VERSION "sin DBC editor"

NS_ :
    STR_64
    BA_SETDATA_REF_
    BA_SETDATA_SGTYPE_

BS_:

BU_: VIU_FL AMP EDC VIU_FR TBOX IP EVCC ICDC

BO_ 722 VIU_FL_2D2: 64 VIU_FL
    SG_ AcRemStartSts : 71|1@0+ (1,0) [0|1] "" VIU_FR
    SG_ CDC_CRCCheck_2D2 : 503|16@0+ (1,0) [0|65535] "" Vector__XXX
    SG_ CDC_RollingCounter_2D2 : 491|4@0+ (1,0) [0|15] "" Vector__XXX
    SG_ CdcAcChrgILimSet : 205|6@0+ (1,0) [0|63] "A" Vector__XXX
    SG_ CdcAntiRustFctSet : 63|2@0+ (1,0) [0|3] "" Vector__XXX
    SG_ CdcAqsOpenSet : 215|2@0+ (1,0) [0|3] "" VIU_FR
    SG_ CdcAutoApplyFctSet : 321|2@0+ (1,0) [0|3] "" Vector__XXX
    SG_ CdcAutoDefrstDefogStsReq : 425|2@0+ (1,0) [0|3] "" VIU_FR
    SG_ CdcAutoWindLongPressSet : 385|2@0+ (1,0) [0|3] "" VIU_FR
    SG_ CdcAutoWindUnlockSet : 213|2@0+ (1,0) [0|3] "" VIU_FR
    SG_ CdcAVHFctSet : 325|2@0+ (1,0) [0|3] "" Vector__XXX
    SG_ CdcBacktWindLvlSetReq : 339|2@0+ (1,0) [0|3] "" VIU_FR
    SG_ CdcBattPlsHeatgSet : 375|2@0+ (1,0) [0|3] "" Vector__XXX
    SG_ CdcBDWFctSet : 359|2@0+ (1,0) [0|3] "" Vector__XXX
    SG_ CdcBrkPedlModSet : 431|2@0+ (1,0) [0|3] "" Vector__XXX
    SG_ CdcCycModSet : 246|3@0+ (1,0) [0|7] "" VIU_FR
    SG_ CdcDrvrTSet : 263|6@0+ (0.5,17) [17|48.5] "" VIU_FR
    SG_ CdcEpbSwtSet : 429|2@0+ (1,0) [0|3] "" Vector__XXX
    SG_ CdcEspFctSet : 273|2@0+ (1,0) [0|3] "" Vector__XXX
    SG_ CdcFrntAutModOpenSet : 303|2@0+ (1,0) [0|3] "" VIU_FR
    SG_ CdcFrntBlowModSet : 301|4@0+ (1,0) [0|15] "" VIU_FR
    SG_ CdcFrntDefrosterSet : 297|2@0+ (1,0) [0|3] "" VIU_FR
    SG_ CdcFrntWindLvlSet : 311|4@0+ (1,0) [0|15] "" VIU_FR
    SG_ CdcFrontAcOffSet : 327|2@0+ (1,0) [0|3] "" VIU_FR
    SG_ CdcHDCFctSet : 355|2@0+ (1,0) [0|3] "" Vector__XXX
    SG_ CdcHotColdModStReq : 352|3@0+ (1,0) [0|7] "" VIU_FR
    SG_ CdcIBCUDrvModSet : 357|2@0+ (1,0) [0|3] "" Vector__XXX
    SG_ CdcORCAFctSet : 9|2@0+ (1,0) [0|3] "" Vector__XXX
    SG_ CdcPassTSet : 391|6@0+ (0.5,17) [17|48.5] "" VIU_FR
    SG_ CdcPlasmaOpenSet : 373|2@0+ (1,0) [0|3] "" VIU_FR
    SG_ CdcSteerModSet : 3|2@0+ (1,0) [0|3] "" VIU_FR
    SG_ CdcTotMilg : 399|24@0+ (0.1,0) [0|1.67772e+06] "Km" EDC,AMP,IP
    SG_ CdcVehEgyCnseSelect : 132|2@0+ (1,0) [0|3] "" Vector__XXX
    SG_ CdcVentnOnSet : 419|2@0+ (1,0) [0|3] "" VIU_FR
    SG_ CdcWorkSpaceSet : 417|2@0+ (1,0) [0|3] "" VIU_FR
    SG_ CST_OFF_Switch : 364|3@0+ (1,0) [0|3] "" Vector__XXX
    SG_ HU_ACRearFanAdjustValueReq : 83|4@0+ (1,0) [0|15] "" VIU_FR
    SG_ HU_ACRearModeAdjustReq : 76|3@0+ (1,0) [0|7] "" VIU_FR
    SG_ HU_ACRearTempAdjustValueReq2 : 21|6@0+ (0.5,17) [17|48.5] "degree" VIU_FR
    SG_ HU_AutowindSet3 : 68|2@0+ (1,0) [0|3] "" VIU_FR
    SG_ HU_MaxACReq : 7|2@0+ (1,0) [0|3] "" VIU_FR
    SG_ HU_MaxDefReq : 15|2@0+ (1,0) [0|3] "" VIU_FR
    SG_ HU_MaxHeatReq : 5|2@0+ (1,0) [0|3] "" VIU_FR
    SG_ HU_RearACOfffReq : 23|2@0+ (1,0) [0|3] "" VIU_FR
    SG_ HU_RearAUTOACOnReq : 73|2@0+ (1,0) [0|3] "" VIU_FR
    SG_ HU_RefreshModeEnable : 29|2@0+ (1,0) [0|3] "" VIU_FR
    SG_ HU_Request_AFUchannel : 65|2@0+ (1,0) [0|3] "" VIU_FR
    SG_ HU_Request_AFUContentleve : 13|4@0+ (1,0) [0|15] "" VIU_FR
    SG_ HU_Request_AFUSt : 61|2@0+ (1,0) [0|3] "" VIU_FR
    SG_ HU_RollerbenchSetStaus : 1|2@0+ (1,0) [0|3] "" Vector__XXX
    SG_ HU_VentilationSetAfternoon : 51|4@0+ (1,0) [0|15] "" VIU_FR
    SG_ HU_VentilationSetEvening : 55|4@0+ (1,0) [0|15] "" VIU_FR
    SG_ HU_VentilationSetMorning : 59|4@0+ (1,0) [0|15] "" VIU_FR
    SG_ HUAcEgySaveModReq : 87|2@0+ (1,0) [0|3] "" VIU_FR
    SG_ HUAutoAirCleanReq : 85|2@0+ (1,0) [0|3] "" VIU_FR
    SG_ HUBatPulseHeatSwitchReq : 89|2@0+ (1,0) [0|3] "" VIU_FR
    SG_ HUMotLockHeatSwitchReq : 91|2@0+ (1,0) [0|3] "" VIU_FR
    SG_ HUSngPrsnModReq : 78|2@0+ (1,0) [0|3] "" VIU_FR
    SG_ VIUDrvModSet : 27|4@0+ (1,0) [0|15] "" IP

BO_ 753 VIU_FL_2F1: 32 VIU_FL
    SG_ RCM_RLTuLiSt : 0|1@0+ (1,0) [0|1] "" VIU_FR
    SG_ RCM_RRTuLiSt : 2|1@0+ (1,0) [0|1] "" VIU_FR

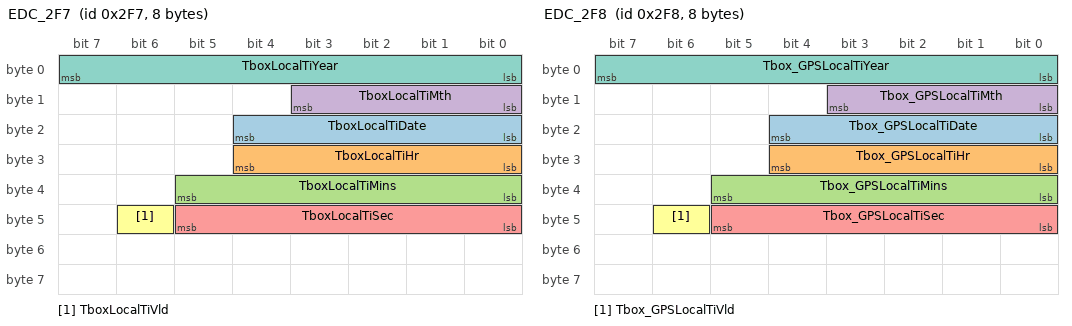
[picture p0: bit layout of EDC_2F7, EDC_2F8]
BO_ 759 EDC_2F7: 8 EDC
    SG_ TboxLocalTiDate : 20|5@0+ (1,0) [0|31] "day" TBOX,VIU_FL,AMP
    SG_ TboxLocalTiHr : 28|5@0+ (1,0) [0|31] "hour" TBOX,VIU_FL,AMP
    SG_ TboxLocalTiMins : 37|6@0+ (1,0) [0|63] "minute" TBOX,VIU_FL,AMP
    SG_ TboxLocalTiMth : 11|4@0+ (1,0) [0|15] "month" TBOX,VIU_FL,AMP
    SG_ TboxLocalTiSec : 45|6@0+ (1,0) [0|63] "second" TBOX,VIU_FL,AMP
    SG_ TboxLocalTiVld : 46|1@0+ (1,0) [0|1] "" TBOX,VIU_FL,AMP
    SG_ TboxLocalTiYear : 7|8@0+ (1,2000) [2000|2255] "year" TBOX,VIU_FL,AMP

BO_ 760 EDC_2F8: 8 EDC
    SG_ Tbox_GPSLocalTiDate : 20|5@0+ (1,0) [0|31] "day" TBOX,VIU_FL
    SG_ Tbox_GPSLocalTiHr : 28|5@0+ (1,0) [0|31] "hour" TBOX,VIU_FL
    SG_ Tbox_GPSLocalTiMins : 37|6@0+ (1,0) [0|63] "minute" TBOX,VIU_FL
    SG_ Tbox_GPSLocalTiMth : 11|4@0+ (1,0) [0|15] "month" TBOX,VIU_FL
    SG_ Tbox_GPSLocalTiSec : 45|6@0+ (1,0) [0|63] "second" TBOX,VIU_FL
    SG_ Tbox_GPSLocalTiVld : 46|1@0+ (1,0) [0|1] "" TBOX,VIU_FL
    SG_ Tbox_GPSLocalTiYear : 7|8@0+ (1,2000) [2000|2255] "year" TBOX,VIU_FL

BO_ 774 VIU_FL_306: 64 VIU_FL
    SG_ AC_ACOnOff : 4|2@0+ (1,0) [0|3] "" EDC
    SG_ ITMSLiquidLevel : 181|2@0+ (1,0) [0|3] "" IP
    SG_ TmsComOutPtPre : 0|9@0+ (0.01,0) [0|5.11] "Mpa" AMP,EDC

BO_ 779 EDC_30B: 64 EDC
    SG_ CDC_CRCCheck_30B : 503|16@0+ (1,0) [0|65535] "" VIU_FL
    SG_ CDC_RollingCounter_30B : 491|4@0+ (1,0) [0|15] "" VIU_FL
    SG_ CdcIPScreenLiOnSts : 276|1@0+ (1,0) [0|1] "" VIU_FL
    SG_ IP_DISFail : 130|1@0+ (1,0) [0|1] "" VIU_FL
    SG_ IP_juADASshowinfa : 134|1@0+ (1,0) [0|1] "" VIU_FL
    SG_ IP_juADASshowoutfa : 135|1@0+ (1,0) [0|1] "" VIU_FL
    SG_ IP_juADAStsE2Efaout : 133|1@0+ (1,0) [0|1] "" VIU_FL
    SG_ IP_QDashACCFail : 129|2@0+ (1,0) [0|3] "" VIU_FL
    SG_ AD_EDCCrtSts : 11|4@0+ (1,0) [0|15] "" VIU_FR
    SG_ AD_EDCCurrenttemp : 7|8@0+ (1,-40) [-40|215] "" VIU_FR
    SG_ TboxDoorLockRemCtrlReq : 14|3@0+ (1,0) [0|7] "" VIU_FL,VIU_FR

BO_ 784 AMP_310: 64 AMP
    SG_ AMP_Err_Detect : 455|16@0+ (1,0) [0|65535] "" Vector__XXX
    SG_ AMP_FLHighSpeakerDelaySETStatus : 207|4@0+ (1,0) [0|15] "" EDC
    SG_ AMP_FLHighSpeakerVolSETStatus : 218|5@0+ (1,0) [0|31] "" EDC
    SG_ AMP_FLMidSpeakerDelaySETStatus : 203|4@0+ (1,0) [0|15] "" EDC
    SG_ AMP_FLMidSpeakerVolSETStatus : 229|5@0+ (1,0) [0|31] "" EDC
    SG_ AMP_FRHighSpeakerDelaySETStatus : 224|5@0+ (1,0) [0|31] "" EDC
    SG_ AMP_FRHighSpeakerVolSETStatus : 212|5@0+ (1,0) [0|31] "" EDC
    SG_ AMP_FRMidSpeakerDelaySETStatus : 235|5@0+ (1,0) [0|31] "" EDC
    SG_ AMP_FRMidSpeakerVolSETStatus : 223|5@0+ (1,0) [0|31] "" EDC
    SG_ AMP_Slot_Detect : 471|16@0+ (1,0) [0|65535] "" Vector__XXX
    SG_ AMP_SV_Detect : 111|16@0+ (1,0) [0|65535] "" Vector__XXX
    SG_ AMP_AlarmVolSETStatus : 95|2@0+ (1,0) [0|3] "" EDC
    SG_ AMP_AvasVolSETStatus : 433|2@0+ (1,0) [0|3] "" EDC
    SG_ AMP_CenterSpeakerDelaySETStatus : 265|5@0+ (1,0) [0|31] "" EDC
    SG_ AMP_CenterSpeakerVolSETStatus : 340|5@0+ (1,0) [0|31] "" EDC
    SG_ AMP_CustomEffectSETStatus : 127|4@0+ (1,0) [0|15] "" EDC
    SG_ AMP_CustomEQ125SET : 43|4@0+ (1,-8) [-8|7] "" EDC
    SG_ AMP_CustomEQ16KSET : 71|4@0+ (1,-8) [-8|7] "" EDC
    SG_ AMP_CustomEQ1KSET : 55|4@0+ (1,-8) [-8|7] "" EDC
    SG_ AMP_CustomEQ250SET : 47|4@0+ (1,-8) [-8|7] "" EDC
    SG_ AMP_CustomEQ2KSET : 59|4@0+ (1,-8) [-8|7] "" EDC
    SG_ AMP_CustomEQ4KSET : 63|4@0+ (1,-8) [-8|7] "" EDC
    SG_ AMP_CustomEQ500SET : 51|4@0+ (1,-8) [-8|7] "" EDC
    SG_ AMP_CustomEQ62SET : 39|4@0+ (1,-8) [-8|7] "" EDC
    SG_ AMP_CustomEQ8KSET : 67|4@0+ (1,-8) [-8|7] "" EDC
    SG_ AMP_FLLowSpeakerDelaySETStatus : 293|5@0+ (1,0) [0|31] "" EDC
    SG_ AMP_FLLowSpeakerVolSETStatus : 352|5@0+ (1,0) [0|31] "" EDC
    SG_ AMP_FLMidHighSpeakerDelaySETStat : 407|4@0+ (1,0) [0|15] "" EDC
    SG_ AMP_FLMidHighSpeakerVolSETStatus : 380|5@0+ (1,0) [0|31] "" EDC
    SG_ AMP_FLTopSpeakerDelaySETStatus : 259|5@0+ (1,0) [0|31] "" EDC
    SG_ AMP_FLTopSpeakerVolSETStatus : 334|5@0+ (1,0) [0|31] "" EDC
    SG_ AMP_FRBalanceSETStatus : 75|4@0+ (1,-8) [-8|7] "" EDC
    SG_ AMP_FRLowSpeakerDelaySETStatus : 282|5@0+ (1,0) [0|31] "" EDC
    SG_ AMP_FRLowSpeakerVolSETStatus : 357|5@0+ (1,0) [0|31] "" EDC
    SG_ AMP_FRMidHighSpeakerDelaySET : 299|5@0+ (1,0) [0|31] "" EDC
    SG_ AMP_FRMidHighSpeakerVolSETStatus : 374|5@0+ (1,0) [0|31] "" EDC
    SG_ AMP_FRTopSpeakerDelaySETStatus : 252|5@0+ (1,0) [0|31] "" EDC
    SG_ AMP_FRTopSpeakerVolSETStatus : 323|5@0+ (1,0) [0|31] "" EDC
    SG_ AMP_KTVMUTESETStatus : 429|2@0+ (1,0) [0|3] "" EDC
    SG_ AMP_KTVVolSETStatus : 396|5@0+ (1,0) [0|31] "" EDC
    SG_ AMP_LRBalanceSETStatus : 83|4@0+ (1,-8) [-8|7] "" EDC
    SG_ AMP_MediaMUTESETStatus : 437|2@0+ (1,0) [0|3] "" EDC
    SG_ AMP_MediaVolSETStatus : 6|5@0+ (1,0) [0|31] "" EDC
    SG_ AMP_MUTESETStatus : 435|2@0+ (1,0) [0|3] "" EDC
    SG_ AMP_NaviMUTESETStatus : 439|2@0+ (1,0) [0|3] "" EDC
    SG_ AMP_NAVIVolSETStatus : 28|5@0+ (1,0) [0|31] "" EDC
    SG_ AMP_OutMUTESETStatus : 417|2@0+ (1,0) [0|3] "" EDC
    SG_ AMP_OUTVolSETStatus : 388|5@0+ (1,0) [0|31] "" EDC
    SG_ AMP_PerfessiionalEQ100SET : 411|4@0+ (1,0) [0|15] "" EDC
    SG_ AMP_PerfessiionalEQ500SET : 415|4@0+ (1,0) [0|15] "" EDC
    SG_ AMP_PerfessiionalEQ6KSET : 403|4@0+ (1,0) [0|15] "" EDC
    SG_ AMP_RLLowHighSpeakerDelaySETStat : 310|5@0+ (1,0) [0|31] "" EDC
    SG_ AMP_RLLowHighSpeakerVolSETStatus : 369|5@0+ (1,0) [0|31] "" EDC
    SG_ AMP_RLSurroundSpeakerDelaySETSta : 287|5@0+ (1,0) [0|31] "" EDC
    SG_ AMP_RLSurroundSpeakerVolSETStatu : 346|5@0+ (1,0) [0|31] "" EDC
    SG_ AMP_RLTopSpeakerDelaySETStatus : 241|5@0+ (1,0) [0|31] "" EDC
    SG_ AMP_RLTopSpeakerVolSETStatus : 316|5@0+ (1,0) [0|31] "" EDC
    SG_ AMP_RNCEnableSETStatus : 123|2@0+ (1,0) [0|3] "" EDC
    SG_ AMP_RRLowHighSpeakerDelaySET : 288|5@0+ (1,0) [0|31] "" EDC
    SG_ AMP_RRLowHighSpeakerVolSETStatus : 363|5@0+ (1,0) [0|31] "" EDC
    SG_ AMP_RRSurroundSpeakerDelaySETSta : 276|5@0+ (1,0) [0|31] "" EDC
    SG_ AMP_RRSurroundSpeakerVolSET : 351|5@0+ (1,0) [0|31] "" EDC
    SG_ AMP_RRTopSpeakerDelaySETStatus : 246|5@0+ (1,0) [0|31] "" EDC
    SG_ AMP_RRTopSpeakerVolSETStatus : 305|5@0+ (1,0) [0|31] "" EDC
    SG_ AMP_SoundEffectSETStatus : 35|4@0+ (1,0) [0|15] "" EDC
    SG_ AMP_SoundFieldSETStatus : 1|4@0+ (1,0) [0|15] "" EDC
    SG_ AMP_SubSpeakerDelaySETStatus : 270|5@0+ (1,0) [0|31] "" EDC
    SG_ AMP_SubSpeakerVolSETStatus : 329|5@0+ (1,0) [0|31] "" EDC
    SG_ AMP_SystemMUTESETStatus : 431|2@0+ (1,0) [0|3] "" EDC
    SG_ AMP_SystemVolSETStatus : 422|5@0+ (1,0) [0|31] "" EDC
    SG_ AMP_TelBcallMUTESETStatus : 425|2@0+ (1,0) [0|3] "" EDC
    SG_ AMP_TELBCALLVolSETStatus : 12|5@0+ (1,0) [0|31] "" EDC
    SG_ AMP_TTSVRMUTESETStatus : 427|2@0+ (1,0) [0|3] "" EDC
    SG_ AMP_TTSVRVolSETStatus : 20|5@0+ (1,0) [0|31] "" EDC
    SG_ AMP_TurnLightInOrOutSETStatus : 441|2@0+ (1,0) [0|1] "" EDC
    SG_ AMP_TurnLightVolSETStatus : 444|2@0+ (1,0) [0|3] "" EDC
    SG_ AMP_VOLSpeedEnableSETStatus : 121|2@0+ (1,0) [0|3] "" EDC

BO_ 800 AMP_320: 64 AMP
    SG_ AMPFLPositionDelaySETStatus : 259|4@0+ (1,0) [0|15] "" EDC
    SG_ AMPFLPositionVolSETStatus : 147|5@0+ (1,0) [0|31] "" EDC
    SG_ AMPFRPositionDelaySETStatus : 164|5@0+ (1,0) [0|31] "" EDC
    SG_ AMPFRPositionVolSETStatus : 175|5@0+ (1,0) [0|31] "" EDC
    SG_ AMPBeosonicModeSetStatus : 5|3@0+ (1,0) [0|7] "" EDC
    SG_ AMPBeosonicXSetStatus : 2|5@0+ (1,0) [0|31] "" EDC
    SG_ AMPBeosonicYSetStatus : 13|5@0+ (1,0) [0|31] "" EDC
    SG_ AMPCenterPositionDelaySETStatus : 141|5@0+ (1,0) [0|31] "" EDC
    SG_ AMPCenterPositionVolSETStatus : 136|5@0+ (1,0) [0|31] "" EDC
    SG_ AMPCustomEQ2500SET : 123|4@0+ (1,-8) [-8|7] "" EDC
    SG_ AMPCustomEQ315SET : 59|4@0+ (1,-8) [-8|7] "" EDC
    SG_ AMPCustomEQ50SET : 263|4@0+ (1,-8) [-8|7] "" EDC
    SG_ AMPCustomEQ6000SET : 187|4@0+ (1,-8) [-8|7] "" EDC
    SG_ AMPCustomEQ800SET : 251|4@0+ (1,-8) [-8|7] "" EDC
    SG_ AMPFLTopPositionDelaySETStatus : 158|5@0+ (1,0) [0|31] "" EDC
    SG_ AMPFLTopPositionVolSETStatus : 153|5@0+ (1,0) [0|31] "" EDC
    SG_ AMPFRTopPositionDelaySETStatus : 170|5@0+ (1,0) [0|31] "" EDC
    SG_ AMPFRTopPositionVolSETStatus : 181|5@0+ (1,0) [0|31] "" EDC
    SG_ AMPRLPositionDelaySETStatus : 176|5@0+ (1,0) [0|31] "" EDC
    SG_ AMPRLPositionVolSETStatus : 199|5@0+ (1,0) [0|31] "" EDC
    SG_ AMPRLSurroundDelaySETStatus : 194|5@0+ (1,0) [0|31] "" EDC
    SG_ AMPRLSurroundVolSETStatus : 205|5@0+ (1,0) [0|31] "" EDC
    SG_ AMPRLTopDelaySETStatus : 200|5@0+ (1,0) [0|31] "" EDC
    SG_ AMPRLTopVolSETStatus : 211|5@0+ (1,0) [0|31] "" EDC
    SG_ AMPRRPositionDelaySET : 222|5@0+ (1,0) [0|31] "" EDC
    SG_ AMPRRPositionVolSETStatus : 217|5@0+ (1,0) [0|31] "" EDC
    SG_ AMPRRSurroundPositionDelaySETSta : 228|5@0+ (1,0) [0|31] "" EDC
    SG_ AMPRRSurroundPositionVolSET : 239|5@0+ (1,0) [0|31] "" EDC
    SG_ AMPRRTopPositionDelaySETStatus : 234|5@0+ (1,0) [0|31] "" EDC
    SG_ AMPRRTopPositionVolSETStatus : 245|5@0+ (1,0) [0|31] "" EDC
    SG_ AMPSoundSourceTypeStatus : 7|2@0+ (1,0) [0|3] "" EDC
    SG_ AMPSubPositionDelaySETStatus : 240|5@0+ (1,0) [0|31] "" EDC
    SG_ AMPSubPositionVolSETStatus : 271|5@0+ (1,0) [0|31] "" EDC
    SG_ AMPTMCenterPositionEQ15000HzSetS : 71|5@0+ (1,0) [0|31] "" EDC
    SG_ AMPTMCenterPositionEQ800HzSetSta : 48|5@0+ (1,0) [0|31] "" EDC
    SG_ AMPTMFLPositionEQ100HzSetStatus : 30|5@0+ (1,0) [0|31] "" EDC
    SG_ AMPTMFLPositionEQ15000HzSetStatu : 36|5@0+ (1,0) [0|31] "" EDC
    SG_ AMPTMFLPositionEQ800HzSetStatus : 25|5@0+ (1,0) [0|31] "" EDC
    SG_ AMPTMFLTopPositionEQ500HzSetStat : 117|5@0+ (1,0) [0|31] "" EDC
    SG_ AMPTMFRPositionEQ100HzSetStatus : 47|5@0+ (1,0) [0|31] "" EDC
    SG_ AMPTMFRPositionEQ15000HzSetStatu : 53|5@0+ (1,0) [0|31] "" EDC
    SG_ AMPTMFRPositionEQ800HzSetStatus : 42|5@0+ (1,0) [0|31] "" EDC
    SG_ AMPTMFRTopPositionEQ500HzSetStat : 112|5@0+ (1,0) [0|31] "" EDC
    SG_ AMPTMReverbSetStatus : 8|7@0+ (1,0) [0|127] "" EDC
    SG_ AMPTMRLPositionEQ10000HzSetStatu : 72|5@0+ (1,0) [0|31] "" EDC
    SG_ AMPTMRLPositionEQ100HzSetStatusS : 77|5@0+ (1,0) [0|31] "" EDC
    SG_ AMPTMRLSurroundPositionEQ15000Hz : 100|5@0+ (1,0) [0|31] "" EDC
    SG_ AMPTMRLSurroundPositionEQ800HzSe : 89|5@0+ (1,0) [0|31] "" EDC
    SG_ AMPTMRLTopPositionEQ500HzSetStat : 135|5@0+ (1,0) [0|31] "" EDC
    SG_ AMPTMRRPositionEQ10000HzSetStatu : 94|5@0+ (1,0) [0|31] "" EDC
    SG_ AMPTMRRPositionEQ100HzSetStatus : 83|5@0+ (1,0) [0|31] "" EDC
    SG_ AMPTMRRSurroundPositionEQ15000Hz : 106|5@0+ (1,0) [0|31] "" EDC
    SG_ AMPTMRRSurroundPositionEQ800HzSe : 111|5@0+ (1,0) [0|31] "" EDC
    SG_ AMPTMRRTopPositionEQ500HzSetStat : 130|5@0+ (1,0) [0|31] "" EDC
    SG_ AMPTMSubPositionEQ30HzSetStatusS : 66|5@0+ (1,0) [0|31] "" EDC
    SG_ AMPVOLSpeedLevChangeSETStatus : 17|3@0+ (1,0) [0|7] "" EDC

BO_ 802 VIU_FL_322: 64 VIU_FL
    SG_ ECAStarLvl : 23|8@0+ (1,-128) [-128|127] "MM" VIU_FR
    SG_ ECASActLvlFL : 71|16@0- (0.01,0) [-327.67|327.67] "MM" VIU_FR
    SG_ ECASActLvlFR : 87|16@0- (0.01,0) [-327.67|327.67] "MM" VIU_FR
    SG_ ECASActLvlRL : 47|16@0- (0.01,0) [-327.67|327.67] "MM" VIU_FR
    SG_ ECASActLvlRR : 31|16@0- (0.01,0) [-327.67|327.67] "MM" VIU_FR
    SG_ ECASAdjBySpd : 8|1@0+ (1,0) [0|1] "" VIU_FR
    SG_ ECASaftaxladjsts : 100|2@0+ (1,0) [0|2] "" EDC
    SG_ ECASerromode : 103|3@0+ (1,0) [0|5] "" EDC
    SG_ ECASfrtaxladjsts : 98|2@0+ (1,0) [0|2] "" EDC
    SG_ EcasModeCHASts : 2|3@0+ (1,0) [0|7] "" VIU_FR,ICDC
    SG_ EcasModeFB : 7|5@0+ (1,0) [0|31] "" VIU_FR,ICDC
    SG_ ECASmodevld : 96|1@0+ (1,0) [0|1] "" EDC
    SG_ SusfaultlLamp : 113|2@0+ (1,0) [0|2] "" EDC,ICDC
    SG_ Susfaultred : 111|8@0+ (1,0) [0|255] "" EDC

BO_ 821 VIU_FL_335: 64 VIU_FL
    SG_ BCM_DriverWindowStatus : 199|8@0+ (0.5,0) [0|100] "%" AMP,EDC
    SG_ BCM_PartWinPosVIT : 119|8@0+ (1,0) [0|101] "" AMP,EDC
    SG_ BCM_PartWinSts : 127|8@0+ (1,0) [0|15] "" AMP,EDC
    SG_ BCM_PassengerWindowPosi : 223|8@0+ (0.5,0) [0|100] "%" AMP,EDC
    SG_ BCM_PassengerWindowStatus : 215|8@0+ (0.5,0) [0|100] "%" AMP,EDC
    SG_ VcuIpuErrLamp : 83|1@0+ (1,0) [0|1] "" Vector__XXX
    SG_ VcuEgyMagtModResp : 455|8@0+ (1,0) [0|255] "NA" IP
    SG_ VcuForceEVModResp : 348|1@0+ (1,0) [0|1] "NA" IP
    SG_ VcuForcePwrPresModResp : 349|1@0+ (1,0) [0|1] "NA" IP
    SG_ BCM_RightRearWindowPosi : 255|8@0+ (0.5,0) [0|100] "%" AMP,EDC
    SG_ BCM_RightRearWindowStatus : 247|8@0+ (0.5,0) [0|100] "%" AMP,EDC
    SG_ VCU_CRCCheck_335 : 503|16@0+ (1,0) [0|65535] "" Vector__XXX
    SG_ VCU_RollingCounter_335 : 491|4@0+ (1,0) [0|15] "" Vector__XXX
    SG_ VcuAcChrgNegativePoleTemp : 191|8@0+ (1,-40) [-40|215] "℃" Vector__XXX
    SG_ VcuAccrPedlPosnGb : 383|8@0+ (1,0) [0|100] "%" Vector__XXX
    SG_ VcuBattIGb : 399|16@0+ (0.1,-1000) [-1000|5553.5] "A" Vector__XXX
    SG_ VcuGearPosnStsGb : 391|8@0+ (1,0) [0|255] "" Vector__XXX
    SG_ VcuHvilStsGb : 345|1@0+ (1,0) [0|1] "" Vector__XXX
    SG_ VcuVehChrgStsGb : 367|8@0+ (1,0) [0|4] "" Vector__XXX
    SG_ VcuVehRunngModGb : 375|8@0+ (1,0) [0|3] "" Vector__XXX
    SG_ VcuVehStsGb : 359|8@0+ (1,0) [0|3] "" Vector__XXX
    SG_ VcuBrkPedlSts : 319|2@0+ (1,0) [0|3] "" Vector__XXX
    SG_ VcuPwrCnse : 288|9@0+ (1,-150) [-150|361] "kW" Vector__XXX
    SG_ VcuSocDisp : 310|7@0+ (1,0) [0|127] "%" Vector__XXX
    SG_ BCM_DriverWindowPosi : 207|8@0+ (0.5,0) [0|100] "%" AMP,EDC
    SG_ BCM_LeftRearWindowPosi : 239|8@0+ (0.5,0) [0|100] "%" AMP,EDC
    SG_ BCM_LeftRearWindowStatus : 231|8@0+ (0.5,0) [0|100] "%" AMP,EDC
    SG_ BcmSunroofPosi : 270|7@0+ (1,0) [0|127] "" AMP,EDC
    SG_ BcmSunroofStatus : 262|7@0+ (1,0) [0|127] "" AMP,EDC
    SG_ MFS_Right_switch_Right1_signal : 93|2@0+ (1,0) [0|3] "" EDC
    SG_ VcuAcChrgPositivePoleTemp : 183|8@0+ (1,-40) [-40|215] "℃" Vector__XXX
    SG_ VcuBattChrgErrLamp : 8|1@0+ (1,0) [0|1] "" Vector__XXX
    SG_ VcuBattlowU : 71|8@0+ (0.1,0) [0|25.5] "V" Vector__XXX
    SG_ VcuBattUUnderWarn : 81|2@0+ (1,0) [0|3] "" Vector__XXX
    SG_ VcuChrgAutoUnlckSetStsFb : 97|2@0+ (1,0) [0|3] "" Vector__XXX
    SG_ VcuChrgLckInfo : 101|3@0+ (1,0) [0|7] "" Vector__XXX
    SG_ VcuDcChrgNegativePoleTemp : 175|8@0+ (1,-40) [-40|215] "℃" Vector__XXX
    SG_ VcuDcChrgPositivePoleTemp : 167|8@0+ (1,-40) [-40|215] "℃" Vector__XXX
    SG_ VCUGearShiftPositon : 315|4@0+ (1,0) [0|15] "" IP,EDC
    SG_ VcuHvBattCutOffLamp : 82|1@0+ (1,0) [0|1] "" Vector__XXX
    SG_ VcuHVErrInfo : 90|1@0+ (1,0) [0|1] "" Vector__XXX
    SG_ VcuHvilSts : 344|1@0+ (1,0) [0|1] "" Vector__XXX
    SG_ VcuResiMilg : 23|11@0+ (1,0) [0|2047] "km" Vector__XXX
    SG_ VcuShiftPErrInfo : 89|1@0+ (1,0) [0|1] "" Vector__XXX
    SG_ VCUShiftPostionValid : 311|1@0+ (1,0) [0|1] "" EDC
    SG_ VcuVehErrInfo : 88|1@0+ (1,0) [0|1] "" Vector__XXX
    SG_ VIUFL_DeviceVerifyResult : 487|2@0+ (1,0) [0|3] "" EDC
    SG_ VcuOffRoadCrpSts : 2|3@0+ (1,0) [0|7] "" IP
    SG_ BCMALLDoorLockSwt : 28|3@0+ (1,0) [0|7] "" EDC

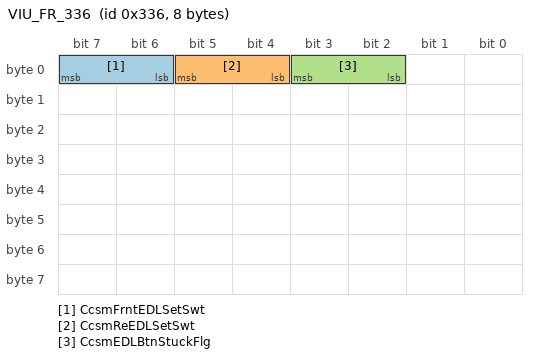
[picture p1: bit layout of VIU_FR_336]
BO_ 822 VIU_FR_336: 8 VIU_FR
    SG_ CcsmFrntEDLSetSwt : 7|2@0+ (1,0) [0|3] "" VIU_FL
    SG_ CcsmReEDLSetSwt : 5|2@0+ (1,0) [0|3] "" VIU_FL
    SG_ CcsmEDLBtnStuckFlg : 3|2@0+ (1,0) [0|3] "" VIU_FL

BO_ 854 EDC_356: 64 EDC
    SG_ HU_FLHighSpeakerDelaySET : 419|4@0+ (1,0) [0|15] "" AMP
    SG_ HU_FLHighSpeakerVolSET : 386|5@0+ (1,0) [0|31] "" AMP
    SG_ HU_FLMidSpeakerDelaySET : 423|4@0+ (1,0) [0|15] "" AMP
    SG_ HU_FLMidSpeakerVolSET : 391|5@0+ (1,0) [0|31] "" AMP
    SG_ HU_FRHighSpeakerDelaySET : 414|5@0+ (1,0) [0|31] "" AMP
    SG_ HU_FRHighSpeakerVolSET : 392|5@0+ (1,0) [0|31] "" AMP
    SG_ HU_FRMidSpeakerDelaySET : 403|5@0+ (1,0) [0|31] "" AMP
    SG_ HU_FRMidSpeakerVolSET : 397|5@0+ (1,0) [0|31] "" AMP
    SG_ HUFLPositionDelaySET : 507|4@0+ (1,0) [0|15] "" AMP
    SG_ HUFLPositionVolSET : 473|5@0+ (1,0) [0|31] "" AMP
    SG_ HUFRPositionDelaySET : 490|5@0+ (1,0) [0|31] "" AMP
    SG_ HUFRPositionVolSET : 501|5@0+ (1,0) [0|31] "" AMP
    SG_ HU_AlarmVolSET : 102|2@0+ (1,0) [0|3] "" AMP
    SG_ HU_AvasVolSET : 329|2@0+ (1,0) [0|3] "" AMP
    SG_ HU_CenterSpeakerDelaySET : 259|5@0+ (1,0) [0|31] "" AMP
    SG_ HU_CenterSpeakerVolSET : 206|5@0+ (1,0) [0|31] "" AMP
    SG_ HU_CustomEffectSET : 79|4@0+ (1,0) [0|15] "" AMP
    SG_ HU_CustomEQ125SET : 43|4@0+ (1,-8) [-8|7] "" AMP
    SG_ HU_CustomEQ16KSET : 71|4@0+ (1,-8) [-8|7] "" AMP
    SG_ HU_CustomEQ1KSET : 55|4@0+ (1,-8) [-8|7] "" AMP
    SG_ HU_CustomEQ250SET : 47|4@0+ (1,-8) [-8|7] "" AMP
    SG_ HU_CustomEQ2KSET : 59|4@0+ (1,-8) [-8|7] "" AMP
    SG_ HU_CustomEQ4KSET : 63|4@0+ (1,-8) [-8|7] "" AMP
    SG_ HU_CustomEQ500SET : 51|4@0+ (1,-8) [-8|7] "" AMP
    SG_ HU_CustomEQ62SET : 37|4@0+ (1,-8) [-8|7] "" AMP
    SG_ HU_CustomEQ8KSET : 67|4@0+ (1,-8) [-8|7] "" AMP
    SG_ HU_FLLowSpeakerDelaySET : 287|5@0+ (1,0) [0|31] "" AMP
    SG_ HU_FLLowSpeakerVolSET : 218|5@0+ (1,0) [0|31] "" AMP
    SG_ HU_FLMidHighSpeakerDelaySET : 339|4@0+ (1,0) [0|15] "" AMP
    SG_ HU_FLMidHighSpeakerVolSET : 246|5@0+ (1,0) [0|31] "" AMP
    SG_ HU_FLTopSpeakerDelaySET : 369|5@0+ (1,0) [0|31] "" AMP
    SG_ HU_FLTopSpeakerVolSET : 316|5@0+ (1,0) [0|31] "" AMP
    SG_ HU_FRBalanceSET : 75|4@0+ (1,-8) [-8|7] "" AMP
    SG_ HU_FRLowSpeakerDelaySET : 276|5@0+ (1,0) [0|31] "" AMP
    SG_ HU_FRLowSpeakerVolSET : 223|5@0+ (1,0) [0|31] "" AMP
    SG_ HU_FRMidHighSpeakerDelaySET : 293|5@0+ (1,0) [0|31] "" AMP
    SG_ HU_FRMidHighSpeakerVolSET : 224|5@0+ (1,0) [0|31] "" AMP
    SG_ HU_FRTopSpeakerDelaySET : 374|5@0+ (1,0) [0|31] "" AMP
    SG_ HU_FRTopSpeakerVolSET : 305|5@0+ (1,0) [0|31] "" AMP
    SG_ HU_KTVMUTESET : 323|2@0+ (1,0) [0|3] "" AMP
    SG_ HU_KTVVolSET : 252|5@0+ (1,0) [0|31] "" AMP
    SG_ HU_LRBalanceSET : 83|4@0+ (1,-8) [-8|7] "" AMP
    SG_ HU_MediaMUTESET : 331|2@0+ (1,0) [0|3] "" AMP
    SG_ HU_MediaVolSET : 6|5@0+ (1,0) [0|31] "" AMP
    SG_ HU_MUTESET : 95|2@0+ (1,0) [0|3] "" AMP
    SG_ HU_NaviMUTESET : 333|2@0+ (1,0) [0|3] "" AMP
    SG_ HU_NAVIVolSET : 148|5@0+ (1,0) [0|31] "" AMP
    SG_ HU_OutMUTESET : 327|2@0+ (1,0) [0|3] "" AMP
    SG_ HU_OUTVolSET : 241|5@0+ (1,0) [0|31] "" AMP
    SG_ HU_PerfessiionalEQ100SET : 356|4@0+ (1,0) [0|15] "" AMP
    SG_ HU_PerfessiionalEQ500SET : 347|4@0+ (1,0) [0|15] "" AMP
    SG_ HU_PerfessiionalEQ6KSET : 351|4@0+ (1,0) [0|15] "" AMP
    SG_ HU_RLLowHighSpeakerDelaySET : 288|5@0+ (1,0) [0|31] "" AMP
    SG_ HU_RLLowHighSpeakerVolSET : 235|5@0+ (1,0) [0|31] "" AMP
    SG_ HU_RLSurroundSpeakerDelaySET : 265|5@0+ (1,0) [0|31] "" AMP
    SG_ HU_RLSurroundSpeakerVolSET : 212|5@0+ (1,0) [0|31] "" AMP
    SG_ HU_RLTopSpeakerDelaySET : 363|5@0+ (1,0) [0|31] "" AMP
    SG_ HU_RLTopSpeakerVolSET : 310|5@0+ (1,0) [0|31] "" AMP
    SG_ HU_RNCEnableSET : 124|2@0+ (1,0) [0|3] "" AMP
    SG_ HU_RRLowHighSpeakerDelaySET : 282|5@0+ (1,0) [0|31] "" AMP
    SG_ HU_RRLowHighSpeakerVolSET : 229|5@0+ (1,0) [0|31] "" AMP
    SG_ HU_RRSurroundSpeakerDelaySET : 270|5@0+ (1,0) [0|31] "" AMP
    SG_ HU_RRSurroundSpeakerVolSET : 201|5@0+ (1,0) [0|31] "" AMP
    SG_ HU_RRTopSpeakerDelaySET : 352|5@0+ (1,0) [0|31] "" AMP
    SG_ HU_RRTopSpeakerVolSET : 299|5@0+ (1,0) [0|31] "" AMP
    SG_ HU_SoundEffectSET : 19|4@0+ (1,0) [0|15] "" AMP
    SG_ HU_SoundFieldSET : 1|4@0+ (1,0) [0|15] "" AMP
    SG_ HU_SubSpeakerDelaySET : 380|5@0+ (1,0) [0|31] "" AMP
    SG_ HU_SubSpeakerVolSET : 195|5@0+ (1,0) [0|31] "" AMP
    SG_ HU_SystemMUTESET : 325|2@0+ (1,0) [0|3] "" AMP
    SG_ HU_SystemVolSET : 184|5@0+ (1,0) [0|31] "" AMP
    SG_ HU_TelBcallMUTESET : 335|2@0+ (1,0) [0|3] "" AMP
    SG_ HU_TELBCALLVolSET : 13|5@0+ (1,0) [0|31] "" AMP
    SG_ HU_TTSVRMUTESET : 321|2@0+ (1,0) [0|3] "" AMP
    SG_ HU_TTSVRVolSET : 8|5@0+ (1,0) [0|31] "" AMP
    SG_ HU_TurnLightInOrOutSET : 358|2@0+ (1,0) [0|1] "" AMP
    SG_ HU_TurnLightVolSET : 341|2@0+ (1,0) [0|3] "" AMP
    SG_ HU_VOLSpeedLevEnableSET : 118|2@0+ (1,0) [0|3] "" AMP
    SG_ HUBeosonicModeSet : 105|3@0+ (1,0) [0|7] "" AMP
    SG_ HUBeosonicXSet : 31|5@0+ (1,0) [0|31] "" AMP
    SG_ HUBeosonicYSet : 26|5@0+ (1,0) [0|31] "" AMP
    SG_ HUCenterPositionDelaySET : 467|5@0+ (1,0) [0|31] "" AMP
    SG_ HUCenterPositionVolSET : 478|5@0+ (1,0) [0|31] "" AMP
    SG_ HUCustomEQ2500SET : 136|4@0+ (1,-8) [-8|7] "" AMP
    SG_ HUCustomEQ315SET : 87|4@0+ (1,-8) [-8|7] "" AMP
    SG_ HUCustomEQ50SET : 443|4@0+ (1,-8) [-8|7] "" AMP
    SG_ HUCustomEQ6000SET : 188|4@0+ (1,-8) [-8|7] "" AMP
    SG_ HUCustomEQ800SET : 263|4@0+ (1,-8) [-8|7] "" AMP
    SG_ HUFLTopPositionDelaySET : 484|5@0+ (1,0) [0|31] "" AMP
    SG_ HUFLTopPositionVolSET : 495|5@0+ (1,0) [0|31] "" AMP
    SG_ HUFRTopPositionDelaySET : 496|5@0+ (1,0) [0|31] "" AMP
    SG_ HUSoundSourceType : 33|2@0+ (1,0) [0|3] "" AMP
    SG_ HUTMCenterPositionEQ15000HzSet : 154|5@0+ (1,0) [0|31] "" AMP
    SG_ HUTMCenterPositionEQ800HzSet : 159|5@0+ (1,0) [0|31] "" AMP
    SG_ HUTMFLPositionEQ100HzSet : 99|5@0+ (1,0) [0|31] "" AMP
    SG_ HUTMFLPositionEQ15000HzSet : 116|5@0+ (1,0) [0|31] "" AMP
    SG_ HUTMFLPositionEQ800HzSet : 110|5@0+ (1,0) [0|31] "" AMP
    SG_ HUTMFLTopPositionEQ500HzSet : 455|5@0+ (1,0) [0|31] "" AMP
    SG_ HUTMFRPositionEQ100HzSet : 135|5@0+ (1,0) [0|31] "" AMP
    SG_ HUTMFRPositionEQ15000HzSet : 141|5@0+ (1,0) [0|31] "" AMP
    SG_ HUTMFRPositionEQ800HzSet : 130|5@0+ (1,0) [0|31] "" AMP
    SG_ HUTMFRTopPositionEQ500HzSet : 450|5@0+ (1,0) [0|31] "" AMP
    SG_ HUTMReverbSet : 93|7@0+ (1,0) [0|127] "" AMP
    SG_ HUTMRLPositionEQ10000HzSet : 171|5@0+ (1,0) [0|31] "" AMP
    SG_ HUTMRLPositionEQ100HzSet : 160|5@0+ (1,0) [0|31] "" AMP
    SG_ HUTMRLSurroundPositionEQ15000HzS : 426|5@0+ (1,0) [0|31] "" AMP
    SG_ HUTMRLSurroundPositionEQ800HzSet : 431|5@0+ (1,0) [0|31] "" AMP
    SG_ HUTMRLTopPositionEQ500HzSet : 461|5@0+ (1,0) [0|31] "" AMP
    SG_ HUTMRRPositionEQ10000HzSet : 177|5@0+ (1,0) [0|31] "" AMP
    SG_ HUTMRRPositionEQ100HzSet : 182|5@0+ (1,0) [0|31] "" AMP
    SG_ HUTMRRSurroundPositionEQ15000HzS : 432|5@0+ (1,0) [0|31] "" AMP
    SG_ HUTMRRSurroundPositionEQ800HzSet : 437|5@0+ (1,0) [0|31] "" AMP
    SG_ HUTMRRTopPositionEQ500HzSet : 456|5@0+ (1,0) [0|31] "" AMP
    SG_ HUTMSubPositionEQ30HzSet : 165|5@0+ (1,0) [0|31] "" AMP
    SG_ HUTMTransEnd : 7|1@0+ (1,0) [0|1] "" AMP
    SG_ HUVOLSpeedLevChangeSET : 127|3@0+ (1,0) [0|7] "" AMP

BO_ 868 EDC_364: 8 EDC
    SG_ CdcEpbSetSwt_1 : 1|2@0+ (1,0) [0|3] "" VIU_FR

CM_ BO_ 722 " ";
CM_ SG_ 722 AcRemStartSts "空调远程控制标志位";
CM_ SG_ 722 CDC_CRCCheck_2D2 "2D2帧报文校验";
CM_ SG_ 722 CDC_RollingCounter_2D2 "2D2帧报文计数";
CM_ SG_ 722 CdcAcChrgILimSet "交流充电电流限值设置";
CM_ SG_ 722 CdcAntiRustFctSet "制动盘除锈功能设置状态";
CM_ SG_ 722 CdcAqsOpenSet "AQS开启请求";
CM_ SG_ 722 CdcAutoApplyFctSet "AutoApply功能设置状态";
CM_ SG_ 722 CdcAutoDefrstDefogStsReq "自动除霜除雾设定请求信号";
CM_ SG_ 722 CdcAutoWindLongPressSet "钥匙长按通风设置";
CM_ SG_ 722 CdcAutoWindUnlockSet "钥匙开锁通风设置";
CM_ SG_ 722 CdcAVHFctSet "AVH功能设置状态";
CM_ SG_ 722 CdcBacktWindLvlSetReq "后排风量设定请求（风口）";
CM_ SG_ 722 CdcBattPlsHeatgSet "电池即时加热设置请求";
CM_ SG_ 722 CdcBDWFctSet "BDW功能设置状态";
CM_ SG_ 722 CdcBrkPedlModSet "制动踏板感模式设置";
CM_ SG_ 722 CdcCycModSet "循环模式设定请求";
CM_ SG_ 722 CdcDrvrTSet "主驾温度设定请求";
CM_ SG_ 722 CdcEpbSwtSet "CDC电子手刹开关设置";
CM_ SG_ 722 CdcEspFctSet "ESP功能设置状态";
CM_ SG_ 722 CdcFrntAutModOpenSet "前排空调自动模式设定请求";
CM_ SG_ 722 CdcFrntBlowModSet "前出风模式设定请求";
CM_ SG_ 722 CdcFrntDefrosterSet "前除霜模式设定请求";
CM_ SG_ 722 CdcFrntWindLvlSet "前排风量设定请求";
CM_ SG_ 722 CdcFrontAcOffSet "前排空调开启/关闭请求";
CM_ SG_ 722 CdcHDCFctSet "HDC功能设置状态";
CM_ SG_ 722 CdcHotColdModStReq "制冷制热模式设定请求";
CM_ SG_ 722 CdcIBCUDrvModSet "IBCU模式设置";
CM_ SG_ 722 CdcORCAFctSet "坦克掉头功能设置状态";
CM_ SG_ 722 CdcPassTSet "副驾温度设定请求";
CM_ SG_ 722 CdcPlasmaOpenSet "离子发生器控制请求";
CM_ SG_ 722 CdcSteerModSet "助力转向模式设置";
CM_ SG_ 722 CdcTotMilg "总里程信号";
CM_ SG_ 722 CdcVehEgyCnseSelect "能耗选项";
CM_ SG_ 722 CdcVentnOnSet "定时通风开启请求";
CM_ SG_ 722 CdcWorkSpaceSet "温区设定同步请求";
CM_ SG_ 722 CST_OFF_Switch "CST功能设置开关";
CM_ SG_ 722 HU_ACRearFanAdjustValueReq "后排风量设定请求信号";
CM_ SG_ 722 HU_ACRearModeAdjustReq "后排出风模式设定请求信号";
CM_ SG_ 722 HU_ACRearTempAdjustValueReq2 "后排温度设定信号2";
CM_ SG_ 722 HU_AutowindSet3 "空调自干燥设置";
CM_ SG_ 722 HU_MaxACReq "最大制冷开启请求";
CM_ SG_ 722 HU_MaxDefReq "最大除霜开启请求";
CM_ SG_ 722 HU_MaxHeatReq "最大制热开启请求";
CM_ SG_ 722 HU_RearACOfffReq "后排空调开启/关闭请求信号";
CM_ SG_ 722 HU_RearAUTOACOnReq "后排空调自动模式开启请求信号";
CM_ SG_ 722 HU_RefreshModeEnable "清醒提神模式设置信号";
CM_ SG_ 722 HU_Request_AFUchannel "香氛通道选择";
CM_ SG_ 722 HU_Request_AFUContentleve "香氛浓度控制";
CM_ SG_ 722 HU_Request_AFUSt "香氛开启请求";
CM_ SG_ 722 HU_RollerbenchSetStaus "测功机模式目标状态";
CM_ SG_ 722 HU_VentilationSetAfternoon "定时通风设定下午";
CM_ SG_ 722 HU_VentilationSetEvening "定时通风设定晚上";
CM_ SG_ 722 HU_VentilationSetMorning "定时通风设定上午";
CM_ SG_ 722 HUAcEgySaveModReq "空调节能模式设置请求";
CM_ SG_ 722 HUAutoAirCleanReq "自动空气净化设置请求";
CM_ SG_ 722 HUBatPulseHeatSwitchReq "电池脉冲加热开关设置";
CM_ SG_ 722 HUMotLockHeatSwitchReq "电机堵转加热开关设置";
CM_ SG_ 722 HUSngPrsnModReq "单人模式设置请求";
CM_ SG_ 722 VIUDrvModSet "驾驶模式设置";
CM_ BO_ 753 " ";
CM_ SG_ 753 RCM_RLTuLiSt "左后转向灯状态";
CM_ SG_ 753 RCM_RRTuLiSt "右后转向灯状态";
CM_ BO_ 759 " ";
CM_ SG_ 759 TboxLocalTiDate "本地时间日";
CM_ SG_ 759 TboxLocalTiHr "本地时间时";
CM_ SG_ 759 TboxLocalTiMins "本地时间分";
CM_ SG_ 759 TboxLocalTiMth "本地时间月";
CM_ SG_ 759 TboxLocalTiSec "本地时间秒";
CM_ SG_ 759 TboxLocalTiVld "本地时间有效位";
CM_ SG_ 759 TboxLocalTiYear "本地时间年";
CM_ BO_ 760 " ";
CM_ SG_ 760 Tbox_GPSLocalTiDate "GPS时间日";
CM_ SG_ 760 Tbox_GPSLocalTiHr "GPS时间时";
CM_ SG_ 760 Tbox_GPSLocalTiMins "GPS时间分";
CM_ SG_ 760 Tbox_GPSLocalTiMth "GPS时间月";
CM_ SG_ 760 Tbox_GPSLocalTiSec "GPS时间秒";
CM_ SG_ 760 Tbox_GPSLocalTiVld "GPS时间有效位";
CM_ SG_ 760 Tbox_GPSLocalTiYear "GPS时间年";
CM_ BO_ 774 " ";
CM_ SG_ 774 AC_ACOnOff "空调工作状态";
CM_ SG_ 774 ITMSLiquidLevel "液位传感器";
CM_ SG_ 774 TmsComOutPtPre "压缩机出口PT传感器压力信号";
CM_ BO_ 779 " ";
CM_ SG_ 779 CDC_CRCCheck_30B "30B帧报文校验";
CM_ SG_ 779 CDC_RollingCounter_30B "30B帧报文计数";
CM_ SG_ 779 CdcIPScreenLiOnSts "仪表亮灭状态";
CM_ SG_ 779 IP_DISFail "仪表故障";
CM_ SG_ 779 IP_juADASshowinfa "IP判断影响ADAS正常显示的自身故障输出信号";
CM_ SG_ 779 IP_juADASshowoutfa "IP判断影响ADAS正常显示的外部故障输出信号";
CM_ SG_ 779 IP_juADAStsE2Efaout "IP判断ADAS信号E2E校验故障输出信号";
CM_ SG_ 779 IP_QDashACCFail "仪表检测到ACC发出的信息有误（例如timeout）";
CM_ SG_ 779 AD_EDCCrtSts "EDC工作状态";
CM_ SG_ 779 AD_EDCCurrenttemp "EDC当前温度";
CM_ SG_ 779 TboxDoorLockRemCtrlReq "远程解闭锁请求";
CM_ BO_ 784 " ";
CM_ SG_ 784 AMP_Err_Detect "外置功放错误检测";
CM_ SG_ 784 AMP_FLHighSpeakerDelaySETStatus "前左高音扬声器延时设置状态";
CM_ SG_ 784 AMP_FLHighSpeakerVolSETStatus "前左高音扬声器增益设置状态";
CM_ SG_ 784 AMP_FLMidSpeakerDelaySETStatus "前左中音扬声器延时设置状态";
CM_ SG_ 784 AMP_FLMidSpeakerVolSETStatus "前左中音扬声器增益设置状态";
CM_ SG_ 784 AMP_FRHighSpeakerDelaySETStatus "前右高音扬声器延时设置状态";
CM_ SG_ 784 AMP_FRHighSpeakerVolSETStatus "前右高音扬声器增益设置状态";
CM_ SG_ 784 AMP_FRMidSpeakerDelaySETStatus "前右中音扬声器延时设置状态";
CM_ SG_ 784 AMP_FRMidSpeakerVolSETStatus "前右中音扬声器增益设置状态";
CM_ SG_ 784 AMP_Slot_Detect "外置功放slot通道监测";
CM_ SG_ 784 AMP_SV_Detect "外置功放内部版本监测";
CM_ SG_ 784 AMP_AlarmVolSETStatus "报警音音量设置状态";
CM_ SG_ 784 AMP_AvasVolSETStatus "车外行人警示音音量设置状态";
CM_ SG_ 784 AMP_CenterSpeakerDelaySETStatus "中置扬声器延时设置状态";
CM_ SG_ 784 AMP_CenterSpeakerVolSETStatus "中置扬声器增益设置状态";
CM_ SG_ 784 AMP_CustomEffectSETStatus "自定义音效设置状态";
CM_ SG_ 784 AMP_CustomEQ125SET "自定义125Hz频段设置状态";
CM_ SG_ 784 AMP_CustomEQ16KSET "自定义16000Hz频段设置状态";
CM_ SG_ 784 AMP_CustomEQ1KSET "自定义1000Hz频段设置状态";
CM_ SG_ 784 AMP_CustomEQ250SET "自定义250Hz频段设置状态";
CM_ SG_ 784 AMP_CustomEQ2KSET "自定义2000Hz频段设置状态";
CM_ SG_ 784 AMP_CustomEQ4KSET "自定义4000Hz频段设置状态";
CM_ SG_ 784 AMP_CustomEQ500SET "自定义500Hz频段设置状态";
CM_ SG_ 784 AMP_CustomEQ62SET "自定义62Hz频段设置状态";
CM_ SG_ 784 AMP_CustomEQ8KSET "自定义8000Hz频段设置状态";
CM_ SG_ 784 AMP_FLLowSpeakerDelaySETStatus "前左低音扬声器延时设置状态";
CM_ SG_ 784 AMP_FLLowSpeakerVolSETStatus "前左低音扬声器增益设置状态";
CM_ SG_ 784 AMP_FLMidHighSpeakerDelaySETStat "前左中高音扬声器延时设置状态";
CM_ SG_ 784 AMP_FLMidHighSpeakerVolSETStatus "前左中高音扬声器增益设置状态";
CM_ SG_ 784 AMP_FLTopSpeakerDelaySETStatus "前左顶棚扬声器延时设置状态";
CM_ SG_ 784 AMP_FLTopSpeakerVolSETStatus "前左顶棚扬声器增益设置状态";
CM_ SG_ 784 AMP_FRBalanceSETStatus "声场前后平衡设置状态";
CM_ SG_ 784 AMP_FRLowSpeakerDelaySETStatus "前右低音扬声器延时设置状态";
CM_ SG_ 784 AMP_FRLowSpeakerVolSETStatus "前右低音扬声器增益设置状态";
CM_ SG_ 784 AMP_FRMidHighSpeakerDelaySET "前右中高音扬声器延时设置状态";
CM_ SG_ 784 AMP_FRMidHighSpeakerVolSETStatus "前右中高音扬声器增益设置状态";
CM_ SG_ 784 AMP_FRTopSpeakerDelaySETStatus "前右顶棚扬声器延时设置状态";
CM_ SG_ 784 AMP_FRTopSpeakerVolSETStatus "前右顶棚扬声器增益设置状态";
CM_ SG_ 784 AMP_KTVMUTESETStatus "KTV人声静音设置状态";
CM_ SG_ 784 AMP_KTVVolSETStatus "KTV人声音量设置状态";
CM_ SG_ 784 AMP_LRBalanceSETStatus "声场左右平衡设置状态";
CM_ SG_ 784 AMP_MediaMUTESETStatus "多媒体静音设置状态";
CM_ SG_ 784 AMP_MediaVolSETStatus "多媒体音量设置状态";
CM_ SG_ 784 AMP_MUTESETStatus "全部静音设置状态";
CM_ SG_ 784 AMP_NaviMUTESETStatus "导航静音设置状态";
CM_ SG_ 784 AMP_NAVIVolSETStatus "导航播报音量设置状态";
CM_ SG_ 784 AMP_OutMUTESETStatus "车外声音静音设置状态";
CM_ SG_ 784 AMP_OUTVolSETStatus "车外声音音量设置状态";
CM_ SG_ 784 AMP_PerfessiionalEQ100SET "专业自定义100Hz频段设置状态";
CM_ SG_ 784 AMP_PerfessiionalEQ500SET "专业自定义500Hz频段设置状态";
CM_ SG_ 784 AMP_PerfessiionalEQ6KSET "专业自定义6000Hz频段设置状态";
CM_ SG_ 784 AMP_RLLowHighSpeakerDelaySETStat "后左低高音扬声器延时设置状态";
CM_ SG_ 784 AMP_RLLowHighSpeakerVolSETStatus "后左低高音扬声器增益设置状态";
CM_ SG_ 784 AMP_RLSurroundSpeakerDelaySETSta "后左环绕扬声器延时设置状态";
CM_ SG_ 784 AMP_RLSurroundSpeakerVolSETStatu "后左环绕扬声器增益设置状态";
CM_ SG_ 784 AMP_RLTopSpeakerDelaySETStatus "后左顶棚扬声器延时设置状态";
CM_ SG_ 784 AMP_RLTopSpeakerVolSETStatus "后左顶棚扬声器增益设置状态";
CM_ SG_ 784 AMP_RNCEnableSETStatus "主动路噪降噪功能设置状态";
CM_ SG_ 784 AMP_RRLowHighSpeakerDelaySET "后右低高音扬声器延时设置状态";
CM_ SG_ 784 AMP_RRLowHighSpeakerVolSETStatus "后右低高音扬声器增益设置状态";
CM_ SG_ 784 AMP_RRSurroundSpeakerDelaySETSta "后右环绕扬声器延时设置状态";
CM_ SG_ 784 AMP_RRSurroundSpeakerVolSET "后右环绕扬声器增益设置状态";
CM_ SG_ 784 AMP_RRTopSpeakerDelaySETStatus "后右顶棚扬声器延时设置状态";
CM_ SG_ 784 AMP_RRTopSpeakerVolSETStatus "后右顶棚扬声器增益设置状态";
CM_ SG_ 784 AMP_SoundEffectSETStatus "音效设置状态";
CM_ SG_ 784 AMP_SoundFieldSETStatus "声场设置状态";
CM_ SG_ 784 AMP_SubSpeakerDelaySETStatus "重低音扬声器延时设置状态";
CM_ SG_ 784 AMP_SubSpeakerVolSETStatus "重低音扬声器增益设置状态";
CM_ SG_ 784 AMP_SystemMUTESETStatus "系统提示音静音设置状态";
CM_ SG_ 784 AMP_SystemVolSETStatus "系统提示音量设置状态";
CM_ SG_ 784 AMP_TelBcallMUTESETStatus "电话/Bcall静音设置状态";
CM_ SG_ 784 AMP_TELBCALLVolSETStatus "蓝牙电话音量/becall音量设置状态";
CM_ SG_ 784 AMP_TTSVRMUTESETStatus "TTS/语音静音设置状态";
CM_ SG_ 784 AMP_TTSVRVolSETStatus "TTS/语音音量设置状态";
CM_ SG_ 784 AMP_TurnLightInOrOutSETStatus "转向灯音车内外设置状态";
CM_ SG_ 784 AMP_TurnLightVolSETStatus "转向灯音音量设置状态";
CM_ SG_ 784 AMP_VOLSpeedEnableSETStatus "音量随速调节功能设置状态";
CM_ BO_ 800 " ";
CM_ SG_ 800 AMPFLPositionDelaySETStatus "前左方位延时设置状态";
CM_ SG_ 800 AMPFLPositionVolSETStatus "前左方位增益设置状态";
CM_ SG_ 800 AMPFRPositionDelaySETStatus "前右方位延时设置状态";
CM_ SG_ 800 AMPFRPositionVolSETStatus "前右方位增益设置状态";
CM_ SG_ 800 AMPBeosonicModeSetStatus "Beosonic模式设置状态";
CM_ SG_ 800 AMPBeosonicXSetStatus "BeosonicX轴参数设置状态";
CM_ SG_ 800 AMPBeosonicYSetStatus "BeosonicY轴参数设置状态";
CM_ SG_ 800 AMPCenterPositionDelaySETStatus "中置方位延时设置状态";
CM_ SG_ 800 AMPCenterPositionVolSETStatus "中置方位增益设置状态";
CM_ SG_ 800 AMPCustomEQ2500SET "自定义2500Hz频段设置状态";
CM_ SG_ 800 AMPCustomEQ315SET "自定义315Hz频段设置状态";
CM_ SG_ 800 AMPCustomEQ50SET "自定义50Hz频段设置状态";
CM_ SG_ 800 AMPCustomEQ6000SET "自定义6000Hz频段设置状态";
CM_ SG_ 800 AMPCustomEQ800SET "自定义800Hz频段设置状态";
CM_ SG_ 800 AMPFLTopPositionDelaySETStatus "前左天空方位延时设置状态";
CM_ SG_ 800 AMPFLTopPositionVolSETStatus "前左天空方位增益设置状态";
CM_ SG_ 800 AMPFRTopPositionDelaySETStatus "前右天空方位延时设置状态";
CM_ SG_ 800 AMPFRTopPositionVolSETStatus "前右天空方位增益设置状态";
CM_ SG_ 800 AMPRLPositionDelaySETStatus "后左方位延时设置状态";
CM_ SG_ 800 AMPRLPositionVolSETStatus "后左方位增益设置状态";
CM_ SG_ 800 AMPRLSurroundDelaySETStatus "后左环绕方位延时设置状态";
CM_ SG_ 800 AMPRLSurroundVolSETStatus "后左环绕方位增益设置状态";
CM_ SG_ 800 AMPRLTopDelaySETStatus "后左天空方位延时设置状态";
CM_ SG_ 800 AMPRLTopVolSETStatus "后左天空方位增益设置状态";
CM_ SG_ 800 AMPRRPositionDelaySET "后右方位延时设置状态";
CM_ SG_ 800 AMPRRPositionVolSETStatus "后右方位增益设置状态";
CM_ SG_ 800 AMPRRSurroundPositionDelaySETSta "后右环绕方位延时设置状态";
CM_ SG_ 800 AMPRRSurroundPositionVolSET "后右环绕方位增益设置状态";
CM_ SG_ 800 AMPRRTopPositionDelaySETStatus "后右天空方位延时设置状态";
CM_ SG_ 800 AMPRRTopPositionVolSETStatus "后右天空方位增益设置状态";
CM_ SG_ 800 AMPSoundSourceTypeStatus "音源类型状态";
CM_ SG_ 800 AMPSubPositionDelaySETStatus "重低音方位延时设置状态";
CM_ SG_ 800 AMPSubPositionVolSETStatus "重低音方位增益设置状态";
CM_ SG_ 800 AMPTMCenterPositionEQ15000HzSetS "中置方位15000Hz频段设置状态（调音大师）";
CM_ SG_ 800 AMPTMCenterPositionEQ800HzSetSta "中置方位800Hz频段设置状态（调音大师）";
CM_ SG_ 800 AMPTMFLPositionEQ100HzSetStatus "前左方位100Hz频段设置状态（调音大师）";
CM_ SG_ 800 AMPTMFLPositionEQ15000HzSetStatu "前左方位15000Hz频段设置状态（调音大师）";
CM_ SG_ 800 AMPTMFLPositionEQ800HzSetStatus "前左方位800Hz频段设置状态（调音大师）";
CM_ SG_ 800 AMPTMFLTopPositionEQ500HzSetStat "前左天空方位500Hz频段设置状态（调音大师）";
CM_ SG_ 800 AMPTMFRPositionEQ100HzSetStatus "前右方位100Hz频段设置状态（调音大师）";
CM_ SG_ 800 AMPTMFRPositionEQ15000HzSetStatu "前右方位15000Hz频段设置状态（调音大师）";
CM_ SG_ 800 AMPTMFRPositionEQ800HzSetStatus "前右方位800Hz频段设置状态（调音大师）";
CM_ SG_ 800 AMPTMFRTopPositionEQ500HzSetStat "前右天空方位500Hz频段设置状态（调音大师）";
CM_ SG_ 800 AMPTMReverbSetStatus "混响调节设置状态（调音大师）";
CM_ SG_ 800 AMPTMRLPositionEQ10000HzSetStatu "后左方位10000Hz频段设置状态（调音大师）";
CM_ SG_ 800 AMPTMRLPositionEQ100HzSetStatusS "后左方位100Hz频段设置状态（调音大师）";
CM_ SG_ 800 AMPTMRLSurroundPositionEQ15000Hz "后左环绕方位15000Hz频段设置状态（调音大师）";
CM_ SG_ 800 AMPTMRLSurroundPositionEQ800HzSe "后左环绕方位800Hz频段设置状态（调音大师）";
CM_ SG_ 800 AMPTMRLTopPositionEQ500HzSetStat "后左天空方位500Hz频段设置状态（调音大师）";
CM_ SG_ 800 AMPTMRRPositionEQ10000HzSetStatu "后右方位10000Hz频段设置状态（调音大师）";
CM_ SG_ 800 AMPTMRRPositionEQ100HzSetStatus "后右方位100Hz频段设置状态（调音大师）";
CM_ SG_ 800 AMPTMRRSurroundPositionEQ15000Hz "后右环绕方位15000Hz频段设置状态（调音大师）";
CM_ SG_ 800 AMPTMRRSurroundPositionEQ800HzSe "后右环绕方位800Hz频段设置状态（调音大师）";
CM_ SG_ 800 AMPTMRRTopPositionEQ500HzSetStat "后右天空方位500Hz频段设置状态（调音大师）";
CM_ SG_ 800 AMPTMSubPositionEQ30HzSetStatusS "重低音方位30Hz频段设置状态（调音大师）";
CM_ SG_ 800 AMPVOLSpeedLevChangeSETStatus "音量随速调节功能设置状态（新）";
CM_ BO_ 802 " ";
CM_ SG_ 802 ECAStarLvl "空簧目标高度";
CM_ SG_ 802 ECASActLvlFL "FL高度信号";
CM_ SG_ 802 ECASActLvlFR "FR高度信号";
CM_ SG_ 802 ECASActLvlRL "RL高度信号";
CM_ SG_ 802 ECASActLvlRR "RR高度信号";
CM_ SG_ 802 ECASAdjBySpd "随速调节激活状态";
CM_ SG_ 802 ECASaftaxladjsts "ECAS后轴升降状态";
CM_ SG_ 802 ECASerromode "ECAS故障模式";
CM_ SG_ 802 ECASfrtaxladjsts "ECAS前轴升降状态";
CM_ SG_ 802 EcasModeCHASts "ECAS模式切换状态";
CM_ SG_ 802 EcasModeFB "空簧模式当前模式反馈";
CM_ SG_ 802 ECASmodevld "ECAS模式有效";
CM_ SG_ 802 SusfaultlLamp "悬架故障点灯提示";
CM_ SG_ 802 Susfaultred "悬架文字提示";
CM_ BO_ 821 " ";
CM_ SG_ 821 BCM_DriverWindowStatus "主驾车窗状态";
CM_ SG_ 821 BCM_PartWinPosVIT "隔断玻璃实时位置（百分比）";
CM_ SG_ 821 BCM_PartWinSts "隔断玻璃状态";
CM_ SG_ 821 BCM_PassengerWindowPosi "副驾车窗位置";
CM_ SG_ 821 BCM_PassengerWindowStatus "副驾车窗状态";
CM_ SG_ 821 VcuIpuErrLamp "驱动电机故障指示灯";
CM_ SG_ 821 VcuEgyMagtModResp "能源模式设置反馈";
CM_ SG_ 821 VcuForceEVModResp "强制纯电模式反馈";
CM_ SG_ 821 VcuForcePwrPresModResp "强制保电模式反馈";
CM_ SG_ 821 BCM_RightRearWindowPosi "右后车窗位置";
CM_ SG_ 821 BCM_RightRearWindowStatus "右后车窗状态";
CM_ SG_ 821 VCU_CRCCheck_335 "335帧报文校验";
CM_ SG_ 821 VCU_RollingCounter_335 "335帧报文计数";
CM_ SG_ 821 VcuAcChrgNegativePoleTemp "交流充电负极温度";
CM_ SG_ 821 VcuAccrPedlPosnGb "加速踏板行程";
CM_ SG_ 821 VcuBattIGb "总电流（国标）";
CM_ SG_ 821 VcuGearPosnStsGb "挡位状态";
CM_ SG_ 821 VcuHvilStsGb "高压互锁状态报警（国标）";
CM_ SG_ 821 VcuVehChrgStsGb "充电状态";
CM_ SG_ 821 VcuVehRunngModGb "运行模式";
CM_ SG_ 821 VcuVehStsGb "车辆状态";
CM_ SG_ 821 VcuBrkPedlSts "VCU制动踏板状态";
CM_ SG_ 821 VcuPwrCnse "整车瞬时功率";
CM_ SG_ 821 VcuSocDisp "仪表显示SOC";
CM_ SG_ 821 BCM_DriverWindowPosi "主驾车窗位置";
CM_ SG_ 821 BCM_LeftRearWindowPosi "左后车窗位置";
CM_ SG_ 821 BCM_LeftRearWindowStatus "左后车窗状态";
CM_ SG_ 821 BcmSunroofPosi "天窗位置";
CM_ SG_ 821 BcmSunroofStatus "天窗状态";
CM_ SG_ 821 MFS_Right_switch_Right1_signal "MFS方向盘右按键1";
CM_ SG_ 821 VcuAcChrgPositivePoleTemp "交流充电正极温度";
CM_ SG_ 821 VcuBattChrgErrLamp "蓄电池充电故障指示灯";
CM_ SG_ 821 VcuBattlowU "铅蓄电池电压";
CM_ SG_ 821 VcuBattUUnderWarn "铅蓄电池电压报警";
CM_ SG_ 821 VcuChrgAutoUnlckSetStsFb "充电锁自动解锁功能设置状态反馈";
CM_ SG_ 821 VcuChrgLckInfo "电子锁文字提示";
CM_ SG_ 821 VcuDcChrgNegativePoleTemp "直流充电负极温度";
CM_ SG_ 821 VcuDcChrgPositivePoleTemp "直流充电正极温度";
CM_ SG_ 821 VCUGearShiftPositon "换挡器位置";
CM_ SG_ 821 VcuHvBattCutOffLamp "高压电池切断指示灯";
CM_ SG_ 821 VcuHVErrInfo "高压故障提示信息";
CM_ SG_ 821 VcuHvilSts "高压互锁状态";
CM_ SG_ 821 VcuResiMilg "整车续驶里程";
CM_ SG_ 821 VcuShiftPErrInfo "P挡故障提示信息";
CM_ SG_ 821 VCUShiftPostionValid "换挡器位置有效";
CM_ SG_ 821 VcuVehErrInfo "车辆严重故障提示信息";
CM_ SG_ 821 VIUFL_DeviceVerifyResult "设备认证结果";
CM_ SG_ 821 VcuOffRoadCrpSts "越野蠕行状态";
CM_ SG_ 821 BCMALLDoorLockSwt "整车门锁状态";
CM_ BO_ 822 " ";
CM_ SG_ 822 CcsmFrntEDLSetSwt "CCSM前差速锁开关请求 ";
CM_ SG_ 822 CcsmReEDLSetSwt "CCSM后差速锁开关请求 ";
CM_ SG_ 822 CcsmEDLBtnStuckFlg "差速锁按键粘连故障标志";
CM_ BO_ 854 " ";
CM_ SG_ 854 HU_FLHighSpeakerDelaySET "前左高音扬声器延时设置";
CM_ SG_ 854 HU_FLHighSpeakerVolSET "前左高音扬声器增益设置";
CM_ SG_ 854 HU_FLMidSpeakerDelaySET "前左中音扬声器延时设置";
CM_ SG_ 854 HU_FLMidSpeakerVolSET "前左中音扬声器增益设置";
CM_ SG_ 854 HU_FRHighSpeakerDelaySET "前右高音扬声器延时设置";
CM_ SG_ 854 HU_FRHighSpeakerVolSET "前右高音扬声器增益设置";
CM_ SG_ 854 HU_FRMidSpeakerDelaySET "前右中音扬声器延时设置";
CM_ SG_ 854 HU_FRMidSpeakerVolSET "前右中音扬声器增益设置";
CM_ SG_ 854 HUFLPositionDelaySET "前左方位延时设置";
CM_ SG_ 854 HUFLPositionVolSET "前左方位增益设置";
CM_ SG_ 854 HUFRPositionDelaySET "前右方位延时设置";
CM_ SG_ 854 HUFRPositionVolSET "前右方位增益设置";
CM_ SG_ 854 HU_AlarmVolSET "报警音音量设置";
CM_ SG_ 854 HU_AvasVolSET "车外行人警示音音量设置";
CM_ SG_ 854 HU_CenterSpeakerDelaySET "中置扬声器延时设置";
CM_ SG_ 854 HU_CenterSpeakerVolSET "中置扬声器增益设置";
CM_ SG_ 854 HU_CustomEffectSET "自定义音效设置";
CM_ SG_ 854 HU_CustomEQ125SET "自定义125Hz频段设置";
CM_ SG_ 854 HU_CustomEQ16KSET "自定义16000Hz频段设置";
CM_ SG_ 854 HU_CustomEQ1KSET "自定义1000Hz频段设置";
CM_ SG_ 854 HU_CustomEQ250SET "自定义250Hz频段设置";
CM_ SG_ 854 HU_CustomEQ2KSET "自定义2000Hz频段设置";
CM_ SG_ 854 HU_CustomEQ4KSET "自定义4000Hz频段设置";
CM_ SG_ 854 HU_CustomEQ500SET "自定义500Hz频段设置";
CM_ SG_ 854 HU_CustomEQ62SET "自定义62Hz频段设置";
CM_ SG_ 854 HU_CustomEQ8KSET "自定义8000Hz频段设置";
CM_ SG_ 854 HU_FLLowSpeakerDelaySET "前左低音扬声器延时设置";
CM_ SG_ 854 HU_FLLowSpeakerVolSET "前左低音扬声器增益设置";
CM_ SG_ 854 HU_FLMidHighSpeakerDelaySET "前左中高音扬声器延时设置";
CM_ SG_ 854 HU_FLMidHighSpeakerVolSET "前左中高音扬声器增益设置";
CM_ SG_ 854 HU_FLTopSpeakerDelaySET "前左顶棚扬声器延时设置";
CM_ SG_ 854 HU_FLTopSpeakerVolSET "前左顶棚扬声器增益设置";
CM_ SG_ 854 HU_FRBalanceSET "声场前后平衡设置";
CM_ SG_ 854 HU_FRLowSpeakerDelaySET "前右低音扬声器延时设置";
CM_ SG_ 854 HU_FRLowSpeakerVolSET "前右低音扬声器增益设置";
CM_ SG_ 854 HU_FRMidHighSpeakerDelaySET "前右中高音扬声器延时设置";
CM_ SG_ 854 HU_FRMidHighSpeakerVolSET "前右中高音扬声器增益设置";
CM_ SG_ 854 HU_FRTopSpeakerDelaySET "前右顶棚扬声器延时设置";
CM_ SG_ 854 HU_FRTopSpeakerVolSET "前右顶棚扬声器增益设置";
CM_ SG_ 854 HU_KTVMUTESET "KTV人声静音设置";
CM_ SG_ 854 HU_KTVVolSET "KTV人声音量设置";
CM_ SG_ 854 HU_LRBalanceSET "声场左右平衡设置";
CM_ SG_ 854 HU_MediaMUTESET "多媒体静音设置";
CM_ SG_ 854 HU_MediaVolSET "多媒体音量设置";
CM_ SG_ 854 HU_MUTESET "全部静音设置";
CM_ SG_ 854 HU_NaviMUTESET "导航静音设置";
CM_ SG_ 854 HU_NAVIVolSET "导航播报音量设置";
CM_ SG_ 854 HU_OutMUTESET "车外声音静音设置";
CM_ SG_ 854 HU_OUTVolSET "车外声音音量设置";
CM_ SG_ 854 HU_PerfessiionalEQ100SET "专业自定义100Hz频段设置";
CM_ SG_ 854 HU_PerfessiionalEQ500SET "专业自定义500Hz频段设置";
CM_ SG_ 854 HU_PerfessiionalEQ6KSET "专业自定义6000Hz频段设置";
CM_ SG_ 854 HU_RLLowHighSpeakerDelaySET "后左低高音扬声器延时设置";
CM_ SG_ 854 HU_RLLowHighSpeakerVolSET "后左低高音扬声器增益设置";
CM_ SG_ 854 HU_RLSurroundSpeakerDelaySET "后左环绕扬声器延时设置";
CM_ SG_ 854 HU_RLSurroundSpeakerVolSET "后左环绕扬声器增益设置";
CM_ SG_ 854 HU_RLTopSpeakerDelaySET "后左顶棚扬声器延时设置";
CM_ SG_ 854 HU_RLTopSpeakerVolSET "后左顶棚扬声器增益设置";
CM_ SG_ 854 HU_RNCEnableSET "主动路噪降噪功能设置";
CM_ SG_ 854 HU_RRLowHighSpeakerDelaySET "后右低高音扬声器延时设置";
CM_ SG_ 854 HU_RRLowHighSpeakerVolSET "后右低高音扬声器增益设置";
CM_ SG_ 854 HU_RRSurroundSpeakerDelaySET "后右环绕扬声器延时设置";
CM_ SG_ 854 HU_RRSurroundSpeakerVolSET "后右环绕扬声器增益设置";
CM_ SG_ 854 HU_RRTopSpeakerDelaySET "后右顶棚扬声器延时设置";
CM_ SG_ 854 HU_RRTopSpeakerVolSET "后右顶棚扬声器增益设置";
CM_ SG_ 854 HU_SoundEffectSET "音效设置";
CM_ SG_ 854 HU_SoundFieldSET "声场设置";
CM_ SG_ 854 HU_SubSpeakerDelaySET "重低音扬声器延时设置";
CM_ SG_ 854 HU_SubSpeakerVolSET "重低音扬声器增益设置";
CM_ SG_ 854 HU_SystemMUTESET "系统提示音静音设置";
CM_ SG_ 854 HU_SystemVolSET "系统提示音量设置";
CM_ SG_ 854 HU_TelBcallMUTESET "电话/Bcall静音设置";
CM_ SG_ 854 HU_TELBCALLVolSET "蓝牙电话音量/becall音量设置";
CM_ SG_ 854 HU_TTSVRMUTESET "TTS/语音静音设置";
CM_ SG_ 854 HU_TTSVRVolSET "TTS/语音音量设置";
CM_ SG_ 854 HU_TurnLightInOrOutSET "转向灯音车内外设置";
CM_ SG_ 854 HU_TurnLightVolSET "转向灯音音量设置";
CM_ SG_ 854 HU_VOLSpeedLevEnableSET "音量随速调节功能设置";
CM_ SG_ 854 HUBeosonicModeSet "Beosonic模式设置";
CM_ SG_ 854 HUBeosonicXSet "BeosonicX轴参数设置";
CM_ SG_ 854 HUBeosonicYSet "BeosonicY轴参数设置";
CM_ SG_ 854 HUCenterPositionDelaySET "中置方位延时设置";
CM_ SG_ 854 HUCenterPositionVolSET "中置方位增益设置";
CM_ SG_ 854 HUCustomEQ2500SET "自定义2500Hz频段设置状态";
CM_ SG_ 854 HUCustomEQ315SET "自定义315Hz频段设置状态";
CM_ SG_ 854 HUCustomEQ50SET "自定义50Hz频段设置状态";
CM_ SG_ 854 HUCustomEQ6000SET "自定义6000Hz频段设置状态";
CM_ SG_ 854 HUCustomEQ800SET "自定义800Hz频段设置状态";
CM_ SG_ 854 HUFLTopPositionDelaySET "前左天空方位延时设置";
CM_ SG_ 854 HUFLTopPositionVolSET "前左天空方位增益设置";
CM_ SG_ 854 HUFRTopPositionDelaySET "前右天空方位延时设置";
CM_ SG_ 854 HUSoundSourceType "音源类型";
CM_ SG_ 854 HUTMCenterPositionEQ15000HzSet "中置方位15000Hz频段设置（调音大师）";
CM_ SG_ 854 HUTMCenterPositionEQ800HzSet "中置方位800Hz频段设置（调音大师）";
CM_ SG_ 854 HUTMFLPositionEQ100HzSet "前左方位100Hz频段设置（调音大师）";
CM_ SG_ 854 HUTMFLPositionEQ15000HzSet "前左方位15000Hz频段设置（调音大师）";
CM_ SG_ 854 HUTMFLPositionEQ800HzSet "前左方位800Hz频段设置（调音大师）";
CM_ SG_ 854 HUTMFLTopPositionEQ500HzSet "前左天空方位500Hz频段设置（调音大师）";
CM_ SG_ 854 HUTMFRPositionEQ100HzSet "前右方位100Hz频段设置（调音大师）";
CM_ SG_ 854 HUTMFRPositionEQ15000HzSet "前右方位15000Hz频段设置（调音大师）";
CM_ SG_ 854 HUTMFRPositionEQ800HzSet "前右方位800Hz频段设置（调音大师）";
CM_ SG_ 854 HUTMFRTopPositionEQ500HzSet "前右天空方位500Hz频段设置（调音大师）";
CM_ SG_ 854 HUTMReverbSet "混响调节设置（调音大师）";
CM_ SG_ 854 HUTMRLPositionEQ10000HzSet "后左方位10000Hz频段设置（调音大师）";
CM_ SG_ 854 HUTMRLPositionEQ100HzSet "后左方位100Hz频段设置（调音大师）";
CM_ SG_ 854 HUTMRLSurroundPositionEQ15000HzS "后左环绕方位15000Hz频段设置（调音大师）";
CM_ SG_ 854 HUTMRLSurroundPositionEQ800HzSet "后左环绕方位800Hz频段设置（调音大师）";
CM_ SG_ 854 HUTMRLTopPositionEQ500HzSet "后左天空方位500Hz频段设置（调音大师）";
CM_ SG_ 854 HUTMRRPositionEQ10000HzSet "后右方位10000Hz频段设置（调音大师）";
CM_ SG_ 854 HUTMRRPositionEQ100HzSet "后右方位100Hz频段设置（调音大师）";
CM_ SG_ 854 HUTMRRSurroundPositionEQ15000HzS "后右环绕方位15000Hz频段设置（调音大师）";
CM_ SG_ 854 HUTMRRSurroundPositionEQ800HzSet "后右环绕方位800Hz频段设置（调音大师）";
CM_ SG_ 854 HUTMRRTopPositionEQ500HzSet "后右天空方位500Hz频段设置（调音大师）";
CM_ SG_ 854 HUTMSubPositionEQ30HzSet "重低音方位30Hz频段设置（调音大师）";
CM_ SG_ 854 HUTMTransEnd "调音大师参数发送完成标识";
CM_ SG_ 854 HUVOLSpeedLevChangeSET "音量随速调节功能设置（新）";
CM_ BO_ 868 " ";
CM_ SG_ 868 CdcEpbSetSwt_1 "CDC电子手刹开关设置1";
BA_DEF_ SG_ "GenSigStartValue" INT 0 0;
BA_DEF_ SG_ "GenSigInvalidValue" CHAR;
BA_DEF_ SG_ "GenSigCycleTime" INT 0 0;
BA_DEF_ SG_ "GenSigSendType" ENUM,"Cyclic\"","\"OnWrite\"","\"OnWriteWithRepetition\"","\"OnChange\"","\"OnChangeWithRepetition\"","\"IfActive\"","\"IfActiveWithRepetition\"","\"NoSigSendType\"","\"NotUsed\"","\"NotUsed\"","\"NotUsed\"","\"NotUsed\"","\"NotUsed";
BA_DEF_ BO_ "GenMsgSendType" ENUM,"Cyclic\"","\"Event\"","\"Direct\"","\"NotUsed\"","\"NotUsed\"","\"Cyclic\"","\"NotUsed\"","\"IfActive\"","\"NoMsgSendType\"","\"NotUsed";
BA_DEF_ BO_ "GenMsgCycleTime" INT 0 65535;
BA_DEF_ BO_ "VFrameFormat" ENUM,"StandardCAN\"","\"ExtendedCAN\"","\"reserved\"","\"reserved\"","\"reserved\"","\"reserved\"","\"reserved\"","\"reserved\"","\"reserved\"","\"reserved\"","\"reserved\"","\"reserved\"","\"reserved\"","\"reserved\"","\"StandardCAN_FD\"","\"ExtendedCAN_FD";
BA_DEF_ SG_ "SystemSignalLongSymbol" CHAR;
BA_ "GenMsgCycleTime" BO_ 722 100;
BA_ "GenMsgSendType" BO_ 722 0;
BA_ "VFrameFormat" BO_ 722 14;
BA_ "GenMsgCycleTime" BO_ 753 50;
BA_ "GenMsgSendType" BO_ 753 0;
BA_ "VFrameFormat" BO_ 753 14;
BA_ "GenMsgCycleTime" BO_ 759 1000;
BA_ "GenMsgSendType" BO_ 759 0;
BA_ "VFrameFormat" BO_ 759 14;
BA_ "GenMsgCycleTime" BO_ 760 1000;
BA_ "GenMsgSendType" BO_ 760 0;
BA_ "VFrameFormat" BO_ 760 14;
BA_ "GenMsgCycleTime" BO_ 774 100;
BA_ "GenMsgSendType" BO_ 774 0;
BA_ "VFrameFormat" BO_ 774 14;
BA_ "GenMsgCycleTime" BO_ 779 100;
BA_ "GenMsgSendType" BO_ 779 0;
BA_ "VFrameFormat" BO_ 779 14;
BA_ "GenMsgCycleTime" BO_ 784 100;
BA_ "GenMsgSendType" BO_ 784 0;
BA_ "VFrameFormat" BO_ 784 14;
BA_ "GenMsgCycleTime" BO_ 800 100;
BA_ "GenMsgSendType" BO_ 800 0;
BA_ "VFrameFormat" BO_ 800 14;
BA_ "GenMsgCycleTime" BO_ 802 100;
BA_ "GenMsgSendType" BO_ 802 0;
BA_ "VFrameFormat" BO_ 802 14;
BA_ "GenMsgCycleTime" BO_ 821 100;
BA_ "GenMsgSendType" BO_ 821 0;
BA_ "VFrameFormat" BO_ 821 14;
BA_ "GenMsgCycleTime" BO_ 822 100;
BA_ "GenMsgSendType" BO_ 822 0;
BA_ "VFrameFormat" BO_ 822 14;
BA_ "GenMsgCycleTime" BO_ 854 100;
BA_ "GenMsgSendType" BO_ 854 0;
BA_ "VFrameFormat" BO_ 854 14;
BA_ "GenMsgCycleTime" BO_ 868 100;
BA_ "GenMsgSendType" BO_ 868 0;
BA_ "VFrameFormat" BO_ 868 14;
BA_ "GenSigCycleTime" SG_ 722 AcRemStartSts 100;
BA_ "GenSigSendType" SG_ 722 AcRemStartSts 0;
BA_ "GenSigStartValue" SG_ 722 AcRemStartSts 0;
BA_ "GenSigInvalidValue" SG_ 722 AcRemStartSts "NA";
BA_ "GenSigCycleTime" SG_ 722 CDC_CRCCheck_2D2 100;
BA_ "GenSigSendType" SG_ 722 CDC_CRCCheck_2D2 0;
BA_ "GenSigStartValue" SG_ 722 CDC_CRCCheck_2D2 0;
BA_ "GenSigInvalidValue" SG_ 722 CDC_CRCCheck_2D2 "NA";
BA_ "GenSigCycleTime" SG_ 722 CDC_RollingCounter_2D2 100;
BA_ "GenSigSendType" SG_ 722 CDC_RollingCounter_2D2 0;
BA_ "GenSigStartValue" SG_ 722 CDC_RollingCounter_2D2 0;
BA_ "GenSigInvalidValue" SG_ 722 CDC_RollingCounter_2D2 0;
BA_ "GenSigCycleTime" SG_ 722 CdcAcChrgILimSet 100;
BA_ "GenSigSendType" SG_ 722 CdcAcChrgILimSet 0;
BA_ "GenSigStartValue" SG_ 722 CdcAcChrgILimSet 0;
BA_ "GenSigInvalidValue" SG_ 722 CdcAcChrgILimSet 0;
BA_ "GenSigCycleTime" SG_ 722 CdcAntiRustFctSet 100;
BA_ "GenSigSendType" SG_ 722 CdcAntiRustFctSet 0;
BA_ "GenSigStartValue" SG_ 722 CdcAntiRustFctSet 0;
BA_ "GenSigInvalidValue" SG_ 722 CdcAntiRustFctSet 0;
BA_ "GenSigCycleTime" SG_ 722 CdcAqsOpenSet 100;
BA_ "GenSigSendType" SG_ 722 CdcAqsOpenSet 0;
BA_ "GenSigStartValue" SG_ 722 CdcAqsOpenSet 0;
BA_ "GenSigInvalidValue" SG_ 722 CdcAqsOpenSet 0;
BA_ "GenSigCycleTime" SG_ 722 CdcAutoApplyFctSet 100;
BA_ "GenSigSendType" SG_ 722 CdcAutoApplyFctSet 0;
BA_ "GenSigStartValue" SG_ 722 CdcAutoApplyFctSet 0;
BA_ "GenSigInvalidValue" SG_ 722 CdcAutoApplyFctSet 0;
BA_ "GenSigCycleTime" SG_ 722 CdcAutoDefrstDefogStsReq 100;
BA_ "GenSigSendType" SG_ 722 CdcAutoDefrstDefogStsReq 0;
BA_ "GenSigStartValue" SG_ 722 CdcAutoDefrstDefogStsReq 0;
BA_ "GenSigInvalidValue" SG_ 722 CdcAutoDefrstDefogStsReq 0;
BA_ "GenSigCycleTime" SG_ 722 CdcAutoWindLongPressSet 100;
BA_ "GenSigSendType" SG_ 722 CdcAutoWindLongPressSet 0;
BA_ "GenSigStartValue" SG_ 722 CdcAutoWindLongPressSet 0;
BA_ "GenSigInvalidValue" SG_ 722 CdcAutoWindLongPressSet 0;
BA_ "GenSigCycleTime" SG_ 722 CdcAutoWindUnlockSet 100;
BA_ "GenSigSendType" SG_ 722 CdcAutoWindUnlockSet 0;
BA_ "GenSigStartValue" SG_ 722 CdcAutoWindUnlockSet 0;
BA_ "GenSigInvalidValue" SG_ 722 CdcAutoWindUnlockSet 0;
BA_ "GenSigCycleTime" SG_ 722 CdcAVHFctSet 100;
BA_ "GenSigSendType" SG_ 722 CdcAVHFctSet 0;
BA_ "GenSigStartValue" SG_ 722 CdcAVHFctSet 0;
BA_ "GenSigInvalidValue" SG_ 722 CdcAVHFctSet 0;
BA_ "GenSigCycleTime" SG_ 722 CdcBacktWindLvlSetReq 100;
BA_ "GenSigSendType" SG_ 722 CdcBacktWindLvlSetReq 0;
BA_ "GenSigStartValue" SG_ 722 CdcBacktWindLvlSetReq 0;
BA_ "GenSigInvalidValue" SG_ 722 CdcBacktWindLvlSetReq 0;
BA_ "GenSigCycleTime" SG_ 722 CdcBattPlsHeatgSet 100;
BA_ "GenSigSendType" SG_ 722 CdcBattPlsHeatgSet 0;
BA_ "GenSigStartValue" SG_ 722 CdcBattPlsHeatgSet 0;
BA_ "GenSigInvalidValue" SG_ 722 CdcBattPlsHeatgSet 0;
BA_ "GenSigCycleTime" SG_ 722 CdcBDWFctSet 100;
BA_ "GenSigSendType" SG_ 722 CdcBDWFctSet 0;
BA_ "GenSigStartValue" SG_ 722 CdcBDWFctSet 0;
BA_ "GenSigInvalidValue" SG_ 722 CdcBDWFctSet 0;
BA_ "GenSigCycleTime" SG_ 722 CdcBrkPedlModSet 100;
BA_ "GenSigSendType" SG_ 722 CdcBrkPedlModSet 0;
BA_ "GenSigStartValue" SG_ 722 CdcBrkPedlModSet 0;
BA_ "GenSigInvalidValue" SG_ 722 CdcBrkPedlModSet "LastValue";
BA_ "GenSigCycleTime" SG_ 722 CdcCycModSet 100;
BA_ "GenSigSendType" SG_ 722 CdcCycModSet 0;
BA_ "GenSigStartValue" SG_ 722 CdcCycModSet 0;
BA_ "GenSigInvalidValue" SG_ 722 CdcCycModSet 0;
BA_ "GenSigCycleTime" SG_ 722 CdcDrvrTSet 100;
BA_ "GenSigSendType" SG_ 722 CdcDrvrTSet 0;
BA_ "GenSigStartValue" SG_ 722 CdcDrvrTSet 0;
BA_ "GenSigInvalidValue" SG_ 722 CdcDrvrTSet 0;
BA_ "GenSigCycleTime" SG_ 722 CdcEpbSwtSet 100;
BA_ "GenSigSendType" SG_ 722 CdcEpbSwtSet 0;
BA_ "GenSigStartValue" SG_ 722 CdcEpbSwtSet 0;
BA_ "GenSigInvalidValue" SG_ 722 CdcEpbSwtSet 0;
BA_ "GenSigCycleTime" SG_ 722 CdcEspFctSet 100;
BA_ "GenSigSendType" SG_ 722 CdcEspFctSet 0;
BA_ "GenSigStartValue" SG_ 722 CdcEspFctSet 0;
BA_ "GenSigInvalidValue" SG_ 722 CdcEspFctSet 0;
BA_ "GenSigCycleTime" SG_ 722 CdcFrntAutModOpenSet 100;
BA_ "GenSigSendType" SG_ 722 CdcFrntAutModOpenSet 0;
BA_ "GenSigStartValue" SG_ 722 CdcFrntAutModOpenSet 0;
BA_ "GenSigInvalidValue" SG_ 722 CdcFrntAutModOpenSet 0;
BA_ "GenSigCycleTime" SG_ 722 CdcFrntBlowModSet 100;
BA_ "GenSigSendType" SG_ 722 CdcFrntBlowModSet 0;
BA_ "GenSigStartValue" SG_ 722 CdcFrntBlowModSet 0;
BA_ "GenSigInvalidValue" SG_ 722 CdcFrntBlowModSet 0;
BA_ "GenSigCycleTime" SG_ 722 CdcFrntDefrosterSet 100;
BA_ "GenSigSendType" SG_ 722 CdcFrntDefrosterSet 0;
BA_ "GenSigStartValue" SG_ 722 CdcFrntDefrosterSet 0;
BA_ "GenSigInvalidValue" SG_ 722 CdcFrntDefrosterSet 0;
BA_ "GenSigCycleTime" SG_ 722 CdcFrntWindLvlSet 100;
BA_ "GenSigSendType" SG_ 722 CdcFrntWindLvlSet 0;
BA_ "GenSigStartValue" SG_ 722 CdcFrntWindLvlSet 0;
BA_ "GenSigInvalidValue" SG_ 722 CdcFrntWindLvlSet 0;
BA_ "GenSigCycleTime" SG_ 722 CdcFrontAcOffSet 100;
BA_ "GenSigSendType" SG_ 722 CdcFrontAcOffSet 0;
BA_ "GenSigStartValue" SG_ 722 CdcFrontAcOffSet 0;
BA_ "GenSigInvalidValue" SG_ 722 CdcFrontAcOffSet 0;
BA_ "GenSigCycleTime" SG_ 722 CdcHDCFctSet 100;
BA_ "GenSigSendType" SG_ 722 CdcHDCFctSet 0;
BA_ "GenSigStartValue" SG_ 722 CdcHDCFctSet 0;
BA_ "GenSigInvalidValue" SG_ 722 CdcHDCFctSet 0;
BA_ "GenSigCycleTime" SG_ 722 CdcHotColdModStReq 100;
BA_ "GenSigSendType" SG_ 722 CdcHotColdModStReq 0;
BA_ "GenSigStartValue" SG_ 722 CdcHotColdModStReq 0;
BA_ "GenSigInvalidValue" SG_ 722 CdcHotColdModStReq 0;
BA_ "GenSigCycleTime" SG_ 722 CdcIBCUDrvModSet 100;
BA_ "GenSigSendType" SG_ 722 CdcIBCUDrvModSet 0;
BA_ "GenSigStartValue" SG_ 722 CdcIBCUDrvModSet 0;
BA_ "GenSigInvalidValue" SG_ 722 CdcIBCUDrvModSet 0;
BA_ "GenSigCycleTime" SG_ 722 CdcORCAFctSet 100;
BA_ "GenSigSendType" SG_ 722 CdcORCAFctSet 0;
BA_ "GenSigStartValue" SG_ 722 CdcORCAFctSet 0;
BA_ "GenSigInvalidValue" SG_ 722 CdcORCAFctSet 0;
BA_ "GenSigCycleTime" SG_ 722 CdcPassTSet 100;
BA_ "GenSigSendType" SG_ 722 CdcPassTSet 0;
BA_ "GenSigStartValue" SG_ 722 CdcPassTSet 0;
BA_ "GenSigInvalidValue" SG_ 722 CdcPassTSet 0;
BA_ "GenSigCycleTime" SG_ 722 CdcPlasmaOpenSet 100;
BA_ "GenSigSendType" SG_ 722 CdcPlasmaOpenSet 0;
BA_ "GenSigStartValue" SG_ 722 CdcPlasmaOpenSet 0;
BA_ "GenSigInvalidValue" SG_ 722 CdcPlasmaOpenSet 0;
BA_ "GenSigCycleTime" SG_ 722 CdcSteerModSet 100;
BA_ "GenSigSendType" SG_ 722 CdcSteerModSet 0;
BA_ "GenSigStartValue" SG_ 722 CdcSteerModSet 0;
BA_ "GenSigInvalidValue" SG_ 722 CdcSteerModSet 0;
BA_ "GenSigCycleTime" SG_ 722 CdcTotMilg 100;
BA_ "GenSigSendType" SG_ 722 CdcTotMilg 0;
BA_ "GenSigStartValue" SG_ 722 CdcTotMilg 0;
BA_ "GenSigInvalidValue" SG_ 722 CdcTotMilg "LastValue";
BA_ "GenSigCycleTime" SG_ 722 CdcVehEgyCnseSelect 100;
BA_ "GenSigSendType" SG_ 722 CdcVehEgyCnseSelect 0;
BA_ "GenSigStartValue" SG_ 722 CdcVehEgyCnseSelect 0;
BA_ "GenSigInvalidValue" SG_ 722 CdcVehEgyCnseSelect 0;
BA_ "GenSigCycleTime" SG_ 722 CdcVentnOnSet 100;
BA_ "GenSigSendType" SG_ 722 CdcVentnOnSet 0;
BA_ "GenSigStartValue" SG_ 722 CdcVentnOnSet 0;
BA_ "GenSigInvalidValue" SG_ 722 CdcVentnOnSet 0;
BA_ "GenSigCycleTime" SG_ 722 CdcWorkSpaceSet 100;
BA_ "GenSigSendType" SG_ 722 CdcWorkSpaceSet 0;
BA_ "GenSigStartValue" SG_ 722 CdcWorkSpaceSet 0;
BA_ "GenSigInvalidValue" SG_ 722 CdcWorkSpaceSet 0;
BA_ "GenSigCycleTime" SG_ 722 CST_OFF_Switch 100;
BA_ "GenSigSendType" SG_ 722 CST_OFF_Switch 0;
BA_ "GenSigStartValue" SG_ 722 CST_OFF_Switch 0;
BA_ "GenSigInvalidValue" SG_ 722 CST_OFF_Switch 0;
BA_ "GenSigCycleTime" SG_ 722 HU_ACRearFanAdjustValueReq 100;
BA_ "GenSigSendType" SG_ 722 HU_ACRearFanAdjustValueReq 0;
BA_ "GenSigStartValue" SG_ 722 HU_ACRearFanAdjustValueReq 0;
BA_ "GenSigInvalidValue" SG_ 722 HU_ACRearFanAdjustValueReq 0;
BA_ "GenSigCycleTime" SG_ 722 HU_ACRearModeAdjustReq 100;
BA_ "GenSigSendType" SG_ 722 HU_ACRearModeAdjustReq 0;
BA_ "GenSigStartValue" SG_ 722 HU_ACRearModeAdjustReq 0;
BA_ "GenSigInvalidValue" SG_ 722 HU_ACRearModeAdjustReq 0;
BA_ "GenSigCycleTime" SG_ 722 HU_ACRearTempAdjustValueReq2 100;
BA_ "GenSigSendType" SG_ 722 HU_ACRearTempAdjustValueReq2 0;
BA_ "GenSigStartValue" SG_ 722 HU_ACRearTempAdjustValueReq2 0;
BA_ "GenSigInvalidValue" SG_ 722 HU_ACRearTempAdjustValueReq2 "/";
BA_ "GenSigCycleTime" SG_ 722 HU_AutowindSet3 100;
BA_ "GenSigSendType" SG_ 722 HU_AutowindSet3 0;
BA_ "GenSigStartValue" SG_ 722 HU_AutowindSet3 0;
BA_ "GenSigInvalidValue" SG_ 722 HU_AutowindSet3 "/";
BA_ "GenSigCycleTime" SG_ 722 HU_MaxACReq 100;
BA_ "GenSigSendType" SG_ 722 HU_MaxACReq 0;
BA_ "GenSigStartValue" SG_ 722 HU_MaxACReq 0;
BA_ "GenSigInvalidValue" SG_ 722 HU_MaxACReq "NA";
BA_ "GenSigCycleTime" SG_ 722 HU_MaxDefReq 100;
BA_ "GenSigSendType" SG_ 722 HU_MaxDefReq 0;
BA_ "GenSigStartValue" SG_ 722 HU_MaxDefReq 0;
BA_ "GenSigInvalidValue" SG_ 722 HU_MaxDefReq "NA";
BA_ "GenSigCycleTime" SG_ 722 HU_MaxHeatReq 100;
BA_ "GenSigSendType" SG_ 722 HU_MaxHeatReq 0;
BA_ "GenSigStartValue" SG_ 722 HU_MaxHeatReq 0;
BA_ "GenSigInvalidValue" SG_ 722 HU_MaxHeatReq "NA";
BA_ "GenSigCycleTime" SG_ 722 HU_RearACOfffReq 100;
BA_ "GenSigSendType" SG_ 722 HU_RearACOfffReq 0;
BA_ "GenSigStartValue" SG_ 722 HU_RearACOfffReq 0;
BA_ "GenSigInvalidValue" SG_ 722 HU_RearACOfffReq 0;
BA_ "GenSigCycleTime" SG_ 722 HU_RearAUTOACOnReq 100;
BA_ "GenSigSendType" SG_ 722 HU_RearAUTOACOnReq 0;
BA_ "GenSigStartValue" SG_ 722 HU_RearAUTOACOnReq 0;
BA_ "GenSigInvalidValue" SG_ 722 HU_RearAUTOACOnReq 0;
BA_ "GenSigCycleTime" SG_ 722 HU_RefreshModeEnable 100;
BA_ "GenSigSendType" SG_ 722 HU_RefreshModeEnable 0;
BA_ "GenSigStartValue" SG_ 722 HU_RefreshModeEnable 0;
BA_ "GenSigInvalidValue" SG_ 722 HU_RefreshModeEnable 0;
BA_ "GenSigCycleTime" SG_ 722 HU_Request_AFUchannel 100;
BA_ "GenSigSendType" SG_ 722 HU_Request_AFUchannel 0;
BA_ "GenSigStartValue" SG_ 722 HU_Request_AFUchannel 0;
BA_ "GenSigInvalidValue" SG_ 722 HU_Request_AFUchannel 0;
BA_ "GenSigCycleTime" SG_ 722 HU_Request_AFUContentleve 100;
BA_ "GenSigSendType" SG_ 722 HU_Request_AFUContentleve 0;
BA_ "GenSigStartValue" SG_ 722 HU_Request_AFUContentleve 0;
BA_ "GenSigInvalidValue" SG_ 722 HU_Request_AFUContentleve 0;
BA_ "GenSigCycleTime" SG_ 722 HU_Request_AFUSt 100;
BA_ "GenSigSendType" SG_ 722 HU_Request_AFUSt 0;
BA_ "GenSigStartValue" SG_ 722 HU_Request_AFUSt 0;
BA_ "GenSigInvalidValue" SG_ 722 HU_Request_AFUSt 0;
BA_ "GenSigCycleTime" SG_ 722 HU_RollerbenchSetStaus 100;
BA_ "GenSigSendType" SG_ 722 HU_RollerbenchSetStaus 0;
BA_ "GenSigStartValue" SG_ 722 HU_RollerbenchSetStaus 0;
BA_ "GenSigInvalidValue" SG_ 722 HU_RollerbenchSetStaus "NA";
BA_ "GenSigCycleTime" SG_ 722 HU_VentilationSetAfternoon 100;
BA_ "GenSigSendType" SG_ 722 HU_VentilationSetAfternoon 0;
BA_ "GenSigStartValue" SG_ 722 HU_VentilationSetAfternoon 0;
BA_ "GenSigInvalidValue" SG_ 722 HU_VentilationSetAfternoon 0;
BA_ "GenSigCycleTime" SG_ 722 HU_VentilationSetEvening 100;
BA_ "GenSigSendType" SG_ 722 HU_VentilationSetEvening 0;
BA_ "GenSigStartValue" SG_ 722 HU_VentilationSetEvening 0;
BA_ "GenSigInvalidValue" SG_ 722 HU_VentilationSetEvening 0;
BA_ "GenSigCycleTime" SG_ 722 HU_VentilationSetMorning 100;
BA_ "GenSigSendType" SG_ 722 HU_VentilationSetMorning 0;
BA_ "GenSigStartValue" SG_ 722 HU_VentilationSetMorning 0;
BA_ "GenSigInvalidValue" SG_ 722 HU_VentilationSetMorning 0;
BA_ "GenSigCycleTime" SG_ 722 HUAcEgySaveModReq 100;
BA_ "GenSigSendType" SG_ 722 HUAcEgySaveModReq 0;
BA_ "GenSigStartValue" SG_ 722 HUAcEgySaveModReq 0;
BA_ "GenSigInvalidValue" SG_ 722 HUAcEgySaveModReq "NA";
BA_ "GenSigCycleTime" SG_ 722 HUAutoAirCleanReq 100;
BA_ "GenSigSendType" SG_ 722 HUAutoAirCleanReq 0;
BA_ "GenSigStartValue" SG_ 722 HUAutoAirCleanReq 0;
BA_ "GenSigInvalidValue" SG_ 722 HUAutoAirCleanReq "NA";
BA_ "GenSigCycleTime" SG_ 722 HUBatPulseHeatSwitchReq 100;
BA_ "GenSigSendType" SG_ 722 HUBatPulseHeatSwitchReq 0;
BA_ "GenSigStartValue" SG_ 722 HUBatPulseHeatSwitchReq 0;
BA_ "GenSigInvalidValue" SG_ 722 HUBatPulseHeatSwitchReq "NA";
BA_ "GenSigCycleTime" SG_ 722 HUMotLockHeatSwitchReq 100;
BA_ "GenSigSendType" SG_ 722 HUMotLockHeatSwitchReq 0;
BA_ "GenSigStartValue" SG_ 722 HUMotLockHeatSwitchReq 0;
BA_ "GenSigInvalidValue" SG_ 722 HUMotLockHeatSwitchReq "NA";
BA_ "GenSigCycleTime" SG_ 722 HUSngPrsnModReq 100;
BA_ "GenSigSendType" SG_ 722 HUSngPrsnModReq 0;
BA_ "GenSigStartValue" SG_ 722 HUSngPrsnModReq 0;
BA_ "GenSigInvalidValue" SG_ 722 HUSngPrsnModReq "NA";
BA_ "GenSigCycleTime" SG_ 722 VIUDrvModSet 100;
BA_ "GenSigSendType" SG_ 722 VIUDrvModSet 0;
BA_ "GenSigStartValue" SG_ 722 VIUDrvModSet 0;
BA_ "GenSigInvalidValue" SG_ 722 VIUDrvModSet "NA";
BA_ "GenSigCycleTime" SG_ 753 RCM_RLTuLiSt 50;
BA_ "GenSigSendType" SG_ 753 RCM_RLTuLiSt 0;
BA_ "GenSigStartValue" SG_ 753 RCM_RLTuLiSt 0;
BA_ "GenSigInvalidValue" SG_ 753 RCM_RLTuLiSt 0;
BA_ "GenSigCycleTime" SG_ 753 RCM_RRTuLiSt 50;
BA_ "GenSigSendType" SG_ 753 RCM_RRTuLiSt 0;
BA_ "GenSigStartValue" SG_ 753 RCM_RRTuLiSt 0;
BA_ "GenSigInvalidValue" SG_ 753 RCM_RRTuLiSt 0;
BA_ "GenSigCycleTime" SG_ 759 TboxLocalTiDate 1000;
BA_ "GenSigSendType" SG_ 759 TboxLocalTiDate 0;
BA_ "GenSigStartValue" SG_ 759 TboxLocalTiDate 0;
BA_ "GenSigInvalidValue" SG_ 759 TboxLocalTiDate "NA";
BA_ "GenSigCycleTime" SG_ 759 TboxLocalTiHr 1000;
BA_ "GenSigSendType" SG_ 759 TboxLocalTiHr 0;
BA_ "GenSigStartValue" SG_ 759 TboxLocalTiHr 0;
BA_ "GenSigInvalidValue" SG_ 759 TboxLocalTiHr "NA";
BA_ "GenSigCycleTime" SG_ 759 TboxLocalTiMins 1000;
BA_ "GenSigSendType" SG_ 759 TboxLocalTiMins 0;
BA_ "GenSigStartValue" SG_ 759 TboxLocalTiMins 0;
BA_ "GenSigInvalidValue" SG_ 759 TboxLocalTiMins "NA";
BA_ "GenSigCycleTime" SG_ 759 TboxLocalTiMth 1000;
BA_ "GenSigSendType" SG_ 759 TboxLocalTiMth 0;
BA_ "GenSigStartValue" SG_ 759 TboxLocalTiMth 0;
BA_ "GenSigInvalidValue" SG_ 759 TboxLocalTiMth "NA";
BA_ "GenSigCycleTime" SG_ 759 TboxLocalTiSec 1000;
BA_ "GenSigSendType" SG_ 759 TboxLocalTiSec 0;
BA_ "GenSigStartValue" SG_ 759 TboxLocalTiSec 0;
BA_ "GenSigInvalidValue" SG_ 759 TboxLocalTiSec "NA";
BA_ "GenSigCycleTime" SG_ 759 TboxLocalTiVld 1000;
BA_ "GenSigSendType" SG_ 759 TboxLocalTiVld 0;
BA_ "GenSigStartValue" SG_ 759 TboxLocalTiVld 0;
BA_ "GenSigInvalidValue" SG_ 759 TboxLocalTiVld "NA";
BA_ "GenSigCycleTime" SG_ 759 TboxLocalTiYear 1000;
BA_ "GenSigSendType" SG_ 759 TboxLocalTiYear 0;
BA_ "GenSigStartValue" SG_ 759 TboxLocalTiYear 0;
BA_ "GenSigInvalidValue" SG_ 759 TboxLocalTiYear "NA";
BA_ "GenSigCycleTime" SG_ 760 Tbox_GPSLocalTiDate 1000;
BA_ "GenSigSendType" SG_ 760 Tbox_GPSLocalTiDate 0;
BA_ "GenSigStartValue" SG_ 760 Tbox_GPSLocalTiDate 0;
BA_ "GenSigInvalidValue" SG_ 760 Tbox_GPSLocalTiDate "NA";
BA_ "GenSigCycleTime" SG_ 760 Tbox_GPSLocalTiHr 1000;
BA_ "GenSigSendType" SG_ 760 Tbox_GPSLocalTiHr 0;
BA_ "GenSigStartValue" SG_ 760 Tbox_GPSLocalTiHr 0;
BA_ "GenSigInvalidValue" SG_ 760 Tbox_GPSLocalTiHr "NA";
BA_ "GenSigCycleTime" SG_ 760 Tbox_GPSLocalTiMins 1000;
BA_ "GenSigSendType" SG_ 760 Tbox_GPSLocalTiMins 0;
BA_ "GenSigStartValue" SG_ 760 Tbox_GPSLocalTiMins 0;
BA_ "GenSigInvalidValue" SG_ 760 Tbox_GPSLocalTiMins "NA";
BA_ "GenSigCycleTime" SG_ 760 Tbox_GPSLocalTiMth 1000;
BA_ "GenSigSendType" SG_ 760 Tbox_GPSLocalTiMth 0;
BA_ "GenSigStartValue" SG_ 760 Tbox_GPSLocalTiMth 0;
BA_ "GenSigInvalidValue" SG_ 760 Tbox_GPSLocalTiMth "NA";
BA_ "GenSigCycleTime" SG_ 760 Tbox_GPSLocalTiSec 1000;
BA_ "GenSigSendType" SG_ 760 Tbox_GPSLocalTiSec 0;
BA_ "GenSigStartValue" SG_ 760 Tbox_GPSLocalTiSec 0;
BA_ "GenSigInvalidValue" SG_ 760 Tbox_GPSLocalTiSec "NA";
BA_ "GenSigCycleTime" SG_ 760 Tbox_GPSLocalTiVld 1000;
BA_ "GenSigSendType" SG_ 760 Tbox_GPSLocalTiVld 0;
BA_ "GenSigStartValue" SG_ 760 Tbox_GPSLocalTiVld 0;
BA_ "GenSigInvalidValue" SG_ 760 Tbox_GPSLocalTiVld "NA";
BA_ "GenSigCycleTime" SG_ 760 Tbox_GPSLocalTiYear 1000;
BA_ "GenSigSendType" SG_ 760 Tbox_GPSLocalTiYear 0;
BA_ "GenSigStartValue" SG_ 760 Tbox_GPSLocalTiYear 0;
BA_ "GenSigInvalidValue" SG_ 760 Tbox_GPSLocalTiYear "NA";
BA_ "GenSigCycleTime" SG_ 774 AC_ACOnOff 100;
BA_ "GenSigSendType" SG_ 774 AC_ACOnOff 0;
BA_ "GenSigStartValue" SG_ 774 AC_ACOnOff 0;
BA_ "GenSigInvalidValue" SG_ 774 AC_ACOnOff 0;
BA_ "GenSigCycleTime" SG_ 774 ITMSLiquidLevel 100;
BA_ "GenSigSendType" SG_ 774 ITMSLiquidLevel 0;
BA_ "GenSigStartValue" SG_ 774 ITMSLiquidLevel 0;
BA_ "GenSigInvalidValue" SG_ 774 ITMSLiquidLevel "/";
BA_ "GenSigCycleTime" SG_ 774 TmsComOutPtPre 100;
BA_ "GenSigSendType" SG_ 774 TmsComOutPtPre 0;
BA_ "GenSigStartValue" SG_ 774 TmsComOutPtPre 0;
BA_ "GenSigInvalidValue" SG_ 774 TmsComOutPtPre 0;
BA_ "GenSigCycleTime" SG_ 779 CDC_CRCCheck_30B 100;
BA_ "GenSigSendType" SG_ 779 CDC_CRCCheck_30B 0;
BA_ "GenSigStartValue" SG_ 779 CDC_CRCCheck_30B 0;
BA_ "GenSigInvalidValue" SG_ 779 CDC_CRCCheck_30B "NA";
BA_ "GenSigCycleTime" SG_ 779 CDC_RollingCounter_30B 100;
BA_ "GenSigSendType" SG_ 779 CDC_RollingCounter_30B 0;
BA_ "GenSigStartValue" SG_ 779 CDC_RollingCounter_30B 0;
BA_ "GenSigInvalidValue" SG_ 779 CDC_RollingCounter_30B 0;
BA_ "GenSigCycleTime" SG_ 779 CdcIPScreenLiOnSts 100;
BA_ "GenSigSendType" SG_ 779 CdcIPScreenLiOnSts 0;
BA_ "GenSigStartValue" SG_ 779 CdcIPScreenLiOnSts 0;
BA_ "GenSigInvalidValue" SG_ 779 CdcIPScreenLiOnSts 0;
BA_ "GenSigCycleTime" SG_ 779 IP_DISFail 100;
BA_ "GenSigSendType" SG_ 779 IP_DISFail 0;
BA_ "GenSigStartValue" SG_ 779 IP_DISFail 0;
BA_ "GenSigInvalidValue" SG_ 779 IP_DISFail 0;
BA_ "GenSigCycleTime" SG_ 779 IP_juADASshowinfa 100;
BA_ "GenSigSendType" SG_ 779 IP_juADASshowinfa 0;
BA_ "GenSigStartValue" SG_ 779 IP_juADASshowinfa 0;
BA_ "GenSigInvalidValue" SG_ 779 IP_juADASshowinfa 0;
BA_ "GenSigCycleTime" SG_ 779 IP_juADASshowoutfa 100;
BA_ "GenSigSendType" SG_ 779 IP_juADASshowoutfa 0;
BA_ "GenSigStartValue" SG_ 779 IP_juADASshowoutfa 0;
BA_ "GenSigInvalidValue" SG_ 779 IP_juADASshowoutfa 0;
BA_ "GenSigCycleTime" SG_ 779 IP_juADAStsE2Efaout 100;
BA_ "GenSigSendType" SG_ 779 IP_juADAStsE2Efaout 0;
BA_ "GenSigStartValue" SG_ 779 IP_juADAStsE2Efaout 0;
BA_ "GenSigInvalidValue" SG_ 779 IP_juADAStsE2Efaout 0;
BA_ "GenSigCycleTime" SG_ 779 IP_QDashACCFail 100;
BA_ "GenSigSendType" SG_ 779 IP_QDashACCFail 0;
BA_ "GenSigStartValue" SG_ 779 IP_QDashACCFail 0;
BA_ "GenSigInvalidValue" SG_ 779 IP_QDashACCFail 0;
BA_ "GenSigCycleTime" SG_ 779 AD_EDCCrtSts 100;
BA_ "GenSigSendType" SG_ 779 AD_EDCCrtSts 0;
BA_ "GenSigStartValue" SG_ 779 AD_EDCCrtSts 0;
BA_ "GenSigInvalidValue" SG_ 779 AD_EDCCrtSts 0;
BA_ "GenSigCycleTime" SG_ 779 AD_EDCCurrenttemp 100;
BA_ "GenSigSendType" SG_ 779 AD_EDCCurrenttemp 0;
BA_ "GenSigStartValue" SG_ 779 AD_EDCCurrenttemp 0;
BA_ "GenSigInvalidValue" SG_ 779 AD_EDCCurrenttemp "NA";
BA_ "GenSigCycleTime" SG_ 779 TboxDoorLockRemCtrlReq 100;
BA_ "GenSigSendType" SG_ 779 TboxDoorLockRemCtrlReq 0;
BA_ "GenSigStartValue" SG_ 779 TboxDoorLockRemCtrlReq 0;
BA_ "GenSigInvalidValue" SG_ 779 TboxDoorLockRemCtrlReq 0;
BA_ "GenSigCycleTime" SG_ 784 AMP_Err_Detect 100;
BA_ "GenSigSendType" SG_ 784 AMP_Err_Detect 0;
BA_ "GenSigStartValue" SG_ 784 AMP_Err_Detect 0;
BA_ "GenSigInvalidValue" SG_ 784 AMP_Err_Detect 0;
BA_ "GenSigCycleTime" SG_ 784 AMP_FLHighSpeakerDelaySETStatus 100;
BA_ "GenSigSendType" SG_ 784 AMP_FLHighSpeakerDelaySETStatus 0;
BA_ "GenSigStartValue" SG_ 784 AMP_FLHighSpeakerDelaySETStatus 0;
BA_ "GenSigInvalidValue" SG_ 784 AMP_FLHighSpeakerDelaySETStatus 0;
BA_ "GenSigCycleTime" SG_ 784 AMP_FLHighSpeakerVolSETStatus 100;
BA_ "GenSigSendType" SG_ 784 AMP_FLHighSpeakerVolSETStatus 0;
BA_ "GenSigStartValue" SG_ 784 AMP_FLHighSpeakerVolSETStatus 31;
BA_ "GenSigInvalidValue" SG_ 784 AMP_FLHighSpeakerVolSETStatus 31;
BA_ "GenSigCycleTime" SG_ 784 AMP_FLMidSpeakerDelaySETStatus 100;
BA_ "GenSigSendType" SG_ 784 AMP_FLMidSpeakerDelaySETStatus 0;
BA_ "GenSigStartValue" SG_ 784 AMP_FLMidSpeakerDelaySETStatus 0;
BA_ "GenSigInvalidValue" SG_ 784 AMP_FLMidSpeakerDelaySETStatus 0;
BA_ "GenSigCycleTime" SG_ 784 AMP_FLMidSpeakerVolSETStatus 100;
BA_ "GenSigSendType" SG_ 784 AMP_FLMidSpeakerVolSETStatus 0;
BA_ "GenSigStartValue" SG_ 784 AMP_FLMidSpeakerVolSETStatus 31;
BA_ "GenSigInvalidValue" SG_ 784 AMP_FLMidSpeakerVolSETStatus 31;
BA_ "GenSigCycleTime" SG_ 784 AMP_FRHighSpeakerDelaySETStatus 100;
BA_ "GenSigSendType" SG_ 784 AMP_FRHighSpeakerDelaySETStatus 0;
BA_ "GenSigStartValue" SG_ 784 AMP_FRHighSpeakerDelaySETStatus 0;
BA_ "GenSigInvalidValue" SG_ 784 AMP_FRHighSpeakerDelaySETStatus 0;
BA_ "GenSigCycleTime" SG_ 784 AMP_FRHighSpeakerVolSETStatus 100;
BA_ "GenSigSendType" SG_ 784 AMP_FRHighSpeakerVolSETStatus 0;
BA_ "GenSigStartValue" SG_ 784 AMP_FRHighSpeakerVolSETStatus 31;
BA_ "GenSigInvalidValue" SG_ 784 AMP_FRHighSpeakerVolSETStatus 31;
BA_ "GenSigCycleTime" SG_ 784 AMP_FRMidSpeakerDelaySETStatus 100;
BA_ "GenSigSendType" SG_ 784 AMP_FRMidSpeakerDelaySETStatus 0;
BA_ "GenSigStartValue" SG_ 784 AMP_FRMidSpeakerDelaySETStatus 0;
BA_ "GenSigInvalidValue" SG_ 784 AMP_FRMidSpeakerDelaySETStatus 0;
BA_ "GenSigCycleTime" SG_ 784 AMP_FRMidSpeakerVolSETStatus 100;
BA_ "GenSigSendType" SG_ 784 AMP_FRMidSpeakerVolSETStatus 0;
BA_ "GenSigStartValue" SG_ 784 AMP_FRMidSpeakerVolSETStatus 31;
BA_ "GenSigInvalidValue" SG_ 784 AMP_FRMidSpeakerVolSETStatus 31;
BA_ "GenSigCycleTime" SG_ 784 AMP_Slot_Detect 100;
BA_ "GenSigSendType" SG_ 784 AMP_Slot_Detect 0;
BA_ "GenSigStartValue" SG_ 784 AMP_Slot_Detect 0;
BA_ "GenSigInvalidValue" SG_ 784 AMP_Slot_Detect 0;
BA_ "GenSigCycleTime" SG_ 784 AMP_SV_Detect 100;
BA_ "GenSigSendType" SG_ 784 AMP_SV_Detect 0;
BA_ "GenSigStartValue" SG_ 784 AMP_SV_Detect 0;
BA_ "GenSigInvalidValue" SG_ 784 AMP_SV_Detect 0;
BA_ "GenSigCycleTime" SG_ 784 AMP_AlarmVolSETStatus 100;
BA_ "GenSigSendType" SG_ 784 AMP_AlarmVolSETStatus 0;
BA_ "GenSigStartValue" SG_ 784 AMP_AlarmVolSETStatus 0;
BA_ "GenSigInvalidValue" SG_ 784 AMP_AlarmVolSETStatus 0;
BA_ "GenSigCycleTime" SG_ 784 AMP_AvasVolSETStatus 100;
BA_ "GenSigSendType" SG_ 784 AMP_AvasVolSETStatus 0;
BA_ "GenSigStartValue" SG_ 784 AMP_AvasVolSETStatus 0;
BA_ "GenSigInvalidValue" SG_ 784 AMP_AvasVolSETStatus 0;
BA_ "GenSigCycleTime" SG_ 784 AMP_CenterSpeakerDelaySETStatus 100;
BA_ "GenSigSendType" SG_ 784 AMP_CenterSpeakerDelaySETStatus 0;
BA_ "GenSigStartValue" SG_ 784 AMP_CenterSpeakerDelaySETStatus 0;
BA_ "GenSigInvalidValue" SG_ 784 AMP_CenterSpeakerDelaySETStatus 0;
BA_ "GenSigCycleTime" SG_ 784 AMP_CenterSpeakerVolSETStatus 100;
BA_ "GenSigSendType" SG_ 784 AMP_CenterSpeakerVolSETStatus 0;
BA_ "GenSigStartValue" SG_ 784 AMP_CenterSpeakerVolSETStatus 31;
BA_ "GenSigInvalidValue" SG_ 784 AMP_CenterSpeakerVolSETStatus 31;
BA_ "GenSigCycleTime" SG_ 784 AMP_CustomEffectSETStatus 100;
BA_ "GenSigSendType" SG_ 784 AMP_CustomEffectSETStatus 0;
BA_ "GenSigStartValue" SG_ 784 AMP_CustomEffectSETStatus 0;
BA_ "GenSigInvalidValue" SG_ 784 AMP_CustomEffectSETStatus 0;
BA_ "GenSigCycleTime" SG_ 784 AMP_CustomEQ125SET 100;
BA_ "GenSigSendType" SG_ 784 AMP_CustomEQ125SET 0;
BA_ "GenSigStartValue" SG_ 784 AMP_CustomEQ125SET 0;
BA_ "GenSigInvalidValue" SG_ 784 AMP_CustomEQ125SET 0;
BA_ "GenSigCycleTime" SG_ 784 AMP_CustomEQ16KSET 100;
BA_ "GenSigSendType" SG_ 784 AMP_CustomEQ16KSET 0;
BA_ "GenSigStartValue" SG_ 784 AMP_CustomEQ16KSET 0;
BA_ "GenSigInvalidValue" SG_ 784 AMP_CustomEQ16KSET 0;
BA_ "GenSigCycleTime" SG_ 784 AMP_CustomEQ1KSET 100;
BA_ "GenSigSendType" SG_ 784 AMP_CustomEQ1KSET 0;
BA_ "GenSigStartValue" SG_ 784 AMP_CustomEQ1KSET 0;
BA_ "GenSigInvalidValue" SG_ 784 AMP_CustomEQ1KSET 0;
BA_ "GenSigCycleTime" SG_ 784 AMP_CustomEQ250SET 100;
BA_ "GenSigSendType" SG_ 784 AMP_CustomEQ250SET 0;
BA_ "GenSigStartValue" SG_ 784 AMP_CustomEQ250SET 0;
BA_ "GenSigInvalidValue" SG_ 784 AMP_CustomEQ250SET 0;
BA_ "GenSigCycleTime" SG_ 784 AMP_CustomEQ2KSET 100;
BA_ "GenSigSendType" SG_ 784 AMP_CustomEQ2KSET 0;
BA_ "GenSigStartValue" SG_ 784 AMP_CustomEQ2KSET 0;
BA_ "GenSigInvalidValue" SG_ 784 AMP_CustomEQ2KSET 0;
BA_ "GenSigCycleTime" SG_ 784 AMP_CustomEQ4KSET 100;
BA_ "GenSigSendType" SG_ 784 AMP_CustomEQ4KSET 0;
BA_ "GenSigStartValue" SG_ 784 AMP_CustomEQ4KSET 0;
BA_ "GenSigInvalidValue" SG_ 784 AMP_CustomEQ4KSET 0;
BA_ "GenSigCycleTime" SG_ 784 AMP_CustomEQ500SET 100;
BA_ "GenSigSendType" SG_ 784 AMP_CustomEQ500SET 0;
BA_ "GenSigStartValue" SG_ 784 AMP_CustomEQ500SET 0;
BA_ "GenSigInvalidValue" SG_ 784 AMP_CustomEQ500SET 0;
BA_ "GenSigCycleTime" SG_ 784 AMP_CustomEQ62SET 100;
BA_ "GenSigSendType" SG_ 784 AMP_CustomEQ62SET 0;
BA_ "GenSigStartValue" SG_ 784 AMP_CustomEQ62SET 0;
BA_ "GenSigInvalidValue" SG_ 784 AMP_CustomEQ62SET 0;
BA_ "GenSigCycleTime" SG_ 784 AMP_CustomEQ8KSET 100;
BA_ "GenSigSendType" SG_ 784 AMP_CustomEQ8KSET 0;
BA_ "GenSigStartValue" SG_ 784 AMP_CustomEQ8KSET 0;
BA_ "GenSigInvalidValue" SG_ 784 AMP_CustomEQ8KSET 0;
BA_ "GenSigCycleTime" SG_ 784 AMP_FLLowSpeakerDelaySETStatus 100;
BA_ "GenSigSendType" SG_ 784 AMP_FLLowSpeakerDelaySETStatus 0;
BA_ "GenSigStartValue" SG_ 784 AMP_FLLowSpeakerDelaySETStatus 0;
BA_ "GenSigInvalidValue" SG_ 784 AMP_FLLowSpeakerDelaySETStatus 0;
BA_ "GenSigCycleTime" SG_ 784 AMP_FLLowSpeakerVolSETStatus 100;
BA_ "GenSigSendType" SG_ 784 AMP_FLLowSpeakerVolSETStatus 0;
BA_ "GenSigStartValue" SG_ 784 AMP_FLLowSpeakerVolSETStatus 31;
BA_ "GenSigInvalidValue" SG_ 784 AMP_FLLowSpeakerVolSETStatus 31;
BA_ "GenSigCycleTime" SG_ 784 AMP_FLMidHighSpeakerDelaySETStat 100;
BA_ "GenSigSendType" SG_ 784 AMP_FLMidHighSpeakerDelaySETStat 0;
BA_ "GenSigStartValue" SG_ 784 AMP_FLMidHighSpeakerDelaySETStat 0;
BA_ "GenSigInvalidValue" SG_ 784 AMP_FLMidHighSpeakerDelaySETStat 0;
BA_ "SystemSignalLongSymbol" SG_ 784 AMP_FLMidHighSpeakerDelaySETStat "AMP_FLMidHighSpeakerDelaySETStatus";
BA_ "GenSigCycleTime" SG_ 784 AMP_FLMidHighSpeakerVolSETStatus 100;
BA_ "GenSigSendType" SG_ 784 AMP_FLMidHighSpeakerVolSETStatus 0;
BA_ "GenSigStartValue" SG_ 784 AMP_FLMidHighSpeakerVolSETStatus 31;
BA_ "GenSigInvalidValue" SG_ 784 AMP_FLMidHighSpeakerVolSETStatus 31;
BA_ "GenSigCycleTime" SG_ 784 AMP_FLTopSpeakerDelaySETStatus 100;
BA_ "GenSigSendType" SG_ 784 AMP_FLTopSpeakerDelaySETStatus 0;
BA_ "GenSigStartValue" SG_ 784 AMP_FLTopSpeakerDelaySETStatus 0;
BA_ "GenSigInvalidValue" SG_ 784 AMP_FLTopSpeakerDelaySETStatus 0;
BA_ "GenSigCycleTime" SG_ 784 AMP_FLTopSpeakerVolSETStatus 100;
BA_ "GenSigSendType" SG_ 784 AMP_FLTopSpeakerVolSETStatus 0;
BA_ "GenSigStartValue" SG_ 784 AMP_FLTopSpeakerVolSETStatus 31;
BA_ "GenSigInvalidValue" SG_ 784 AMP_FLTopSpeakerVolSETStatus 31;
BA_ "GenSigCycleTime" SG_ 784 AMP_FRBalanceSETStatus 100;
BA_ "GenSigSendType" SG_ 784 AMP_FRBalanceSETStatus 0;
BA_ "GenSigStartValue" SG_ 784 AMP_FRBalanceSETStatus 0;
BA_ "GenSigInvalidValue" SG_ 784 AMP_FRBalanceSETStatus 0;
BA_ "GenSigCycleTime" SG_ 784 AMP_FRLowSpeakerDelaySETStatus 100;
BA_ "GenSigSendType" SG_ 784 AMP_FRLowSpeakerDelaySETStatus 0;
BA_ "GenSigStartValue" SG_ 784 AMP_FRLowSpeakerDelaySETStatus 0;
BA_ "GenSigInvalidValue" SG_ 784 AMP_FRLowSpeakerDelaySETStatus 0;
BA_ "GenSigCycleTime" SG_ 784 AMP_FRLowSpeakerVolSETStatus 100;
BA_ "GenSigSendType" SG_ 784 AMP_FRLowSpeakerVolSETStatus 0;
BA_ "GenSigStartValue" SG_ 784 AMP_FRLowSpeakerVolSETStatus 31;
BA_ "GenSigInvalidValue" SG_ 784 AMP_FRLowSpeakerVolSETStatus 31;
BA_ "GenSigCycleTime" SG_ 784 AMP_FRMidHighSpeakerDelaySET 100;
BA_ "GenSigSendType" SG_ 784 AMP_FRMidHighSpeakerDelaySET 0;
BA_ "GenSigStartValue" SG_ 784 AMP_FRMidHighSpeakerDelaySET 0;
BA_ "GenSigInvalidValue" SG_ 784 AMP_FRMidHighSpeakerDelaySET 0;
BA_ "GenSigCycleTime" SG_ 784 AMP_FRMidHighSpeakerVolSETStatus 100;
BA_ "GenSigSendType" SG_ 784 AMP_FRMidHighSpeakerVolSETStatus 0;
BA_ "GenSigStartValue" SG_ 784 AMP_FRMidHighSpeakerVolSETStatus 31;
BA_ "GenSigInvalidValue" SG_ 784 AMP_FRMidHighSpeakerVolSETStatus 31;
BA_ "GenSigCycleTime" SG_ 784 AMP_FRTopSpeakerDelaySETStatus 100;
BA_ "GenSigSendType" SG_ 784 AMP_FRTopSpeakerDelaySETStatus 0;
BA_ "GenSigStartValue" SG_ 784 AMP_FRTopSpeakerDelaySETStatus 0;
BA_ "GenSigInvalidValue" SG_ 784 AMP_FRTopSpeakerDelaySETStatus 0;
BA_ "GenSigCycleTime" SG_ 784 AMP_FRTopSpeakerVolSETStatus 100;
BA_ "GenSigSendType" SG_ 784 AMP_FRTopSpeakerVolSETStatus 0;
BA_ "GenSigStartValue" SG_ 784 AMP_FRTopSpeakerVolSETStatus 31;
BA_ "GenSigInvalidValue" SG_ 784 AMP_FRTopSpeakerVolSETStatus 31;
BA_ "GenSigCycleTime" SG_ 784 AMP_KTVMUTESETStatus 100;
BA_ "GenSigSendType" SG_ 784 AMP_KTVMUTESETStatus 0;
BA_ "GenSigStartValue" SG_ 784 AMP_KTVMUTESETStatus 0;
BA_ "GenSigInvalidValue" SG_ 784 AMP_KTVMUTESETStatus 0;
BA_ "GenSigCycleTime" SG_ 784 AMP_KTVVolSETStatus 100;
BA_ "GenSigSendType" SG_ 784 AMP_KTVVolSETStatus 0;
BA_ "GenSigStartValue" SG_ 784 AMP_KTVVolSETStatus 31;
BA_ "GenSigInvalidValue" SG_ 784 AMP_KTVVolSETStatus 31;
BA_ "GenSigCycleTime" SG_ 784 AMP_LRBalanceSETStatus 100;
BA_ "GenSigSendType" SG_ 784 AMP_LRBalanceSETStatus 0;
BA_ "GenSigStartValue" SG_ 784 AMP_LRBalanceSETStatus 0;
BA_ "GenSigInvalidValue" SG_ 784 AMP_LRBalanceSETStatus 0;
BA_ "GenSigCycleTime" SG_ 784 AMP_MediaMUTESETStatus 100;
BA_ "GenSigSendType" SG_ 784 AMP_MediaMUTESETStatus 0;
BA_ "GenSigStartValue" SG_ 784 AMP_MediaMUTESETStatus 0;
BA_ "GenSigInvalidValue" SG_ 784 AMP_MediaMUTESETStatus 0;
BA_ "GenSigCycleTime" SG_ 784 AMP_MediaVolSETStatus 100;
BA_ "GenSigSendType" SG_ 784 AMP_MediaVolSETStatus 0;
BA_ "GenSigStartValue" SG_ 784 AMP_MediaVolSETStatus 31;
BA_ "GenSigInvalidValue" SG_ 784 AMP_MediaVolSETStatus 31;
BA_ "GenSigCycleTime" SG_ 784 AMP_MUTESETStatus 100;
BA_ "GenSigSendType" SG_ 784 AMP_MUTESETStatus 0;
BA_ "GenSigStartValue" SG_ 784 AMP_MUTESETStatus 0;
BA_ "GenSigInvalidValue" SG_ 784 AMP_MUTESETStatus 0;
BA_ "GenSigCycleTime" SG_ 784 AMP_NaviMUTESETStatus 100;
BA_ "GenSigSendType" SG_ 784 AMP_NaviMUTESETStatus 0;
BA_ "GenSigStartValue" SG_ 784 AMP_NaviMUTESETStatus 0;
BA_ "GenSigInvalidValue" SG_ 784 AMP_NaviMUTESETStatus 0;
BA_ "GenSigCycleTime" SG_ 784 AMP_NAVIVolSETStatus 100;
BA_ "GenSigSendType" SG_ 784 AMP_NAVIVolSETStatus 0;
BA_ "GenSigStartValue" SG_ 784 AMP_NAVIVolSETStatus 31;
BA_ "GenSigInvalidValue" SG_ 784 AMP_NAVIVolSETStatus 31;
BA_ "GenSigCycleTime" SG_ 784 AMP_OutMUTESETStatus 100;
BA_ "GenSigSendType" SG_ 784 AMP_OutMUTESETStatus 0;
BA_ "GenSigStartValue" SG_ 784 AMP_OutMUTESETStatus 0;
BA_ "GenSigInvalidValue" SG_ 784 AMP_OutMUTESETStatus 0;
BA_ "GenSigCycleTime" SG_ 784 AMP_OUTVolSETStatus 100;
BA_ "GenSigSendType" SG_ 784 AMP_OUTVolSETStatus 0;
BA_ "GenSigStartValue" SG_ 784 AMP_OUTVolSETStatus 31;
BA_ "GenSigInvalidValue" SG_ 784 AMP_OUTVolSETStatus 31;
BA_ "GenSigCycleTime" SG_ 784 AMP_PerfessiionalEQ100SET 100;
BA_ "GenSigSendType" SG_ 784 AMP_PerfessiionalEQ100SET 0;
BA_ "GenSigStartValue" SG_ 784 AMP_PerfessiionalEQ100SET 0;
BA_ "GenSigInvalidValue" SG_ 784 AMP_PerfessiionalEQ100SET 0;
BA_ "GenSigCycleTime" SG_ 784 AMP_PerfessiionalEQ500SET 100;
BA_ "GenSigSendType" SG_ 784 AMP_PerfessiionalEQ500SET 0;
BA_ "GenSigStartValue" SG_ 784 AMP_PerfessiionalEQ500SET 0;
BA_ "GenSigInvalidValue" SG_ 784 AMP_PerfessiionalEQ500SET 0;
BA_ "GenSigCycleTime" SG_ 784 AMP_PerfessiionalEQ6KSET 100;
BA_ "GenSigSendType" SG_ 784 AMP_PerfessiionalEQ6KSET 0;
BA_ "GenSigStartValue" SG_ 784 AMP_PerfessiionalEQ6KSET 0;
BA_ "GenSigInvalidValue" SG_ 784 AMP_PerfessiionalEQ6KSET 0;
BA_ "GenSigCycleTime" SG_ 784 AMP_RLLowHighSpeakerDelaySETStat 100;
BA_ "GenSigSendType" SG_ 784 AMP_RLLowHighSpeakerDelaySETStat 0;
BA_ "GenSigStartValue" SG_ 784 AMP_RLLowHighSpeakerDelaySETStat 0;
BA_ "GenSigInvalidValue" SG_ 784 AMP_RLLowHighSpeakerDelaySETStat 0;
BA_ "SystemSignalLongSymbol" SG_ 784 AMP_RLLowHighSpeakerDelaySETStat "AMP_RLLowHighSpeakerDelaySETStatus";
BA_ "GenSigCycleTime" SG_ 784 AMP_RLLowHighSpeakerVolSETStatus 100;
BA_ "GenSigSendType" SG_ 784 AMP_RLLowHighSpeakerVolSETStatus 0;
BA_ "GenSigStartValue" SG_ 784 AMP_RLLowHighSpeakerVolSETStatus 31;
BA_ "GenSigInvalidValue" SG_ 784 AMP_RLLowHighSpeakerVolSETStatus 31;
BA_ "GenSigCycleTime" SG_ 784 AMP_RLSurroundSpeakerDelaySETSta 100;
BA_ "GenSigSendType" SG_ 784 AMP_RLSurroundSpeakerDelaySETSta 0;
BA_ "GenSigStartValue" SG_ 784 AMP_RLSurroundSpeakerDelaySETSta 0;
BA_ "GenSigInvalidValue" SG_ 784 AMP_RLSurroundSpeakerDelaySETSta 0;
BA_ "SystemSignalLongSymbol" SG_ 784 AMP_RLSurroundSpeakerDelaySETSta "AMP_RLSurroundSpeakerDelaySETStatus";
BA_ "GenSigCycleTime" SG_ 784 AMP_RLSurroundSpeakerVolSETStatu 100;
BA_ "GenSigSendType" SG_ 784 AMP_RLSurroundSpeakerVolSETStatu 0;
BA_ "GenSigStartValue" SG_ 784 AMP_RLSurroundSpeakerVolSETStatu 31;
BA_ "GenSigInvalidValue" SG_ 784 AMP_RLSurroundSpeakerVolSETStatu 31;
BA_ "SystemSignalLongSymbol" SG_ 784 AMP_RLSurroundSpeakerVolSETStatu "AMP_RLSurroundSpeakerVolSETStatus";
BA_ "GenSigCycleTime" SG_ 784 AMP_RLTopSpeakerDelaySETStatus 100;
BA_ "GenSigSendType" SG_ 784 AMP_RLTopSpeakerDelaySETStatus 0;
BA_ "GenSigStartValue" SG_ 784 AMP_RLTopSpeakerDelaySETStatus 0;
BA_ "GenSigInvalidValue" SG_ 784 AMP_RLTopSpeakerDelaySETStatus 0;
BA_ "GenSigCycleTime" SG_ 784 AMP_RLTopSpeakerVolSETStatus 100;
BA_ "GenSigSendType" SG_ 784 AMP_RLTopSpeakerVolSETStatus 0;
BA_ "GenSigStartValue" SG_ 784 AMP_RLTopSpeakerVolSETStatus 31;
BA_ "GenSigInvalidValue" SG_ 784 AMP_RLTopSpeakerVolSETStatus 31;
BA_ "GenSigCycleTime" SG_ 784 AMP_RNCEnableSETStatus 100;
BA_ "GenSigSendType" SG_ 784 AMP_RNCEnableSETStatus 0;
BA_ "GenSigStartValue" SG_ 784 AMP_RNCEnableSETStatus 0;
BA_ "GenSigInvalidValue" SG_ 784 AMP_RNCEnableSETStatus 0;
BA_ "GenSigCycleTime" SG_ 784 AMP_RRLowHighSpeakerDelaySET 100;
BA_ "GenSigSendType" SG_ 784 AMP_RRLowHighSpeakerDelaySET 0;
BA_ "GenSigStartValue" SG_ 784 AMP_RRLowHighSpeakerDelaySET 0;
BA_ "GenSigInvalidValue" SG_ 784 AMP_RRLowHighSpeakerDelaySET 0;
BA_ "GenSigCycleTime" SG_ 784 AMP_RRLowHighSpeakerVolSETStatus 100;
BA_ "GenSigSendType" SG_ 784 AMP_RRLowHighSpeakerVolSETStatus 0;
BA_ "GenSigStartValue" SG_ 784 AMP_RRLowHighSpeakerVolSETStatus 31;
BA_ "GenSigInvalidValue" SG_ 784 AMP_RRLowHighSpeakerVolSETStatus 31;
BA_ "GenSigCycleTime" SG_ 784 AMP_RRSurroundSpeakerDelaySETSta 100;
BA_ "GenSigSendType" SG_ 784 AMP_RRSurroundSpeakerDelaySETSta 0;
BA_ "GenSigStartValue" SG_ 784 AMP_RRSurroundSpeakerDelaySETSta 0;
BA_ "GenSigInvalidValue" SG_ 784 AMP_RRSurroundSpeakerDelaySETSta 0;
BA_ "SystemSignalLongSymbol" SG_ 784 AMP_RRSurroundSpeakerDelaySETSta "AMP_RRSurroundSpeakerDelaySETStatus";
BA_ "GenSigCycleTime" SG_ 784 AMP_RRSurroundSpeakerVolSET 100;
BA_ "GenSigSendType" SG_ 784 AMP_RRSurroundSpeakerVolSET 0;
BA_ "GenSigStartValue" SG_ 784 AMP_RRSurroundSpeakerVolSET 31;
BA_ "GenSigInvalidValue" SG_ 784 AMP_RRSurroundSpeakerVolSET 31;
BA_ "GenSigCycleTime" SG_ 784 AMP_RRTopSpeakerDelaySETStatus 100;
BA_ "GenSigSendType" SG_ 784 AMP_RRTopSpeakerDelaySETStatus 0;
BA_ "GenSigStartValue" SG_ 784 AMP_RRTopSpeakerDelaySETStatus 0;
BA_ "GenSigInvalidValue" SG_ 784 AMP_RRTopSpeakerDelaySETStatus 0;
BA_ "GenSigCycleTime" SG_ 784 AMP_RRTopSpeakerVolSETStatus 100;
BA_ "GenSigSendType" SG_ 784 AMP_RRTopSpeakerVolSETStatus 0;
BA_ "GenSigStartValue" SG_ 784 AMP_RRTopSpeakerVolSETStatus 31;
BA_ "GenSigInvalidValue" SG_ 784 AMP_RRTopSpeakerVolSETStatus 31;
BA_ "GenSigCycleTime" SG_ 784 AMP_SoundEffectSETStatus 100;
BA_ "GenSigSendType" SG_ 784 AMP_SoundEffectSETStatus 0;
BA_ "GenSigStartValue" SG_ 784 AMP_SoundEffectSETStatus 0;
BA_ "GenSigInvalidValue" SG_ 784 AMP_SoundEffectSETStatus 0;
BA_ "GenSigCycleTime" SG_ 784 AMP_SoundFieldSETStatus 100;
BA_ "GenSigSendType" SG_ 784 AMP_SoundFieldSETStatus 0;
BA_ "GenSigStartValue" SG_ 784 AMP_SoundFieldSETStatus 0;
BA_ "GenSigInvalidValue" SG_ 784 AMP_SoundFieldSETStatus 0;
BA_ "GenSigCycleTime" SG_ 784 AMP_SubSpeakerDelaySETStatus 100;
BA_ "GenSigSendType" SG_ 784 AMP_SubSpeakerDelaySETStatus 0;
BA_ "GenSigStartValue" SG_ 784 AMP_SubSpeakerDelaySETStatus 0;
BA_ "GenSigInvalidValue" SG_ 784 AMP_SubSpeakerDelaySETStatus 0;
BA_ "GenSigCycleTime" SG_ 784 AMP_SubSpeakerVolSETStatus 100;
BA_ "GenSigSendType" SG_ 784 AMP_SubSpeakerVolSETStatus 0;
BA_ "GenSigStartValue" SG_ 784 AMP_SubSpeakerVolSETStatus 31;
BA_ "GenSigInvalidValue" SG_ 784 AMP_SubSpeakerVolSETStatus 31;
BA_ "GenSigCycleTime" SG_ 784 AMP_SystemMUTESETStatus 100;
BA_ "GenSigSendType" SG_ 784 AMP_SystemMUTESETStatus 0;
BA_ "GenSigStartValue" SG_ 784 AMP_SystemMUTESETStatus 0;
BA_ "GenSigInvalidValue" SG_ 784 AMP_SystemMUTESETStatus 0;
BA_ "GenSigCycleTime" SG_ 784 AMP_SystemVolSETStatus 100;
BA_ "GenSigSendType" SG_ 784 AMP_SystemVolSETStatus 0;
BA_ "GenSigStartValue" SG_ 784 AMP_SystemVolSETStatus 31;
BA_ "GenSigInvalidValue" SG_ 784 AMP_SystemVolSETStatus 31;
BA_ "GenSigCycleTime" SG_ 784 AMP_TelBcallMUTESETStatus 100;
BA_ "GenSigSendType" SG_ 784 AMP_TelBcallMUTESETStatus 0;
BA_ "GenSigStartValue" SG_ 784 AMP_TelBcallMUTESETStatus 0;
BA_ "GenSigInvalidValue" SG_ 784 AMP_TelBcallMUTESETStatus 0;
BA_ "GenSigCycleTime" SG_ 784 AMP_TELBCALLVolSETStatus 100;
BA_ "GenSigSendType" SG_ 784 AMP_TELBCALLVolSETStatus 0;
BA_ "GenSigStartValue" SG_ 784 AMP_TELBCALLVolSETStatus 31;
BA_ "GenSigInvalidValue" SG_ 784 AMP_TELBCALLVolSETStatus 31;
BA_ "GenSigCycleTime" SG_ 784 AMP_TTSVRMUTESETStatus 100;
BA_ "GenSigSendType" SG_ 784 AMP_TTSVRMUTESETStatus 0;
BA_ "GenSigStartValue" SG_ 784 AMP_TTSVRMUTESETStatus 0;
BA_ "GenSigInvalidValue" SG_ 784 AMP_TTSVRMUTESETStatus 0;
BA_ "GenSigCycleTime" SG_ 784 AMP_TTSVRVolSETStatus 100;
BA_ "GenSigSendType" SG_ 784 AMP_TTSVRVolSETStatus 0;
BA_ "GenSigStartValue" SG_ 784 AMP_TTSVRVolSETStatus 31;
BA_ "GenSigInvalidValue" SG_ 784 AMP_TTSVRVolSETStatus 31;
BA_ "GenSigCycleTime" SG_ 784 AMP_TurnLightInOrOutSETStatus 100;
BA_ "GenSigSendType" SG_ 784 AMP_TurnLightInOrOutSETStatus 0;
BA_ "GenSigStartValue" SG_ 784 AMP_TurnLightInOrOutSETStatus 0;
BA_ "GenSigInvalidValue" SG_ 784 AMP_TurnLightInOrOutSETStatus 0;
BA_ "GenSigCycleTime" SG_ 784 AMP_TurnLightVolSETStatus 100;
BA_ "GenSigSendType" SG_ 784 AMP_TurnLightVolSETStatus 0;
BA_ "GenSigStartValue" SG_ 784 AMP_TurnLightVolSETStatus 0;
BA_ "GenSigInvalidValue" SG_ 784 AMP_TurnLightVolSETStatus 0;
BA_ "GenSigCycleTime" SG_ 784 AMP_VOLSpeedEnableSETStatus 100;
BA_ "GenSigSendType" SG_ 784 AMP_VOLSpeedEnableSETStatus 0;
BA_ "GenSigStartValue" SG_ 784 AMP_VOLSpeedEnableSETStatus 0;
BA_ "GenSigInvalidValue" SG_ 784 AMP_VOLSpeedEnableSETStatus 0;
BA_ "GenSigCycleTime" SG_ 800 AMPFLPositionDelaySETStatus 100;
BA_ "GenSigSendType" SG_ 800 AMPFLPositionDelaySETStatus 0;
BA_ "GenSigStartValue" SG_ 800 AMPFLPositionDelaySETStatus 1;
BA_ "GenSigInvalidValue" SG_ 800 AMPFLPositionDelaySETStatus 1;
BA_ "GenSigCycleTime" SG_ 800 AMPFLPositionVolSETStatus 100;
BA_ "GenSigSendType" SG_ 800 AMPFLPositionVolSETStatus 0;
BA_ "GenSigStartValue" SG_ 800 AMPFLPositionVolSETStatus 4;
BA_ "GenSigInvalidValue" SG_ 800 AMPFLPositionVolSETStatus 4;
BA_ "GenSigCycleTime" SG_ 800 AMPFRPositionDelaySETStatus 100;
BA_ "GenSigSendType" SG_ 800 AMPFRPositionDelaySETStatus 0;
BA_ "GenSigStartValue" SG_ 800 AMPFRPositionDelaySETStatus 1;
BA_ "GenSigInvalidValue" SG_ 800 AMPFRPositionDelaySETStatus 1;
BA_ "GenSigCycleTime" SG_ 800 AMPFRPositionVolSETStatus 100;
BA_ "GenSigSendType" SG_ 800 AMPFRPositionVolSETStatus 0;
BA_ "GenSigStartValue" SG_ 800 AMPFRPositionVolSETStatus 4;
BA_ "GenSigInvalidValue" SG_ 800 AMPFRPositionVolSETStatus 4;
BA_ "GenSigCycleTime" SG_ 800 AMPBeosonicModeSetStatus 100;
BA_ "GenSigSendType" SG_ 800 AMPBeosonicModeSetStatus 0;
BA_ "GenSigStartValue" SG_ 800 AMPBeosonicModeSetStatus 0;
BA_ "GenSigInvalidValue" SG_ 800 AMPBeosonicModeSetStatus 0;
BA_ "GenSigCycleTime" SG_ 800 AMPBeosonicXSetStatus 100;
BA_ "GenSigSendType" SG_ 800 AMPBeosonicXSetStatus 0;
BA_ "GenSigStartValue" SG_ 800 AMPBeosonicXSetStatus 11;
BA_ "GenSigInvalidValue" SG_ 800 AMPBeosonicXSetStatus 11;
BA_ "GenSigCycleTime" SG_ 800 AMPBeosonicYSetStatus 100;
BA_ "GenSigSendType" SG_ 800 AMPBeosonicYSetStatus 0;
BA_ "GenSigStartValue" SG_ 800 AMPBeosonicYSetStatus 11;
BA_ "GenSigInvalidValue" SG_ 800 AMPBeosonicYSetStatus 11;
BA_ "GenSigCycleTime" SG_ 800 AMPCenterPositionDelaySETStatus 100;
BA_ "GenSigSendType" SG_ 800 AMPCenterPositionDelaySETStatus 0;
BA_ "GenSigStartValue" SG_ 800 AMPCenterPositionDelaySETStatus 1;
BA_ "GenSigInvalidValue" SG_ 800 AMPCenterPositionDelaySETStatus 1;
BA_ "GenSigCycleTime" SG_ 800 AMPCenterPositionVolSETStatus 100;
BA_ "GenSigSendType" SG_ 800 AMPCenterPositionVolSETStatus 0;
BA_ "GenSigStartValue" SG_ 800 AMPCenterPositionVolSETStatus 4;
BA_ "GenSigInvalidValue" SG_ 800 AMPCenterPositionVolSETStatus 4;
BA_ "GenSigCycleTime" SG_ 800 AMPCustomEQ2500SET 100;
BA_ "GenSigSendType" SG_ 800 AMPCustomEQ2500SET 0;
BA_ "GenSigStartValue" SG_ 800 AMPCustomEQ2500SET 8;
BA_ "GenSigInvalidValue" SG_ 800 AMPCustomEQ2500SET 8;
BA_ "GenSigCycleTime" SG_ 800 AMPCustomEQ315SET 100;
BA_ "GenSigSendType" SG_ 800 AMPCustomEQ315SET 0;
BA_ "GenSigStartValue" SG_ 800 AMPCustomEQ315SET 8;
BA_ "GenSigInvalidValue" SG_ 800 AMPCustomEQ315SET 8;
BA_ "GenSigCycleTime" SG_ 800 AMPCustomEQ50SET 100;
BA_ "GenSigSendType" SG_ 800 AMPCustomEQ50SET 0;
BA_ "GenSigStartValue" SG_ 800 AMPCustomEQ50SET 8;
BA_ "GenSigInvalidValue" SG_ 800 AMPCustomEQ50SET 8;
BA_ "GenSigCycleTime" SG_ 800 AMPCustomEQ6000SET 100;
BA_ "GenSigSendType" SG_ 800 AMPCustomEQ6000SET 0;
BA_ "GenSigStartValue" SG_ 800 AMPCustomEQ6000SET 8;
BA_ "GenSigInvalidValue" SG_ 800 AMPCustomEQ6000SET 8;
BA_ "GenSigCycleTime" SG_ 800 AMPCustomEQ800SET 100;
BA_ "GenSigSendType" SG_ 800 AMPCustomEQ800SET 0;
BA_ "GenSigStartValue" SG_ 800 AMPCustomEQ800SET 8;
BA_ "GenSigInvalidValue" SG_ 800 AMPCustomEQ800SET 8;
BA_ "GenSigCycleTime" SG_ 800 AMPFLTopPositionDelaySETStatus 100;
BA_ "GenSigSendType" SG_ 800 AMPFLTopPositionDelaySETStatus 0;
BA_ "GenSigStartValue" SG_ 800 AMPFLTopPositionDelaySETStatus 1;
BA_ "GenSigInvalidValue" SG_ 800 AMPFLTopPositionDelaySETStatus 1;
BA_ "GenSigCycleTime" SG_ 800 AMPFLTopPositionVolSETStatus 100;
BA_ "GenSigSendType" SG_ 800 AMPFLTopPositionVolSETStatus 0;
BA_ "GenSigStartValue" SG_ 800 AMPFLTopPositionVolSETStatus 4;
BA_ "GenSigInvalidValue" SG_ 800 AMPFLTopPositionVolSETStatus 4;
BA_ "GenSigCycleTime" SG_ 800 AMPFRTopPositionDelaySETStatus 100;
BA_ "GenSigSendType" SG_ 800 AMPFRTopPositionDelaySETStatus 0;
BA_ "GenSigStartValue" SG_ 800 AMPFRTopPositionDelaySETStatus 1;
BA_ "GenSigInvalidValue" SG_ 800 AMPFRTopPositionDelaySETStatus 1;
BA_ "GenSigCycleTime" SG_ 800 AMPFRTopPositionVolSETStatus 100;
BA_ "GenSigSendType" SG_ 800 AMPFRTopPositionVolSETStatus 0;
BA_ "GenSigStartValue" SG_ 800 AMPFRTopPositionVolSETStatus 4;
BA_ "GenSigInvalidValue" SG_ 800 AMPFRTopPositionVolSETStatus 4;
BA_ "GenSigCycleTime" SG_ 800 AMPRLPositionDelaySETStatus 100;
BA_ "GenSigSendType" SG_ 800 AMPRLPositionDelaySETStatus 0;
BA_ "GenSigStartValue" SG_ 800 AMPRLPositionDelaySETStatus 1;
BA_ "GenSigInvalidValue" SG_ 800 AMPRLPositionDelaySETStatus 1;
BA_ "GenSigCycleTime" SG_ 800 AMPRLPositionVolSETStatus 100;
BA_ "GenSigSendType" SG_ 800 AMPRLPositionVolSETStatus 0;
BA_ "GenSigStartValue" SG_ 800 AMPRLPositionVolSETStatus 4;
BA_ "GenSigInvalidValue" SG_ 800 AMPRLPositionVolSETStatus 4;
BA_ "GenSigCycleTime" SG_ 800 AMPRLSurroundDelaySETStatus 100;
BA_ "GenSigSendType" SG_ 800 AMPRLSurroundDelaySETStatus 0;
BA_ "GenSigStartValue" SG_ 800 AMPRLSurroundDelaySETStatus 1;
BA_ "GenSigInvalidValue" SG_ 800 AMPRLSurroundDelaySETStatus 1;
BA_ "GenSigCycleTime" SG_ 800 AMPRLSurroundVolSETStatus 100;
BA_ "GenSigSendType" SG_ 800 AMPRLSurroundVolSETStatus 0;
BA_ "GenSigStartValue" SG_ 800 AMPRLSurroundVolSETStatus 4;
BA_ "GenSigInvalidValue" SG_ 800 AMPRLSurroundVolSETStatus 4;
BA_ "GenSigCycleTime" SG_ 800 AMPRLTopDelaySETStatus 100;
BA_ "GenSigSendType" SG_ 800 AMPRLTopDelaySETStatus 0;
BA_ "GenSigStartValue" SG_ 800 AMPRLTopDelaySETStatus 1;
BA_ "GenSigInvalidValue" SG_ 800 AMPRLTopDelaySETStatus 1;
BA_ "GenSigCycleTime" SG_ 800 AMPRLTopVolSETStatus 100;
BA_ "GenSigSendType" SG_ 800 AMPRLTopVolSETStatus 0;
BA_ "GenSigStartValue" SG_ 800 AMPRLTopVolSETStatus 4;
BA_ "GenSigInvalidValue" SG_ 800 AMPRLTopVolSETStatus 4;
BA_ "GenSigCycleTime" SG_ 800 AMPRRPositionDelaySET 100;
BA_ "GenSigSendType" SG_ 800 AMPRRPositionDelaySET 0;
BA_ "GenSigStartValue" SG_ 800 AMPRRPositionDelaySET 1;
BA_ "GenSigInvalidValue" SG_ 800 AMPRRPositionDelaySET 1;
BA_ "GenSigCycleTime" SG_ 800 AMPRRPositionVolSETStatus 100;
BA_ "GenSigSendType" SG_ 800 AMPRRPositionVolSETStatus 0;
BA_ "GenSigStartValue" SG_ 800 AMPRRPositionVolSETStatus 4;
BA_ "GenSigInvalidValue" SG_ 800 AMPRRPositionVolSETStatus 4;
BA_ "GenSigCycleTime" SG_ 800 AMPRRSurroundPositionDelaySETSta 100;
BA_ "GenSigSendType" SG_ 800 AMPRRSurroundPositionDelaySETSta 0;
BA_ "GenSigStartValue" SG_ 800 AMPRRSurroundPositionDelaySETSta 1;
BA_ "GenSigInvalidValue" SG_ 800 AMPRRSurroundPositionDelaySETSta 1;
BA_ "SystemSignalLongSymbol" SG_ 800 AMPRRSurroundPositionDelaySETSta "AMPRRSurroundPositionDelaySETStatus";
BA_ "GenSigCycleTime" SG_ 800 AMPRRSurroundPositionVolSET 100;
BA_ "GenSigSendType" SG_ 800 AMPRRSurroundPositionVolSET 0;
BA_ "GenSigStartValue" SG_ 800 AMPRRSurroundPositionVolSET 4;
BA_ "GenSigInvalidValue" SG_ 800 AMPRRSurroundPositionVolSET 4;
BA_ "GenSigCycleTime" SG_ 800 AMPRRTopPositionDelaySETStatus 100;
BA_ "GenSigSendType" SG_ 800 AMPRRTopPositionDelaySETStatus 0;
BA_ "GenSigStartValue" SG_ 800 AMPRRTopPositionDelaySETStatus 1;
BA_ "GenSigInvalidValue" SG_ 800 AMPRRTopPositionDelaySETStatus 1;
BA_ "GenSigCycleTime" SG_ 800 AMPRRTopPositionVolSETStatus 100;
BA_ "GenSigSendType" SG_ 800 AMPRRTopPositionVolSETStatus 0;
BA_ "GenSigStartValue" SG_ 800 AMPRRTopPositionVolSETStatus 4;
BA_ "GenSigInvalidValue" SG_ 800 AMPRRTopPositionVolSETStatus 4;
BA_ "GenSigCycleTime" SG_ 800 AMPSoundSourceTypeStatus 100;
BA_ "GenSigSendType" SG_ 800 AMPSoundSourceTypeStatus 0;
BA_ "GenSigStartValue" SG_ 800 AMPSoundSourceTypeStatus 0;
BA_ "GenSigInvalidValue" SG_ 800 AMPSoundSourceTypeStatus 0;
BA_ "GenSigCycleTime" SG_ 800 AMPSubPositionDelaySETStatus 100;
BA_ "GenSigSendType" SG_ 800 AMPSubPositionDelaySETStatus 0;
BA_ "GenSigStartValue" SG_ 800 AMPSubPositionDelaySETStatus 1;
BA_ "GenSigInvalidValue" SG_ 800 AMPSubPositionDelaySETStatus 1;
BA_ "GenSigCycleTime" SG_ 800 AMPSubPositionVolSETStatus 100;
BA_ "GenSigSendType" SG_ 800 AMPSubPositionVolSETStatus 0;
BA_ "GenSigStartValue" SG_ 800 AMPSubPositionVolSETStatus 4;
BA_ "GenSigInvalidValue" SG_ 800 AMPSubPositionVolSETStatus 4;
BA_ "GenSigCycleTime" SG_ 800 AMPTMCenterPositionEQ15000HzSetS 100;
BA_ "GenSigSendType" SG_ 800 AMPTMCenterPositionEQ15000HzSetS 0;
BA_ "GenSigStartValue" SG_ 800 AMPTMCenterPositionEQ15000HzSetS 4;
BA_ "GenSigInvalidValue" SG_ 800 AMPTMCenterPositionEQ15000HzSetS 4;
BA_ "SystemSignalLongSymbol" SG_ 800 AMPTMCenterPositionEQ15000HzSetS "AMPTMCenterPositionEQ15000HzSetStatus";
BA_ "GenSigCycleTime" SG_ 800 AMPTMCenterPositionEQ800HzSetSta 100;
BA_ "GenSigSendType" SG_ 800 AMPTMCenterPositionEQ800HzSetSta 0;
BA_ "GenSigStartValue" SG_ 800 AMPTMCenterPositionEQ800HzSetSta 4;
BA_ "GenSigInvalidValue" SG_ 800 AMPTMCenterPositionEQ800HzSetSta 4;
BA_ "SystemSignalLongSymbol" SG_ 800 AMPTMCenterPositionEQ800HzSetSta "AMPTMCenterPositionEQ800HzSetStatus";
BA_ "GenSigCycleTime" SG_ 800 AMPTMFLPositionEQ100HzSetStatus 100;
BA_ "GenSigSendType" SG_ 800 AMPTMFLPositionEQ100HzSetStatus 0;
BA_ "GenSigStartValue" SG_ 800 AMPTMFLPositionEQ100HzSetStatus 4;
BA_ "GenSigInvalidValue" SG_ 800 AMPTMFLPositionEQ100HzSetStatus 4;
BA_ "GenSigCycleTime" SG_ 800 AMPTMFLPositionEQ15000HzSetStatu 100;
BA_ "GenSigSendType" SG_ 800 AMPTMFLPositionEQ15000HzSetStatu 0;
BA_ "GenSigStartValue" SG_ 800 AMPTMFLPositionEQ15000HzSetStatu 4;
BA_ "GenSigInvalidValue" SG_ 800 AMPTMFLPositionEQ15000HzSetStatu 4;
BA_ "SystemSignalLongSymbol" SG_ 800 AMPTMFLPositionEQ15000HzSetStatu "AMPTMFLPositionEQ15000HzSetStatus";
BA_ "GenSigCycleTime" SG_ 800 AMPTMFLPositionEQ800HzSetStatus 100;
BA_ "GenSigSendType" SG_ 800 AMPTMFLPositionEQ800HzSetStatus 0;
BA_ "GenSigStartValue" SG_ 800 AMPTMFLPositionEQ800HzSetStatus 4;
BA_ "GenSigInvalidValue" SG_ 800 AMPTMFLPositionEQ800HzSetStatus 4;
BA_ "GenSigCycleTime" SG_ 800 AMPTMFLTopPositionEQ500HzSetStat 100;
BA_ "GenSigSendType" SG_ 800 AMPTMFLTopPositionEQ500HzSetStat 0;
BA_ "GenSigStartValue" SG_ 800 AMPTMFLTopPositionEQ500HzSetStat 4;
BA_ "GenSigInvalidValue" SG_ 800 AMPTMFLTopPositionEQ500HzSetStat 4;
BA_ "SystemSignalLongSymbol" SG_ 800 AMPTMFLTopPositionEQ500HzSetStat "AMPTMFLTopPositionEQ500HzSetStatus";
BA_ "GenSigCycleTime" SG_ 800 AMPTMFRPositionEQ100HzSetStatus 100;
BA_ "GenSigSendType" SG_ 800 AMPTMFRPositionEQ100HzSetStatus 0;
BA_ "GenSigStartValue" SG_ 800 AMPTMFRPositionEQ100HzSetStatus 4;
BA_ "GenSigInvalidValue" SG_ 800 AMPTMFRPositionEQ100HzSetStatus 4;
BA_ "GenSigCycleTime" SG_ 800 AMPTMFRPositionEQ15000HzSetStatu 100;
BA_ "GenSigSendType" SG_ 800 AMPTMFRPositionEQ15000HzSetStatu 0;
BA_ "GenSigStartValue" SG_ 800 AMPTMFRPositionEQ15000HzSetStatu 4;
BA_ "GenSigInvalidValue" SG_ 800 AMPTMFRPositionEQ15000HzSetStatu 4;
BA_ "SystemSignalLongSymbol" SG_ 800 AMPTMFRPositionEQ15000HzSetStatu "AMPTMFRPositionEQ15000HzSetStatus";
BA_ "GenSigCycleTime" SG_ 800 AMPTMFRPositionEQ800HzSetStatus 100;
BA_ "GenSigSendType" SG_ 800 AMPTMFRPositionEQ800HzSetStatus 0;
BA_ "GenSigStartValue" SG_ 800 AMPTMFRPositionEQ800HzSetStatus 4;
BA_ "GenSigInvalidValue" SG_ 800 AMPTMFRPositionEQ800HzSetStatus 4;
BA_ "GenSigCycleTime" SG_ 800 AMPTMFRTopPositionEQ500HzSetStat 100;
BA_ "GenSigSendType" SG_ 800 AMPTMFRTopPositionEQ500HzSetStat 0;
BA_ "GenSigStartValue" SG_ 800 AMPTMFRTopPositionEQ500HzSetStat 4;
BA_ "GenSigInvalidValue" SG_ 800 AMPTMFRTopPositionEQ500HzSetStat 4;
BA_ "SystemSignalLongSymbol" SG_ 800 AMPTMFRTopPositionEQ500HzSetStat "AMPTMFRTopPositionEQ500HzSetStatus";
BA_ "GenSigCycleTime" SG_ 800 AMPTMReverbSetStatus 100;
BA_ "GenSigSendType" SG_ 800 AMPTMReverbSetStatus 0;
BA_ "GenSigStartValue" SG_ 800 AMPTMReverbSetStatus 0;
BA_ "GenSigInvalidValue" SG_ 800 AMPTMReverbSetStatus 0;
BA_ "GenSigCycleTime" SG_ 800 AMPTMRLPositionEQ10000HzSetStatu 100;
BA_ "GenSigSendType" SG_ 800 AMPTMRLPositionEQ10000HzSetStatu 0;
BA_ "GenSigStartValue" SG_ 800 AMPTMRLPositionEQ10000HzSetStatu 4;
BA_ "GenSigInvalidValue" SG_ 800 AMPTMRLPositionEQ10000HzSetStatu 4;
BA_ "SystemSignalLongSymbol" SG_ 800 AMPTMRLPositionEQ10000HzSetStatu "AMPTMRLPositionEQ10000HzSetStatus";
BA_ "GenSigCycleTime" SG_ 800 AMPTMRLPositionEQ100HzSetStatusS 100;
BA_ "GenSigSendType" SG_ 800 AMPTMRLPositionEQ100HzSetStatusS 0;
BA_ "GenSigStartValue" SG_ 800 AMPTMRLPositionEQ100HzSetStatusS 4;
BA_ "GenSigInvalidValue" SG_ 800 AMPTMRLPositionEQ100HzSetStatusS 4;
BA_ "SystemSignalLongSymbol" SG_ 800 AMPTMRLPositionEQ100HzSetStatusS "AMPTMRLPositionEQ100HzSetStatusStatus";
BA_ "GenSigCycleTime" SG_ 800 AMPTMRLSurroundPositionEQ15000Hz 100;
BA_ "GenSigSendType" SG_ 800 AMPTMRLSurroundPositionEQ15000Hz 0;
BA_ "GenSigStartValue" SG_ 800 AMPTMRLSurroundPositionEQ15000Hz 4;
BA_ "GenSigInvalidValue" SG_ 800 AMPTMRLSurroundPositionEQ15000Hz 4;
BA_ "SystemSignalLongSymbol" SG_ 800 AMPTMRLSurroundPositionEQ15000Hz "AMPTMRLSurroundPositionEQ15000HzSetStatus";
BA_ "GenSigCycleTime" SG_ 800 AMPTMRLSurroundPositionEQ800HzSe 100;
BA_ "GenSigSendType" SG_ 800 AMPTMRLSurroundPositionEQ800HzSe 0;
BA_ "GenSigStartValue" SG_ 800 AMPTMRLSurroundPositionEQ800HzSe 4;
BA_ "GenSigInvalidValue" SG_ 800 AMPTMRLSurroundPositionEQ800HzSe 4;
BA_ "SystemSignalLongSymbol" SG_ 800 AMPTMRLSurroundPositionEQ800HzSe "AMPTMRLSurroundPositionEQ800HzSetStatus";
BA_ "GenSigCycleTime" SG_ 800 AMPTMRLTopPositionEQ500HzSetStat 100;
BA_ "GenSigSendType" SG_ 800 AMPTMRLTopPositionEQ500HzSetStat 0;
BA_ "GenSigStartValue" SG_ 800 AMPTMRLTopPositionEQ500HzSetStat 4;
BA_ "GenSigInvalidValue" SG_ 800 AMPTMRLTopPositionEQ500HzSetStat 4;
BA_ "SystemSignalLongSymbol" SG_ 800 AMPTMRLTopPositionEQ500HzSetStat "AMPTMRLTopPositionEQ500HzSetStatus";
BA_ "GenSigCycleTime" SG_ 800 AMPTMRRPositionEQ10000HzSetStatu 100;
BA_ "GenSigSendType" SG_ 800 AMPTMRRPositionEQ10000HzSetStatu 0;
BA_ "GenSigStartValue" SG_ 800 AMPTMRRPositionEQ10000HzSetStatu 4;
BA_ "GenSigInvalidValue" SG_ 800 AMPTMRRPositionEQ10000HzSetStatu 4;
BA_ "SystemSignalLongSymbol" SG_ 800 AMPTMRRPositionEQ10000HzSetStatu "AMPTMRRPositionEQ10000HzSetStatus";
BA_ "GenSigCycleTime" SG_ 800 AMPTMRRPositionEQ100HzSetStatus 100;
BA_ "GenSigSendType" SG_ 800 AMPTMRRPositionEQ100HzSetStatus 0;
BA_ "GenSigStartValue" SG_ 800 AMPTMRRPositionEQ100HzSetStatus 4;
BA_ "GenSigInvalidValue" SG_ 800 AMPTMRRPositionEQ100HzSetStatus 4;
BA_ "GenSigCycleTime" SG_ 800 AMPTMRRSurroundPositionEQ15000Hz 100;
BA_ "GenSigSendType" SG_ 800 AMPTMRRSurroundPositionEQ15000Hz 0;
BA_ "GenSigStartValue" SG_ 800 AMPTMRRSurroundPositionEQ15000Hz 4;
BA_ "GenSigInvalidValue" SG_ 800 AMPTMRRSurroundPositionEQ15000Hz 4;
BA_ "SystemSignalLongSymbol" SG_ 800 AMPTMRRSurroundPositionEQ15000Hz "AMPTMRRSurroundPositionEQ15000HzSetStatus";
BA_ "GenSigCycleTime" SG_ 800 AMPTMRRSurroundPositionEQ800HzSe 100;
BA_ "GenSigSendType" SG_ 800 AMPTMRRSurroundPositionEQ800HzSe 0;
BA_ "GenSigStartValue" SG_ 800 AMPTMRRSurroundPositionEQ800HzSe 4;
BA_ "GenSigInvalidValue" SG_ 800 AMPTMRRSurroundPositionEQ800HzSe 4;
BA_ "SystemSignalLongSymbol" SG_ 800 AMPTMRRSurroundPositionEQ800HzSe "AMPTMRRSurroundPositionEQ800HzSetStatus";
BA_ "GenSigCycleTime" SG_ 800 AMPTMRRTopPositionEQ500HzSetStat 100;
BA_ "GenSigSendType" SG_ 800 AMPTMRRTopPositionEQ500HzSetStat 0;
BA_ "GenSigStartValue" SG_ 800 AMPTMRRTopPositionEQ500HzSetStat 4;
BA_ "GenSigInvalidValue" SG_ 800 AMPTMRRTopPositionEQ500HzSetStat 4;
BA_ "SystemSignalLongSymbol" SG_ 800 AMPTMRRTopPositionEQ500HzSetStat "AMPTMRRTopPositionEQ500HzSetStatus";
BA_ "GenSigCycleTime" SG_ 800 AMPTMSubPositionEQ30HzSetStatusS 100;
BA_ "GenSigSendType" SG_ 800 AMPTMSubPositionEQ30HzSetStatusS 0;
BA_ "GenSigStartValue" SG_ 800 AMPTMSubPositionEQ30HzSetStatusS 4;
BA_ "GenSigInvalidValue" SG_ 800 AMPTMSubPositionEQ30HzSetStatusS 4;
BA_ "SystemSignalLongSymbol" SG_ 800 AMPTMSubPositionEQ30HzSetStatusS "AMPTMSubPositionEQ30HzSetStatusStatus";
BA_ "GenSigCycleTime" SG_ 800 AMPVOLSpeedLevChangeSETStatus 100;
BA_ "GenSigSendType" SG_ 800 AMPVOLSpeedLevChangeSETStatus 0;
BA_ "GenSigStartValue" SG_ 800 AMPVOLSpeedLevChangeSETStatus 1;
BA_ "GenSigInvalidValue" SG_ 800 AMPVOLSpeedLevChangeSETStatus 1;
BA_ "GenSigCycleTime" SG_ 802 ECAStarLvl 100;
BA_ "GenSigSendType" SG_ 802 ECAStarLvl 0;
BA_ "GenSigStartValue" SG_ 802 ECAStarLvl 0;
BA_ "GenSigInvalidValue" SG_ 802 ECAStarLvl 0;
BA_ "GenSigCycleTime" SG_ 802 ECASActLvlFL 100;
BA_ "GenSigSendType" SG_ 802 ECASActLvlFL 0;
BA_ "GenSigStartValue" SG_ 802 ECASActLvlFL 0;
BA_ "GenSigInvalidValue" SG_ 802 ECASActLvlFL 0;
BA_ "GenSigCycleTime" SG_ 802 ECASActLvlFR 100;
BA_ "GenSigSendType" SG_ 802 ECASActLvlFR 0;
BA_ "GenSigStartValue" SG_ 802 ECASActLvlFR 0;
BA_ "GenSigInvalidValue" SG_ 802 ECASActLvlFR 0;
BA_ "GenSigCycleTime" SG_ 802 ECASActLvlRL 100;
BA_ "GenSigSendType" SG_ 802 ECASActLvlRL 0;
BA_ "GenSigStartValue" SG_ 802 ECASActLvlRL 0;
BA_ "GenSigInvalidValue" SG_ 802 ECASActLvlRL 0;
BA_ "GenSigCycleTime" SG_ 802 ECASActLvlRR 100;
BA_ "GenSigSendType" SG_ 802 ECASActLvlRR 0;
BA_ "GenSigStartValue" SG_ 802 ECASActLvlRR 0;
BA_ "GenSigInvalidValue" SG_ 802 ECASActLvlRR 0;
BA_ "GenSigCycleTime" SG_ 802 ECASAdjBySpd 100;
BA_ "GenSigSendType" SG_ 802 ECASAdjBySpd 0;
BA_ "GenSigStartValue" SG_ 802 ECASAdjBySpd 0;
BA_ "GenSigInvalidValue" SG_ 802 ECASAdjBySpd 0;
BA_ "GenSigCycleTime" SG_ 802 ECASaftaxladjsts 100;
BA_ "GenSigSendType" SG_ 802 ECASaftaxladjsts 0;
BA_ "GenSigStartValue" SG_ 802 ECASaftaxladjsts 0;
BA_ "GenSigInvalidValue" SG_ 802 ECASaftaxladjsts "NA";
BA_ "GenSigCycleTime" SG_ 802 ECASerromode 100;
BA_ "GenSigSendType" SG_ 802 ECASerromode 0;
BA_ "GenSigStartValue" SG_ 802 ECASerromode 0;
BA_ "GenSigInvalidValue" SG_ 802 ECASerromode "NA";
BA_ "GenSigCycleTime" SG_ 802 ECASfrtaxladjsts 100;
BA_ "GenSigSendType" SG_ 802 ECASfrtaxladjsts 0;
BA_ "GenSigStartValue" SG_ 802 ECASfrtaxladjsts 0;
BA_ "GenSigInvalidValue" SG_ 802 ECASfrtaxladjsts "NA";
BA_ "GenSigCycleTime" SG_ 802 EcasModeCHASts 100;
BA_ "GenSigSendType" SG_ 802 EcasModeCHASts 0;
BA_ "GenSigStartValue" SG_ 802 EcasModeCHASts 0;
BA_ "GenSigInvalidValue" SG_ 802 EcasModeCHASts 0;
BA_ "GenSigCycleTime" SG_ 802 EcasModeFB 100;
BA_ "GenSigSendType" SG_ 802 EcasModeFB 0;
BA_ "GenSigStartValue" SG_ 802 EcasModeFB 0;
BA_ "GenSigInvalidValue" SG_ 802 EcasModeFB 0;
BA_ "GenSigCycleTime" SG_ 802 ECASmodevld 100;
BA_ "GenSigSendType" SG_ 802 ECASmodevld 0;
BA_ "GenSigStartValue" SG_ 802 ECASmodevld 0;
BA_ "GenSigInvalidValue" SG_ 802 ECASmodevld "NA";
BA_ "GenSigCycleTime" SG_ 802 SusfaultlLamp 100;
BA_ "GenSigSendType" SG_ 802 SusfaultlLamp 0;
BA_ "GenSigStartValue" SG_ 802 SusfaultlLamp 0;
BA_ "GenSigInvalidValue" SG_ 802 SusfaultlLamp "NA";
BA_ "GenSigCycleTime" SG_ 802 Susfaultred 100;
BA_ "GenSigSendType" SG_ 802 Susfaultred 0;
BA_ "GenSigStartValue" SG_ 802 Susfaultred 0;
BA_ "GenSigInvalidValue" SG_ 802 Susfaultred 0;
BA_ "GenSigCycleTime" SG_ 821 BCM_DriverWindowStatus 100;
BA_ "GenSigSendType" SG_ 821 BCM_DriverWindowStatus 0;
BA_ "GenSigStartValue" SG_ 821 BCM_DriverWindowStatus 0;
BA_ "GenSigInvalidValue" SG_ 821 BCM_DriverWindowStatus 0;
BA_ "GenSigCycleTime" SG_ 821 BCM_PartWinPosVIT 100;
BA_ "GenSigSendType" SG_ 821 BCM_PartWinPosVIT 0;
BA_ "GenSigStartValue" SG_ 821 BCM_PartWinPosVIT 0;
BA_ "GenSigInvalidValue" SG_ 821 BCM_PartWinPosVIT 0;
BA_ "GenSigCycleTime" SG_ 821 BCM_PartWinSts 100;
BA_ "GenSigSendType" SG_ 821 BCM_PartWinSts 0;
BA_ "GenSigStartValue" SG_ 821 BCM_PartWinSts 0;
BA_ "GenSigInvalidValue" SG_ 821 BCM_PartWinSts 0;
BA_ "GenSigCycleTime" SG_ 821 BCM_PassengerWindowPosi 100;
BA_ "GenSigSendType" SG_ 821 BCM_PassengerWindowPosi 0;
BA_ "GenSigStartValue" SG_ 821 BCM_PassengerWindowPosi 0;
BA_ "GenSigInvalidValue" SG_ 821 BCM_PassengerWindowPosi 0;
BA_ "GenSigCycleTime" SG_ 821 BCM_PassengerWindowStatus 100;
BA_ "GenSigSendType" SG_ 821 BCM_PassengerWindowStatus 0;
BA_ "GenSigStartValue" SG_ 821 BCM_PassengerWindowStatus 0;
BA_ "GenSigInvalidValue" SG_ 821 BCM_PassengerWindowStatus 0;
BA_ "GenSigCycleTime" SG_ 821 VcuIpuErrLamp 100;
BA_ "GenSigSendType" SG_ 821 VcuIpuErrLamp 0;
BA_ "GenSigStartValue" SG_ 821 VcuIpuErrLamp 0;
BA_ "GenSigInvalidValue" SG_ 821 VcuIpuErrLamp "NA";
BA_ "GenSigCycleTime" SG_ 821 VcuEgyMagtModResp 100;
BA_ "GenSigSendType" SG_ 821 VcuEgyMagtModResp 0;
BA_ "GenSigStartValue" SG_ 821 VcuEgyMagtModResp 1;
BA_ "GenSigInvalidValue" SG_ 821 VcuEgyMagtModResp 1;
BA_ "GenSigCycleTime" SG_ 821 VcuForceEVModResp 100;
BA_ "GenSigSendType" SG_ 821 VcuForceEVModResp 0;
BA_ "GenSigStartValue" SG_ 821 VcuForceEVModResp 0;
BA_ "GenSigInvalidValue" SG_ 821 VcuForceEVModResp 0;
BA_ "GenSigCycleTime" SG_ 821 VcuForcePwrPresModResp 100;
BA_ "GenSigSendType" SG_ 821 VcuForcePwrPresModResp 0;
BA_ "GenSigStartValue" SG_ 821 VcuForcePwrPresModResp 0;
BA_ "GenSigInvalidValue" SG_ 821 VcuForcePwrPresModResp 0;
BA_ "GenSigCycleTime" SG_ 821 BCM_RightRearWindowPosi 100;
BA_ "GenSigSendType" SG_ 821 BCM_RightRearWindowPosi 0;
BA_ "GenSigStartValue" SG_ 821 BCM_RightRearWindowPosi 0;
BA_ "GenSigInvalidValue" SG_ 821 BCM_RightRearWindowPosi 0;
BA_ "GenSigCycleTime" SG_ 821 BCM_RightRearWindowStatus 100;
BA_ "GenSigSendType" SG_ 821 BCM_RightRearWindowStatus 0;
BA_ "GenSigStartValue" SG_ 821 BCM_RightRearWindowStatus 0;
BA_ "GenSigInvalidValue" SG_ 821 BCM_RightRearWindowStatus 0;
BA_ "GenSigCycleTime" SG_ 821 VCU_CRCCheck_335 100;
BA_ "GenSigSendType" SG_ 821 VCU_CRCCheck_335 0;
BA_ "GenSigStartValue" SG_ 821 VCU_CRCCheck_335 0;
BA_ "GenSigInvalidValue" SG_ 821 VCU_CRCCheck_335 "NA";
BA_ "GenSigCycleTime" SG_ 821 VCU_RollingCounter_335 100;
BA_ "GenSigSendType" SG_ 821 VCU_RollingCounter_335 0;
BA_ "GenSigStartValue" SG_ 821 VCU_RollingCounter_335 0;
BA_ "GenSigInvalidValue" SG_ 821 VCU_RollingCounter_335 "NA";
BA_ "GenSigCycleTime" SG_ 821 VcuAcChrgNegativePoleTemp 100;
BA_ "GenSigSendType" SG_ 821 VcuAcChrgNegativePoleTemp 0;
BA_ "GenSigStartValue" SG_ 821 VcuAcChrgNegativePoleTemp 0;
BA_ "GenSigInvalidValue" SG_ 821 VcuAcChrgNegativePoleTemp "NA";
BA_ "GenSigCycleTime" SG_ 821 VcuAccrPedlPosnGb 100;
BA_ "GenSigSendType" SG_ 821 VcuAccrPedlPosnGb 0;
BA_ "GenSigStartValue" SG_ 821 VcuAccrPedlPosnGb 0;
BA_ "GenSigInvalidValue" SG_ 821 VcuAccrPedlPosnGb "NA";
BA_ "GenSigCycleTime" SG_ 821 VcuBattIGb 100;
BA_ "GenSigSendType" SG_ 821 VcuBattIGb 0;
BA_ "GenSigStartValue" SG_ 821 VcuBattIGb 0;
BA_ "GenSigInvalidValue" SG_ 821 VcuBattIGb "NA";
BA_ "GenSigCycleTime" SG_ 821 VcuGearPosnStsGb 100;
BA_ "GenSigSendType" SG_ 821 VcuGearPosnStsGb 0;
BA_ "GenSigStartValue" SG_ 821 VcuGearPosnStsGb 0;
BA_ "GenSigInvalidValue" SG_ 821 VcuGearPosnStsGb "NA";
BA_ "GenSigCycleTime" SG_ 821 VcuHvilStsGb 100;
BA_ "GenSigSendType" SG_ 821 VcuHvilStsGb 0;
BA_ "GenSigStartValue" SG_ 821 VcuHvilStsGb 0;
BA_ "GenSigInvalidValue" SG_ 821 VcuHvilStsGb "NA";
BA_ "GenSigCycleTime" SG_ 821 VcuVehChrgStsGb 100;
BA_ "GenSigSendType" SG_ 821 VcuVehChrgStsGb 0;
BA_ "GenSigStartValue" SG_ 821 VcuVehChrgStsGb 0;
BA_ "GenSigInvalidValue" SG_ 821 VcuVehChrgStsGb "NA";
BA_ "GenSigCycleTime" SG_ 821 VcuVehRunngModGb 100;
BA_ "GenSigSendType" SG_ 821 VcuVehRunngModGb 0;
BA_ "GenSigStartValue" SG_ 821 VcuVehRunngModGb 0;
BA_ "GenSigInvalidValue" SG_ 821 VcuVehRunngModGb "NA";
BA_ "GenSigCycleTime" SG_ 821 VcuVehStsGb 100;
BA_ "GenSigSendType" SG_ 821 VcuVehStsGb 0;
BA_ "GenSigStartValue" SG_ 821 VcuVehStsGb 0;
BA_ "GenSigInvalidValue" SG_ 821 VcuVehStsGb "NA";
BA_ "GenSigCycleTime" SG_ 821 VcuBrkPedlSts 100;
BA_ "GenSigSendType" SG_ 821 VcuBrkPedlSts 0;
BA_ "GenSigStartValue" SG_ 821 VcuBrkPedlSts 0;
BA_ "GenSigInvalidValue" SG_ 821 VcuBrkPedlSts "NA";
BA_ "GenSigCycleTime" SG_ 821 VcuPwrCnse 100;
BA_ "GenSigSendType" SG_ 821 VcuPwrCnse 0;
BA_ "GenSigStartValue" SG_ 821 VcuPwrCnse 0;
BA_ "GenSigInvalidValue" SG_ 821 VcuPwrCnse "NA";
BA_ "GenSigCycleTime" SG_ 821 VcuSocDisp 100;
BA_ "GenSigSendType" SG_ 821 VcuSocDisp 0;
BA_ "GenSigStartValue" SG_ 821 VcuSocDisp 0;
BA_ "GenSigInvalidValue" SG_ 821 VcuSocDisp "NA";
BA_ "GenSigCycleTime" SG_ 821 BCM_DriverWindowPosi 100;
BA_ "GenSigSendType" SG_ 821 BCM_DriverWindowPosi 0;
BA_ "GenSigStartValue" SG_ 821 BCM_DriverWindowPosi 0;
BA_ "GenSigInvalidValue" SG_ 821 BCM_DriverWindowPosi 0;
BA_ "GenSigCycleTime" SG_ 821 BCM_LeftRearWindowPosi 100;
BA_ "GenSigSendType" SG_ 821 BCM_LeftRearWindowPosi 0;
BA_ "GenSigStartValue" SG_ 821 BCM_LeftRearWindowPosi 0;
BA_ "GenSigInvalidValue" SG_ 821 BCM_LeftRearWindowPosi 0;
BA_ "GenSigCycleTime" SG_ 821 BCM_LeftRearWindowStatus 100;
BA_ "GenSigSendType" SG_ 821 BCM_LeftRearWindowStatus 0;
BA_ "GenSigStartValue" SG_ 821 BCM_LeftRearWindowStatus 0;
BA_ "GenSigInvalidValue" SG_ 821 BCM_LeftRearWindowStatus 0;
BA_ "GenSigCycleTime" SG_ 821 BcmSunroofPosi 100;
BA_ "GenSigSendType" SG_ 821 BcmSunroofPosi 0;
BA_ "GenSigStartValue" SG_ 821 BcmSunroofPosi 0;
BA_ "GenSigInvalidValue" SG_ 821 BcmSunroofPosi "NA";
BA_ "GenSigCycleTime" SG_ 821 BcmSunroofStatus 100;
BA_ "GenSigSendType" SG_ 821 BcmSunroofStatus 0;
BA_ "GenSigStartValue" SG_ 821 BcmSunroofStatus 0;
BA_ "GenSigInvalidValue" SG_ 821 BcmSunroofStatus "NA";
BA_ "GenSigCycleTime" SG_ 821 MFS_Right_switch_Right1_signal 100;
BA_ "GenSigSendType" SG_ 821 MFS_Right_switch_Right1_signal 0;
BA_ "GenSigStartValue" SG_ 821 MFS_Right_switch_Right1_signal 0;
BA_ "GenSigInvalidValue" SG_ 821 MFS_Right_switch_Right1_signal "NA";
BA_ "GenSigCycleTime" SG_ 821 VcuAcChrgPositivePoleTemp 100;
BA_ "GenSigSendType" SG_ 821 VcuAcChrgPositivePoleTemp 0;
BA_ "GenSigStartValue" SG_ 821 VcuAcChrgPositivePoleTemp 0;
BA_ "GenSigInvalidValue" SG_ 821 VcuAcChrgPositivePoleTemp "NA";
BA_ "GenSigCycleTime" SG_ 821 VcuBattChrgErrLamp 100;
BA_ "GenSigSendType" SG_ 821 VcuBattChrgErrLamp 0;
BA_ "GenSigStartValue" SG_ 821 VcuBattChrgErrLamp 0;
BA_ "GenSigInvalidValue" SG_ 821 VcuBattChrgErrLamp "NA";
BA_ "GenSigCycleTime" SG_ 821 VcuBattlowU 100;
BA_ "GenSigSendType" SG_ 821 VcuBattlowU 0;
BA_ "GenSigStartValue" SG_ 821 VcuBattlowU 0;
BA_ "GenSigInvalidValue" SG_ 821 VcuBattlowU "NA";
BA_ "GenSigCycleTime" SG_ 821 VcuBattUUnderWarn 100;
BA_ "GenSigSendType" SG_ 821 VcuBattUUnderWarn 0;
BA_ "GenSigStartValue" SG_ 821 VcuBattUUnderWarn 0;
BA_ "GenSigInvalidValue" SG_ 821 VcuBattUUnderWarn "NA";
BA_ "GenSigCycleTime" SG_ 821 VcuChrgAutoUnlckSetStsFb 100;
BA_ "GenSigSendType" SG_ 821 VcuChrgAutoUnlckSetStsFb 0;
BA_ "GenSigStartValue" SG_ 821 VcuChrgAutoUnlckSetStsFb 0;
BA_ "GenSigInvalidValue" SG_ 821 VcuChrgAutoUnlckSetStsFb "NA";
BA_ "GenSigCycleTime" SG_ 821 VcuChrgLckInfo 100;
BA_ "GenSigSendType" SG_ 821 VcuChrgLckInfo 0;
BA_ "GenSigStartValue" SG_ 821 VcuChrgLckInfo 0;
BA_ "GenSigInvalidValue" SG_ 821 VcuChrgLckInfo "NA";
BA_ "GenSigCycleTime" SG_ 821 VcuDcChrgNegativePoleTemp 100;
BA_ "GenSigSendType" SG_ 821 VcuDcChrgNegativePoleTemp 0;
BA_ "GenSigStartValue" SG_ 821 VcuDcChrgNegativePoleTemp 0;
BA_ "GenSigInvalidValue" SG_ 821 VcuDcChrgNegativePoleTemp "NA";
BA_ "GenSigCycleTime" SG_ 821 VcuDcChrgPositivePoleTemp 100;
BA_ "GenSigSendType" SG_ 821 VcuDcChrgPositivePoleTemp 0;
BA_ "GenSigStartValue" SG_ 821 VcuDcChrgPositivePoleTemp 0;
BA_ "GenSigInvalidValue" SG_ 821 VcuDcChrgPositivePoleTemp "NA";
BA_ "GenSigCycleTime" SG_ 821 VCUGearShiftPositon 100;
BA_ "GenSigSendType" SG_ 821 VCUGearShiftPositon 0;
BA_ "GenSigStartValue" SG_ 821 VCUGearShiftPositon 0;
BA_ "GenSigInvalidValue" SG_ 821 VCUGearShiftPositon "NA";
BA_ "GenSigCycleTime" SG_ 821 VcuHvBattCutOffLamp 100;
BA_ "GenSigSendType" SG_ 821 VcuHvBattCutOffLamp 0;
BA_ "GenSigStartValue" SG_ 821 VcuHvBattCutOffLamp 0;
BA_ "GenSigInvalidValue" SG_ 821 VcuHvBattCutOffLamp "NA";
BA_ "GenSigCycleTime" SG_ 821 VcuHVErrInfo 100;
BA_ "GenSigSendType" SG_ 821 VcuHVErrInfo 0;
BA_ "GenSigStartValue" SG_ 821 VcuHVErrInfo 0;
BA_ "GenSigInvalidValue" SG_ 821 VcuHVErrInfo "NA";
BA_ "GenSigCycleTime" SG_ 821 VcuHvilSts 100;
BA_ "GenSigSendType" SG_ 821 VcuHvilSts 0;
BA_ "GenSigStartValue" SG_ 821 VcuHvilSts 0;
BA_ "GenSigInvalidValue" SG_ 821 VcuHvilSts "NA";
BA_ "GenSigCycleTime" SG_ 821 VcuResiMilg 100;
BA_ "GenSigSendType" SG_ 821 VcuResiMilg 0;
BA_ "GenSigStartValue" SG_ 821 VcuResiMilg 0;
BA_ "GenSigInvalidValue" SG_ 821 VcuResiMilg "NA";
BA_ "GenSigCycleTime" SG_ 821 VcuShiftPErrInfo 100;
BA_ "GenSigSendType" SG_ 821 VcuShiftPErrInfo 0;
BA_ "GenSigStartValue" SG_ 821 VcuShiftPErrInfo 0;
BA_ "GenSigInvalidValue" SG_ 821 VcuShiftPErrInfo "NA";
BA_ "GenSigCycleTime" SG_ 821 VCUShiftPostionValid 100;
BA_ "GenSigSendType" SG_ 821 VCUShiftPostionValid 0;
BA_ "GenSigStartValue" SG_ 821 VCUShiftPostionValid 0;
BA_ "GenSigInvalidValue" SG_ 821 VCUShiftPostionValid "NA";
BA_ "GenSigCycleTime" SG_ 821 VcuVehErrInfo 100;
BA_ "GenSigSendType" SG_ 821 VcuVehErrInfo 0;
BA_ "GenSigStartValue" SG_ 821 VcuVehErrInfo 0;
BA_ "GenSigInvalidValue" SG_ 821 VcuVehErrInfo "NA";
BA_ "GenSigCycleTime" SG_ 821 VIUFL_DeviceVerifyResult 100;
BA_ "GenSigSendType" SG_ 821 VIUFL_DeviceVerifyResult 0;
BA_ "GenSigStartValue" SG_ 821 VIUFL_DeviceVerifyResult 0;
BA_ "GenSigInvalidValue" SG_ 821 VIUFL_DeviceVerifyResult 0;
BA_ "GenSigCycleTime" SG_ 821 VcuOffRoadCrpSts 100;
BA_ "GenSigSendType" SG_ 821 VcuOffRoadCrpSts 0;
BA_ "GenSigStartValue" SG_ 821 VcuOffRoadCrpSts 0;
BA_ "GenSigInvalidValue" SG_ 821 VcuOffRoadCrpSts 0;
BA_ "GenSigCycleTime" SG_ 821 BCMALLDoorLockSwt 100;
BA_ "GenSigSendType" SG_ 821 BCMALLDoorLockSwt 0;
BA_ "GenSigStartValue" SG_ 821 BCMALLDoorLockSwt 0;
BA_ "GenSigInvalidValue" SG_ 821 BCMALLDoorLockSwt 0;
BA_ "GenSigCycleTime" SG_ 822 CcsmFrntEDLSetSwt 100;
BA_ "GenSigSendType" SG_ 822 CcsmFrntEDLSetSwt 0;
BA_ "GenSigStartValue" SG_ 822 CcsmFrntEDLSetSwt 0;
BA_ "GenSigInvalidValue" SG_ 822 CcsmFrntEDLSetSwt 0;
BA_ "GenSigCycleTime" SG_ 822 CcsmReEDLSetSwt 100;
BA_ "GenSigSendType" SG_ 822 CcsmReEDLSetSwt 0;
BA_ "GenSigStartValue" SG_ 822 CcsmReEDLSetSwt 0;
BA_ "GenSigInvalidValue" SG_ 822 CcsmReEDLSetSwt 0;
BA_ "GenSigCycleTime" SG_ 822 CcsmEDLBtnStuckFlg 100;
BA_ "GenSigSendType" SG_ 822 CcsmEDLBtnStuckFlg 0;
BA_ "GenSigStartValue" SG_ 822 CcsmEDLBtnStuckFlg 0;
BA_ "GenSigInvalidValue" SG_ 822 CcsmEDLBtnStuckFlg 0;
BA_ "GenSigCycleTime" SG_ 854 HU_FLHighSpeakerDelaySET 100;
BA_ "GenSigSendType" SG_ 854 HU_FLHighSpeakerDelaySET 0;
BA_ "GenSigStartValue" SG_ 854 HU_FLHighSpeakerDelaySET 0;
BA_ "GenSigInvalidValue" SG_ 854 HU_FLHighSpeakerDelaySET 0;
BA_ "GenSigCycleTime" SG_ 854 HU_FLHighSpeakerVolSET 100;
BA_ "GenSigSendType" SG_ 854 HU_FLHighSpeakerVolSET 0;
BA_ "GenSigStartValue" SG_ 854 HU_FLHighSpeakerVolSET 31;
BA_ "GenSigInvalidValue" SG_ 854 HU_FLHighSpeakerVolSET 31;
BA_ "GenSigCycleTime" SG_ 854 HU_FLMidSpeakerDelaySET 100;
BA_ "GenSigSendType" SG_ 854 HU_FLMidSpeakerDelaySET 0;
BA_ "GenSigStartValue" SG_ 854 HU_FLMidSpeakerDelaySET 0;
BA_ "GenSigInvalidValue" SG_ 854 HU_FLMidSpeakerDelaySET 0;
BA_ "GenSigCycleTime" SG_ 854 HU_FLMidSpeakerVolSET 100;
BA_ "GenSigSendType" SG_ 854 HU_FLMidSpeakerVolSET 0;
BA_ "GenSigStartValue" SG_ 854 HU_FLMidSpeakerVolSET 31;
BA_ "GenSigInvalidValue" SG_ 854 HU_FLMidSpeakerVolSET 31;
BA_ "GenSigCycleTime" SG_ 854 HU_FRHighSpeakerDelaySET 100;
BA_ "GenSigSendType" SG_ 854 HU_FRHighSpeakerDelaySET 0;
BA_ "GenSigStartValue" SG_ 854 HU_FRHighSpeakerDelaySET 0;
BA_ "GenSigInvalidValue" SG_ 854 HU_FRHighSpeakerDelaySET 0;
BA_ "GenSigCycleTime" SG_ 854 HU_FRHighSpeakerVolSET 100;
BA_ "GenSigSendType" SG_ 854 HU_FRHighSpeakerVolSET 0;
BA_ "GenSigStartValue" SG_ 854 HU_FRHighSpeakerVolSET 31;
BA_ "GenSigInvalidValue" SG_ 854 HU_FRHighSpeakerVolSET 31;
BA_ "GenSigCycleTime" SG_ 854 HU_FRMidSpeakerDelaySET 100;
BA_ "GenSigSendType" SG_ 854 HU_FRMidSpeakerDelaySET 0;
BA_ "GenSigStartValue" SG_ 854 HU_FRMidSpeakerDelaySET 0;
BA_ "GenSigInvalidValue" SG_ 854 HU_FRMidSpeakerDelaySET 0;
BA_ "GenSigCycleTime" SG_ 854 HU_FRMidSpeakerVolSET 100;
BA_ "GenSigSendType" SG_ 854 HU_FRMidSpeakerVolSET 0;
BA_ "GenSigStartValue" SG_ 854 HU_FRMidSpeakerVolSET 31;
BA_ "GenSigInvalidValue" SG_ 854 HU_FRMidSpeakerVolSET 31;
BA_ "GenSigCycleTime" SG_ 854 HUFLPositionDelaySET 100;
BA_ "GenSigSendType" SG_ 854 HUFLPositionDelaySET 0;
BA_ "GenSigStartValue" SG_ 854 HUFLPositionDelaySET 0;
BA_ "GenSigInvalidValue" SG_ 854 HUFLPositionDelaySET 0;
BA_ "GenSigCycleTime" SG_ 854 HUFLPositionVolSET 100;
BA_ "GenSigSendType" SG_ 854 HUFLPositionVolSET 0;
BA_ "GenSigStartValue" SG_ 854 HUFLPositionVolSET 0;
BA_ "GenSigInvalidValue" SG_ 854 HUFLPositionVolSET 0;
BA_ "GenSigCycleTime" SG_ 854 HUFRPositionDelaySET 100;
BA_ "GenSigSendType" SG_ 854 HUFRPositionDelaySET 0;
BA_ "GenSigStartValue" SG_ 854 HUFRPositionDelaySET 0;
BA_ "GenSigInvalidValue" SG_ 854 HUFRPositionDelaySET 0;
BA_ "GenSigCycleTime" SG_ 854 HUFRPositionVolSET 100;
BA_ "GenSigSendType" SG_ 854 HUFRPositionVolSET 0;
BA_ "GenSigStartValue" SG_ 854 HUFRPositionVolSET 0;
BA_ "GenSigInvalidValue" SG_ 854 HUFRPositionVolSET 0;
BA_ "GenSigCycleTime" SG_ 854 HU_AlarmVolSET 100;
BA_ "GenSigSendType" SG_ 854 HU_AlarmVolSET 0;
BA_ "GenSigStartValue" SG_ 854 HU_AlarmVolSET 0;
BA_ "GenSigInvalidValue" SG_ 854 HU_AlarmVolSET 0;
BA_ "GenSigCycleTime" SG_ 854 HU_AvasVolSET 100;
BA_ "GenSigSendType" SG_ 854 HU_AvasVolSET 0;
BA_ "GenSigStartValue" SG_ 854 HU_AvasVolSET 0;
BA_ "GenSigInvalidValue" SG_ 854 HU_AvasVolSET 0;
BA_ "GenSigCycleTime" SG_ 854 HU_CenterSpeakerDelaySET 100;
BA_ "GenSigSendType" SG_ 854 HU_CenterSpeakerDelaySET 0;
BA_ "GenSigStartValue" SG_ 854 HU_CenterSpeakerDelaySET 0;
BA_ "GenSigInvalidValue" SG_ 854 HU_CenterSpeakerDelaySET 0;
BA_ "GenSigCycleTime" SG_ 854 HU_CenterSpeakerVolSET 100;
BA_ "GenSigSendType" SG_ 854 HU_CenterSpeakerVolSET 0;
BA_ "GenSigStartValue" SG_ 854 HU_CenterSpeakerVolSET 31;
BA_ "GenSigInvalidValue" SG_ 854 HU_CenterSpeakerVolSET 31;
BA_ "GenSigCycleTime" SG_ 854 HU_CustomEffectSET 100;
BA_ "GenSigSendType" SG_ 854 HU_CustomEffectSET 0;
BA_ "GenSigStartValue" SG_ 854 HU_CustomEffectSET 0;
BA_ "GenSigInvalidValue" SG_ 854 HU_CustomEffectSET 0;
BA_ "GenSigCycleTime" SG_ 854 HU_CustomEQ125SET 100;
BA_ "GenSigSendType" SG_ 854 HU_CustomEQ125SET 0;
BA_ "GenSigStartValue" SG_ 854 HU_CustomEQ125SET 0;
BA_ "GenSigInvalidValue" SG_ 854 HU_CustomEQ125SET 0;
BA_ "GenSigCycleTime" SG_ 854 HU_CustomEQ16KSET 100;
BA_ "GenSigSendType" SG_ 854 HU_CustomEQ16KSET 0;
BA_ "GenSigStartValue" SG_ 854 HU_CustomEQ16KSET 0;
BA_ "GenSigInvalidValue" SG_ 854 HU_CustomEQ16KSET 0;
BA_ "GenSigCycleTime" SG_ 854 HU_CustomEQ1KSET 100;
BA_ "GenSigSendType" SG_ 854 HU_CustomEQ1KSET 0;
BA_ "GenSigStartValue" SG_ 854 HU_CustomEQ1KSET 0;
BA_ "GenSigInvalidValue" SG_ 854 HU_CustomEQ1KSET 0;
BA_ "GenSigCycleTime" SG_ 854 HU_CustomEQ250SET 100;
BA_ "GenSigSendType" SG_ 854 HU_CustomEQ250SET 0;
BA_ "GenSigStartValue" SG_ 854 HU_CustomEQ250SET 0;
BA_ "GenSigInvalidValue" SG_ 854 HU_CustomEQ250SET 0;
BA_ "GenSigCycleTime" SG_ 854 HU_CustomEQ2KSET 100;
BA_ "GenSigSendType" SG_ 854 HU_CustomEQ2KSET 0;
BA_ "GenSigStartValue" SG_ 854 HU_CustomEQ2KSET 0;
BA_ "GenSigInvalidValue" SG_ 854 HU_CustomEQ2KSET 0;
BA_ "GenSigCycleTime" SG_ 854 HU_CustomEQ4KSET 100;
BA_ "GenSigSendType" SG_ 854 HU_CustomEQ4KSET 0;
BA_ "GenSigStartValue" SG_ 854 HU_CustomEQ4KSET 0;
BA_ "GenSigInvalidValue" SG_ 854 HU_CustomEQ4KSET 0;
BA_ "GenSigCycleTime" SG_ 854 HU_CustomEQ500SET 100;
BA_ "GenSigSendType" SG_ 854 HU_CustomEQ500SET 0;
BA_ "GenSigStartValue" SG_ 854 HU_CustomEQ500SET 0;
BA_ "GenSigInvalidValue" SG_ 854 HU_CustomEQ500SET 0;
BA_ "GenSigCycleTime" SG_ 854 HU_CustomEQ62SET 100;
BA_ "GenSigSendType" SG_ 854 HU_CustomEQ62SET 0;
BA_ "GenSigStartValue" SG_ 854 HU_CustomEQ62SET 0;
BA_ "GenSigInvalidValue" SG_ 854 HU_CustomEQ62SET 0;
BA_ "GenSigCycleTime" SG_ 854 HU_CustomEQ8KSET 100;
BA_ "GenSigSendType" SG_ 854 HU_CustomEQ8KSET 0;
BA_ "GenSigStartValue" SG_ 854 HU_CustomEQ8KSET 0;
BA_ "GenSigInvalidValue" SG_ 854 HU_CustomEQ8KSET 0;
BA_ "GenSigCycleTime" SG_ 854 HU_FLLowSpeakerDelaySET 100;
BA_ "GenSigSendType" SG_ 854 HU_FLLowSpeakerDelaySET 0;
BA_ "GenSigStartValue" SG_ 854 HU_FLLowSpeakerDelaySET 0;
BA_ "GenSigInvalidValue" SG_ 854 HU_FLLowSpeakerDelaySET 0;
BA_ "GenSigCycleTime" SG_ 854 HU_FLLowSpeakerVolSET 100;
BA_ "GenSigSendType" SG_ 854 HU_FLLowSpeakerVolSET 0;
BA_ "GenSigStartValue" SG_ 854 HU_FLLowSpeakerVolSET 31;
BA_ "GenSigInvalidValue" SG_ 854 HU_FLLowSpeakerVolSET 31;
BA_ "GenSigCycleTime" SG_ 854 HU_FLMidHighSpeakerDelaySET 100;
BA_ "GenSigSendType" SG_ 854 HU_FLMidHighSpeakerDelaySET 0;
BA_ "GenSigStartValue" SG_ 854 HU_FLMidHighSpeakerDelaySET 0;
BA_ "GenSigInvalidValue" SG_ 854 HU_FLMidHighSpeakerDelaySET 0;
BA_ "GenSigCycleTime" SG_ 854 HU_FLMidHighSpeakerVolSET 100;
BA_ "GenSigSendType" SG_ 854 HU_FLMidHighSpeakerVolSET 0;
BA_ "GenSigStartValue" SG_ 854 HU_FLMidHighSpeakerVolSET 31;
BA_ "GenSigInvalidValue" SG_ 854 HU_FLMidHighSpeakerVolSET 31;
BA_ "GenSigCycleTime" SG_ 854 HU_FLTopSpeakerDelaySET 100;
BA_ "GenSigSendType" SG_ 854 HU_FLTopSpeakerDelaySET 0;
BA_ "GenSigStartValue" SG_ 854 HU_FLTopSpeakerDelaySET 0;
BA_ "GenSigInvalidValue" SG_ 854 HU_FLTopSpeakerDelaySET 0;
BA_ "GenSigCycleTime" SG_ 854 HU_FLTopSpeakerVolSET 100;
BA_ "GenSigSendType" SG_ 854 HU_FLTopSpeakerVolSET 0;
BA_ "GenSigStartValue" SG_ 854 HU_FLTopSpeakerVolSET 31;
BA_ "GenSigInvalidValue" SG_ 854 HU_FLTopSpeakerVolSET 31;
BA_ "GenSigCycleTime" SG_ 854 HU_FRBalanceSET 100;
BA_ "GenSigSendType" SG_ 854 HU_FRBalanceSET 0;
BA_ "GenSigStartValue" SG_ 854 HU_FRBalanceSET 0;
BA_ "GenSigInvalidValue" SG_ 854 HU_FRBalanceSET 0;
BA_ "GenSigCycleTime" SG_ 854 HU_FRLowSpeakerDelaySET 100;
BA_ "GenSigSendType" SG_ 854 HU_FRLowSpeakerDelaySET 0;
BA_ "GenSigStartValue" SG_ 854 HU_FRLowSpeakerDelaySET 0;
BA_ "GenSigInvalidValue" SG_ 854 HU_FRLowSpeakerDelaySET 0;
BA_ "GenSigCycleTime" SG_ 854 HU_FRLowSpeakerVolSET 100;
BA_ "GenSigSendType" SG_ 854 HU_FRLowSpeakerVolSET 0;
BA_ "GenSigStartValue" SG_ 854 HU_FRLowSpeakerVolSET 31;
BA_ "GenSigInvalidValue" SG_ 854 HU_FRLowSpeakerVolSET 31;
BA_ "GenSigCycleTime" SG_ 854 HU_FRMidHighSpeakerDelaySET 100;
BA_ "GenSigSendType" SG_ 854 HU_FRMidHighSpeakerDelaySET 0;
BA_ "GenSigStartValue" SG_ 854 HU_FRMidHighSpeakerDelaySET 0;
BA_ "GenSigInvalidValue" SG_ 854 HU_FRMidHighSpeakerDelaySET 0;
BA_ "GenSigCycleTime" SG_ 854 HU_FRMidHighSpeakerVolSET 100;
BA_ "GenSigSendType" SG_ 854 HU_FRMidHighSpeakerVolSET 0;
BA_ "GenSigStartValue" SG_ 854 HU_FRMidHighSpeakerVolSET 31;
BA_ "GenSigInvalidValue" SG_ 854 HU_FRMidHighSpeakerVolSET 31;
BA_ "GenSigCycleTime" SG_ 854 HU_FRTopSpeakerDelaySET 100;
BA_ "GenSigSendType" SG_ 854 HU_FRTopSpeakerDelaySET 0;
BA_ "GenSigStartValue" SG_ 854 HU_FRTopSpeakerDelaySET 0;
BA_ "GenSigInvalidValue" SG_ 854 HU_FRTopSpeakerDelaySET 0;
BA_ "GenSigCycleTime" SG_ 854 HU_FRTopSpeakerVolSET 100;
BA_ "GenSigSendType" SG_ 854 HU_FRTopSpeakerVolSET 0;
BA_ "GenSigStartValue" SG_ 854 HU_FRTopSpeakerVolSET 31;
BA_ "GenSigInvalidValue" SG_ 854 HU_FRTopSpeakerVolSET 31;
BA_ "GenSigCycleTime" SG_ 854 HU_KTVMUTESET 100;
BA_ "GenSigSendType" SG_ 854 HU_KTVMUTESET 0;
BA_ "GenSigStartValue" SG_ 854 HU_KTVMUTESET 0;
BA_ "GenSigInvalidValue" SG_ 854 HU_KTVMUTESET 0;
BA_ "GenSigCycleTime" SG_ 854 HU_KTVVolSET 100;
BA_ "GenSigSendType" SG_ 854 HU_KTVVolSET 0;
BA_ "GenSigStartValue" SG_ 854 HU_KTVVolSET 31;
BA_ "GenSigInvalidValue" SG_ 854 HU_KTVVolSET 31;
BA_ "GenSigCycleTime" SG_ 854 HU_LRBalanceSET 100;
BA_ "GenSigSendType" SG_ 854 HU_LRBalanceSET 0;
BA_ "GenSigStartValue" SG_ 854 HU_LRBalanceSET 0;
BA_ "GenSigInvalidValue" SG_ 854 HU_LRBalanceSET 0;
BA_ "GenSigCycleTime" SG_ 854 HU_MediaMUTESET 100;
BA_ "GenSigSendType" SG_ 854 HU_MediaMUTESET 0;
BA_ "GenSigStartValue" SG_ 854 HU_MediaMUTESET 0;
BA_ "GenSigInvalidValue" SG_ 854 HU_MediaMUTESET 0;
BA_ "GenSigCycleTime" SG_ 854 HU_MediaVolSET 100;
BA_ "GenSigSendType" SG_ 854 HU_MediaVolSET 0;
BA_ "GenSigStartValue" SG_ 854 HU_MediaVolSET 31;
BA_ "GenSigInvalidValue" SG_ 854 HU_MediaVolSET 31;
BA_ "GenSigCycleTime" SG_ 854 HU_MUTESET 100;
BA_ "GenSigSendType" SG_ 854 HU_MUTESET 0;
BA_ "GenSigStartValue" SG_ 854 HU_MUTESET 0;
BA_ "GenSigInvalidValue" SG_ 854 HU_MUTESET 0;
BA_ "GenSigCycleTime" SG_ 854 HU_NaviMUTESET 100;
BA_ "GenSigSendType" SG_ 854 HU_NaviMUTESET 0;
BA_ "GenSigStartValue" SG_ 854 HU_NaviMUTESET 0;
BA_ "GenSigInvalidValue" SG_ 854 HU_NaviMUTESET 0;
BA_ "GenSigCycleTime" SG_ 854 HU_NAVIVolSET 100;
BA_ "GenSigSendType" SG_ 854 HU_NAVIVolSET 0;
BA_ "GenSigStartValue" SG_ 854 HU_NAVIVolSET 31;
BA_ "GenSigInvalidValue" SG_ 854 HU_NAVIVolSET 31;
BA_ "GenSigCycleTime" SG_ 854 HU_OutMUTESET 100;
BA_ "GenSigSendType" SG_ 854 HU_OutMUTESET 0;
BA_ "GenSigStartValue" SG_ 854 HU_OutMUTESET 0;
BA_ "GenSigInvalidValue" SG_ 854 HU_OutMUTESET 0;
BA_ "GenSigCycleTime" SG_ 854 HU_OUTVolSET 100;
BA_ "GenSigSendType" SG_ 854 HU_OUTVolSET 0;
BA_ "GenSigStartValue" SG_ 854 HU_OUTVolSET 31;
BA_ "GenSigInvalidValue" SG_ 854 HU_OUTVolSET 31;
BA_ "GenSigCycleTime" SG_ 854 HU_PerfessiionalEQ100SET 100;
BA_ "GenSigSendType" SG_ 854 HU_PerfessiionalEQ100SET 0;
BA_ "GenSigStartValue" SG_ 854 HU_PerfessiionalEQ100SET 0;
BA_ "GenSigInvalidValue" SG_ 854 HU_PerfessiionalEQ100SET 0;
BA_ "GenSigCycleTime" SG_ 854 HU_PerfessiionalEQ500SET 100;
BA_ "GenSigSendType" SG_ 854 HU_PerfessiionalEQ500SET 0;
BA_ "GenSigStartValue" SG_ 854 HU_PerfessiionalEQ500SET 0;
BA_ "GenSigInvalidValue" SG_ 854 HU_PerfessiionalEQ500SET 0;
BA_ "GenSigCycleTime" SG_ 854 HU_PerfessiionalEQ6KSET 100;
BA_ "GenSigSendType" SG_ 854 HU_PerfessiionalEQ6KSET 0;
BA_ "GenSigStartValue" SG_ 854 HU_PerfessiionalEQ6KSET 0;
BA_ "GenSigInvalidValue" SG_ 854 HU_PerfessiionalEQ6KSET 0;
BA_ "GenSigCycleTime" SG_ 854 HU_RLLowHighSpeakerDelaySET 100;
BA_ "GenSigSendType" SG_ 854 HU_RLLowHighSpeakerDelaySET 0;
BA_ "GenSigStartValue" SG_ 854 HU_RLLowHighSpeakerDelaySET 0;
BA_ "GenSigInvalidValue" SG_ 854 HU_RLLowHighSpeakerDelaySET 0;
BA_ "GenSigCycleTime" SG_ 854 HU_RLLowHighSpeakerVolSET 100;
BA_ "GenSigSendType" SG_ 854 HU_RLLowHighSpeakerVolSET 0;
BA_ "GenSigStartValue" SG_ 854 HU_RLLowHighSpeakerVolSET 31;
BA_ "GenSigInvalidValue" SG_ 854 HU_RLLowHighSpeakerVolSET 31;
BA_ "GenSigCycleTime" SG_ 854 HU_RLSurroundSpeakerDelaySET 100;
BA_ "GenSigSendType" SG_ 854 HU_RLSurroundSpeakerDelaySET 0;
BA_ "GenSigStartValue" SG_ 854 HU_RLSurroundSpeakerDelaySET 0;
BA_ "GenSigInvalidValue" SG_ 854 HU_RLSurroundSpeakerDelaySET 0;
BA_ "GenSigCycleTime" SG_ 854 HU_RLSurroundSpeakerVolSET 100;
BA_ "GenSigSendType" SG_ 854 HU_RLSurroundSpeakerVolSET 0;
BA_ "GenSigStartValue" SG_ 854 HU_RLSurroundSpeakerVolSET 31;
BA_ "GenSigInvalidValue" SG_ 854 HU_RLSurroundSpeakerVolSET 31;
BA_ "GenSigCycleTime" SG_ 854 HU_RLTopSpeakerDelaySET 100;
BA_ "GenSigSendType" SG_ 854 HU_RLTopSpeakerDelaySET 0;
BA_ "GenSigStartValue" SG_ 854 HU_RLTopSpeakerDelaySET 0;
BA_ "GenSigInvalidValue" SG_ 854 HU_RLTopSpeakerDelaySET 0;
BA_ "GenSigCycleTime" SG_ 854 HU_RLTopSpeakerVolSET 100;
BA_ "GenSigSendType" SG_ 854 HU_RLTopSpeakerVolSET 0;
BA_ "GenSigStartValue" SG_ 854 HU_RLTopSpeakerVolSET 31;
BA_ "GenSigInvalidValue" SG_ 854 HU_RLTopSpeakerVolSET 31;
BA_ "GenSigCycleTime" SG_ 854 HU_RNCEnableSET 100;
BA_ "GenSigSendType" SG_ 854 HU_RNCEnableSET 0;
BA_ "GenSigStartValue" SG_ 854 HU_RNCEnableSET 0;
BA_ "GenSigInvalidValue" SG_ 854 HU_RNCEnableSET 0;
BA_ "GenSigCycleTime" SG_ 854 HU_RRLowHighSpeakerDelaySET 100;
BA_ "GenSigSendType" SG_ 854 HU_RRLowHighSpeakerDelaySET 0;
BA_ "GenSigStartValue" SG_ 854 HU_RRLowHighSpeakerDelaySET 0;
BA_ "GenSigInvalidValue" SG_ 854 HU_RRLowHighSpeakerDelaySET 0;
BA_ "GenSigCycleTime" SG_ 854 HU_RRLowHighSpeakerVolSET 100;
BA_ "GenSigSendType" SG_ 854 HU_RRLowHighSpeakerVolSET 0;
BA_ "GenSigStartValue" SG_ 854 HU_RRLowHighSpeakerVolSET 31;
BA_ "GenSigInvalidValue" SG_ 854 HU_RRLowHighSpeakerVolSET 31;
BA_ "GenSigCycleTime" SG_ 854 HU_RRSurroundSpeakerDelaySET 100;
BA_ "GenSigSendType" SG_ 854 HU_RRSurroundSpeakerDelaySET 0;
BA_ "GenSigStartValue" SG_ 854 HU_RRSurroundSpeakerDelaySET 0;
BA_ "GenSigInvalidValue" SG_ 854 HU_RRSurroundSpeakerDelaySET 0;
BA_ "GenSigCycleTime" SG_ 854 HU_RRSurroundSpeakerVolSET 100;
BA_ "GenSigSendType" SG_ 854 HU_RRSurroundSpeakerVolSET 0;
BA_ "GenSigStartValue" SG_ 854 HU_RRSurroundSpeakerVolSET 31;
BA_ "GenSigInvalidValue" SG_ 854 HU_RRSurroundSpeakerVolSET 31;
BA_ "GenSigCycleTime" SG_ 854 HU_RRTopSpeakerDelaySET 100;
BA_ "GenSigSendType" SG_ 854 HU_RRTopSpeakerDelaySET 0;
BA_ "GenSigStartValue" SG_ 854 HU_RRTopSpeakerDelaySET 0;
BA_ "GenSigInvalidValue" SG_ 854 HU_RRTopSpeakerDelaySET 0;
BA_ "GenSigCycleTime" SG_ 854 HU_RRTopSpeakerVolSET 100;
BA_ "GenSigSendType" SG_ 854 HU_RRTopSpeakerVolSET 0;
BA_ "GenSigStartValue" SG_ 854 HU_RRTopSpeakerVolSET 31;
BA_ "GenSigInvalidValue" SG_ 854 HU_RRTopSpeakerVolSET 31;
BA_ "GenSigCycleTime" SG_ 854 HU_SoundEffectSET 100;
BA_ "GenSigSendType" SG_ 854 HU_SoundEffectSET 0;
BA_ "GenSigStartValue" SG_ 854 HU_SoundEffectSET 0;
BA_ "GenSigInvalidValue" SG_ 854 HU_SoundEffectSET 0;
BA_ "GenSigCycleTime" SG_ 854 HU_SoundFieldSET 100;
BA_ "GenSigSendType" SG_ 854 HU_SoundFieldSET 0;
BA_ "GenSigStartValue" SG_ 854 HU_SoundFieldSET 0;
BA_ "GenSigInvalidValue" SG_ 854 HU_SoundFieldSET 0;
BA_ "GenSigCycleTime" SG_ 854 HU_SubSpeakerDelaySET 100;
BA_ "GenSigSendType" SG_ 854 HU_SubSpeakerDelaySET 0;
BA_ "GenSigStartValue" SG_ 854 HU_SubSpeakerDelaySET 0;
BA_ "GenSigInvalidValue" SG_ 854 HU_SubSpeakerDelaySET 0;
BA_ "GenSigCycleTime" SG_ 854 HU_SubSpeakerVolSET 100;
BA_ "GenSigSendType" SG_ 854 HU_SubSpeakerVolSET 0;
BA_ "GenSigStartValue" SG_ 854 HU_SubSpeakerVolSET 31;
BA_ "GenSigInvalidValue" SG_ 854 HU_SubSpeakerVolSET 31;
BA_ "GenSigCycleTime" SG_ 854 HU_SystemMUTESET 100;
BA_ "GenSigSendType" SG_ 854 HU_SystemMUTESET 0;
BA_ "GenSigStartValue" SG_ 854 HU_SystemMUTESET 0;
BA_ "GenSigInvalidValue" SG_ 854 HU_SystemMUTESET 0;
BA_ "GenSigCycleTime" SG_ 854 HU_SystemVolSET 100;
BA_ "GenSigSendType" SG_ 854 HU_SystemVolSET 0;
BA_ "GenSigStartValue" SG_ 854 HU_SystemVolSET 31;
BA_ "GenSigInvalidValue" SG_ 854 HU_SystemVolSET 31;
BA_ "GenSigCycleTime" SG_ 854 HU_TelBcallMUTESET 100;
BA_ "GenSigSendType" SG_ 854 HU_TelBcallMUTESET 0;
BA_ "GenSigStartValue" SG_ 854 HU_TelBcallMUTESET 0;
BA_ "GenSigInvalidValue" SG_ 854 HU_TelBcallMUTESET 0;
BA_ "GenSigCycleTime" SG_ 854 HU_TELBCALLVolSET 100;
BA_ "GenSigSendType" SG_ 854 HU_TELBCALLVolSET 0;
BA_ "GenSigStartValue" SG_ 854 HU_TELBCALLVolSET 31;
BA_ "GenSigInvalidValue" SG_ 854 HU_TELBCALLVolSET 31;
BA_ "GenSigCycleTime" SG_ 854 HU_TTSVRMUTESET 100;
BA_ "GenSigSendType" SG_ 854 HU_TTSVRMUTESET 0;
BA_ "GenSigStartValue" SG_ 854 HU_TTSVRMUTESET 0;
BA_ "GenSigInvalidValue" SG_ 854 HU_TTSVRMUTESET 0;
BA_ "GenSigCycleTime" SG_ 854 HU_TTSVRVolSET 100;
BA_ "GenSigSendType" SG_ 854 HU_TTSVRVolSET 0;
BA_ "GenSigStartValue" SG_ 854 HU_TTSVRVolSET 31;
BA_ "GenSigInvalidValue" SG_ 854 HU_TTSVRVolSET 31;
BA_ "GenSigCycleTime" SG_ 854 HU_TurnLightInOrOutSET 100;
BA_ "GenSigSendType" SG_ 854 HU_TurnLightInOrOutSET 0;
BA_ "GenSigStartValue" SG_ 854 HU_TurnLightInOrOutSET 0;
BA_ "GenSigInvalidValue" SG_ 854 HU_TurnLightInOrOutSET 0;
BA_ "GenSigCycleTime" SG_ 854 HU_TurnLightVolSET 100;
BA_ "GenSigSendType" SG_ 854 HU_TurnLightVolSET 0;
BA_ "GenSigStartValue" SG_ 854 HU_TurnLightVolSET 0;
BA_ "GenSigInvalidValue" SG_ 854 HU_TurnLightVolSET 0;
BA_ "GenSigCycleTime" SG_ 854 HU_VOLSpeedLevEnableSET 100;
BA_ "GenSigSendType" SG_ 854 HU_VOLSpeedLevEnableSET 0;
BA_ "GenSigStartValue" SG_ 854 HU_VOLSpeedLevEnableSET 0;
BA_ "GenSigInvalidValue" SG_ 854 HU_VOLSpeedLevEnableSET 0;
BA_ "GenSigCycleTime" SG_ 854 HUBeosonicModeSet 100;
BA_ "GenSigSendType" SG_ 854 HUBeosonicModeSet 0;
BA_ "GenSigStartValue" SG_ 854 HUBeosonicModeSet 0;
BA_ "GenSigInvalidValue" SG_ 854 HUBeosonicModeSet 0;
BA_ "GenSigCycleTime" SG_ 854 HUBeosonicXSet 100;
BA_ "GenSigSendType" SG_ 854 HUBeosonicXSet 0;
BA_ "GenSigStartValue" SG_ 854 HUBeosonicXSet 0;
BA_ "GenSigInvalidValue" SG_ 854 HUBeosonicXSet 0;
BA_ "GenSigCycleTime" SG_ 854 HUBeosonicYSet 100;
BA_ "GenSigSendType" SG_ 854 HUBeosonicYSet 0;
BA_ "GenSigStartValue" SG_ 854 HUBeosonicYSet 0;
BA_ "GenSigInvalidValue" SG_ 854 HUBeosonicYSet 0;
BA_ "GenSigCycleTime" SG_ 854 HUCenterPositionDelaySET 100;
BA_ "GenSigSendType" SG_ 854 HUCenterPositionDelaySET 0;
BA_ "GenSigStartValue" SG_ 854 HUCenterPositionDelaySET 0;
BA_ "GenSigInvalidValue" SG_ 854 HUCenterPositionDelaySET 0;
BA_ "GenSigCycleTime" SG_ 854 HUCenterPositionVolSET 100;
BA_ "GenSigSendType" SG_ 854 HUCenterPositionVolSET 0;
BA_ "GenSigStartValue" SG_ 854 HUCenterPositionVolSET 0;
BA_ "GenSigInvalidValue" SG_ 854 HUCenterPositionVolSET 0;
BA_ "GenSigCycleTime" SG_ 854 HUCustomEQ2500SET 100;
BA_ "GenSigSendType" SG_ 854 HUCustomEQ2500SET 0;
BA_ "GenSigStartValue" SG_ 854 HUCustomEQ2500SET 0;
BA_ "GenSigInvalidValue" SG_ 854 HUCustomEQ2500SET 0;
BA_ "GenSigCycleTime" SG_ 854 HUCustomEQ315SET 100;
BA_ "GenSigSendType" SG_ 854 HUCustomEQ315SET 0;
BA_ "GenSigStartValue" SG_ 854 HUCustomEQ315SET 0;
BA_ "GenSigInvalidValue" SG_ 854 HUCustomEQ315SET 0;
BA_ "GenSigCycleTime" SG_ 854 HUCustomEQ50SET 100;
BA_ "GenSigSendType" SG_ 854 HUCustomEQ50SET 0;
BA_ "GenSigStartValue" SG_ 854 HUCustomEQ50SET 0;
BA_ "GenSigInvalidValue" SG_ 854 HUCustomEQ50SET 0;
BA_ "GenSigCycleTime" SG_ 854 HUCustomEQ6000SET 100;
BA_ "GenSigSendType" SG_ 854 HUCustomEQ6000SET 0;
BA_ "GenSigStartValue" SG_ 854 HUCustomEQ6000SET 0;
BA_ "GenSigInvalidValue" SG_ 854 HUCustomEQ6000SET 0;
BA_ "GenSigCycleTime" SG_ 854 HUCustomEQ800SET 100;
BA_ "GenSigSendType" SG_ 854 HUCustomEQ800SET 0;
BA_ "GenSigStartValue" SG_ 854 HUCustomEQ800SET 0;
BA_ "GenSigInvalidValue" SG_ 854 HUCustomEQ800SET 0;
BA_ "GenSigCycleTime" SG_ 854 HUFLTopPositionDelaySET 100;
BA_ "GenSigSendType" SG_ 854 HUFLTopPositionDelaySET 0;
BA_ "GenSigStartValue" SG_ 854 HUFLTopPositionDelaySET 0;
BA_ "GenSigInvalidValue" SG_ 854 HUFLTopPositionDelaySET 0;
BA_ "GenSigCycleTime" SG_ 854 HUFLTopPositionVolSET 100;
BA_ "GenSigSendType" SG_ 854 HUFLTopPositionVolSET 0;
BA_ "GenSigStartValue" SG_ 854 HUFLTopPositionVolSET 0;
BA_ "GenSigInvalidValue" SG_ 854 HUFLTopPositionVolSET 0;
BA_ "GenSigCycleTime" SG_ 854 HUFRTopPositionDelaySET 100;
BA_ "GenSigSendType" SG_ 854 HUFRTopPositionDelaySET 0;
BA_ "GenSigStartValue" SG_ 854 HUFRTopPositionDelaySET 0;
BA_ "GenSigInvalidValue" SG_ 854 HUFRTopPositionDelaySET 0;
BA_ "GenSigCycleTime" SG_ 854 HUSoundSourceType 100;
BA_ "GenSigSendType" SG_ 854 HUSoundSourceType 0;
BA_ "GenSigStartValue" SG_ 854 HUSoundSourceType 0;
BA_ "GenSigInvalidValue" SG_ 854 HUSoundSourceType 0;
BA_ "GenSigCycleTime" SG_ 854 HUTMCenterPositionEQ15000HzSet 100;
BA_ "GenSigSendType" SG_ 854 HUTMCenterPositionEQ15000HzSet 0;
BA_ "GenSigStartValue" SG_ 854 HUTMCenterPositionEQ15000HzSet 0;
BA_ "GenSigInvalidValue" SG_ 854 HUTMCenterPositionEQ15000HzSet 0;
BA_ "GenSigCycleTime" SG_ 854 HUTMCenterPositionEQ800HzSet 100;
BA_ "GenSigSendType" SG_ 854 HUTMCenterPositionEQ800HzSet 0;
BA_ "GenSigStartValue" SG_ 854 HUTMCenterPositionEQ800HzSet 0;
BA_ "GenSigInvalidValue" SG_ 854 HUTMCenterPositionEQ800HzSet 0;
BA_ "GenSigCycleTime" SG_ 854 HUTMFLPositionEQ100HzSet 100;
BA_ "GenSigSendType" SG_ 854 HUTMFLPositionEQ100HzSet 0;
BA_ "GenSigStartValue" SG_ 854 HUTMFLPositionEQ100HzSet 0;
BA_ "GenSigInvalidValue" SG_ 854 HUTMFLPositionEQ100HzSet 0;
BA_ "GenSigCycleTime" SG_ 854 HUTMFLPositionEQ15000HzSet 100;
BA_ "GenSigSendType" SG_ 854 HUTMFLPositionEQ15000HzSet 0;
BA_ "GenSigStartValue" SG_ 854 HUTMFLPositionEQ15000HzSet 0;
BA_ "GenSigInvalidValue" SG_ 854 HUTMFLPositionEQ15000HzSet 0;
BA_ "GenSigCycleTime" SG_ 854 HUTMFLPositionEQ800HzSet 100;
BA_ "GenSigSendType" SG_ 854 HUTMFLPositionEQ800HzSet 0;
BA_ "GenSigStartValue" SG_ 854 HUTMFLPositionEQ800HzSet 0;
BA_ "GenSigInvalidValue" SG_ 854 HUTMFLPositionEQ800HzSet 0;
BA_ "GenSigCycleTime" SG_ 854 HUTMFLTopPositionEQ500HzSet 100;
BA_ "GenSigSendType" SG_ 854 HUTMFLTopPositionEQ500HzSet 0;
BA_ "GenSigStartValue" SG_ 854 HUTMFLTopPositionEQ500HzSet 0;
BA_ "GenSigInvalidValue" SG_ 854 HUTMFLTopPositionEQ500HzSet 0;
BA_ "GenSigCycleTime" SG_ 854 HUTMFRPositionEQ100HzSet 100;
BA_ "GenSigSendType" SG_ 854 HUTMFRPositionEQ100HzSet 0;
BA_ "GenSigStartValue" SG_ 854 HUTMFRPositionEQ100HzSet 0;
BA_ "GenSigInvalidValue" SG_ 854 HUTMFRPositionEQ100HzSet 0;
BA_ "GenSigCycleTime" SG_ 854 HUTMFRPositionEQ15000HzSet 100;
BA_ "GenSigSendType" SG_ 854 HUTMFRPositionEQ15000HzSet 0;
BA_ "GenSigStartValue" SG_ 854 HUTMFRPositionEQ15000HzSet 0;
BA_ "GenSigInvalidValue" SG_ 854 HUTMFRPositionEQ15000HzSet 0;
BA_ "GenSigCycleTime" SG_ 854 HUTMFRPositionEQ800HzSet 100;
BA_ "GenSigSendType" SG_ 854 HUTMFRPositionEQ800HzSet 0;
BA_ "GenSigStartValue" SG_ 854 HUTMFRPositionEQ800HzSet 0;
BA_ "GenSigInvalidValue" SG_ 854 HUTMFRPositionEQ800HzSet 0;
BA_ "GenSigCycleTime" SG_ 854 HUTMFRTopPositionEQ500HzSet 100;
BA_ "GenSigSendType" SG_ 854 HUTMFRTopPositionEQ500HzSet 0;
BA_ "GenSigStartValue" SG_ 854 HUTMFRTopPositionEQ500HzSet 0;
BA_ "GenSigInvalidValue" SG_ 854 HUTMFRTopPositionEQ500HzSet 0;
BA_ "GenSigCycleTime" SG_ 854 HUTMReverbSet 100;
BA_ "GenSigSendType" SG_ 854 HUTMReverbSet 0;
BA_ "GenSigStartValue" SG_ 854 HUTMReverbSet 0;
BA_ "GenSigInvalidValue" SG_ 854 HUTMReverbSet 0;
BA_ "GenSigCycleTime" SG_ 854 HUTMRLPositionEQ10000HzSet 100;
BA_ "GenSigSendType" SG_ 854 HUTMRLPositionEQ10000HzSet 0;
BA_ "GenSigStartValue" SG_ 854 HUTMRLPositionEQ10000HzSet 0;
BA_ "GenSigInvalidValue" SG_ 854 HUTMRLPositionEQ10000HzSet 0;
BA_ "GenSigCycleTime" SG_ 854 HUTMRLPositionEQ100HzSet 100;
BA_ "GenSigSendType" SG_ 854 HUTMRLPositionEQ100HzSet 0;
BA_ "GenSigStartValue" SG_ 854 HUTMRLPositionEQ100HzSet 0;
BA_ "GenSigInvalidValue" SG_ 854 HUTMRLPositionEQ100HzSet 0;
BA_ "GenSigCycleTime" SG_ 854 HUTMRLSurroundPositionEQ15000HzS 100;
BA_ "GenSigSendType" SG_ 854 HUTMRLSurroundPositionEQ15000HzS 0;
BA_ "GenSigStartValue" SG_ 854 HUTMRLSurroundPositionEQ15000HzS 0;
BA_ "GenSigInvalidValue" SG_ 854 HUTMRLSurroundPositionEQ15000HzS 0;
BA_ "SystemSignalLongSymbol" SG_ 854 HUTMRLSurroundPositionEQ15000HzS "HUTMRLSurroundPositionEQ15000HzSet";
BA_ "GenSigCycleTime" SG_ 854 HUTMRLSurroundPositionEQ800HzSet 100;
BA_ "GenSigSendType" SG_ 854 HUTMRLSurroundPositionEQ800HzSet 0;
BA_ "GenSigStartValue" SG_ 854 HUTMRLSurroundPositionEQ800HzSet 0;
BA_ "GenSigInvalidValue" SG_ 854 HUTMRLSurroundPositionEQ800HzSet 0;
BA_ "GenSigCycleTime" SG_ 854 HUTMRLTopPositionEQ500HzSet 100;
BA_ "GenSigSendType" SG_ 854 HUTMRLTopPositionEQ500HzSet 0;
BA_ "GenSigStartValue" SG_ 854 HUTMRLTopPositionEQ500HzSet 0;
BA_ "GenSigInvalidValue" SG_ 854 HUTMRLTopPositionEQ500HzSet 0;
BA_ "GenSigCycleTime" SG_ 854 HUTMRRPositionEQ10000HzSet 100;
BA_ "GenSigSendType" SG_ 854 HUTMRRPositionEQ10000HzSet 0;
BA_ "GenSigStartValue" SG_ 854 HUTMRRPositionEQ10000HzSet 0;
BA_ "GenSigInvalidValue" SG_ 854 HUTMRRPositionEQ10000HzSet 0;
BA_ "GenSigCycleTime" SG_ 854 HUTMRRPositionEQ100HzSet 100;
BA_ "GenSigSendType" SG_ 854 HUTMRRPositionEQ100HzSet 0;
BA_ "GenSigStartValue" SG_ 854 HUTMRRPositionEQ100HzSet 0;
BA_ "GenSigInvalidValue" SG_ 854 HUTMRRPositionEQ100HzSet 0;
BA_ "GenSigCycleTime" SG_ 854 HUTMRRSurroundPositionEQ15000HzS 100;
BA_ "GenSigSendType" SG_ 854 HUTMRRSurroundPositionEQ15000HzS 0;
BA_ "GenSigStartValue" SG_ 854 HUTMRRSurroundPositionEQ15000HzS 0;
BA_ "GenSigInvalidValue" SG_ 854 HUTMRRSurroundPositionEQ15000HzS 0;
BA_ "SystemSignalLongSymbol" SG_ 854 HUTMRRSurroundPositionEQ15000HzS "HUTMRRSurroundPositionEQ15000HzSet";
BA_ "GenSigCycleTime" SG_ 854 HUTMRRSurroundPositionEQ800HzSet 100;
BA_ "GenSigSendType" SG_ 854 HUTMRRSurroundPositionEQ800HzSet 0;
BA_ "GenSigStartValue" SG_ 854 HUTMRRSurroundPositionEQ800HzSet 0;
BA_ "GenSigInvalidValue" SG_ 854 HUTMRRSurroundPositionEQ800HzSet 0;
BA_ "GenSigCycleTime" SG_ 854 HUTMRRTopPositionEQ500HzSet 100;
BA_ "GenSigSendType" SG_ 854 HUTMRRTopPositionEQ500HzSet 0;
BA_ "GenSigStartValue" SG_ 854 HUTMRRTopPositionEQ500HzSet 0;
BA_ "GenSigInvalidValue" SG_ 854 HUTMRRTopPositionEQ500HzSet 0;
BA_ "GenSigCycleTime" SG_ 854 HUTMSubPositionEQ30HzSet 100;
BA_ "GenSigSendType" SG_ 854 HUTMSubPositionEQ30HzSet 0;
BA_ "GenSigStartValue" SG_ 854 HUTMSubPositionEQ30HzSet 0;
BA_ "GenSigInvalidValue" SG_ 854 HUTMSubPositionEQ30HzSet 0;
BA_ "GenSigCycleTime" SG_ 854 HUTMTransEnd 100;
BA_ "GenSigSendType" SG_ 854 HUTMTransEnd 0;
BA_ "GenSigStartValue" SG_ 854 HUTMTransEnd 0;
BA_ "GenSigInvalidValue" SG_ 854 HUTMTransEnd 0;
BA_ "GenSigCycleTime" SG_ 854 HUVOLSpeedLevChangeSET 100;
BA_ "GenSigSendType" SG_ 854 HUVOLSpeedLevChangeSET 0;
BA_ "GenSigStartValue" SG_ 854 HUVOLSpeedLevChangeSET 0;
BA_ "GenSigInvalidValue" SG_ 854 HUVOLSpeedLevChangeSET 0;
BA_ "GenSigCycleTime" SG_ 868 CdcEpbSetSwt_1 100;
BA_ "GenSigSendType" SG_ 868 CdcEpbSetSwt_1 0;
BA_ "GenSigStartValue" SG_ 868 CdcEpbSetSwt_1 0;
BA_ "GenSigInvalidValue" SG_ 868 CdcEpbSetSwt_1 0;
VAL_ 722 AcRemStartSts 0 "off" 1 "on" ;
VAL_ 722 CdcAntiRustFctSet 0 "norequest" 1 "Off" 2 "On" 3 "Reserved" ;
VAL_ 722 CdcAqsOpenSet 0 "NoReq" 1 "Off" 2 "On" 3 "Press" ;
VAL_ 722 CdcAutoApplyFctSet 0 "norequest" 1 "Off" 2 "On" 3 "Reserved" ;
VAL_ 722 CdcAutoDefrstDefogStsReq 0 "无请求" 1 "关闭" 2 "开启" 3 "预留" ;
VAL_ 722 CdcAutoWindLongPressSet 0 "Notset" 1 "on" 2 "Off" 3 "Reserved" ;
VAL_ 722 CdcAutoWindUnlockSet 0 "Notset" 1 "on" 2 "Off" 3 "Reserved" ;
VAL_ 722 CdcAVHFctSet 0 "norequest" 1 "Off" 2 "On" 3 "Reserved" ;
VAL_ 722 CdcBacktWindLvlSetReq 0 "无请求" 1 "开启" 2 "关闭" 3 "预留" ;
VAL_ 722 CdcBattPlsHeatgSet 0 "无请求" 1 "开启" 2 "关闭" 3 "预留" ;
VAL_ 722 CdcBDWFctSet 0 "norequest" 1 "Off" 2 "On" 3 "Reserved" ;
VAL_ 722 CdcBrkPedlModSet 0 "norequest" 1 "舒适模式" 2 "运动模式" 3 "custom" ;
VAL_ 722 CdcCycModSet 0 "NoReq" 1 "REC" 2 "FRS" 3 "AUTO RNAF" 4 "RECNAFRS" ;
VAL_ 722 CdcEpbSwtSet 0 "norequest" 1 "apply" 2 "Release" 3 "Reserved" ;
VAL_ 722 CdcEspFctSet 0 "norequest" 1 "Off" 2 "On" 3 "Reserved" ;
VAL_ 722 CdcFrntAutModOpenSet 0 "Notreq" 1 "Req" 2 "reserved" 3 "invalid" ;
VAL_ 722 CdcFrntBlowModSet 0 "NoReq" 1 "Face" 2 "Face/Foot" 3 "Foot" 4 "Foot/Def" 5 "Def" 6 "Face/Def" 7 "Face/Foot/Def" 8 "Mode" ;
VAL_ 722 CdcFrntDefrosterSet 0 "Notreq" 1 "Off" 2 "ON" 3 "DEF" ;
VAL_ 722 CdcFrntWindLvlSet 0 "noreq" 1 "Level 1" 2 "Level 2" 3 "Level 3" 4 "Level 4" 5 "Level 5" 6 "Level 6" 7 "Level 7" 8 "Level 8" 9 "UP Req" 10 "DOWN Req" ;
VAL_ 722 CdcFrontAcOffSet 0 "Notreq" 1 "ON" 2 "OFF" 3 "PRESS" ;
VAL_ 722 CdcHDCFctSet 0 "norequest" 1 "Off" 2 "On" 3 "Reserved" ;
VAL_ 722 CdcHotColdModStReq 0 "无请求" 1 "制冷" 2 "制热" 3 "通风" 4 "自动制冷制热" ;
VAL_ 722 CdcIBCUDrvModSet 0 "Notset" 1 "Normal" 2 "Sport" 3 " Trail(ATS)" ;
VAL_ 722 CdcORCAFctSet 0 "norequest" 1 "Off" 2 "On" 3 "Reserved" ;
VAL_ 722 CdcPassTSet 0 "noreq" 1 "LO" 31 "HI" 32 "up req" 33 "down req" 63 "Invalid" ;
VAL_ 722 CdcPlasmaOpenSet 0 "Notreq" 1 "Ionizer On" 2 "Ionizer Off" 3 "Ionizer_Req" ;
VAL_ 722 CdcSteerModSet 0 "StandarMode" 1 "Comfort Mode" 2 "Sport Mode" 3 "custom Mode" ;
VAL_ 722 CdcVehEgyCnseSelect 0 "无请求" 1 "CLTC工况" 2 "WLTC工况" 3 "动态工况" ;
VAL_ 722 CdcVentnOnSet 0 "Inactive" 1 "OFF" 2 "Default" 3 "User Defined" ;
VAL_ 722 CdcWorkSpaceSet 0 "NoReq" 1 "Off" 2 "On" 3 "Press" ;
VAL_ 722 CST_OFF_Switch 0 "norequest" 1 "OFF" 2 "On-lev1" 3 "On-lev2" 4 "On-lev3" ;
VAL_ 722 HU_ACRearFanAdjustValueReq 0 "NoReq" 9 "UP Req" 10 "DOWN Req" ;
VAL_ 722 HU_ACRearModeAdjustReq 0 "NoReq" 1 "Face" 2 "Face/Foot" 3 "Foot" 4 "Reserved" 5 "PressFaceArea" 6 "PressFootArea" 7 "Mode" ;
VAL_ 722 HU_AutowindSet3 0 "Notset" 1 "ON" 2 "OFF" 3 "Reserved" ;
VAL_ 722 HU_MaxACReq 0 "NoReq" 1 "Off" 2 "On" 3 "Press" ;
VAL_ 722 HU_MaxDefReq 0 "NoReq" 1 "Off" 2 "On" 3 "Press" ;
VAL_ 722 HU_MaxHeatReq 0 "NoReq" 1 "Off" 2 "On" 3 "Press" ;
VAL_ 722 HU_RearACOfffReq 0 "NoReq" 1 "ON" 2 "OFF" 3 "Press" ;
VAL_ 722 HU_RearAUTOACOnReq 0 "NoReq" 1 "Req" 2 "Reserved" 3 "Invalid" ;
VAL_ 722 HU_RefreshModeEnable 0 "Inactive" 1 "主驾清新提神" 2 "副驾清新提神" 3 "前排清新提神" ;
VAL_ 722 HU_Request_AFUchannel 0 "inactive" 1 "1通道" 2 "2通道" 3 "3通道" ;
VAL_ 722 HU_Request_AFUContentleve 0 "inactive" 1 "1档" 2 "2档" 3 "3档" 4 "4档" 5 "5档" 6 "6档" 7 "7档" 8 "8档" 9 "9档" 10 "10档" 11 "11档" 12 "12档" 13 "13档" 14 "14档" 15 "15档" ;
VAL_ 722 HU_Request_AFUSt 0 "inactive" 1 "OFF" 2 "ON" 3 "Reserve" ;
VAL_ 722 HU_RollerbenchSetStaus 0 "norequest" 1 "Off" 2 "On" 3 "Reserved" ;
VAL_ 722 HU_VentilationSetAfternoon 0 "Inactive" 1 "12=30" 2 "13=00" 3 "13=30" 4 "14=00" 5 "14=30" 6 "15=00" 7 "15=30" 8 "16=00" 9 "16=30" 10 "17=00" 11 "17=30" 12 "18=00" 13 "18=30" ;
VAL_ 722 HU_VentilationSetEvening 0 "Inactive" 1 "19=00" 2 "19=30" 3 "20=00" 4 "20=30" 5 "21=00" 6 "21=30" 7 "22=00" 8 "22=30" ;
VAL_ 722 HU_VentilationSetMorning 0 "Inactive" 1 "6=30" 2 "7=00" 3 "7=30" 4 "8=00" 5 "8=30" 6 "9=00" 7 "9=30" 8 "10=00" 9 "10=30" 10 "11=00" 11 "11=30" 12 "12=00" ;
VAL_ 722 HUAcEgySaveModReq 0 "NoReq" 1 "Off" 2 "On" 3 "Press" ;
VAL_ 722 HUAutoAirCleanReq 0 "NoReq" 1 "Off" 2 "On" 3 "Press" ;
VAL_ 722 HUBatPulseHeatSwitchReq 0 "NoReq" 1 "Off" 2 "On" 3 "Press" ;
VAL_ 722 HUMotLockHeatSwitchReq 0 "NoReq" 1 "Off" 2 "On" 3 "Press" ;
VAL_ 722 HUSngPrsnModReq 0 "NoReq" 1 "Off" 2 "On" 3 "Press" ;
VAL_ 722 VIUDrvModSet 0 "Notset" 1 "Comfort" 2 "Sport" 3 "Eco" 4 "SuperEco" 5 "ATS" 6 "Selfdefined" 7 "CrazyCow" 8 "Offroad" 9 "Snow" 10 "Sand" 12 "AISport" 15 "Invalid" ;
VAL_ 753 RCM_RLTuLiSt 0 "左后转向灯未开启" 1 "左后转向灯开启" ;
VAL_ 753 RCM_RRTuLiSt 0 "右后转向灯未开启" 1 "右后转向灯开启" ;
VAL_ 759 TboxLocalTiVld 0 "Valid" 1 "Invalid" ;
VAL_ 760 Tbox_GPSLocalTiVld 0 "Valid" 1 "Invalid" ;
VAL_ 774 AC_ACOnOff 0 "OFF" 1 "ON" 2 "not used" 3 "invalid" ;
VAL_ 774 ITMSLiquidLevel 0 "reserved" 1 "液位正常" 2 "液位低" 3 "无效值" ;
VAL_ 779 CdcIPScreenLiOnSts 0 "点亮" 1 "熄灭" ;
VAL_ 779 IP_DISFail 0 "noerror" 1 "error" ;
VAL_ 779 IP_juADASshowinfa 0 "noerror" 1 "error" ;
VAL_ 779 IP_juADASshowoutfa 0 "noerror" 1 "error" ;
VAL_ 779 IP_juADAStsE2Efaout 0 "noerror" 1 "error" ;
VAL_ 779 IP_QDashACCFail 0 "noerror" 1 "error" 2 "reserved" 3 "reserved" ;
VAL_ 779 AD_EDCCrtSts 0 "NotActive激活状态" 1 " Active激活状态" 2 "Error故障状态" ;
VAL_ 779 TboxDoorLockRemCtrlReq 0 "无效值（默认值）" 1 "解锁" 2 "闭锁" ;
VAL_ 784 AMP_FLHighSpeakerDelaySETStatus 0 "invalid" 1 "0ms" 2 "0.5ms" 3 "1ms" 4 "1.5ms" 5 "2ms" ;
VAL_ 784 AMP_FLHighSpeakerVolSETStatus 0 "Step0" 1 "Step1" 20 "Step20" 31 "invalid" ;
VAL_ 784 AMP_FLMidSpeakerDelaySETStatus 0 "invalid" 1 "0ms" 2 "0.5ms" 3 "1ms" 4 "1.5ms" 5 "2ms" ;
VAL_ 784 AMP_FLMidSpeakerVolSETStatus 0 "Step0" 1 "Step1" 20 "Step20" 31 "invalid" ;
VAL_ 784 AMP_FRHighSpeakerDelaySETStatus 0 "invalid" 1 "0ms" 2 "0.5ms" 3 "1ms" 4 "1.5ms" 5 "2ms" ;
VAL_ 784 AMP_FRHighSpeakerVolSETStatus 0 "Step0" 1 "Step1" 20 "Step20" 31 "invalid" ;
VAL_ 784 AMP_FRMidSpeakerDelaySETStatus 0 "invalid" 1 "0ms" 2 "0.5ms" 3 "1ms" 4 "1.5ms" 5 "2ms" ;
VAL_ 784 AMP_FRMidSpeakerVolSETStatus 0 "Step0" 1 "Step1" 20 "Step20" 31 "invalid" ;
VAL_ 784 AMP_AlarmVolSETStatus 0 "invalid" 1 "低" 2 "中" 3 "高" ;
VAL_ 784 AMP_AvasVolSETStatus 0 "invalid" 1 "低" 2 "中" 3 "高" ;
VAL_ 784 AMP_CenterSpeakerDelaySETStatus 0 "invalid" 1 "0ms" 2 "0.5ms" 3 "1ms" 4 "1.5ms" 5 "2ms" ;
VAL_ 784 AMP_CenterSpeakerVolSETStatus 0 "Step0" 1 "Step1" 20 "Step20" 31 "invalid" ;
VAL_ 784 AMP_CustomEffectSETStatus 0 "Inactive" 1 "仅专业自定义频段设置生效（3段）" 2 "仅自定义频段设置生效（9段）" 3 "失效" 4 "自定义频段设置生效（7段）" 5 "Beososic" ;
VAL_ 784 AMP_CustomEQ125SET 0 "invalid" 1 "-7" 2 "-6" 8 "0" 14 "6" 15 "7" ;
VAL_ 784 AMP_CustomEQ16KSET 0 "invalid" 1 "-7" 2 "-6" 8 "0" 14 "6" 15 "7" ;
VAL_ 784 AMP_CustomEQ1KSET 0 "invalid" 1 "-7" 2 "-6" 8 "0" 14 "6" 15 "7" ;
VAL_ 784 AMP_CustomEQ250SET 0 "invalid" 1 "-7" 2 "-6" 8 "0" 14 "6" 15 "7" ;
VAL_ 784 AMP_CustomEQ2KSET 0 "invalid" 1 "-7" 2 "-6" 8 "0" 14 "6" 15 "7" ;
VAL_ 784 AMP_CustomEQ4KSET 0 "invalid" 1 "-7" 2 "-6" 8 "0" 14 "6" 15 "7" ;
VAL_ 784 AMP_CustomEQ500SET 0 "invalid" 1 "-7" 2 "-6" 8 "0" 14 "6" 15 "7" ;
VAL_ 784 AMP_CustomEQ62SET 0 "invalid" 1 "-7" 2 "-6" 8 "0" 14 "6" 15 "7" ;
VAL_ 784 AMP_CustomEQ8KSET 0 "invalid" 1 "-7" 2 "-6" 8 "0" 14 "6" 15 "7" ;
VAL_ 784 AMP_FLLowSpeakerDelaySETStatus 0 "invalid" 1 "0ms" 2 "0.5ms" 3 "1ms" 4 "1.5ms" 5 "2ms" ;
VAL_ 784 AMP_FLLowSpeakerVolSETStatus 0 "Step0" 1 "Step1" 20 "Step20" 31 "invalid" ;
VAL_ 784 AMP_FLMidHighSpeakerDelaySETStat 0 "invalid" 1 "0ms" 2 "0.5ms" 3 "1ms" 4 "1.5ms" 5 "2ms" ;
VAL_ 784 AMP_FLMidHighSpeakerVolSETStatus 0 "Step0" 1 "Step1" 20 "Step20" 31 "invalid" ;
VAL_ 784 AMP_FLTopSpeakerDelaySETStatus 0 "invalid" 1 "0ms" 2 "0.5ms" 3 "1ms" 4 "1.5ms" 5 "2ms" ;
VAL_ 784 AMP_FLTopSpeakerVolSETStatus 0 "Step0" 1 "Step1" 20 "Step20" 31 "invalid" ;
VAL_ 784 AMP_FRBalanceSETStatus 0 "invalid" 1 "-7" 2 "-6" 8 "0" 14 "6" 15 "7" ;
VAL_ 784 AMP_FRLowSpeakerDelaySETStatus 0 "invalid" 1 "0ms" 2 "0.5ms" 3 "1ms" 4 "1.5ms" 5 "2ms" ;
VAL_ 784 AMP_FRLowSpeakerVolSETStatus 0 "Step0" 1 "Step1" 20 "Step20" 31 "invalid" ;
VAL_ 784 AMP_FRMidHighSpeakerDelaySET 0 "invalid" 1 "0ms" 2 "0.5ms" 3 "1ms" 4 "1.5ms" 5 "2ms" ;
VAL_ 784 AMP_FRMidHighSpeakerVolSETStatus 0 "Step0" 1 "Step1" 20 "Step20" 31 "invalid" ;
VAL_ 784 AMP_FRTopSpeakerDelaySETStatus 0 "invalid" 1 "0ms" 2 "0.5ms" 3 "1ms" 4 "1.5ms" 5 "2ms" ;
VAL_ 784 AMP_FRTopSpeakerVolSETStatus 0 "Step0" 1 "Step1" 20 "Step20" 31 "invalid" ;
VAL_ 784 AMP_KTVMUTESETStatus 0 "invalid" 1 "静音" 2 "非静音" 3 "reserved" ;
VAL_ 784 AMP_KTVVolSETStatus 0 "Step0" 1 "Step1" 20 "Step20" 31 "invalid" ;
VAL_ 784 AMP_LRBalanceSETStatus 0 "invalid" 1 "-7" 2 "-6" 8 "0" 14 "6" 15 "7" ;
VAL_ 784 AMP_MediaMUTESETStatus 0 "invalid" 1 "静音" 2 "非静音" 3 "reserved" ;
VAL_ 784 AMP_MediaVolSETStatus 0 "Step0" 1 "Step1" 20 "Step20" 31 "invalid" ;
VAL_ 784 AMP_MUTESETStatus 0 "invalid" 1 "静音" 2 "非静音" 3 "reserved" ;
VAL_ 784 AMP_NaviMUTESETStatus 0 "invalid" 1 "静音" 2 "非静音" 3 "reserved" ;
VAL_ 784 AMP_NAVIVolSETStatus 0 "Step0" 1 "Step1" 20 "Step20" 31 "invalid" ;
VAL_ 784 AMP_OutMUTESETStatus 0 "invalid" 1 "静音" 2 "非静音" 3 "reserved" ;
VAL_ 784 AMP_OUTVolSETStatus 0 "Step0" 1 "Step1" 20 "Step20" 31 "invalid" ;
VAL_ 784 AMP_PerfessiionalEQ100SET 0 "invalid" 1 "-7" 2 "-6" 8 "0" 14 "6" 15 "7" ;
VAL_ 784 AMP_PerfessiionalEQ500SET 0 "invalid" 1 "-7" 2 "-6" 8 "0" 14 "6" 15 "7" ;
VAL_ 784 AMP_PerfessiionalEQ6KSET 0 "invalid" 1 "-7" 2 "-6" 8 "0" 14 "6" 15 "7" ;
VAL_ 784 AMP_RLLowHighSpeakerDelaySETStat 0 "invalid" 1 "0ms" 2 "0.5ms" 3 "1ms" 4 "1.5ms" 5 "2ms" ;
VAL_ 784 AMP_RLLowHighSpeakerVolSETStatus 0 "Step0" 1 "Step1" 20 "Step20" 31 "invalid" ;
VAL_ 784 AMP_RLSurroundSpeakerDelaySETSta 0 "invalid" 1 "0ms" 2 "0.5ms" 3 "1ms" 4 "1.5ms" 5 "2ms" ;
VAL_ 784 AMP_RLSurroundSpeakerVolSETStatu 0 "Step0" 1 "Step1" 20 "Step20" 31 "invalid" ;
VAL_ 784 AMP_RLTopSpeakerDelaySETStatus 0 "invalid" 1 "0ms" 2 "0.5ms" 3 "1ms" 4 "1.5ms" 5 "2ms" ;
VAL_ 784 AMP_RLTopSpeakerVolSETStatus 0 "Step0" 1 "Step1" 20 "Step20" 31 "invalid" ;
VAL_ 784 AMP_RNCEnableSETStatus 0 "invalid" 1 "开启" 2 "关闭" 3 "reserved" ;
VAL_ 784 AMP_RRLowHighSpeakerDelaySET 0 "invalid" 1 "0ms" 2 "0.5ms" 3 "1ms" 4 "1.5ms" 5 "2ms" ;
VAL_ 784 AMP_RRLowHighSpeakerVolSETStatus 0 "Step0" 1 "Step1" 20 "Step20" 31 "invalid" ;
VAL_ 784 AMP_RRSurroundSpeakerDelaySETSta 0 "invalid" 1 "0ms" 2 "0.5ms" 3 "1ms" 4 "1.5ms" 5 "2ms" ;
VAL_ 784 AMP_RRSurroundSpeakerVolSET 0 "Step0" 1 "Step1" 20 "Step20" 31 "invalid" ;
VAL_ 784 AMP_RRTopSpeakerDelaySETStatus 0 "invalid" 1 "0ms" 2 "0.5ms" 3 "1ms" 4 "1.5ms" 5 "2ms" ;
VAL_ 784 AMP_RRTopSpeakerVolSETStatus 0 "Step0" 1 "Step1" 20 "Step20" 31 "invalid" ;
VAL_ 784 AMP_SoundEffectSETStatus 0 "invalid" 1 "音效1（HIFI原声）" 2 "音效2（沉浸环绕）" 3 "音效3（预留）" 4 "音效4（交响乐厅）" 5 "音效5（预留）" 6 "音效6（露营嗨唱）" 7 "音效7" 8 "音效8" 9 "音效9" 10 "音效10" 11 "音效11（寰宇影院）" 12 "音效12（调音大师）" ;
VAL_ 784 AMP_SoundFieldSETStatus 0 "invalid" 1 "自定义（CX810无）" 2 "主驾模式" 3 "均衡模式（全车模式）" 4 "左后模式" 5 "右后模式" 6 "副驾模式" ;
VAL_ 784 AMP_SubSpeakerDelaySETStatus 0 "invalid" 1 "0ms" 2 "0.5ms" 3 "1ms" 4 "1.5ms" 5 "2ms" ;
VAL_ 784 AMP_SubSpeakerVolSETStatus 0 "Step0" 1 "Step1" 20 "Step20" 31 "invalid" ;
VAL_ 784 AMP_SystemMUTESETStatus 0 "invalid" 1 "静音" 2 "非静音" 3 "reserved" ;
VAL_ 784 AMP_SystemVolSETStatus 0 "Step0" 1 "Step1" 20 "Step20" 31 "invalid" ;
VAL_ 784 AMP_TelBcallMUTESETStatus 0 "invalid" 1 "静音" 2 "非静音" 3 "reserved" ;
VAL_ 784 AMP_TELBCALLVolSETStatus 0 "Step0" 1 "Step1" 20 "Step20" 31 "invalid" ;
VAL_ 784 AMP_TTSVRMUTESETStatus 0 "invalid" 1 "静音" 2 "非静音" 3 "reserved" ;
VAL_ 784 AMP_TTSVRVolSETStatus 0 "Step0" 1 "Step1" 20 "Step20" 31 "invalid" ;
VAL_ 784 AMP_TurnLightInOrOutSETStatus 0 "invalid" 1 "in" 2 "out" ;
VAL_ 784 AMP_TurnLightVolSETStatus 0 "invalid" 1 "低" 2 "中" 3 "高" ;
VAL_ 784 AMP_VOLSpeedEnableSETStatus 0 "invalid" 1 "关闭" 2 "打开" 3 "=reserved" ;
VAL_ 800 AMPFLPositionDelaySETStatus 0 "invalid" 1 "0ms" 2 "0.5ms" 3 "1ms" 4 "1.5ms" 5 "2ms" ;
VAL_ 800 AMPFLPositionVolSETStatus 0 "invalid" 1 "-3" 2 "-2" 3 "-1" 4 "0" 5 "1" 6 "2" 7 "3" ;
VAL_ 800 AMPFRPositionDelaySETStatus 0 "invalid" 1 "0ms" 2 "0.5ms" 3 "1ms" 4 "1.5ms" 5 "2ms" ;
VAL_ 800 AMPFRPositionVolSETStatus 0 "invalid" 1 "-3" 2 "-2" 3 "-1" 4 "0" 5 "1" 6 "2" 7 "3" ;
VAL_ 800 AMPBeosonicModeSetStatus 0 "invalid" 1 "Lounge" 2 "Party" 3 "Podcast" 4 "Custom" ;
VAL_ 800 AMPBeosonicXSetStatus 0 "invalid" 1 "-10" 2 "-9" 11 "0" 20 "9" 21 "10" ;
VAL_ 800 AMPBeosonicYSetStatus 0 "invalid" 1 "-10" 2 "-9" 11 "0" 20 "9" 21 "10" ;
VAL_ 800 AMPCenterPositionDelaySETStatus 0 "invalid" 1 "0ms" 2 "0.5ms" 3 "1ms" 4 "1.5ms" 5 "2ms" ;
VAL_ 800 AMPCenterPositionVolSETStatus 0 "invalid" 1 "-3" 2 "-2" 3 "-1" 4 "0" 5 "1" 6 "2" 7 "3" ;
VAL_ 800 AMPCustomEQ2500SET 0 "invalid" 1 "-7" 2 "-6" 8 "0" 14 "6" 15 "7" ;
VAL_ 800 AMPCustomEQ315SET 0 "invalid" 1 "-7" 2 "-6" 8 "0" 14 "6" 15 "7" ;
VAL_ 800 AMPCustomEQ50SET 0 "invalid" 1 "-7" 2 "-6" 8 "0" 14 "6" 15 "7" ;
VAL_ 800 AMPCustomEQ6000SET 0 "invalid" 1 "-7" 2 "-6" 8 "0" 14 "6" 15 "7" ;
VAL_ 800 AMPCustomEQ800SET 0 "invalid" 1 "-7" 2 "-6" 8 "0" 14 "6" 15 "7" ;
VAL_ 800 AMPFLTopPositionDelaySETStatus 0 "invalid" 1 "0ms" 2 "0.5ms" 3 "1ms" 4 "1.5ms" 5 "2ms" ;
VAL_ 800 AMPFLTopPositionVolSETStatus 0 "invalid" 1 "-3" 2 "-2" 3 "-1" 4 "0" 5 "1" 6 "2" 7 "3" ;
VAL_ 800 AMPFRTopPositionDelaySETStatus 0 "invalid" 1 "0ms" 2 "0.5ms" 3 "1ms" 4 "1.5ms" 5 "2ms" ;
VAL_ 800 AMPFRTopPositionVolSETStatus 0 "invalid" 1 "-3" 2 "-2" 3 "-1" 4 "0" 5 "1" 6 "2" 7 "3" ;
VAL_ 800 AMPRLPositionDelaySETStatus 0 "invalid" 1 "0ms" 2 "0.5ms" 3 "1ms" 4 "1.5ms" 5 "2ms" ;
VAL_ 800 AMPRLPositionVolSETStatus 0 "invalid" 1 "-3" 2 "-2" 3 "-1" 4 "0" 5 "1" 6 "2" 7 "3" ;
VAL_ 800 AMPRLSurroundDelaySETStatus 0 "invalid" 1 "0ms" 2 "0.5ms" 3 "1ms" 4 "1.5ms" 5 "2ms" ;
VAL_ 800 AMPRLSurroundVolSETStatus 0 "invalid" 1 "-3" 2 "-2" 3 "-1" 4 "0" 5 "1" 6 "2" 7 "3" ;
VAL_ 800 AMPRLTopDelaySETStatus 0 "invalid" 1 "0ms" 2 "0.5ms" 3 "1ms" 4 "1.5ms" 5 "2ms" ;
VAL_ 800 AMPRLTopVolSETStatus 0 "invalid" 1 "-3" 2 "-2" 3 "-1" 4 "0" 5 "1" 6 "2" 7 "3" ;
VAL_ 800 AMPRRPositionDelaySET 0 "invalid" 1 "0ms" 2 "0.5ms" 3 "1ms" 4 "1.5ms" 5 "2ms" ;
VAL_ 800 AMPRRPositionVolSETStatus 0 "invalid" 1 "-3" 2 "-2" 3 "-1" 4 "0" 5 "1" 6 "2" 7 "3" ;
VAL_ 800 AMPRRSurroundPositionDelaySETSta 0 "invalid" 1 "0ms" 2 "0.5ms" 3 "1ms" 4 "1.5ms" 5 "2ms" ;
VAL_ 800 AMPRRSurroundPositionVolSET 0 "invalid" 1 "-3" 2 "-2" 3 "-1" 4 "0" 5 "1" 6 "2" 7 "3" ;
VAL_ 800 AMPRRTopPositionDelaySETStatus 0 "invalid" 1 "0ms" 2 "0.5ms" 3 "1ms" 4 "1.5ms" 5 "2ms" ;
VAL_ 800 AMPRRTopPositionVolSETStatus 0 "invalid" 1 "-3" 2 "-2" 3 "-1" 4 "0" 5 "1" 6 "2" 7 "3" ;
VAL_ 800 AMPSoundSourceTypeStatus 0 "invalid" 1 "立体声" 2 "7.1.4" 3 "reserved" ;
VAL_ 800 AMPSubPositionDelaySETStatus 0 "invalid" 1 "0ms" 2 "0.5ms" 3 "1ms" 4 "1.5ms" 5 "2ms" ;
VAL_ 800 AMPSubPositionVolSETStatus 0 "invalid" 1 "-3" 2 "-2" 3 "-1" 4 "0" 5 "1" 6 "2" 7 "3" ;
VAL_ 800 AMPTMCenterPositionEQ15000HzSetS 0 "invalid" 1 "-3" 2 "-2" 3 "-1" 4 "0" 5 "1" 6 "2" 7 "3" ;
VAL_ 800 AMPTMCenterPositionEQ800HzSetSta 0 "invalid" 1 "-3" 2 "-2" 3 "-1" 4 "0" 5 "1" 6 "2" 7 "3" ;
VAL_ 800 AMPTMFLPositionEQ100HzSetStatus 0 "invalid" 1 "-3" 2 "-2" 3 "-1" 4 "0" 5 "1" 6 "2" 7 "3" ;
VAL_ 800 AMPTMFLPositionEQ15000HzSetStatu 0 "invalid" 1 "-3" 2 "-2" 3 "-1" 4 "0" 5 "1" 6 "2" 7 "3" ;
VAL_ 800 AMPTMFLPositionEQ800HzSetStatus 0 "invalid" 1 "-3" 2 "-2" 3 "-1" 4 "0" 5 "1" 6 "2" 7 "3" ;
VAL_ 800 AMPTMFLTopPositionEQ500HzSetStat 0 "invalid" 1 "-3" 2 "-2" 3 "-1" 4 "0" 5 "1" 6 "2" 7 "3" ;
VAL_ 800 AMPTMFRPositionEQ100HzSetStatus 0 "invalid" 1 "-3" 2 "-2" 3 "-1" 4 "0" 5 "1" 6 "2" 7 "3" ;
VAL_ 800 AMPTMFRPositionEQ15000HzSetStatu 0 "invalid" 1 "-3" 2 "-2" 3 "-1" 4 "0" 5 "1" 6 "2" 7 "3" ;
VAL_ 800 AMPTMFRPositionEQ800HzSetStatus 0 "invalid" 1 "-3" 2 "-2" 3 "-1" 4 "0" 5 "1" 6 "2" 7 "3" ;
VAL_ 800 AMPTMFRTopPositionEQ500HzSetStat 0 "invalid" 1 "-3" 2 "-2" 3 "-1" 4 "0" 5 "1" 6 "2" 7 "3" ;
VAL_ 800 AMPTMReverbSetStatus 0 "invalid" 1 "1" 2 "2" 3 "3" 100 "100" ;
VAL_ 800 AMPTMRLPositionEQ10000HzSetStatu 0 "invalid" 1 "-3" 2 "-2" 3 "-1" 4 "0" 5 "1" 6 "2" 7 "3" ;
VAL_ 800 AMPTMRLPositionEQ100HzSetStatusS 0 "invalid" 1 "-3" 2 "-2" 3 "-1" 4 "0" 5 "1" 6 "2" 7 "3" ;
VAL_ 800 AMPTMRLSurroundPositionEQ15000Hz 0 "invalid" 1 "-3" 2 "-2" 3 "-1" 4 "0" 5 "1" 6 "2" 7 "3" ;
VAL_ 800 AMPTMRLSurroundPositionEQ800HzSe 0 "invalid" 1 "-3" 2 "-2" 3 "-1" 4 "0" 5 "1" 6 "2" 7 "3" ;
VAL_ 800 AMPTMRLTopPositionEQ500HzSetStat 0 "invalid" 1 "-3" 2 "-2" 3 "-1" 4 "0" 5 "1" 6 "2" 7 "3" ;
VAL_ 800 AMPTMRRPositionEQ10000HzSetStatu 0 "invalid" 1 "-3" 2 "-2" 3 "-1" 4 "0" 5 "1" 6 "2" 7 "3" ;
VAL_ 800 AMPTMRRPositionEQ100HzSetStatus 0 "invalid" 1 "-3" 2 "-2" 3 "-1" 4 "0" 5 "1" 6 "2" 7 "3" ;
VAL_ 800 AMPTMRRSurroundPositionEQ15000Hz 0 "invalid" 1 "-3" 2 "-2" 3 "-1" 4 "0" 5 "1" 6 "2" 7 "3" ;
VAL_ 800 AMPTMRRSurroundPositionEQ800HzSe 0 "invalid" 1 "-3" 2 "-2" 3 "-1" 4 "0" 5 "1" 6 "2" 7 "3" ;
VAL_ 800 AMPTMRRTopPositionEQ500HzSetStat 0 "invalid" 1 "-3" 2 "-2" 3 "-1" 4 "0" 5 "1" 6 "2" 7 "3" ;
VAL_ 800 AMPTMSubPositionEQ30HzSetStatusS 0 "invalid" 1 "-3" 2 "-2" 3 "-1" 4 "0" 5 "1" 6 "2" 7 "3" ;
VAL_ 800 AMPVOLSpeedLevChangeSETStatus 0 "invalid" 1 "关闭" 2 "低" 3 "中" 4 "高" ;
VAL_ 802 ECASAdjBySpd 0 "Inactive" 1 "Active " ;
VAL_ 802 ECASaftaxladjsts 0 "idle" 1 "up" 2 "down" ;
VAL_ 802 ECASerromode 0 "error_mode_0(nofault)" 1 "error_mode_1 (light error)" 2 "error_mode_2 (heavy error)" 3 "error_mode_3 (heavy actor fault)" 4 "Reserved" ;
VAL_ 802 ECASfrtaxladjsts 0 "idle" 1 "up" 2 "down" ;
VAL_ 802 EcasModeCHASts 0 "Idle" 1 "up" 2 "down" 3 "Switch fail" 4 "ready to Switch " ;
VAL_ 802 EcasModeFB 0 "Normal" 1 "sport" 2 "Off road" 3 "Comfort" 4 "Auto" 5 "Access" 6 "Load" 7 "Level" 8 "Trailer mode" 9 "maintenance" 10 "10%" 11 "20%" 12 "30%" 13 "40%" 14 "50%" 15 "60%" 16 "70%" 17 "80%" 18 "90%" 19 "100%" 20 "Remote Ultra High" 21 "Remote Off road" 22 "Remote Normal" 23 "Remote sport" 24 "Ultra High" ;
VAL_ 802 ECASmodevld 0 "Valid" 1 "Invalid" ;
VAL_ 802 SusfaultlLamp 0 "idle" 1 "“亮黄灯”" 2 "“亮红灯”" ;
VAL_ 802 Susfaultred 0 "idle" 1 "压缩机温度过高，暂停使用" 2 "悬架运动已暂停，关闭车门后继续" 3 "当前车身姿态不稳，暂不能调节悬架高度（对应横向加速度过大）" 4 "Reserved" 5 "当前车身姿态不稳，暂不能调节悬架高度（对应静态路面不平）" 6 "方向盘转角转速过大，空簧停止调节" 7 "紧急状态，空簧停止调节" 8 "行驶路面颠簸，空簧停止调节" 9 "悬架热保护中，大概XX分钟后悬架可使用" 10 "悬架高度差过大，空簧停止调节 " 11 "悬架高度调节锁定中，请将车速提升至5km/h以上解除" 12 "空簧系统清洁中，请稍后再试”" 13 "请确认充放电枪已断开再试" 14 "Reserved" 15 "Reserved" 16 "悬架姿态恢复中，请谨慎行驶" ;
VAL_ 821 BCM_DriverWindowStatus 1 "Open" 2 "Close" 3 "Openning" 4 "Closing" 5 "AntiPinch 防夹回退状态" 255 "Invalid" ;
VAL_ 821 BCM_PartWinPosVIT 0 "Invalid" 255 "PosUnknown " ;
VAL_ 821 BCM_PartWinSts 0 "Init初始" 1 "RSV 保留" 2 "RSV 保留" 3 "Open 打开" 4 "Close 关闭" 5 "Stop 停止" ;
VAL_ 821 BCM_PassengerWindowPosi 0 "此参数无效" ;
VAL_ 821 BCM_PassengerWindowStatus 1 "Open" 2 "Close" 3 "Openning" 4 "Closing" 5 "AntiPinch 防夹回退状态" 255 "Invalid" ;
VAL_ 821 VcuIpuErrLamp 0 "OFF" 1 "ON" ;
VAL_ 821 VcuEgyMagtModResp 1 "模式1" 2 "模式2" 3 "模式3" 4 "模式4" ;
VAL_ 821 VcuForceEVModResp 0 "关闭" 1 "开启" ;
VAL_ 821 VcuForcePwrPresModResp 0 "关闭" 1 "开启" ;
VAL_ 821 BCM_RightRearWindowPosi 0 "此参数无效" ;
VAL_ 821 BCM_RightRearWindowStatus 1 "Open" 2 "Close" 3 "Openning" 4 "Closing" 5 "AntiPinch 防夹回退状态" 255 "Invalid" ;
VAL_ 821 VcuHvilStsGb 0 "noerror" 1 "error" ;
VAL_ 821 VcuVehChrgStsGb 1 "停车充电" 2 "行驶充电" 3 "未充电状态" 4 "充电完成" ;
VAL_ 821 VcuVehRunngModGb 1 "纯电" 2 "混动" 3 "燃油" ;
VAL_ 821 VcuVehStsGb 1 "车辆启动状态" 2 "熄火" 3 "其他状态" ;
VAL_ 821 VcuBrkPedlSts 0 "NotPressed" 1 "Pressed" 2 "Reserved" 3 "Error" ;
VAL_ 821 BCM_DriverWindowPosi 0 "此参数无效" ;
VAL_ 821 BCM_LeftRearWindowPosi 0 "此参数无效" ;
VAL_ 821 BCM_LeftRearWindowStatus 1 "Open" 2 "Close" 3 "Openning" 4 "Closing" 5 "AntiPinch 防夹回退状态" 255 "Invalid" ;
VAL_ 821 BcmSunroofPosi 0 "此参数无效" ;
VAL_ 821 BcmSunroofStatus 1 "Open" 2 "Close" 3 "Openning" 4 "Closing" 5 "AntiPinch 防夹回退状态" 127 "Invalid" ;
VAL_ 821 MFS_Right_switch_Right1_signal 0 "按键未按下" 1 "按键按下" 2 "假按键" 3 "Error" ;
VAL_ 821 VcuBattChrgErrLamp 0 "Off" 1 "ON" ;
VAL_ 821 VcuBattUUnderWarn 0 "Invalid" 1 "OFF" 2 "一级报警" 3 "二级报警" ;
VAL_ 821 VcuChrgAutoUnlckSetStsFb 0 "Invalid" 1 "off" 2 "on" ;
VAL_ 821 VcuChrgLckInfo 0 "无显示提示" 1 "锁止失败提示" 2 "解锁失败提示" ;
VAL_ 821 VCUGearShiftPositon 0 "Parking" 1 "Reverse" 2 "Neutral" 3 "D" 14 "Unreliable" 15 "Invalid" ;
VAL_ 821 VcuHvBattCutOffLamp 0 "LightOff" 1 "LightOn" ;
VAL_ 821 VcuHVErrInfo 0 "Noerror" 1 "Error" ;
VAL_ 821 VcuHvilSts 0 "noerror" 1 "error" ;
VAL_ 821 VcuShiftPErrInfo 0 "Noerror" 1 "Error" ;
VAL_ 821 VCUShiftPostionValid 0 "Valid" 1 "Invalid" ;
VAL_ 821 VcuVehErrInfo 0 "Noerror" 1 "Error" ;
VAL_ 821 VIUFL_DeviceVerifyResult 0 "VerifynotPassed" 1 "Verify Passed" 2 "Rsvrd" 3 "Rsvrd" ;
VAL_ 821 VcuOffRoadCrpSts 0 "Off" 1 "Standby" 2 "Active" 3 "Fault" ;
VAL_ 821 BCMALLDoorLockSwt 0 "无效值" 1 "解锁成功，整车以太网异常" 2 "解锁失败" 3 "闭锁成功，整车以太网异常" 4 "闭锁失败" ;
VAL_ 822 CcsmFrntEDLSetSwt 0 "None" 1 "请求解锁" 2 "请求锁止" 3 "Reserved" ;
VAL_ 822 CcsmReEDLSetSwt 0 "None" 1 "请求解锁" 2 "请求锁止" 3 "Reserved" ;
VAL_ 822 CcsmEDLBtnStuckFlg 0 "无故障" 1 "前锁按键粘连" 2 "后锁按键粘连" 3 "双锁按键粘连" ;
VAL_ 854 HU_FLHighSpeakerDelaySET 0 "invalid" 1 "0ms" 2 "0.5ms" 3 "1ms" 4 "1.5ms" 5 "2ms" ;
VAL_ 854 HU_FLHighSpeakerVolSET 0 "Step0" 1 "Step1" 20 "Step20" 31 "invalid" ;
VAL_ 854 HU_FLMidSpeakerDelaySET 0 "invalid" 1 "0ms" 2 "0.5ms" 3 "1ms" 4 "1.5ms" 5 "2ms" ;
VAL_ 854 HU_FLMidSpeakerVolSET 0 "Step0" 1 "Step1" 20 "Step20" 31 "invalid" ;
VAL_ 854 HU_FRHighSpeakerDelaySET 0 "invalid" 1 "0ms" 2 "0.5ms" 3 "1ms" 4 "1.5ms" 5 "2ms" ;
VAL_ 854 HU_FRHighSpeakerVolSET 0 "Step0" 1 "Step1" 20 "Step20" 31 "invalid" ;
VAL_ 854 HU_FRMidSpeakerDelaySET 0 "invalid" 1 "0ms" 2 "0.5ms" 3 "1ms" 4 "1.5ms" 5 "2ms" ;
VAL_ 854 HU_FRMidSpeakerVolSET 0 "Step0" 1 "Step1" 20 "Step20" 31 "invalid" ;
VAL_ 854 HUFLPositionDelaySET 0 "invalid" 1 "0ms" 2 "0.5ms" 3 "1ms" 4 "1.5ms" 5 "2ms" ;
VAL_ 854 HUFLPositionVolSET 0 "invalid" 1 "-3" 2 "-2" 3 "-1" 4 "0" 5 "1" 6 "2" 7 "3" ;
VAL_ 854 HUFRPositionDelaySET 0 "invalid" 1 "0ms" 2 "0.5ms" 3 "1ms" 4 "1.5ms" 5 "2ms" ;
VAL_ 854 HUFRPositionVolSET 0 "invalid" 1 "-3" 2 "-2" 3 "-1" 4 "0" 5 "1" 6 "2" 7 "3" ;
VAL_ 854 HU_AlarmVolSET 0 "invalid" 1 "低" 2 "中" 3 "高" ;
VAL_ 854 HU_AvasVolSET 0 "invalid" 1 "低" 2 "中" 3 "高" ;
VAL_ 854 HU_CenterSpeakerDelaySET 0 "invalid" 1 "0ms" 2 "0.5ms" 3 "1ms" 4 "1.5ms" 5 "2ms" ;
VAL_ 854 HU_CenterSpeakerVolSET 0 "Step0" 1 "Step1" 20 "Step20" 31 "invalid" ;
VAL_ 854 HU_CustomEffectSET 0 "Inactive" 1 "仅专业自定义频段设置生效（3段）" 2 "仅自定义频段设置生效（9段）" 3 "失效" 4 "自定义频段设置生效（7段）" 5 "Beososic" ;
VAL_ 854 HU_CustomEQ125SET 0 "invalid" 1 "-7" 2 "-6" 8 "0" 14 "6" 15 "7" ;
VAL_ 854 HU_CustomEQ16KSET 0 "invalid" 1 "-7" 2 "-6" 8 "0" 14 "6" 15 "7" ;
VAL_ 854 HU_CustomEQ1KSET 0 "invalid" 1 "-7" 2 "-6" 8 "0" 14 "6" 15 "7" ;
VAL_ 854 HU_CustomEQ250SET 0 "invalid" 1 "-7" 2 "-6" 8 "0" 14 "6" 15 "7" ;
VAL_ 854 HU_CustomEQ2KSET 0 "invalid" 1 "-7" 2 "-6" 8 "0" 14 "6" 15 "7" ;
VAL_ 854 HU_CustomEQ4KSET 0 "invalid" 1 "-7" 2 "-6" 8 "0" 14 "6" 15 "7" ;
VAL_ 854 HU_CustomEQ500SET 0 "invalid" 1 "-7" 2 "-6" 8 "0" 14 "6" 15 "7" ;
VAL_ 854 HU_CustomEQ62SET 0 "invalid" 1 "-7" 2 "-6" 8 "0" 14 "6" 15 "7" ;
VAL_ 854 HU_CustomEQ8KSET 0 "invalid" 1 "-7" 2 "-6" 8 "0" 14 "6" 15 "7" ;
VAL_ 854 HU_FLLowSpeakerDelaySET 0 "invalid" 1 "0ms" 2 "0.5ms" 3 "1ms" 4 "1.5ms" 5 "2ms" ;
VAL_ 854 HU_FLLowSpeakerVolSET 0 "Step0" 1 "Step1" 20 "Step20" 31 "invalid" ;
VAL_ 854 HU_FLMidHighSpeakerDelaySET 0 "invalid" 1 "0ms" 2 "0.5ms" 3 "1ms" 4 "1.5ms" 5 "2ms" ;
VAL_ 854 HU_FLMidHighSpeakerVolSET 0 "Step0" 1 "Step1" 20 "Step20" 31 "invalid" ;
VAL_ 854 HU_FLTopSpeakerDelaySET 0 "invalid" 1 "0ms" 2 "0.5ms" 3 "1ms" 4 "1.5ms" 5 "2ms" ;
VAL_ 854 HU_FLTopSpeakerVolSET 0 "Step0" 1 "Step1" 20 "Step20" 31 "invalid" ;
VAL_ 854 HU_FRBalanceSET 0 "Inactive" 1 "-7（最前面）" 2 "-6" 8 "0（中间位置）" 15 "7(最后边)" ;
VAL_ 854 HU_FRLowSpeakerDelaySET 0 "invalid" 1 "0ms" 2 "0.5ms" 3 "1ms" 4 "1.5ms" 5 "2ms" ;
VAL_ 854 HU_FRLowSpeakerVolSET 0 "Step0" 1 "Step1" 20 "Step20" 31 "invalid" ;
VAL_ 854 HU_FRMidHighSpeakerDelaySET 0 "invalid" 1 "0ms" 2 "0.5ms" 3 "1ms" 4 "1.5ms" 5 "2ms" ;
VAL_ 854 HU_FRMidHighSpeakerVolSET 0 "Step0" 1 "Step1" 20 "Step20" 31 "invalid" ;
VAL_ 854 HU_FRTopSpeakerDelaySET 0 "invalid" 1 "0ms" 2 "0.5ms" 3 "1ms" 4 "1.5ms" 5 "2ms" ;
VAL_ 854 HU_FRTopSpeakerVolSET 0 "Step0" 1 "Step1" 20 "Step20" 31 "invalid" ;
VAL_ 854 HU_KTVMUTESET 0 "invalid" 1 "静音" 2 "非静音" 3 "reserved" ;
VAL_ 854 HU_KTVVolSET 0 "Step0" 1 "Step1" 20 "Step20" 31 "invalid" ;
VAL_ 854 HU_LRBalanceSET 0 "Inactive" 1 "-7（最左边）" 2 "-6" 8 "0（中间位置）" 15 "7(最右边)" ;
VAL_ 854 HU_MediaMUTESET 0 "invalid" 1 "静音" 2 "非静音" 3 "reserved" ;
VAL_ 854 HU_MediaVolSET 0 "Step0" 1 "Step1" 20 "Step20" 31 "invalid" ;
VAL_ 854 HU_MUTESET 0 "invalid" 1 "静音" 2 "非静音" 3 "reserved" ;
VAL_ 854 HU_NaviMUTESET 0 "invalid" 1 "静音" 2 "非静音" 3 "reserved" ;
VAL_ 854 HU_NAVIVolSET 0 "Step0" 1 "Step1" 20 "Step20" 31 "invalid" ;
VAL_ 854 HU_OutMUTESET 0 "invalid" 1 "静音" 2 "非静音" 3 "reserved" ;
VAL_ 854 HU_OUTVolSET 0 "Step0" 1 "Step1" 20 "Step20" 31 "invalid" ;
VAL_ 854 HU_PerfessiionalEQ100SET 0 "invalid" 1 "-7" 2 "-6" 8 "0" 14 "6" 15 "7" ;
VAL_ 854 HU_PerfessiionalEQ500SET 0 "invalid" 1 "-7" 2 "-6" 8 "0" 14 "6" 15 "7" ;
VAL_ 854 HU_PerfessiionalEQ6KSET 0 "invalid" 1 "-7" 2 "-6" 8 "0" 14 "6" 15 "7" ;
VAL_ 854 HU_RLLowHighSpeakerDelaySET 0 "invalid" 1 "0ms" 2 "0.5ms" 3 "1ms" 4 "1.5ms" 5 "2ms" ;
VAL_ 854 HU_RLLowHighSpeakerVolSET 0 "Step0" 1 "Step1" 20 "Step20" 31 "invalid" ;
VAL_ 854 HU_RLSurroundSpeakerDelaySET 0 "invalid" 1 "0ms" 2 "0.5ms" 3 "1ms" 4 "1.5ms" 5 "2ms" ;
VAL_ 854 HU_RLSurroundSpeakerVolSET 0 "Step0" 1 "Step1" 20 "Step20" 31 "invalid" ;
VAL_ 854 HU_RLTopSpeakerDelaySET 0 "invalid" 1 "0ms" 2 "0.5ms" 3 "1ms" 4 "1.5ms" 5 "2ms" ;
VAL_ 854 HU_RLTopSpeakerVolSET 0 "Step0" 1 "Step1" 20 "Step20" 31 "invalid" ;
VAL_ 854 HU_RNCEnableSET 0 "invalid" 1 "开启" 2 "关闭" 3 "reserved" ;
VAL_ 854 HU_RRLowHighSpeakerDelaySET 0 "invalid" 1 "0ms" 2 "0.5ms" 3 "1ms" 4 "1.5ms" 5 "2ms" ;
VAL_ 854 HU_RRLowHighSpeakerVolSET 0 "Step0" 1 "Step1" 20 "Step20" 31 "invalid" ;
VAL_ 854 HU_RRSurroundSpeakerDelaySET 0 "invalid" 1 "0ms" 2 "0.5ms" 3 "1ms" 4 "1.5ms" 5 "2ms" ;
VAL_ 854 HU_RRSurroundSpeakerVolSET 0 "Step0" 1 "Step1" 20 "Step20" 31 "invalid" ;
VAL_ 854 HU_RRTopSpeakerDelaySET 0 "invalid" 1 "0ms" 2 "0.5ms" 3 "1ms" 4 "1.5ms" 5 "2ms" ;
VAL_ 854 HU_RRTopSpeakerVolSET 0 "Step0" 1 "Step1" 20 "Step20" 31 "invalid" ;
VAL_ 854 HU_SoundEffectSET 0 "invalid" 1 "音效1（HIFI原声）" 2 "音效2（沉浸环绕）" 3 "音效3（预留）" 4 "音效4（交响乐厅）" 5 "音效5（预留）" 6 "音效6（露营嗨唱）" 7 "音效7" 8 "音效8" 9 "音效9" 10 "音效10" 11 "音效11（寰宇影院）" 12 "音效12（调音大师）" ;
VAL_ 854 HU_SoundFieldSET 0 "invalid" 1 "自定义（CX810无）" 2 "主驾模式" 3 "均衡模式（全车模式）" 4 "左后模式" 5 "右后模式" 6 "副驾模式" ;
VAL_ 854 HU_SubSpeakerDelaySET 0 "invalid" 1 "0ms" 2 "0.5ms" 3 "1ms" 4 "1.5ms" 5 "2ms" ;
VAL_ 854 HU_SubSpeakerVolSET 0 "Step0" 1 "Step1" 20 "Step20" 31 "invalid" ;
VAL_ 854 HU_SystemMUTESET 0 "invalid" 1 "静音" 2 "非静音" 3 "reserved" ;
VAL_ 854 HU_SystemVolSET 0 "Step0" 1 "Step1" 20 "Step20" 31 "invalid" ;
VAL_ 854 HU_TelBcallMUTESET 0 "invalid" 1 "静音" 2 "非静音" 3 "reserved" ;
VAL_ 854 HU_TELBCALLVolSET 0 "Step0" 1 "Step1" 20 "Step20" 31 "invalid" ;
VAL_ 854 HU_TTSVRMUTESET 0 "invalid" 1 "静音" 2 "非静音" 3 "reserved" ;
VAL_ 854 HU_TTSVRVolSET 0 "Step0" 1 "Step1" 20 "Step20" 31 "invalid" ;
VAL_ 854 HU_TurnLightInOrOutSET 0 "invalid" 1 "in" 2 "out" ;
VAL_ 854 HU_TurnLightVolSET 0 "Inactive" 1 "低" 2 "中" 3 "高" ;
VAL_ 854 HU_VOLSpeedLevEnableSET 0 "invalid" 1 "关闭" 2 "打开" 3 "=reserved" ;
VAL_ 854 HUBeosonicModeSet 0 "invalid" 1 "Lounge" 2 "Party" 3 "Podcast" 4 "Custom" ;
VAL_ 854 HUBeosonicXSet 0 "invalid" 1 "-10" 2 "-9" 11 "0" 20 "9" 21 "10" ;
VAL_ 854 HUBeosonicYSet 0 "invalid" 1 "-10" 2 "-9" 11 "0" 20 "9" 21 "10" ;
VAL_ 854 HUCenterPositionDelaySET 0 "invalid" 1 "0ms" 2 "0.5ms" 3 "1ms" 4 "1.5ms" 5 "2ms" ;
VAL_ 854 HUCenterPositionVolSET 0 "invalid" 1 "-3" 2 "-2" 3 "-1" 4 "0" 5 "1" 6 "2" 7 "3" ;
VAL_ 854 HUCustomEQ2500SET 0 "invalid" 1 "-7" 2 "-6" 8 "0" 14 "6" 15 "7" ;
VAL_ 854 HUCustomEQ315SET 0 "invalid" 1 "-7" 2 "-6" 8 "0" 14 "6" 15 "7" ;
VAL_ 854 HUCustomEQ50SET 0 "invalid" 1 "-7" 2 "-6" 8 "0" 14 "6" 15 "7" ;
VAL_ 854 HUCustomEQ6000SET 0 "invalid" 1 "-7" 2 "-6" 8 "0" 14 "6" 15 "7" ;
VAL_ 854 HUCustomEQ800SET 0 "invalid" 1 "-7" 2 "-6" 8 "0" 14 "6" 15 "7" ;
VAL_ 854 HUFLTopPositionDelaySET 0 "invalid" 1 "0ms" 2 "0.5ms" 3 "1ms" 4 "1.5ms" 5 "2ms" ;
VAL_ 854 HUFLTopPositionVolSET 0 "invalid" 1 "-3" 2 "-2" 3 "-1" 4 "0" 5 "1" 6 "2" 7 "3" ;
VAL_ 854 HUFRTopPositionDelaySET 0 "invalid" 1 "0ms" 2 "0.5ms" 3 "1ms" 4 "1.5ms" 5 "2ms" ;
VAL_ 854 HUSoundSourceType 0 "invalid" 1 "立体声" 2 "7.1.4" 3 "reserved" ;
VAL_ 854 HUTMCenterPositionEQ15000HzSet 0 "invalid" 1 "-3" 2 "-2" 3 "-1" 4 "0" 5 "1" 6 "2" 7 "3" ;
VAL_ 854 HUTMCenterPositionEQ800HzSet 0 "invalid" 1 "-3" 2 "-2" 3 "-1" 4 "0" 5 "1" 6 "2" 7 "3" ;
VAL_ 854 HUTMFLPositionEQ100HzSet 0 "invalid" 1 "-3" 2 "-2" 3 "-1" 4 "0" 5 "1" 6 "2" 7 "3" ;
VAL_ 854 HUTMFLPositionEQ15000HzSet 0 "invalid" 1 "-3" 2 "-2" 3 "-1" 4 "0" 5 "1" 6 "2" 7 "3" ;
VAL_ 854 HUTMFLPositionEQ800HzSet 0 "invalid" 1 "-3" 2 "-2" 3 "-1" 4 "0" 5 "1" 6 "2" 7 "3" ;
VAL_ 854 HUTMFLTopPositionEQ500HzSet 0 "invalid" 1 "-3" 2 "-2" 3 "-1" 4 "0" 5 "1" 6 "2" 7 "3" ;
VAL_ 854 HUTMFRPositionEQ100HzSet 0 "invalid" 1 "-3" 2 "-2" 3 "-1" 4 "0" 5 "1" 6 "2" 7 "3" ;
VAL_ 854 HUTMFRPositionEQ15000HzSet 0 "invalid" 1 "-3" 2 "-2" 3 "-1" 4 "0" 5 "1" 6 "2" 7 "3" ;
VAL_ 854 HUTMFRPositionEQ800HzSet 0 "invalid" 1 "-3" 2 "-2" 3 "-1" 4 "0" 5 "1" 6 "2" 7 "3" ;
VAL_ 854 HUTMFRTopPositionEQ500HzSet 0 "invalid" 1 "-3" 2 "-2" 3 "-1" 4 "0" 5 "1" 6 "2" 7 "3" ;
VAL_ 854 HUTMReverbSet 0 "invalid" 1 "1" 2 "2" 3 "3" 100 "100" ;
VAL_ 854 HUTMRLPositionEQ10000HzSet 0 "invalid" 1 "-3" 2 "-2" 3 "-1" 4 "0" 5 "1" 6 "2" 7 "3" ;
VAL_ 854 HUTMRLPositionEQ100HzSet 0 "invalid" 1 "-3" 2 "-2" 3 "-1" 4 "0" 5 "1" 6 "2" 7 "3" ;
VAL_ 854 HUTMRLSurroundPositionEQ15000HzS 0 "invalid" 1 "-3" 2 "-2" 3 "-1" 4 "0" 5 "1" 6 "2" 7 "3" ;
VAL_ 854 HUTMRLSurroundPositionEQ800HzSet 0 "invalid" 1 "-3" 2 "-2" 3 "-1" 4 "0" 5 "1" 6 "2" 7 "3" ;
VAL_ 854 HUTMRLTopPositionEQ500HzSet 0 "invalid" 1 "-3" 2 "-2" 3 "-1" 4 "0" 5 "1" 6 "2" 7 "3" ;
VAL_ 854 HUTMRRPositionEQ10000HzSet 0 "invalid" 1 "-3" 2 "-2" 3 "-1" 4 "0" 5 "1" 6 "2" 7 "3" ;
VAL_ 854 HUTMRRPositionEQ100HzSet 0 "invalid" 1 "-3" 2 "-2" 3 "-1" 4 "0" 5 "1" 6 "2" 7 "3" ;
VAL_ 854 HUTMRRSurroundPositionEQ15000HzS 0 "invalid" 1 "-3" 2 "-2" 3 "-1" 4 "0" 5 "1" 6 "2" 7 "3" ;
VAL_ 854 HUTMRRSurroundPositionEQ800HzSet 0 "invalid" 1 "-3" 2 "-2" 3 "-1" 4 "0" 5 "1" 6 "2" 7 "3" ;
VAL_ 854 HUTMRRTopPositionEQ500HzSet 0 "invalid" 1 "-3" 2 "-2" 3 "-1" 4 "0" 5 "1" 6 "2" 7 "3" ;
VAL_ 854 HUTMSubPositionEQ30HzSet 0 "invalid" 1 "-3" 2 "-2" 3 "-1" 4 "0" 5 "1" 6 "2" 7 "3" ;
VAL_ 854 HUTMTransEnd 0 "未发送" 1 "发送完成" ;
VAL_ 854 HUVOLSpeedLevChangeSET 0 "invalid" 1 "关闭" 2 "低" 3 "中" 4 "高" ;
VAL_ 868 CdcEpbSetSwt_1 0 "norequest" 1 "apply" 2 "Release" 3 "Reserved" ;
VERSION "sin DBC editor"

NS_ :
    STR_64
    BA_SETDATA_REF_
    BA_SETDATA_SGTYPE_

BS_:

BU_: VIU_FL AMP EDC VIU_FR TBOX IP EVCC ICDC

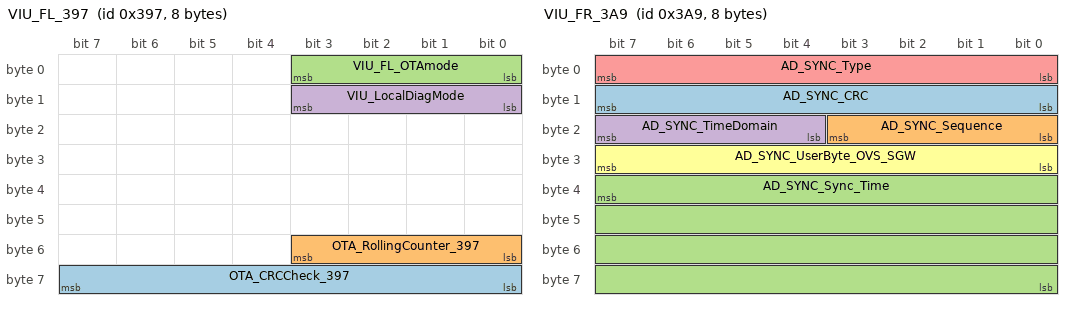
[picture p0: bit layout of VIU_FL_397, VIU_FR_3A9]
BO_ 919 VIU_FL_397: 8 VIU_FL
    SG_ OTA_CRCCheck_397 : 63|8@0+ (1,0) [0|255] "" EDC,TBOX,AMP,IP
    SG_ OTA_RollingCounter_397 : 51|4@0+ (1,0) [0|15] "" EDC,TBOX,AMP,IP
    SG_ VIU_FL_OTAmode : 3|4@0+ (1,0) [0|15] "" EDC,TBOX,AMP,IP
    SG_ VIU_LocalDiagMode : 11|4@0+ (1,0) [0|15] "" EDC,TBOX

BO_ 920 EDC_398: 8 EDC
    SG_ EDC_EOLMode : 7|4@0+ (1,0) [0|15] "" TBOX,VIU_FL
    SG_ EDC_VerCollectMode : 3|4@0+ (1,0) [0|15] "" TBOX,VIU_FL

BO_ 921 EDC_399: 8 EDC
    SG_ TBOX_RemotDiagMode : 3|4@0+ (1,0) [0|15] "" VIU_FL,TBOX

BO_ 930 VIU_FL_3A2: 64 VIU_FL
    SG_ EmsFlexfuelDisplay : 55|1@0+ (1,0) [0|1] "" EDC
    SG_ EmsLowTempMilgRemind : 95|1@0+ (1,0) [0|1] "" EDC

BO_ 931 EDC_3A3: 64 EDC
    SG_ EDC_EpbFctLamp : 7|2@0+ (1,0) [0|3] "" IP
    SG_ EDC_EpsFaild : 5|3@0+ (1,0) [0|7] "" IP
    SG_ EDC_EmsMilLamp : 2|2@0+ (1,0) [0|3] "" IP
    SG_ EDC_VcuDrvEgyInd : 15|8@0+ (1,-100) [-100|100] "" IP
    SG_ EDC_VcuFuelLevelPercent : 22|7@0+ (1,0) [0|100] "%" IP
    SG_ EDC_VcuFulLimdDrvgDst : 31|11@0+ (1,0) [0|2047] "km" IP
    SG_ EDC_VcuEvDrvResiMilg : 36|11@0+ (1,0) [0|2047] "Km" IP
    SG_ EDC_VcuVehAvrgEgyCnseLongTime : 41|10@0+ (0.1,-50) [-50|50] "kWh/百公里" IP
    SG_ EDC_VcuVehAvrgFuelCnseLongTime : 119|9@0+ (0.1,0) [0|50] "L/100km" IP
    SG_ EDC_VcuVehAvrgEgyCnseInTripA : 135|10@0+ (0.1,-50) [-50|50] "kWh/百公里" IP
    SG_ EDC_VcuVehAvrgTotCnseInTripA : 141|9@0+ (0.1,0) [0|50] "L/100km" IP
    SG_ EDC_LoBeamInfo : 63|1@0+ (1,0) [0|1] "" IP
    SG_ EDC_HiBeamInfo : 62|1@0+ (1,0) [0|1] "" IP
    SG_ EDC_AutoHiBeamInfo : 61|2@0+ (1,0) [0|3] "" IP
    SG_ EDC_Le_ReLoglSt : 59|1@0+ (1,0) [0|1] "" IP
    SG_ EDC_Ri_ReLoglSt : 58|1@0+ (1,0) [0|1] "" IP
    SG_ EDC_PosnLiInfo : 57|1@0+ (1,0) [0|1] "" IP
    SG_ EDC_VcuPlugConnectLamp : 56|1@0+ (1,0) [0|1] "" IP
    SG_ EDC_BcuBattSocUnderLamp : 148|1@0+ (1,0) [0|1] "" IP
    SG_ EDC_VcuChrgStsLamp : 147|1@0+ (1,0) [0|1] "" IP
    SG_ EDC_DcacStsLamp : 146|2@0+ (1,0) [0|3] "" IP
    SG_ EDC_LoBattErrSts : 144|1@0+ (1,0) [0|1] "" IP
    SG_ EDC_VcuVehPwrLimLamp : 159|1@0+ (1,0) [0|1] "" IP
    SG_ EDC_VcuEngineOilPressureLowSts : 157|1@0+ (1,0) [0|1] "" IP
    SG_ EDC_PsgSeatSBR : 155|2@0+ (1,0) [0|3] "" IP
    SG_ EDC_RearLeSeatSBR : 153|2@0+ (1,0) [0|3] "" IP
    SG_ EDC_RearMidSeatSBR : 167|2@0+ (1,0) [0|3] "" IP
    SG_ EDC_RearRiSeatSBR : 165|2@0+ (1,0) [0|3] "" IP
    SG_ EDC_SBR : 163|1@0+ (1,0) [0|1] "" IP
    SG_ EDC_AD_NDAStatus : 162|3@0+ (1,0) [0|7] "" IP
    SG_ EDC_AD_BSDLCA_LeftAlert : 174|2@0+ (1,0) [0|3] "" IP
    SG_ EDC_AD_BSDLCA_RightAlert : 172|2@0+ (1,0) [0|3] "" IP
    SG_ EDC_ACC_SetSpeed : 183|16@0+ (1,0) [0|17777] "" IP
    SG_ EDC_time_hr : 199|8@0+ (1,0) [0|23] "" IP
    SG_ EDC_time_min : 207|8@0+ (1,0) [0|59] "" IP
    SG_ EDC_ViuEgyResiColor : 213|2@0+ (1,0) [0|3] "" IP
    SG_ EDC_ViuEvResiMilgInvldDisp : 211|1@0+ (1,0) [0|1] "" IP
    SG_ EDC_LaneLeft_Status : 223|4@0+ (1,0) [0|15] "" IP
    SG_ EDC_LaneRight_Status : 219|4@0+ (1,0) [0|15] "" IP
    SG_ EDC_ACC_TimeGapSet : 210|3@0+ (1,0) [0|7] "" IP
    SG_ EDC_Objx_Detection : 239|4@0+ (1,0) [0|15] "" IP
    SG_ EDC_Lane_PointArr : 231|8@0+ (1,0) [0|255] "" IP
    SG_ EDC_EpbFailrLamp : 235|2@0+ (1,0) [0|3] "" IP
    SG_ EDC_trafficLight : 71|4@0+ (1,0) [0|15] "" IP
    SG_ EDC_countdown : 67|16@0+ (1,0) [0|255] "" IP
    SG_ EDC_mileage : 83|2@0+ (1,0) [0|3] "" IP
    SG_ EDC_brightness : 81|4@0+ (1,0) [0|10] "" IP
    SG_ EDC_Autobrightness : 93|2@0+ (1,0) [0|3] "" IP
    SG_ EDC_FW_Brightness : 91|16@0+ (6,0) [0|6138] "" IP
    SG_ EDC_AMB_Brightness : 233|16@0+ (30,0) [0|30690] "" IP
    SG_ EDC_AD_AEBStatus : 107|4@0+ (1,0) [0|15] "" IP
    SG_ EDC_trip : 249|24@0+ (0.1,0) [0|1.67772e+06] "Km" IP
    SG_ EDC_VcuPwrSysErrLamp : 169|2@0+ (1,0) [0|2] "" IP
    SG_ EDCDisplayEspVehSpd : 350|9@0+ (1,0) [0|510] "Km/h" IP

BO_ 937 VIU_FR_3A9: 8 VIU_FR
    SG_ AD_SYNC_CRC : 15|8@0+ (1,0) [0|255] "" VIU_FL
    SG_ AD_SYNC_Sequence : 19|4@0+ (1,0) [0|15] "" VIU_FL
    SG_ AD_SYNC_Sync_Time : 39|32@0+ (1,0) [0|4.29e+09] "" VIU_FL
    SG_ AD_SYNC_TimeDomain : 23|4@0+ (1,0) [0|15] "" VIU_FL
    SG_ AD_SYNC_Type : 7|8@0+ (1,0) [0|255] "" VIU_FL
    SG_ AD_SYNC_UserByte_OVS_SGW : 31|8@0+ (1,0) [0|255] "" VIU_FL

BO_ 941 VIU_FL_3AD: 64 VIU_FL
    SG_ RRS_FLCDistance : 199|9@0+ (1,0) [0|511] "" EDC,IP
    SG_ RRS_FLMDistance : 220|9@0+ (1,0) [0|511] "" EDC,IP
    SG_ RRS_FLODistance : 213|9@0+ (1,0) [0|511] "" EDC,IP
    SG_ RRS_FLSDistance : 206|9@0+ (1,0) [0|511] "" EDC,IP
    SG_ RRS_FRCDistance : 263|9@0+ (1,0) [0|511] "" EDC,IP
    SG_ RRS_FRMDistance : 227|9@0+ (1,0) [0|511] "" EDC,IP
    SG_ RRS_FRODistance : 234|9@0+ (1,0) [0|511] "" EDC,IP
    SG_ RRS_FRSDistance : 241|9@0+ (1,0) [0|511] "" EDC,IP
    SG_ RRS_RLCDistance : 270|9@0+ (1,0) [0|511] "" EDC,IP
    SG_ RRS_RLMDistance : 291|9@0+ (1,0) [0|511] "" EDC,IP
    SG_ RRS_RLODistance : 284|9@0+ (1,0) [0|511] "" EDC,IP
    SG_ RRS_RLSDistance : 277|9@0+ (1,0) [0|511] "" EDC,IP
    SG_ RRS_RRCDistance : 334|9@0+ (1,0) [0|511] "" EDC,IP
    SG_ RRS_RRMDistance : 298|9@0+ (1,0) [0|511] "" EDC,IP
    SG_ RRS_RRODistance : 305|9@0+ (1,0) [0|511] "" EDC,IP
    SG_ RRS_RRSDistance : 327|9@0+ (1,0) [0|511] "" EDC,IP
    SG_ ACC_CRCCheck_3AD : 503|16@0+ (1,0) [0|65535] "" EDC,IP
    SG_ ACC_RollingCounter_3AD : 491|4@0+ (1,0) [0|15] "" EDC,IP
    SG_ AD_CNAStatus : 54|3@0+ (1,0) [0|7] "" EDC
    SG_ AD_HandsOnReq : 18|3@0+ (1,0) [0|7] "" EDC
    SG_ AD_IACCHWAMode : 29|3@0+ (1,0) [0|7] "" EDC,IP
    SG_ AD_IACCMode : 7|3@0+ (1,0) [0|7] "" EDC,IP
    SG_ AD_LatTakeoverReq : 15|2@0+ (1,0) [0|3] "" EDC,IP
    SG_ AD_LngTakeOverReq : 13|2@0+ (1,0) [0|3] "" EDC,IP
    SG_ AD_NDAStatus : 51|4@0+ (1,0) [0|15] "" EDC
    SG_ AD_TakeoverReqAtIPFail : 23|2@0+ (1,0) [0|3] "" EDC
    SG_ AD_TJPStatus : 46|2@0+ (1,0) [0|3] "" EDC
    SG_ AD_Voiceinfo : 36|5@0+ (1,0) [0|31] "" EDC
    SG_ RRS_SystemFailureFlag : 363|2@0+ (1,0) [0|3] "" EDC

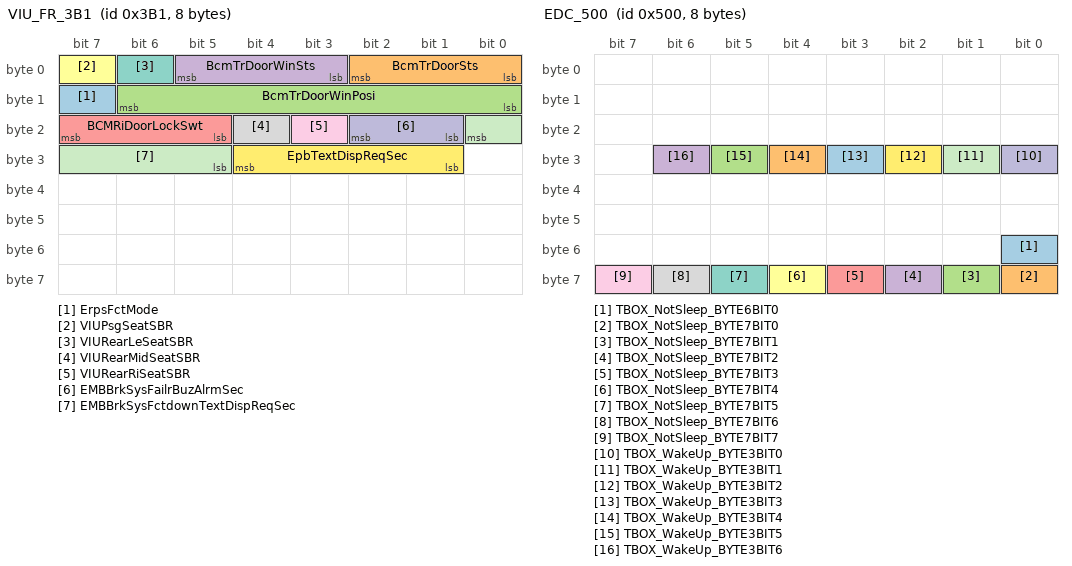
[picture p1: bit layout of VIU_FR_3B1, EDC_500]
BO_ 945 VIU_FR_3B1: 8 VIU_FR
    SG_ ErpsFctMode : 15|1@0+ (1,0) [0|1] "" VIU_FL,EDC
    SG_ BcmTrDoorSts : 2|3@0+ (1,0) [0|7] "" VIU_FL,IP,EDC
    SG_ BcmTrDoorWinPosi : 14|7@0+ (1,0) [0|127] "" EDC
    SG_ BcmTrDoorWinSts : 5|3@0+ (1,0) [0|7] "" EDC
    SG_ BCMRiDoorLockSwt : 23|3@0+ (1,0) [0|7] "" EDC
    SG_ VIUPsgSeatSBR : 7|1@0+ (1,0) [0|1] "" VIU_FL
    SG_ VIURearLeSeatSBR : 6|1@0+ (1,0) [0|1] "" VIU_FL
    SG_ VIURearMidSeatSBR : 20|1@0+ (1,0) [0|1] "" VIU_FL
    SG_ VIURearRiSeatSBR : 19|1@0+ (1,0) [0|1] "" VIU_FL
    SG_ EMBBrkSysFailrBuzAlrmSec : 18|2@0+ (1,0) [0|3] "" EDC
    SG_ EMBBrkSysFctdownTextDispReqSec : 16|4@0+ (1,0) [0|15] "" EDC
    SG_ EpbTextDispReqSec : 28|4@0+ (1,0) [0|15] "" EDC

BO_ 959 EDC_3BF: 64 EDC
    SG_ HUFRTopPositionVolSET : 273|5@0+ (1,0) [0|31] "" AMP
    SG_ HURLPositionDelaySET : 284|5@0+ (1,0) [0|31] "" AMP
    SG_ HURLPositionVolSET : 295|5@0+ (1,0) [0|31] "" AMP
    SG_ HURLSurroundPositionDelaySET : 290|5@0+ (1,0) [0|31] "" AMP
    SG_ HURLSurroundPositionVolSET : 301|5@0+ (1,0) [0|31] "" AMP
    SG_ HURLTopPositionDelaySET : 296|5@0+ (1,0) [0|31] "" AMP
    SG_ HURLTopPositionVolSET : 307|5@0+ (1,0) [0|31] "" AMP
    SG_ HURRPositionDelaySET : 318|5@0+ (1,0) [0|31] "" AMP
    SG_ HURRPositionVolSET : 327|5@0+ (1,0) [0|31] "" AMP
    SG_ HURRSurroundPositionDelaySET : 322|5@0+ (1,0) [0|31] "" AMP
    SG_ HURRSurroundPositionVolSET : 333|5@0+ (1,0) [0|31] "" AMP
    SG_ HURRTopPositionDelaySET : 328|5@0+ (1,0) [0|31] "" AMP
    SG_ HURRTopPositionVolSET : 339|5@0+ (1,0) [0|31] "" AMP

BO_ 965 VIU_FL_3C5: 64 VIU_FL
    SG_ AD_HWPStatus : 15|3@0+ (1,0) [0|6] "" IP
    SG_ ACC_ADCNotice : 12|9@0+ (1,0) [0|480] "" IP
    SG_ AD_SafetyNotice : 7|8@0+ (1,0) [0|160] "" IP
    SG_ AD_CRCCheck_3C5 : 503|16@0+ (1,0) [0|65535] "" IP
    SG_ AD_RollingCounter_3C5 : 491|4@0+ (1,0) [0|15] "" IP

BO_ 1000 VIU_FL_3E8: 64 VIU_FL
    SG_ Reserved_message3E8 : 0|1@0+ (1,0) [0|1] "" Vector__XXX

BO_ 1001 VIU_FR_3E9: 64 VIU_FR
    SG_ Reserved_message3E9 : 0|1@0+ (1,0) [0|1] "" Vector__XXX

BO_ 1015 IP_3F7: 8 IP
    SG_ IP_brightness : 7|4@0+ (1,0) [0|10] "" EDC
    SG_ IPFault : 3|16@0+ (1,0) [0|65535] "" VIU_FL

BO_ 1025 IP_401: 8 IP
    SG_ NM_message401 : 0|1@0+ (1,0) [0|1] "" Vector__XXX

BO_ 1031 TBOX_407: 8 TBOX
    SG_ NM_message407 : 0|1@0+ (1,0) [0|1] "" Vector__XXX

BO_ 1036 VIU_FL_40C: 8 VIU_FL
    SG_ NM_message40C : 0|1@0+ (1,0) [0|1] "" Vector__XXX

BO_ 1037 VIU_FR_40D: 8 VIU_FR
    SG_ NM_message40D : 0|1@0+ (1,0) [0|1] "" Vector__XXX

BO_ 1041 EDC_411: 8 EDC
    SG_ NM_message411 : 0|1@0+ (1,0) [0|1] "" Vector__XXX

BO_ 1059 AMP_423: 8 AMP
    SG_ NM_message423 : 0|1@0+ (1,0) [0|1] "" Vector__XXX

BO_ 1193 EVCC_4A9: 8 EVCC
    SG_ NM_message4A9 : 0|1@0+ (1,0) [0|1] "" Vector__XXX

BO_ 1280 EDC_500: 8 EDC
    SG_ TBOX_NotSleep_BYTE6BIT0 : 48|1@0+ (1,0) [0|1] "" TBOX,VIU_FL
    SG_ TBOX_NotSleep_BYTE7BIT0 : 56|1@0+ (1,0) [0|1] "" TBOX,VIU_FL
    SG_ TBOX_NotSleep_BYTE7BIT1 : 57|1@0+ (1,0) [0|1] "" TBOX,VIU_FL
    SG_ TBOX_NotSleep_BYTE7BIT2 : 58|1@0+ (1,0) [0|1] "" TBOX,VIU_FL
    SG_ TBOX_NotSleep_BYTE7BIT3 : 59|1@0+ (1,0) [0|1] "" TBOX,VIU_FL
    SG_ TBOX_NotSleep_BYTE7BIT4 : 60|1@0+ (1,0) [0|1] "" TBOX,VIU_FL
    SG_ TBOX_NotSleep_BYTE7BIT5 : 61|1@0+ (1,0) [0|1] "" TBOX,VIU_FL
    SG_ TBOX_NotSleep_BYTE7BIT6 : 62|1@0+ (1,0) [0|1] "" TBOX,VIU_FL
    SG_ TBOX_NotSleep_BYTE7BIT7 : 63|1@0+ (1,0) [0|1] "" TBOX,VIU_FL
    SG_ TBOX_WakeUp_BYTE3BIT0 : 24|1@0+ (1,0) [0|1] "" TBOX,VIU_FL
    SG_ TBOX_WakeUp_BYTE3BIT1 : 25|1@0+ (1,0) [0|1] "" TBOX,VIU_FL
    SG_ TBOX_WakeUp_BYTE3BIT2 : 26|1@0+ (1,0) [0|1] "" TBOX,VIU_FL
    SG_ TBOX_WakeUp_BYTE3BIT3 : 27|1@0+ (1,0) [0|1] "" TBOX,VIU_FL
    SG_ TBOX_WakeUp_BYTE3BIT4 : 28|1@0+ (1,0) [0|1] "" TBOX,VIU_FL
    SG_ TBOX_WakeUp_BYTE3BIT5 : 29|1@0+ (1,0) [0|1] "" TBOX,VIU_FL
    SG_ TBOX_WakeUp_BYTE3BIT6 : 30|1@0+ (1,0) [0|1] "" TBOX,VIU_FL

BO_ 1288 VIU_FR_508: 64 VIU_FR
    SG_ TMS_BatteryPumpErrCode : 7|16@0+ (1,0) [0|65535] "" VIU_FL
    SG_ TMS_BatteryPumpSt : 187|2@0+ (1,0) [0|3] "" VIU_FL
    SG_ TMS_BattInpWtrTValid : 185|1@0+ (1,0) [0|1] "" VIU_FL
    SG_ TMS_ECV1ErrCode_Radiator : 23|8@0+ (1,0) [0|128] "" VIU_FL
    SG_ TMS_ECV1MotorSt_Radiator : 184|1@0+ (1,0) [0|1] "" VIU_FL
    SG_ TMS_ECV1PosnAct_Radiator : 31|8@0+ (1,0) [0|100] "" VIU_FL
    SG_ TMS_Ecv1St_Radiator : 299|2@0+ (1,0) [0|3] "" VIU_FL
    SG_ TMS_ECV2ErrCode_Battery : 39|8@0+ (1,0) [0|128] "" VIU_FL
    SG_ TMS_ECV2MotorSt_Battery : 297|1@0+ (1,0) [0|1] "" VIU_FL
    SG_ TMS_ECV2PosnAct_Battery : 47|8@0+ (1,0) [0|100] "" VIU_FL
    SG_ TMS_ECV2St_Battery : 296|2@0+ (1,0) [0|3] "" VIU_FL
    SG_ TMS_ECV3ErrCode_Hydrothermal : 55|8@0+ (1,0) [0|128] "" VIU_FL
    SG_ TMS_ECV3MotorSt_Hydrothermal : 310|1@0+ (1,0) [0|1] "" VIU_FL
    SG_ TMS_ECV3PosnAct_Hydrothermal : 63|8@0+ (1,0) [0|100] "" VIU_FL
    SG_ TMS_ECV3St_Hydrothermal : 309|2@0+ (1,0) [0|3] "" VIU_FL
    SG_ TMS_ExtendRangePumpErrCode : 71|16@0+ (1,0) [0|65535] "" VIU_FL
    SG_ TMS_ExtendRangePumpSt : 307|2@0+ (1,0) [0|3] "" VIU_FL
    SG_ TMS_Exv1ErrCode_HVAC : 135|10@0+ (1,0) [0|511] "" VIU_FL
    SG_ TMS_Exv1InitSt_HVAC : 305|2@0+ (1,0) [0|3] "" VIU_FL
    SG_ TMS_Exv1PosnAct_HVAC : 141|10@0+ (1,0) [0|1000] "step" VIU_FL
    SG_ TMS_Exv1RunSt_HVAC : 319|2@0+ (1,0) [0|1] "" VIU_FL
    SG_ TMS_Exv2ErrCode_Battery : 147|10@0+ (1,0) [0|511] "" VIU_FL
    SG_ TMS_Exv2InitSt_Battery : 317|2@0+ (1,0) [0|3] "" VIU_FL
    SG_ TMS_Exv2RunSt_Battery : 315|2@0+ (1,0) [0|1] "" VIU_FL
    SG_ TMS_Exv3ErrCode_WasteHeatRe : 153|10@0+ (1,0) [0|511] "" VIU_FL
    SG_ TMS_Exv3InitSt_WasteHeatRe : 313|2@0+ (1,0) [0|3] "" VIU_FL
    SG_ TMS_Exv3PosnAct_WasteHeatRe : 175|10@0+ (1,0) [0|1000] "step" VIU_FL
    SG_ TMS_Exv3RunSt_WasteHeatRe : 327|2@0+ (1,0) [0|1] "" VIU_FL
    SG_ TMS_Exv4ErrCode_Refrigerant : 181|10@0+ (1,0) [0|511] "" VIU_FL
    SG_ TMS_Exv4InitSt_Refrigerant : 325|2@0+ (1,0) [0|3] "" VIU_FL
    SG_ TMS_Exv4PosnAct_Refrigerant : 199|10@0+ (1,0) [0|1000] "step" VIU_FL
    SG_ TMS_Exv4RunningSt_Refrigerant : 323|2@0+ (1,0) [0|1] "" VIU_FL
    SG_ TMS_FWV1ErrCode : 87|8@0+ (1,0) [0|128] "" VIU_FL
    SG_ TMS_FWV1MotorSt : 365|1@0+ (1,0) [0|1] "" VIU_FL
    SG_ TMS_FWV1PosnAct : 95|8@0+ (1,0) [0|100] "" VIU_FL
    SG_ TMS_FWV1St : 321|2@0+ (1,0) [0|3] "" VIU_FL
    SG_ TMS_InSeriesPumpErrCode : 103|16@0+ (1,0) [0|65535] "" VIU_FL
    SG_ TMS_InSeriesPumpSpdAct : 119|8@0+ (1,0) [0|100] "%" VIU_FL
    SG_ TMS_MotorPumpSt : 335|2@0+ (1,0) [0|3] "" VIU_FL
    SG_ TMS_OilCoolerWtrT : 127|8@0+ (1,-40) [-40|215] "℃" VIU_FL
    SG_ TMS_OilCoolerWtrTValid : 364|1@0+ (1,0) [0|1] "" VIU_FL
    SG_ TMS_PT1PrErrCode : 333|2@0+ (1,0) [0|3] "" VIU_FL
    SG_ TMS_PT1TempSnsrErrCode : 331|2@0+ (1,0) [0|3] "" VIU_FL
    SG_ TMS_PT2PrErrCode : 329|2@0+ (1,0) [0|3] "" VIU_FL
    SG_ TMS_PT2TempSnsrErrCode : 343|2@0+ (1,0) [0|3] "" VIU_FL
    SG_ TMS_PT3PrErrCode : 341|2@0+ (1,0) [0|3] "" VIU_FL
    SG_ TMS_PT3TempSnsrErrCode : 339|2@0+ (1,0) [0|3] "" VIU_FL
    SG_ TMS_PT4P_LiquidStorage : 205|10@0+ (0.1,0) [0|40] "bar" VIU_FL
    SG_ TMS_PT4PrErrCode : 337|2@0+ (1,0) [0|3] "" VIU_FL
    SG_ TMS_PT4temp_LiquidStorage : 211|12@0+ (0.1,-50) [-50|200] "degC" VIU_FL
    SG_ TMS_PT4TempSnsrErrCode : 351|2@0+ (1,0) [0|3] "" VIU_FL
    SG_ TMS_PT5Pr_WasteHeatRe : 231|10@0+ (0.1,0) [0|40] "bar" VIU_FL
    SG_ TMS_PT5PrErrCode : 349|2@0+ (1,0) [0|3] "" VIU_FL
    SG_ TMS_PT5temp_WasteHeatRe : 237|12@0+ (0.1,-50) [-50|200] "degC" VIU_FL
    SG_ TMS_PT5TempSnsrErrCode : 347|2@0+ (1,0) [0|3] "" VIU_FL
    SG_ TMS_PT6Pr_RearEvap : 241|10@0+ (0.1,0) [0|40] "bar" VIU_FL
    SG_ TMS_PT6PrErrCode : 345|2@0+ (1,0) [0|3] "" VIU_FL
    SG_ TMS_PT6temp_RearEvap : 295|12@0+ (0.1,-50) [-50|200] "degC" VIU_FL
    SG_ TMS_PT6TempSnsrErrCode : 359|2@0+ (1,0) [0|3] "" VIU_FL
    SG_ TMS_SolnVlv1St_DLP : 357|2@0+ (1,0) [0|3] "" VIU_FL
    SG_ TMS_SolnVlv1St_RearEvap : 355|2@0+ (1,0) [0|3] "" VIU_FL
    SG_ TMS_WarmPumpErrCode : 263|16@0+ (1,0) [0|65535] "" VIU_FL
    SG_ Tms_ExtenderPmpCtrlVal : 279|8@0+ (1,0) [0|255] "" VIU_FL
    SG_ Tms_ExtenderPmpSts : 363|1@0+ (1,0) [0|1] "" VIU_FL
    SG_ Tms_HeatPmpCtrlVal : 287|8@0+ (1,0) [0|255] "" VIU_FL
    SG_ Tms_HeatPmpSts : 362|1@0+ (1,0) [0|1] "" VIU_FL
    SG_ TMS_CTMU_SolnVlv3ErrCode : 353|2@0+ (1,0) [0|3] "" VIU_FL
    SG_ TMS_CTMU_SolnVlv3St : 367|2@0+ (1,0) [0|3] "" VIU_FL

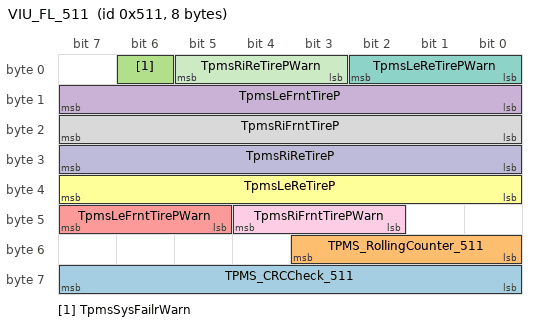
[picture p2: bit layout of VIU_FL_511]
BO_ 1297 VIU_FL_511: 8 VIU_FL
    SG_ TPMS_CRCCheck_511 : 63|8@0+ (1,0) [0|255] "" Vector__XXX
    SG_ TPMS_RollingCounter_511 : 51|4@0+ (1,0) [0|15] "" Vector__XXX
    SG_ TpmsSysFailrWarn : 6|1@0+ (1,0) [0|1] "" TBOX,IP
    SG_ TpmsLeFrntTireP : 15|8@0+ (1.373,0) [0|350] "KPa" IP
    SG_ TpmsLeFrntTirePWarn : 47|3@0+ (1,0) [0|7] "" IP
    SG_ TpmsLeReTireP : 39|8@0+ (1.373,0) [0|350] "KPa" IP
    SG_ TpmsLeReTirePWarn : 2|3@0+ (1,0) [0|7] "" IP
    SG_ TpmsRiFrntTireP : 23|8@0+ (1.373,0) [0|350] "KPa" IP
    SG_ TpmsRiFrntTirePWarn : 44|3@0+ (1,0) [0|7] "" IP
    SG_ TpmsRiReTireP : 31|8@0+ (1.373,0) [0|350] "KPa" IP
    SG_ TpmsRiReTirePWarn : 5|3@0+ (1,0) [0|7] "" IP

BO_ 1361 VIU_FL_551: 8 VIU_FL
    SG_ VIU_FL_NMNotSleep_BYTE2BIT0 : 16|1@0+ (1,0) [0|1] "" Vector__XXX
    SG_ VIU_FL_NMNotSleep_BYTE2BIT1 : 17|1@0+ (1,0) [0|1] "" Vector__XXX
    SG_ VIU_FL_NMNotSleep_BYTE2BIT2 : 18|1@0+ (1,0) [0|1] "" Vector__XXX
    SG_ VIU_FL_NMNotSleep_BYTE2BIT3 : 19|1@0+ (1,0) [0|1] "" Vector__XXX
    SG_ VIU_FL_NMNotSleep_BYTE2BIT4 : 20|1@0+ (1,0) [0|1] "" Vector__XXX
    SG_ VIU_FL_NMNotSleep_BYTE2BIT5 : 21|1@0+ (1,0) [0|1] "" Vector__XXX
    SG_ VIU_FL_NMNotSleep_BYTE2BIT6 : 22|1@0+ (1,0) [0|1] "" Vector__XXX
    SG_ VIU_FL_NMNotSleep_BYTE2BIT7 : 23|1@0+ (1,0) [0|1] "" Vector__XXX
    SG_ VIU_FL_NMNotSleep_BYTE3BIT0 : 24|1@0+ (1,0) [0|1] "" Vector__XXX
    SG_ VIU_FL_NMNotSleep_BYTE3BIT1 : 25|1@0+ (1,0) [0|1] "" Vector__XXX
    SG_ VIU_FL_NMNotSleep_BYTE3BIT2 : 26|1@0+ (1,0) [0|1] "" Vector__XXX
    SG_ VIU_FL_NMNotSleep_BYTE3BIT3 : 27|1@0+ (1,0) [0|1] "" Vector__XXX
    SG_ VIU_FL_NMNotSleep_BYTE3BIT4 : 28|1@0+ (1,0) [0|1] "" Vector__XXX
    SG_ VIU_FL_NMNotSleep_BYTE3BIT5 : 29|1@0+ (1,0) [0|1] "" Vector__XXX
    SG_ VIU_FL_NMNotSleep_BYTE3BIT6 : 30|1@0+ (1,0) [0|1] "" Vector__XXX
    SG_ VIU_FL_NMNotSleep_BYTE3BIT7 : 31|1@0+ (1,0) [0|1] "" Vector__XXX
    SG_ VIU_FL_NMNotSleep_BYTE4BIT0 : 32|1@0+ (1,0) [0|1] "" Vector__XXX
    SG_ VIU_FL_NMNotSleep_BYTE4BIT1 : 33|1@0+ (1,0) [0|1] "" Vector__XXX
    SG_ VIU_FL_NMNotSleep_BYTE4BIT2 : 34|1@0+ (1,0) [0|1] "" Vector__XXX
    SG_ VIU_FL_NMNotSleep_BYTE4BIT3 : 35|1@0+ (1,0) [0|1] "" Vector__XXX
    SG_ VIU_FL_NMNotSleep_BYTE4BIT4 : 36|1@0+ (1,0) [0|1] "" Vector__XXX
    SG_ VIU_FL_NMNotSleep_BYTE4BIT5 : 37|1@0+ (1,0) [0|1] "" Vector__XXX
    SG_ VIU_FL_NMNotSleep_BYTE4BIT6 : 38|1@0+ (1,0) [0|1] "" Vector__XXX
    SG_ VIU_FL_NMNotSleep_BYTE4BIT7 : 39|1@0+ (1,0) [0|1] "" Vector__XXX
    SG_ VIU_FL_NMNotSleep_BYTE5BIT0 : 40|1@0+ (1,0) [0|1] "" Vector__XXX
    SG_ VIU_FL_NMNotSleep_BYTE5BIT1 : 41|1@0+ (1,0) [0|1] "" Vector__XXX
    SG_ VIU_FL_NMNotSleep_BYTE5BIT2 : 42|1@0+ (1,0) [0|1] "" Vector__XXX
    SG_ VIU_FL_NMNotSleep_BYTE5BIT3 : 43|1@0+ (1,0) [0|1] "" Vector__XXX
    SG_ VIU_FL_NMNotSleep_BYTE5BIT4 : 44|1@0+ (1,0) [0|1] "" Vector__XXX
    SG_ VIU_FL_NMNotSleep_BYTE5BIT5 : 45|1@0+ (1,0) [0|1] "" Vector__XXX
    SG_ VIU_FL_NMNotSleep_BYTE5BIT6 : 46|1@0+ (1,0) [0|1] "" Vector__XXX
    SG_ VIU_FL_NMNotSleep_BYTE5BIT7 : 47|1@0+ (1,0) [0|1] "" Vector__XXX
    SG_ VIU_FL_NMNotSleep_BYTE6BIT0 : 48|1@0+ (1,0) [0|1] "" Vector__XXX
    SG_ VIU_FL_NMNotSleep_BYTE6BIT1 : 49|1@0+ (1,0) [0|1] "" Vector__XXX
    SG_ VIU_FL_NMNotSleep_BYTE6BIT2 : 50|1@0+ (1,0) [0|1] "" Vector__XXX
    SG_ VIU_FL_NMNotSleep_BYTE6BIT3 : 51|1@0+ (1,0) [0|1] "" Vector__XXX
    SG_ VIU_FL_NMNotSleep_BYTE6BIT4 : 52|1@0+ (1,0) [0|1] "" Vector__XXX
    SG_ VIU_FL_NMNotSleep_BYTE6BIT5 : 53|1@0+ (1,0) [0|1] "" Vector__XXX
    SG_ VIU_FL_NMNotSleep_BYTE6BIT6 : 54|1@0+ (1,0) [0|1] "" Vector__XXX
    SG_ VIU_FL_NMNotSleep_BYTE6BIT7 : 55|1@0+ (1,0) [0|1] "" Vector__XXX
    SG_ VIU_FL_NMNotSleep_BYTE7BIT0 : 56|1@0+ (1,0) [0|1] "" Vector__XXX
    SG_ VIU_FL_NMNotSleep_BYTE7BIT1 : 57|1@0+ (1,0) [0|1] "" Vector__XXX
    SG_ VIU_FL_NMNotSleep_BYTE7BIT2 : 58|1@0+ (1,0) [0|1] "" Vector__XXX
    SG_ VIU_FL_NMNotSleep_BYTE7BIT3 : 59|1@0+ (1,0) [0|1] "" Vector__XXX
    SG_ VIU_FL_NMNotSleep_BYTE7BIT4 : 60|1@0+ (1,0) [0|1] "" Vector__XXX
    SG_ VIU_FL_NMNotSleep_BYTE7BIT5 : 61|1@0+ (1,0) [0|1] "" Vector__XXX
    SG_ VIU_FL_NMNotSleep_BYTE7BIT6 : 62|1@0+ (1,0) [0|1] "" Vector__XXX
    SG_ VIU_FL_NMNotSleep_BYTE7BIT7 : 63|1@0+ (1,0) [0|1] "" Vector__XXX
    SG_ VIU_FL_NMWakeUp : 7|8@0+ (1,0) [0|255] "" Vector__XXX

BO_ 1369 VIU_FR_559: 8 VIU_FR
    SG_ VIU_FR_NMNotSleep_BYTE2BIT0 : 16|1@0+ (1,0) [0|1] "" VIU_FL
    SG_ VIU_FR_NMNotSleep_BYTE2BIT1 : 17|1@0+ (1,0) [0|1] "" VIU_FL
    SG_ VIU_FR_NMNotSleep_BYTE2BIT2 : 18|1@0+ (1,0) [0|1] "" VIU_FL
    SG_ VIU_FR_NMNotSleep_BYTE2BIT3 : 19|1@0+ (1,0) [0|1] "" VIU_FL
    SG_ VIU_FR_NMNotSleep_BYTE2BIT4 : 20|1@0+ (1,0) [0|1] "" VIU_FL
    SG_ VIU_FR_NMNotSleep_BYTE2BIT5 : 21|1@0+ (1,0) [0|1] "" VIU_FL
    SG_ VIU_FR_NMNotSleep_BYTE2BIT6 : 22|1@0+ (1,0) [0|1] "" VIU_FL
    SG_ VIU_FR_NMNotSleep_BYTE2BIT7 : 23|1@0+ (1,0) [0|1] "" VIU_FL
    SG_ VIU_FR_NMNotSleep_BYTE3BIT0 : 24|1@0+ (1,0) [0|1] "" VIU_FL
    SG_ VIU_FR_NMNotSleep_BYTE3BIT1 : 25|1@0+ (1,0) [0|1] "" VIU_FL
    SG_ VIU_FR_NMNotSleep_BYTE3BIT2 : 26|1@0+ (1,0) [0|1] "" VIU_FL
    SG_ VIU_FR_NMNotSleep_BYTE3BIT3 : 27|1@0+ (1,0) [0|1] "" VIU_FL
    SG_ VIU_FR_NMNotSleep_BYTE3BIT4 : 28|1@0+ (1,0) [0|1] "" VIU_FL
    SG_ VIU_FR_NMNotSleep_BYTE3BIT5 : 29|1@0+ (1,0) [0|1] "" VIU_FL
    SG_ VIU_FR_NMNotSleep_BYTE3BIT6 : 30|1@0+ (1,0) [0|1] "" VIU_FL
    SG_ VIU_FR_NMNotSleep_BYTE3BIT7 : 31|1@0+ (1,0) [0|1] "" VIU_FL
    SG_ VIU_FR_NMNotSleep_BYTE4BIT0 : 32|1@0+ (1,0) [0|1] "" VIU_FL
    SG_ VIU_FR_NMNotSleep_BYTE4BIT1 : 33|1@0+ (1,0) [0|1] "" VIU_FL
    SG_ VIU_FR_NMNotSleep_BYTE4BIT2 : 34|1@0+ (1,0) [0|1] "" VIU_FL
    SG_ VIU_FR_NMNotSleep_BYTE4BIT3 : 35|1@0+ (1,0) [0|1] "" VIU_FL
    SG_ VIU_FR_NMNotSleep_BYTE4BIT4 : 36|1@0+ (1,0) [0|1] "" VIU_FL
    SG_ VIU_FR_NMNotSleep_BYTE4BIT5 : 37|1@0+ (1,0) [0|1] "" VIU_FL
    SG_ VIU_FR_NMNotSleep_BYTE4BIT6 : 38|1@0+ (1,0) [0|1] "" VIU_FL
    SG_ VIU_FR_NMNotSleep_BYTE4BIT7 : 39|1@0+ (1,0) [0|1] "" VIU_FL
    SG_ VIU_FR_NMNotSleep_BYTE5BIT0 : 40|1@0+ (1,0) [0|1] "" VIU_FL
    SG_ VIU_FR_NMNotSleep_BYTE5BIT1 : 41|1@0+ (1,0) [0|1] "" VIU_FL
    SG_ VIU_FR_NMNotSleep_BYTE5BIT2 : 42|1@0+ (1,0) [0|1] "" VIU_FL
    SG_ VIU_FR_NMNotSleep_BYTE5BIT3 : 43|1@0+ (1,0) [0|1] "" VIU_FL
    SG_ VIU_FR_NMNotSleep_BYTE5BIT4 : 44|1@0+ (1,0) [0|1] "" VIU_FL
    SG_ VIU_FR_NMNotSleep_BYTE5BIT5 : 45|1@0+ (1,0) [0|1] "" VIU_FL
    SG_ VIU_FR_NMNotSleep_BYTE5BIT6 : 46|1@0+ (1,0) [0|1] "" VIU_FL
    SG_ VIU_FR_NMNotSleep_BYTE5BIT7 : 47|1@0+ (1,0) [0|1] "" VIU_FL
    SG_ VIU_FR_NMNotSleep_BYTE6BIT0 : 48|1@0+ (1,0) [0|1] "" VIU_FL
    SG_ VIU_FR_NMNotSleep_BYTE6BIT1 : 49|1@0+ (1,0) [0|1] "" VIU_FL
    SG_ VIU_FR_NMNotSleep_BYTE6BIT2 : 50|1@0+ (1,0) [0|1] "" VIU_FL
    SG_ VIU_FR_NMNotSleep_BYTE6BIT3 : 51|1@0+ (1,0) [0|1] "" VIU_FL
    SG_ VIU_FR_NMNotSleep_BYTE6BIT4 : 52|1@0+ (1,0) [0|1] "" VIU_FL
    SG_ VIU_FR_NMNotSleep_BYTE6BIT5 : 53|1@0+ (1,0) [0|1] "" VIU_FL
    SG_ VIU_FR_NMNotSleep_BYTE6BIT6 : 54|1@0+ (1,0) [0|1] "" VIU_FL
    SG_ VIU_FR_NMNotSleep_BYTE6BIT7 : 55|1@0+ (1,0) [0|1] "" VIU_FL
    SG_ VIU_FR_NMNotSleep_BYTE7BIT0 : 56|1@0+ (1,0) [0|1] "" VIU_FL
    SG_ VIU_FR_NMNotSleep_BYTE7BIT1 : 57|1@0+ (1,0) [0|1] "" VIU_FL
    SG_ VIU_FR_NMNotSleep_BYTE7BIT2 : 58|1@0+ (1,0) [0|1] "" VIU_FL
    SG_ VIU_FR_NMNotSleep_BYTE7BIT3 : 59|1@0+ (1,0) [0|1] "" VIU_FL
    SG_ VIU_FR_NMNotSleep_BYTE7BIT4 : 60|1@0+ (1,0) [0|1] "" VIU_FL
    SG_ VIU_FR_NMNotSleep_BYTE7BIT5 : 61|1@0+ (1,0) [0|1] "" VIU_FL
    SG_ VIU_FR_NMNotSleep_BYTE7BIT6 : 62|1@0+ (1,0) [0|1] "" VIU_FL
    SG_ VIU_FR_NMNotSleep_BYTE7BIT7 : 63|1@0+ (1,0) [0|1] "" VIU_FL
    SG_ VIU_FR_NMWakeUp : 7|8@0+ (1,0) [0|255] "" VIU_FL

BO_ 1396 EDC_574: 8 EDC
    SG_ EDC_NotSleep_Android : 39|16@0+ (1,0) [0|65535] "" VIU_FL
    SG_ EDC_NotSleep_Android_other : 53|1@0+ (1,0) [0|1] "" VIU_FL
    SG_ EDC_NotSleep_BYTE5BIT0 : 11|4@0+ (1,0) [0|15] "" VIU_FL
    SG_ EDC_NotSleep_BYTE6BIT0 : 48|1@0+ (1,0) [0|1] "" VIU_FL
    SG_ EDC_NotSleep_BYTE6BIT1 : 49|1@0+ (1,0) [0|1] "" VIU_FL
    SG_ EDC_NotSleep_BYTE6BIT2 : 50|1@0+ (1,0) [0|1] "" VIU_FL
    SG_ EDC_NotSleep_BYTE6BIT3 : 51|1@0+ (1,0) [0|1] "" VIU_FL
    SG_ EDC_NotSleep_BYTE6BIT4 : 52|1@0+ (1,0) [0|1] "" VIU_FL
    SG_ EDC_NotSleep_BYTE7BIT0 : 56|1@0+ (1,0) [0|1] "" VIU_FL
    SG_ EDC_NotSleep_BYTE7BIT1 : 57|1@0+ (1,0) [0|1] "" VIU_FL
    SG_ EDC_NotSleep_BYTE7BIT2 : 58|1@0+ (1,0) [0|1] "" VIU_FL
    SG_ EDC_NotSleep_BYTE7BIT3 : 59|1@0+ (1,0) [0|1] "" VIU_FL
    SG_ EDC_NotSleep_BYTE7BIT4 : 60|1@0+ (1,0) [0|1] "" VIU_FL
    SG_ EDC_NotSleep_BYTE7BIT5 : 61|1@0+ (1,0) [0|1] "" VIU_FL
    SG_ EDC_NotSleep_BYTE7BIT6 : 62|1@0+ (1,0) [0|1] "" VIU_FL
    SG_ EDC_NotSleep_BYTE7BIT7 : 63|1@0+ (1,0) [0|1] "" VIU_FL
    SG_ EDC_wakeup_BYTE2BIT0 : 16|1@0+ (1,0) [0|1] "" VIU_FL
    SG_ EDC_wakeup_BYTE2BIT1 : 17|1@0+ (1,0) [0|1] "" VIU_FL
    SG_ EDC_wakeup_BYTE2BIT2 : 18|1@0+ (1,0) [0|1] "" VIU_FL
    SG_ EDC_wakeup_BYTE2BIT3 : 19|1@0+ (1,0) [0|1] "" VIU_FL
    SG_ EDC_WakeUp_BYTE3BIT0 : 24|1@0+ (1,0) [0|1] "" VIU_FL
    SG_ EDC_WakeUp_BYTE3BIT1 : 25|1@0+ (1,0) [0|1] "" VIU_FL
    SG_ EDC_WakeUp_BYTE3BIT2 : 26|1@0+ (1,0) [0|1] "" VIU_FL
    SG_ EDC_WakeUp_BYTE3BIT3 : 27|1@0+ (1,0) [0|1] "" VIU_FL
    SG_ EDC_WakeUp_BYTE3BIT4 : 28|1@0+ (1,0) [0|1] "" VIU_FL
    SG_ EDC_WakeUp_BYTE3BIT5 : 29|1@0+ (1,0) [0|1] "" VIU_FL
    SG_ EDC_WakeUp_BYTE3BIT6 : 30|1@0+ (1,0) [0|1] "" VIU_FL
    SG_ EDC_WakeUp_BYTE3BIT7 : 31|1@0+ (1,0) [0|1] "" VIU_FL
    SG_ EDC_NotSleep_BYTE1BIT4 : 12|1@0+ (1,0) [0|1] "" VIU_FL
    SG_ EDC_NotSleep_BYTE1BIT5 : 13|1@0+ (1,0) [0|1] "" VIU_FL
    SG_ EDC_NotSleep_BYTE1BIT6 : 14|1@0+ (1,0) [0|1] "" VIU_FL
    SG_ EDC_NotSleep_BYTE1BIT7 : 15|1@0+ (1,0) [0|1] "" VIU_FL
    SG_ EDC_wakeup_BYTE2BIT4 : 20|1@0+ (1,0) [0|1] "" VIU_FL
    SG_ EDC_wakeup_BYTE2BIT5 : 21|1@0+ (1,0) [0|1] "" VIU_FL
    SG_ EDC_wakeup_BYTE2BIT6 : 22|1@0+ (1,0) [0|1] "" VIU_FL
    SG_ EDC_wakeup_BYTE2BIT7 : 23|1@0+ (1,0) [0|1] "" VIU_FL

CM_ BO_ 919 " ";
CM_ SG_ 919 OTA_CRCCheck_397 "OTA模式信号校验和";
CM_ SG_ 919 OTA_RollingCounter_397 "OTA模式信号计数器";
CM_ SG_ 919 VIU_FL_OTAmode "OTA模式";
CM_ SG_ 919 VIU_LocalDiagMode "本地诊断状态";
CM_ BO_ 920 " ";
CM_ SG_ 920 EDC_EOLMode "电检流程执行状态";
CM_ SG_ 920 EDC_VerCollectMode "版本号收集执行状态";
CM_ BO_ 921 " ";
CM_ SG_ 921 TBOX_RemotDiagMode "远程诊断状态";
CM_ BO_ 930 " ";
CM_ SG_ 930 EmsFlexfuelDisplay "灵活燃料加油提示";
CM_ SG_ 930 EmsLowTempMilgRemind "长期低温短里程提醒信号";
CM_ BO_ 931 " ";
CM_ SG_ 931 EDC_EpbFctLamp "EPB功能指示灯";
CM_ SG_ 931 EDC_EpsFaild "助力转向故障位";
CM_ SG_ 931 EDC_EmsMilLamp "MIL指示灯";
CM_ SG_ 931 EDC_VcuDrvEgyInd "驾驶能量指示";
CM_ SG_ 931 EDC_VcuFuelLevelPercent "油量百分比";
CM_ SG_ 931 EDC_VcuFulLimdDrvgDst "燃油续驶里程";
CM_ SG_ 931 EDC_VcuEvDrvResiMilg "纯电续驶里程";
CM_ SG_ 931 EDC_VcuVehAvrgEgyCnseLongTime "长期平均电耗";
CM_ SG_ 931 EDC_VcuVehAvrgFuelCnseLongTime "长期平均油耗";
CM_ SG_ 931 EDC_VcuVehAvrgEgyCnseInTripA "小计里程平均电耗";
CM_ SG_ 931 EDC_VcuVehAvrgTotCnseInTripA "小计里程综合能耗";
CM_ SG_ 931 EDC_LoBeamInfo "近光灯";
CM_ SG_ 931 EDC_HiBeamInfo "远光灯";
CM_ SG_ 931 EDC_AutoHiBeamInfo "自动远光灯";
CM_ SG_ 931 EDC_Le_ReLoglSt "左后雾灯";
CM_ SG_ 931 EDC_Ri_ReLoglSt "右后雾灯";
CM_ SG_ 931 EDC_PosnLiInfo "位置灯";
CM_ SG_ 931 EDC_VcuPlugConnectLamp "充电线连接指示灯";
CM_ SG_ 931 EDC_BcuBattSocUnderLamp "动力系统低电荷状态指示灯";
CM_ SG_ 931 EDC_VcuChrgStsLamp "充电状态指示灯";
CM_ SG_ 931 EDC_DcacStsLamp "放电状态指示灯";
CM_ SG_ 931 EDC_LoBattErrSts "低压蓄电池故障状态";
CM_ SG_ 931 EDC_VcuVehPwrLimLamp "驱动功率限制指示灯";
CM_ SG_ 931 EDC_VcuEngineOilPressureLowSts "机油压力低";
CM_ SG_ 931 EDC_PsgSeatSBR "副驾座椅人员检测";
CM_ SG_ 931 EDC_RearLeSeatSBR "后排左人员检测";
CM_ SG_ 931 EDC_RearMidSeatSBR "后排中人员检测";
CM_ SG_ 931 EDC_RearRiSeatSBR "后排右人员检测";
CM_ SG_ 931 EDC_SBR "后排安全带未系提醒";
CM_ SG_ 931 EDC_AD_NDAStatus "NID状态";
CM_ SG_ 931 EDC_AD_BSDLCA_LeftAlert "左侧盲点检测_换道辅助报警信号";
CM_ SG_ 931 EDC_AD_BSDLCA_RightAlert "右侧盲点检测_换道辅助报警信号";
CM_ SG_ 931 EDC_ACC_SetSpeed "ACC目标巡航车速";
CM_ SG_ 931 EDC_time_hr "时间（时）";
CM_ SG_ 931 EDC_time_min "时间（分）";
CM_ SG_ 931 EDC_ViuEgyResiColor "剩余电量显示颜色";
CM_ SG_ 931 EDC_ViuEvResiMilgInvldDisp "剩余纯电续驶里程无效";
CM_ SG_ 931 EDC_LaneLeft_Status "左车道线状态";
CM_ SG_ 931 EDC_LaneRight_Status "右车道线状态";
CM_ SG_ 931 EDC_ACC_TimeGapSet "ACC跟车时距设置";
CM_ SG_ 931 EDC_Objx_Detection "跟车目标";
CM_ SG_ 931 EDC_Lane_PointArr "车道线点集";
CM_ SG_ 931 EDC_EpbFailrLamp "EPB错误指示灯";
CM_ SG_ 931 EDC_trafficLight "红绿灯状态";
CM_ SG_ 931 EDC_countdown "红绿灯倒计时";
CM_ SG_ 931 EDC_mileage "里程显示设置";
CM_ SG_ 931 EDC_brightness "亮度";
CM_ SG_ 931 EDC_Autobrightness "自适应亮度";
CM_ SG_ 931 EDC_FW_Brightness "前向光光照强度";
CM_ SG_ 931 EDC_AMB_Brightness "环境光光照强度";
CM_ SG_ 931 EDC_AD_AEBStatus "AEB系统状态";
CM_ SG_ 931 EDC_trip "小计里程";
CM_ SG_ 931 EDC_VcuPwrSysErrLamp "动力系统故障指示灯";
CM_ SG_ 931 EDCDisplayEspVehSpd "显示车速";
CM_ BO_ 937 " ";
CM_ SG_ 937 AD_SYNC_CRC "AD时间同步校验";
CM_ SG_ 937 AD_SYNC_Sequence "AD时间同步序计数器";
CM_ SG_ 937 AD_SYNC_Sync_Time "AD时间同步时间";
CM_ SG_ 937 AD_SYNC_TimeDomain "AD时间同步时间域";
CM_ SG_ 937 AD_SYNC_Type "AD时间同步类型";
CM_ SG_ 937 AD_SYNC_UserByte_OVS_SGW "AD时间同步用户_溢出_SGW字节";
CM_ BO_ 941 " ";
CM_ SG_ 941 RRS_FLCDistance "前左侧障碍物距离";
CM_ SG_ 941 RRS_FLMDistance "前左中障碍物距离";
CM_ SG_ 941 RRS_FLODistance "前左角障碍物距离";
CM_ SG_ 941 RRS_FLSDistance "前左边障碍物距离";
CM_ SG_ 941 RRS_FRCDistance "前右侧障碍物距离";
CM_ SG_ 941 RRS_FRMDistance "前右中障碍物距离";
CM_ SG_ 941 RRS_FRODistance "前右角障碍物距离";
CM_ SG_ 941 RRS_FRSDistance "前右边障碍物距离";
CM_ SG_ 941 RRS_RLCDistance "后左侧障碍物距离";
CM_ SG_ 941 RRS_RLMDistance "后左中障碍物距离";
CM_ SG_ 941 RRS_RLODistance "后左角障碍物距离";
CM_ SG_ 941 RRS_RLSDistance "后左边障碍物距离";
CM_ SG_ 941 RRS_RRCDistance "后右侧障碍物距离";
CM_ SG_ 941 RRS_RRMDistance "后右中障碍物距离";
CM_ SG_ 941 RRS_RRODistance "后右角障碍物距离";
CM_ SG_ 941 RRS_RRSDistance "后右边障碍物距离";
CM_ SG_ 941 ACC_CRCCheck_3AD "ACC_3AD校验和";
CM_ SG_ 941 ACC_RollingCounter_3AD "ACC_3AD计数器";
CM_ SG_ 941 AD_CNAStatus "CNA系统状态";
CM_ SG_ 941 AD_HandsOnReq "handsOn请求";
CM_ SG_ 941 AD_IACCHWAMode "IACC/HWA工作模式";
CM_ SG_ 941 AD_IACCMode "IACC工作模式";
CM_ SG_ 941 AD_LatTakeoverReq "横向接管请求";
CM_ SG_ 941 AD_LngTakeOverReq "纵向接管请求";
CM_ SG_ 941 AD_NDAStatus "NDA状态";
CM_ SG_ 941 AD_TakeoverReqAtIPFail "IP故障时驾驶员接管请求";
CM_ SG_ 941 AD_TJPStatus "TJP状态";
CM_ SG_ 941 AD_Voiceinfo "驾驶辅助声音信息";
CM_ SG_ 941 RRS_SystemFailureFlag "雷达系统故障";
CM_ BO_ 945 " ";
CM_ SG_ 945 ErpsFctMode "ERPS功能动态配置";
CM_ SG_ 945 BcmTrDoorSts "行李箱门状态";
CM_ SG_ 945 BcmTrDoorWinPosi "后背门玻璃位置";
CM_ SG_ 945 BcmTrDoorWinSts "后背门玻璃状态";
CM_ SG_ 945 BCMRiDoorLockSwt "车身右侧门锁状态";
CM_ SG_ 945 VIUPsgSeatSBR "副驾座椅人员检测";
CM_ SG_ 945 VIURearLeSeatSBR "二排左座椅人员检测";
CM_ SG_ 945 VIURearMidSeatSBR "二排中座椅人员检测";
CM_ SG_ 945 VIURearRiSeatSBR "二排右座椅人员检测";
CM_ SG_ 945 EMBBrkSysFailrBuzAlrmSec "EMB系统失效蜂鸣报警（辅）";
CM_ SG_ 945 EMBBrkSysFctdownTextDispReqSec "整车系统降级提示（辅）";
CM_ SG_ 945 EpbTextDispReqSec "EPB系统文本显示（辅）";
CM_ BO_ 959 " ";
CM_ SG_ 959 HUFRTopPositionVolSET "前右天空方位增益设置";
CM_ SG_ 959 HURLPositionDelaySET "后左方位延时设置";
CM_ SG_ 959 HURLPositionVolSET "后左方位增益设置";
CM_ SG_ 959 HURLSurroundPositionDelaySET "后左环绕方位延时设置";
CM_ SG_ 959 HURLSurroundPositionVolSET "后左环绕方位增益设置";
CM_ SG_ 959 HURLTopPositionDelaySET "后左天空方位延时设置";
CM_ SG_ 959 HURLTopPositionVolSET "后左天空方位增益设置";
CM_ SG_ 959 HURRPositionDelaySET "后右方位延时设置";
CM_ SG_ 959 HURRPositionVolSET "后右方位增益设置";
CM_ SG_ 959 HURRSurroundPositionDelaySET "后右环绕方位延时设置";
CM_ SG_ 959 HURRSurroundPositionVolSET "后右环绕方位增益设置";
CM_ SG_ 959 HURRTopPositionDelaySET "后右天空方位延时设置";
CM_ SG_ 959 HURRTopPositionVolSET "后右天空方位增益设置";
CM_ BO_ 965 " ";
CM_ SG_ 965 AD_HWPStatus "HWP系统状态";
CM_ SG_ 965 ACC_ADCNotice "智能驾驶提示信息";
CM_ SG_ 965 AD_SafetyNotice "安全提示信息";
CM_ SG_ 965 AD_CRCCheck_3C5 "AD_3C5校验和";
CM_ SG_ 965 AD_RollingCounter_3C5 "AD_3C5计数器";
CM_ BO_ 1000 " ";
CM_ SG_ 1000 Reserved_message3E8 "预留的报文（用于生成DBC）";
CM_ BO_ 1001 " ";
CM_ SG_ 1001 Reserved_message3E9 "预留的报文（用于生成DBC）";
CM_ BO_ 1015 " ";
CM_ SG_ 1015 IP_brightness "屏幕亮度设置值";
CM_ SG_ 1015 IPFault "仪表故障";
CM_ BO_ 1025 " ";
CM_ SG_ 1025 NM_message401 "网络管理报文（用于生成DBC）";
CM_ BO_ 1031 " ";
CM_ SG_ 1031 NM_message407 "网络管理报文（用于生成DBC）";
CM_ BO_ 1036 " ";
CM_ SG_ 1036 NM_message40C "网络管理报文（用于生成DBC）";
CM_ BO_ 1037 " ";
CM_ SG_ 1037 NM_message40D "网络管理报文（用于生成DBC）";
CM_ BO_ 1041 " ";
CM_ SG_ 1041 NM_message411 "网络管理报文（用于生成DBC）";
CM_ BO_ 1059 " ";
CM_ SG_ 1059 NM_message423 "网络管理报文（用于生成DBC）";
CM_ BO_ 1193 " ";
CM_ SG_ 1193 NM_message4A9 "网络管理报文（用于生成DBC）";
CM_ BO_ 1280 " ";
CM_ SG_ 1280 TBOX_NotSleep_BYTE6BIT0 "不休眠原因_9";
CM_ SG_ 1280 TBOX_NotSleep_BYTE7BIT0 "不休眠原因_1";
CM_ SG_ 1280 TBOX_NotSleep_BYTE7BIT1 "不休眠原因_2";
CM_ SG_ 1280 TBOX_NotSleep_BYTE7BIT2 "不休眠原因_3";
CM_ SG_ 1280 TBOX_NotSleep_BYTE7BIT3 "不休眠原因_4";
CM_ SG_ 1280 TBOX_NotSleep_BYTE7BIT4 "不休眠原因_5";
CM_ SG_ 1280 TBOX_NotSleep_BYTE7BIT5 "不休眠原因_6";
CM_ SG_ 1280 TBOX_NotSleep_BYTE7BIT6 "不休眠原因_7";
CM_ SG_ 1280 TBOX_NotSleep_BYTE7BIT7 "不休眠原因_8";
CM_ SG_ 1280 TBOX_WakeUp_BYTE3BIT0 "唤醒原因_1";
CM_ SG_ 1280 TBOX_WakeUp_BYTE3BIT1 "唤醒原因_2";
CM_ SG_ 1280 TBOX_WakeUp_BYTE3BIT2 "唤醒原因_3";
CM_ SG_ 1280 TBOX_WakeUp_BYTE3BIT3 "唤醒原因_4";
CM_ SG_ 1280 TBOX_WakeUp_BYTE3BIT4 "唤醒原因_5";
CM_ SG_ 1280 TBOX_WakeUp_BYTE3BIT5 "唤醒原因6";
CM_ SG_ 1280 TBOX_WakeUp_BYTE3BIT6 "唤醒原因_7";
CM_ BO_ 1288 " ";
CM_ SG_ 1288 TMS_BatteryPumpErrCode "电池水泵故障类型";
CM_ SG_ 1288 TMS_BatteryPumpSt "电池水泵状态";
CM_ SG_ 1288 TMS_BattInpWtrTValid "电池入水口温度传感器有效";
CM_ SG_ 1288 TMS_ECV1ErrCode_Radiator "三通阀1的故障类型散热器侧";
CM_ SG_ 1288 TMS_ECV1MotorSt_Radiator "三通阀1电机运行状态散热器侧";
CM_ SG_ 1288 TMS_ECV1PosnAct_Radiator "三通阀1实际位置散热器侧";
CM_ SG_ 1288 TMS_Ecv1St_Radiator "三通阀1的工作状态散热器侧";
CM_ SG_ 1288 TMS_ECV2ErrCode_Battery "三通阀2的故障类型电池侧";
CM_ SG_ 1288 TMS_ECV2MotorSt_Battery "三通阀2电机运行状态电池侧";
CM_ SG_ 1288 TMS_ECV2PosnAct_Battery "三通阀2实际位置电池侧";
CM_ SG_ 1288 TMS_ECV2St_Battery "三通阀2的工作状态电池侧";
CM_ SG_ 1288 TMS_ECV3ErrCode_Hydrothermal "三通阀3的故障类型水热侧";
CM_ SG_ 1288 TMS_ECV3MotorSt_Hydrothermal "三通阀3电机运行状态水热侧";
CM_ SG_ 1288 TMS_ECV3PosnAct_Hydrothermal "三通阀3实际位置水热侧";
CM_ SG_ 1288 TMS_ECV3St_Hydrothermal "三通阀3的工作状态水热侧";
CM_ SG_ 1288 TMS_ExtendRangePumpErrCode "增程水泵故障类型";
CM_ SG_ 1288 TMS_ExtendRangePumpSt "增程水泵状态";
CM_ SG_ 1288 TMS_Exv1ErrCode_HVAC "EXV1的故障类型空调箱侧";
CM_ SG_ 1288 TMS_Exv1InitSt_HVAC "EXV1初始化状态空调箱侧";
CM_ SG_ 1288 TMS_Exv1PosnAct_HVAC "EXV1实际位置空调箱侧";
CM_ SG_ 1288 TMS_Exv1RunSt_HVAC "EXV1运行状态空调箱侧";
CM_ SG_ 1288 TMS_Exv2ErrCode_Battery "EXV2的故障类型电池侧";
CM_ SG_ 1288 TMS_Exv2InitSt_Battery "EXV2初始化状态电池侧";
CM_ SG_ 1288 TMS_Exv2RunSt_Battery "EXV2运行状态电池侧";
CM_ SG_ 1288 TMS_Exv3ErrCode_WasteHeatRe "EXV3的故障类型余热回收";
CM_ SG_ 1288 TMS_Exv3InitSt_WasteHeatRe "EXV3初始化状态余热回收";
CM_ SG_ 1288 TMS_Exv3PosnAct_WasteHeatRe "EXV3实际位置余热回收";
CM_ SG_ 1288 TMS_Exv3RunSt_WasteHeatRe "EXV3运行状态余热回收";
CM_ SG_ 1288 TMS_Exv4ErrCode_Refrigerant "EXV4的故障类型冷媒三通阀";
CM_ SG_ 1288 TMS_Exv4InitSt_Refrigerant "EXV4初始化状态冷媒三通阀";
CM_ SG_ 1288 TMS_Exv4PosnAct_Refrigerant "EXV4实际位置冷媒三通阀";
CM_ SG_ 1288 TMS_Exv4RunningSt_Refrigerant "EXV4运行状态冷媒三通阀";
CM_ SG_ 1288 TMS_FWV1ErrCode "四通阀1的故障类型";
CM_ SG_ 1288 TMS_FWV1MotorSt "四通阀1电机运行状态";
CM_ SG_ 1288 TMS_FWV1PosnAct "四通阀1实际位置";
CM_ SG_ 1288 TMS_FWV1St "四通阀1的工作状态";
CM_ SG_ 1288 TMS_InSeriesPumpErrCode "串联水泵故障类型";
CM_ SG_ 1288 TMS_InSeriesPumpSpdAct "串联水泵实际运行转速比例";
CM_ SG_ 1288 TMS_MotorPumpSt "电驱水泵状态";
CM_ SG_ 1288 TMS_OilCoolerWtrT "油冷器入口温度";
CM_ SG_ 1288 TMS_OilCoolerWtrTValid "油冷器入水口温度传感器有效";
CM_ SG_ 1288 TMS_PT1PrErrCode "PT传感器1压力故障类型";
CM_ SG_ 1288 TMS_PT1TempSnsrErrCode "PT传感器1温度故障类型";
CM_ SG_ 1288 TMS_PT2PrErrCode "PT传感器2压力故障类型";
CM_ SG_ 1288 TMS_PT2TempSnsrErrCode "PT传感器2温度故障类型";
CM_ SG_ 1288 TMS_PT3PrErrCode "PT传感器3压力故障类型";
CM_ SG_ 1288 TMS_PT3TempSnsrErrCode "PT传感器3温度故障类型";
CM_ SG_ 1288 TMS_PT4P_LiquidStorage "PT4压力值储液罐前";
CM_ SG_ 1288 TMS_PT4PrErrCode "PT传感器4压力故障类型";
CM_ SG_ 1288 TMS_PT4temp_LiquidStorage "PT4温度值储液罐前";
CM_ SG_ 1288 TMS_PT4TempSnsrErrCode "PT传感器4温度故障类型";
CM_ SG_ 1288 TMS_PT5Pr_WasteHeatRe "PT5压力值余热回收出口";
CM_ SG_ 1288 TMS_PT5PrErrCode "PT传感器5压力故障类型";
CM_ SG_ 1288 TMS_PT5temp_WasteHeatRe "PT5温度值余热回收出口";
CM_ SG_ 1288 TMS_PT5TempSnsrErrCode "PT传感器5温度故障类型";
CM_ SG_ 1288 TMS_PT6Pr_RearEvap "PT6压力值后蒸";
CM_ SG_ 1288 TMS_PT6PrErrCode "PT传感器6压力故障类型";
CM_ SG_ 1288 TMS_PT6temp_RearEvap "PT6温度值后蒸";
CM_ SG_ 1288 TMS_PT6TempSnsrErrCode "PT传感器6温度故障类型";
CM_ SG_ 1288 TMS_SolnVlv1St_DLP "截止阀2状态DLP大灯";
CM_ SG_ 1288 TMS_SolnVlv1St_RearEvap "截止阀1状态后蒸阀";
CM_ SG_ 1288 TMS_WarmPumpErrCode "暖风水泵故障类型";
CM_ SG_ 1288 Tms_ExtenderPmpCtrlVal "增程冷却水泵控制PWM值";
CM_ SG_ 1288 Tms_ExtenderPmpSts "增程冷却水泵工作状态";
CM_ SG_ 1288 Tms_HeatPmpCtrlVal "暖风水泵控制PWM值";
CM_ SG_ 1288 Tms_HeatPmpSts "暖风水泵工作状态";
CM_ SG_ 1288 TMS_CTMU_SolnVlv3ErrCode "截止阀3故障类型";
CM_ SG_ 1288 TMS_CTMU_SolnVlv3St "截止阀3状态";
CM_ BO_ 1297 " ";
CM_ SG_ 1297 TPMS_CRCCheck_511 "511帧报文校验";
CM_ SG_ 1297 TPMS_RollingCounter_511 "511帧报文计数";
CM_ SG_ 1297 TpmsSysFailrWarn "胎压系统故障报警";
CM_ SG_ 1297 TpmsLeFrntTireP "左前轮胎压力";
CM_ SG_ 1297 TpmsLeFrntTirePWarn "左前轮胎压力报警";
CM_ SG_ 1297 TpmsLeReTireP "左后轮胎压力";
CM_ SG_ 1297 TpmsLeReTirePWarn "左后轮胎压力报警";
CM_ SG_ 1297 TpmsRiFrntTireP "右前轮胎压力";
CM_ SG_ 1297 TpmsRiFrntTirePWarn "右前轮胎压力报警";
CM_ SG_ 1297 TpmsRiReTireP "右后轮胎压力";
CM_ SG_ 1297 TpmsRiReTirePWarn "右后轮胎压力报警";
CM_ BO_ 1361 " ";
CM_ SG_ 1361 VIU_FL_NMNotSleep_BYTE2BIT0 "VIU_FL NM不允许休眠原因_1";
CM_ SG_ 1361 VIU_FL_NMNotSleep_BYTE2BIT1 "VIU_FL NM不允许休眠原因_2";
CM_ SG_ 1361 VIU_FL_NMNotSleep_BYTE2BIT2 "VIU_FL NM不允许休眠原因_3";
CM_ SG_ 1361 VIU_FL_NMNotSleep_BYTE2BIT3 "VIU_FL NM不允许休眠原因_4";
CM_ SG_ 1361 VIU_FL_NMNotSleep_BYTE2BIT4 "VIU_FL NM不允许休眠原因_5";
CM_ SG_ 1361 VIU_FL_NMNotSleep_BYTE2BIT5 "VIU_FL NM不允许休眠原因_6";
CM_ SG_ 1361 VIU_FL_NMNotSleep_BYTE2BIT6 "VIU_FL NM不允许休眠原因_7";
CM_ SG_ 1361 VIU_FL_NMNotSleep_BYTE2BIT7 "VIU_FL NM不允许休眠原因_8";
CM_ SG_ 1361 VIU_FL_NMNotSleep_BYTE3BIT0 "VIU_FL NM不允许休眠原因_9";
CM_ SG_ 1361 VIU_FL_NMNotSleep_BYTE3BIT1 "VIU_FL NM不允许休眠原因_10";
CM_ SG_ 1361 VIU_FL_NMNotSleep_BYTE3BIT2 "VIU_FL NM不允许休眠原因_11";
CM_ SG_ 1361 VIU_FL_NMNotSleep_BYTE3BIT3 "VIU_FL NM不允许休眠原因_12";
CM_ SG_ 1361 VIU_FL_NMNotSleep_BYTE3BIT4 "VIU_FL NM不允许休眠原因_13";
CM_ SG_ 1361 VIU_FL_NMNotSleep_BYTE3BIT5 "VIU_FL NM不允许休眠原因_14";
CM_ SG_ 1361 VIU_FL_NMNotSleep_BYTE3BIT6 "VIU_FL NM不允许休眠原因_15";
CM_ SG_ 1361 VIU_FL_NMNotSleep_BYTE3BIT7 "VIU_FL NM不允许休眠原因_16";
CM_ SG_ 1361 VIU_FL_NMNotSleep_BYTE4BIT0 "VIU_FL NM不允许休眠原因_17";
CM_ SG_ 1361 VIU_FL_NMNotSleep_BYTE4BIT1 "VIU_FL NM不允许休眠原因_18";
CM_ SG_ 1361 VIU_FL_NMNotSleep_BYTE4BIT2 "VIU_FL NM不允许休眠原因_19";
CM_ SG_ 1361 VIU_FL_NMNotSleep_BYTE4BIT3 "VIU_FL NM不允许休眠原因_20";
CM_ SG_ 1361 VIU_FL_NMNotSleep_BYTE4BIT4 "VIU_FL NM不允许休眠原因_21";
CM_ SG_ 1361 VIU_FL_NMNotSleep_BYTE4BIT5 "VIU_FL NM不允许休眠原因_22";
CM_ SG_ 1361 VIU_FL_NMNotSleep_BYTE4BIT6 "VIU_FL NM不允许休眠原因_23";
CM_ SG_ 1361 VIU_FL_NMNotSleep_BYTE4BIT7 "VIU_FL NM不允许休眠原因_24";
CM_ SG_ 1361 VIU_FL_NMNotSleep_BYTE5BIT0 "VIU_FL NM不允许休眠原因_25";
CM_ SG_ 1361 VIU_FL_NMNotSleep_BYTE5BIT1 "VIU_FL NM不允许休眠原因_26";
CM_ SG_ 1361 VIU_FL_NMNotSleep_BYTE5BIT2 "VIU_FL NM不允许休眠原因_27";
CM_ SG_ 1361 VIU_FL_NMNotSleep_BYTE5BIT3 "VIU_FL NM不允许休眠原因_28";
CM_ SG_ 1361 VIU_FL_NMNotSleep_BYTE5BIT4 "VIU_FL NM不允许休眠原因_29";
CM_ SG_ 1361 VIU_FL_NMNotSleep_BYTE5BIT5 "VIU_FL NM不允许休眠原因_30";
CM_ SG_ 1361 VIU_FL_NMNotSleep_BYTE5BIT6 "VIU_FL NM不允许休眠原因_31";
CM_ SG_ 1361 VIU_FL_NMNotSleep_BYTE5BIT7 "VIU_FL NM不允许休眠原因_32";
CM_ SG_ 1361 VIU_FL_NMNotSleep_BYTE6BIT0 "VIU_FL NM不允许休眠原因_33";
CM_ SG_ 1361 VIU_FL_NMNotSleep_BYTE6BIT1 "VIU_FL NM不允许休眠原因_34";
CM_ SG_ 1361 VIU_FL_NMNotSleep_BYTE6BIT2 "VIU_FL NM不允许休眠原因_35";
CM_ SG_ 1361 VIU_FL_NMNotSleep_BYTE6BIT3 "VIU_FL NM不允许休眠原因_36";
CM_ SG_ 1361 VIU_FL_NMNotSleep_BYTE6BIT4 "VIU_FL NM不允许休眠原因_37";
CM_ SG_ 1361 VIU_FL_NMNotSleep_BYTE6BIT5 "VIU_FL NM不允许休眠原因_38";
CM_ SG_ 1361 VIU_FL_NMNotSleep_BYTE6BIT6 "VIU_FL NM不允许休眠原因_39";
CM_ SG_ 1361 VIU_FL_NMNotSleep_BYTE6BIT7 "VIU_FL NM不允许休眠原因_40";
CM_ SG_ 1361 VIU_FL_NMNotSleep_BYTE7BIT0 "VIU_FL NM不允许休眠原因_41";
CM_ SG_ 1361 VIU_FL_NMNotSleep_BYTE7BIT1 "VIU_FL NM不允许休眠原因_42";
CM_ SG_ 1361 VIU_FL_NMNotSleep_BYTE7BIT2 "VIU_FL NM不允许休眠原因_43";
CM_ SG_ 1361 VIU_FL_NMNotSleep_BYTE7BIT3 "VIU_FL NM不允许休眠原因_44";
CM_ SG_ 1361 VIU_FL_NMNotSleep_BYTE7BIT4 "VIU_FL NM不允许休眠原因_45";
CM_ SG_ 1361 VIU_FL_NMNotSleep_BYTE7BIT5 "VIU_FL NM不允许休眠原因_46";
CM_ SG_ 1361 VIU_FL_NMNotSleep_BYTE7BIT6 "VIU_FL NM不允许休眠原因_47";
CM_ SG_ 1361 VIU_FL_NMNotSleep_BYTE7BIT7 "VIU_FL NM不允许休眠原因_48";
CM_ SG_ 1361 VIU_FL_NMWakeUp "VIU_FL NM唤醒原因";
CM_ BO_ 1369 " ";
CM_ SG_ 1369 VIU_FR_NMNotSleep_BYTE2BIT0 "VIU_FR NM不允许休眠原因_1";
CM_ SG_ 1369 VIU_FR_NMNotSleep_BYTE2BIT1 "VIU_FR NM不允许休眠原因_2";
CM_ SG_ 1369 VIU_FR_NMNotSleep_BYTE2BIT2 "VIU_FR NM不允许休眠原因_3";
CM_ SG_ 1369 VIU_FR_NMNotSleep_BYTE2BIT3 "VIU_FR NM不允许休眠原因_4";
CM_ SG_ 1369 VIU_FR_NMNotSleep_BYTE2BIT4 "VIU_FR NM不允许休眠原因_5";
CM_ SG_ 1369 VIU_FR_NMNotSleep_BYTE2BIT5 "VIU_FR NM不允许休眠原因_6";
CM_ SG_ 1369 VIU_FR_NMNotSleep_BYTE2BIT6 "VIU_FR NM不允许休眠原因_7";
CM_ SG_ 1369 VIU_FR_NMNotSleep_BYTE2BIT7 "VIU_FR NM不允许休眠原因_8";
CM_ SG_ 1369 VIU_FR_NMNotSleep_BYTE3BIT0 "VIU_FR NM不允许休眠原因_9";
CM_ SG_ 1369 VIU_FR_NMNotSleep_BYTE3BIT1 "VIU_FR NM不允许休眠原因_10";
CM_ SG_ 1369 VIU_FR_NMNotSleep_BYTE3BIT2 "VIU_FR NM不允许休眠原因_11";
CM_ SG_ 1369 VIU_FR_NMNotSleep_BYTE3BIT3 "VIU_FR NM不允许休眠原因_12";
CM_ SG_ 1369 VIU_FR_NMNotSleep_BYTE3BIT4 "VIU_FR NM不允许休眠原因_13";
CM_ SG_ 1369 VIU_FR_NMNotSleep_BYTE3BIT5 "VIU_FR NM不允许休眠原因_14";
CM_ SG_ 1369 VIU_FR_NMNotSleep_BYTE3BIT6 "VIU_FR NM不允许休眠原因_15";
CM_ SG_ 1369 VIU_FR_NMNotSleep_BYTE3BIT7 "VIU_FR NM不允许休眠原因_16";
CM_ SG_ 1369 VIU_FR_NMNotSleep_BYTE4BIT0 "VIU_FR NM不允许休眠原因_17";
CM_ SG_ 1369 VIU_FR_NMNotSleep_BYTE4BIT1 "VIU_FR NM不允许休眠原因_18";
CM_ SG_ 1369 VIU_FR_NMNotSleep_BYTE4BIT2 "VIU_FR NM不允许休眠原因_19";
CM_ SG_ 1369 VIU_FR_NMNotSleep_BYTE4BIT3 "VIU_FR NM不允许休眠原因_20";
CM_ SG_ 1369 VIU_FR_NMNotSleep_BYTE4BIT4 "VIU_FR NM不允许休眠原因_21";
CM_ SG_ 1369 VIU_FR_NMNotSleep_BYTE4BIT5 "VIU_FR NM不允许休眠原因_22";
CM_ SG_ 1369 VIU_FR_NMNotSleep_BYTE4BIT6 "VIU_FR NM不允许休眠原因_23";
CM_ SG_ 1369 VIU_FR_NMNotSleep_BYTE4BIT7 "VIU_FR NM不允许休眠原因_24";
CM_ SG_ 1369 VIU_FR_NMNotSleep_BYTE5BIT0 "VIU_FR NM不允许休眠原因_25";
CM_ SG_ 1369 VIU_FR_NMNotSleep_BYTE5BIT1 "VIU_FR NM不允许休眠原因_26";
CM_ SG_ 1369 VIU_FR_NMNotSleep_BYTE5BIT2 "VIU_FR NM不允许休眠原因_27";
CM_ SG_ 1369 VIU_FR_NMNotSleep_BYTE5BIT3 "VIU_FR NM不允许休眠原因_28";
CM_ SG_ 1369 VIU_FR_NMNotSleep_BYTE5BIT4 "VIU_FR NM不允许休眠原因_29";
CM_ SG_ 1369 VIU_FR_NMNotSleep_BYTE5BIT5 "VIU_FR NM不允许休眠原因_30";
CM_ SG_ 1369 VIU_FR_NMNotSleep_BYTE5BIT6 "VIU_FR NM不允许休眠原因_31";
CM_ SG_ 1369 VIU_FR_NMNotSleep_BYTE5BIT7 "VIU_FR NM不允许休眠原因_32";
CM_ SG_ 1369 VIU_FR_NMNotSleep_BYTE6BIT0 "VIU_FR NM不允许休眠原因_33";
CM_ SG_ 1369 VIU_FR_NMNotSleep_BYTE6BIT1 "VIU_FR NM不允许休眠原因_34";
CM_ SG_ 1369 VIU_FR_NMNotSleep_BYTE6BIT2 "VIU_FR NM不允许休眠原因_35";
CM_ SG_ 1369 VIU_FR_NMNotSleep_BYTE6BIT3 "VIU_FR NM不允许休眠原因_36";
CM_ SG_ 1369 VIU_FR_NMNotSleep_BYTE6BIT4 "VIU_FR NM不允许休眠原因_37";
CM_ SG_ 1369 VIU_FR_NMNotSleep_BYTE6BIT5 "VIU_FR NM不允许休眠原因_38";
CM_ SG_ 1369 VIU_FR_NMNotSleep_BYTE6BIT6 "VIU_FR NM不允许休眠原因_39";
CM_ SG_ 1369 VIU_FR_NMNotSleep_BYTE6BIT7 "VIU_FR NM不允许休眠原因_40";
CM_ SG_ 1369 VIU_FR_NMNotSleep_BYTE7BIT0 "VIU_FR NM不允许休眠原因_41";
CM_ SG_ 1369 VIU_FR_NMNotSleep_BYTE7BIT1 "VIU_FR NM不允许休眠原因_42";
CM_ SG_ 1369 VIU_FR_NMNotSleep_BYTE7BIT2 "VIU_FR NM不允许休眠原因_43";
CM_ SG_ 1369 VIU_FR_NMNotSleep_BYTE7BIT3 "VIU_FR NM不允许休眠原因_44";
CM_ SG_ 1369 VIU_FR_NMNotSleep_BYTE7BIT4 "VIU_FR NM不允许休眠原因_45";
CM_ SG_ 1369 VIU_FR_NMNotSleep_BYTE7BIT5 "VIU_FR NM不允许休眠原因_46";
CM_ SG_ 1369 VIU_FR_NMNotSleep_BYTE7BIT6 "VIU_FR NM不允许休眠原因_47";
CM_ SG_ 1369 VIU_FR_NMNotSleep_BYTE7BIT7 "VIU_FR NM不允许休眠原因_48";
CM_ SG_ 1369 VIU_FR_NMWakeUp "VIU_FR NM唤醒原因";
CM_ BO_ 1396 " ";
CM_ SG_ 1396 EDC_NotSleep_Android "不休眠原因_15~29";
CM_ SG_ 1396 EDC_NotSleep_Android_other "不休眠原因_14";
CM_ SG_ 1396 EDC_NotSleep_BYTE5BIT0 "不休眠原因30~33";
CM_ SG_ 1396 EDC_NotSleep_BYTE6BIT0 "不休眠原因_9";
CM_ SG_ 1396 EDC_NotSleep_BYTE6BIT1 "不休眠原因_10";
CM_ SG_ 1396 EDC_NotSleep_BYTE6BIT2 "不休眠原因_11";
CM_ SG_ 1396 EDC_NotSleep_BYTE6BIT3 "不休眠原因_12";
CM_ SG_ 1396 EDC_NotSleep_BYTE6BIT4 "不休眠原因_13";
CM_ SG_ 1396 EDC_NotSleep_BYTE7BIT0 "不休眠原因_1";
CM_ SG_ 1396 EDC_NotSleep_BYTE7BIT1 "不休眠原因_2";
CM_ SG_ 1396 EDC_NotSleep_BYTE7BIT2 "不休眠原因_3";
CM_ SG_ 1396 EDC_NotSleep_BYTE7BIT3 "不休眠原因_4";
CM_ SG_ 1396 EDC_NotSleep_BYTE7BIT4 "不休眠原因_5";
CM_ SG_ 1396 EDC_NotSleep_BYTE7BIT5 "不休眠原因_6";
CM_ SG_ 1396 EDC_NotSleep_BYTE7BIT6 "不休眠原因_7";
CM_ SG_ 1396 EDC_NotSleep_BYTE7BIT7 "不休眠原因_8";
CM_ SG_ 1396 EDC_wakeup_BYTE2BIT0 "唤醒原因_9";
CM_ SG_ 1396 EDC_wakeup_BYTE2BIT1 "唤醒原因_10";
CM_ SG_ 1396 EDC_wakeup_BYTE2BIT2 "唤醒原因_11";
CM_ SG_ 1396 EDC_wakeup_BYTE2BIT3 "唤醒原因_12";
CM_ SG_ 1396 EDC_WakeUp_BYTE3BIT0 "唤醒原因_1";
CM_ SG_ 1396 EDC_WakeUp_BYTE3BIT1 "唤醒原因_2";
CM_ SG_ 1396 EDC_WakeUp_BYTE3BIT2 "唤醒原因_3";
CM_ SG_ 1396 EDC_WakeUp_BYTE3BIT3 "唤醒原因_4";
CM_ SG_ 1396 EDC_WakeUp_BYTE3BIT4 "唤醒原因_5";
CM_ SG_ 1396 EDC_WakeUp_BYTE3BIT5 "唤醒原因_6";
CM_ SG_ 1396 EDC_WakeUp_BYTE3BIT6 "唤醒原因_7";
CM_ SG_ 1396 EDC_WakeUp_BYTE3BIT7 "唤醒原因_8";
CM_ SG_ 1396 EDC_NotSleep_BYTE1BIT4 "不休眠原因_34";
CM_ SG_ 1396 EDC_NotSleep_BYTE1BIT5 "不休眠原因_35";
CM_ SG_ 1396 EDC_NotSleep_BYTE1BIT6 "不休眠原因_36";
CM_ SG_ 1396 EDC_NotSleep_BYTE1BIT7 "不休眠原因_37";
CM_ SG_ 1396 EDC_wakeup_BYTE2BIT4 "唤醒原因_13";
CM_ SG_ 1396 EDC_wakeup_BYTE2BIT5 "唤醒原因_14";
CM_ SG_ 1396 EDC_wakeup_BYTE2BIT6 "唤醒原因_15";
CM_ SG_ 1396 EDC_wakeup_BYTE2BIT7 "唤醒原因_16";
BA_DEF_ SG_ "GenSigStartValue" INT 0 0;
BA_DEF_ SG_ "GenSigInvalidValue" CHAR;
BA_DEF_ SG_ "GenSigCycleTime" INT 0 0;
BA_DEF_ SG_ "GenSigSendType" ENUM,"Cyclic\"","\"OnWrite\"","\"OnWriteWithRepetition\"","\"OnChange\"","\"OnChangeWithRepetition\"","\"IfActive\"","\"IfActiveWithRepetition\"","\"NoSigSendType\"","\"NotUsed\"","\"NotUsed\"","\"NotUsed\"","\"NotUsed\"","\"NotUsed";
BA_DEF_ BO_ "GenMsgSendType" ENUM,"Cyclic\"","\"Event\"","\"Direct\"","\"NotUsed\"","\"NotUsed\"","\"Cyclic\"","\"NotUsed\"","\"IfActive\"","\"NoMsgSendType\"","\"NotUsed";
BA_DEF_ BO_ "GenMsgCycleTime" INT 0 65535;
BA_DEF_ BO_ "VFrameFormat" ENUM,"StandardCAN\"","\"ExtendedCAN\"","\"reserved\"","\"reserved\"","\"reserved\"","\"reserved\"","\"reserved\"","\"reserved\"","\"reserved\"","\"reserved\"","\"reserved\"","\"reserved\"","\"reserved\"","\"reserved\"","\"StandardCAN_FD\"","\"ExtendedCAN_FD";
BA_DEF_ SG_ "SystemSignalLongSymbol" CHAR;
BA_ "GenMsgCycleTime" BO_ 919 500;
BA_ "GenMsgSendType" BO_ 919 0;
BA_ "VFrameFormat" BO_ 919 14;
BA_ "GenMsgCycleTime" BO_ 920 500;
BA_ "GenMsgSendType" BO_ 920 0;
BA_ "VFrameFormat" BO_ 920 14;
BA_ "GenMsgCycleTime" BO_ 921 500;
BA_ "GenMsgSendType" BO_ 921 0;
BA_ "VFrameFormat" BO_ 921 14;
BA_ "GenMsgCycleTime" BO_ 930 100;
BA_ "GenMsgSendType" BO_ 930 0;
BA_ "VFrameFormat" BO_ 930 14;
BA_ "GenMsgCycleTime" BO_ 931 100;
BA_ "GenMsgSendType" BO_ 931 0;
BA_ "VFrameFormat" BO_ 931 14;
BA_ "GenMsgCycleTime" BO_ 937 0;
BA_ "GenMsgSendType" BO_ 937 1;
BA_ "VFrameFormat" BO_ 937 14;
BA_ "GenMsgCycleTime" BO_ 941 100;
BA_ "GenMsgSendType" BO_ 941 0;
BA_ "VFrameFormat" BO_ 941 14;
BA_ "GenMsgCycleTime" BO_ 945 100;
BA_ "GenMsgSendType" BO_ 945 0;
BA_ "VFrameFormat" BO_ 945 14;
BA_ "GenMsgCycleTime" BO_ 959 100;
BA_ "GenMsgSendType" BO_ 959 0;
BA_ "VFrameFormat" BO_ 959 14;
BA_ "GenMsgCycleTime" BO_ 965 100;
BA_ "GenMsgSendType" BO_ 965 0;
BA_ "VFrameFormat" BO_ 965 14;
BA_ "GenMsgCycleTime" BO_ 1000 0;
BA_ "GenMsgSendType" BO_ 1000 1;
BA_ "VFrameFormat" BO_ 1000 14;
BA_ "GenMsgCycleTime" BO_ 1001 0;
BA_ "GenMsgSendType" BO_ 1001 1;
BA_ "VFrameFormat" BO_ 1001 14;
BA_ "GenMsgCycleTime" BO_ 1015 100;
BA_ "GenMsgSendType" BO_ 1015 0;
BA_ "VFrameFormat" BO_ 1015 14;
BA_ "GenMsgCycleTime" BO_ 1025 0;
BA_ "GenMsgSendType" BO_ 1025 1;
BA_ "VFrameFormat" BO_ 1025 0;
BA_ "GenMsgCycleTime" BO_ 1031 0;
BA_ "GenMsgSendType" BO_ 1031 1;
BA_ "VFrameFormat" BO_ 1031 0;
BA_ "GenMsgCycleTime" BO_ 1036 0;
BA_ "GenMsgSendType" BO_ 1036 1;
BA_ "VFrameFormat" BO_ 1036 0;
BA_ "GenMsgCycleTime" BO_ 1037 0;
BA_ "GenMsgSendType" BO_ 1037 1;
BA_ "VFrameFormat" BO_ 1037 0;
BA_ "GenMsgCycleTime" BO_ 1041 0;
BA_ "GenMsgSendType" BO_ 1041 1;
BA_ "VFrameFormat" BO_ 1041 0;
BA_ "GenMsgCycleTime" BO_ 1059 0;
BA_ "GenMsgSendType" BO_ 1059 1;
BA_ "VFrameFormat" BO_ 1059 0;
BA_ "GenMsgCycleTime" BO_ 1193 0;
BA_ "GenMsgSendType" BO_ 1193 1;
BA_ "VFrameFormat" BO_ 1193 0;
BA_ "GenMsgCycleTime" BO_ 1280 1000;
BA_ "GenMsgSendType" BO_ 1280 0;
BA_ "VFrameFormat" BO_ 1280 14;
BA_ "GenMsgCycleTime" BO_ 1288 200;
BA_ "GenMsgSendType" BO_ 1288 0;
BA_ "VFrameFormat" BO_ 1288 14;
BA_ "GenMsgCycleTime" BO_ 1297 500;
BA_ "GenMsgSendType" BO_ 1297 0;
BA_ "VFrameFormat" BO_ 1297 14;
BA_ "GenMsgCycleTime" BO_ 1361 1000;
BA_ "GenMsgSendType" BO_ 1361 0;
BA_ "VFrameFormat" BO_ 1361 14;
BA_ "GenMsgCycleTime" BO_ 1369 1000;
BA_ "GenMsgSendType" BO_ 1369 0;
BA_ "VFrameFormat" BO_ 1369 14;
BA_ "GenMsgCycleTime" BO_ 1396 1000;
BA_ "GenMsgSendType" BO_ 1396 0;
BA_ "VFrameFormat" BO_ 1396 14;
BA_ "GenSigCycleTime" SG_ 919 OTA_CRCCheck_397 500;
BA_ "GenSigSendType" SG_ 919 OTA_CRCCheck_397 0;
BA_ "GenSigStartValue" SG_ 919 OTA_CRCCheck_397 0;
BA_ "GenSigInvalidValue" SG_ 919 OTA_CRCCheck_397 0;
BA_ "GenSigCycleTime" SG_ 919 OTA_RollingCounter_397 500;
BA_ "GenSigSendType" SG_ 919 OTA_RollingCounter_397 0;
BA_ "GenSigStartValue" SG_ 919 OTA_RollingCounter_397 0;
BA_ "GenSigInvalidValue" SG_ 919 OTA_RollingCounter_397 0;
BA_ "GenSigCycleTime" SG_ 919 VIU_FL_OTAmode 500;
BA_ "GenSigSendType" SG_ 919 VIU_FL_OTAmode 0;
BA_ "GenSigStartValue" SG_ 919 VIU_FL_OTAmode 0;
BA_ "GenSigInvalidValue" SG_ 919 VIU_FL_OTAmode 0;
BA_ "GenSigCycleTime" SG_ 919 VIU_LocalDiagMode 500;
BA_ "GenSigSendType" SG_ 919 VIU_LocalDiagMode 0;
BA_ "GenSigStartValue" SG_ 919 VIU_LocalDiagMode 0;
BA_ "GenSigInvalidValue" SG_ 919 VIU_LocalDiagMode 0;
BA_ "GenSigCycleTime" SG_ 920 EDC_EOLMode 500;
BA_ "GenSigSendType" SG_ 920 EDC_EOLMode 0;
BA_ "GenSigStartValue" SG_ 920 EDC_EOLMode 0;
BA_ "GenSigInvalidValue" SG_ 920 EDC_EOLMode 0;
BA_ "GenSigCycleTime" SG_ 920 EDC_VerCollectMode 500;
BA_ "GenSigSendType" SG_ 920 EDC_VerCollectMode 0;
BA_ "GenSigStartValue" SG_ 920 EDC_VerCollectMode 0;
BA_ "GenSigInvalidValue" SG_ 920 EDC_VerCollectMode 0;
BA_ "GenSigCycleTime" SG_ 921 TBOX_RemotDiagMode 500;
BA_ "GenSigSendType" SG_ 921 TBOX_RemotDiagMode 0;
BA_ "GenSigStartValue" SG_ 921 TBOX_RemotDiagMode 0;
BA_ "GenSigInvalidValue" SG_ 921 TBOX_RemotDiagMode 0;
BA_ "GenSigCycleTime" SG_ 930 EmsFlexfuelDisplay 100;
BA_ "GenSigSendType" SG_ 930 EmsFlexfuelDisplay 0;
BA_ "GenSigStartValue" SG_ 930 EmsFlexfuelDisplay 0;
BA_ "GenSigInvalidValue" SG_ 930 EmsFlexfuelDisplay 0;
BA_ "GenSigCycleTime" SG_ 930 EmsLowTempMilgRemind 100;
BA_ "GenSigSendType" SG_ 930 EmsLowTempMilgRemind 0;
BA_ "GenSigStartValue" SG_ 930 EmsLowTempMilgRemind 0;
BA_ "GenSigInvalidValue" SG_ 930 EmsLowTempMilgRemind 0;
BA_ "GenSigCycleTime" SG_ 931 EDC_EpbFctLamp 100;
BA_ "GenSigSendType" SG_ 931 EDC_EpbFctLamp 0;
BA_ "GenSigStartValue" SG_ 931 EDC_EpbFctLamp 0;
BA_ "GenSigInvalidValue" SG_ 931 EDC_EpbFctLamp 0;
BA_ "GenSigCycleTime" SG_ 931 EDC_EpsFaild 100;
BA_ "GenSigSendType" SG_ 931 EDC_EpsFaild 0;
BA_ "GenSigStartValue" SG_ 931 EDC_EpsFaild 0;
BA_ "GenSigInvalidValue" SG_ 931 EDC_EpsFaild 0;
BA_ "GenSigCycleTime" SG_ 931 EDC_EmsMilLamp 100;
BA_ "GenSigSendType" SG_ 931 EDC_EmsMilLamp 0;
BA_ "GenSigStartValue" SG_ 931 EDC_EmsMilLamp 0;
BA_ "GenSigInvalidValue" SG_ 931 EDC_EmsMilLamp 0;
BA_ "GenSigCycleTime" SG_ 931 EDC_VcuDrvEgyInd 100;
BA_ "GenSigSendType" SG_ 931 EDC_VcuDrvEgyInd 0;
BA_ "GenSigStartValue" SG_ 931 EDC_VcuDrvEgyInd 100;
BA_ "GenSigInvalidValue" SG_ 931 EDC_VcuDrvEgyInd 100;
BA_ "GenSigCycleTime" SG_ 931 EDC_VcuFuelLevelPercent 100;
BA_ "GenSigSendType" SG_ 931 EDC_VcuFuelLevelPercent 0;
BA_ "GenSigStartValue" SG_ 931 EDC_VcuFuelLevelPercent 0;
BA_ "GenSigInvalidValue" SG_ 931 EDC_VcuFuelLevelPercent 0;
BA_ "GenSigCycleTime" SG_ 931 EDC_VcuFulLimdDrvgDst 100;
BA_ "GenSigSendType" SG_ 931 EDC_VcuFulLimdDrvgDst 0;
BA_ "GenSigStartValue" SG_ 931 EDC_VcuFulLimdDrvgDst 0;
BA_ "GenSigInvalidValue" SG_ 931 EDC_VcuFulLimdDrvgDst 0;
BA_ "GenSigCycleTime" SG_ 931 EDC_VcuEvDrvResiMilg 100;
BA_ "GenSigSendType" SG_ 931 EDC_VcuEvDrvResiMilg 0;
BA_ "GenSigStartValue" SG_ 931 EDC_VcuEvDrvResiMilg 0;
BA_ "GenSigInvalidValue" SG_ 931 EDC_VcuEvDrvResiMilg 0;
BA_ "GenSigCycleTime" SG_ 931 EDC_VcuVehAvrgEgyCnseLongTime 100;
BA_ "GenSigSendType" SG_ 931 EDC_VcuVehAvrgEgyCnseLongTime 0;
BA_ "GenSigStartValue" SG_ 931 EDC_VcuVehAvrgEgyCnseLongTime 0;
BA_ "GenSigInvalidValue" SG_ 931 EDC_VcuVehAvrgEgyCnseLongTime 0;
BA_ "GenSigCycleTime" SG_ 931 EDC_VcuVehAvrgFuelCnseLongTime 100;
BA_ "GenSigSendType" SG_ 931 EDC_VcuVehAvrgFuelCnseLongTime 0;
BA_ "GenSigStartValue" SG_ 931 EDC_VcuVehAvrgFuelCnseLongTime 0;
BA_ "GenSigInvalidValue" SG_ 931 EDC_VcuVehAvrgFuelCnseLongTime 0;
BA_ "GenSigCycleTime" SG_ 931 EDC_VcuVehAvrgEgyCnseInTripA 100;
BA_ "GenSigSendType" SG_ 931 EDC_VcuVehAvrgEgyCnseInTripA 0;
BA_ "GenSigStartValue" SG_ 931 EDC_VcuVehAvrgEgyCnseInTripA 0;
BA_ "GenSigInvalidValue" SG_ 931 EDC_VcuVehAvrgEgyCnseInTripA 0;
BA_ "GenSigCycleTime" SG_ 931 EDC_VcuVehAvrgTotCnseInTripA 100;
BA_ "GenSigSendType" SG_ 931 EDC_VcuVehAvrgTotCnseInTripA 0;
BA_ "GenSigStartValue" SG_ 931 EDC_VcuVehAvrgTotCnseInTripA 0;
BA_ "GenSigInvalidValue" SG_ 931 EDC_VcuVehAvrgTotCnseInTripA 0;
BA_ "GenSigCycleTime" SG_ 931 EDC_LoBeamInfo 100;
BA_ "GenSigSendType" SG_ 931 EDC_LoBeamInfo 0;
BA_ "GenSigStartValue" SG_ 931 EDC_LoBeamInfo 0;
BA_ "GenSigInvalidValue" SG_ 931 EDC_LoBeamInfo 0;
BA_ "GenSigCycleTime" SG_ 931 EDC_HiBeamInfo 100;
BA_ "GenSigSendType" SG_ 931 EDC_HiBeamInfo 0;
BA_ "GenSigStartValue" SG_ 931 EDC_HiBeamInfo 0;
BA_ "GenSigInvalidValue" SG_ 931 EDC_HiBeamInfo 0;
BA_ "GenSigCycleTime" SG_ 931 EDC_AutoHiBeamInfo 100;
BA_ "GenSigSendType" SG_ 931 EDC_AutoHiBeamInfo 0;
BA_ "GenSigStartValue" SG_ 931 EDC_AutoHiBeamInfo 0;
BA_ "GenSigInvalidValue" SG_ 931 EDC_AutoHiBeamInfo 0;
BA_ "GenSigCycleTime" SG_ 931 EDC_Le_ReLoglSt 100;
BA_ "GenSigSendType" SG_ 931 EDC_Le_ReLoglSt 0;
BA_ "GenSigStartValue" SG_ 931 EDC_Le_ReLoglSt 0;
BA_ "GenSigInvalidValue" SG_ 931 EDC_Le_ReLoglSt 0;
BA_ "GenSigCycleTime" SG_ 931 EDC_Ri_ReLoglSt 100;
BA_ "GenSigSendType" SG_ 931 EDC_Ri_ReLoglSt 0;
BA_ "GenSigStartValue" SG_ 931 EDC_Ri_ReLoglSt 0;
BA_ "GenSigInvalidValue" SG_ 931 EDC_Ri_ReLoglSt 0;
BA_ "GenSigCycleTime" SG_ 931 EDC_PosnLiInfo 100;
BA_ "GenSigSendType" SG_ 931 EDC_PosnLiInfo 0;
BA_ "GenSigStartValue" SG_ 931 EDC_PosnLiInfo 0;
BA_ "GenSigInvalidValue" SG_ 931 EDC_PosnLiInfo 0;
BA_ "GenSigCycleTime" SG_ 931 EDC_VcuPlugConnectLamp 100;
BA_ "GenSigSendType" SG_ 931 EDC_VcuPlugConnectLamp 0;
BA_ "GenSigStartValue" SG_ 931 EDC_VcuPlugConnectLamp 0;
BA_ "GenSigInvalidValue" SG_ 931 EDC_VcuPlugConnectLamp 0;
BA_ "GenSigCycleTime" SG_ 931 EDC_BcuBattSocUnderLamp 100;
BA_ "GenSigSendType" SG_ 931 EDC_BcuBattSocUnderLamp 0;
BA_ "GenSigStartValue" SG_ 931 EDC_BcuBattSocUnderLamp 0;
BA_ "GenSigInvalidValue" SG_ 931 EDC_BcuBattSocUnderLamp 0;
BA_ "GenSigCycleTime" SG_ 931 EDC_VcuChrgStsLamp 100;
BA_ "GenSigSendType" SG_ 931 EDC_VcuChrgStsLamp 0;
BA_ "GenSigStartValue" SG_ 931 EDC_VcuChrgStsLamp 0;
BA_ "GenSigInvalidValue" SG_ 931 EDC_VcuChrgStsLamp 0;
BA_ "GenSigCycleTime" SG_ 931 EDC_DcacStsLamp 100;
BA_ "GenSigSendType" SG_ 931 EDC_DcacStsLamp 0;
BA_ "GenSigStartValue" SG_ 931 EDC_DcacStsLamp 0;
BA_ "GenSigInvalidValue" SG_ 931 EDC_DcacStsLamp 0;
BA_ "GenSigCycleTime" SG_ 931 EDC_LoBattErrSts 100;
BA_ "GenSigSendType" SG_ 931 EDC_LoBattErrSts 0;
BA_ "GenSigStartValue" SG_ 931 EDC_LoBattErrSts 0;
BA_ "GenSigInvalidValue" SG_ 931 EDC_LoBattErrSts 0;
BA_ "GenSigCycleTime" SG_ 931 EDC_VcuVehPwrLimLamp 100;
BA_ "GenSigSendType" SG_ 931 EDC_VcuVehPwrLimLamp 0;
BA_ "GenSigStartValue" SG_ 931 EDC_VcuVehPwrLimLamp 0;
BA_ "GenSigInvalidValue" SG_ 931 EDC_VcuVehPwrLimLamp 0;
BA_ "GenSigCycleTime" SG_ 931 EDC_VcuEngineOilPressureLowSts 100;
BA_ "GenSigSendType" SG_ 931 EDC_VcuEngineOilPressureLowSts 0;
BA_ "GenSigStartValue" SG_ 931 EDC_VcuEngineOilPressureLowSts 0;
BA_ "GenSigInvalidValue" SG_ 931 EDC_VcuEngineOilPressureLowSts 0;
BA_ "GenSigCycleTime" SG_ 931 EDC_PsgSeatSBR 100;
BA_ "GenSigSendType" SG_ 931 EDC_PsgSeatSBR 0;
BA_ "GenSigStartValue" SG_ 931 EDC_PsgSeatSBR 0;
BA_ "GenSigInvalidValue" SG_ 931 EDC_PsgSeatSBR 0;
BA_ "GenSigCycleTime" SG_ 931 EDC_RearLeSeatSBR 100;
BA_ "GenSigSendType" SG_ 931 EDC_RearLeSeatSBR 0;
BA_ "GenSigStartValue" SG_ 931 EDC_RearLeSeatSBR 0;
BA_ "GenSigInvalidValue" SG_ 931 EDC_RearLeSeatSBR 0;
BA_ "GenSigCycleTime" SG_ 931 EDC_RearMidSeatSBR 100;
BA_ "GenSigSendType" SG_ 931 EDC_RearMidSeatSBR 0;
BA_ "GenSigStartValue" SG_ 931 EDC_RearMidSeatSBR 0;
BA_ "GenSigInvalidValue" SG_ 931 EDC_RearMidSeatSBR 0;
BA_ "GenSigCycleTime" SG_ 931 EDC_RearRiSeatSBR 100;
BA_ "GenSigSendType" SG_ 931 EDC_RearRiSeatSBR 0;
BA_ "GenSigStartValue" SG_ 931 EDC_RearRiSeatSBR 0;
BA_ "GenSigInvalidValue" SG_ 931 EDC_RearRiSeatSBR 0;
BA_ "GenSigCycleTime" SG_ 931 EDC_SBR 100;
BA_ "GenSigSendType" SG_ 931 EDC_SBR 0;
BA_ "GenSigStartValue" SG_ 931 EDC_SBR 0;
BA_ "GenSigInvalidValue" SG_ 931 EDC_SBR 0;
BA_ "GenSigCycleTime" SG_ 931 EDC_AD_NDAStatus 100;
BA_ "GenSigSendType" SG_ 931 EDC_AD_NDAStatus 0;
BA_ "GenSigStartValue" SG_ 931 EDC_AD_NDAStatus 0;
BA_ "GenSigInvalidValue" SG_ 931 EDC_AD_NDAStatus 0;
BA_ "GenSigCycleTime" SG_ 931 EDC_AD_BSDLCA_LeftAlert 100;
BA_ "GenSigSendType" SG_ 931 EDC_AD_BSDLCA_LeftAlert 0;
BA_ "GenSigStartValue" SG_ 931 EDC_AD_BSDLCA_LeftAlert 0;
BA_ "GenSigInvalidValue" SG_ 931 EDC_AD_BSDLCA_LeftAlert 0;
BA_ "GenSigCycleTime" SG_ 931 EDC_AD_BSDLCA_RightAlert 100;
BA_ "GenSigSendType" SG_ 931 EDC_AD_BSDLCA_RightAlert 0;
BA_ "GenSigStartValue" SG_ 931 EDC_AD_BSDLCA_RightAlert 0;
BA_ "GenSigInvalidValue" SG_ 931 EDC_AD_BSDLCA_RightAlert 0;
BA_ "GenSigCycleTime" SG_ 931 EDC_ACC_SetSpeed 100;
BA_ "GenSigSendType" SG_ 931 EDC_ACC_SetSpeed 0;
BA_ "GenSigStartValue" SG_ 931 EDC_ACC_SetSpeed 0;
BA_ "GenSigInvalidValue" SG_ 931 EDC_ACC_SetSpeed 0;
BA_ "GenSigCycleTime" SG_ 931 EDC_time_hr 100;
BA_ "GenSigSendType" SG_ 931 EDC_time_hr 0;
BA_ "GenSigStartValue" SG_ 931 EDC_time_hr 0;
BA_ "GenSigInvalidValue" SG_ 931 EDC_time_hr 0;
BA_ "GenSigCycleTime" SG_ 931 EDC_time_min 100;
BA_ "GenSigSendType" SG_ 931 EDC_time_min 0;
BA_ "GenSigStartValue" SG_ 931 EDC_time_min 0;
BA_ "GenSigInvalidValue" SG_ 931 EDC_time_min 0;
BA_ "GenSigCycleTime" SG_ 931 EDC_ViuEgyResiColor 100;
BA_ "GenSigSendType" SG_ 931 EDC_ViuEgyResiColor 0;
BA_ "GenSigStartValue" SG_ 931 EDC_ViuEgyResiColor 0;
BA_ "GenSigInvalidValue" SG_ 931 EDC_ViuEgyResiColor 0;
BA_ "GenSigCycleTime" SG_ 931 EDC_ViuEvResiMilgInvldDisp 100;
BA_ "GenSigSendType" SG_ 931 EDC_ViuEvResiMilgInvldDisp 0;
BA_ "GenSigStartValue" SG_ 931 EDC_ViuEvResiMilgInvldDisp 0;
BA_ "GenSigInvalidValue" SG_ 931 EDC_ViuEvResiMilgInvldDisp 0;
BA_ "GenSigCycleTime" SG_ 931 EDC_LaneLeft_Status 100;
BA_ "GenSigSendType" SG_ 931 EDC_LaneLeft_Status 0;
BA_ "GenSigStartValue" SG_ 931 EDC_LaneLeft_Status 0;
BA_ "GenSigInvalidValue" SG_ 931 EDC_LaneLeft_Status 0;
BA_ "GenSigCycleTime" SG_ 931 EDC_LaneRight_Status 100;
BA_ "GenSigSendType" SG_ 931 EDC_LaneRight_Status 0;
BA_ "GenSigStartValue" SG_ 931 EDC_LaneRight_Status 0;
BA_ "GenSigInvalidValue" SG_ 931 EDC_LaneRight_Status 0;
BA_ "GenSigCycleTime" SG_ 931 EDC_ACC_TimeGapSet 100;
BA_ "GenSigSendType" SG_ 931 EDC_ACC_TimeGapSet 0;
BA_ "GenSigStartValue" SG_ 931 EDC_ACC_TimeGapSet 0;
BA_ "GenSigInvalidValue" SG_ 931 EDC_ACC_TimeGapSet 0;
BA_ "GenSigCycleTime" SG_ 931 EDC_Objx_Detection 100;
BA_ "GenSigSendType" SG_ 931 EDC_Objx_Detection 0;
BA_ "GenSigStartValue" SG_ 931 EDC_Objx_Detection 0;
BA_ "GenSigInvalidValue" SG_ 931 EDC_Objx_Detection 0;
BA_ "GenSigCycleTime" SG_ 931 EDC_Lane_PointArr 100;
BA_ "GenSigSendType" SG_ 931 EDC_Lane_PointArr 0;
BA_ "GenSigStartValue" SG_ 931 EDC_Lane_PointArr 0;
BA_ "GenSigInvalidValue" SG_ 931 EDC_Lane_PointArr 0;
BA_ "GenSigCycleTime" SG_ 931 EDC_EpbFailrLamp 100;
BA_ "GenSigSendType" SG_ 931 EDC_EpbFailrLamp 0;
BA_ "GenSigStartValue" SG_ 931 EDC_EpbFailrLamp 0;
BA_ "GenSigInvalidValue" SG_ 931 EDC_EpbFailrLamp 0;
BA_ "GenSigCycleTime" SG_ 931 EDC_trafficLight 100;
BA_ "GenSigSendType" SG_ 931 EDC_trafficLight 0;
BA_ "GenSigStartValue" SG_ 931 EDC_trafficLight 0;
BA_ "GenSigInvalidValue" SG_ 931 EDC_trafficLight 0;
BA_ "GenSigCycleTime" SG_ 931 EDC_countdown 100;
BA_ "GenSigSendType" SG_ 931 EDC_countdown 0;
BA_ "GenSigStartValue" SG_ 931 EDC_countdown 0;
BA_ "GenSigInvalidValue" SG_ 931 EDC_countdown 0;
BA_ "GenSigCycleTime" SG_ 931 EDC_mileage 100;
BA_ "GenSigSendType" SG_ 931 EDC_mileage 0;
BA_ "GenSigStartValue" SG_ 931 EDC_mileage 0;
BA_ "GenSigInvalidValue" SG_ 931 EDC_mileage 0;
BA_ "GenSigCycleTime" SG_ 931 EDC_brightness 100;
BA_ "GenSigSendType" SG_ 931 EDC_brightness 0;
BA_ "GenSigStartValue" SG_ 931 EDC_brightness 0;
BA_ "GenSigInvalidValue" SG_ 931 EDC_brightness 0;
BA_ "GenSigCycleTime" SG_ 931 EDC_Autobrightness 100;
BA_ "GenSigSendType" SG_ 931 EDC_Autobrightness 0;
BA_ "GenSigStartValue" SG_ 931 EDC_Autobrightness 0;
BA_ "GenSigInvalidValue" SG_ 931 EDC_Autobrightness 0;
BA_ "GenSigCycleTime" SG_ 931 EDC_FW_Brightness 100;
BA_ "GenSigSendType" SG_ 931 EDC_FW_Brightness 0;
BA_ "GenSigStartValue" SG_ 931 EDC_FW_Brightness 1022;
BA_ "GenSigInvalidValue" SG_ 931 EDC_FW_Brightness 1022;
BA_ "GenSigCycleTime" SG_ 931 EDC_AMB_Brightness 100;
BA_ "GenSigSendType" SG_ 931 EDC_AMB_Brightness 0;
BA_ "GenSigStartValue" SG_ 931 EDC_AMB_Brightness 1022;
BA_ "GenSigInvalidValue" SG_ 931 EDC_AMB_Brightness 1022;
BA_ "GenSigCycleTime" SG_ 931 EDC_AD_AEBStatus 100;
BA_ "GenSigSendType" SG_ 931 EDC_AD_AEBStatus 0;
BA_ "GenSigStartValue" SG_ 931 EDC_AD_AEBStatus 0;
BA_ "GenSigInvalidValue" SG_ 931 EDC_AD_AEBStatus 0;
BA_ "GenSigCycleTime" SG_ 931 EDC_trip 100;
BA_ "GenSigSendType" SG_ 931 EDC_trip 0;
BA_ "GenSigStartValue" SG_ 931 EDC_trip 0;
BA_ "GenSigInvalidValue" SG_ 931 EDC_trip "LastValue";
BA_ "GenSigCycleTime" SG_ 931 EDC_VcuPwrSysErrLamp 100;
BA_ "GenSigSendType" SG_ 931 EDC_VcuPwrSysErrLamp 0;
BA_ "GenSigStartValue" SG_ 931 EDC_VcuPwrSysErrLamp 0;
BA_ "GenSigInvalidValue" SG_ 931 EDC_VcuPwrSysErrLamp 0;
BA_ "GenSigCycleTime" SG_ 931 EDCDisplayEspVehSpd 100;
BA_ "GenSigSendType" SG_ 931 EDCDisplayEspVehSpd 0;
BA_ "GenSigStartValue" SG_ 931 EDCDisplayEspVehSpd 0;
BA_ "GenSigInvalidValue" SG_ 931 EDCDisplayEspVehSpd 0;
BA_ "GenSigCycleTime" SG_ 937 AD_SYNC_CRC 0;
BA_ "GenSigSendType" SG_ 937 AD_SYNC_CRC 3;
BA_ "GenSigStartValue" SG_ 937 AD_SYNC_CRC 0;
BA_ "GenSigInvalidValue" SG_ 937 AD_SYNC_CRC 0;
BA_ "GenSigCycleTime" SG_ 937 AD_SYNC_Sequence 0;
BA_ "GenSigSendType" SG_ 937 AD_SYNC_Sequence 3;
BA_ "GenSigStartValue" SG_ 937 AD_SYNC_Sequence 0;
BA_ "GenSigInvalidValue" SG_ 937 AD_SYNC_Sequence 0;
BA_ "GenSigCycleTime" SG_ 937 AD_SYNC_Sync_Time 0;
BA_ "GenSigSendType" SG_ 937 AD_SYNC_Sync_Time 3;
BA_ "GenSigStartValue" SG_ 937 AD_SYNC_Sync_Time 0;
BA_ "GenSigInvalidValue" SG_ 937 AD_SYNC_Sync_Time 0;
BA_ "GenSigCycleTime" SG_ 937 AD_SYNC_TimeDomain 0;
BA_ "GenSigSendType" SG_ 937 AD_SYNC_TimeDomain 3;
BA_ "GenSigStartValue" SG_ 937 AD_SYNC_TimeDomain 0;
BA_ "GenSigInvalidValue" SG_ 937 AD_SYNC_TimeDomain 0;
BA_ "GenSigCycleTime" SG_ 937 AD_SYNC_Type 0;
BA_ "GenSigSendType" SG_ 937 AD_SYNC_Type 3;
BA_ "GenSigStartValue" SG_ 937 AD_SYNC_Type 0;
BA_ "GenSigInvalidValue" SG_ 937 AD_SYNC_Type 0;
BA_ "GenSigCycleTime" SG_ 937 AD_SYNC_UserByte_OVS_SGW 0;
BA_ "GenSigSendType" SG_ 937 AD_SYNC_UserByte_OVS_SGW 3;
BA_ "GenSigStartValue" SG_ 937 AD_SYNC_UserByte_OVS_SGW 0;
BA_ "GenSigInvalidValue" SG_ 937 AD_SYNC_UserByte_OVS_SGW 0;
BA_ "GenSigCycleTime" SG_ 941 RRS_FLCDistance 100;
BA_ "GenSigSendType" SG_ 941 RRS_FLCDistance 0;
BA_ "GenSigStartValue" SG_ 941 RRS_FLCDistance 0;
BA_ "GenSigInvalidValue" SG_ 941 RRS_FLCDistance 0;
BA_ "GenSigCycleTime" SG_ 941 RRS_FLMDistance 100;
BA_ "GenSigSendType" SG_ 941 RRS_FLMDistance 0;
BA_ "GenSigStartValue" SG_ 941 RRS_FLMDistance 0;
BA_ "GenSigInvalidValue" SG_ 941 RRS_FLMDistance 0;
BA_ "GenSigCycleTime" SG_ 941 RRS_FLODistance 100;
BA_ "GenSigSendType" SG_ 941 RRS_FLODistance 0;
BA_ "GenSigStartValue" SG_ 941 RRS_FLODistance 0;
BA_ "GenSigInvalidValue" SG_ 941 RRS_FLODistance 0;
BA_ "GenSigCycleTime" SG_ 941 RRS_FLSDistance 100;
BA_ "GenSigSendType" SG_ 941 RRS_FLSDistance 0;
BA_ "GenSigStartValue" SG_ 941 RRS_FLSDistance 0;
BA_ "GenSigInvalidValue" SG_ 941 RRS_FLSDistance 0;
BA_ "GenSigCycleTime" SG_ 941 RRS_FRCDistance 100;
BA_ "GenSigSendType" SG_ 941 RRS_FRCDistance 0;
BA_ "GenSigStartValue" SG_ 941 RRS_FRCDistance 0;
BA_ "GenSigInvalidValue" SG_ 941 RRS_FRCDistance 0;
BA_ "GenSigCycleTime" SG_ 941 RRS_FRMDistance 100;
BA_ "GenSigSendType" SG_ 941 RRS_FRMDistance 0;
BA_ "GenSigStartValue" SG_ 941 RRS_FRMDistance 0;
BA_ "GenSigInvalidValue" SG_ 941 RRS_FRMDistance 0;
BA_ "GenSigCycleTime" SG_ 941 RRS_FRODistance 100;
BA_ "GenSigSendType" SG_ 941 RRS_FRODistance 0;
BA_ "GenSigStartValue" SG_ 941 RRS_FRODistance 0;
BA_ "GenSigInvalidValue" SG_ 941 RRS_FRODistance 0;
BA_ "GenSigCycleTime" SG_ 941 RRS_FRSDistance 100;
BA_ "GenSigSendType" SG_ 941 RRS_FRSDistance 0;
BA_ "GenSigStartValue" SG_ 941 RRS_FRSDistance 0;
BA_ "GenSigInvalidValue" SG_ 941 RRS_FRSDistance 0;
BA_ "GenSigCycleTime" SG_ 941 RRS_RLCDistance 100;
BA_ "GenSigSendType" SG_ 941 RRS_RLCDistance 0;
BA_ "GenSigStartValue" SG_ 941 RRS_RLCDistance 0;
BA_ "GenSigInvalidValue" SG_ 941 RRS_RLCDistance 0;
BA_ "GenSigCycleTime" SG_ 941 RRS_RLMDistance 100;
BA_ "GenSigSendType" SG_ 941 RRS_RLMDistance 0;
BA_ "GenSigStartValue" SG_ 941 RRS_RLMDistance 0;
BA_ "GenSigInvalidValue" SG_ 941 RRS_RLMDistance 0;
BA_ "GenSigCycleTime" SG_ 941 RRS_RLODistance 100;
BA_ "GenSigSendType" SG_ 941 RRS_RLODistance 0;
BA_ "GenSigStartValue" SG_ 941 RRS_RLODistance 0;
BA_ "GenSigInvalidValue" SG_ 941 RRS_RLODistance 0;
BA_ "GenSigCycleTime" SG_ 941 RRS_RLSDistance 100;
BA_ "GenSigSendType" SG_ 941 RRS_RLSDistance 0;
BA_ "GenSigStartValue" SG_ 941 RRS_RLSDistance 0;
BA_ "GenSigInvalidValue" SG_ 941 RRS_RLSDistance 0;
BA_ "GenSigCycleTime" SG_ 941 RRS_RRCDistance 100;
BA_ "GenSigSendType" SG_ 941 RRS_RRCDistance 0;
BA_ "GenSigStartValue" SG_ 941 RRS_RRCDistance 0;
BA_ "GenSigInvalidValue" SG_ 941 RRS_RRCDistance 0;
BA_ "GenSigCycleTime" SG_ 941 RRS_RRMDistance 100;
BA_ "GenSigSendType" SG_ 941 RRS_RRMDistance 0;
BA_ "GenSigStartValue" SG_ 941 RRS_RRMDistance 0;
BA_ "GenSigInvalidValue" SG_ 941 RRS_RRMDistance 0;
BA_ "GenSigCycleTime" SG_ 941 RRS_RRODistance 100;
BA_ "GenSigSendType" SG_ 941 RRS_RRODistance 0;
BA_ "GenSigStartValue" SG_ 941 RRS_RRODistance 0;
BA_ "GenSigInvalidValue" SG_ 941 RRS_RRODistance 0;
BA_ "GenSigCycleTime" SG_ 941 RRS_RRSDistance 100;
BA_ "GenSigSendType" SG_ 941 RRS_RRSDistance 0;
BA_ "GenSigStartValue" SG_ 941 RRS_RRSDistance 0;
BA_ "GenSigInvalidValue" SG_ 941 RRS_RRSDistance 0;
BA_ "GenSigCycleTime" SG_ 941 ACC_CRCCheck_3AD 100;
BA_ "GenSigSendType" SG_ 941 ACC_CRCCheck_3AD 0;
BA_ "GenSigStartValue" SG_ 941 ACC_CRCCheck_3AD 0;
BA_ "GenSigInvalidValue" SG_ 941 ACC_CRCCheck_3AD "/";
BA_ "GenSigCycleTime" SG_ 941 ACC_RollingCounter_3AD 100;
BA_ "GenSigSendType" SG_ 941 ACC_RollingCounter_3AD 0;
BA_ "GenSigStartValue" SG_ 941 ACC_RollingCounter_3AD 0;
BA_ "GenSigInvalidValue" SG_ 941 ACC_RollingCounter_3AD "/";
BA_ "GenSigCycleTime" SG_ 941 AD_CNAStatus 100;
BA_ "GenSigSendType" SG_ 941 AD_CNAStatus 0;
BA_ "GenSigStartValue" SG_ 941 AD_CNAStatus 0;
BA_ "GenSigInvalidValue" SG_ 941 AD_CNAStatus 0;
BA_ "GenSigCycleTime" SG_ 941 AD_HandsOnReq 100;
BA_ "GenSigSendType" SG_ 941 AD_HandsOnReq 0;
BA_ "GenSigStartValue" SG_ 941 AD_HandsOnReq 0;
BA_ "GenSigInvalidValue" SG_ 941 AD_HandsOnReq 0;
BA_ "GenSigCycleTime" SG_ 941 AD_IACCHWAMode 100;
BA_ "GenSigSendType" SG_ 941 AD_IACCHWAMode 0;
BA_ "GenSigStartValue" SG_ 941 AD_IACCHWAMode 0;
BA_ "GenSigInvalidValue" SG_ 941 AD_IACCHWAMode 0;
BA_ "GenSigCycleTime" SG_ 941 AD_IACCMode 100;
BA_ "GenSigSendType" SG_ 941 AD_IACCMode 0;
BA_ "GenSigStartValue" SG_ 941 AD_IACCMode 0;
BA_ "GenSigInvalidValue" SG_ 941 AD_IACCMode 0;
BA_ "GenSigCycleTime" SG_ 941 AD_LatTakeoverReq 100;
BA_ "GenSigSendType" SG_ 941 AD_LatTakeoverReq 0;
BA_ "GenSigStartValue" SG_ 941 AD_LatTakeoverReq 0;
BA_ "GenSigInvalidValue" SG_ 941 AD_LatTakeoverReq 0;
BA_ "GenSigCycleTime" SG_ 941 AD_LngTakeOverReq 100;
BA_ "GenSigSendType" SG_ 941 AD_LngTakeOverReq 0;
BA_ "GenSigStartValue" SG_ 941 AD_LngTakeOverReq 0;
BA_ "GenSigInvalidValue" SG_ 941 AD_LngTakeOverReq 0;
BA_ "GenSigCycleTime" SG_ 941 AD_NDAStatus 100;
BA_ "GenSigSendType" SG_ 941 AD_NDAStatus 0;
BA_ "GenSigStartValue" SG_ 941 AD_NDAStatus 0;
BA_ "GenSigInvalidValue" SG_ 941 AD_NDAStatus 0;
BA_ "GenSigCycleTime" SG_ 941 AD_TakeoverReqAtIPFail 100;
BA_ "GenSigSendType" SG_ 941 AD_TakeoverReqAtIPFail 0;
BA_ "GenSigStartValue" SG_ 941 AD_TakeoverReqAtIPFail 0;
BA_ "GenSigInvalidValue" SG_ 941 AD_TakeoverReqAtIPFail 0;
BA_ "GenSigCycleTime" SG_ 941 AD_TJPStatus 100;
BA_ "GenSigSendType" SG_ 941 AD_TJPStatus 0;
BA_ "GenSigStartValue" SG_ 941 AD_TJPStatus 0;
BA_ "GenSigInvalidValue" SG_ 941 AD_TJPStatus 0;
BA_ "GenSigCycleTime" SG_ 941 AD_Voiceinfo 100;
BA_ "GenSigSendType" SG_ 941 AD_Voiceinfo 0;
BA_ "GenSigStartValue" SG_ 941 AD_Voiceinfo 0;
BA_ "GenSigInvalidValue" SG_ 941 AD_Voiceinfo 0;
BA_ "GenSigCycleTime" SG_ 941 RRS_SystemFailureFlag 100;
BA_ "GenSigSendType" SG_ 941 RRS_SystemFailureFlag 0;
BA_ "GenSigStartValue" SG_ 941 RRS_SystemFailureFlag 0;
BA_ "GenSigInvalidValue" SG_ 941 RRS_SystemFailureFlag 0;
BA_ "GenSigCycleTime" SG_ 945 ErpsFctMode 100;
BA_ "GenSigSendType" SG_ 945 ErpsFctMode 0;
BA_ "GenSigStartValue" SG_ 945 ErpsFctMode 0;
BA_ "GenSigInvalidValue" SG_ 945 ErpsFctMode 0;
BA_ "GenSigCycleTime" SG_ 945 BcmTrDoorSts 100;
BA_ "GenSigSendType" SG_ 945 BcmTrDoorSts 0;
BA_ "GenSigStartValue" SG_ 945 BcmTrDoorSts 0;
BA_ "GenSigInvalidValue" SG_ 945 BcmTrDoorSts 0;
BA_ "GenSigCycleTime" SG_ 945 BcmTrDoorWinPosi 100;
BA_ "GenSigSendType" SG_ 945 BcmTrDoorWinPosi 0;
BA_ "GenSigStartValue" SG_ 945 BcmTrDoorWinPosi 0;
BA_ "GenSigInvalidValue" SG_ 945 BcmTrDoorWinPosi 0;
BA_ "GenSigCycleTime" SG_ 945 BcmTrDoorWinSts 100;
BA_ "GenSigSendType" SG_ 945 BcmTrDoorWinSts 0;
BA_ "GenSigStartValue" SG_ 945 BcmTrDoorWinSts 0;
BA_ "GenSigInvalidValue" SG_ 945 BcmTrDoorWinSts 0;
BA_ "GenSigCycleTime" SG_ 945 BCMRiDoorLockSwt 100;
BA_ "GenSigSendType" SG_ 945 BCMRiDoorLockSwt 0;
BA_ "GenSigStartValue" SG_ 945 BCMRiDoorLockSwt 0;
BA_ "GenSigInvalidValue" SG_ 945 BCMRiDoorLockSwt 0;
BA_ "GenSigCycleTime" SG_ 945 VIUPsgSeatSBR 100;
BA_ "GenSigSendType" SG_ 945 VIUPsgSeatSBR 0;
BA_ "GenSigStartValue" SG_ 945 VIUPsgSeatSBR 0;
BA_ "GenSigInvalidValue" SG_ 945 VIUPsgSeatSBR 0;
BA_ "GenSigCycleTime" SG_ 945 VIURearLeSeatSBR 100;
BA_ "GenSigSendType" SG_ 945 VIURearLeSeatSBR 0;
BA_ "GenSigStartValue" SG_ 945 VIURearLeSeatSBR 0;
BA_ "GenSigInvalidValue" SG_ 945 VIURearLeSeatSBR 0;
BA_ "GenSigCycleTime" SG_ 945 VIURearMidSeatSBR 100;
BA_ "GenSigSendType" SG_ 945 VIURearMidSeatSBR 0;
BA_ "GenSigStartValue" SG_ 945 VIURearMidSeatSBR 0;
BA_ "GenSigInvalidValue" SG_ 945 VIURearMidSeatSBR 0;
BA_ "GenSigCycleTime" SG_ 945 VIURearRiSeatSBR 100;
BA_ "GenSigSendType" SG_ 945 VIURearRiSeatSBR 0;
BA_ "GenSigStartValue" SG_ 945 VIURearRiSeatSBR 0;
BA_ "GenSigInvalidValue" SG_ 945 VIURearRiSeatSBR 0;
BA_ "GenSigCycleTime" SG_ 945 EMBBrkSysFailrBuzAlrmSec 100;
BA_ "GenSigSendType" SG_ 945 EMBBrkSysFailrBuzAlrmSec 0;
BA_ "GenSigStartValue" SG_ 945 EMBBrkSysFailrBuzAlrmSec 0;
BA_ "GenSigInvalidValue" SG_ 945 EMBBrkSysFailrBuzAlrmSec 0;
BA_ "GenSigCycleTime" SG_ 945 EMBBrkSysFctdownTextDispReqSec 100;
BA_ "GenSigSendType" SG_ 945 EMBBrkSysFctdownTextDispReqSec 0;
BA_ "GenSigStartValue" SG_ 945 EMBBrkSysFctdownTextDispReqSec 0;
BA_ "GenSigInvalidValue" SG_ 945 EMBBrkSysFctdownTextDispReqSec 0;
BA_ "GenSigCycleTime" SG_ 945 EpbTextDispReqSec 100;
BA_ "GenSigSendType" SG_ 945 EpbTextDispReqSec 0;
BA_ "GenSigStartValue" SG_ 945 EpbTextDispReqSec 0;
BA_ "GenSigInvalidValue" SG_ 945 EpbTextDispReqSec 0;
BA_ "GenSigCycleTime" SG_ 959 HUFRTopPositionVolSET 100;
BA_ "GenSigSendType" SG_ 959 HUFRTopPositionVolSET 0;
BA_ "GenSigStartValue" SG_ 959 HUFRTopPositionVolSET 0;
BA_ "GenSigInvalidValue" SG_ 959 HUFRTopPositionVolSET 0;
BA_ "GenSigCycleTime" SG_ 959 HURLPositionDelaySET 100;
BA_ "GenSigSendType" SG_ 959 HURLPositionDelaySET 0;
BA_ "GenSigStartValue" SG_ 959 HURLPositionDelaySET 0;
BA_ "GenSigInvalidValue" SG_ 959 HURLPositionDelaySET 0;
BA_ "GenSigCycleTime" SG_ 959 HURLPositionVolSET 100;
BA_ "GenSigSendType" SG_ 959 HURLPositionVolSET 0;
BA_ "GenSigStartValue" SG_ 959 HURLPositionVolSET 0;
BA_ "GenSigInvalidValue" SG_ 959 HURLPositionVolSET 0;
BA_ "GenSigCycleTime" SG_ 959 HURLSurroundPositionDelaySET 100;
BA_ "GenSigSendType" SG_ 959 HURLSurroundPositionDelaySET 0;
BA_ "GenSigStartValue" SG_ 959 HURLSurroundPositionDelaySET 0;
BA_ "GenSigInvalidValue" SG_ 959 HURLSurroundPositionDelaySET 0;
BA_ "GenSigCycleTime" SG_ 959 HURLSurroundPositionVolSET 100;
BA_ "GenSigSendType" SG_ 959 HURLSurroundPositionVolSET 0;
BA_ "GenSigStartValue" SG_ 959 HURLSurroundPositionVolSET 0;
BA_ "GenSigInvalidValue" SG_ 959 HURLSurroundPositionVolSET 0;
BA_ "GenSigCycleTime" SG_ 959 HURLTopPositionDelaySET 100;
BA_ "GenSigSendType" SG_ 959 HURLTopPositionDelaySET 0;
BA_ "GenSigStartValue" SG_ 959 HURLTopPositionDelaySET 0;
BA_ "GenSigInvalidValue" SG_ 959 HURLTopPositionDelaySET 0;
BA_ "GenSigCycleTime" SG_ 959 HURLTopPositionVolSET 100;
BA_ "GenSigSendType" SG_ 959 HURLTopPositionVolSET 0;
BA_ "GenSigStartValue" SG_ 959 HURLTopPositionVolSET 0;
BA_ "GenSigInvalidValue" SG_ 959 HURLTopPositionVolSET 0;
BA_ "GenSigCycleTime" SG_ 959 HURRPositionDelaySET 100;
BA_ "GenSigSendType" SG_ 959 HURRPositionDelaySET 0;
BA_ "GenSigStartValue" SG_ 959 HURRPositionDelaySET 0;
BA_ "GenSigInvalidValue" SG_ 959 HURRPositionDelaySET 0;
BA_ "GenSigCycleTime" SG_ 959 HURRPositionVolSET 100;
BA_ "GenSigSendType" SG_ 959 HURRPositionVolSET 0;
BA_ "GenSigStartValue" SG_ 959 HURRPositionVolSET 0;
BA_ "GenSigInvalidValue" SG_ 959 HURRPositionVolSET 0;
BA_ "GenSigCycleTime" SG_ 959 HURRSurroundPositionDelaySET 100;
BA_ "GenSigSendType" SG_ 959 HURRSurroundPositionDelaySET 0;
BA_ "GenSigStartValue" SG_ 959 HURRSurroundPositionDelaySET 0;
BA_ "GenSigInvalidValue" SG_ 959 HURRSurroundPositionDelaySET 0;
BA_ "GenSigCycleTime" SG_ 959 HURRSurroundPositionVolSET 100;
BA_ "GenSigSendType" SG_ 959 HURRSurroundPositionVolSET 0;
BA_ "GenSigStartValue" SG_ 959 HURRSurroundPositionVolSET 0;
BA_ "GenSigInvalidValue" SG_ 959 HURRSurroundPositionVolSET 0;
BA_ "GenSigCycleTime" SG_ 959 HURRTopPositionDelaySET 100;
BA_ "GenSigSendType" SG_ 959 HURRTopPositionDelaySET 0;
BA_ "GenSigStartValue" SG_ 959 HURRTopPositionDelaySET 0;
BA_ "GenSigInvalidValue" SG_ 959 HURRTopPositionDelaySET 0;
BA_ "GenSigCycleTime" SG_ 959 HURRTopPositionVolSET 100;
BA_ "GenSigSendType" SG_ 959 HURRTopPositionVolSET 0;
BA_ "GenSigStartValue" SG_ 959 HURRTopPositionVolSET 0;
BA_ "GenSigInvalidValue" SG_ 959 HURRTopPositionVolSET 0;
BA_ "GenSigCycleTime" SG_ 965 AD_HWPStatus 100;
BA_ "GenSigSendType" SG_ 965 AD_HWPStatus 0;
BA_ "GenSigStartValue" SG_ 965 AD_HWPStatus 0;
BA_ "GenSigInvalidValue" SG_ 965 AD_HWPStatus 0;
BA_ "GenSigCycleTime" SG_ 965 ACC_ADCNotice 100;
BA_ "GenSigSendType" SG_ 965 ACC_ADCNotice 0;
BA_ "GenSigStartValue" SG_ 965 ACC_ADCNotice 0;
BA_ "GenSigInvalidValue" SG_ 965 ACC_ADCNotice 0;
BA_ "GenSigCycleTime" SG_ 965 AD_SafetyNotice 100;
BA_ "GenSigSendType" SG_ 965 AD_SafetyNotice 0;
BA_ "GenSigStartValue" SG_ 965 AD_SafetyNotice 0;
BA_ "GenSigInvalidValue" SG_ 965 AD_SafetyNotice 0;
BA_ "GenSigCycleTime" SG_ 965 AD_CRCCheck_3C5 100;
BA_ "GenSigSendType" SG_ 965 AD_CRCCheck_3C5 0;
BA_ "GenSigStartValue" SG_ 965 AD_CRCCheck_3C5 0;
BA_ "GenSigInvalidValue" SG_ 965 AD_CRCCheck_3C5 "/";
BA_ "GenSigCycleTime" SG_ 965 AD_RollingCounter_3C5 100;
BA_ "GenSigSendType" SG_ 965 AD_RollingCounter_3C5 0;
BA_ "GenSigStartValue" SG_ 965 AD_RollingCounter_3C5 0;
BA_ "GenSigInvalidValue" SG_ 965 AD_RollingCounter_3C5 "/";
BA_ "GenSigCycleTime" SG_ 1000 Reserved_message3E8 0;
BA_ "GenSigSendType" SG_ 1000 Reserved_message3E8 3;
BA_ "GenSigStartValue" SG_ 1000 Reserved_message3E8 0;
BA_ "GenSigInvalidValue" SG_ 1000 Reserved_message3E8 0;
BA_ "GenSigCycleTime" SG_ 1001 Reserved_message3E9 0;
BA_ "GenSigSendType" SG_ 1001 Reserved_message3E9 3;
BA_ "GenSigStartValue" SG_ 1001 Reserved_message3E9 0;
BA_ "GenSigInvalidValue" SG_ 1001 Reserved_message3E9 0;
BA_ "GenSigCycleTime" SG_ 1015 IP_brightness 100;
BA_ "GenSigSendType" SG_ 1015 IP_brightness 0;
BA_ "GenSigStartValue" SG_ 1015 IP_brightness 0;
BA_ "GenSigInvalidValue" SG_ 1015 IP_brightness 0;
BA_ "GenSigCycleTime" SG_ 1015 IPFault 100;
BA_ "GenSigSendType" SG_ 1015 IPFault 0;
BA_ "GenSigStartValue" SG_ 1015 IPFault 0;
BA_ "GenSigInvalidValue" SG_ 1015 IPFault 0;
BA_ "GenSigCycleTime" SG_ 1025 NM_message401 0;
BA_ "GenSigSendType" SG_ 1025 NM_message401 3;
BA_ "GenSigStartValue" SG_ 1025 NM_message401 0;
BA_ "GenSigInvalidValue" SG_ 1025 NM_message401 0;
BA_ "GenSigCycleTime" SG_ 1031 NM_message407 0;
BA_ "GenSigSendType" SG_ 1031 NM_message407 3;
BA_ "GenSigStartValue" SG_ 1031 NM_message407 0;
BA_ "GenSigInvalidValue" SG_ 1031 NM_message407 0;
BA_ "GenSigCycleTime" SG_ 1036 NM_message40C 0;
BA_ "GenSigSendType" SG_ 1036 NM_message40C 3;
BA_ "GenSigStartValue" SG_ 1036 NM_message40C 0;
BA_ "GenSigInvalidValue" SG_ 1036 NM_message40C 0;
BA_ "GenSigCycleTime" SG_ 1037 NM_message40D 0;
BA_ "GenSigSendType" SG_ 1037 NM_message40D 3;
BA_ "GenSigStartValue" SG_ 1037 NM_message40D 0;
BA_ "GenSigInvalidValue" SG_ 1037 NM_message40D 0;
BA_ "GenSigCycleTime" SG_ 1041 NM_message411 0;
BA_ "GenSigSendType" SG_ 1041 NM_message411 3;
BA_ "GenSigStartValue" SG_ 1041 NM_message411 0;
BA_ "GenSigInvalidValue" SG_ 1041 NM_message411 0;
BA_ "GenSigCycleTime" SG_ 1059 NM_message423 0;
BA_ "GenSigSendType" SG_ 1059 NM_message423 3;
BA_ "GenSigStartValue" SG_ 1059 NM_message423 0;
BA_ "GenSigInvalidValue" SG_ 1059 NM_message423 0;
BA_ "GenSigCycleTime" SG_ 1193 NM_message4A9 0;
BA_ "GenSigSendType" SG_ 1193 NM_message4A9 3;
BA_ "GenSigStartValue" SG_ 1193 NM_message4A9 0;
BA_ "GenSigInvalidValue" SG_ 1193 NM_message4A9 0;
BA_ "GenSigCycleTime" SG_ 1280 TBOX_NotSleep_BYTE6BIT0 1000;
BA_ "GenSigSendType" SG_ 1280 TBOX_NotSleep_BYTE6BIT0 0;
BA_ "GenSigStartValue" SG_ 1280 TBOX_NotSleep_BYTE6BIT0 0;
BA_ "GenSigInvalidValue" SG_ 1280 TBOX_NotSleep_BYTE6BIT0 0;
BA_ "GenSigCycleTime" SG_ 1280 TBOX_NotSleep_BYTE7BIT0 1000;
BA_ "GenSigSendType" SG_ 1280 TBOX_NotSleep_BYTE7BIT0 0;
BA_ "GenSigStartValue" SG_ 1280 TBOX_NotSleep_BYTE7BIT0 0;
BA_ "GenSigInvalidValue" SG_ 1280 TBOX_NotSleep_BYTE7BIT0 0;
BA_ "GenSigCycleTime" SG_ 1280 TBOX_NotSleep_BYTE7BIT1 1000;
BA_ "GenSigSendType" SG_ 1280 TBOX_NotSleep_BYTE7BIT1 0;
BA_ "GenSigStartValue" SG_ 1280 TBOX_NotSleep_BYTE7BIT1 0;
BA_ "GenSigInvalidValue" SG_ 1280 TBOX_NotSleep_BYTE7BIT1 0;
BA_ "GenSigCycleTime" SG_ 1280 TBOX_NotSleep_BYTE7BIT2 1000;
BA_ "GenSigSendType" SG_ 1280 TBOX_NotSleep_BYTE7BIT2 0;
BA_ "GenSigStartValue" SG_ 1280 TBOX_NotSleep_BYTE7BIT2 0;
BA_ "GenSigInvalidValue" SG_ 1280 TBOX_NotSleep_BYTE7BIT2 0;
BA_ "GenSigCycleTime" SG_ 1280 TBOX_NotSleep_BYTE7BIT3 1000;
BA_ "GenSigSendType" SG_ 1280 TBOX_NotSleep_BYTE7BIT3 0;
BA_ "GenSigStartValue" SG_ 1280 TBOX_NotSleep_BYTE7BIT3 0;
BA_ "GenSigInvalidValue" SG_ 1280 TBOX_NotSleep_BYTE7BIT3 0;
BA_ "GenSigCycleTime" SG_ 1280 TBOX_NotSleep_BYTE7BIT4 1000;
BA_ "GenSigSendType" SG_ 1280 TBOX_NotSleep_BYTE7BIT4 0;
BA_ "GenSigStartValue" SG_ 1280 TBOX_NotSleep_BYTE7BIT4 0;
BA_ "GenSigInvalidValue" SG_ 1280 TBOX_NotSleep_BYTE7BIT4 0;
BA_ "GenSigCycleTime" SG_ 1280 TBOX_NotSleep_BYTE7BIT5 1000;
BA_ "GenSigSendType" SG_ 1280 TBOX_NotSleep_BYTE7BIT5 0;
BA_ "GenSigStartValue" SG_ 1280 TBOX_NotSleep_BYTE7BIT5 0;
BA_ "GenSigInvalidValue" SG_ 1280 TBOX_NotSleep_BYTE7BIT5 0;
BA_ "GenSigCycleTime" SG_ 1280 TBOX_NotSleep_BYTE7BIT6 1000;
BA_ "GenSigSendType" SG_ 1280 TBOX_NotSleep_BYTE7BIT6 0;
BA_ "GenSigStartValue" SG_ 1280 TBOX_NotSleep_BYTE7BIT6 0;
BA_ "GenSigInvalidValue" SG_ 1280 TBOX_NotSleep_BYTE7BIT6 0;
BA_ "GenSigCycleTime" SG_ 1280 TBOX_NotSleep_BYTE7BIT7 1000;
BA_ "GenSigSendType" SG_ 1280 TBOX_NotSleep_BYTE7BIT7 0;
BA_ "GenSigStartValue" SG_ 1280 TBOX_NotSleep_BYTE7BIT7 0;
BA_ "GenSigInvalidValue" SG_ 1280 TBOX_NotSleep_BYTE7BIT7 0;
BA_ "GenSigCycleTime" SG_ 1280 TBOX_WakeUp_BYTE3BIT0 1000;
BA_ "GenSigSendType" SG_ 1280 TBOX_WakeUp_BYTE3BIT0 0;
BA_ "GenSigStartValue" SG_ 1280 TBOX_WakeUp_BYTE3BIT0 0;
BA_ "GenSigInvalidValue" SG_ 1280 TBOX_WakeUp_BYTE3BIT0 0;
BA_ "GenSigCycleTime" SG_ 1280 TBOX_WakeUp_BYTE3BIT1 1000;
BA_ "GenSigSendType" SG_ 1280 TBOX_WakeUp_BYTE3BIT1 0;
BA_ "GenSigStartValue" SG_ 1280 TBOX_WakeUp_BYTE3BIT1 0;
BA_ "GenSigInvalidValue" SG_ 1280 TBOX_WakeUp_BYTE3BIT1 0;
BA_ "GenSigCycleTime" SG_ 1280 TBOX_WakeUp_BYTE3BIT2 1000;
BA_ "GenSigSendType" SG_ 1280 TBOX_WakeUp_BYTE3BIT2 0;
BA_ "GenSigStartValue" SG_ 1280 TBOX_WakeUp_BYTE3BIT2 0;
BA_ "GenSigInvalidValue" SG_ 1280 TBOX_WakeUp_BYTE3BIT2 0;
BA_ "GenSigCycleTime" SG_ 1280 TBOX_WakeUp_BYTE3BIT3 1000;
BA_ "GenSigSendType" SG_ 1280 TBOX_WakeUp_BYTE3BIT3 0;
BA_ "GenSigStartValue" SG_ 1280 TBOX_WakeUp_BYTE3BIT3 0;
BA_ "GenSigInvalidValue" SG_ 1280 TBOX_WakeUp_BYTE3BIT3 0;
BA_ "GenSigCycleTime" SG_ 1280 TBOX_WakeUp_BYTE3BIT4 1000;
BA_ "GenSigSendType" SG_ 1280 TBOX_WakeUp_BYTE3BIT4 0;
BA_ "GenSigStartValue" SG_ 1280 TBOX_WakeUp_BYTE3BIT4 0;
BA_ "GenSigInvalidValue" SG_ 1280 TBOX_WakeUp_BYTE3BIT4 0;
BA_ "GenSigCycleTime" SG_ 1280 TBOX_WakeUp_BYTE3BIT5 1000;
BA_ "GenSigSendType" SG_ 1280 TBOX_WakeUp_BYTE3BIT5 0;
BA_ "GenSigStartValue" SG_ 1280 TBOX_WakeUp_BYTE3BIT5 0;
BA_ "GenSigInvalidValue" SG_ 1280 TBOX_WakeUp_BYTE3BIT5 0;
BA_ "GenSigCycleTime" SG_ 1280 TBOX_WakeUp_BYTE3BIT6 1000;
BA_ "GenSigSendType" SG_ 1280 TBOX_WakeUp_BYTE3BIT6 0;
BA_ "GenSigStartValue" SG_ 1280 TBOX_WakeUp_BYTE3BIT6 0;
BA_ "GenSigInvalidValue" SG_ 1280 TBOX_WakeUp_BYTE3BIT6 0;
BA_ "GenSigCycleTime" SG_ 1288 TMS_BatteryPumpErrCode 200;
BA_ "GenSigSendType" SG_ 1288 TMS_BatteryPumpErrCode 0;
BA_ "GenSigStartValue" SG_ 1288 TMS_BatteryPumpErrCode 0;
BA_ "GenSigInvalidValue" SG_ 1288 TMS_BatteryPumpErrCode 0;
BA_ "GenSigCycleTime" SG_ 1288 TMS_BatteryPumpSt 200;
BA_ "GenSigSendType" SG_ 1288 TMS_BatteryPumpSt 0;
BA_ "GenSigStartValue" SG_ 1288 TMS_BatteryPumpSt 0;
BA_ "GenSigInvalidValue" SG_ 1288 TMS_BatteryPumpSt 0;
BA_ "GenSigCycleTime" SG_ 1288 TMS_BattInpWtrTValid 200;
BA_ "GenSigSendType" SG_ 1288 TMS_BattInpWtrTValid 0;
BA_ "GenSigStartValue" SG_ 1288 TMS_BattInpWtrTValid 0;
BA_ "GenSigInvalidValue" SG_ 1288 TMS_BattInpWtrTValid 0;
BA_ "GenSigCycleTime" SG_ 1288 TMS_ECV1ErrCode_Radiator 200;
BA_ "GenSigSendType" SG_ 1288 TMS_ECV1ErrCode_Radiator 0;
BA_ "GenSigStartValue" SG_ 1288 TMS_ECV1ErrCode_Radiator 0;
BA_ "GenSigInvalidValue" SG_ 1288 TMS_ECV1ErrCode_Radiator 0;
BA_ "GenSigCycleTime" SG_ 1288 TMS_ECV1MotorSt_Radiator 200;
BA_ "GenSigSendType" SG_ 1288 TMS_ECV1MotorSt_Radiator 0;
BA_ "GenSigStartValue" SG_ 1288 TMS_ECV1MotorSt_Radiator 0;
BA_ "GenSigInvalidValue" SG_ 1288 TMS_ECV1MotorSt_Radiator 0;
BA_ "GenSigCycleTime" SG_ 1288 TMS_ECV1PosnAct_Radiator 200;
BA_ "GenSigSendType" SG_ 1288 TMS_ECV1PosnAct_Radiator 0;
BA_ "GenSigStartValue" SG_ 1288 TMS_ECV1PosnAct_Radiator 0;
BA_ "GenSigInvalidValue" SG_ 1288 TMS_ECV1PosnAct_Radiator 0;
BA_ "GenSigCycleTime" SG_ 1288 TMS_Ecv1St_Radiator 200;
BA_ "GenSigSendType" SG_ 1288 TMS_Ecv1St_Radiator 0;
BA_ "GenSigStartValue" SG_ 1288 TMS_Ecv1St_Radiator 0;
BA_ "GenSigInvalidValue" SG_ 1288 TMS_Ecv1St_Radiator 0;
BA_ "GenSigCycleTime" SG_ 1288 TMS_ECV2ErrCode_Battery 200;
BA_ "GenSigSendType" SG_ 1288 TMS_ECV2ErrCode_Battery 0;
BA_ "GenSigStartValue" SG_ 1288 TMS_ECV2ErrCode_Battery 0;
BA_ "GenSigInvalidValue" SG_ 1288 TMS_ECV2ErrCode_Battery 0;
BA_ "GenSigCycleTime" SG_ 1288 TMS_ECV2MotorSt_Battery 200;
BA_ "GenSigSendType" SG_ 1288 TMS_ECV2MotorSt_Battery 0;
BA_ "GenSigStartValue" SG_ 1288 TMS_ECV2MotorSt_Battery 0;
BA_ "GenSigInvalidValue" SG_ 1288 TMS_ECV2MotorSt_Battery 0;
BA_ "GenSigCycleTime" SG_ 1288 TMS_ECV2PosnAct_Battery 200;
BA_ "GenSigSendType" SG_ 1288 TMS_ECV2PosnAct_Battery 0;
BA_ "GenSigStartValue" SG_ 1288 TMS_ECV2PosnAct_Battery 0;
BA_ "GenSigInvalidValue" SG_ 1288 TMS_ECV2PosnAct_Battery 0;
BA_ "GenSigCycleTime" SG_ 1288 TMS_ECV2St_Battery 200;
BA_ "GenSigSendType" SG_ 1288 TMS_ECV2St_Battery 0;
BA_ "GenSigStartValue" SG_ 1288 TMS_ECV2St_Battery 0;
BA_ "GenSigInvalidValue" SG_ 1288 TMS_ECV2St_Battery 0;
BA_ "GenSigCycleTime" SG_ 1288 TMS_ECV3ErrCode_Hydrothermal 200;
BA_ "GenSigSendType" SG_ 1288 TMS_ECV3ErrCode_Hydrothermal 0;
BA_ "GenSigStartValue" SG_ 1288 TMS_ECV3ErrCode_Hydrothermal 0;
BA_ "GenSigInvalidValue" SG_ 1288 TMS_ECV3ErrCode_Hydrothermal 0;
BA_ "GenSigCycleTime" SG_ 1288 TMS_ECV3MotorSt_Hydrothermal 200;
BA_ "GenSigSendType" SG_ 1288 TMS_ECV3MotorSt_Hydrothermal 0;
BA_ "GenSigStartValue" SG_ 1288 TMS_ECV3MotorSt_Hydrothermal 0;
BA_ "GenSigInvalidValue" SG_ 1288 TMS_ECV3MotorSt_Hydrothermal 0;
BA_ "GenSigCycleTime" SG_ 1288 TMS_ECV3PosnAct_Hydrothermal 200;
BA_ "GenSigSendType" SG_ 1288 TMS_ECV3PosnAct_Hydrothermal 0;
BA_ "GenSigStartValue" SG_ 1288 TMS_ECV3PosnAct_Hydrothermal 0;
BA_ "GenSigInvalidValue" SG_ 1288 TMS_ECV3PosnAct_Hydrothermal 0;
BA_ "GenSigCycleTime" SG_ 1288 TMS_ECV3St_Hydrothermal 200;
BA_ "GenSigSendType" SG_ 1288 TMS_ECV3St_Hydrothermal 0;
BA_ "GenSigStartValue" SG_ 1288 TMS_ECV3St_Hydrothermal 0;
BA_ "GenSigInvalidValue" SG_ 1288 TMS_ECV3St_Hydrothermal 0;
BA_ "GenSigCycleTime" SG_ 1288 TMS_ExtendRangePumpErrCode 200;
BA_ "GenSigSendType" SG_ 1288 TMS_ExtendRangePumpErrCode 0;
BA_ "GenSigStartValue" SG_ 1288 TMS_ExtendRangePumpErrCode 0;
BA_ "GenSigInvalidValue" SG_ 1288 TMS_ExtendRangePumpErrCode 0;
BA_ "GenSigCycleTime" SG_ 1288 TMS_ExtendRangePumpSt 200;
BA_ "GenSigSendType" SG_ 1288 TMS_ExtendRangePumpSt 0;
BA_ "GenSigStartValue" SG_ 1288 TMS_ExtendRangePumpSt 0;
BA_ "GenSigInvalidValue" SG_ 1288 TMS_ExtendRangePumpSt 0;
BA_ "GenSigCycleTime" SG_ 1288 TMS_Exv1ErrCode_HVAC 200;
BA_ "GenSigSendType" SG_ 1288 TMS_Exv1ErrCode_HVAC 0;
BA_ "GenSigStartValue" SG_ 1288 TMS_Exv1ErrCode_HVAC 0;
BA_ "GenSigInvalidValue" SG_ 1288 TMS_Exv1ErrCode_HVAC 0;
BA_ "GenSigCycleTime" SG_ 1288 TMS_Exv1InitSt_HVAC 200;
BA_ "GenSigSendType" SG_ 1288 TMS_Exv1InitSt_HVAC 0;
BA_ "GenSigStartValue" SG_ 1288 TMS_Exv1InitSt_HVAC 0;
BA_ "GenSigInvalidValue" SG_ 1288 TMS_Exv1InitSt_HVAC 0;
BA_ "GenSigCycleTime" SG_ 1288 TMS_Exv1PosnAct_HVAC 200;
BA_ "GenSigSendType" SG_ 1288 TMS_Exv1PosnAct_HVAC 0;
BA_ "GenSigStartValue" SG_ 1288 TMS_Exv1PosnAct_HVAC 0;
BA_ "GenSigInvalidValue" SG_ 1288 TMS_Exv1PosnAct_HVAC 0;
BA_ "GenSigCycleTime" SG_ 1288 TMS_Exv1RunSt_HVAC 200;
BA_ "GenSigSendType" SG_ 1288 TMS_Exv1RunSt_HVAC 0;
BA_ "GenSigStartValue" SG_ 1288 TMS_Exv1RunSt_HVAC 0;
BA_ "GenSigInvalidValue" SG_ 1288 TMS_Exv1RunSt_HVAC 0;
BA_ "GenSigCycleTime" SG_ 1288 TMS_Exv2ErrCode_Battery 200;
BA_ "GenSigSendType" SG_ 1288 TMS_Exv2ErrCode_Battery 0;
BA_ "GenSigStartValue" SG_ 1288 TMS_Exv2ErrCode_Battery 0;
BA_ "GenSigInvalidValue" SG_ 1288 TMS_Exv2ErrCode_Battery 0;
BA_ "GenSigCycleTime" SG_ 1288 TMS_Exv2InitSt_Battery 200;
BA_ "GenSigSendType" SG_ 1288 TMS_Exv2InitSt_Battery 0;
BA_ "GenSigStartValue" SG_ 1288 TMS_Exv2InitSt_Battery 0;
BA_ "GenSigInvalidValue" SG_ 1288 TMS_Exv2InitSt_Battery 0;
BA_ "GenSigCycleTime" SG_ 1288 TMS_Exv2RunSt_Battery 200;
BA_ "GenSigSendType" SG_ 1288 TMS_Exv2RunSt_Battery 0;
BA_ "GenSigStartValue" SG_ 1288 TMS_Exv2RunSt_Battery 0;
BA_ "GenSigInvalidValue" SG_ 1288 TMS_Exv2RunSt_Battery 0;
BA_ "GenSigCycleTime" SG_ 1288 TMS_Exv3ErrCode_WasteHeatRe 200;
BA_ "GenSigSendType" SG_ 1288 TMS_Exv3ErrCode_WasteHeatRe 0;
BA_ "GenSigStartValue" SG_ 1288 TMS_Exv3ErrCode_WasteHeatRe 0;
BA_ "GenSigInvalidValue" SG_ 1288 TMS_Exv3ErrCode_WasteHeatRe 0;
BA_ "GenSigCycleTime" SG_ 1288 TMS_Exv3InitSt_WasteHeatRe 200;
BA_ "GenSigSendType" SG_ 1288 TMS_Exv3InitSt_WasteHeatRe 0;
BA_ "GenSigStartValue" SG_ 1288 TMS_Exv3InitSt_WasteHeatRe 0;
BA_ "GenSigInvalidValue" SG_ 1288 TMS_Exv3InitSt_WasteHeatRe 0;
BA_ "GenSigCycleTime" SG_ 1288 TMS_Exv3PosnAct_WasteHeatRe 200;
BA_ "GenSigSendType" SG_ 1288 TMS_Exv3PosnAct_WasteHeatRe 0;
BA_ "GenSigStartValue" SG_ 1288 TMS_Exv3PosnAct_WasteHeatRe 0;
BA_ "GenSigInvalidValue" SG_ 1288 TMS_Exv3PosnAct_WasteHeatRe 0;
BA_ "GenSigCycleTime" SG_ 1288 TMS_Exv3RunSt_WasteHeatRe 200;
BA_ "GenSigSendType" SG_ 1288 TMS_Exv3RunSt_WasteHeatRe 0;
BA_ "GenSigStartValue" SG_ 1288 TMS_Exv3RunSt_WasteHeatRe 0;
BA_ "GenSigInvalidValue" SG_ 1288 TMS_Exv3RunSt_WasteHeatRe 0;
BA_ "GenSigCycleTime" SG_ 1288 TMS_Exv4ErrCode_Refrigerant 200;
BA_ "GenSigSendType" SG_ 1288 TMS_Exv4ErrCode_Refrigerant 0;
BA_ "GenSigStartValue" SG_ 1288 TMS_Exv4ErrCode_Refrigerant 0;
BA_ "GenSigInvalidValue" SG_ 1288 TMS_Exv4ErrCode_Refrigerant 0;
BA_ "GenSigCycleTime" SG_ 1288 TMS_Exv4InitSt_Refrigerant 200;
BA_ "GenSigSendType" SG_ 1288 TMS_Exv4InitSt_Refrigerant 0;
BA_ "GenSigStartValue" SG_ 1288 TMS_Exv4InitSt_Refrigerant 0;
BA_ "GenSigInvalidValue" SG_ 1288 TMS_Exv4InitSt_Refrigerant 0;
BA_ "GenSigCycleTime" SG_ 1288 TMS_Exv4PosnAct_Refrigerant 200;
BA_ "GenSigSendType" SG_ 1288 TMS_Exv4PosnAct_Refrigerant 0;
BA_ "GenSigStartValue" SG_ 1288 TMS_Exv4PosnAct_Refrigerant 0;
BA_ "GenSigInvalidValue" SG_ 1288 TMS_Exv4PosnAct_Refrigerant 0;
BA_ "GenSigCycleTime" SG_ 1288 TMS_Exv4RunningSt_Refrigerant 200;
BA_ "GenSigSendType" SG_ 1288 TMS_Exv4RunningSt_Refrigerant 0;
BA_ "GenSigStartValue" SG_ 1288 TMS_Exv4RunningSt_Refrigerant 0;
BA_ "GenSigInvalidValue" SG_ 1288 TMS_Exv4RunningSt_Refrigerant 0;
BA_ "GenSigCycleTime" SG_ 1288 TMS_FWV1ErrCode 200;
BA_ "GenSigSendType" SG_ 1288 TMS_FWV1ErrCode 0;
BA_ "GenSigStartValue" SG_ 1288 TMS_FWV1ErrCode 0;
BA_ "GenSigInvalidValue" SG_ 1288 TMS_FWV1ErrCode 0;
BA_ "GenSigCycleTime" SG_ 1288 TMS_FWV1MotorSt 200;
BA_ "GenSigSendType" SG_ 1288 TMS_FWV1MotorSt 0;
BA_ "GenSigStartValue" SG_ 1288 TMS_FWV1MotorSt 0;
BA_ "GenSigInvalidValue" SG_ 1288 TMS_FWV1MotorSt 0;
BA_ "GenSigCycleTime" SG_ 1288 TMS_FWV1PosnAct 200;
BA_ "GenSigSendType" SG_ 1288 TMS_FWV1PosnAct 0;
BA_ "GenSigStartValue" SG_ 1288 TMS_FWV1PosnAct 0;
BA_ "GenSigInvalidValue" SG_ 1288 TMS_FWV1PosnAct 0;
BA_ "GenSigCycleTime" SG_ 1288 TMS_FWV1St 200;
BA_ "GenSigSendType" SG_ 1288 TMS_FWV1St 0;
BA_ "GenSigStartValue" SG_ 1288 TMS_FWV1St 0;
BA_ "GenSigInvalidValue" SG_ 1288 TMS_FWV1St 0;
BA_ "GenSigCycleTime" SG_ 1288 TMS_InSeriesPumpErrCode 200;
BA_ "GenSigSendType" SG_ 1288 TMS_InSeriesPumpErrCode 0;
BA_ "GenSigStartValue" SG_ 1288 TMS_InSeriesPumpErrCode 0;
BA_ "GenSigInvalidValue" SG_ 1288 TMS_InSeriesPumpErrCode 0;
BA_ "GenSigCycleTime" SG_ 1288 TMS_InSeriesPumpSpdAct 200;
BA_ "GenSigSendType" SG_ 1288 TMS_InSeriesPumpSpdAct 0;
BA_ "GenSigStartValue" SG_ 1288 TMS_InSeriesPumpSpdAct 0;
BA_ "GenSigInvalidValue" SG_ 1288 TMS_InSeriesPumpSpdAct 0;
BA_ "GenSigCycleTime" SG_ 1288 TMS_MotorPumpSt 200;
BA_ "GenSigSendType" SG_ 1288 TMS_MotorPumpSt 0;
BA_ "GenSigStartValue" SG_ 1288 TMS_MotorPumpSt 0;
BA_ "GenSigInvalidValue" SG_ 1288 TMS_MotorPumpSt 0;
BA_ "GenSigCycleTime" SG_ 1288 TMS_OilCoolerWtrT 200;
BA_ "GenSigSendType" SG_ 1288 TMS_OilCoolerWtrT 0;
BA_ "GenSigStartValue" SG_ 1288 TMS_OilCoolerWtrT 60;
BA_ "GenSigInvalidValue" SG_ 1288 TMS_OilCoolerWtrT 60;
BA_ "GenSigCycleTime" SG_ 1288 TMS_OilCoolerWtrTValid 200;
BA_ "GenSigSendType" SG_ 1288 TMS_OilCoolerWtrTValid 0;
BA_ "GenSigStartValue" SG_ 1288 TMS_OilCoolerWtrTValid 0;
BA_ "GenSigInvalidValue" SG_ 1288 TMS_OilCoolerWtrTValid 0;
BA_ "GenSigCycleTime" SG_ 1288 TMS_PT1PrErrCode 200;
BA_ "GenSigSendType" SG_ 1288 TMS_PT1PrErrCode 0;
BA_ "GenSigStartValue" SG_ 1288 TMS_PT1PrErrCode 0;
BA_ "GenSigInvalidValue" SG_ 1288 TMS_PT1PrErrCode 0;
BA_ "GenSigCycleTime" SG_ 1288 TMS_PT1TempSnsrErrCode 200;
BA_ "GenSigSendType" SG_ 1288 TMS_PT1TempSnsrErrCode 0;
BA_ "GenSigStartValue" SG_ 1288 TMS_PT1TempSnsrErrCode 0;
BA_ "GenSigInvalidValue" SG_ 1288 TMS_PT1TempSnsrErrCode 0;
BA_ "GenSigCycleTime" SG_ 1288 TMS_PT2PrErrCode 200;
BA_ "GenSigSendType" SG_ 1288 TMS_PT2PrErrCode 0;
BA_ "GenSigStartValue" SG_ 1288 TMS_PT2PrErrCode 0;
BA_ "GenSigInvalidValue" SG_ 1288 TMS_PT2PrErrCode 0;
BA_ "GenSigCycleTime" SG_ 1288 TMS_PT2TempSnsrErrCode 200;
BA_ "GenSigSendType" SG_ 1288 TMS_PT2TempSnsrErrCode 0;
BA_ "GenSigStartValue" SG_ 1288 TMS_PT2TempSnsrErrCode 0;
BA_ "GenSigInvalidValue" SG_ 1288 TMS_PT2TempSnsrErrCode 0;
BA_ "GenSigCycleTime" SG_ 1288 TMS_PT3PrErrCode 200;
BA_ "GenSigSendType" SG_ 1288 TMS_PT3PrErrCode 0;
BA_ "GenSigStartValue" SG_ 1288 TMS_PT3PrErrCode 0;
BA_ "GenSigInvalidValue" SG_ 1288 TMS_PT3PrErrCode 0;
BA_ "GenSigCycleTime" SG_ 1288 TMS_PT3TempSnsrErrCode 200;
BA_ "GenSigSendType" SG_ 1288 TMS_PT3TempSnsrErrCode 0;
BA_ "GenSigStartValue" SG_ 1288 TMS_PT3TempSnsrErrCode 0;
BA_ "GenSigInvalidValue" SG_ 1288 TMS_PT3TempSnsrErrCode 0;
BA_ "GenSigCycleTime" SG_ 1288 TMS_PT4P_LiquidStorage 200;
BA_ "GenSigSendType" SG_ 1288 TMS_PT4P_LiquidStorage 0;
BA_ "GenSigStartValue" SG_ 1288 TMS_PT4P_LiquidStorage 0;
BA_ "GenSigInvalidValue" SG_ 1288 TMS_PT4P_LiquidStorage 0;
BA_ "GenSigCycleTime" SG_ 1288 TMS_PT4PrErrCode 200;
BA_ "GenSigSendType" SG_ 1288 TMS_PT4PrErrCode 0;
BA_ "GenSigStartValue" SG_ 1288 TMS_PT4PrErrCode 0;
BA_ "GenSigInvalidValue" SG_ 1288 TMS_PT4PrErrCode 0;
BA_ "GenSigCycleTime" SG_ 1288 TMS_PT4temp_LiquidStorage 200;
BA_ "GenSigSendType" SG_ 1288 TMS_PT4temp_LiquidStorage 0;
BA_ "GenSigStartValue" SG_ 1288 TMS_PT4temp_LiquidStorage 0;
BA_ "GenSigInvalidValue" SG_ 1288 TMS_PT4temp_LiquidStorage 0;
BA_ "GenSigCycleTime" SG_ 1288 TMS_PT4TempSnsrErrCode 200;
BA_ "GenSigSendType" SG_ 1288 TMS_PT4TempSnsrErrCode 0;
BA_ "GenSigStartValue" SG_ 1288 TMS_PT4TempSnsrErrCode 0;
BA_ "GenSigInvalidValue" SG_ 1288 TMS_PT4TempSnsrErrCode 0;
BA_ "GenSigCycleTime" SG_ 1288 TMS_PT5Pr_WasteHeatRe 200;
BA_ "GenSigSendType" SG_ 1288 TMS_PT5Pr_WasteHeatRe 0;
BA_ "GenSigStartValue" SG_ 1288 TMS_PT5Pr_WasteHeatRe 0;
BA_ "GenSigInvalidValue" SG_ 1288 TMS_PT5Pr_WasteHeatRe 0;
BA_ "GenSigCycleTime" SG_ 1288 TMS_PT5PrErrCode 200;
BA_ "GenSigSendType" SG_ 1288 TMS_PT5PrErrCode 0;
BA_ "GenSigStartValue" SG_ 1288 TMS_PT5PrErrCode 0;
BA_ "GenSigInvalidValue" SG_ 1288 TMS_PT5PrErrCode 0;
BA_ "GenSigCycleTime" SG_ 1288 TMS_PT5temp_WasteHeatRe 200;
BA_ "GenSigSendType" SG_ 1288 TMS_PT5temp_WasteHeatRe 0;
BA_ "GenSigStartValue" SG_ 1288 TMS_PT5temp_WasteHeatRe 0;
BA_ "GenSigInvalidValue" SG_ 1288 TMS_PT5temp_WasteHeatRe 0;
BA_ "GenSigCycleTime" SG_ 1288 TMS_PT5TempSnsrErrCode 200;
BA_ "GenSigSendType" SG_ 1288 TMS_PT5TempSnsrErrCode 0;
BA_ "GenSigStartValue" SG_ 1288 TMS_PT5TempSnsrErrCode 0;
BA_ "GenSigInvalidValue" SG_ 1288 TMS_PT5TempSnsrErrCode 0;
BA_ "GenSigCycleTime" SG_ 1288 TMS_PT6Pr_RearEvap 200;
BA_ "GenSigSendType" SG_ 1288 TMS_PT6Pr_RearEvap 0;
BA_ "GenSigStartValue" SG_ 1288 TMS_PT6Pr_RearEvap 0;
BA_ "GenSigInvalidValue" SG_ 1288 TMS_PT6Pr_RearEvap 0;
BA_ "GenSigCycleTime" SG_ 1288 TMS_PT6PrErrCode 200;
BA_ "GenSigSendType" SG_ 1288 TMS_PT6PrErrCode 0;
BA_ "GenSigStartValue" SG_ 1288 TMS_PT6PrErrCode 0;
BA_ "GenSigInvalidValue" SG_ 1288 TMS_PT6PrErrCode 0;
BA_ "GenSigCycleTime" SG_ 1288 TMS_PT6temp_RearEvap 200;
BA_ "GenSigSendType" SG_ 1288 TMS_PT6temp_RearEvap 0;
BA_ "GenSigStartValue" SG_ 1288 TMS_PT6temp_RearEvap 0;
BA_ "GenSigInvalidValue" SG_ 1288 TMS_PT6temp_RearEvap 0;
BA_ "GenSigCycleTime" SG_ 1288 TMS_PT6TempSnsrErrCode 200;
BA_ "GenSigSendType" SG_ 1288 TMS_PT6TempSnsrErrCode 0;
BA_ "GenSigStartValue" SG_ 1288 TMS_PT6TempSnsrErrCode 0;
BA_ "GenSigInvalidValue" SG_ 1288 TMS_PT6TempSnsrErrCode 0;
BA_ "GenSigCycleTime" SG_ 1288 TMS_SolnVlv1St_DLP 200;
BA_ "GenSigSendType" SG_ 1288 TMS_SolnVlv1St_DLP 0;
BA_ "GenSigStartValue" SG_ 1288 TMS_SolnVlv1St_DLP 0;
BA_ "GenSigInvalidValue" SG_ 1288 TMS_SolnVlv1St_DLP 0;
BA_ "GenSigCycleTime" SG_ 1288 TMS_SolnVlv1St_RearEvap 200;
BA_ "GenSigSendType" SG_ 1288 TMS_SolnVlv1St_RearEvap 0;
BA_ "GenSigStartValue" SG_ 1288 TMS_SolnVlv1St_RearEvap 0;
BA_ "GenSigInvalidValue" SG_ 1288 TMS_SolnVlv1St_RearEvap 0;
BA_ "GenSigCycleTime" SG_ 1288 TMS_WarmPumpErrCode 200;
BA_ "GenSigSendType" SG_ 1288 TMS_WarmPumpErrCode 0;
BA_ "GenSigStartValue" SG_ 1288 TMS_WarmPumpErrCode 0;
BA_ "GenSigInvalidValue" SG_ 1288 TMS_WarmPumpErrCode 0;
BA_ "GenSigCycleTime" SG_ 1288 Tms_ExtenderPmpCtrlVal 200;
BA_ "GenSigSendType" SG_ 1288 Tms_ExtenderPmpCtrlVal 0;
BA_ "GenSigStartValue" SG_ 1288 Tms_ExtenderPmpCtrlVal 0;
BA_ "GenSigInvalidValue" SG_ 1288 Tms_ExtenderPmpCtrlVal 0;
BA_ "GenSigCycleTime" SG_ 1288 Tms_ExtenderPmpSts 200;
BA_ "GenSigSendType" SG_ 1288 Tms_ExtenderPmpSts 0;
BA_ "GenSigStartValue" SG_ 1288 Tms_ExtenderPmpSts 0;
BA_ "GenSigInvalidValue" SG_ 1288 Tms_ExtenderPmpSts 0;
BA_ "GenSigCycleTime" SG_ 1288 Tms_HeatPmpCtrlVal 200;
BA_ "GenSigSendType" SG_ 1288 Tms_HeatPmpCtrlVal 0;
BA_ "GenSigStartValue" SG_ 1288 Tms_HeatPmpCtrlVal 0;
BA_ "GenSigInvalidValue" SG_ 1288 Tms_HeatPmpCtrlVal 0;
BA_ "GenSigCycleTime" SG_ 1288 Tms_HeatPmpSts 200;
BA_ "GenSigSendType" SG_ 1288 Tms_HeatPmpSts 0;
BA_ "GenSigStartValue" SG_ 1288 Tms_HeatPmpSts 0;
BA_ "GenSigInvalidValue" SG_ 1288 Tms_HeatPmpSts 0;
BA_ "GenSigCycleTime" SG_ 1288 TMS_CTMU_SolnVlv3ErrCode 200;
BA_ "GenSigSendType" SG_ 1288 TMS_CTMU_SolnVlv3ErrCode 0;
BA_ "GenSigStartValue" SG_ 1288 TMS_CTMU_SolnVlv3ErrCode 0;
BA_ "GenSigInvalidValue" SG_ 1288 TMS_CTMU_SolnVlv3ErrCode 0;
BA_ "GenSigCycleTime" SG_ 1288 TMS_CTMU_SolnVlv3St 200;
BA_ "GenSigSendType" SG_ 1288 TMS_CTMU_SolnVlv3St 0;
BA_ "GenSigStartValue" SG_ 1288 TMS_CTMU_SolnVlv3St 0;
BA_ "GenSigInvalidValue" SG_ 1288 TMS_CTMU_SolnVlv3St 0;
BA_ "GenSigCycleTime" SG_ 1297 TPMS_CRCCheck_511 500;
BA_ "GenSigSendType" SG_ 1297 TPMS_CRCCheck_511 0;
BA_ "GenSigStartValue" SG_ 1297 TPMS_CRCCheck_511 0;
BA_ "GenSigInvalidValue" SG_ 1297 TPMS_CRCCheck_511 "NA";
BA_ "GenSigCycleTime" SG_ 1297 TPMS_RollingCounter_511 500;
BA_ "GenSigSendType" SG_ 1297 TPMS_RollingCounter_511 0;
BA_ "GenSigStartValue" SG_ 1297 TPMS_RollingCounter_511 0;
BA_ "GenSigInvalidValue" SG_ 1297 TPMS_RollingCounter_511 0;
BA_ "GenSigCycleTime" SG_ 1297 TpmsSysFailrWarn 500;
BA_ "GenSigSendType" SG_ 1297 TpmsSysFailrWarn 0;
BA_ "GenSigStartValue" SG_ 1297 TpmsSysFailrWarn 0;
BA_ "GenSigInvalidValue" SG_ 1297 TpmsSysFailrWarn 0;
BA_ "GenSigCycleTime" SG_ 1297 TpmsLeFrntTireP 500;
BA_ "GenSigSendType" SG_ 1297 TpmsLeFrntTireP 0;
BA_ "GenSigStartValue" SG_ 1297 TpmsLeFrntTireP 0;
BA_ "GenSigInvalidValue" SG_ 1297 TpmsLeFrntTireP "LastValue";
BA_ "GenSigCycleTime" SG_ 1297 TpmsLeFrntTirePWarn 500;
BA_ "GenSigSendType" SG_ 1297 TpmsLeFrntTirePWarn 0;
BA_ "GenSigStartValue" SG_ 1297 TpmsLeFrntTirePWarn 0;
BA_ "GenSigInvalidValue" SG_ 1297 TpmsLeFrntTirePWarn 0;
BA_ "GenSigCycleTime" SG_ 1297 TpmsLeReTireP 500;
BA_ "GenSigSendType" SG_ 1297 TpmsLeReTireP 0;
BA_ "GenSigStartValue" SG_ 1297 TpmsLeReTireP 0;
BA_ "GenSigInvalidValue" SG_ 1297 TpmsLeReTireP "LastValue";
BA_ "GenSigCycleTime" SG_ 1297 TpmsLeReTirePWarn 500;
BA_ "GenSigSendType" SG_ 1297 TpmsLeReTirePWarn 0;
BA_ "GenSigStartValue" SG_ 1297 TpmsLeReTirePWarn 0;
BA_ "GenSigInvalidValue" SG_ 1297 TpmsLeReTirePWarn 0;
BA_ "GenSigCycleTime" SG_ 1297 TpmsRiFrntTireP 500;
BA_ "GenSigSendType" SG_ 1297 TpmsRiFrntTireP 0;
BA_ "GenSigStartValue" SG_ 1297 TpmsRiFrntTireP 0;
BA_ "GenSigInvalidValue" SG_ 1297 TpmsRiFrntTireP "LastValue";
BA_ "GenSigCycleTime" SG_ 1297 TpmsRiFrntTirePWarn 500;
BA_ "GenSigSendType" SG_ 1297 TpmsRiFrntTirePWarn 0;
BA_ "GenSigStartValue" SG_ 1297 TpmsRiFrntTirePWarn 0;
BA_ "GenSigInvalidValue" SG_ 1297 TpmsRiFrntTirePWarn 0;
BA_ "GenSigCycleTime" SG_ 1297 TpmsRiReTireP 500;
BA_ "GenSigSendType" SG_ 1297 TpmsRiReTireP 0;
BA_ "GenSigStartValue" SG_ 1297 TpmsRiReTireP 0;
BA_ "GenSigInvalidValue" SG_ 1297 TpmsRiReTireP "LastValue";
BA_ "GenSigCycleTime" SG_ 1297 TpmsRiReTirePWarn 500;
BA_ "GenSigSendType" SG_ 1297 TpmsRiReTirePWarn 0;
BA_ "GenSigStartValue" SG_ 1297 TpmsRiReTirePWarn 0;
BA_ "GenSigInvalidValue" SG_ 1297 TpmsRiReTirePWarn 0;
BA_ "GenSigCycleTime" SG_ 1361 VIU_FL_NMNotSleep_BYTE2BIT0 1000;
BA_ "GenSigSendType" SG_ 1361 VIU_FL_NMNotSleep_BYTE2BIT0 0;
BA_ "GenSigStartValue" SG_ 1361 VIU_FL_NMNotSleep_BYTE2BIT0 0;
BA_ "GenSigInvalidValue" SG_ 1361 VIU_FL_NMNotSleep_BYTE2BIT0 0;
BA_ "GenSigCycleTime" SG_ 1361 VIU_FL_NMNotSleep_BYTE2BIT1 1000;
BA_ "GenSigSendType" SG_ 1361 VIU_FL_NMNotSleep_BYTE2BIT1 0;
BA_ "GenSigStartValue" SG_ 1361 VIU_FL_NMNotSleep_BYTE2BIT1 0;
BA_ "GenSigInvalidValue" SG_ 1361 VIU_FL_NMNotSleep_BYTE2BIT1 0;
BA_ "GenSigCycleTime" SG_ 1361 VIU_FL_NMNotSleep_BYTE2BIT2 1000;
BA_ "GenSigSendType" SG_ 1361 VIU_FL_NMNotSleep_BYTE2BIT2 0;
BA_ "GenSigStartValue" SG_ 1361 VIU_FL_NMNotSleep_BYTE2BIT2 0;
BA_ "GenSigInvalidValue" SG_ 1361 VIU_FL_NMNotSleep_BYTE2BIT2 0;
BA_ "GenSigCycleTime" SG_ 1361 VIU_FL_NMNotSleep_BYTE2BIT3 1000;
BA_ "GenSigSendType" SG_ 1361 VIU_FL_NMNotSleep_BYTE2BIT3 0;
BA_ "GenSigStartValue" SG_ 1361 VIU_FL_NMNotSleep_BYTE2BIT3 0;
BA_ "GenSigInvalidValue" SG_ 1361 VIU_FL_NMNotSleep_BYTE2BIT3 0;
BA_ "GenSigCycleTime" SG_ 1361 VIU_FL_NMNotSleep_BYTE2BIT4 1000;
BA_ "GenSigSendType" SG_ 1361 VIU_FL_NMNotSleep_BYTE2BIT4 0;
BA_ "GenSigStartValue" SG_ 1361 VIU_FL_NMNotSleep_BYTE2BIT4 0;
BA_ "GenSigInvalidValue" SG_ 1361 VIU_FL_NMNotSleep_BYTE2BIT4 0;
BA_ "GenSigCycleTime" SG_ 1361 VIU_FL_NMNotSleep_BYTE2BIT5 1000;
BA_ "GenSigSendType" SG_ 1361 VIU_FL_NMNotSleep_BYTE2BIT5 0;
BA_ "GenSigStartValue" SG_ 1361 VIU_FL_NMNotSleep_BYTE2BIT5 0;
BA_ "GenSigInvalidValue" SG_ 1361 VIU_FL_NMNotSleep_BYTE2BIT5 0;
BA_ "GenSigCycleTime" SG_ 1361 VIU_FL_NMNotSleep_BYTE2BIT6 1000;
BA_ "GenSigSendType" SG_ 1361 VIU_FL_NMNotSleep_BYTE2BIT6 0;
BA_ "GenSigStartValue" SG_ 1361 VIU_FL_NMNotSleep_BYTE2BIT6 0;
BA_ "GenSigInvalidValue" SG_ 1361 VIU_FL_NMNotSleep_BYTE2BIT6 0;
BA_ "GenSigCycleTime" SG_ 1361 VIU_FL_NMNotSleep_BYTE2BIT7 1000;
BA_ "GenSigSendType" SG_ 1361 VIU_FL_NMNotSleep_BYTE2BIT7 0;
BA_ "GenSigStartValue" SG_ 1361 VIU_FL_NMNotSleep_BYTE2BIT7 0;
BA_ "GenSigInvalidValue" SG_ 1361 VIU_FL_NMNotSleep_BYTE2BIT7 0;
BA_ "GenSigCycleTime" SG_ 1361 VIU_FL_NMNotSleep_BYTE3BIT0 1000;
BA_ "GenSigSendType" SG_ 1361 VIU_FL_NMNotSleep_BYTE3BIT0 0;
BA_ "GenSigStartValue" SG_ 1361 VIU_FL_NMNotSleep_BYTE3BIT0 0;
BA_ "GenSigInvalidValue" SG_ 1361 VIU_FL_NMNotSleep_BYTE3BIT0 0;
BA_ "GenSigCycleTime" SG_ 1361 VIU_FL_NMNotSleep_BYTE3BIT1 1000;
BA_ "GenSigSendType" SG_ 1361 VIU_FL_NMNotSleep_BYTE3BIT1 0;
BA_ "GenSigStartValue" SG_ 1361 VIU_FL_NMNotSleep_BYTE3BIT1 0;
BA_ "GenSigInvalidValue" SG_ 1361 VIU_FL_NMNotSleep_BYTE3BIT1 0;
BA_ "GenSigCycleTime" SG_ 1361 VIU_FL_NMNotSleep_BYTE3BIT2 1000;
BA_ "GenSigSendType" SG_ 1361 VIU_FL_NMNotSleep_BYTE3BIT2 0;
BA_ "GenSigStartValue" SG_ 1361 VIU_FL_NMNotSleep_BYTE3BIT2 0;
BA_ "GenSigInvalidValue" SG_ 1361 VIU_FL_NMNotSleep_BYTE3BIT2 0;
BA_ "GenSigCycleTime" SG_ 1361 VIU_FL_NMNotSleep_BYTE3BIT3 1000;
BA_ "GenSigSendType" SG_ 1361 VIU_FL_NMNotSleep_BYTE3BIT3 0;
BA_ "GenSigStartValue" SG_ 1361 VIU_FL_NMNotSleep_BYTE3BIT3 0;
BA_ "GenSigInvalidValue" SG_ 1361 VIU_FL_NMNotSleep_BYTE3BIT3 0;
BA_ "GenSigCycleTime" SG_ 1361 VIU_FL_NMNotSleep_BYTE3BIT4 1000;
BA_ "GenSigSendType" SG_ 1361 VIU_FL_NMNotSleep_BYTE3BIT4 0;
BA_ "GenSigStartValue" SG_ 1361 VIU_FL_NMNotSleep_BYTE3BIT4 0;
BA_ "GenSigInvalidValue" SG_ 1361 VIU_FL_NMNotSleep_BYTE3BIT4 0;
BA_ "GenSigCycleTime" SG_ 1361 VIU_FL_NMNotSleep_BYTE3BIT5 1000;
BA_ "GenSigSendType" SG_ 1361 VIU_FL_NMNotSleep_BYTE3BIT5 0;
BA_ "GenSigStartValue" SG_ 1361 VIU_FL_NMNotSleep_BYTE3BIT5 0;
BA_ "GenSigInvalidValue" SG_ 1361 VIU_FL_NMNotSleep_BYTE3BIT5 0;
BA_ "GenSigCycleTime" SG_ 1361 VIU_FL_NMNotSleep_BYTE3BIT6 1000;
BA_ "GenSigSendType" SG_ 1361 VIU_FL_NMNotSleep_BYTE3BIT6 0;
BA_ "GenSigStartValue" SG_ 1361 VIU_FL_NMNotSleep_BYTE3BIT6 0;
BA_ "GenSigInvalidValue" SG_ 1361 VIU_FL_NMNotSleep_BYTE3BIT6 0;
BA_ "GenSigCycleTime" SG_ 1361 VIU_FL_NMNotSleep_BYTE3BIT7 1000;
BA_ "GenSigSendType" SG_ 1361 VIU_FL_NMNotSleep_BYTE3BIT7 0;
BA_ "GenSigStartValue" SG_ 1361 VIU_FL_NMNotSleep_BYTE3BIT7 0;
BA_ "GenSigInvalidValue" SG_ 1361 VIU_FL_NMNotSleep_BYTE3BIT7 0;
BA_ "GenSigCycleTime" SG_ 1361 VIU_FL_NMNotSleep_BYTE4BIT0 1000;
BA_ "GenSigSendType" SG_ 1361 VIU_FL_NMNotSleep_BYTE4BIT0 0;
BA_ "GenSigStartValue" SG_ 1361 VIU_FL_NMNotSleep_BYTE4BIT0 0;
BA_ "GenSigInvalidValue" SG_ 1361 VIU_FL_NMNotSleep_BYTE4BIT0 0;
BA_ "GenSigCycleTime" SG_ 1361 VIU_FL_NMNotSleep_BYTE4BIT1 1000;
BA_ "GenSigSendType" SG_ 1361 VIU_FL_NMNotSleep_BYTE4BIT1 0;
BA_ "GenSigStartValue" SG_ 1361 VIU_FL_NMNotSleep_BYTE4BIT1 0;
BA_ "GenSigInvalidValue" SG_ 1361 VIU_FL_NMNotSleep_BYTE4BIT1 0;
BA_ "GenSigCycleTime" SG_ 1361 VIU_FL_NMNotSleep_BYTE4BIT2 1000;
BA_ "GenSigSendType" SG_ 1361 VIU_FL_NMNotSleep_BYTE4BIT2 0;
BA_ "GenSigStartValue" SG_ 1361 VIU_FL_NMNotSleep_BYTE4BIT2 0;
BA_ "GenSigInvalidValue" SG_ 1361 VIU_FL_NMNotSleep_BYTE4BIT2 0;
BA_ "GenSigCycleTime" SG_ 1361 VIU_FL_NMNotSleep_BYTE4BIT3 1000;
BA_ "GenSigSendType" SG_ 1361 VIU_FL_NMNotSleep_BYTE4BIT3 0;
BA_ "GenSigStartValue" SG_ 1361 VIU_FL_NMNotSleep_BYTE4BIT3 0;
BA_ "GenSigInvalidValue" SG_ 1361 VIU_FL_NMNotSleep_BYTE4BIT3 0;
BA_ "GenSigCycleTime" SG_ 1361 VIU_FL_NMNotSleep_BYTE4BIT4 1000;
BA_ "GenSigSendType" SG_ 1361 VIU_FL_NMNotSleep_BYTE4BIT4 0;
BA_ "GenSigStartValue" SG_ 1361 VIU_FL_NMNotSleep_BYTE4BIT4 0;
BA_ "GenSigInvalidValue" SG_ 1361 VIU_FL_NMNotSleep_BYTE4BIT4 0;
BA_ "GenSigCycleTime" SG_ 1361 VIU_FL_NMNotSleep_BYTE4BIT5 1000;
BA_ "GenSigSendType" SG_ 1361 VIU_FL_NMNotSleep_BYTE4BIT5 0;
BA_ "GenSigStartValue" SG_ 1361 VIU_FL_NMNotSleep_BYTE4BIT5 0;
BA_ "GenSigInvalidValue" SG_ 1361 VIU_FL_NMNotSleep_BYTE4BIT5 0;
BA_ "GenSigCycleTime" SG_ 1361 VIU_FL_NMNotSleep_BYTE4BIT6 1000;
BA_ "GenSigSendType" SG_ 1361 VIU_FL_NMNotSleep_BYTE4BIT6 0;
BA_ "GenSigStartValue" SG_ 1361 VIU_FL_NMNotSleep_BYTE4BIT6 0;
BA_ "GenSigInvalidValue" SG_ 1361 VIU_FL_NMNotSleep_BYTE4BIT6 0;
BA_ "GenSigCycleTime" SG_ 1361 VIU_FL_NMNotSleep_BYTE4BIT7 1000;
BA_ "GenSigSendType" SG_ 1361 VIU_FL_NMNotSleep_BYTE4BIT7 0;
BA_ "GenSigStartValue" SG_ 1361 VIU_FL_NMNotSleep_BYTE4BIT7 0;
BA_ "GenSigInvalidValue" SG_ 1361 VIU_FL_NMNotSleep_BYTE4BIT7 0;
BA_ "GenSigCycleTime" SG_ 1361 VIU_FL_NMNotSleep_BYTE5BIT0 1000;
BA_ "GenSigSendType" SG_ 1361 VIU_FL_NMNotSleep_BYTE5BIT0 0;
BA_ "GenSigStartValue" SG_ 1361 VIU_FL_NMNotSleep_BYTE5BIT0 0;
BA_ "GenSigInvalidValue" SG_ 1361 VIU_FL_NMNotSleep_BYTE5BIT0 0;
BA_ "GenSigCycleTime" SG_ 1361 VIU_FL_NMNotSleep_BYTE5BIT1 1000;
BA_ "GenSigSendType" SG_ 1361 VIU_FL_NMNotSleep_BYTE5BIT1 0;
BA_ "GenSigStartValue" SG_ 1361 VIU_FL_NMNotSleep_BYTE5BIT1 0;
BA_ "GenSigInvalidValue" SG_ 1361 VIU_FL_NMNotSleep_BYTE5BIT1 0;
BA_ "GenSigCycleTime" SG_ 1361 VIU_FL_NMNotSleep_BYTE5BIT2 1000;
BA_ "GenSigSendType" SG_ 1361 VIU_FL_NMNotSleep_BYTE5BIT2 0;
BA_ "GenSigStartValue" SG_ 1361 VIU_FL_NMNotSleep_BYTE5BIT2 0;
BA_ "GenSigInvalidValue" SG_ 1361 VIU_FL_NMNotSleep_BYTE5BIT2 0;
BA_ "GenSigCycleTime" SG_ 1361 VIU_FL_NMNotSleep_BYTE5BIT3 1000;
BA_ "GenSigSendType" SG_ 1361 VIU_FL_NMNotSleep_BYTE5BIT3 0;
BA_ "GenSigStartValue" SG_ 1361 VIU_FL_NMNotSleep_BYTE5BIT3 0;
BA_ "GenSigInvalidValue" SG_ 1361 VIU_FL_NMNotSleep_BYTE5BIT3 0;
BA_ "GenSigCycleTime" SG_ 1361 VIU_FL_NMNotSleep_BYTE5BIT4 1000;
BA_ "GenSigSendType" SG_ 1361 VIU_FL_NMNotSleep_BYTE5BIT4 0;
BA_ "GenSigStartValue" SG_ 1361 VIU_FL_NMNotSleep_BYTE5BIT4 0;
BA_ "GenSigInvalidValue" SG_ 1361 VIU_FL_NMNotSleep_BYTE5BIT4 0;
BA_ "GenSigCycleTime" SG_ 1361 VIU_FL_NMNotSleep_BYTE5BIT5 1000;
BA_ "GenSigSendType" SG_ 1361 VIU_FL_NMNotSleep_BYTE5BIT5 0;
BA_ "GenSigStartValue" SG_ 1361 VIU_FL_NMNotSleep_BYTE5BIT5 0;
BA_ "GenSigInvalidValue" SG_ 1361 VIU_FL_NMNotSleep_BYTE5BIT5 0;
BA_ "GenSigCycleTime" SG_ 1361 VIU_FL_NMNotSleep_BYTE5BIT6 1000;
BA_ "GenSigSendType" SG_ 1361 VIU_FL_NMNotSleep_BYTE5BIT6 0;
BA_ "GenSigStartValue" SG_ 1361 VIU_FL_NMNotSleep_BYTE5BIT6 0;
BA_ "GenSigInvalidValue" SG_ 1361 VIU_FL_NMNotSleep_BYTE5BIT6 0;
BA_ "GenSigCycleTime" SG_ 1361 VIU_FL_NMNotSleep_BYTE5BIT7 1000;
BA_ "GenSigSendType" SG_ 1361 VIU_FL_NMNotSleep_BYTE5BIT7 0;
BA_ "GenSigStartValue" SG_ 1361 VIU_FL_NMNotSleep_BYTE5BIT7 0;
BA_ "GenSigInvalidValue" SG_ 1361 VIU_FL_NMNotSleep_BYTE5BIT7 0;
BA_ "GenSigCycleTime" SG_ 1361 VIU_FL_NMNotSleep_BYTE6BIT0 1000;
BA_ "GenSigSendType" SG_ 1361 VIU_FL_NMNotSleep_BYTE6BIT0 0;
BA_ "GenSigStartValue" SG_ 1361 VIU_FL_NMNotSleep_BYTE6BIT0 0;
BA_ "GenSigInvalidValue" SG_ 1361 VIU_FL_NMNotSleep_BYTE6BIT0 0;
BA_ "GenSigCycleTime" SG_ 1361 VIU_FL_NMNotSleep_BYTE6BIT1 1000;
BA_ "GenSigSendType" SG_ 1361 VIU_FL_NMNotSleep_BYTE6BIT1 0;
BA_ "GenSigStartValue" SG_ 1361 VIU_FL_NMNotSleep_BYTE6BIT1 0;
BA_ "GenSigInvalidValue" SG_ 1361 VIU_FL_NMNotSleep_BYTE6BIT1 0;
BA_ "GenSigCycleTime" SG_ 1361 VIU_FL_NMNotSleep_BYTE6BIT2 1000;
BA_ "GenSigSendType" SG_ 1361 VIU_FL_NMNotSleep_BYTE6BIT2 0;
BA_ "GenSigStartValue" SG_ 1361 VIU_FL_NMNotSleep_BYTE6BIT2 0;
BA_ "GenSigInvalidValue" SG_ 1361 VIU_FL_NMNotSleep_BYTE6BIT2 0;
BA_ "GenSigCycleTime" SG_ 1361 VIU_FL_NMNotSleep_BYTE6BIT3 1000;
BA_ "GenSigSendType" SG_ 1361 VIU_FL_NMNotSleep_BYTE6BIT3 0;
BA_ "GenSigStartValue" SG_ 1361 VIU_FL_NMNotSleep_BYTE6BIT3 0;
BA_ "GenSigInvalidValue" SG_ 1361 VIU_FL_NMNotSleep_BYTE6BIT3 0;
BA_ "GenSigCycleTime" SG_ 1361 VIU_FL_NMNotSleep_BYTE6BIT4 1000;
BA_ "GenSigSendType" SG_ 1361 VIU_FL_NMNotSleep_BYTE6BIT4 0;
BA_ "GenSigStartValue" SG_ 1361 VIU_FL_NMNotSleep_BYTE6BIT4 0;
BA_ "GenSigInvalidValue" SG_ 1361 VIU_FL_NMNotSleep_BYTE6BIT4 0;
BA_ "GenSigCycleTime" SG_ 1361 VIU_FL_NMNotSleep_BYTE6BIT5 1000;
BA_ "GenSigSendType" SG_ 1361 VIU_FL_NMNotSleep_BYTE6BIT5 0;
BA_ "GenSigStartValue" SG_ 1361 VIU_FL_NMNotSleep_BYTE6BIT5 0;
BA_ "GenSigInvalidValue" SG_ 1361 VIU_FL_NMNotSleep_BYTE6BIT5 0;
BA_ "GenSigCycleTime" SG_ 1361 VIU_FL_NMNotSleep_BYTE6BIT6 1000;
BA_ "GenSigSendType" SG_ 1361 VIU_FL_NMNotSleep_BYTE6BIT6 0;
BA_ "GenSigStartValue" SG_ 1361 VIU_FL_NMNotSleep_BYTE6BIT6 0;
BA_ "GenSigInvalidValue" SG_ 1361 VIU_FL_NMNotSleep_BYTE6BIT6 0;
BA_ "GenSigCycleTime" SG_ 1361 VIU_FL_NMNotSleep_BYTE6BIT7 1000;
BA_ "GenSigSendType" SG_ 1361 VIU_FL_NMNotSleep_BYTE6BIT7 0;
BA_ "GenSigStartValue" SG_ 1361 VIU_FL_NMNotSleep_BYTE6BIT7 0;
BA_ "GenSigInvalidValue" SG_ 1361 VIU_FL_NMNotSleep_BYTE6BIT7 0;
BA_ "GenSigCycleTime" SG_ 1361 VIU_FL_NMNotSleep_BYTE7BIT0 1000;
BA_ "GenSigSendType" SG_ 1361 VIU_FL_NMNotSleep_BYTE7BIT0 0;
BA_ "GenSigStartValue" SG_ 1361 VIU_FL_NMNotSleep_BYTE7BIT0 0;
BA_ "GenSigInvalidValue" SG_ 1361 VIU_FL_NMNotSleep_BYTE7BIT0 0;
BA_ "GenSigCycleTime" SG_ 1361 VIU_FL_NMNotSleep_BYTE7BIT1 1000;
BA_ "GenSigSendType" SG_ 1361 VIU_FL_NMNotSleep_BYTE7BIT1 0;
BA_ "GenSigStartValue" SG_ 1361 VIU_FL_NMNotSleep_BYTE7BIT1 0;
BA_ "GenSigInvalidValue" SG_ 1361 VIU_FL_NMNotSleep_BYTE7BIT1 0;
BA_ "GenSigCycleTime" SG_ 1361 VIU_FL_NMNotSleep_BYTE7BIT2 1000;
BA_ "GenSigSendType" SG_ 1361 VIU_FL_NMNotSleep_BYTE7BIT2 0;
BA_ "GenSigStartValue" SG_ 1361 VIU_FL_NMNotSleep_BYTE7BIT2 0;
BA_ "GenSigInvalidValue" SG_ 1361 VIU_FL_NMNotSleep_BYTE7BIT2 0;
BA_ "GenSigCycleTime" SG_ 1361 VIU_FL_NMNotSleep_BYTE7BIT3 1000;
BA_ "GenSigSendType" SG_ 1361 VIU_FL_NMNotSleep_BYTE7BIT3 0;
BA_ "GenSigStartValue" SG_ 1361 VIU_FL_NMNotSleep_BYTE7BIT3 0;
BA_ "GenSigInvalidValue" SG_ 1361 VIU_FL_NMNotSleep_BYTE7BIT3 0;
BA_ "GenSigCycleTime" SG_ 1361 VIU_FL_NMNotSleep_BYTE7BIT4 1000;
BA_ "GenSigSendType" SG_ 1361 VIU_FL_NMNotSleep_BYTE7BIT4 0;
BA_ "GenSigStartValue" SG_ 1361 VIU_FL_NMNotSleep_BYTE7BIT4 0;
BA_ "GenSigInvalidValue" SG_ 1361 VIU_FL_NMNotSleep_BYTE7BIT4 0;
BA_ "GenSigCycleTime" SG_ 1361 VIU_FL_NMNotSleep_BYTE7BIT5 1000;
BA_ "GenSigSendType" SG_ 1361 VIU_FL_NMNotSleep_BYTE7BIT5 0;
BA_ "GenSigStartValue" SG_ 1361 VIU_FL_NMNotSleep_BYTE7BIT5 0;
BA_ "GenSigInvalidValue" SG_ 1361 VIU_FL_NMNotSleep_BYTE7BIT5 0;
BA_ "GenSigCycleTime" SG_ 1361 VIU_FL_NMNotSleep_BYTE7BIT6 1000;
BA_ "GenSigSendType" SG_ 1361 VIU_FL_NMNotSleep_BYTE7BIT6 0;
BA_ "GenSigStartValue" SG_ 1361 VIU_FL_NMNotSleep_BYTE7BIT6 0;
BA_ "GenSigInvalidValue" SG_ 1361 VIU_FL_NMNotSleep_BYTE7BIT6 0;
BA_ "GenSigCycleTime" SG_ 1361 VIU_FL_NMNotSleep_BYTE7BIT7 1000;
BA_ "GenSigSendType" SG_ 1361 VIU_FL_NMNotSleep_BYTE7BIT7 0;
BA_ "GenSigStartValue" SG_ 1361 VIU_FL_NMNotSleep_BYTE7BIT7 0;
BA_ "GenSigInvalidValue" SG_ 1361 VIU_FL_NMNotSleep_BYTE7BIT7 0;
BA_ "GenSigCycleTime" SG_ 1361 VIU_FL_NMWakeUp 1000;
BA_ "GenSigSendType" SG_ 1361 VIU_FL_NMWakeUp 0;
BA_ "GenSigStartValue" SG_ 1361 VIU_FL_NMWakeUp 0;
BA_ "GenSigInvalidValue" SG_ 1361 VIU_FL_NMWakeUp 0;
BA_ "GenSigCycleTime" SG_ 1369 VIU_FR_NMNotSleep_BYTE2BIT0 1000;
BA_ "GenSigSendType" SG_ 1369 VIU_FR_NMNotSleep_BYTE2BIT0 0;
BA_ "GenSigStartValue" SG_ 1369 VIU_FR_NMNotSleep_BYTE2BIT0 0;
BA_ "GenSigInvalidValue" SG_ 1369 VIU_FR_NMNotSleep_BYTE2BIT0 0;
BA_ "GenSigCycleTime" SG_ 1369 VIU_FR_NMNotSleep_BYTE2BIT1 1000;
BA_ "GenSigSendType" SG_ 1369 VIU_FR_NMNotSleep_BYTE2BIT1 0;
BA_ "GenSigStartValue" SG_ 1369 VIU_FR_NMNotSleep_BYTE2BIT1 0;
BA_ "GenSigInvalidValue" SG_ 1369 VIU_FR_NMNotSleep_BYTE2BIT1 0;
BA_ "GenSigCycleTime" SG_ 1369 VIU_FR_NMNotSleep_BYTE2BIT2 1000;
BA_ "GenSigSendType" SG_ 1369 VIU_FR_NMNotSleep_BYTE2BIT2 0;
BA_ "GenSigStartValue" SG_ 1369 VIU_FR_NMNotSleep_BYTE2BIT2 0;
BA_ "GenSigInvalidValue" SG_ 1369 VIU_FR_NMNotSleep_BYTE2BIT2 0;
BA_ "GenSigCycleTime" SG_ 1369 VIU_FR_NMNotSleep_BYTE2BIT3 1000;
BA_ "GenSigSendType" SG_ 1369 VIU_FR_NMNotSleep_BYTE2BIT3 0;
BA_ "GenSigStartValue" SG_ 1369 VIU_FR_NMNotSleep_BYTE2BIT3 0;
BA_ "GenSigInvalidValue" SG_ 1369 VIU_FR_NMNotSleep_BYTE2BIT3 0;
BA_ "GenSigCycleTime" SG_ 1369 VIU_FR_NMNotSleep_BYTE2BIT4 1000;
BA_ "GenSigSendType" SG_ 1369 VIU_FR_NMNotSleep_BYTE2BIT4 0;
BA_ "GenSigStartValue" SG_ 1369 VIU_FR_NMNotSleep_BYTE2BIT4 0;
BA_ "GenSigInvalidValue" SG_ 1369 VIU_FR_NMNotSleep_BYTE2BIT4 0;
BA_ "GenSigCycleTime" SG_ 1369 VIU_FR_NMNotSleep_BYTE2BIT5 1000;
BA_ "GenSigSendType" SG_ 1369 VIU_FR_NMNotSleep_BYTE2BIT5 0;
BA_ "GenSigStartValue" SG_ 1369 VIU_FR_NMNotSleep_BYTE2BIT5 0;
BA_ "GenSigInvalidValue" SG_ 1369 VIU_FR_NMNotSleep_BYTE2BIT5 0;
BA_ "GenSigCycleTime" SG_ 1369 VIU_FR_NMNotSleep_BYTE2BIT6 1000;
BA_ "GenSigSendType" SG_ 1369 VIU_FR_NMNotSleep_BYTE2BIT6 0;
BA_ "GenSigStartValue" SG_ 1369 VIU_FR_NMNotSleep_BYTE2BIT6 0;
BA_ "GenSigInvalidValue" SG_ 1369 VIU_FR_NMNotSleep_BYTE2BIT6 0;
BA_ "GenSigCycleTime" SG_ 1369 VIU_FR_NMNotSleep_BYTE2BIT7 1000;
BA_ "GenSigSendType" SG_ 1369 VIU_FR_NMNotSleep_BYTE2BIT7 0;
BA_ "GenSigStartValue" SG_ 1369 VIU_FR_NMNotSleep_BYTE2BIT7 0;
BA_ "GenSigInvalidValue" SG_ 1369 VIU_FR_NMNotSleep_BYTE2BIT7 0;
BA_ "GenSigCycleTime" SG_ 1369 VIU_FR_NMNotSleep_BYTE3BIT0 1000;
BA_ "GenSigSendType" SG_ 1369 VIU_FR_NMNotSleep_BYTE3BIT0 0;
BA_ "GenSigStartValue" SG_ 1369 VIU_FR_NMNotSleep_BYTE3BIT0 0;
BA_ "GenSigInvalidValue" SG_ 1369 VIU_FR_NMNotSleep_BYTE3BIT0 0;
BA_ "GenSigCycleTime" SG_ 1369 VIU_FR_NMNotSleep_BYTE3BIT1 1000;
BA_ "GenSigSendType" SG_ 1369 VIU_FR_NMNotSleep_BYTE3BIT1 0;
BA_ "GenSigStartValue" SG_ 1369 VIU_FR_NMNotSleep_BYTE3BIT1 0;
BA_ "GenSigInvalidValue" SG_ 1369 VIU_FR_NMNotSleep_BYTE3BIT1 0;
BA_ "GenSigCycleTime" SG_ 1369 VIU_FR_NMNotSleep_BYTE3BIT2 1000;
BA_ "GenSigSendType" SG_ 1369 VIU_FR_NMNotSleep_BYTE3BIT2 0;
BA_ "GenSigStartValue" SG_ 1369 VIU_FR_NMNotSleep_BYTE3BIT2 0;
BA_ "GenSigInvalidValue" SG_ 1369 VIU_FR_NMNotSleep_BYTE3BIT2 0;
BA_ "GenSigCycleTime" SG_ 1369 VIU_FR_NMNotSleep_BYTE3BIT3 1000;
BA_ "GenSigSendType" SG_ 1369 VIU_FR_NMNotSleep_BYTE3BIT3 0;
BA_ "GenSigStartValue" SG_ 1369 VIU_FR_NMNotSleep_BYTE3BIT3 0;
BA_ "GenSigInvalidValue" SG_ 1369 VIU_FR_NMNotSleep_BYTE3BIT3 0;
BA_ "GenSigCycleTime" SG_ 1369 VIU_FR_NMNotSleep_BYTE3BIT4 1000;
BA_ "GenSigSendType" SG_ 1369 VIU_FR_NMNotSleep_BYTE3BIT4 0;
BA_ "GenSigStartValue" SG_ 1369 VIU_FR_NMNotSleep_BYTE3BIT4 0;
BA_ "GenSigInvalidValue" SG_ 1369 VIU_FR_NMNotSleep_BYTE3BIT4 0;
BA_ "GenSigCycleTime" SG_ 1369 VIU_FR_NMNotSleep_BYTE3BIT5 1000;
BA_ "GenSigSendType" SG_ 1369 VIU_FR_NMNotSleep_BYTE3BIT5 0;
BA_ "GenSigStartValue" SG_ 1369 VIU_FR_NMNotSleep_BYTE3BIT5 0;
BA_ "GenSigInvalidValue" SG_ 1369 VIU_FR_NMNotSleep_BYTE3BIT5 0;
BA_ "GenSigCycleTime" SG_ 1369 VIU_FR_NMNotSleep_BYTE3BIT6 1000;
BA_ "GenSigSendType" SG_ 1369 VIU_FR_NMNotSleep_BYTE3BIT6 0;
BA_ "GenSigStartValue" SG_ 1369 VIU_FR_NMNotSleep_BYTE3BIT6 0;
BA_ "GenSigInvalidValue" SG_ 1369 VIU_FR_NMNotSleep_BYTE3BIT6 0;
BA_ "GenSigCycleTime" SG_ 1369 VIU_FR_NMNotSleep_BYTE3BIT7 1000;
BA_ "GenSigSendType" SG_ 1369 VIU_FR_NMNotSleep_BYTE3BIT7 0;
BA_ "GenSigStartValue" SG_ 1369 VIU_FR_NMNotSleep_BYTE3BIT7 0;
BA_ "GenSigInvalidValue" SG_ 1369 VIU_FR_NMNotSleep_BYTE3BIT7 0;
BA_ "GenSigCycleTime" SG_ 1369 VIU_FR_NMNotSleep_BYTE4BIT0 1000;
BA_ "GenSigSendType" SG_ 1369 VIU_FR_NMNotSleep_BYTE4BIT0 0;
BA_ "GenSigStartValue" SG_ 1369 VIU_FR_NMNotSleep_BYTE4BIT0 0;
BA_ "GenSigInvalidValue" SG_ 1369 VIU_FR_NMNotSleep_BYTE4BIT0 0;
BA_ "GenSigCycleTime" SG_ 1369 VIU_FR_NMNotSleep_BYTE4BIT1 1000;
BA_ "GenSigSendType" SG_ 1369 VIU_FR_NMNotSleep_BYTE4BIT1 0;
BA_ "GenSigStartValue" SG_ 1369 VIU_FR_NMNotSleep_BYTE4BIT1 0;
BA_ "GenSigInvalidValue" SG_ 1369 VIU_FR_NMNotSleep_BYTE4BIT1 0;
BA_ "GenSigCycleTime" SG_ 1369 VIU_FR_NMNotSleep_BYTE4BIT2 1000;
BA_ "GenSigSendType" SG_ 1369 VIU_FR_NMNotSleep_BYTE4BIT2 0;
BA_ "GenSigStartValue" SG_ 1369 VIU_FR_NMNotSleep_BYTE4BIT2 0;
BA_ "GenSigInvalidValue" SG_ 1369 VIU_FR_NMNotSleep_BYTE4BIT2 0;
BA_ "GenSigCycleTime" SG_ 1369 VIU_FR_NMNotSleep_BYTE4BIT3 1000;
BA_ "GenSigSendType" SG_ 1369 VIU_FR_NMNotSleep_BYTE4BIT3 0;
BA_ "GenSigStartValue" SG_ 1369 VIU_FR_NMNotSleep_BYTE4BIT3 0;
BA_ "GenSigInvalidValue" SG_ 1369 VIU_FR_NMNotSleep_BYTE4BIT3 0;
BA_ "GenSigCycleTime" SG_ 1369 VIU_FR_NMNotSleep_BYTE4BIT4 1000;
BA_ "GenSigSendType" SG_ 1369 VIU_FR_NMNotSleep_BYTE4BIT4 0;
BA_ "GenSigStartValue" SG_ 1369 VIU_FR_NMNotSleep_BYTE4BIT4 0;
BA_ "GenSigInvalidValue" SG_ 1369 VIU_FR_NMNotSleep_BYTE4BIT4 0;
BA_ "GenSigCycleTime" SG_ 1369 VIU_FR_NMNotSleep_BYTE4BIT5 1000;
BA_ "GenSigSendType" SG_ 1369 VIU_FR_NMNotSleep_BYTE4BIT5 0;
BA_ "GenSigStartValue" SG_ 1369 VIU_FR_NMNotSleep_BYTE4BIT5 0;
BA_ "GenSigInvalidValue" SG_ 1369 VIU_FR_NMNotSleep_BYTE4BIT5 0;
BA_ "GenSigCycleTime" SG_ 1369 VIU_FR_NMNotSleep_BYTE4BIT6 1000;
BA_ "GenSigSendType" SG_ 1369 VIU_FR_NMNotSleep_BYTE4BIT6 0;
BA_ "GenSigStartValue" SG_ 1369 VIU_FR_NMNotSleep_BYTE4BIT6 0;
BA_ "GenSigInvalidValue" SG_ 1369 VIU_FR_NMNotSleep_BYTE4BIT6 0;
BA_ "GenSigCycleTime" SG_ 1369 VIU_FR_NMNotSleep_BYTE4BIT7 1000;
BA_ "GenSigSendType" SG_ 1369 VIU_FR_NMNotSleep_BYTE4BIT7 0;
BA_ "GenSigStartValue" SG_ 1369 VIU_FR_NMNotSleep_BYTE4BIT7 0;
BA_ "GenSigInvalidValue" SG_ 1369 VIU_FR_NMNotSleep_BYTE4BIT7 0;
BA_ "GenSigCycleTime" SG_ 1369 VIU_FR_NMNotSleep_BYTE5BIT0 1000;
BA_ "GenSigSendType" SG_ 1369 VIU_FR_NMNotSleep_BYTE5BIT0 0;
BA_ "GenSigStartValue" SG_ 1369 VIU_FR_NMNotSleep_BYTE5BIT0 0;
BA_ "GenSigInvalidValue" SG_ 1369 VIU_FR_NMNotSleep_BYTE5BIT0 0;
BA_ "GenSigCycleTime" SG_ 1369 VIU_FR_NMNotSleep_BYTE5BIT1 1000;
BA_ "GenSigSendType" SG_ 1369 VIU_FR_NMNotSleep_BYTE5BIT1 0;
BA_ "GenSigStartValue" SG_ 1369 VIU_FR_NMNotSleep_BYTE5BIT1 0;
BA_ "GenSigInvalidValue" SG_ 1369 VIU_FR_NMNotSleep_BYTE5BIT1 0;
BA_ "GenSigCycleTime" SG_ 1369 VIU_FR_NMNotSleep_BYTE5BIT2 1000;
BA_ "GenSigSendType" SG_ 1369 VIU_FR_NMNotSleep_BYTE5BIT2 0;
BA_ "GenSigStartValue" SG_ 1369 VIU_FR_NMNotSleep_BYTE5BIT2 0;
BA_ "GenSigInvalidValue" SG_ 1369 VIU_FR_NMNotSleep_BYTE5BIT2 0;
BA_ "GenSigCycleTime" SG_ 1369 VIU_FR_NMNotSleep_BYTE5BIT3 1000;
BA_ "GenSigSendType" SG_ 1369 VIU_FR_NMNotSleep_BYTE5BIT3 0;
BA_ "GenSigStartValue" SG_ 1369 VIU_FR_NMNotSleep_BYTE5BIT3 0;
BA_ "GenSigInvalidValue" SG_ 1369 VIU_FR_NMNotSleep_BYTE5BIT3 0;
BA_ "GenSigCycleTime" SG_ 1369 VIU_FR_NMNotSleep_BYTE5BIT4 1000;
BA_ "GenSigSendType" SG_ 1369 VIU_FR_NMNotSleep_BYTE5BIT4 0;
BA_ "GenSigStartValue" SG_ 1369 VIU_FR_NMNotSleep_BYTE5BIT4 0;
BA_ "GenSigInvalidValue" SG_ 1369 VIU_FR_NMNotSleep_BYTE5BIT4 0;
BA_ "GenSigCycleTime" SG_ 1369 VIU_FR_NMNotSleep_BYTE5BIT5 1000;
BA_ "GenSigSendType" SG_ 1369 VIU_FR_NMNotSleep_BYTE5BIT5 0;
BA_ "GenSigStartValue" SG_ 1369 VIU_FR_NMNotSleep_BYTE5BIT5 0;
BA_ "GenSigInvalidValue" SG_ 1369 VIU_FR_NMNotSleep_BYTE5BIT5 0;
BA_ "GenSigCycleTime" SG_ 1369 VIU_FR_NMNotSleep_BYTE5BIT6 1000;
BA_ "GenSigSendType" SG_ 1369 VIU_FR_NMNotSleep_BYTE5BIT6 0;
BA_ "GenSigStartValue" SG_ 1369 VIU_FR_NMNotSleep_BYTE5BIT6 0;
BA_ "GenSigInvalidValue" SG_ 1369 VIU_FR_NMNotSleep_BYTE5BIT6 0;
BA_ "GenSigCycleTime" SG_ 1369 VIU_FR_NMNotSleep_BYTE5BIT7 1000;
BA_ "GenSigSendType" SG_ 1369 VIU_FR_NMNotSleep_BYTE5BIT7 0;
BA_ "GenSigStartValue" SG_ 1369 VIU_FR_NMNotSleep_BYTE5BIT7 0;
BA_ "GenSigInvalidValue" SG_ 1369 VIU_FR_NMNotSleep_BYTE5BIT7 0;
BA_ "GenSigCycleTime" SG_ 1369 VIU_FR_NMNotSleep_BYTE6BIT0 1000;
BA_ "GenSigSendType" SG_ 1369 VIU_FR_NMNotSleep_BYTE6BIT0 0;
BA_ "GenSigStartValue" SG_ 1369 VIU_FR_NMNotSleep_BYTE6BIT0 0;
BA_ "GenSigInvalidValue" SG_ 1369 VIU_FR_NMNotSleep_BYTE6BIT0 0;
BA_ "GenSigCycleTime" SG_ 1369 VIU_FR_NMNotSleep_BYTE6BIT1 1000;
BA_ "GenSigSendType" SG_ 1369 VIU_FR_NMNotSleep_BYTE6BIT1 0;
BA_ "GenSigStartValue" SG_ 1369 VIU_FR_NMNotSleep_BYTE6BIT1 0;
BA_ "GenSigInvalidValue" SG_ 1369 VIU_FR_NMNotSleep_BYTE6BIT1 0;
BA_ "GenSigCycleTime" SG_ 1369 VIU_FR_NMNotSleep_BYTE6BIT2 1000;
BA_ "GenSigSendType" SG_ 1369 VIU_FR_NMNotSleep_BYTE6BIT2 0;
BA_ "GenSigStartValue" SG_ 1369 VIU_FR_NMNotSleep_BYTE6BIT2 0;
BA_ "GenSigInvalidValue" SG_ 1369 VIU_FR_NMNotSleep_BYTE6BIT2 0;
BA_ "GenSigCycleTime" SG_ 1369 VIU_FR_NMNotSleep_BYTE6BIT3 1000;
BA_ "GenSigSendType" SG_ 1369 VIU_FR_NMNotSleep_BYTE6BIT3 0;
BA_ "GenSigStartValue" SG_ 1369 VIU_FR_NMNotSleep_BYTE6BIT3 0;
BA_ "GenSigInvalidValue" SG_ 1369 VIU_FR_NMNotSleep_BYTE6BIT3 0;
BA_ "GenSigCycleTime" SG_ 1369 VIU_FR_NMNotSleep_BYTE6BIT4 1000;
BA_ "GenSigSendType" SG_ 1369 VIU_FR_NMNotSleep_BYTE6BIT4 0;
BA_ "GenSigStartValue" SG_ 1369 VIU_FR_NMNotSleep_BYTE6BIT4 0;
BA_ "GenSigInvalidValue" SG_ 1369 VIU_FR_NMNotSleep_BYTE6BIT4 0;
BA_ "GenSigCycleTime" SG_ 1369 VIU_FR_NMNotSleep_BYTE6BIT5 1000;
BA_ "GenSigSendType" SG_ 1369 VIU_FR_NMNotSleep_BYTE6BIT5 0;
BA_ "GenSigStartValue" SG_ 1369 VIU_FR_NMNotSleep_BYTE6BIT5 0;
BA_ "GenSigInvalidValue" SG_ 1369 VIU_FR_NMNotSleep_BYTE6BIT5 0;
BA_ "GenSigCycleTime" SG_ 1369 VIU_FR_NMNotSleep_BYTE6BIT6 1000;
BA_ "GenSigSendType" SG_ 1369 VIU_FR_NMNotSleep_BYTE6BIT6 0;
BA_ "GenSigStartValue" SG_ 1369 VIU_FR_NMNotSleep_BYTE6BIT6 0;
BA_ "GenSigInvalidValue" SG_ 1369 VIU_FR_NMNotSleep_BYTE6BIT6 0;
BA_ "GenSigCycleTime" SG_ 1369 VIU_FR_NMNotSleep_BYTE6BIT7 1000;
BA_ "GenSigSendType" SG_ 1369 VIU_FR_NMNotSleep_BYTE6BIT7 0;
BA_ "GenSigStartValue" SG_ 1369 VIU_FR_NMNotSleep_BYTE6BIT7 0;
BA_ "GenSigInvalidValue" SG_ 1369 VIU_FR_NMNotSleep_BYTE6BIT7 0;
BA_ "GenSigCycleTime" SG_ 1369 VIU_FR_NMNotSleep_BYTE7BIT0 1000;
BA_ "GenSigSendType" SG_ 1369 VIU_FR_NMNotSleep_BYTE7BIT0 0;
BA_ "GenSigStartValue" SG_ 1369 VIU_FR_NMNotSleep_BYTE7BIT0 0;
BA_ "GenSigInvalidValue" SG_ 1369 VIU_FR_NMNotSleep_BYTE7BIT0 0;
BA_ "GenSigCycleTime" SG_ 1369 VIU_FR_NMNotSleep_BYTE7BIT1 1000;
BA_ "GenSigSendType" SG_ 1369 VIU_FR_NMNotSleep_BYTE7BIT1 0;
BA_ "GenSigStartValue" SG_ 1369 VIU_FR_NMNotSleep_BYTE7BIT1 0;
BA_ "GenSigInvalidValue" SG_ 1369 VIU_FR_NMNotSleep_BYTE7BIT1 0;
BA_ "GenSigCycleTime" SG_ 1369 VIU_FR_NMNotSleep_BYTE7BIT2 1000;
BA_ "GenSigSendType" SG_ 1369 VIU_FR_NMNotSleep_BYTE7BIT2 0;
BA_ "GenSigStartValue" SG_ 1369 VIU_FR_NMNotSleep_BYTE7BIT2 0;
BA_ "GenSigInvalidValue" SG_ 1369 VIU_FR_NMNotSleep_BYTE7BIT2 0;
BA_ "GenSigCycleTime" SG_ 1369 VIU_FR_NMNotSleep_BYTE7BIT3 1000;
BA_ "GenSigSendType" SG_ 1369 VIU_FR_NMNotSleep_BYTE7BIT3 0;
BA_ "GenSigStartValue" SG_ 1369 VIU_FR_NMNotSleep_BYTE7BIT3 0;
BA_ "GenSigInvalidValue" SG_ 1369 VIU_FR_NMNotSleep_BYTE7BIT3 0;
BA_ "GenSigCycleTime" SG_ 1369 VIU_FR_NMNotSleep_BYTE7BIT4 1000;
BA_ "GenSigSendType" SG_ 1369 VIU_FR_NMNotSleep_BYTE7BIT4 0;
BA_ "GenSigStartValue" SG_ 1369 VIU_FR_NMNotSleep_BYTE7BIT4 0;
BA_ "GenSigInvalidValue" SG_ 1369 VIU_FR_NMNotSleep_BYTE7BIT4 0;
BA_ "GenSigCycleTime" SG_ 1369 VIU_FR_NMNotSleep_BYTE7BIT5 1000;
BA_ "GenSigSendType" SG_ 1369 VIU_FR_NMNotSleep_BYTE7BIT5 0;
BA_ "GenSigStartValue" SG_ 1369 VIU_FR_NMNotSleep_BYTE7BIT5 0;
BA_ "GenSigInvalidValue" SG_ 1369 VIU_FR_NMNotSleep_BYTE7BIT5 0;
BA_ "GenSigCycleTime" SG_ 1369 VIU_FR_NMNotSleep_BYTE7BIT6 1000;
BA_ "GenSigSendType" SG_ 1369 VIU_FR_NMNotSleep_BYTE7BIT6 0;
BA_ "GenSigStartValue" SG_ 1369 VIU_FR_NMNotSleep_BYTE7BIT6 0;
BA_ "GenSigInvalidValue" SG_ 1369 VIU_FR_NMNotSleep_BYTE7BIT6 0;
BA_ "GenSigCycleTime" SG_ 1369 VIU_FR_NMNotSleep_BYTE7BIT7 1000;
BA_ "GenSigSendType" SG_ 1369 VIU_FR_NMNotSleep_BYTE7BIT7 0;
BA_ "GenSigStartValue" SG_ 1369 VIU_FR_NMNotSleep_BYTE7BIT7 0;
BA_ "GenSigInvalidValue" SG_ 1369 VIU_FR_NMNotSleep_BYTE7BIT7 0;
BA_ "GenSigCycleTime" SG_ 1369 VIU_FR_NMWakeUp 1000;
BA_ "GenSigSendType" SG_ 1369 VIU_FR_NMWakeUp 0;
BA_ "GenSigStartValue" SG_ 1369 VIU_FR_NMWakeUp 0;
BA_ "GenSigInvalidValue" SG_ 1369 VIU_FR_NMWakeUp 0;
BA_ "GenSigCycleTime" SG_ 1396 EDC_NotSleep_Android 1000;
BA_ "GenSigSendType" SG_ 1396 EDC_NotSleep_Android 0;
BA_ "GenSigStartValue" SG_ 1396 EDC_NotSleep_Android 0;
BA_ "GenSigInvalidValue" SG_ 1396 EDC_NotSleep_Android 0;
BA_ "GenSigCycleTime" SG_ 1396 EDC_NotSleep_Android_other 1000;
BA_ "GenSigSendType" SG_ 1396 EDC_NotSleep_Android_other 0;
BA_ "GenSigStartValue" SG_ 1396 EDC_NotSleep_Android_other 0;
BA_ "GenSigInvalidValue" SG_ 1396 EDC_NotSleep_Android_other 0;
BA_ "GenSigCycleTime" SG_ 1396 EDC_NotSleep_BYTE5BIT0 1000;
BA_ "GenSigSendType" SG_ 1396 EDC_NotSleep_BYTE5BIT0 0;
BA_ "GenSigStartValue" SG_ 1396 EDC_NotSleep_BYTE5BIT0 0;
BA_ "GenSigInvalidValue" SG_ 1396 EDC_NotSleep_BYTE5BIT0 0;
BA_ "GenSigCycleTime" SG_ 1396 EDC_NotSleep_BYTE6BIT0 1000;
BA_ "GenSigSendType" SG_ 1396 EDC_NotSleep_BYTE6BIT0 0;
BA_ "GenSigStartValue" SG_ 1396 EDC_NotSleep_BYTE6BIT0 0;
BA_ "GenSigInvalidValue" SG_ 1396 EDC_NotSleep_BYTE6BIT0 0;
BA_ "GenSigCycleTime" SG_ 1396 EDC_NotSleep_BYTE6BIT1 1000;
BA_ "GenSigSendType" SG_ 1396 EDC_NotSleep_BYTE6BIT1 0;
BA_ "GenSigStartValue" SG_ 1396 EDC_NotSleep_BYTE6BIT1 0;
BA_ "GenSigInvalidValue" SG_ 1396 EDC_NotSleep_BYTE6BIT1 0;
BA_ "GenSigCycleTime" SG_ 1396 EDC_NotSleep_BYTE6BIT2 1000;
BA_ "GenSigSendType" SG_ 1396 EDC_NotSleep_BYTE6BIT2 0;
BA_ "GenSigStartValue" SG_ 1396 EDC_NotSleep_BYTE6BIT2 0;
BA_ "GenSigInvalidValue" SG_ 1396 EDC_NotSleep_BYTE6BIT2 0;
BA_ "GenSigCycleTime" SG_ 1396 EDC_NotSleep_BYTE6BIT3 1000;
BA_ "GenSigSendType" SG_ 1396 EDC_NotSleep_BYTE6BIT3 0;
BA_ "GenSigStartValue" SG_ 1396 EDC_NotSleep_BYTE6BIT3 0;
BA_ "GenSigInvalidValue" SG_ 1396 EDC_NotSleep_BYTE6BIT3 0;
BA_ "GenSigCycleTime" SG_ 1396 EDC_NotSleep_BYTE6BIT4 1000;
BA_ "GenSigSendType" SG_ 1396 EDC_NotSleep_BYTE6BIT4 0;
BA_ "GenSigStartValue" SG_ 1396 EDC_NotSleep_BYTE6BIT4 0;
BA_ "GenSigInvalidValue" SG_ 1396 EDC_NotSleep_BYTE6BIT4 0;
BA_ "GenSigCycleTime" SG_ 1396 EDC_NotSleep_BYTE7BIT0 1000;
BA_ "GenSigSendType" SG_ 1396 EDC_NotSleep_BYTE7BIT0 0;
BA_ "GenSigStartValue" SG_ 1396 EDC_NotSleep_BYTE7BIT0 0;
BA_ "GenSigInvalidValue" SG_ 1396 EDC_NotSleep_BYTE7BIT0 0;
BA_ "GenSigCycleTime" SG_ 1396 EDC_NotSleep_BYTE7BIT1 1000;
BA_ "GenSigSendType" SG_ 1396 EDC_NotSleep_BYTE7BIT1 0;
BA_ "GenSigStartValue" SG_ 1396 EDC_NotSleep_BYTE7BIT1 0;
BA_ "GenSigInvalidValue" SG_ 1396 EDC_NotSleep_BYTE7BIT1 0;
BA_ "GenSigCycleTime" SG_ 1396 EDC_NotSleep_BYTE7BIT2 1000;
BA_ "GenSigSendType" SG_ 1396 EDC_NotSleep_BYTE7BIT2 0;
BA_ "GenSigStartValue" SG_ 1396 EDC_NotSleep_BYTE7BIT2 0;
BA_ "GenSigInvalidValue" SG_ 1396 EDC_NotSleep_BYTE7BIT2 0;
BA_ "GenSigCycleTime" SG_ 1396 EDC_NotSleep_BYTE7BIT3 1000;
BA_ "GenSigSendType" SG_ 1396 EDC_NotSleep_BYTE7BIT3 0;
BA_ "GenSigStartValue" SG_ 1396 EDC_NotSleep_BYTE7BIT3 0;
BA_ "GenSigInvalidValue" SG_ 1396 EDC_NotSleep_BYTE7BIT3 0;
BA_ "GenSigCycleTime" SG_ 1396 EDC_NotSleep_BYTE7BIT4 1000;
BA_ "GenSigSendType" SG_ 1396 EDC_NotSleep_BYTE7BIT4 0;
BA_ "GenSigStartValue" SG_ 1396 EDC_NotSleep_BYTE7BIT4 0;
BA_ "GenSigInvalidValue" SG_ 1396 EDC_NotSleep_BYTE7BIT4 0;
BA_ "GenSigCycleTime" SG_ 1396 EDC_NotSleep_BYTE7BIT5 1000;
BA_ "GenSigSendType" SG_ 1396 EDC_NotSleep_BYTE7BIT5 0;
BA_ "GenSigStartValue" SG_ 1396 EDC_NotSleep_BYTE7BIT5 0;
BA_ "GenSigInvalidValue" SG_ 1396 EDC_NotSleep_BYTE7BIT5 0;
BA_ "GenSigCycleTime" SG_ 1396 EDC_NotSleep_BYTE7BIT6 1000;
BA_ "GenSigSendType" SG_ 1396 EDC_NotSleep_BYTE7BIT6 0;
BA_ "GenSigStartValue" SG_ 1396 EDC_NotSleep_BYTE7BIT6 0;
BA_ "GenSigInvalidValue" SG_ 1396 EDC_NotSleep_BYTE7BIT6 0;
BA_ "GenSigCycleTime" SG_ 1396 EDC_NotSleep_BYTE7BIT7 1000;
BA_ "GenSigSendType" SG_ 1396 EDC_NotSleep_BYTE7BIT7 0;
BA_ "GenSigStartValue" SG_ 1396 EDC_NotSleep_BYTE7BIT7 0;
BA_ "GenSigInvalidValue" SG_ 1396 EDC_NotSleep_BYTE7BIT7 0;
BA_ "GenSigCycleTime" SG_ 1396 EDC_wakeup_BYTE2BIT0 1000;
BA_ "GenSigSendType" SG_ 1396 EDC_wakeup_BYTE2BIT0 0;
BA_ "GenSigStartValue" SG_ 1396 EDC_wakeup_BYTE2BIT0 0;
BA_ "GenSigInvalidValue" SG_ 1396 EDC_wakeup_BYTE2BIT0 0;
BA_ "GenSigCycleTime" SG_ 1396 EDC_wakeup_BYTE2BIT1 1000;
BA_ "GenSigSendType" SG_ 1396 EDC_wakeup_BYTE2BIT1 0;
BA_ "GenSigStartValue" SG_ 1396 EDC_wakeup_BYTE2BIT1 0;
BA_ "GenSigInvalidValue" SG_ 1396 EDC_wakeup_BYTE2BIT1 0;
BA_ "GenSigCycleTime" SG_ 1396 EDC_wakeup_BYTE2BIT2 1000;
BA_ "GenSigSendType" SG_ 1396 EDC_wakeup_BYTE2BIT2 0;
BA_ "GenSigStartValue" SG_ 1396 EDC_wakeup_BYTE2BIT2 0;
BA_ "GenSigInvalidValue" SG_ 1396 EDC_wakeup_BYTE2BIT2 0;
BA_ "GenSigCycleTime" SG_ 1396 EDC_wakeup_BYTE2BIT3 1000;
BA_ "GenSigSendType" SG_ 1396 EDC_wakeup_BYTE2BIT3 0;
BA_ "GenSigStartValue" SG_ 1396 EDC_wakeup_BYTE2BIT3 0;
BA_ "GenSigInvalidValue" SG_ 1396 EDC_wakeup_BYTE2BIT3 0;
BA_ "GenSigCycleTime" SG_ 1396 EDC_WakeUp_BYTE3BIT0 1000;
BA_ "GenSigSendType" SG_ 1396 EDC_WakeUp_BYTE3BIT0 0;
BA_ "GenSigStartValue" SG_ 1396 EDC_WakeUp_BYTE3BIT0 0;
BA_ "GenSigInvalidValue" SG_ 1396 EDC_WakeUp_BYTE3BIT0 0;
BA_ "GenSigCycleTime" SG_ 1396 EDC_WakeUp_BYTE3BIT1 1000;
BA_ "GenSigSendType" SG_ 1396 EDC_WakeUp_BYTE3BIT1 0;
BA_ "GenSigStartValue" SG_ 1396 EDC_WakeUp_BYTE3BIT1 0;
BA_ "GenSigInvalidValue" SG_ 1396 EDC_WakeUp_BYTE3BIT1 0;
BA_ "GenSigCycleTime" SG_ 1396 EDC_WakeUp_BYTE3BIT2 1000;
BA_ "GenSigSendType" SG_ 1396 EDC_WakeUp_BYTE3BIT2 0;
BA_ "GenSigStartValue" SG_ 1396 EDC_WakeUp_BYTE3BIT2 0;
BA_ "GenSigInvalidValue" SG_ 1396 EDC_WakeUp_BYTE3BIT2 0;
BA_ "GenSigCycleTime" SG_ 1396 EDC_WakeUp_BYTE3BIT3 1000;
BA_ "GenSigSendType" SG_ 1396 EDC_WakeUp_BYTE3BIT3 0;
BA_ "GenSigStartValue" SG_ 1396 EDC_WakeUp_BYTE3BIT3 0;
BA_ "GenSigInvalidValue" SG_ 1396 EDC_WakeUp_BYTE3BIT3 0;
BA_ "GenSigCycleTime" SG_ 1396 EDC_WakeUp_BYTE3BIT4 1000;
BA_ "GenSigSendType" SG_ 1396 EDC_WakeUp_BYTE3BIT4 0;
BA_ "GenSigStartValue" SG_ 1396 EDC_WakeUp_BYTE3BIT4 0;
BA_ "GenSigInvalidValue" SG_ 1396 EDC_WakeUp_BYTE3BIT4 0;
BA_ "GenSigCycleTime" SG_ 1396 EDC_WakeUp_BYTE3BIT5 1000;
BA_ "GenSigSendType" SG_ 1396 EDC_WakeUp_BYTE3BIT5 0;
BA_ "GenSigStartValue" SG_ 1396 EDC_WakeUp_BYTE3BIT5 0;
BA_ "GenSigInvalidValue" SG_ 1396 EDC_WakeUp_BYTE3BIT5 0;
BA_ "GenSigCycleTime" SG_ 1396 EDC_WakeUp_BYTE3BIT6 1000;
BA_ "GenSigSendType" SG_ 1396 EDC_WakeUp_BYTE3BIT6 0;
BA_ "GenSigStartValue" SG_ 1396 EDC_WakeUp_BYTE3BIT6 0;
BA_ "GenSigInvalidValue" SG_ 1396 EDC_WakeUp_BYTE3BIT6 0;
BA_ "GenSigCycleTime" SG_ 1396 EDC_WakeUp_BYTE3BIT7 1000;
BA_ "GenSigSendType" SG_ 1396 EDC_WakeUp_BYTE3BIT7 0;
BA_ "GenSigStartValue" SG_ 1396 EDC_WakeUp_BYTE3BIT7 0;
BA_ "GenSigInvalidValue" SG_ 1396 EDC_WakeUp_BYTE3BIT7 0;
BA_ "GenSigCycleTime" SG_ 1396 EDC_NotSleep_BYTE1BIT4 1000;
BA_ "GenSigSendType" SG_ 1396 EDC_NotSleep_BYTE1BIT4 0;
BA_ "GenSigStartValue" SG_ 1396 EDC_NotSleep_BYTE1BIT4 0;
BA_ "GenSigInvalidValue" SG_ 1396 EDC_NotSleep_BYTE1BIT4 0;
BA_ "GenSigCycleTime" SG_ 1396 EDC_NotSleep_BYTE1BIT5 1000;
BA_ "GenSigSendType" SG_ 1396 EDC_NotSleep_BYTE1BIT5 0;
BA_ "GenSigStartValue" SG_ 1396 EDC_NotSleep_BYTE1BIT5 0;
BA_ "GenSigInvalidValue" SG_ 1396 EDC_NotSleep_BYTE1BIT5 0;
BA_ "GenSigCycleTime" SG_ 1396 EDC_NotSleep_BYTE1BIT6 1000;
BA_ "GenSigSendType" SG_ 1396 EDC_NotSleep_BYTE1BIT6 0;
BA_ "GenSigStartValue" SG_ 1396 EDC_NotSleep_BYTE1BIT6 0;
BA_ "GenSigInvalidValue" SG_ 1396 EDC_NotSleep_BYTE1BIT6 0;
BA_ "GenSigCycleTime" SG_ 1396 EDC_NotSleep_BYTE1BIT7 1000;
BA_ "GenSigSendType" SG_ 1396 EDC_NotSleep_BYTE1BIT7 0;
BA_ "GenSigStartValue" SG_ 1396 EDC_NotSleep_BYTE1BIT7 0;
BA_ "GenSigInvalidValue" SG_ 1396 EDC_NotSleep_BYTE1BIT7 0;
BA_ "GenSigCycleTime" SG_ 1396 EDC_wakeup_BYTE2BIT4 1000;
BA_ "GenSigSendType" SG_ 1396 EDC_wakeup_BYTE2BIT4 0;
BA_ "GenSigStartValue" SG_ 1396 EDC_wakeup_BYTE2BIT4 0;
BA_ "GenSigInvalidValue" SG_ 1396 EDC_wakeup_BYTE2BIT4 0;
BA_ "GenSigCycleTime" SG_ 1396 EDC_wakeup_BYTE2BIT5 1000;
BA_ "GenSigSendType" SG_ 1396 EDC_wakeup_BYTE2BIT5 0;
BA_ "GenSigStartValue" SG_ 1396 EDC_wakeup_BYTE2BIT5 0;
BA_ "GenSigInvalidValue" SG_ 1396 EDC_wakeup_BYTE2BIT5 0;
BA_ "GenSigCycleTime" SG_ 1396 EDC_wakeup_BYTE2BIT6 1000;
BA_ "GenSigSendType" SG_ 1396 EDC_wakeup_BYTE2BIT6 0;
BA_ "GenSigStartValue" SG_ 1396 EDC_wakeup_BYTE2BIT6 0;
BA_ "GenSigInvalidValue" SG_ 1396 EDC_wakeup_BYTE2BIT6 0;
BA_ "GenSigCycleTime" SG_ 1396 EDC_wakeup_BYTE2BIT7 1000;
BA_ "GenSigSendType" SG_ 1396 EDC_wakeup_BYTE2BIT7 0;
BA_ "GenSigStartValue" SG_ 1396 EDC_wakeup_BYTE2BIT7 0;
BA_ "GenSigInvalidValue" SG_ 1396 EDC_wakeup_BYTE2BIT7 0;
VAL_ 919 VIU_FL_OTAmode 0 "OTAinactive" 1 "OTAmode" ;
VAL_ 919 VIU_LocalDiagMode 0 "LocalDiagModeInactive" 1 " LocalDiagMode" ;
VAL_ 920 EDC_EOLMode 0 "EOLModeInactive" 1 "EOLMode" ;
VAL_ 920 EDC_VerCollectMode 0 "VerCollectModeInactive" 1 "VerCollectMode" ;
VAL_ 921 TBOX_RemotDiagMode 0 "RemotDiagModeInactive" 1 "RemotDiagMode" ;
VAL_ 930 EmsFlexfuelDisplay 0 "NoDisplay" 1 "Display" ;
VAL_ 930 EmsLowTempMilgRemind 0 "“不显示”" 1 "“为保护发动机，车辆将保持运行一段时间”" ;
VAL_ 931 EDC_EpbFctLamp 0 "LampOff" 1 "Lamp ON" 2 "Lamp Flashing" 3 "Invalid" ;
VAL_ 931 EDC_EpsFaild 0 "Nofailure" 1 "Slight failure" 2 "Critical failure" 3 "Fatal failure" ;
VAL_ 931 EDC_EmsMilLamp 0 "Off" 1 "ON" 2 "Reserved" 3 "Error" ;
VAL_ 931 EDC_LoBeamInfo 0 "OFF" 1 "ON" ;
VAL_ 931 EDC_HiBeamInfo 0 "OFF" 1 "ON" ;
VAL_ 931 EDC_AutoHiBeamInfo 0 "关闭" 1 "开启" 2 "待机" 3 "预留" ;
VAL_ 931 EDC_Le_ReLoglSt 0 "OFF" 1 "ON" ;
VAL_ 931 EDC_Ri_ReLoglSt 0 "OFF" 1 "ON" ;
VAL_ 931 EDC_PosnLiInfo 0 "OFF" 1 "ON" ;
VAL_ 931 EDC_VcuPlugConnectLamp 0 "OFF" 1 "ON" ;
VAL_ 931 EDC_BcuBattSocUnderLamp 0 "OFF" 1 "ON" ;
VAL_ 931 EDC_VcuChrgStsLamp 0 "OFF" 1 "ON" ;
VAL_ 931 EDC_DcacStsLamp 0 "Off" 1 "ON" 2 "working" 3 "Invalid" ;
VAL_ 931 EDC_LoBattErrSts 0 "OFF" 1 "ON" ;
VAL_ 931 EDC_VcuVehPwrLimLamp 0 "OFF" 1 "ON" ;
VAL_ 931 EDC_VcuEngineOilPressureLowSts 0 "Normal" 1 " Low" ;
VAL_ 931 EDC_PsgSeatSBR 0 "InSeat" 1 "NoInSeat" 2 "UnKown" 3 " Reserved" ;
VAL_ 931 EDC_RearLeSeatSBR 0 "InSeat" 1 "NoInSeat" 2 "UnKown" 3 " Reserved" ;
VAL_ 931 EDC_RearMidSeatSBR 0 "InSeat" 1 "NoInSeat" 2 "UnKown" 3 " Reserved" ;
VAL_ 931 EDC_RearRiSeatSBR 0 "InSeat" 1 "NoInSeat" 2 "UnKown" 3 " Reserved" ;
VAL_ 931 EDC_SBR 0 "OFF" 1 "ON" ;
VAL_ 931 EDC_AD_NDAStatus 0 "OFF" 1 "Passive" 2 "StandBy" 3 "NID Active" 4 "Suspend" 5 "Prohibit" 6 "failure" 7 "reserved" ;
VAL_ 931 EDC_AD_BSDLCA_LeftAlert 0 "NoRCTAwarning" 1 " RCTAwarningLevel1" 2 " RCTAwarningLevel2" 3 " RCTAwarningLevel3" ;
VAL_ 931 EDC_AD_BSDLCA_RightAlert 0 "NoRCTAwarning" 1 " RCTAwarningLevel1" 2 " RCTAwarningLevel2" 3 " RCTAwarningLevel3" ;
VAL_ 931 EDC_ViuEgyResiColor 0 "绿色" 1 "黄色" 2 "红色" 3 "Reserved" ;
VAL_ 931 EDC_ViuEvResiMilgInvldDisp 0 "正常" 1 "--" ;
VAL_ 931 EDC_LaneLeft_Status 0 "默认值" 1 "显示" 2 "横向纠偏干预" 3 "车道偏离报警" 4 "车道线对中行驶" 5 "跨越车道线" 6 "UDLC等待换道" 8 "UDLC抑制换道" 7 "ACC active" 9 "IACC active" 10 "NID active" ;
VAL_ 931 EDC_LaneRight_Status 0 "No_display" 1 "Tracking" 2 "Intervention" 3 "Warning" 4 "Centering" 5 "Crossing" 6 "UDLC_Wait_Active" 8 "UDLC_Not_Active" 7 "ACC active" 9 "IACC active" 10 "NID active" ;
VAL_ 931 EDC_ACC_TimeGapSet 0 "nodisplay" 1 " 1.0S" 2 " 1.4S" 3 " 1.8S" 4 " 2.4S" 5 "3S" ;
VAL_ 931 EDC_Objx_Detection 0 "未检测到" 1 " 正常显示" 2 " ACC前向目标" 3 " IACC前向目标" 4 " 碰撞危险目标" 5 " 潜在危险目标" 6 " 其他目标" 7 " 跟车伴游目标" 8 " 跟车&伴游目标" ;
VAL_ 931 EDC_EpbFailrLamp 0 "LampOff" 1 "Lamp ON" 2 "Lamp Flashing" 3 "Invalid" ;
VAL_ 931 EDC_trafficLight 0 "无" 1 "红色" 2 "黄色" 3 "绿色" ;
VAL_ 931 EDC_mileage 0 "总里程" 1 "小计里程" ;
VAL_ 931 EDC_brightness 0 "0档" 1 "1档" 2 "2档" 3 "3档" 4 "4档" 5 "5档" 6 "6档" 7 "7档" 8 "8档" 9 "9档" 10 "10档" ;
VAL_ 931 EDC_Autobrightness 0 "开启" 1 "关闭" ;
VAL_ 931 EDC_FW_Brightness 1022 "初始值" 1023 "故障值" ;
VAL_ 931 EDC_AMB_Brightness 1022 "初始值" 1023 "故障值" ;
VAL_ 931 EDC_AD_AEBStatus 0 "off" 1 "passive" 2 "failure" 3 " standby" 4 "active" ;
VAL_ 931 EDC_VcuPwrSysErrLamp 0 "Noerror" 1 "黄色灯亮" 2 "红色灯亮" 3 "reserved" ;
VAL_ 937 AD_SYNC_Type 32 "SYNC" 40 "FUP" ;
VAL_ 941 AD_CNAStatus 0 "Off关闭" 1 "Passive不可激活待机" 2 "Standy可激活待机" 3 "Active激活" 4 "Override超越" 5 "Failure故障" ;
VAL_ 941 AD_HandsOnReq 0 "norequest" 1 "level 1 request" 2 "level 2 request" 3 "level 3 request" 4 "level 4 request" ;
VAL_ 941 AD_IACCHWAMode 0 "off" 1 "standby" 2 "passive" 3 "active" 4 "suspend" 5 "prohibition" 6 "reserved" 7 "failure" ;
VAL_ 941 AD_IACCMode 0 "off" 1 "standby" 2 "passive" 3 "active" 4 "suspend" 5 "prohibition" 6 "reserved" 7 "failure" ;
VAL_ 941 AD_LatTakeoverReq 0 "norequest" 1 "level 1 request" 2 "level 2 request" 3 "reserved" ;
VAL_ 941 AD_LngTakeOverReq 0 "norequest" 1 "level 1 request" 2 "level 2 request" 3 "reserved" ;
VAL_ 941 AD_NDAStatus 0 "OFF" 1 "Passive" 2 "StandBy" 3 "NID Active" 4 "reserve" 5 "Takeover" 6 "Prohibition" ;
VAL_ 941 AD_TakeoverReqAtIPFail 0 "norequest" 1 "level 1 request" 2 "level 2 request" 3 "reserved" ;
VAL_ 941 AD_TJPStatus 0 "关闭" 1 "可激活" 2 "激活" 3 "故障" ;
VAL_ 941 AD_Voiceinfo 0 "novoice" 1 "latentWarning voive" 2 "FCW/AEB voice" 3 "ACC object detect voice" 4 "ACC object disappeared voice" 5 "ACC/IACC takeover request voice" 6 "Lane Left dangerous warning voice" 7 "Lane Right dangerous warning voice" 8 "reserved" 9 "IACC Active voice" 10 "IACC exit voice" 11 "reserved" 12 "reserved" 13 "cruise unintended exit" 14 "TrafficWarning" ;
VAL_ 941 RRS_SystemFailureFlag 0 "NotFailure" 1 "Front Failure" 2 "Real Failure" 3 "System Failure" ;
VAL_ 945 ErpsFctMode 0 "关闭" 1 "打开" ;
VAL_ 945 BcmTrDoorSts 0 "关闭" 1 "开启" 2 "开启运动状态" 3 "关闭运动状态" 4 "悬停状态" 5 "半锁" 6 "防夹/防撞反转" 7 "无效" ;
VAL_ 945 BcmTrDoorWinPosi 0 "此参数无效" ;
VAL_ 945 BcmTrDoorWinSts 1 "Open" 2 "Close" 3 "Openning" 4 "Closing" 5 "Stop" ;
VAL_ 945 BCMRiDoorLockSwt 0 "无效值" 1 "左侧门锁解锁失败，右侧门锁解锁成功，VIU_FL异常" 2 "左侧门锁解锁失败，右侧门锁解锁失败，VIU_FL异常" 3 "左侧门锁解锁失败，右侧门锁闭锁成功，VIU_FL异常" 4 "左侧门锁解锁失败，右侧门锁闭锁失败，VIU_FL异常" ;
VAL_ 945 VIUPsgSeatSBR 0 "无人" 1 "有人" ;
VAL_ 945 VIURearLeSeatSBR 0 "无人" 1 "有人" ;
VAL_ 945 VIURearMidSeatSBR 0 "无人" 1 "有人" ;
VAL_ 945 VIURearRiSeatSBR 0 "无人" 1 "有人" ;
VAL_ 945 EMBBrkSysFailrBuzAlrmSec 0 "OFF" 1 "ON" 2 "reserved" 3 "Invalid" ;
VAL_ 945 EMBBrkSysFctdownTextDispReqSec 0 "Norequest" 1 "制动系统故障，车辆将限速行驶！" 2 "制动系统故障，不允许车辆加速！" 3 "制动系统故障，车辆将自动减速！" 4 "供电系统故障，车辆将限速行驶！" 5 "供电系统故障，不允许车辆加速！" 6 "供电系统故障，车辆将自动减速！" 7 "reserved" 8 "reserved" 9 "reserved" 10 "reserved" 11 "reserved" 12 "reserved" 13 "reserved" 14 "reserved" 15 "Invalid" ;
VAL_ 945 EpbTextDispReqSec 0 "Notextmessage" 1 "Gradienttoohigh" 2 "parkingforce not " 3 "Fastenseatbelt" 4 "Openparkbrakebyswitch" 5 "Pressbrakepedal" 6 "Vehicle Speed too high" 7 "DynPrkgActived" 8 "Release EPB by shiftt" 9 "P-gear button malfunction, if need park through the HU EPB switch" 10 "parking system malfunction,please check and repair" 11 "reserved" 12 "reserved" 13 "reserved" 14 "reserved" 15 "Invalid" ;
VAL_ 959 HUFRTopPositionVolSET 0 "invalid" 1 "-3" 2 "-2" 3 "-1" 4 "0" 5 "1" 6 "2" 7 "3" ;
VAL_ 959 HURLPositionDelaySET 0 "invalid" 1 "0ms" 2 "0.5ms" 3 "1ms" 4 "1.5ms" 5 "2ms" ;
VAL_ 959 HURLPositionVolSET 0 "invalid" 1 "-3" 2 "-2" 3 "-1" 4 "0" 5 "1" 6 "2" 7 "3" ;
VAL_ 959 HURLSurroundPositionDelaySET 0 "invalid" 1 "0ms" 2 "0.5ms" 3 "1ms" 4 "1.5ms" 5 "2ms" ;
VAL_ 959 HURLSurroundPositionVolSET 0 "invalid" 1 "-3" 2 "-2" 3 "-1" 4 "0" 5 "1" 6 "2" 7 "3" ;
VAL_ 959 HURLTopPositionDelaySET 0 "invalid" 1 "0ms" 2 "0.5ms" 3 "1ms" 4 "1.5ms" 5 "2ms" ;
VAL_ 959 HURLTopPositionVolSET 0 "invalid" 1 "-3" 2 "-2" 3 "-1" 4 "0" 5 "1" 6 "2" 7 "3" ;
VAL_ 959 HURRPositionDelaySET 0 "invalid" 1 "0ms" 2 "0.5ms" 3 "1ms" 4 "1.5ms" 5 "2ms" ;
VAL_ 959 HURRPositionVolSET 0 "invalid" 1 "-3" 2 "-2" 3 "-1" 4 "0" 5 "1" 6 "2" 7 "3" ;
VAL_ 959 HURRSurroundPositionDelaySET 0 "invalid" 1 "0ms" 2 "0.5ms" 3 "1ms" 4 "1.5ms" 5 "2ms" ;
VAL_ 959 HURRSurroundPositionVolSET 0 "invalid" 1 "-3" 2 "-2" 3 "-1" 4 "0" 5 "1" 6 "2" 7 "3" ;
VAL_ 959 HURRTopPositionDelaySET 0 "invalid" 1 "0ms" 2 "0.5ms" 3 "1ms" 4 "1.5ms" 5 "2ms" ;
VAL_ 959 HURRTopPositionVolSET 0 "invalid" 1 "-3" 2 "-2" 3 "-1" 4 "0" 5 "1" 6 "2" 7 "3" ;
VAL_ 965 AD_HWPStatus 0 "OFF" 1 "Passive" 2 "StandBy" 3 "HWP Active" 4 "Suspend" 5 "Prohibit" 6 "failure" 7 "reserved" ;
VAL_ 965 ACC_ADCNotice 1 "L3=HWPActive" 2 "ACC= ACC system error" 3 "ACC= ACC Error by EMS/VCU/TCU" 4 "ACC= ACC Error by EPBI" 5 "ACC= SAS Error" 6 "ACC= Button Error" 7 "ACC= IP Fail" 8 "ACC= ACC temporary unavailable by others" 9 "ACC= ACC error by Front Camera" 10 "ACC= ACC error by Front Radar" 11 "ACC= Engine No Running" 12 "ACC= door is open" 13 "ACC= bonnet is Open" 14 "ACC= Trunk is Open" 15 "ACC= Tire Status is abnormal" 16 "ACC= Bad weather" 17 "ACC= Seatbelt unbuckled" 18 "ACC= ESP off" 19 "ACC= No forward gear" 20 "ACC= APA is on" 21 "ACC= EPB activate" 22 "ACC= ACC cannot active by snow mode" 23 "ACC= SteeringAngle is over" 24 "ACC= brake pedal is applied" 25 "ACC= Speed over 150kph" 26 "ACC=不可激活原因-全地形模式" 27 "ACC= Road wet and slippery" 28 "ACC= Road bumpy" 29 "ACC= Have Pedestrain or Riders" 30 "ACC= Out of slope range " 31 "自动驾驶激活失败，主驾安全带未系上" 32 "ACC= ACC cannot active by Race mode" 33 "ACC= ACC unintended exit warning" 34 "自动驾驶激活失败，副驾安全带未系上" 35 "自动驾驶激活失败，后排安全带未系上" 36 "自动驾驶运行中，用户状态不满足" 37 "ACC= speed reduce by SpdLimited" 38 "不可激活原因-拖挂模式" 39 "ACC= speed reduce by tunnel" 40 "ACC= unable to activate ACC" 41 "ACC= 车辆起步提醒（前车驶离）" 42 "ACC= 激活成功提醒" 43 "ACC=前方红绿灯-智能限速" 44 "ACC= 前方人行横道-请注意减速慢行" 45 "ACC= 前方人行横道-智能限速" 46 "ACC= 前方收费站-请注意减速慢行" 47 "ACC= 前方收费站-智能限速" 48 "ACC= 前方弯道-智能限速" 49 "ACC= 前雷达不可用-ACC退出" 50 "ACC= 前摄像头不可用-ACC退出" 51 "ACC= 推荐调节巡航车速-避让并行车辆" 52 "ACC= 巡航驻车提醒" 53 "ACC= 雨天道路湿滑-自动增加跟车时距" 54 "ACC= 智能加速避让并行车辆" 55 "ACC= 智能减速避让并行车辆" 56 "ACC= 主动提速提醒" 57 "ACC= 主动退出提醒（稍强）" 58 "ACC=巡航驻车（Stand Wait mode）" 59 "ACC= 操作反馈-设定车速达到上限" 60 "ACC= 操作反馈-设定车速达到下限" 61 "ACC= 操作反馈-设定车速达到限速值" 62 "ACC= 操作反馈-超速接近纵向控制极限，即将退出" 63 "用户主动退出，驾驶员接管能力不足" 64 "ACC=巡航或领航降级至ACC" 65 "ACC= 减速提示-城区汇流限速" 66 "ACC= 减速提示-高速汇流限速" 67 "ACC= 减速提示-邻车道缓行限速" 68 "ACC= 减速提示-路口限速" 69 "ACC= 隧道限速解除" 70 "ACC= 匝道限速解除" 71 "ACC= 弯道限速解除" 72 "ACC= 人行横道限速解除" 73 "ACC= 城区汇流限速解除" 74 "ACC= 高速汇流限速解除" 75 "ACC= 邻车道缓行限速解除" 76 "ACC= 路口限速解除" 77 "ACC= 行人限速解除" 78 "ACC= 用户主动解除跟停模式" 79 "ACC= 避让并行车辆结束" 80 "ACC= 减速提示-行人限速" 81 "ACC/IACC= 不可激活原因-传感器遮挡" 82 "安全停车后系统禁用，用户尝试激活自动驾驶" 83 "不可激活原因-请退出自动驾驶后重试" 84 "ACC/IACC= 不可激活原因-车辆后溜" 85 "ACC/IACC= 不可激活原因-车辆前滑" 86 "ACC/IACC= 不可激活原因-制动盘过热" 87 "ACC/IACC= 不可激活原因-充电口未关" 88 "ACC= 减速提示-能见度低" 89 "ACC/IACC= 不可激活原因-充电口打开" 90 "ACC/IACC= 不可激活原因-处于超级省电模式" 91 "ACC/IACC= 不可激活原因-车道过宽" 92 "ACC/IACC= 不可激活原因-车道过窄" 93 "用户主动退出成功自动驾驶系统" 94 "减速提示-传感器逆光" 95 "减速提示-坡度变化" 96 "减速提示-减速线" 97 "减速提示-前方学校" 98 "ACC=减速提示-停车场限速" 99 "ACC-前方绿灯，即将通行" 100 "减速提示-前方医院" 101 "IACC= IACC not available by EPS" 102 "IACC= longitudinal control not available" 103 "IACC= ADR/DVR Status not Match" 104 "IACC= other system error" 105 "IACC= prohibition request for safestop" 106 "IACC= Please turn on IACC= in incall " 107 "IACC= Driver Drowsy or Distracted" 108 "IACC= SteeringAngle is over" 109 "IACC= exceed speed limit" 110 "IACC= turn light switch on" 111 "IACC= Hands on plz" 112 "IACC= driver overrides steering" 113 "IACC= caution about driving safty" 114 "IACC= unable to active for not in lane/crossing lane" 115 "IACC= lane condition not available" 116 "IACC= unable to active in curve" 117 "IACC=unable to active in Bad weather" 118 "IACC= system error" 119 "IACC= LKA Takeover Req" 120 "IACC= ELK active" 121 "IACC= HeadingAngle is over" 122 "IACC= LAT invalid" 123 "IACC= LAT invalid（in safety stargy)" 124 "IACC= Hands on plz" 125 "IACC= IACC active" 126 "IACC= IACC Cancel" 127 "IACC= IACC deactivate" 128 "IACC= IACC override" 129 "驾驶员主动退出（上拨拨杆）" 130 "驾驶员主动退出（踩刹车）" 131 "IACC= Longitude Exit" 132 "IACC= Prohibition request for rdf" 133 "IACC=takeover request with safety stop completed" 134 "IACC= takeover request with safety stoping" 135 "IACC= unable to activate IACC" 136 "IACC= 未认证用户使用智能驾驶功能提醒" 137 "IACC= 超速接近横向控制的极限即将退出" 138 "IACC= 车辆临时靠左行驶，避让并行车辆" 139 "IACC= 车辆临时靠右行驶，避让并行车辆" 140 "IACC= 车辆临时靠左行驶，避让护栏" 141 "IACC= 车辆临时靠右行驶，避让护栏" 142 "IACC= 从ACC升级到巡航" 143 "IACC= 车道线不清晰" 144 "IACC= 推荐使用巡航功能" 145 "IACC= 巡航功能禁用已解除" 146 "IACC=邻车道车辆压线行驶，向左偏移" 147 "IACC=邻车道与大车并行行驶，向左偏移" 148 "IACC=行人偏移，向左" 149 "IACC=骑行者偏移，向左" 150 "IACC= 动物偏移，对向" 151 "IACC= 绿化带偏移，向左" 152 "IACC= 绿化带偏移，向右" 153 "IACC= 动物偏移，同向" 154 "IACC=偏移，障碍物（锥桶、水马）占用本车道-向左" 155 "IACC= 智慧偏移结束" 156 "IACC= 领航降级至巡航" 157 "IACC=连续偏移" 158 "减速提示-前方小区" 159 "减速提示-前方公交站" 161 "IACC=邻车道车辆压线行驶，向右偏移" 162 "IACC=邻车道与大车并行行驶，向右偏移" 163 "IACC=行人偏移，向右" 164 "IACC=骑行者偏移，向右" 165 "IACC=偏移，障碍物（锥桶、水马）占用本车道-向右" 166 "通用向左偏移" 167 "通用向右偏移" 168 "ALC=车辆向右换道，前方路口" 169 "ALC=车辆向右换道至高通行效率车道" 170 "OA=前方车辆异常，向左绕障" 171 "OA=前方车辆故障，向左绕障" 172 "OA=前方车辆异常，向右绕障" 173 "OA=前方车辆故障，向右绕障" 174 "ALC=换道至导航目的地侧车道" 175 "故障提醒-IACC受限激活时（非传感器遮挡）" 176 "故障提醒-IACC受限激活时（传感器遮挡）" 177 "故障提醒-CNID受限激活时（非传感器遮挡）" 178 "故障提醒-CNID受限激活时（传感器遮挡）" 179 "故障提醒-IACC受限降级时（非传感器遮挡）" 180 "故障提醒-IACC受限降级时（传感器遮挡）" 181 "故障提醒-CNID受限降级时（非传感器遮挡）" 182 "故障提醒-CNID受限降级时（传感器遮挡）" 183 "ACC/IACC=不可激活原因-陡坡缓降模式激活" 184 "调速限制提醒-ACC/IACC/C-NID达上限" 185 "跟车伴游模式退出-IACC" 186 "ACC=基于车流限速" 187 "IACC=超越结束" 188 "CNID=超越" 189 "CNID=超越结束" 190 "分叉路口-向左打灯" 191 "分叉路口-向右打灯" 192 "跟车伴游模式激活" 193 "前方不可通行" 194 "路况复杂" 195 "跟车伴游模式退出-NID" 197 "跟车伴游模式激活失败" 198 "后方快速车辆" 199 "前方急弯" 200 "不可激活-车辆逆行" 201 "UDLC=UDLC exit，触发式换道已退出，（UDLC不再等待换道并且不再主导控制）" 202 "UDLC=UDLC return，触发式换道回退原车道（驾驶员取消换道而回退）" 203 "UDLC=UDLC finished，请拨回转向灯（换道完成或回退对中完成时）" 205 "UDLC=change lane to both sides for the traffic jam,两边车道均可支持变道" 206 "UDLC=Lane change request by ramp" 207 "UDLC=change lane to left side for the traffic jam,左边车道可支持变道" 208 "UDLC=change lane to right side for the traffic jam,右边车道可支持变道" 209 "UDLC=out of ODD暂时不满足换道条件，不尝试换道" 210 "UDLC=Please turn on the UDLC in HU请在主机中打开主动换道设置开关" 211 "UDLC=speed out of range车速超出范围，自动换道条件不满足" 212 "UDLC=UDLC System Error自动换道系统故障" 213 "UDLC=雨量过大，自动换道条件不满足" 214 "UDLC=wait over time,换道尝试超时中止" 215 "UDLC=推荐向左换道-道路更畅通" 216 "UDLC=推荐向左换道-超越前车" 217 "UDLC=推荐向左换道-避让前方障碍物" 218 "UDLC=推荐向左换道-避让前方异常车辆" 219 "UDLC=推荐向左换道-道路前方有道路施工" 220 "UDLC=推荐向左换道-提前避让右侧汇入车辆" 221 "UDLC=推荐向左换道-避让右侧汇入车辆" 222 "UDLC=推荐向左换道-前方道路即将向左合并" 223 "UDLC=推荐向左换道-避让右侧大型车辆" 224 "UDLC=推荐向左换道-避让后方大型车辆" 225 "UDLC=推荐向右换道-道路更畅通" 226 "UDLC=推荐向右换道-超越前车" 227 "UDLC=推荐向右换道-道路前方有障碍物" 228 "UDLC=推荐向右换道-道路前方有异常车辆" 229 "UDLC=推荐向右换道-道路前方有道路施工" 230 "UDLC=推荐向右换道-提前避让左侧汇入车辆" 231 "UDLC=推荐向右换道-避让左侧汇入车辆" 232 "UDLC=推荐向右换道-前方道路即将向右合并" 233 "UDLC=推荐向右换道-避让左侧大型车辆" 234 "UDLC=推荐向右换道-避让后方大型车辆" 235 "UDLC=避让侧后方来车，返回原车道" 236 "UDLC=避让危险车辆，返回原车道" 237 "UDLC=避让行人，返回原车道" 238 "UDLC=避让障碍物，返回原车道" 239 "UDLC=非驾驶员操作通用原因，返回原车道" 240 "UDLC=换道辅助系统故障，请立即接管" 241 " 换道辅助系统故障" 242 "UDLC=换道辅助系统退出" 243 "UDLC=换道辅助系统退出，请立即接管" 244 "正在向左换道" 245 "正在向右换道" 246 "UDLC=正在返回原车道" 247 "UDLC=换道完成，请关闭转向灯" 248 "UDLC=胎压异常，暂不支持辅助换道" 249 "UDLC=车速过高，暂不支持辅助换道" 250 "UDLC=换道条件不满足" 251 "UDLC=当前急弯，暂不支持辅助换道" 254 "UDLC=换道条件不满足，本次换道取消" 255 "UDLC=换道失败，请立即接管" 256 "UDLC=等待换道中" 257 "LaneChangeToLeftForPathThroughRamp前方接近匝道，推荐向左换道" 258 "LaneChangeToRightForPathThroughRamp前方接近匝道，推荐向右换道" 259 "LaneChangeForQuickRoad,前方汇入主路，推荐向左换道" 260 "LaneChangeForQuickRoad,前方汇入主路，推荐向右换道" 261 "LaneChangeToLeft推荐向左换道" 262 "LaneChangeToRight推荐向右换道" 263 "LaneChangeToLeftForSurpassTheCar,前方车辆行驶缓慢，推荐向左超车" 264 "LaneChangeToRightForSurpassTheCar,前方车辆行驶缓慢，推荐向右超车" 265 "LaneChangeToLeftForAvoidingConfluence,前方道路汇流，推荐向左换道" 266 "LaneChangeToRightForAvoidingConfluence,前方道路汇流，推荐向右换道" 267 "LaneChangeToLeftForConstruction,前方道路施工，推荐向左换道" 268 "LaneChangeToRightForConstruction,前方道路施工，推荐向右换道" 269 "LaneChangeToLeftForTrafficAccident,前方交通事故，推荐向左换道" 270 "LaneChangeToRightForTrafficAccident前方交通事故，推荐向右换道" 271 "LaneChangeToLeftForObstacle前方有障碍物，推荐向左换道" 272 "LaneChangeToRightForObstacle前方有障碍物，推荐向右换道" 273 "OA=等待绕障车辆" 274 "OA=正在绕障" 275 "UDLC=触发换道中断回退（道路交通条件不满足）" 276 "UDLC=道路条件不满足，无车道" 277 "UDLC=道路条件不满足，车道为实线" 278 "UDLC=交通条件限制，目标车位被占用" 279 "UDLC=交通条件限制，前车限制" 280 "UDLC=交通条件限制，后车限制" 281 "UDLC=驾驶员状态不满足" 282 "UDLC=车辆状态不满足" 283 "辅助提示=过收费站提示" 284 "减速提示=窄路限速" 285 "减速提示=电子眼限速" 286 "减速提示=区间限速" 288 "绕障=向左压实线绕障" 289 "绕障=向右压实线绕障" 290 "不可激活原因-超高模式" 291 "跟车伴游=目标轨迹与导航轨迹不一致" 292 "跟车伴游=驾驶员接管方向盘" 294 "跟车伴游-激活条件不满足" 295 "跟车伴游-未选择跟车目标" 296 "跟车伴游-用户主动退出" 297 "UDLC-压实线换道提示" 298 "ALC-沿导航行驶不响应换道提示" 301 "ALC=LaneChangeToLeftForPathThroughRamp前方接近匝道，即将向左换道" 302 "ALC=LaneChangeToRightForPathThroughRamp前方接近匝道，即将向右换道" 303 "已在跟随正前方目标" 304 "已切换跟随正前方目标" 305 "正前方无可跟随目标" 306 "ALC=LaneChangeToLeftForSurpassTheCar,即将向左超车" 307 "ALC=LaneChangeToRightForSurpassTheCar,即将向右超车" 308 "ALC=向左自动换道-道路更畅通" 309 "ALC=向左自动换道-避让前方特殊车道" 310 "ALC=向左自动换道-避让前方障碍物" 311 "ALC=向左自动换道-避让前方异常车辆" 312 "ALC=向左自动换道-道路前方有道路施工" 313 "ALC=向左自动换道-提前避让右侧汇入车辆" 314 "ALC=向右自动换道-避让前方特殊车道" 315 "ALC=向左自动换道-前方道路即将向左合并" 316 "ALC=向右自动换道-避让左侧大型车辆" 317 "ALC=向左自动换道-避让右侧大型车辆" 318 "ALC=向右自动换道-道路更畅通" 319 "ALC=向右自动换道-超越前车" 320 "ALC=向右自动换道-道路前方有障碍物" 321 "ALC=向右自动换道-道路前方有异常车辆" 322 "右视后摄像头脏污或遮挡，换道暂不可用" 323 "右视前摄像头脏污或遮挡，换道暂不可用" 324 "左视后摄像头脏污或遮挡，换道暂不可用" 325 "左视前摄像头脏污或遮挡，换道暂不可用" 326 "ALC=向右自动换道-避让左侧大型车辆" 327 "ALC=向右自动换道-避让后方大型车辆" 328 "ALC=自动换道已取消（主动）" 329 "ALC=避让侧后方来车，取消自动换道" 330 "ALC=避让危险车辆，取消自动换道" 331 "ALC=避让行人，取消自动换道" 332 "ALC=避让障碍物，取消自动换道" 333 "ALC=非驾驶员操作通用原因，取消自动换道" 334 "ALC=LaneChangeToLeftForAvoidingConfluence,前方道路汇流，即将向左换道" 335 "ALC=LaneChangeToRightForAvoidingConfluence,前方道路汇流，即将向右换道" 336 "ALC=LaneChangeToLeftForConstruction,前方道路施工，即将向左换道" 337 "ALC=LaneChangeToRightForConstruction,前方道路施工，即将向右换道" 338 "ALC=LaneChangeToLeftForTrafficAccident,前方交通事故，即将向左换道" 339 "ALC=LaneChangeToRightForTrafficAccident前方交通事故，即将向右换道" 340 "ALC=返回条件不满足，正在继续换道" 341 "提醒开启远近光灯" 342 "ALC=前方分流，向左换道" 343 "ALC=前方分流，向右换道" 344 "ALC=自动换道完成" 345 "ALC=车辆换道，前方匝道" 346 "ALC=车辆向左换道，前方路口" 347 "ALC=自动换道中断回退，换道取消（驾驶员取消-取消转向灯，反打转向灯）" 348 "ALC=自动换道无法中断回退，继续换道（驾驶员取消-取消转向灯，反打转向灯）" 349 "ALC=智慧换道已关闭" 350 "ALC=车辆向左换道至高通行效率车道" 351 "ALC=本车汇流入主路，向左换道" 352 "ALC=本车汇流入主路，向右换道" 353 "橡胶减速带减速" 354 "到达导航终点减速停车中" 355 "ALC=向左换道-避让行人" 356 "ALC=向右换道-避让行人" 357 "ALC=向左换道-避让骑行者" 358 "ALC=向右换道-避让骑行者" 401 "绕障=前方障碍物，向左绕行" 402 "绕障=前方障碍物，向右绕行" 403 "OA=绕障抑制-道路条件不满足" 404 "OA=绕障抑制-车道线不满足-车道线为实线" 405 "OA=绕障抑制-交通条件不满足-目标车位不满足" 406 "OA=绕障抑制-交通条件不满足-前车不满足" 407 "OA=绕障抑制-交通条件不满足-后车不满足" 408 "OA=绕障抑制-驾驶员状态不满足" 409 "OA=绕障抑制-车辆状态不满足" 410 "OA=不可中断（关闭、反打转向灯）-正在绕障，不可取消" 411 "OA=绕障回退-通用" 412 "OA=绕障回退-交通条件不满足" 413 "OA=前方车辆缓行，向左绕障" 414 "OA=前方车辆缓行，向右绕障" 415 "OA=等待绕障障碍物" 416 "OA=绕障完成" 417 "OA=绕障等待超时" 418 "OA=障碍物-绕障失败" 419 "OA=绕障中用户踩加速踏板" 420 "OA=前方行人，向左绕障" 421 "OA=前方行人，向右绕障" 422 "OA=前方骑行者，向左绕障" 423 "OA=前方骑行者，向右绕障" 424 "OA=前方动物，向左绕障" 425 "OA=前方动物，向右绕障" 426 "OA=三角牌封道绕障" 427 "OA=异形障碍物封道绕障" 428 "OA=危险区域，向左绕障" 429 "OA=危险区域，向右绕障" 430 "OA=绕障前推荐用户踩加速踏板确认" ;
VAL_ 965 AD_SafetyNotice 1 "道路天气环境较差" 2 "前方道路变化" 3 "超出坡度范围" 4 "前方交通事故" 5 "前方道路施工" 6 "前方经过环岛" 7 "前方经过服务区" 8 "前方经过隧道" 9 "前方经过匝道" 10 "超出电子围栏或无法定位" 11 "道路颠簸" 12 "前方存在行人" 13 "脱眼报警" 14 "未检测到头部" 15 "请手握方向盘，注意前方路况" 16 "自动驾驶中，用户状态不满足" 17 "前方道路变化，请手握方向盘" 18 "超出坡度范围，请手握方向盘" 19 "前方交通事故，请手握方向盘" 20 "前方道路施工，请手握方向盘" 21 "前方经过环岛，请手握方向盘" 22 "前方经过服务区，请手握方向盘" 23 "前方经过隧道，请手握方向盘" 24 "前方经过匝道，请手握方向盘" 25 "超出电子围栏或无法定位，请手握方向盘" 26 "道路颠簸，请手握方向盘" 27 "前方存在行人，请手握方向盘" 28 "系统异常，请手握方向盘" 29 "油门超越，请手握方向盘" 30 "请保持ESP功能开启" 31 "请保持挡位为D挡或S挡" 32 "请求系好安全带，X秒系统退出" 33 "L3接管报警" 34 "灯光故障，请立即接管" 35 "动力系统异常，请立即接管" 36 "传感系统异常，请立即接管" 37 "转向系统异常，请立即接管" 38 "制动系统异常，请立即接管" 39 "交互系统异常，请立即接管" 40 "驻车系统异常，请立即接管" 41 "系统异常，请立即接管" 42 "胎压异常，请立即接管" 43 "胎温异常，请立即接管" 44 "数据记录异常，请立即接管" 45 "道路天气环境较差，请立即接管" 46 "超出坡度范围，请立即接管" 47 "前方道路施工，请立即接管" 48 "道路颠簸，请立即接管" 49 "道路湿滑，请立即接管" 50 "危险目标，请立即接管" 51 "前方存在行人，请立即接管" 52 "请求系好安全带，并立即接管" 53 "换道失败，立即接管" 54 "即将在本车道停车，请立即接管" 55 "即将靠边停车，请立即接管" 56 "正在停车，请立即接管" 57 "停车已完成，请立即接管" 58 "前方存在骑行者" 59 "解开安全带，系统退出" 60 "车门打开，系统退出" 61 "ESP功能关闭，系统退出" 62 "挡位切换，系统退出" 63 "巡航驻车超时，系统退出" 64 "前方存在骑行者，请手握方向盘" 65 "请立即接管" 66 "转向灯故障，请立即接管" 67 "制动灯异常，请立即接管" 68 "远近光灯故障，请立即接管" 69 "请打开远近光灯，并立即接管" 70 "轨迹规划异常，请立即接管" 71 "电量过低，请立即接管" 72 "制动盘过热，请立即接管" 73 "前方存在骑行者，请立即接管" 74 "车辆存在失稳，请立即接管" 75 "油门超越，请手握方向盘，注意前方路况" 76 "前后舱盖或车门未关闭，请立即接管" 77 "L3安全停车中" 79 "前方汇流" 80 "前方分流" 81 "通讯故障，请立即接管" 82 "前方经过路口" 83 "前方经过路口，请手握方向盘" 84 "超出曲率范围，请手握方向盘" 85 "超出曲率范围" 86 "超出曲率范围，请立即接管" 87 "车道宽度不合适" 88 "车道宽度不合适，请手握方向盘" 89 "前方道路危险障碍物" 90 "前方道路危险障碍物，请手握方向盘" 91 "车辆压线行驶" 92 "前方经过收费站" 93 "系统退出" 95 "前方红绿灯" 96 "前方人行横道" 97 "前方红绿灯，请手握方向盘" 98 "前方人行横道，请手握方向盘" 99 "请降低车速" 100 "车速过高，请立即接管" 101 "未检测到驾驶员，请立即接管" 102 "拥堵解除，请手握方向盘，注意前方路况" 103 "前方存在特殊车辆，请立即接管" 104 "前方车辆倒车，请立即接管" 105 "前方有障碍物，请立即接管" 106 "前方截止路段，请立即接管" 107 "前方路口无法通行，请立即接管" 108 "前方无法下匝道，请立即接管" 109 "UDLC道路交通环境限制-中断换道无法回退接管" 110 "ALC无法自动换道，需用户接管" 111 "OA无法绕障，需用户接管" 112 "IDA路口无法通行，需用户接管" 113 "匝道辅助-无法汇入主路，需用户接管" 114 "匝道辅助-无法汇入匝道，需用户接管" 115 "NID-系统退出，需用户接管" 116 "禁止脱手-前方经过路口，禁止脱手" 117 "禁止脱手-前方下匝道" 118 "立即接管提示-后备箱未关" 119 "立即接管提示-车门未关闭" 120 "立即接管提示-充电盖未关闭" 121 "立即接管提示-按键故障" 122 "立即接管提示-档位失效" 123 "立即接管提示-车道线不清晰" 124 "立即接管提示-纠偏失败需接管" 125 "立即接管提示-无法保持车道内行驶" 126 "注意力预告-前方骑行者" 127 "注意力预告-上下匝道" 128 "注意力预告-油门超越" 129 "注意力预告-系统异常" 130 "禁止脱手-LKA脱手" 131 "接管-ACC/巡航/领航退出" 132 "接管-车道过窄" 133 "接管-安全停车" 134 "接管-车流与本车道横向距离过近" 135 "接管-红绿灯识别错误" 136 "接管-传感器遮挡" 137 "接管-路口辅助红灯" 138 "驾驶员手动控制方向盘，退出智驾" ;
VAL_ 1015 IP_brightness 0 "0档" 1 "1档" 2 "2档" 3 "3档" 4 "4档" 5 "5档" 6 "6档" 7 "7档" 8 "8档" 9 "9档" 10 "10档" ;
VAL_ 1280 TBOX_NotSleep_BYTE6BIT0 0 "Inactive" 1 "其他条件（包含外部/远程/本地功能请求及诊断模式）" ;
VAL_ 1280 TBOX_NotSleep_BYTE7BIT0 0 "Inactive" 1 "网络上其他节点NM报文不允许休眠" ;
VAL_ 1280 TBOX_NotSleep_BYTE7BIT1 0 "Inactive" 1 "电源档位为ON档" ;
VAL_ 1280 TBOX_NotSleep_BYTE7BIT2 0 "Inactive" 1 "TSP指令唤醒" ;
VAL_ 1280 TBOX_NotSleep_BYTE7BIT3 0 "Inactive" 1 "预留" ;
VAL_ 1280 TBOX_NotSleep_BYTE7BIT4 0 "Inactive" 1 "预留" ;
VAL_ 1280 TBOX_NotSleep_BYTE7BIT5 0 "Inactive" 1 "ECALL不允许休眠" ;
VAL_ 1280 TBOX_NotSleep_BYTE7BIT6 0 "Inactive" 1 "预留" ;
VAL_ 1280 TBOX_NotSleep_BYTE7BIT7 0 "Inactive" 1 "OTA不允许休眠" ;
VAL_ 1280 TBOX_WakeUp_BYTE3BIT0 0 "Inactive" 1 "NM报文唤醒" ;
VAL_ 1280 TBOX_WakeUp_BYTE3BIT1 0 "Inactive" 1 "电源档位为ON档" ;
VAL_ 1280 TBOX_WakeUp_BYTE3BIT2 0 "Inactive" 1 "TSP指令唤醒" ;
VAL_ 1280 TBOX_WakeUp_BYTE3BIT3 0 "Inactive" 1 "短信唤醒" ;
VAL_ 1280 TBOX_WakeUp_BYTE3BIT4 0 "Inactive" 1 "电话唤醒" ;
VAL_ 1280 TBOX_WakeUp_BYTE3BIT5 0 "Inactive" 1 "ECALL唤醒" ;
VAL_ 1280 TBOX_WakeUp_BYTE3BIT6 0 "Inactive" 1 "RTC定时唤醒" ;
VAL_ 1288 TMS_BatteryPumpSt 0 "normal" 1 "derating error" 2 "self recovering error" 3 "stop error" ;
VAL_ 1288 TMS_BattInpWtrTValid 0 "Valid" 1 "Invalid" ;
VAL_ 1288 TMS_ECV1MotorSt_Radiator 0 "MotorStop" 1 "Motor Running" ;
VAL_ 1288 TMS_Ecv1St_Radiator 0 "normal" 1 "initializing" 2 "stop error" ;
VAL_ 1288 TMS_ECV2MotorSt_Battery 0 "MotorStop" 1 "Motor Running" ;
VAL_ 1288 TMS_ECV2St_Battery 0 "normal" 1 "initializing" 2 "stop error" ;
VAL_ 1288 TMS_ECV3MotorSt_Hydrothermal 0 "MotorStop" 1 "Motor Running" ;
VAL_ 1288 TMS_ECV3St_Hydrothermal 0 "normal" 1 "initializing" 2 "stop error" ;
VAL_ 1288 TMS_ExtendRangePumpSt 0 "normal" 1 "derating error" 2 "self recovering error" 3 "stop error" ;
VAL_ 1288 TMS_Exv1InitSt_HVAC 0 "=NotInitialized" 1 "=Initalization in Process" 2 "Initialized" 3 "Invalid" ;
VAL_ 1288 TMS_Exv1RunSt_HVAC 0 "Actuatorisnotmoving" 1 "Actuator is moving" ;
VAL_ 1288 TMS_Exv2InitSt_Battery 0 "NotInitialized" 1 "Initalization in Process" 2 " Initialized" 3 "=Invalid" ;
VAL_ 1288 TMS_Exv2RunSt_Battery 0 "Actuatorisnotmoving" 1 "Actuator is moving" ;
VAL_ 1288 TMS_Exv3InitSt_WasteHeatRe 0 "NotInitialized" 1 "Initalization in Process" 2 " Initialized" 3 "=Invalid" ;
VAL_ 1288 TMS_Exv3RunSt_WasteHeatRe 0 "Actuatorisnotmoving" 1 "Actuator is moving" ;
VAL_ 1288 TMS_Exv4InitSt_Refrigerant 0 "NotInitialized" 1 "Initalization in Process" 2 " Initialized" 3 "=Invalid" ;
VAL_ 1288 TMS_Exv4RunningSt_Refrigerant 0 "Actuatorisnotmoving" 1 "Actuator is moving" ;
VAL_ 1288 TMS_FWV1MotorSt 0 "MotorStop" 1 "Motor Running" ;
VAL_ 1288 TMS_FWV1St 0 "normal" 1 "initializing" 2 "stop error" ;
VAL_ 1288 TMS_MotorPumpSt 0 "normal" 1 "derating error" 2 "self recovering error" 3 "stop error" ;
VAL_ 1288 TMS_OilCoolerWtrTValid 0 "Valid" 1 "Invalid" ;
VAL_ 1288 TMS_SolnVlv1St_DLP 0 "off" 1 "on" ;
VAL_ 1288 TMS_SolnVlv1St_RearEvap 0 "off" 1 "on" ;
VAL_ 1288 Tms_ExtenderPmpSts 0 "Notactive" 1 "active" ;
VAL_ 1288 Tms_HeatPmpSts 0 "Notactive" 1 "active" ;
VAL_ 1288 TMS_CTMU_SolnVlv3St 0 "off" 1 "on" ;
VAL_ 1297 TpmsSysFailrWarn 0 "Noanyerror" 1 "Systemerror" ;
VAL_ 1297 TpmsLeFrntTirePWarn 0 "Nowarning" 1 "Highpressurewarning" 2 "Lowpressurewarning" 3 "Quikleakage" 4 "LostSensor" 5 "Sensorbatterylow" 6 "Sensorfailure" 7 "Unlearning" ;
VAL_ 1297 TpmsLeReTirePWarn 0 "Nowarning" 1 "Highpressurewarning" 2 "Lowpressurewarning" 3 "Quikleakage" 4 "LostSensor" 5 "Sensorbatterylow" 6 "Sensorfailure" 7 "Unlearning" ;
VAL_ 1297 TpmsRiFrntTirePWarn 0 "Nowarning" 1 "Highpressurewarning" 2 "Lowpressurewarning" 3 "Quikleakage" 4 "LostSensor" 5 "Sensorbatterylow" 6 "Sensorfailure" 7 "Unlearning" ;
VAL_ 1297 TpmsRiReTirePWarn 0 "Nowarning" 1 "Highpressurewarning" 2 "Lowpressurewarning" 3 "Quikleakage" 4 "LostSensor" 5 "Sensorbatterylow" 6 "Sensorfailure" 7 "Unlearning" ;
VAL_ 1361 VIU_FL_NMNotSleep_BYTE2BIT0 0 "Inactive" 1 "VIU_FL NM报文不允许休眠(0x40C)" ;
VAL_ 1361 VIU_FL_NMNotSleep_BYTE2BIT1 0 "Inactive" 1 "VMC NM报文不允许休眠(0x45C)" ;
VAL_ 1361 VIU_FL_NMNotSleep_BYTE2BIT2 0 "Inactive" 1 "WLCM NM报文不允许休眠(0x471)" ;
VAL_ 1361 VIU_FL_NMNotSleep_BYTE2BIT3 0 "Inactive" 1 "PMU NM报文不允许休眠(0x472)" ;
VAL_ 1361 VIU_FL_NMNotSleep_BYTE2BIT4 0 "Inactive" 1 "ITMS NM报文不允许休眠(0x41C)" ;
VAL_ 1361 VIU_FL_NMNotSleep_BYTE2BIT5 0 "Inactive" 1 "BCU NM报文不允许休眠(0x425)" ;
VAL_ 1361 VIU_FL_NMNotSleep_BYTE2BIT6 0 "Inactive" 1 "IBCU NM报文不允许休眠(0x420)" ;
VAL_ 1361 VIU_FL_NMNotSleep_BYTE2BIT7 0 "Inactive" 1 "RBM NM报文不允许休眠(0x42B)" ;
VAL_ 1361 VIU_FL_NMNotSleep_BYTE3BIT0 0 "Inactive" 1 "ACR_FR NM报文不允许休眠(0x449)" ;
VAL_ 1361 VIU_FL_NMNotSleep_BYTE3BIT1 0 "Inactive" 1 "ACR_FL NM报文不允许休眠(0x448)" ;
VAL_ 1361 VIU_FL_NMNotSleep_BYTE3BIT2 0 "Inactive" 1 "EDC NM报文不允许休眠(0x411)" ;
VAL_ 1361 VIU_FL_NMNotSleep_BYTE3BIT3 0 "Inactive" 1 "TBOX NM报文不允许休眠(0x407)" ;
VAL_ 1361 VIU_FL_NMNotSleep_BYTE3BIT4 0 "Inactive" 1 "VIU_R NM报文不允许休眠(0x46A)" ;
VAL_ 1361 VIU_FL_NMNotSleep_BYTE3BIT5 0 "Inactive" 1 "C2 NM报文不允许休眠(0x450)" ;
VAL_ 1361 VIU_FL_NMNotSleep_BYTE3BIT6 0 "Inactive" 1 "HCM NM报文不允许休眠(0x484)" ;
VAL_ 1361 VIU_FL_NMNotSleep_BYTE3BIT7 0 "Inactive" 1 "RCM NM报文不允许休眠(0x481)" ;
VAL_ 1361 VIU_FL_NMNotSleep_BYTE4BIT0 0 "Inactive" 1 "NFC_E NM报文不允许休眠(0x44A)" ;
VAL_ 1361 VIU_FL_NMNotSleep_BYTE4BIT1 0 "Inactive" 1 "NFC_S NM报文不允许休眠(0x44B)" ;
VAL_ 1361 VIU_FL_NMNotSleep_BYTE4BIT2 0 "Inactive" 1 "FC NM报文不允许休眠(0x451)" ;
VAL_ 1361 VIU_FL_NMNotSleep_BYTE4BIT3 0 "Inactive" 1 "FR_L NM报文不允许休眠(0x44D)" ;
VAL_ 1361 VIU_FL_NMNotSleep_BYTE4BIT4 0 "Inactive" 1 "RLR_L NM报文不允许休眠(0x458)" ;
VAL_ 1361 VIU_FL_NMNotSleep_BYTE4BIT5 0 "Inactive" 1 "RRR_LNM报文不允许休眠(0x459)" ;
VAL_ 1361 VIU_FL_NMNotSleep_BYTE4BIT6 0 "Inactive" 1 "INS NM报文不允许休眠(0x45A)" ;
VAL_ 1361 VIU_FL_NMNotSleep_BYTE4BIT7 0 "Inactive" 1 "VIU_FR NM报文不允许休眠(0x40D)" ;
VAL_ 1361 VIU_FL_NMNotSleep_BYTE5BIT0 0 "Inactive" 1 "FLR NM报文不允许休眠(0x457)" ;
VAL_ 1361 VIU_FL_NMNotSleep_BYTE5BIT1 0 "Inactive" 1 "FRR NM报文不允许休眠(0x456)" ;
VAL_ 1361 VIU_FL_NMNotSleep_BYTE5BIT2 0 "Inactive" 1 "RLR NM报文不允许休眠(0x454)" ;
VAL_ 1361 VIU_FL_NMNotSleep_BYTE5BIT3 0 "Inactive" 1 "RRR NM报文不允许休眠(0x455)" ;
VAL_ 1361 VIU_FL_NMNotSleep_BYTE5BIT4 0 "Inactive" 1 "FGIPU NM报文不允许休眠(0x430)" ;
VAL_ 1361 VIU_FL_NMNotSleep_BYTE5BIT5 0 "Inactive" 1 "EMS NM报文不允许休眠(0x431)" ;
VAL_ 1361 VIU_FL_NMNotSleep_BYTE5BIT6 0 "Inactive" 1 "FMIPU NM报文不允许休眠(0x432)" ;
VAL_ 1361 VIU_FL_NMNotSleep_BYTE5BIT7 0 "Inactive" 1 "RMIPU NM报文不允许休眠(0x433)" ;
VAL_ 1361 VIU_FL_NMNotSleep_BYTE6BIT0 0 "Inactive" 1 "BLE NM不允许休眠(0x40E)" ;
VAL_ 1361 VIU_FL_NMNotSleep_BYTE6BIT1 0 "Inactive" 1 "智能表面(IS) NM报文不允许休眠(0x46D)" ;
VAL_ 1361 VIU_FL_NMNotSleep_BYTE6BIT2 0 "Inactive" 1 "触控面板(TP) NM报文不允许休眠(0x46C)" ;
VAL_ 1361 VIU_FL_NMNotSleep_BYTE6BIT3 0 "Inactive" 1 "HUD NM报文不允许休眠(0x461)" ;
VAL_ 1361 VIU_FL_NMNotSleep_BYTE6BIT4 0 "Inactive" 1 "电子外后视镜左屏 NM报文不允许休眠(0x462)" ;
VAL_ 1361 VIU_FL_NMNotSleep_BYTE6BIT5 0 "Inactive" 1 "电子外后视镜右屏 NM报文不允许休眠(0x463)" ;
VAL_ 1361 VIU_FL_NMNotSleep_BYTE6BIT6 0 "Inactive" 1 "流媒体后视镜 NM报文不允许休眠(0x464)" ;
VAL_ 1361 VIU_FL_NMNotSleep_BYTE6BIT7 0 "Inactive" 1 "外置功放 NM报文不允许休眠(0x423)" ;
VAL_ 1361 VIU_FL_NMNotSleep_BYTE7BIT0 0 "Inactive" 1 "FR NM报文不允许休眠(0x453)" ;
VAL_ 1361 VIU_FL_NMNotSleep_BYTE7BIT1 0 "Inactive" 1 "PDU/OBC NM报文不允许休眠(0x434)" ;
VAL_ 1361 VIU_FL_NMNotSleep_BYTE7BIT2 0 "Inactive" 1 "CTMU NM报文不允许休眠(0x45E)" ;
VAL_ 1361 VIU_FL_NMNotSleep_BYTE7BIT3 0 "Inactive" 1 "ISD NM报文不允许休眠(0x482)" ;
VAL_ 1361 VIU_FL_NMNotSleep_BYTE7BIT4 0 "Inactive" 1 "DPEU NM报文不允许休眠(0x436)" ;
VAL_ 1361 VIU_FL_NMNotSleep_BYTE7BIT5 0 "Inactive" 1 "IPUMP NM报文不允许休眠(0x495)" ;
VAL_ 1361 VIU_FL_NMNotSleep_BYTE7BIT6 0 "Inactive" 1 "ECDC NM报文不允许休眠(0x45D)" ;
VAL_ 1361 VIU_FL_NMNotSleep_BYTE7BIT7 0 "Inactive" 1 "diag CAN 不允许休眠" ;
VAL_ 1369 VIU_FR_NMNotSleep_BYTE2BIT0 0 "Inactive" 1 "VIU_FL NM报文不允许休眠(0x40C)" ;
VAL_ 1369 VIU_FR_NMNotSleep_BYTE2BIT1 0 "Inactive" 1 "VMC NM报文不允许休眠(0x45C)" ;
VAL_ 1369 VIU_FR_NMNotSleep_BYTE2BIT2 0 "Inactive" 1 "WLCM NM报文不允许休眠(0x471)" ;
VAL_ 1369 VIU_FR_NMNotSleep_BYTE2BIT3 0 "Inactive" 1 "PMU NM报文不允许休眠(0x472)" ;
VAL_ 1369 VIU_FR_NMNotSleep_BYTE2BIT4 0 "Inactive" 1 "ITMS NM报文不允许休眠(0x41C)" ;
VAL_ 1369 VIU_FR_NMNotSleep_BYTE2BIT5 0 "Inactive" 1 "BCU NM报文不允许休眠(0x425)" ;
VAL_ 1369 VIU_FR_NMNotSleep_BYTE2BIT6 0 "Inactive" 1 "IBCU NM报文不允许休眠(0x420)" ;
VAL_ 1369 VIU_FR_NMNotSleep_BYTE2BIT7 0 "Inactive" 1 "RBM NM报文不允许休眠(0x42B)" ;
VAL_ 1369 VIU_FR_NMNotSleep_BYTE3BIT0 0 "Inactive" 1 "ACR_FR NM报文不允许休眠(0x449)" ;
VAL_ 1369 VIU_FR_NMNotSleep_BYTE3BIT1 0 "Inactive" 1 "ACR_FL NM报文不允许休眠(0x448)" ;
VAL_ 1369 VIU_FR_NMNotSleep_BYTE3BIT2 0 "Inactive" 1 "EDC NM报文不允许休眠(0x411)" ;
VAL_ 1369 VIU_FR_NMNotSleep_BYTE3BIT3 0 "Inactive" 1 "TBOX NM报文不允许休眠(0x407)" ;
VAL_ 1369 VIU_FR_NMNotSleep_BYTE3BIT4 0 "Inactive" 1 "VIU_R NM报文不允许休眠(0x46A)" ;
VAL_ 1369 VIU_FR_NMNotSleep_BYTE3BIT5 0 "Inactive" 1 "C2 NM报文不允许休眠(0x450)" ;
VAL_ 1369 VIU_FR_NMNotSleep_BYTE3BIT6 0 "Inactive" 1 "HCM NM报文不允许休眠(0x484)" ;
VAL_ 1369 VIU_FR_NMNotSleep_BYTE3BIT7 0 "Inactive" 1 "RCM NM报文不允许休眠(0x481)" ;
VAL_ 1369 VIU_FR_NMNotSleep_BYTE4BIT0 0 "Inactive" 1 "NFC_E NM报文不允许休眠(0x44A)" ;
VAL_ 1369 VIU_FR_NMNotSleep_BYTE4BIT1 0 "Inactive" 1 "NFC_S NM报文不允许休眠(0x44B)" ;
VAL_ 1369 VIU_FR_NMNotSleep_BYTE4BIT2 0 "Inactive" 1 "FC NM报文不允许休眠(0x451)" ;
VAL_ 1369 VIU_FR_NMNotSleep_BYTE4BIT3 0 "Inactive" 1 "FR_L NM报文不允许休眠(0x44D)" ;
VAL_ 1369 VIU_FR_NMNotSleep_BYTE4BIT4 0 "Inactive" 1 "RLR_L NM报文不允许休眠(0x458)" ;
VAL_ 1369 VIU_FR_NMNotSleep_BYTE4BIT5 0 "Inactive" 1 "RRR_LNM报文不允许休眠(0x459)" ;
VAL_ 1369 VIU_FR_NMNotSleep_BYTE4BIT6 0 "Inactive" 1 "INS NM报文不允许休眠(0x45A)" ;
VAL_ 1369 VIU_FR_NMNotSleep_BYTE4BIT7 0 "Inactive" 1 "VIU_FR NM报文不允许休眠(0x40D)" ;
VAL_ 1369 VIU_FR_NMNotSleep_BYTE5BIT0 0 "Inactive" 1 "FLR NM报文不允许休眠(0x457)" ;
VAL_ 1369 VIU_FR_NMNotSleep_BYTE5BIT1 0 "Inactive" 1 "FRR NM报文不允许休眠(0x456)" ;
VAL_ 1369 VIU_FR_NMNotSleep_BYTE5BIT2 0 "Inactive" 1 "RLR NM报文不允许休眠(0x454)" ;
VAL_ 1369 VIU_FR_NMNotSleep_BYTE5BIT3 0 "Inactive" 1 "RRR NM报文不允许休眠(0x455)" ;
VAL_ 1369 VIU_FR_NMNotSleep_BYTE5BIT4 0 "Inactive" 1 "FGIPU NM报文不允许休眠(0x430)" ;
VAL_ 1369 VIU_FR_NMNotSleep_BYTE5BIT5 0 "Inactive" 1 "EMS NM报文不允许休眠(0x431)" ;
VAL_ 1369 VIU_FR_NMNotSleep_BYTE5BIT6 0 "Inactive" 1 "FMIPU NM报文不允许休眠(0x432)" ;
VAL_ 1369 VIU_FR_NMNotSleep_BYTE5BIT7 0 "Inactive" 1 "RMIPU NM报文不允许休眠(0x433)" ;
VAL_ 1369 VIU_FR_NMNotSleep_BYTE6BIT0 0 "Inactive" 1 "BLE NM不允许休眠(0x40E)" ;
VAL_ 1369 VIU_FR_NMNotSleep_BYTE6BIT1 0 "Inactive" 1 "智能表面(IS) NM报文不允许休眠(0x46D)" ;
VAL_ 1369 VIU_FR_NMNotSleep_BYTE6BIT2 0 "Inactive" 1 "触控面板(TP) NM报文不允许休眠(0x46C)" ;
VAL_ 1369 VIU_FR_NMNotSleep_BYTE6BIT3 0 "Inactive" 1 "HUD NM报文不允许休眠(0x461)" ;
VAL_ 1369 VIU_FR_NMNotSleep_BYTE6BIT4 0 "Inactive" 1 "电子外后视镜左屏 NM报文不允许休眠(0x462)" ;
VAL_ 1369 VIU_FR_NMNotSleep_BYTE6BIT5 0 "Inactive" 1 "电子外后视镜右屏 NM报文不允许休眠(0x463)" ;
VAL_ 1369 VIU_FR_NMNotSleep_BYTE6BIT6 0 "Inactive" 1 "流媒体后视镜 NM报文不允许休眠(0x464)" ;
VAL_ 1369 VIU_FR_NMNotSleep_BYTE6BIT7 0 "Inactive" 1 "外置功放 NM报文不允许休眠(0x423)" ;
VAL_ 1369 VIU_FR_NMNotSleep_BYTE7BIT0 0 "Inactive" 1 "FR NM报文不允许休眠(0x453)" ;
VAL_ 1369 VIU_FR_NMNotSleep_BYTE7BIT1 0 "Inactive" 1 "PDU/OBC NM报文不允许休眠(0x434)" ;
VAL_ 1369 VIU_FR_NMNotSleep_BYTE7BIT2 0 "Inactive" 1 "CTMU NM报文不允许休眠(0x45E)" ;
VAL_ 1369 VIU_FR_NMNotSleep_BYTE7BIT3 0 "Inactive" 1 "ISD NM报文不允许休眠(0x482)" ;
VAL_ 1369 VIU_FR_NMNotSleep_BYTE7BIT4 0 "Inactive" 1 "DPEU NM报文不允许休眠(0x436)" ;
VAL_ 1369 VIU_FR_NMNotSleep_BYTE7BIT5 0 "Inactive" 1 "IPUMP NM报文不允许休眠(0x495)" ;
VAL_ 1369 VIU_FR_NMNotSleep_BYTE7BIT6 0 "Inactive" 1 "ECDC NM报文不允许休眠(0x45D)" ;
VAL_ 1369 VIU_FR_NMNotSleep_BYTE7BIT7 0 "Inactive" 1 "diag CAN 不允许休眠" ;
VAL_ 1396 EDC_NotSleep_Android 0 "Inactive" 1 "安卓不允许休眠(1~16）" ;
VAL_ 1396 EDC_NotSleep_Android_other 0 "Inactive" 1 "安卓不允许休眠—其他" ;
VAL_ 1396 EDC_NotSleep_BYTE5BIT0 0 "Inactive" 1 "QNX不允许休眠(1~4)" ;
VAL_ 1396 EDC_NotSleep_BYTE6BIT0 0 "Inactive" 1 "外置功放 NM报文不允许休眠" ;
VAL_ 1396 EDC_NotSleep_BYTE6BIT1 0 "Inactive" 1 "TBOX NM报文不允许休眠" ;
VAL_ 1396 EDC_NotSleep_BYTE6BIT2 0 "Inactive" 1 "4G不允许休眠" ;
VAL_ 1396 EDC_NotSleep_BYTE6BIT3 0 "Inactive" 1 "VIU_R NM报文不允许休眠" ;
VAL_ 1396 EDC_NotSleep_BYTE6BIT4 0 "Inactive" 1 "其他条件（包含外部/远程/本地功能请求及诊断模式）" ;
VAL_ 1396 EDC_NotSleep_BYTE7BIT0 0 "Inactive" 1 "电源档位为ON档" ;
VAL_ 1396 EDC_NotSleep_BYTE7BIT1 0 "Inactive" 1 "VIU_FL NM报文不允许休眠" ;
VAL_ 1396 EDC_NotSleep_BYTE7BIT2 0 "Inactive" 1 "智能表面(IS) NM报文不允许休眠(0x46D)" ;
VAL_ 1396 EDC_NotSleep_BYTE7BIT3 0 "Inactive" 1 "触控面板(TP) NM报文不允许休眠(0x46C)" ;
VAL_ 1396 EDC_NotSleep_BYTE7BIT4 0 "Inactive" 1 "HUD NM报文不允许休眠(0x461)" ;
VAL_ 1396 EDC_NotSleep_BYTE7BIT5 0 "Inactive" 1 "电子外后视镜左屏 NM报文不允许休眠(0x462)" ;
VAL_ 1396 EDC_NotSleep_BYTE7BIT6 0 "Inactive" 1 "电子外后视镜右屏 NM报文不允许休眠(0x463)" ;
VAL_ 1396 EDC_NotSleep_BYTE7BIT7 0 "Inactive" 1 "流媒体后视镜 NM报文不允许休眠(0x464)" ;
VAL_ 1396 EDC_wakeup_BYTE2BIT0 0 "Inactive" 1 "外置功放 NM报文唤醒" ;
VAL_ 1396 EDC_wakeup_BYTE2BIT1 0 "Inactive" 1 "TBOX NM报文唤醒" ;
VAL_ 1396 EDC_wakeup_BYTE2BIT2 0 "Inactive" 1 "4G/5G唤醒" ;
VAL_ 1396 EDC_wakeup_BYTE2BIT3 0 "Inactive" 1 "VIU_R NM报文唤醒" ;
VAL_ 1396 EDC_WakeUp_BYTE3BIT0 0 "Inactive" 1 "电源档位为ON档" ;
VAL_ 1396 EDC_WakeUp_BYTE3BIT1 0 "Inactive" 1 "VIU_FL NM报文唤醒" ;
VAL_ 1396 EDC_WakeUp_BYTE3BIT2 0 "Inactive" 1 "智能表面(IS) NM报文唤醒(0x46D)" ;
VAL_ 1396 EDC_WakeUp_BYTE3BIT3 0 "Inactive" 1 "触控面板(TP) NM报文唤醒(0x46C)" ;
VAL_ 1396 EDC_WakeUp_BYTE3BIT4 0 "Inactive" 1 "HUD NM报文唤醒(0x461)" ;
VAL_ 1396 EDC_WakeUp_BYTE3BIT5 0 "Inactive" 1 "电子外后视镜左屏 NM报文唤醒(0x462)" ;
VAL_ 1396 EDC_WakeUp_BYTE3BIT6 0 "Inactive" 1 "电子外后视镜右屏 NM报文唤醒(0x463)" ;
VAL_ 1396 EDC_WakeUp_BYTE3BIT7 0 "Inactive" 1 "流媒体后视镜 NM报文唤醒(0x464)" ;
VAL_ 1396 EDC_NotSleep_BYTE1BIT4 0 "Inactive" 1 "VIU_FR NM报文不允许休眠(0x40D)" ;
VAL_ 1396 EDC_NotSleep_BYTE1BIT5 0 "Inactive" 1 "EVCC NM报文不允许休眠(0x4A9)" ;
VAL_ 1396 EDC_NotSleep_BYTE1BIT6 0 "Inactive" 1 "C2 NM报文不允许休眠(0x450)" ;
VAL_ 1396 EDC_NotSleep_BYTE1BIT7 0 "Inactive" 1 "IMU不允许休眠" ;
VAL_ 1396 EDC_wakeup_BYTE2BIT4 0 "Inactive" 1 "VIU_FR NM报文唤醒(0x40D)" ;
VAL_ 1396 EDC_wakeup_BYTE2BIT5 0 "Inactive" 1 "EVCC NM报文唤醒(0x4A9)" ;
VAL_ 1396 EDC_wakeup_BYTE2BIT6 0 "Inactive" 1 "C2 NM报文唤醒(0x450)" ;
VAL_ 1396 EDC_wakeup_BYTE2BIT7 0 "Inactive" 1 "IMU唤醒" ;
VERSION "sin DBC editor"

NS_ :
    STR_64
    BA_SETDATA_REF_
    BA_SETDATA_SGTYPE_

BS_:

BU_: VIU_FL AMP EDC VIU_FR TBOX IP EVCC ICDC

BO_ 1407 VIU_FL_57F: 16 VIU_FL
    SG_ VIU_FL_NotSleep_Index : 87|8@0+ (1,0) [0|255] "" Vector__XXX
    SG_ VIU_FL_NotSleep_IndexTotal : 79|8@0+ (1,0) [0|255] "" Vector__XXX
    SG_ VIU_FL_NotSleep_Nmnumber : 71|8@0+ (1,0) [0|255] "" Vector__XXX
    SG_ VIU_FL_NotSleep_serviceNumber : 95|32@0+ (1,0) [0|4.29497e+09] "" Vector__XXX
    SG_ VIU_FL_WakeUp_BYTE0BIT0 : 0|1@0+ (1,0) [0|1] "" Vector__XXX
    SG_ VIU_FL_WakeUp_BYTE0BIT1 : 1|1@0+ (1,0) [0|1] "" Vector__XXX
    SG_ VIU_FL_WakeUp_BYTE0BIT2 : 2|1@0+ (1,0) [0|1] "" Vector__XXX
    SG_ VIU_FL_WakeUp_BYTE0BIT3 : 3|1@0+ (1,0) [0|1] "" Vector__XXX
    SG_ VIU_FL_WakeUp_BYTE0BIT4 : 4|1@0+ (1,0) [0|1] "" Vector__XXX
    SG_ VIU_FL_WakeUp_BYTE0BIT5 : 5|1@0+ (1,0) [0|1] "" Vector__XXX
    SG_ VIU_FL_WakeUp_BYTE0BIT6 : 6|1@0+ (1,0) [0|1] "" Vector__XXX
    SG_ VIU_FL_WakeUp_BYTE0BIT7 : 7|1@0+ (1,0) [0|1] "" Vector__XXX
    SG_ VIU_FL_WakeUp_BYTE1BIT0 : 8|1@0+ (1,0) [0|1] "" Vector__XXX
    SG_ VIU_FL_WakeUp_BYTE1BIT1 : 9|1@0+ (1,0) [0|1] "" Vector__XXX
    SG_ VIU_FL_WakeUp_BYTE1BIT2 : 10|1@0+ (1,0) [0|1] "" Vector__XXX
    SG_ VIU_FL_WakeUp_BYTE1BIT3 : 11|1@0+ (1,0) [0|1] "" Vector__XXX
    SG_ VIU_FL_WakeUp_BYTE1BIT4 : 12|1@0+ (1,0) [0|1] "" Vector__XXX
    SG_ VIU_FL_WakeUp_BYTE1BIT5 : 13|1@0+ (1,0) [0|1] "" Vector__XXX
    SG_ VIU_FL_WakeUp_BYTE1BIT6 : 14|1@0+ (1,0) [0|1] "" Vector__XXX
    SG_ VIU_FL_WakeUp_BYTE1BIT7 : 15|1@0+ (1,0) [0|1] "" Vector__XXX
    SG_ VIU_FL_WakeUp_BYTE2BIT0 : 16|1@0+ (1,0) [0|1] "" Vector__XXX
    SG_ VIU_FL_WakeUp_BYTE2BIT1 : 17|1@0+ (1,0) [0|1] "" Vector__XXX
    SG_ VIU_FL_WakeUp_BYTE2BIT2 : 18|1@0+ (1,0) [0|1] "" Vector__XXX
    SG_ VIU_FL_WakeUp_BYTE2BIT3 : 19|1@0+ (1,0) [0|1] "" Vector__XXX
    SG_ VIU_FL_WakeUp_BYTE2BIT4 : 20|1@0+ (1,0) [0|1] "" Vector__XXX
    SG_ VIU_FL_WakeUp_BYTE2BIT5 : 21|1@0+ (1,0) [0|1] "" Vector__XXX
    SG_ VIU_FL_WakeUp_BYTE2BIT6 : 22|1@0+ (1,0) [0|1] "" Vector__XXX
    SG_ VIU_FL_WakeUp_BYTE2BIT7 : 23|1@0+ (1,0) [0|1] "" Vector__XXX
    SG_ VIU_FL_WakeUp_BYTE3BIT0 : 24|1@0+ (1,0) [0|1] "" Vector__XXX
    SG_ VIU_FL_WakeUp_BYTE3BIT1 : 25|1@0+ (1,0) [0|1] "" Vector__XXX
    SG_ VIU_FL_WakeUp_BYTE3BIT2 : 26|1@0+ (1,0) [0|1] "" Vector__XXX
    SG_ VIU_FL_WakeUp_BYTE3BIT3 : 27|1@0+ (1,0) [0|1] "" Vector__XXX
    SG_ VIU_FL_WakeUp_BYTE3BIT4 : 28|1@0+ (1,0) [0|1] "" Vector__XXX
    SG_ VIU_FL_WakeUp_BYTE3BIT5 : 29|1@0+ (1,0) [0|1] "" Vector__XXX
    SG_ VIU_FL_WakeUp_BYTE3BIT6 : 30|1@0+ (1,0) [0|1] "" Vector__XXX
    SG_ VIU_FL_WakeUp_BYTE3BIT7 : 31|1@0+ (1,0) [0|1] "" Vector__XXX
    SG_ VIU_FL_WakeUp_BYTE4BIT0 : 32|1@0+ (1,0) [0|1] "" Vector__XXX
    SG_ VIU_FL_WakeUp_BYTE4BIT1 : 33|1@0+ (1,0) [0|1] "" Vector__XXX
    SG_ VIU_FL_WakeUp_BYTE4BIT2 : 34|1@0+ (1,0) [0|1] "" Vector__XXX
    SG_ VIU_FL_WakeUp_BYTE4BIT3 : 35|1@0+ (1,0) [0|1] "" Vector__XXX
    SG_ VIU_FL_WakeUp_BYTE4BIT4 : 36|1@0+ (1,0) [0|1] "" Vector__XXX
    SG_ VIU_FL_WakeUp_BYTE4BIT5 : 37|1@0+ (1,0) [0|1] "" Vector__XXX
    SG_ VIU_FL_WakeUp_BYTE4BIT6 : 38|1@0+ (1,0) [0|1] "" Vector__XXX
    SG_ VIU_FL_WakeUp_BYTE4BIT7 : 39|1@0+ (1,0) [0|1] "" Vector__XXX
    SG_ VIU_FL_WakeUp_BYTE5BIT0 : 40|1@0+ (1,0) [0|1] "" Vector__XXX
    SG_ VIU_FL_WakeUp_BYTE5BIT1 : 41|1@0+ (1,0) [0|1] "" Vector__XXX
    SG_ VIU_FL_WakeUp_BYTE5BIT2 : 42|1@0+ (1,0) [0|1] "" Vector__XXX
    SG_ VIU_FL_WakeUp_BYTE5BIT3 : 43|1@0+ (1,0) [0|1] "" Vector__XXX
    SG_ VIU_FL_WakeUp_BYTE5BIT4 : 44|1@0+ (1,0) [0|1] "" Vector__XXX
    SG_ VIU_FL_WakeUp_BYTE5BIT5 : 45|1@0+ (1,0) [0|1] "" Vector__XXX
    SG_ VIU_FL_WakeUp_BYTE5BIT6 : 46|1@0+ (1,0) [0|1] "" Vector__XXX
    SG_ VIU_FL_WakeUp_BYTE5BIT7 : 47|1@0+ (1,0) [0|1] "" Vector__XXX
    SG_ VIU_FL_WakeUp_BYTE6BIT0 : 48|1@0+ (1,0) [0|1] "" Vector__XXX
    SG_ VIU_FL_WakeUp_BYTE6BIT1 : 49|1@0+ (1,0) [0|1] "" Vector__XXX
    SG_ VIU_FL_WakeUp_BYTE6BIT2 : 50|1@0+ (1,0) [0|1] "" Vector__XXX
    SG_ VIU_FL_WakeUp_BYTE6BIT3 : 51|1@0+ (1,0) [0|1] "" Vector__XXX
    SG_ VIU_FL_WakeUp_BYTE6BIT4 : 52|1@0+ (1,0) [0|1] "" Vector__XXX
    SG_ VIU_FL_WakeUp_BYTE6BIT5 : 53|1@0+ (1,0) [0|1] "" Vector__XXX
    SG_ VIU_FL_WakeUp_BYTE6BIT6 : 54|1@0+ (1,0) [0|1] "" Vector__XXX
    SG_ VIU_FL_WakeUp_BYTE6BIT7 : 55|1@0+ (1,0) [0|1] "" Vector__XXX
    SG_ VIU_FL_WakeUp_BYTE7BIT0 : 56|1@0+ (1,0) [0|1] "" Vector__XXX
    SG_ VIU_FL_WakeUp_BYTE7BIT1 : 57|1@0+ (1,0) [0|1] "" Vector__XXX
    SG_ VIU_FL_WakeUp_BYTE7BIT2 : 58|1@0+ (1,0) [0|1] "" Vector__XXX
    SG_ VIU_FL_WakeUp_BYTE7BIT3 : 59|1@0+ (1,0) [0|1] "" Vector__XXX
    SG_ VIU_FL_WakeUp_BYTE7BIT4 : 60|1@0+ (1,0) [0|1] "" Vector__XXX
    SG_ VIU_FL_WakeUp_BYTE7BIT5 : 61|1@0+ (1,0) [0|1] "" Vector__XXX
    SG_ VIU_FL_WakeUp_BYTE7BIT6 : 62|1@0+ (1,0) [0|1] "" Vector__XXX
    SG_ VIU_FL_WakeUp_BYTE7BIT7 : 63|1@0+ (1,0) [0|1] "" Vector__XXX
    SG_ VIU_FL_WakeUp_BYTE15BIT0 : 120|1@0+ (1,0) [0|1] "" Vector__XXX
    SG_ VIU_FL_WakeUp_BYTE15BIT1 : 121|1@0+ (1,0) [0|1] "" Vector__XXX

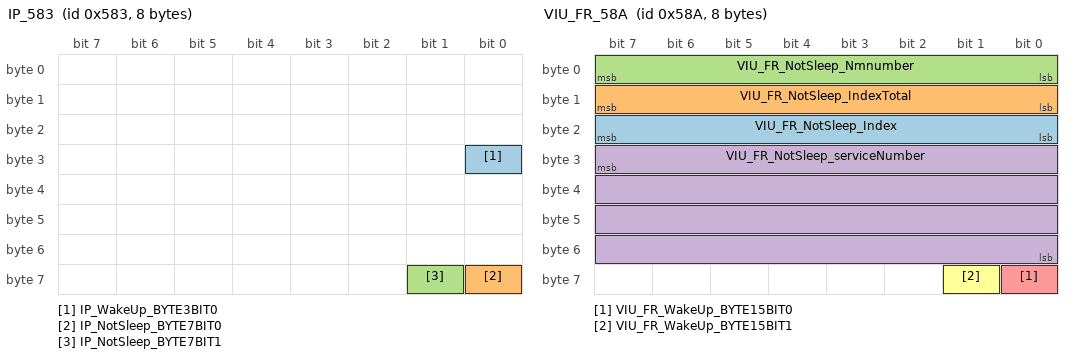
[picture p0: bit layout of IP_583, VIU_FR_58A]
BO_ 1411 IP_583: 8 IP
    SG_ IP_WakeUp_BYTE3BIT0 : 24|1@0+ (1,0) [0|1] "" VIU_FL,VIU_FR
    SG_ IP_NotSleep_BYTE7BIT0 : 56|1@0+ (1,0) [0|1] "" VIU_FL,VIU_FR
    SG_ IP_NotSleep_BYTE7BIT1 : 57|1@0+ (1,0) [0|1] "" VIU_FL,VIU_FR

BO_ 1417 VIU_FR_589: 8 VIU_FR
    SG_ VIU_FR_WakeUp_BYTE0BIT0 : 0|1@0+ (1,0) [0|1] "" VIU_FL
    SG_ VIU_FR_WakeUp_BYTE0BIT1 : 1|1@0+ (1,0) [0|1] "" VIU_FL
    SG_ VIU_FR_WakeUp_BYTE0BIT2 : 2|1@0+ (1,0) [0|1] "" VIU_FL
    SG_ VIU_FR_WakeUp_BYTE0BIT3 : 3|1@0+ (1,0) [0|1] "" VIU_FL
    SG_ VIU_FR_WakeUp_BYTE0BIT4 : 4|1@0+ (1,0) [0|1] "" VIU_FL
    SG_ VIU_FR_WakeUp_BYTE0BIT5 : 5|1@0+ (1,0) [0|1] "" VIU_FL
    SG_ VIU_FR_WakeUp_BYTE0BIT6 : 6|1@0+ (1,0) [0|1] "" VIU_FL
    SG_ VIU_FR_WakeUp_BYTE0BIT7 : 7|1@0+ (1,0) [0|1] "" VIU_FL
    SG_ VIU_FR_WakeUp_BYTE1BIT0 : 8|1@0+ (1,0) [0|1] "" VIU_FL
    SG_ VIU_FR_WakeUp_BYTE1BIT1 : 9|1@0+ (1,0) [0|1] "" VIU_FL
    SG_ VIU_FR_WakeUp_BYTE1BIT2 : 10|1@0+ (1,0) [0|1] "" VIU_FL
    SG_ VIU_FR_WakeUp_BYTE1BIT3 : 11|1@0+ (1,0) [0|1] "" VIU_FL
    SG_ VIU_FR_WakeUp_BYTE1BIT4 : 12|1@0+ (1,0) [0|1] "" VIU_FL
    SG_ VIU_FR_WakeUp_BYTE1BIT5 : 13|1@0+ (1,0) [0|1] "" VIU_FL
    SG_ VIU_FR_WakeUp_BYTE1BIT6 : 14|1@0+ (1,0) [0|1] "" VIU_FL
    SG_ VIU_FR_WakeUp_BYTE1BIT7 : 15|1@0+ (1,0) [0|1] "" VIU_FL
    SG_ VIU_FR_WakeUp_BYTE2BIT0 : 16|1@0+ (1,0) [0|1] "" VIU_FL
    SG_ VIU_FR_WakeUp_BYTE2BIT1 : 17|1@0+ (1,0) [0|1] "" VIU_FL
    SG_ VIU_FR_WakeUp_BYTE2BIT2 : 18|1@0+ (1,0) [0|1] "" VIU_FL
    SG_ VIU_FR_WakeUp_BYTE2BIT3 : 19|1@0+ (1,0) [0|1] "" VIU_FL
    SG_ VIU_FR_WakeUp_BYTE2BIT4 : 20|1@0+ (1,0) [0|1] "" VIU_FL
    SG_ VIU_FR_WakeUp_BYTE2BIT5 : 21|1@0+ (1,0) [0|1] "" VIU_FL
    SG_ VIU_FR_WakeUp_BYTE2BIT6 : 22|1@0+ (1,0) [0|1] "" VIU_FL
    SG_ VIU_FR_WakeUp_BYTE2BIT7 : 23|1@0+ (1,0) [0|1] "" VIU_FL
    SG_ VIU_FR_WakeUp_BYTE3BIT0 : 24|1@0+ (1,0) [0|1] "" VIU_FL
    SG_ VIU_FR_WakeUp_BYTE3BIT1 : 25|1@0+ (1,0) [0|1] "" VIU_FL
    SG_ VIU_FR_WakeUp_BYTE3BIT2 : 26|1@0+ (1,0) [0|1] "" VIU_FL
    SG_ VIU_FR_WakeUp_BYTE3BIT3 : 27|1@0+ (1,0) [0|1] "" VIU_FL
    SG_ VIU_FR_WakeUp_BYTE3BIT4 : 28|1@0+ (1,0) [0|1] "" VIU_FL
    SG_ VIU_FR_WakeUp_BYTE3BIT5 : 29|1@0+ (1,0) [0|1] "" VIU_FL
    SG_ VIU_FR_WakeUp_BYTE3BIT6 : 30|1@0+ (1,0) [0|1] "" VIU_FL
    SG_ VIU_FR_WakeUp_BYTE3BIT7 : 31|1@0+ (1,0) [0|1] "" VIU_FL
    SG_ VIU_FR_WakeUp_BYTE4BIT0 : 32|1@0+ (1,0) [0|1] "" VIU_FL
    SG_ VIU_FR_WakeUp_BYTE4BIT1 : 33|1@0+ (1,0) [0|1] "" VIU_FL
    SG_ VIU_FR_WakeUp_BYTE4BIT2 : 34|1@0+ (1,0) [0|1] "" VIU_FL
    SG_ VIU_FR_WakeUp_BYTE4BIT3 : 35|1@0+ (1,0) [0|1] "" VIU_FL
    SG_ VIU_FR_WakeUp_BYTE4BIT4 : 36|1@0+ (1,0) [0|1] "" VIU_FL
    SG_ VIU_FR_WakeUp_BYTE4BIT5 : 37|1@0+ (1,0) [0|1] "" VIU_FL
    SG_ VIU_FR_WakeUp_BYTE4BIT6 : 38|1@0+ (1,0) [0|1] "" VIU_FL
    SG_ VIU_FR_WakeUp_BYTE4BIT7 : 39|1@0+ (1,0) [0|1] "" VIU_FL
    SG_ VIU_FR_WakeUp_BYTE5BIT0 : 40|1@0+ (1,0) [0|1] "" VIU_FL
    SG_ VIU_FR_WakeUp_BYTE5BIT1 : 41|1@0+ (1,0) [0|1] "" VIU_FL
    SG_ VIU_FR_WakeUp_BYTE5BIT2 : 42|1@0+ (1,0) [0|1] "" VIU_FL
    SG_ VIU_FR_WakeUp_BYTE5BIT3 : 43|1@0+ (1,0) [0|1] "" VIU_FL
    SG_ VIU_FR_WakeUp_BYTE5BIT4 : 44|1@0+ (1,0) [0|1] "" VIU_FL
    SG_ VIU_FR_WakeUp_BYTE5BIT5 : 45|1@0+ (1,0) [0|1] "" VIU_FL
    SG_ VIU_FR_WakeUp_BYTE5BIT6 : 46|1@0+ (1,0) [0|1] "" VIU_FL
    SG_ VIU_FR_WakeUp_BYTE5BIT7 : 47|1@0+ (1,0) [0|1] "" VIU_FL
    SG_ VIU_FR_WakeUp_BYTE6BIT0 : 48|1@0+ (1,0) [0|1] "" VIU_FL
    SG_ VIU_FR_WakeUp_BYTE6BIT1 : 49|1@0+ (1,0) [0|1] "" VIU_FL
    SG_ VIU_FR_WakeUp_BYTE6BIT2 : 50|1@0+ (1,0) [0|1] "" VIU_FL
    SG_ VIU_FR_WakeUp_BYTE6BIT3 : 51|1@0+ (1,0) [0|1] "" VIU_FL
    SG_ VIU_FR_WakeUp_BYTE6BIT4 : 52|1@0+ (1,0) [0|1] "" VIU_FL
    SG_ VIU_FR_WakeUp_BYTE6BIT5 : 53|1@0+ (1,0) [0|1] "" VIU_FL
    SG_ VIU_FR_WakeUp_BYTE6BIT6 : 54|1@0+ (1,0) [0|1] "" VIU_FL
    SG_ VIU_FR_WakeUp_BYTE6BIT7 : 55|1@0+ (1,0) [0|1] "" VIU_FL
    SG_ VIU_FR_WakeUp_BYTE7BIT0 : 56|1@0+ (1,0) [0|1] "" VIU_FL
    SG_ VIU_FR_WakeUp_BYTE7BIT1 : 57|1@0+ (1,0) [0|1] "" VIU_FL
    SG_ VIU_FR_WakeUp_BYTE7BIT2 : 58|1@0+ (1,0) [0|1] "" VIU_FL
    SG_ VIU_FR_WakeUp_BYTE7BIT3 : 59|1@0+ (1,0) [0|1] "" VIU_FL
    SG_ VIU_FR_WakeUp_BYTE7BIT4 : 60|1@0+ (1,0) [0|1] "" VIU_FL
    SG_ VIU_FR_WakeUp_BYTE7BIT5 : 61|1@0+ (1,0) [0|1] "" VIU_FL
    SG_ VIU_FR_WakeUp_BYTE7BIT6 : 62|1@0+ (1,0) [0|1] "" VIU_FL
    SG_ VIU_FR_WakeUp_BYTE7BIT7 : 63|1@0+ (1,0) [0|1] "" VIU_FL

BO_ 1418 VIU_FR_58A: 8 VIU_FR
    SG_ VIU_FR_NotSleep_Index : 23|8@0+ (1,0) [0|255] "" VIU_FL
    SG_ VIU_FR_NotSleep_IndexTotal : 15|8@0+ (1,0) [0|255] "" VIU_FL
    SG_ VIU_FR_NotSleep_Nmnumber : 7|8@0+ (1,0) [0|255] "" VIU_FL
    SG_ VIU_FR_NotSleep_serviceNumber : 31|32@0+ (1,0) [0|4.29497e+09] "" VIU_FL
    SG_ VIU_FR_WakeUp_BYTE15BIT0 : 56|1@0+ (1,0) [0|1] "" VIU_FL
    SG_ VIU_FR_WakeUp_BYTE15BIT1 : 57|1@0+ (1,0) [0|1] "" VIU_FL

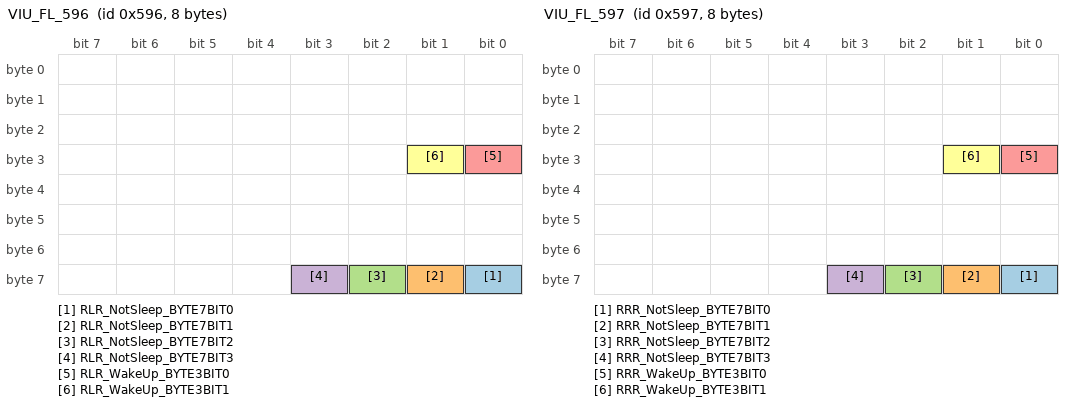
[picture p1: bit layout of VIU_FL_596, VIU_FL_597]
BO_ 1430 VIU_FL_596: 8 VIU_FL
    SG_ RLR_NotSleep_BYTE7BIT0 : 56|1@0+ (1,0) [0|1] "" VIU_FR
    SG_ RLR_NotSleep_BYTE7BIT1 : 57|1@0+ (1,0) [0|1] "" VIU_FR
    SG_ RLR_NotSleep_BYTE7BIT2 : 58|1@0+ (1,0) [0|1] "" VIU_FR
    SG_ RLR_NotSleep_BYTE7BIT3 : 59|1@0+ (1,0) [0|1] "" VIU_FR
    SG_ RLR_WakeUp_BYTE3BIT0 : 24|1@0+ (1,0) [0|1] "" VIU_FR
    SG_ RLR_WakeUp_BYTE3BIT1 : 25|1@0+ (1,0) [0|1] "" VIU_FR

BO_ 1431 VIU_FL_597: 8 VIU_FL
    SG_ RRR_NotSleep_BYTE7BIT0 : 56|1@0+ (1,0) [0|1] "" VIU_FR
    SG_ RRR_NotSleep_BYTE7BIT1 : 57|1@0+ (1,0) [0|1] "" VIU_FR
    SG_ RRR_NotSleep_BYTE7BIT2 : 58|1@0+ (1,0) [0|1] "" VIU_FR
    SG_ RRR_NotSleep_BYTE7BIT3 : 59|1@0+ (1,0) [0|1] "" VIU_FR
    SG_ RRR_WakeUp_BYTE3BIT0 : 24|1@0+ (1,0) [0|1] "" VIU_FR
    SG_ RRR_WakeUp_BYTE3BIT1 : 25|1@0+ (1,0) [0|1] "" VIU_FR

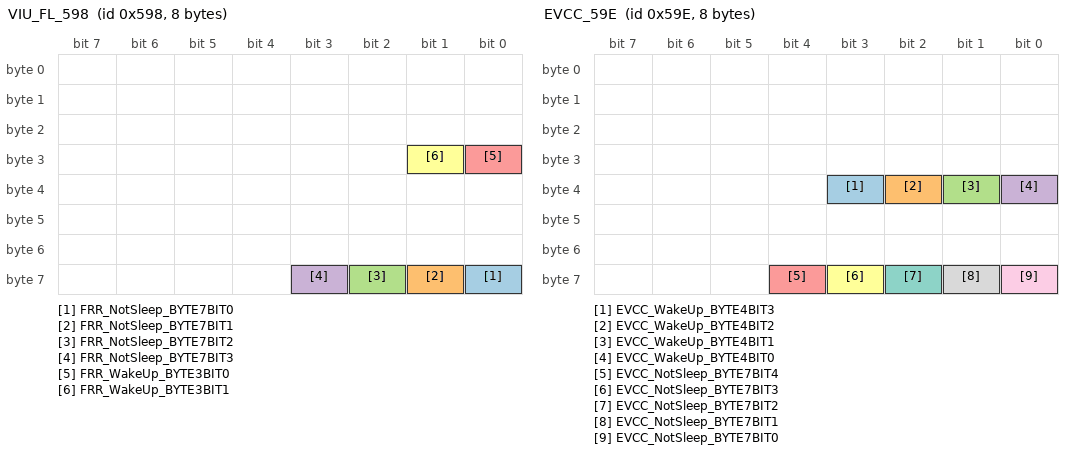
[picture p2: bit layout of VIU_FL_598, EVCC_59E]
BO_ 1432 VIU_FL_598: 8 VIU_FL
    SG_ FRR_NotSleep_BYTE7BIT0 : 56|1@0+ (1,0) [0|1] "" VIU_FR
    SG_ FRR_NotSleep_BYTE7BIT1 : 57|1@0+ (1,0) [0|1] "" VIU_FR
    SG_ FRR_NotSleep_BYTE7BIT2 : 58|1@0+ (1,0) [0|1] "" VIU_FR
    SG_ FRR_NotSleep_BYTE7BIT3 : 59|1@0+ (1,0) [0|1] "" VIU_FR
    SG_ FRR_WakeUp_BYTE3BIT0 : 24|1@0+ (1,0) [0|1] "" VIU_FR
    SG_ FRR_WakeUp_BYTE3BIT1 : 25|1@0+ (1,0) [0|1] "" VIU_FR

BO_ 1438 EVCC_59E: 8 EVCC
    SG_ EVCC_WakeUp_BYTE4BIT3 : 35|1@0+ (1,0) [0|1] "" VIU_FL
    SG_ EVCC_WakeUp_BYTE4BIT2 : 34|1@0+ (1,0) [0|1] "" VIU_FL
    SG_ EVCC_WakeUp_BYTE4BIT1 : 33|1@0+ (1,0) [0|1] "" VIU_FL
    SG_ EVCC_WakeUp_BYTE4BIT0 : 32|1@0+ (1,0) [0|1] "" VIU_FL
    SG_ EVCC_NotSleep_BYTE7BIT4 : 60|1@0+ (1,0) [0|1] "" VIU_FL
    SG_ EVCC_NotSleep_BYTE7BIT3 : 59|1@0+ (1,0) [0|1] "" VIU_FL
    SG_ EVCC_NotSleep_BYTE7BIT2 : 58|1@0+ (1,0) [0|1] "" VIU_FL
    SG_ EVCC_NotSleep_BYTE7BIT1 : 57|1@0+ (1,0) [0|1] "" VIU_FL
    SG_ EVCC_NotSleep_BYTE7BIT0 : 56|1@0+ (1,0) [0|1] "" VIU_FL

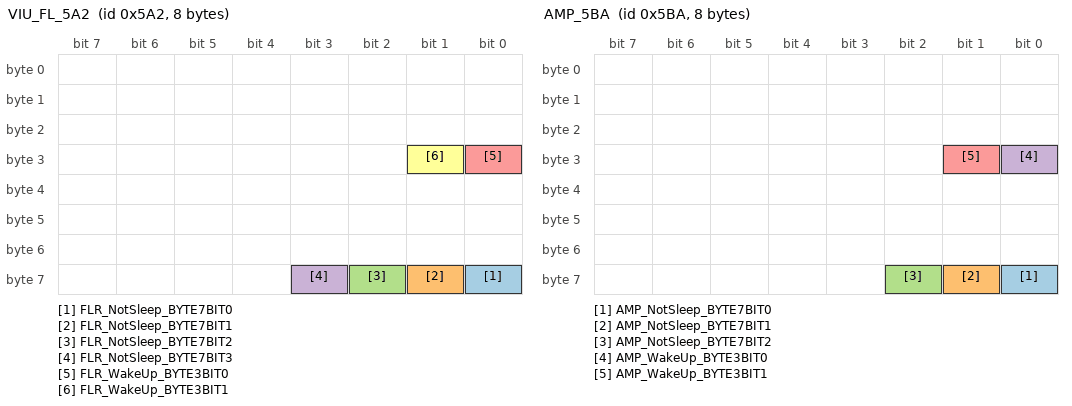
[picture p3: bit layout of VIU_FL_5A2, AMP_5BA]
BO_ 1442 VIU_FL_5A2: 8 VIU_FL
    SG_ FLR_NotSleep_BYTE7BIT0 : 56|1@0+ (1,0) [0|1] "" VIU_FR
    SG_ FLR_NotSleep_BYTE7BIT1 : 57|1@0+ (1,0) [0|1] "" VIU_FR
    SG_ FLR_NotSleep_BYTE7BIT2 : 58|1@0+ (1,0) [0|1] "" VIU_FR
    SG_ FLR_NotSleep_BYTE7BIT3 : 59|1@0+ (1,0) [0|1] "" VIU_FR
    SG_ FLR_WakeUp_BYTE3BIT0 : 24|1@0+ (1,0) [0|1] "" VIU_FR
    SG_ FLR_WakeUp_BYTE3BIT1 : 25|1@0+ (1,0) [0|1] "" VIU_FR

BO_ 1466 AMP_5BA: 8 AMP
    SG_ AMP_NotSleep_BYTE7BIT0 : 56|1@0+ (1,0) [0|1] "" EDC
    SG_ AMP_NotSleep_BYTE7BIT1 : 57|1@0+ (1,0) [0|1] "" EDC
    SG_ AMP_NotSleep_BYTE7BIT2 : 58|1@0+ (1,0) [0|1] "" EDC
    SG_ AMP_WakeUp_BYTE3BIT0 : 24|1@0+ (1,0) [0|1] "" EDC
    SG_ AMP_WakeUp_BYTE3BIT1 : 25|1@0+ (1,0) [0|1] "" EDC

BO_ 1471 EDC_5BF: 64 EDC
    SG_ mcuLogDataBytesSegment0 : 7|64@0+ (1,0) [0|255] "" VIU_FR,VIU_FL
    SG_ mcuLogDataBytesSegment1 : 71|64@0+ (1,0) [0|255] "" VIU_FR,VIU_FL
    SG_ mcuLogDataBytesSegment2 : 135|64@0+ (1,0) [0|255] "" VIU_FR,VIU_FL
    SG_ mcuLogDataBytesSegment3 : 199|64@0+ (1,0) [0|255] "" VIU_FR,VIU_FL
    SG_ mcuLogDataBytesSegment4 : 263|64@0+ (1,0) [0|255] "" VIU_FR,VIU_FL
    SG_ mcuLogDataBytesSegment5 : 327|64@0+ (1,0) [0|255] "" VIU_FR,VIU_FL
    SG_ mcuLogDataBytesSegment6 : 391|64@0+ (1,0) [0|255] "" VIU_FR,VIU_FL
    SG_ mcuLogDataBytesSegment7 : 455|64@0+ (1,0) [0|255] "" VIU_FR,VIU_FL

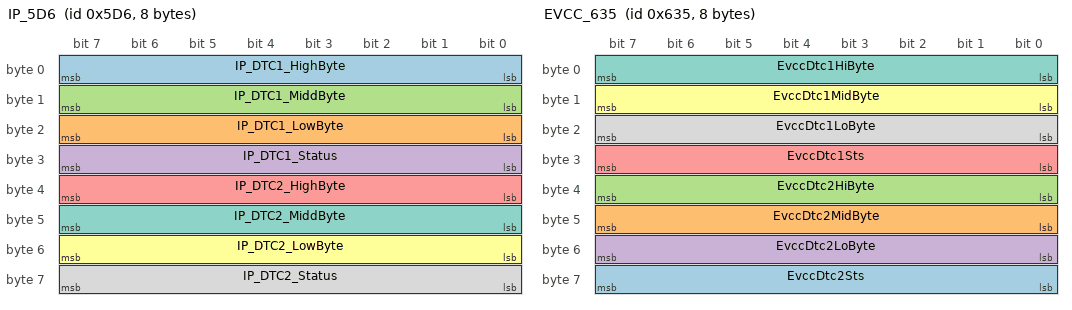
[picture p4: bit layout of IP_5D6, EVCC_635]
BO_ 1494 IP_5D6: 8 IP
    SG_ IP_DTC1_HighByte : 7|8@0+ (1,0) [0|255] "" VIU_FL
    SG_ IP_DTC1_LowByte : 23|8@0+ (1,0) [0|255] "" VIU_FL
    SG_ IP_DTC1_MiddByte : 15|8@0+ (1,0) [0|255] "" VIU_FL
    SG_ IP_DTC1_Status : 31|8@0+ (1,0) [0|255] "" VIU_FL
    SG_ IP_DTC2_HighByte : 39|8@0+ (1,0) [0|255] "" VIU_FL
    SG_ IP_DTC2_LowByte : 55|8@0+ (1,0) [0|255] "" VIU_FL
    SG_ IP_DTC2_MiddByte : 47|8@0+ (1,0) [0|255] "" VIU_FL
    SG_ IP_DTC2_Status : 63|8@0+ (1,0) [0|255] "" VIU_FL

BO_ 1502 VIU_FL_5DE: 64 VIU_FL
    SG_ ReMotAmnt_GB : 7|8@0+ (1,0) [1|253] "" EDC,TBOX
    SG_ ReMotNr_GB : 15|8@0+ (1,0) [1|253] "" EDC,TBOX
    SG_ ReMotSts_GB : 23|8@0+ (1,0) [0|255] "" EDC,TBOX
    SG_ ReIpuT_GB : 31|8@0+ (1,-40) [-40|210] "℃" EDC,TBOX
    SG_ ReMotTq_GB : 39|32@0+ (0.1,-20000) [-20000|20000] "Nm" EDC,TBOX
    SG_ ReMotSpd_GB : 71|16@0+ (1,-32000) [-32000|33531] "rpm" EDC,TBOX
    SG_ ReMotTStatr_GB : 87|8@0+ (1,-40) [-40|210] "℃" EDC,TBOX
    SG_ ReIpuErrAmnt_GB : 95|8@0+ (1,0) [0|253] "" EDC,TBOX
    SG_ ReIpuErrNr_GB : 103|32@0+ (1,0) [0|65535] "" EDC,TBOX
    SG_ ReMotOverSpd_GB : 135|1@0+ (1,0) [0|1] "" EDC,TBOX
    SG_ ReMotOverI_GB : 134|1@0+ (1,0) [0|1] "" EDC,TBOX
    SG_ ReIpuTOver_GB : 133|1@0+ (1,0) [0|1] "" EDC,TBOX
    SG_ ReMotTOver_GB : 132|1@0+ (1,0) [0|1] "" EDC,TBOX

BO_ 1510 VIU_FL_5E6: 64 VIU_FL
    SG_ FrntMotAmntGb : 7|8@0+ (1,0) [1|253] "" EDC,TBOX
    SG_ FrntMotNrGb : 15|8@0+ (1,0) [1|253] "" EDC,TBOX
    SG_ FrntMotStsGb : 23|8@0+ (1,0) [0|255] "" EDC,TBOX
    SG_ FrntMotIvtINTCTGb : 31|8@0+ (1,-40) [-40|210] "℃" EDC,TBOX
    SG_ FrntMotTqGb : 39|32@0+ (0.1,-20000) [-20000|20000] "Nm" EDC,TBOX
    SG_ FrntMotSpdGb : 71|16@0+ (1,-32000) [-32000|33531] "rpm" EDC,TBOX
    SG_ FrntMotTStatrGb : 87|8@0+ (1,-40) [-40|210] "℃" EDC,TBOX
    SG_ FrntIpuErrAmntGb : 95|8@0+ (1,0) [0|253] "" EDC,TBOX
    SG_ FrntIpuErrNrGb : 103|32@0+ (1,0) [0|65535] "" EDC,TBOX
    SG_ FrntMotOverSpdGb : 135|1@0+ (1,0) [0|1] "" EDC,TBOX
    SG_ FrntMotOverIGb : 134|1@0+ (1,0) [0|1] "" EDC,TBOX
    SG_ FrntIpuTOverGb : 133|1@0+ (1,0) [0|1] "" EDC,TBOX
    SG_ FrntMotTOverGb : 132|1@0+ (1,0) [0|1] "" EDC,TBOX

BO_ 1540 EDC_604: 16 EDC
    SG_ EDC_EthMng_Vers : 7|8@0+ (1,0) [0|255] "" VIU_FL,VIU_FR
    SG_ EDC_EthMng_MngTyp : 15|8@0+ (1,0) [0|255] "" VIU_FL,VIU_FR
    SG_ EDC_EthMng_Msg : 23|8@0+ (1,0) [0|255] "" VIU_FL,VIU_FR
    SG_ EDC_EthMng_OptnCod : 31|8@0+ (1,0) [0|255] "" VIU_FL,VIU_FR
    SG_ EDC_EthMng_Optn : 39|8@0+ (1,0) [0|255] "" VIU_FL,VIU_FR
    SG_ EDC_EthMng_DataTyp : 47|8@0+ (1,0) [0|255] "" VIU_FL,VIU_FR
    SG_ EDC_EthMng_DataLen : 55|16@0+ (1,0) [0|65535] "" VIU_FL,VIU_FR
    SG_ EDC_EthMng_Payload : 71|8@0+ (1,0) [0|255] "" VIU_FL,VIU_FR

BO_ 1541 VIU_FL_605: 64 VIU_FL
    SG_ VIUFL_EthMng_Vers : 7|8@0+ (1,0) [0|255] "" EDC
    SG_ VIUFL_EthMng_MngTyp : 15|8@0+ (1,0) [0|255] "" EDC
    SG_ VIUFL_EthMng_Msg : 23|8@0+ (1,0) [0|255] "" EDC
    SG_ VIUFL_EthMng_OptnCod : 31|8@0+ (1,0) [0|255] "" EDC
    SG_ VIUFL_EthMng_Optn : 39|8@0+ (1,0) [0|255] "" EDC
    SG_ VIUFL_EthMng_DataTyp : 47|8@0+ (1,0) [0|255] "" EDC
    SG_ VIUFL_EthMng_DataLen : 55|16@0+ (1,0) [0|65535] "" EDC

BO_ 1543 VIU_FR_607: 8 VIU_FR
    SG_ VIU_FrTakOveSts : 1|2@0+ (1,0) [0|3] "" VIU_FL

BO_ 1546 VIU_FR_60A: 64 VIU_FR
    SG_ VIUFR_EthMng_Vers : 7|8@0+ (1,0) [0|255] "" EDC
    SG_ VIUFR_EthMng_MngTyp : 15|8@0+ (1,0) [0|255] "" EDC
    SG_ VIUFR_EthMng_Msg : 23|8@0+ (1,0) [0|255] "" EDC
    SG_ VIUFR_EthMng_OptnCod : 31|8@0+ (1,0) [0|255] "" EDC
    SG_ VIUFR_EthMng_Optn : 39|8@0+ (1,0) [0|255] "" EDC
    SG_ VIUFR_EthMng_DataTyp : 47|8@0+ (1,0) [0|255] "" EDC
    SG_ VIUFR_EthMng_DataLen : 55|16@0+ (1,0) [0|65535] "" EDC

BO_ 1547 VIU_FL_60B: 64 VIU_FL
    SG_ C2_EthMng_Vers : 7|8@0+ (1,0) [0|255] "" EDC
    SG_ C2_EthMng_MngTyp : 15|8@0+ (1,0) [0|255] "" EDC
    SG_ C2_EthMng_Msg : 23|8@0+ (1,0) [0|255] "" EDC
    SG_ C2_EthMng_OptnCod : 31|8@0+ (1,0) [0|255] "" EDC
    SG_ C2_EthMng_Optn : 39|8@0+ (1,0) [0|255] "" EDC
    SG_ C2_EthMng_DataTyp : 47|8@0+ (1,0) [0|255] "" EDC
    SG_ C2_EthMng_DataLen : 55|16@0+ (1,0) [0|65535] "" EDC

BO_ 1548 EDC_60C: 8 EDC
    SG_ EDC_ErpsRev_Pst : 7|2@0+ (1,0) [0|3] "" VIU_FL,VIU_FR

BO_ 1551 VIU_FR_60F: 8 VIU_FR
    SG_ VIUFR_ErpsRev_Pst : 7|2@0+ (1,0) [0|3] "" EDC,VIU_FL

BO_ 1579 VIU_FR_62B: 64 VIU_FR
    SG_ C2_EthMng_Vers : 7|8@0+ (1,0) [0|255] "" EDC
    SG_ C2_EthMng_MngTyp : 15|8@0+ (1,0) [0|255] "" EDC
    SG_ C2_EthMng_Msg : 23|8@0+ (1,0) [0|255] "" EDC
    SG_ C2_EthMng_OptnCod : 31|8@0+ (1,0) [0|255] "" EDC
    SG_ C2_EthMng_Optn : 39|8@0+ (1,0) [0|255] "" EDC
    SG_ C2_EthMng_DataTyp : 47|8@0+ (1,0) [0|255] "" EDC
    SG_ C2_EthMng_DataLen : 55|16@0+ (1,0) [0|65535] "" EDC

BO_ 1589 EVCC_635: 8 EVCC
    SG_ EvccDtc2Sts : 63|8@0+ (1,0) [0|255] "" VIU_FL
    SG_ EvccDtc2MidByte : 47|8@0+ (1,0) [0|255] "" VIU_FL
    SG_ EvccDtc2HiByte : 39|8@0+ (1,0) [0|255] "" VIU_FL
    SG_ EvccDtc2LoByte : 55|8@0+ (1,0) [0|255] "" VIU_FL
    SG_ EvccDtc1Sts : 31|8@0+ (1,0) [0|255] "" VIU_FL
    SG_ EvccDtc1MidByte : 15|8@0+ (1,0) [0|255] "" VIU_FL
    SG_ EvccDtc1HiByte : 7|8@0+ (1,0) [0|255] "" VIU_FL
    SG_ EvccDtc1LoByte : 23|8@0+ (1,0) [0|255] "" VIU_FL

BO_ 1705 VIU_FR_6A9: 8 VIU_FR
    SG_ calibration_message6A9 : 0|1@0+ (1,0) [0|1] "" VIU_FL

BO_ 1707 VIU_FL_6AB: 8 VIU_FL
    SG_ Diagnose_message_6AB : 0|1@0+ (1,0) [0|1] "" VIU_FR

BO_ 1750 VIU_FL_6D6: 64 VIU_FL
    SG_ calibration_message6D6 : 0|1@0+ (1,0) [0|1] "" VIU_FR

BO_ 1751 VIU_FR_6D7: 64 VIU_FR
    SG_ calibration_message6D7 : 0|1@0+ (1,0) [0|1] "" VIU_FL

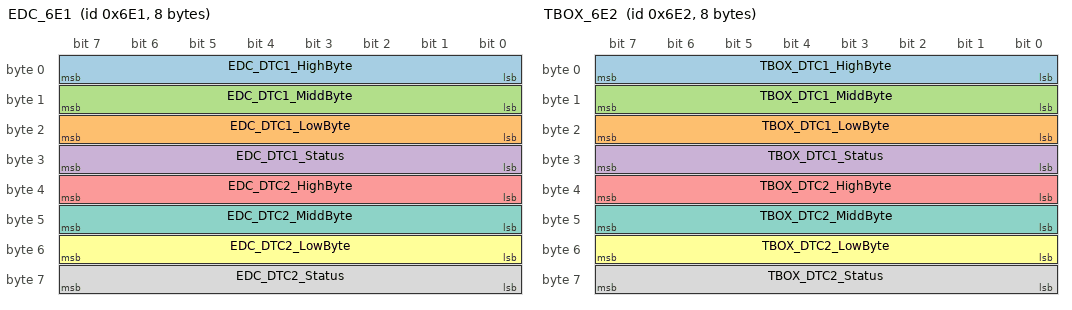
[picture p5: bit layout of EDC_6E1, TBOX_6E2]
BO_ 1761 EDC_6E1: 8 EDC
    SG_ EDC_DTC1_HighByte : 7|8@0+ (1,0) [0|255] "" VIU_FL
    SG_ EDC_DTC1_LowByte : 23|8@0+ (1,0) [0|255] "" VIU_FL
    SG_ EDC_DTC1_MiddByte : 15|8@0+ (1,0) [0|255] "" VIU_FL
    SG_ EDC_DTC1_Status : 31|8@0+ (1,0) [0|255] "" VIU_FL
    SG_ EDC_DTC2_HighByte : 39|8@0+ (1,0) [0|255] "" VIU_FL
    SG_ EDC_DTC2_LowByte : 55|8@0+ (1,0) [0|255] "" VIU_FL
    SG_ EDC_DTC2_MiddByte : 47|8@0+ (1,0) [0|255] "" VIU_FL
    SG_ EDC_DTC2_Status : 63|8@0+ (1,0) [0|255] "" VIU_FL

BO_ 1762 TBOX_6E2: 8 TBOX
    SG_ TBOX_DTC1_HighByte : 7|8@0+ (1,0) [0|255] "" VIU_FL
    SG_ TBOX_DTC1_LowByte : 23|8@0+ (1,0) [0|255] "" VIU_FL
    SG_ TBOX_DTC1_MiddByte : 15|8@0+ (1,0) [0|255] "" VIU_FL
    SG_ TBOX_DTC1_Status : 31|8@0+ (1,0) [0|255] "" VIU_FL
    SG_ TBOX_DTC2_HighByte : 39|8@0+ (1,0) [0|255] "" VIU_FL
    SG_ TBOX_DTC2_LowByte : 55|8@0+ (1,0) [0|255] "" VIU_FL
    SG_ TBOX_DTC2_MiddByte : 47|8@0+ (1,0) [0|255] "" VIU_FL
    SG_ TBOX_DTC2_Status : 63|8@0+ (1,0) [0|255] "" VIU_FL

BO_ 1763 EDC_6E3: 32 EDC
    SG_ EDCEqCertifReqFrmType : 7|8@0+ (1,0) [161|163] "L" VIU_FL
    SG_ EDCEqCertifReqCmac : 15|128@0+ (1,0) [0|255] "L" VIU_FL

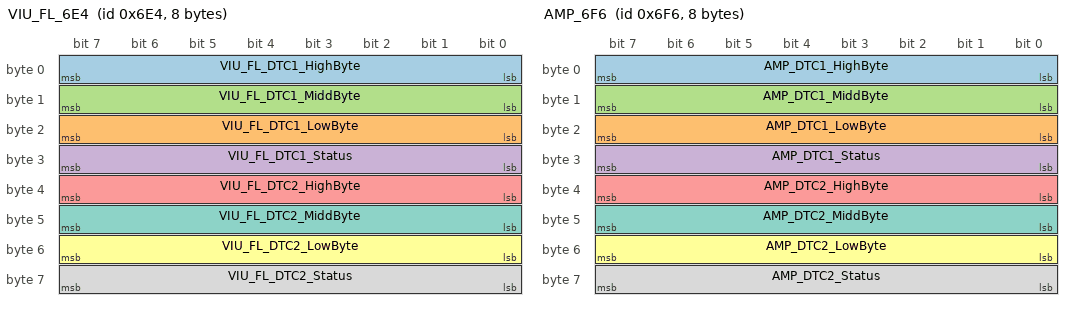
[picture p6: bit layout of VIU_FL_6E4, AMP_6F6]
BO_ 1764 VIU_FL_6E4: 8 VIU_FL
    SG_ VIU_FL_DTC1_HighByte : 7|8@0+ (1,0) [0|255] "" Vector__XXX
    SG_ VIU_FL_DTC1_LowByte : 23|8@0+ (1,0) [0|255] "" Vector__XXX
    SG_ VIU_FL_DTC1_MiddByte : 15|8@0+ (1,0) [0|255] "" Vector__XXX
    SG_ VIU_FL_DTC1_Status : 31|8@0+ (1,0) [0|255] "" Vector__XXX
    SG_ VIU_FL_DTC2_HighByte : 39|8@0+ (1,0) [0|255] "" Vector__XXX
    SG_ VIU_FL_DTC2_LowByte : 55|8@0+ (1,0) [0|255] "" Vector__XXX
    SG_ VIU_FL_DTC2_MiddByte : 47|8@0+ (1,0) [0|255] "" Vector__XXX
    SG_ VIU_FL_DTC2_Status : 63|8@0+ (1,0) [0|255] "" Vector__XXX

BO_ 1767 VIU_FL_6E7: 32 VIU_FL
    SG_ VIUEqCertifRespFrmType : 7|8@0+ (1,0) [162|164] "L" EDC
    SG_ VIUEqCertifRespRand : 15|128@0+ (1,0) [0|255] "L" EDC
    SG_ VIUEqCertifRespRes : 143|8@0+ (1,0) [0|1] "L" EDC

BO_ 1782 AMP_6F6: 8 AMP
    SG_ AMP_DTC1_HighByte : 7|8@0+ (1,0) [0|255] "" EDC,VIU_FR
    SG_ AMP_DTC1_LowByte : 23|8@0+ (1,0) [0|255] "" EDC,VIU_FR
    SG_ AMP_DTC1_MiddByte : 15|8@0+ (1,0) [0|255] "" EDC,VIU_FR
    SG_ AMP_DTC1_Status : 31|8@0+ (1,0) [0|255] "" EDC,VIU_FR
    SG_ AMP_DTC2_HighByte : 39|8@0+ (1,0) [0|255] "" EDC,VIU_FR
    SG_ AMP_DTC2_LowByte : 55|8@0+ (1,0) [0|255] "" EDC,VIU_FR
    SG_ AMP_DTC2_MiddByte : 47|8@0+ (1,0) [0|255] "" EDC,VIU_FR
    SG_ AMP_DTC2_Status : 63|8@0+ (1,0) [0|255] "" EDC,VIU_FR

BO_ 1786 VIU_FR_6FA: 8 VIU_FR
    SG_ calibration_message6FA : 0|1@0+ (1,0) [0|1] "" VIU_FL

BO_ 1787 VIU_FL_6FB: 8 VIU_FL
    SG_ Diagnose_message_6FB : 0|1@0+ (1,0) [0|1] "" VIU_FR

BO_ 1790 VIU_FR_6FE: 8 VIU_FR
    SG_ ErpsBootMode : 7|1@0+ (1,0) [0|1] "" VIU_FL,EDC

BO_ 1793 VIU_FL_701: 64 VIU_FL
    SG_ Diagnose_message_701 : 0|1@0+ (1,0) [0|1] "" IP

BO_ 1795 VIU_FL_703: 8 VIU_FL
    SG_ Diagnose_message_703 : 0|1@0+ (1,0) [0|1] "" VIU_FR

BO_ 1796 VIU_FL_704: 64 VIU_FL
    SG_ Diagnose_message_704 : 0|1@0+ (1,0) [0|1] "" EVCC

BO_ 1801 IP_709: 8 IP
    SG_ Diagnose_message_709 : 0|1@0+ (1,0) [0|1] "" VIU_FL

BO_ 1803 VIU_FR_70B: 8 VIU_FR
    SG_ Diagnose_message_70B : 0|1@0+ (1,0) [0|1] "" VIU_FL

BO_ 1804 EVCC_70C: 8 EVCC
    SG_ Diagnose_message_70C : 0|1@0+ (1,0) [0|1] "" VIU_FL

BO_ 1808 VIU_FL_710: 64 VIU_FL
    SG_ Diagnose_message_710 : 0|1@0+ (1,0) [0|1] "" TBOX

BO_ 1811 VIU_FL_713: 64 VIU_FL
    SG_ Diagnose_message_713 : 0|1@0+ (1,0) [0|1] "" EDC

BO_ 1816 TBOX_718: 8 TBOX
    SG_ Diagnose_message_718 : 0|1@0+ (1,0) [0|1] "" VIU_FL

BO_ 1819 EDC_71B: 8 EDC
    SG_ Diagnose_message_71B : 0|1@0+ (1,0) [0|1] "" VIU_FL

BO_ 1824 VIU_FL_720: 64 VIU_FL
    SG_ Diagnose_message_720 : 0|1@0+ (1,0) [0|1] "" VIU_FR

BO_ 1832 VIU_FR_728: 8 VIU_FR
    SG_ Diagnose_message_728 : 0|1@0+ (1,0) [0|1] "" VIU_FL

BO_ 1843 VIU_FL_733: 64 VIU_FL
    SG_ Diagnose_message_733 : 0|1@0+ (1,0) [0|1] "" VIU_FR

BO_ 1845 VIU_FL_735: 64 VIU_FL
    SG_ Diagnose_message_735 : 0|1@0+ (1,0) [0|1] "" EDC,AMP

BO_ 1851 VIU_FR_73B: 8 VIU_FR
    SG_ Diagnose_message_73B : 0|1@0+ (1,0) [0|1] "" VIU_FL

BO_ 1853 AMP_73D: 8 AMP
    SG_ Diagnose_message_73D : 0|1@0+ (1,0) [0|1] "" VIU_FL,EDC

BO_ 1875 VIU_FL_753: 8 VIU_FL
    SG_ Diagnose_message_753 : 0|1@0+ (1,0) [0|1] "" VIU_FR

BO_ 1883 VIU_FR_75B: 8 VIU_FR
    SG_ Diagnose_message_75B : 0|1@0+ (1,0) [0|1] "" VIU_FL

BO_ 1892 VIU_FL_764: 64 VIU_FL
    SG_ Diagnose_message_764 : 0|1@0+ (1,0) [0|1] "" VIU_FR

BO_ 1900 VIU_FR_76C: 8 VIU_FR
    SG_ Diagnose_message_76C : 0|1@0+ (1,0) [0|1] "" VIU_FL

BO_ 1910 VIU_FL_776: 8 VIU_FL
    SG_ Diagnose_message_776 : 0|1@0+ (1,0) [0|1] "" VIU_FR

BO_ 1911 VIU_FL_777: 8 VIU_FL
    SG_ Diagnose_message_777 : 0|1@0+ (1,0) [0|1] "" VIU_FR

BO_ 1918 VIU_FR_77E: 8 VIU_FR
    SG_ Diagnose_message_77E : 0|1@0+ (1,0) [0|1] "" VIU_FL

BO_ 1919 VIU_FR_77F: 8 VIU_FR
    SG_ Diagnose_message_77F : 0|1@0+ (1,0) [0|1] "" VIU_FL

BO_ 1955 VIU_FL_7A3: 8 VIU_FL
    SG_ Diagnose_message7A3 : 0|1@0+ (1,0) [0|1] "" VIU_FR

BO_ 1957 VIU_FL_7A5: 8 VIU_FL
    SG_ Diagnose_message_7A5 : 0|1@0+ (1,0) [0|1] "" VIU_FR

BO_ 1963 VIU_FR_7AB: 8 VIU_FR
    SG_ Diagnose_message7AB : 0|1@0+ (1,0) [0|1] "" VIU_FL

BO_ 1965 VIU_FR_7AD: 8 VIU_FR
    SG_ Diagnose_message_7AD : 0|1@0+ (1,0) [0|1] "" VIU_FL

BO_ 1984 VIU_FL_7C0: 8 VIU_FL
    SG_ Diagnose_message_7C0 : 0|1@0+ (1,0) [0|1] "" VIU_FR

BO_ 1992 VIU_FR_7C8: 8 VIU_FR
    SG_ Diagnose_message_7C8 : 0|1@0+ (1,0) [0|1] "" VIU_FL

BO_ 2000 VIU_FL_7D0: 8 VIU_FL
    SG_ Diagnose_message_7D0 : 0|1@0+ (1,0) [0|1] "" VIU_FR

BO_ 2004 VIU_FR_7D4: 8 VIU_FR
    SG_ Diagnose_message_7D4 : 0|1@0+ (1,0) [0|1] "" VIU_FL

BO_ 2005 VIU_FR_7D5: 8 VIU_FR
    SG_ Diagnose_message_7D5 : 0|1@0+ (1,0) [0|1] "" VIU_FL

BO_ 2006 VIU_FR_7D6: 8 VIU_FR
    SG_ Diagnose_message_7D6 : 0|1@0+ (1,0) [0|1] "" VIU_FL

BO_ 2007 VIU_FR_7D7: 8 VIU_FR
    SG_ Diagnose_message_7D7 : 0|1@0+ (1,0) [0|1] "" VIU_FL

BO_ 2008 VIU_FR_7D8: 8 VIU_FR
    SG_ Diagnose_message_7D8 : 0|1@0+ (1,0) [0|1] "" VIU_FL

BO_ 2015 VIU_FL_7DF: 8 VIU_FL
    SG_ Diagnose_message_7DF : 0|1@0+ (1,0) [0|1] "" EDC,TBOX,VIU_FR,AMP,EVCC,IP

BO_ 2016 VIU_FL_7E0: 8 VIU_FL
    SG_ Diagnose_message_7E0 : 0|1@0+ (1,0) [0|1] "" VIU_FR

BO_ 2017 VIU_FL_7E1: 8 VIU_FL
    SG_ Diagnose_message7E1 : 0|1@0+ (1,0) [0|1] "" VIU_FR

BO_ 2024 VIU_FR_7E8: 8 VIU_FR
    SG_ Diagnose_message_7E8 : 0|1@0+ (1,0) [0|1] "" VIU_FL

BO_ 2025 VIU_FR_7E9: 8 VIU_FR
    SG_ Diagnose_message7E9 : 0|1@0+ (1,0) [0|1] "" VIU_FL

BO_ 2033 VIU_FL_7F1: 8 VIU_FL
    SG_ Diagnose_message_7F1 : 0|1@0+ (1,0) [0|1] "" VIU_FR

BO_ 2041 VIU_FR_7F9: 8 VIU_FR
    SG_ Diagnose_message_7F9 : 0|1@0+ (1,0) [0|1] "" VIU_FL

CM_ BO_ 1407 " ";
CM_ SG_ 1407 VIU_FL_NotSleep_Index "VIU_FL 自身不休眠原因索引";
CM_ SG_ 1407 VIU_FL_NotSleep_IndexTotal "VIU_FL 自身不休眠原因索引组数";
CM_ SG_ 1407 VIU_FL_NotSleep_Nmnumber "VIU_FL 收到的NM数";
CM_ SG_ 1407 VIU_FL_NotSleep_serviceNumber "VIU_FL 自身不休眠原因服务编号";
CM_ SG_ 1407 VIU_FL_WakeUp_BYTE0BIT0 "VIU_FL 自身唤醒原因_1";
CM_ SG_ 1407 VIU_FL_WakeUp_BYTE0BIT1 "VIU_FL 自身唤醒原因_2";
CM_ SG_ 1407 VIU_FL_WakeUp_BYTE0BIT2 "VIU_FL 自身唤醒原因_3";
CM_ SG_ 1407 VIU_FL_WakeUp_BYTE0BIT3 "VIU_FL 唤醒原因_4";
CM_ SG_ 1407 VIU_FL_WakeUp_BYTE0BIT4 "VIU_FL 自身唤醒原因_5";
CM_ SG_ 1407 VIU_FL_WakeUp_BYTE0BIT5 "VIU_FL 自身唤醒原因_6";
CM_ SG_ 1407 VIU_FL_WakeUp_BYTE0BIT6 "VIU_FL 自身唤醒原因_7";
CM_ SG_ 1407 VIU_FL_WakeUp_BYTE0BIT7 "VIU_FL 唤醒原因_8";
CM_ SG_ 1407 VIU_FL_WakeUp_BYTE1BIT0 "VIU_FL 自身唤醒原因_9";
CM_ SG_ 1407 VIU_FL_WakeUp_BYTE1BIT1 "VIU_FL 唤醒原因_10";
CM_ SG_ 1407 VIU_FL_WakeUp_BYTE1BIT2 "VIU_FL 自身唤醒原因_11";
CM_ SG_ 1407 VIU_FL_WakeUp_BYTE1BIT3 "VIU_FL 自身唤醒原因_12";
CM_ SG_ 1407 VIU_FL_WakeUp_BYTE1BIT4 "VIU_FL 自身唤醒原因_13";
CM_ SG_ 1407 VIU_FL_WakeUp_BYTE1BIT5 "VIU_FL 自身唤醒原因_14";
CM_ SG_ 1407 VIU_FL_WakeUp_BYTE1BIT6 "VIU_FL 自身唤醒原因_15";
CM_ SG_ 1407 VIU_FL_WakeUp_BYTE1BIT7 "VIU_FL 自身唤醒原因_16";
CM_ SG_ 1407 VIU_FL_WakeUp_BYTE2BIT0 "VIU_FL 自身唤醒原因_17";
CM_ SG_ 1407 VIU_FL_WakeUp_BYTE2BIT1 "VIU_FL 自身唤醒原因_18";
CM_ SG_ 1407 VIU_FL_WakeUp_BYTE2BIT2 "VIU_FL 自身唤醒原因_19";
CM_ SG_ 1407 VIU_FL_WakeUp_BYTE2BIT3 "VIU_FL 自身唤醒原因_20";
CM_ SG_ 1407 VIU_FL_WakeUp_BYTE2BIT4 "VIU_FL 唤醒原因_21";
CM_ SG_ 1407 VIU_FL_WakeUp_BYTE2BIT5 "VIU_FL 自身唤醒原因_22";
CM_ SG_ 1407 VIU_FL_WakeUp_BYTE2BIT6 "VIU_FL 自身唤醒原因_23";
CM_ SG_ 1407 VIU_FL_WakeUp_BYTE2BIT7 "VIU_FL 自身唤醒原因_24";
CM_ SG_ 1407 VIU_FL_WakeUp_BYTE3BIT0 "VIU_FL 自身唤醒原因_25";
CM_ SG_ 1407 VIU_FL_WakeUp_BYTE3BIT1 "VIU_FL 自身唤醒原因_26";
CM_ SG_ 1407 VIU_FL_WakeUp_BYTE3BIT2 "VIU_FL 自身唤醒原因_27";
CM_ SG_ 1407 VIU_FL_WakeUp_BYTE3BIT3 "VIU_FL 自身唤醒原因_28";
CM_ SG_ 1407 VIU_FL_WakeUp_BYTE3BIT4 "VIU_FL 自身唤醒原因_29";
CM_ SG_ 1407 VIU_FL_WakeUp_BYTE3BIT5 "VIU_FL 唤醒原因_30";
CM_ SG_ 1407 VIU_FL_WakeUp_BYTE3BIT6 "VIU_FL 唤醒原因_31";
CM_ SG_ 1407 VIU_FL_WakeUp_BYTE3BIT7 "VIU_FL 自身唤醒原因_32";
CM_ SG_ 1407 VIU_FL_WakeUp_BYTE4BIT0 "VIU_FL 自身唤醒原因_33";
CM_ SG_ 1407 VIU_FL_WakeUp_BYTE4BIT1 "VIU_FL 自身唤醒原因_34";
CM_ SG_ 1407 VIU_FL_WakeUp_BYTE4BIT2 "VIU_FL 唤醒原因_35";
CM_ SG_ 1407 VIU_FL_WakeUp_BYTE4BIT3 "VIU_FL 自身唤醒原因_36";
CM_ SG_ 1407 VIU_FL_WakeUp_BYTE4BIT4 "VIU_FL 自身唤醒原因_37";
CM_ SG_ 1407 VIU_FL_WakeUp_BYTE4BIT5 "VIU_FL 自身唤醒原因_38";
CM_ SG_ 1407 VIU_FL_WakeUp_BYTE4BIT6 "VIU_FL 自身唤醒原因_39";
CM_ SG_ 1407 VIU_FL_WakeUp_BYTE4BIT7 "VIU_FL 唤醒原因_40";
CM_ SG_ 1407 VIU_FL_WakeUp_BYTE5BIT0 "VIU_FL 自身唤醒原因_41";
CM_ SG_ 1407 VIU_FL_WakeUp_BYTE5BIT1 "VIU_FL 自身唤醒原因_42";
CM_ SG_ 1407 VIU_FL_WakeUp_BYTE5BIT2 "VIU_FL 唤醒原因_43";
CM_ SG_ 1407 VIU_FL_WakeUp_BYTE5BIT3 "VIU_FL 自身唤醒原因_44";
CM_ SG_ 1407 VIU_FL_WakeUp_BYTE5BIT4 "VIU_FL 自身唤醒原因_45";
CM_ SG_ 1407 VIU_FL_WakeUp_BYTE5BIT5 "VIU_FL 唤醒原因_46";
CM_ SG_ 1407 VIU_FL_WakeUp_BYTE5BIT6 "VIU_FL 唤醒原因_47";
CM_ SG_ 1407 VIU_FL_WakeUp_BYTE5BIT7 "VIU_FL 自身唤醒原因_48";
CM_ SG_ 1407 VIU_FL_WakeUp_BYTE6BIT0 "VIU_FL 唤醒原因_49";
CM_ SG_ 1407 VIU_FL_WakeUp_BYTE6BIT1 "VIU_FL 唤醒原因_50";
CM_ SG_ 1407 VIU_FL_WakeUp_BYTE6BIT2 "VIU_FL 唤醒原因_51";
CM_ SG_ 1407 VIU_FL_WakeUp_BYTE6BIT3 "VIU_FL 唤醒原因_52";
CM_ SG_ 1407 VIU_FL_WakeUp_BYTE6BIT4 "VIU_FL 唤醒原因_53";
CM_ SG_ 1407 VIU_FL_WakeUp_BYTE6BIT5 "VIU_FL 唤醒原因_54";
CM_ SG_ 1407 VIU_FL_WakeUp_BYTE6BIT6 "VIU_FL 唤醒原因_55";
CM_ SG_ 1407 VIU_FL_WakeUp_BYTE6BIT7 "VIU_FL 唤醒原因_56";
CM_ SG_ 1407 VIU_FL_WakeUp_BYTE7BIT0 "VIU_FL 唤醒原因_57";
CM_ SG_ 1407 VIU_FL_WakeUp_BYTE7BIT1 "VIU_FL 唤醒原因_58";
CM_ SG_ 1407 VIU_FL_WakeUp_BYTE7BIT2 "VIU_FL 唤醒原因_59";
CM_ SG_ 1407 VIU_FL_WakeUp_BYTE7BIT3 "VIU_FL 唤醒原因_60";
CM_ SG_ 1407 VIU_FL_WakeUp_BYTE7BIT4 "VIU_FL 唤醒原因_61";
CM_ SG_ 1407 VIU_FL_WakeUp_BYTE7BIT5 "VIU_FL 唤醒原因_62";
CM_ SG_ 1407 VIU_FL_WakeUp_BYTE7BIT6 "VIU_FL 唤醒原因_63";
CM_ SG_ 1407 VIU_FL_WakeUp_BYTE7BIT7 "VIU_FL 唤醒原因_64";
CM_ SG_ 1407 VIU_FL_WakeUp_BYTE15BIT0 "VIU_FL 唤醒原因_65";
CM_ SG_ 1407 VIU_FL_WakeUp_BYTE15BIT1 "VIU_FL 唤醒原因_66";
CM_ BO_ 1411 " ";
CM_ SG_ 1411 IP_WakeUp_BYTE3BIT0 "唤醒原因_1";
CM_ SG_ 1411 IP_NotSleep_BYTE7BIT0 "不休眠原因_1";
CM_ SG_ 1411 IP_NotSleep_BYTE7BIT1 "不休眠原因_2";
CM_ BO_ 1417 " ";
CM_ SG_ 1417 VIU_FR_WakeUp_BYTE0BIT0 "VIU_FR 自身唤醒原因_1";
CM_ SG_ 1417 VIU_FR_WakeUp_BYTE0BIT1 "VIU_FR 自身唤醒原因_2";
CM_ SG_ 1417 VIU_FR_WakeUp_BYTE0BIT2 "VIU_FR 自身唤醒原因_3";
CM_ SG_ 1417 VIU_FR_WakeUp_BYTE0BIT3 "VIU_FR 自身唤醒原因_4";
CM_ SG_ 1417 VIU_FR_WakeUp_BYTE0BIT4 "VIU_FR 自身唤醒原因_5";
CM_ SG_ 1417 VIU_FR_WakeUp_BYTE0BIT5 "VIU_FR 自身唤醒原因_6";
CM_ SG_ 1417 VIU_FR_WakeUp_BYTE0BIT6 "VIU_FR 自身唤醒原因_7";
CM_ SG_ 1417 VIU_FR_WakeUp_BYTE0BIT7 "VIU_FR 自身唤醒原因_8";
CM_ SG_ 1417 VIU_FR_WakeUp_BYTE1BIT0 "VIU_FR 自身唤醒原因_9";
CM_ SG_ 1417 VIU_FR_WakeUp_BYTE1BIT1 "VIU_FR 自身唤醒原因_10";
CM_ SG_ 1417 VIU_FR_WakeUp_BYTE1BIT2 "VIU_FR 自身唤醒原因_11";
CM_ SG_ 1417 VIU_FR_WakeUp_BYTE1BIT3 "VIU_FR 自身唤醒原因_12";
CM_ SG_ 1417 VIU_FR_WakeUp_BYTE1BIT4 "VIU_FR 自身唤醒原因_13";
CM_ SG_ 1417 VIU_FR_WakeUp_BYTE1BIT5 "VIU_FR 自身唤醒原因_14";
CM_ SG_ 1417 VIU_FR_WakeUp_BYTE1BIT6 "VIU_FR 自身唤醒原因_15";
CM_ SG_ 1417 VIU_FR_WakeUp_BYTE1BIT7 "VIU_FR 自身唤醒原因_16";
CM_ SG_ 1417 VIU_FR_WakeUp_BYTE2BIT0 "VIU_FR 自身唤醒原因_17";
CM_ SG_ 1417 VIU_FR_WakeUp_BYTE2BIT1 "VIU_FR 自身唤醒原因_18";
CM_ SG_ 1417 VIU_FR_WakeUp_BYTE2BIT2 "VIU_FR 自身唤醒原因_19";
CM_ SG_ 1417 VIU_FR_WakeUp_BYTE2BIT3 "VIU_FR 自身唤醒原因_20";
CM_ SG_ 1417 VIU_FR_WakeUp_BYTE2BIT4 "VIU_FR 自身唤醒原因_21";
CM_ SG_ 1417 VIU_FR_WakeUp_BYTE2BIT5 "VIU_FR 自身唤醒原因_22";
CM_ SG_ 1417 VIU_FR_WakeUp_BYTE2BIT6 "VIU_FR 自身唤醒原因_23";
CM_ SG_ 1417 VIU_FR_WakeUp_BYTE2BIT7 "VIU_FR自身唤醒原因_24";
CM_ SG_ 1417 VIU_FR_WakeUp_BYTE3BIT0 "VIU_FR自身唤醒原因_25";
CM_ SG_ 1417 VIU_FR_WakeUp_BYTE3BIT1 "VIU_FR自身唤醒原因_26";
CM_ SG_ 1417 VIU_FR_WakeUp_BYTE3BIT2 "VIU_FR自身唤醒原因_27";
CM_ SG_ 1417 VIU_FR_WakeUp_BYTE3BIT3 "VIU_FR自身唤醒原因_28";
CM_ SG_ 1417 VIU_FR_WakeUp_BYTE3BIT4 "VIU_FR自身唤醒原因_29";
CM_ SG_ 1417 VIU_FR_WakeUp_BYTE3BIT5 "VIU_FR 自身唤醒原因_30";
CM_ SG_ 1417 VIU_FR_WakeUp_BYTE3BIT6 "VIU_FR 自身唤醒原因_31";
CM_ SG_ 1417 VIU_FR_WakeUp_BYTE3BIT7 "VIU_FR自身唤醒原因_32";
CM_ SG_ 1417 VIU_FR_WakeUp_BYTE4BIT0 "VIU_FR自身唤醒原因_33";
CM_ SG_ 1417 VIU_FR_WakeUp_BYTE4BIT1 "VIU_FR自身唤醒原因_34";
CM_ SG_ 1417 VIU_FR_WakeUp_BYTE4BIT2 "VIU_FR 自身唤醒原因_35";
CM_ SG_ 1417 VIU_FR_WakeUp_BYTE4BIT3 "VIU_FR自身唤醒原因_36";
CM_ SG_ 1417 VIU_FR_WakeUp_BYTE4BIT4 "VIU_FR 自身唤醒原因_37";
CM_ SG_ 1417 VIU_FR_WakeUp_BYTE4BIT5 "VIU_FR 自身唤醒原因_38";
CM_ SG_ 1417 VIU_FR_WakeUp_BYTE4BIT6 "VIU_FR 自身唤醒原因_39";
CM_ SG_ 1417 VIU_FR_WakeUp_BYTE4BIT7 "VIU_FR 自身唤醒原因_40";
CM_ SG_ 1417 VIU_FR_WakeUp_BYTE5BIT0 "VIU_FR 自身唤醒原因_41";
CM_ SG_ 1417 VIU_FR_WakeUp_BYTE5BIT1 "VIU_FR 自身唤醒原因_42";
CM_ SG_ 1417 VIU_FR_WakeUp_BYTE5BIT2 "VIU_FR 自身唤醒原因_43";
CM_ SG_ 1417 VIU_FR_WakeUp_BYTE5BIT3 "VIU_FR 自身唤醒原因_44";
CM_ SG_ 1417 VIU_FR_WakeUp_BYTE5BIT4 "VIU_FR 自身唤醒原因_45";
CM_ SG_ 1417 VIU_FR_WakeUp_BYTE5BIT5 "VIU_FR 自身唤醒原因_46";
CM_ SG_ 1417 VIU_FR_WakeUp_BYTE5BIT6 "VIU_FR 自身唤醒原因_47";
CM_ SG_ 1417 VIU_FR_WakeUp_BYTE5BIT7 "VIU_FR 自身唤醒原因_48";
CM_ SG_ 1417 VIU_FR_WakeUp_BYTE6BIT0 "VIU_FR 自身唤醒原因_49";
CM_ SG_ 1417 VIU_FR_WakeUp_BYTE6BIT1 "VIU_FR 自身唤醒原因_50";
CM_ SG_ 1417 VIU_FR_WakeUp_BYTE6BIT2 "VIU_FR 自身唤醒原因_51";
CM_ SG_ 1417 VIU_FR_WakeUp_BYTE6BIT3 "VIU_FR 自身唤醒原因_52";
CM_ SG_ 1417 VIU_FR_WakeUp_BYTE6BIT4 "VIU_FR 自身唤醒原因_53";
CM_ SG_ 1417 VIU_FR_WakeUp_BYTE6BIT5 "VIU_FR 自身唤醒原因_54";
CM_ SG_ 1417 VIU_FR_WakeUp_BYTE6BIT6 "VIU_FR 自身唤醒原因_55";
CM_ SG_ 1417 VIU_FR_WakeUp_BYTE6BIT7 "VIU_FR 自身唤醒原因_56";
CM_ SG_ 1417 VIU_FR_WakeUp_BYTE7BIT0 "VIU_FR 自身唤醒原因_57";
CM_ SG_ 1417 VIU_FR_WakeUp_BYTE7BIT1 "VIU_FR 自身唤醒原因_58";
CM_ SG_ 1417 VIU_FR_WakeUp_BYTE7BIT2 "VIU_FR 自身唤醒原因_59";
CM_ SG_ 1417 VIU_FR_WakeUp_BYTE7BIT3 "VIU_FR 自身唤醒原因_60";
CM_ SG_ 1417 VIU_FR_WakeUp_BYTE7BIT4 "VIU_FR 自身唤醒原因_61";
CM_ SG_ 1417 VIU_FR_WakeUp_BYTE7BIT5 "VIU_FR 自身唤醒原因_62";
CM_ SG_ 1417 VIU_FR_WakeUp_BYTE7BIT6 "VIU_FR 自身唤醒原因_63";
CM_ SG_ 1417 VIU_FR_WakeUp_BYTE7BIT7 "VIU_FR 自身唤醒原因_64";
CM_ BO_ 1418 " ";
CM_ SG_ 1418 VIU_FR_NotSleep_Index "VIU_FR 自身不休眠原因索引";
CM_ SG_ 1418 VIU_FR_NotSleep_IndexTotal "VIU_FR 自身不休眠原因索引组数";
CM_ SG_ 1418 VIU_FR_NotSleep_Nmnumber "VIU_FR 收到的NM数";
CM_ SG_ 1418 VIU_FR_NotSleep_serviceNumber "VIU_FR 自身不休眠原因服务编号";
CM_ SG_ 1418 VIU_FR_WakeUp_BYTE15BIT0 "VIU_FR 自身唤醒原因_65";
CM_ SG_ 1418 VIU_FR_WakeUp_BYTE15BIT1 "VIU_FR 自身唤醒原因_66";
CM_ BO_ 1430 " ";
CM_ SG_ 1430 RLR_NotSleep_BYTE7BIT0 "不休眠原因_1";
CM_ SG_ 1430 RLR_NotSleep_BYTE7BIT1 "不休眠原因_2";
CM_ SG_ 1430 RLR_NotSleep_BYTE7BIT2 "不休眠原因_3";
CM_ SG_ 1430 RLR_NotSleep_BYTE7BIT3 "不休眠原因_4";
CM_ SG_ 1430 RLR_WakeUp_BYTE3BIT0 "唤醒原因_1";
CM_ SG_ 1430 RLR_WakeUp_BYTE3BIT1 "唤醒原因_2";
CM_ BO_ 1431 " ";
CM_ SG_ 1431 RRR_NotSleep_BYTE7BIT0 "不休眠原因_1";
CM_ SG_ 1431 RRR_NotSleep_BYTE7BIT1 "不休眠原因_2";
CM_ SG_ 1431 RRR_NotSleep_BYTE7BIT2 "不休眠原因_3";
CM_ SG_ 1431 RRR_NotSleep_BYTE7BIT3 "不休眠原因_4";
CM_ SG_ 1431 RRR_WakeUp_BYTE3BIT0 "唤醒原因_1";
CM_ SG_ 1431 RRR_WakeUp_BYTE3BIT1 "唤醒原因_2";
CM_ BO_ 1432 " ";
CM_ SG_ 1432 FRR_NotSleep_BYTE7BIT0 "不休眠原因_1";
CM_ SG_ 1432 FRR_NotSleep_BYTE7BIT1 "不休眠原因_2";
CM_ SG_ 1432 FRR_NotSleep_BYTE7BIT2 "不休眠原因_3";
CM_ SG_ 1432 FRR_NotSleep_BYTE7BIT3 "不休眠原因_4";
CM_ SG_ 1432 FRR_WakeUp_BYTE3BIT0 "唤醒原因_1";
CM_ SG_ 1432 FRR_WakeUp_BYTE3BIT1 "唤醒原因_2";
CM_ BO_ 1438 " ";
CM_ SG_ 1438 EVCC_WakeUp_BYTE4BIT3 "唤醒原因_4";
CM_ SG_ 1438 EVCC_WakeUp_BYTE4BIT2 "唤醒原因_3";
CM_ SG_ 1438 EVCC_WakeUp_BYTE4BIT1 "唤醒原因_2";
CM_ SG_ 1438 EVCC_WakeUp_BYTE4BIT0 "唤醒原因_1";
CM_ SG_ 1438 EVCC_NotSleep_BYTE7BIT4 "不休眠原因_5";
CM_ SG_ 1438 EVCC_NotSleep_BYTE7BIT3 "不休眠原因_4";
CM_ SG_ 1438 EVCC_NotSleep_BYTE7BIT2 "不休眠原因_3";
CM_ SG_ 1438 EVCC_NotSleep_BYTE7BIT1 "不休眠原因_2";
CM_ SG_ 1438 EVCC_NotSleep_BYTE7BIT0 "不休眠原因_1";
CM_ BO_ 1442 " ";
CM_ SG_ 1442 FLR_NotSleep_BYTE7BIT0 "不休眠原因_1";
CM_ SG_ 1442 FLR_NotSleep_BYTE7BIT1 "不休眠原因_2";
CM_ SG_ 1442 FLR_NotSleep_BYTE7BIT2 "不休眠原因_3";
CM_ SG_ 1442 FLR_NotSleep_BYTE7BIT3 "不休眠原因_4";
CM_ SG_ 1442 FLR_WakeUp_BYTE3BIT0 "唤醒原因_1";
CM_ SG_ 1442 FLR_WakeUp_BYTE3BIT1 "唤醒原因_2";
CM_ BO_ 1466 " ";
CM_ SG_ 1466 AMP_NotSleep_BYTE7BIT0 "不休眠原因_1";
CM_ SG_ 1466 AMP_NotSleep_BYTE7BIT1 "不休眠原因_2";
CM_ SG_ 1466 AMP_NotSleep_BYTE7BIT2 "不休眠原因_3";
CM_ SG_ 1466 AMP_WakeUp_BYTE3BIT0 "唤醒原因_1";
CM_ SG_ 1466 AMP_WakeUp_BYTE3BIT1 "唤醒原因_2";
CM_ BO_ 1471 " ";
CM_ SG_ 1471 mcuLogDataBytesSegment0 "EDC-Mcu日志片段0";
CM_ SG_ 1471 mcuLogDataBytesSegment1 "EDC-Mcu日志片段1";
CM_ SG_ 1471 mcuLogDataBytesSegment2 "EDC-Mcu日志片段2";
CM_ SG_ 1471 mcuLogDataBytesSegment3 "EDC-Mcu日志片段3";
CM_ SG_ 1471 mcuLogDataBytesSegment4 "EDC-Mcu日志片段4";
CM_ SG_ 1471 mcuLogDataBytesSegment5 "EDC-Mcu日志片段5";
CM_ SG_ 1471 mcuLogDataBytesSegment6 "EDC-Mcu日志片段6";
CM_ SG_ 1471 mcuLogDataBytesSegment7 "EDC-Mcu日志片段7";
CM_ BO_ 1494 " ";
CM_ SG_ 1494 IP_DTC1_HighByte "IP的DTC1高字节";
CM_ SG_ 1494 IP_DTC1_LowByte "IP的DTC1低字节";
CM_ SG_ 1494 IP_DTC1_MiddByte "IP的DTC1中字节";
CM_ SG_ 1494 IP_DTC1_Status "IP的DTC1状态";
CM_ SG_ 1494 IP_DTC2_HighByte "IP的DTC2高字节";
CM_ SG_ 1494 IP_DTC2_LowByte "IP的DTC2低字节";
CM_ SG_ 1494 IP_DTC2_MiddByte "IP的DTC2中字节";
CM_ SG_ 1494 IP_DTC2_Status "IP的DTC2状态";
CM_ BO_ 1502 " ";
CM_ SG_ 1502 ReMotAmnt_GB "后电机总数（国标）";
CM_ SG_ 1502 ReMotNr_GB "后电机序号（国标）";
CM_ SG_ 1502 ReMotSts_GB "后电机状态（国标）";
CM_ SG_ 1502 ReIpuT_GB "后电机控制器温度（国标）";
CM_ SG_ 1502 ReMotTq_GB "后电机扭矩（国标）";
CM_ SG_ 1502 ReMotSpd_GB "后电机转速（国标）";
CM_ SG_ 1502 ReMotTStatr_GB "后电机定子温度（国标）";
CM_ SG_ 1502 ReIpuErrAmnt_GB "后电机故障数量（国标）";
CM_ SG_ 1502 ReIpuErrNr_GB "后电机故障代码（国标）";
CM_ SG_ 1502 ReMotOverSpd_GB "后电机超速报警（国标）";
CM_ SG_ 1502 ReMotOverI_GB "后电机过流报警（国标）";
CM_ SG_ 1502 ReIpuTOver_GB "后电机控制器过温（国标）";
CM_ SG_ 1502 ReMotTOver_GB "后电机温度过高（国标）";
CM_ BO_ 1510 " ";
CM_ SG_ 1510 FrntMotAmntGb "前电机总数（国标）";
CM_ SG_ 1510 FrntMotNrGb "前电机序号（国标）";
CM_ SG_ 1510 FrntMotStsGb "前电机状态（国标）";
CM_ SG_ 1510 FrntMotIvtINTCTGb "前电机逆变器NTC温度（国标）";
CM_ SG_ 1510 FrntMotTqGb "前电机扭矩（国标）";
CM_ SG_ 1510 FrntMotSpdGb "前电机转速（国标）";
CM_ SG_ 1510 FrntMotTStatrGb "前电机定子温度（国标）";
CM_ SG_ 1510 FrntIpuErrAmntGb "前电机故障数量（国标）";
CM_ SG_ 1510 FrntIpuErrNrGb "前电机故障代码（国标）";
CM_ SG_ 1510 FrntMotOverSpdGb "前电机超速报警（国标）";
CM_ SG_ 1510 FrntMotOverIGb "前电机过流报警（国标）";
CM_ SG_ 1510 FrntIpuTOverGb "前电机控制器过温（国标）";
CM_ SG_ 1510 FrntMotTOverGb "前电机温度过高（国标）";
CM_ BO_ 1540 " ";
CM_ SG_ 1540 EDC_EthMng_Vers "以太组网管理协议版本号";
CM_ SG_ 1540 EDC_EthMng_MngTyp "以太组网管理消息类型";
CM_ SG_ 1540 EDC_EthMng_Msg "以太组网管理消息层";
CM_ SG_ 1540 EDC_EthMng_OptnCod "以太组网管理操作码";
CM_ SG_ 1540 EDC_EthMng_Optn "以太组网管理ECU序列号";
CM_ SG_ 1540 EDC_EthMng_DataTyp "以太组网管理数据类型";
CM_ SG_ 1540 EDC_EthMng_DataLen "以太组网管理数据长度";
CM_ SG_ 1540 EDC_EthMng_Payload "以太组网管理数据内容";
CM_ BO_ 1541 " ";
CM_ SG_ 1541 VIUFL_EthMng_Vers "以太组网管理协议版本号";
CM_ SG_ 1541 VIUFL_EthMng_MngTyp "以太组网管理消息类型";
CM_ SG_ 1541 VIUFL_EthMng_Msg "以太组网管理消息层";
CM_ SG_ 1541 VIUFL_EthMng_OptnCod "以太组网管理操作码";
CM_ SG_ 1541 VIUFL_EthMng_Optn "以太组网管理ECU序列号";
CM_ SG_ 1541 VIUFL_EthMng_DataTyp "以太组网管理数据类型";
CM_ SG_ 1541 VIUFL_EthMng_DataLen "以太组网管理数据长度";
CM_ BO_ 1543 " ";
CM_ SG_ 1543 VIU_FrTakOveSts "VIU-FR实际接管状态";
CM_ BO_ 1546 " ";
CM_ SG_ 1546 VIUFR_EthMng_Vers "以太组网管理协议版本号";
CM_ SG_ 1546 VIUFR_EthMng_MngTyp "以太组网管理消息类型";
CM_ SG_ 1546 VIUFR_EthMng_Msg "以太组网管理消息层";
CM_ SG_ 1546 VIUFR_EthMng_OptnCod "以太组网管理操作码";
CM_ SG_ 1546 VIUFR_EthMng_Optn "以太组网管理ECU序列号";
CM_ SG_ 1546 VIUFR_EthMng_DataTyp "以太组网管理数据类型";
CM_ SG_ 1546 VIUFR_EthMng_DataLen "以太组网管理数据长度";
CM_ BO_ 1547 " ";
CM_ SG_ 1547 C2_EthMng_Vers "以太组网管理协议版本号";
CM_ SG_ 1547 C2_EthMng_MngTyp "以太组网管理消息类型";
CM_ SG_ 1547 C2_EthMng_Msg "以太组网管理消息层";
CM_ SG_ 1547 C2_EthMng_OptnCod "以太组网管理操作码";
CM_ SG_ 1547 C2_EthMng_Optn "以太组网管理ECU序列号";
CM_ SG_ 1547 C2_EthMng_DataTyp "以太组网管理数据类型";
CM_ SG_ 1547 C2_EthMng_DataLen "以太组网管理数据长度";
CM_ BO_ 1548 " ";
CM_ SG_ 1548 EDC_ErpsRev_Pst "以太环网端口状态";
CM_ BO_ 1551 " ";
CM_ SG_ 1551 VIUFR_ErpsRev_Pst "以太环网端口状态";
CM_ BO_ 1579 " ";
CM_ SG_ 1579 C2_EthMng_Vers "以太组网管理协议版本号";
CM_ SG_ 1579 C2_EthMng_MngTyp "以太组网管理消息类型";
CM_ SG_ 1579 C2_EthMng_Msg "以太组网管理消息层";
CM_ SG_ 1579 C2_EthMng_OptnCod "以太组网管理操作码";
CM_ SG_ 1579 C2_EthMng_Optn "以太组网管理ECU序列号";
CM_ SG_ 1579 C2_EthMng_DataTyp "以太组网管理数据类型";
CM_ SG_ 1579 C2_EthMng_DataLen "以太组网管理数据长度";
CM_ BO_ 1589 " ";
CM_ SG_ 1589 EvccDtc2Sts "EVCC的DTC2状态";
CM_ SG_ 1589 EvccDtc2MidByte "EVCC的DTC2中字节";
CM_ SG_ 1589 EvccDtc2HiByte "EVCC的DTC2高字节";
CM_ SG_ 1589 EvccDtc2LoByte "EVCC的DTC2低字节";
CM_ SG_ 1589 EvccDtc1Sts "EVCC的DTC1状态";
CM_ SG_ 1589 EvccDtc1MidByte "EVCC的DTC1中字节";
CM_ SG_ 1589 EvccDtc1HiByte "EVCC的DTC1高字节";
CM_ SG_ 1589 EvccDtc1LoByte "EVCC的DTC1低字节";
CM_ BO_ 1705 " ";
CM_ SG_ 1705 calibration_message6A9 "标定报文（用于生成DBC）(ID与HCM冲突)";
CM_ BO_ 1707 " ";
CM_ SG_ 1707 Diagnose_message_6AB "诊断信号（用于生成dbc）";
CM_ BO_ 1750 " ";
CM_ SG_ 1750 calibration_message6D6 "标定报文（用于生成DBC）";
CM_ BO_ 1751 " ";
CM_ SG_ 1751 calibration_message6D7 "标定报文（用于生成DBC）";
CM_ BO_ 1761 " ";
CM_ SG_ 1761 EDC_DTC1_HighByte "EDC的DTC1高字节";
CM_ SG_ 1761 EDC_DTC1_LowByte "EDC的DTC1低字节";
CM_ SG_ 1761 EDC_DTC1_MiddByte "EDC的DTC1中字节";
CM_ SG_ 1761 EDC_DTC1_Status "EDC的DTC1状态";
CM_ SG_ 1761 EDC_DTC2_HighByte "EDC的DTC2高字节";
CM_ SG_ 1761 EDC_DTC2_LowByte "EDC的DTC2低字节";
CM_ SG_ 1761 EDC_DTC2_MiddByte "EDC的DTC2中字节";
CM_ SG_ 1761 EDC_DTC2_Status "EDC的DTC2状态";
CM_ BO_ 1762 " ";
CM_ SG_ 1762 TBOX_DTC1_HighByte "TBOX的DTC1高字节";
CM_ SG_ 1762 TBOX_DTC1_LowByte "TBOX的DTC1低字节";
CM_ SG_ 1762 TBOX_DTC1_MiddByte "TBOX的DTC1中字节";
CM_ SG_ 1762 TBOX_DTC1_Status "TBOX的DTC1状态";
CM_ SG_ 1762 TBOX_DTC2_HighByte "TBOX的DTC2高字节";
CM_ SG_ 1762 TBOX_DTC2_LowByte "TBOX的DTC2低字节";
CM_ SG_ 1762 TBOX_DTC2_MiddByte "TBOX的DTC2中字节";
CM_ SG_ 1762 TBOX_DTC2_Status "TBOX的DTC2状态";
CM_ BO_ 1763 " ";
CM_ SG_ 1763 EDCEqCertifReqFrmType "EDC设备认证申请帧类型";
CM_ SG_ 1763 EDCEqCertifReqCmac "EDC设备认证申请挑战应答";
CM_ BO_ 1764 " ";
CM_ SG_ 1764 VIU_FL_DTC1_HighByte "VIU_FL的DTC1高字节";
CM_ SG_ 1764 VIU_FL_DTC1_LowByte "VIU_FL的DTC1低字节";
CM_ SG_ 1764 VIU_FL_DTC1_MiddByte "VIU_FL的DTC1中字节";
CM_ SG_ 1764 VIU_FL_DTC1_Status "VIU_FL的DTC1状态";
CM_ SG_ 1764 VIU_FL_DTC2_HighByte "VIU_FL的DTC2高字节";
CM_ SG_ 1764 VIU_FL_DTC2_LowByte "VIU_FL的DTC2低字节";
CM_ SG_ 1764 VIU_FL_DTC2_MiddByte "VIU_FL的DTC2中字节";
CM_ SG_ 1764 VIU_FL_DTC2_Status "VIU_FL的DTC2状态";
CM_ BO_ 1767 " ";
CM_ SG_ 1767 VIUEqCertifRespFrmType "VIU设备认证应答帧类型";
CM_ SG_ 1767 VIUEqCertifRespRand "VIU设备认证应答随机数";
CM_ SG_ 1767 VIUEqCertifRespRes "VIU设备认证应答认证结果";
CM_ BO_ 1782 " ";
CM_ SG_ 1782 AMP_DTC1_HighByte "AMP的DTC1高字节";
CM_ SG_ 1782 AMP_DTC1_LowByte "AMP的DTC1低字节";
CM_ SG_ 1782 AMP_DTC1_MiddByte "AMP的DTC1中字节";
CM_ SG_ 1782 AMP_DTC1_Status "AMP的DTC1状态";
CM_ SG_ 1782 AMP_DTC2_HighByte "AMP的DTC2高字节";
CM_ SG_ 1782 AMP_DTC2_LowByte "AMP的DTC2低字节";
CM_ SG_ 1782 AMP_DTC2_MiddByte "AMP的DTC2中字节";
CM_ SG_ 1782 AMP_DTC2_Status "AMP的DTC2状态";
CM_ BO_ 1786 " ";
CM_ SG_ 1786 calibration_message6FA "标定报文（用于生成DBC）";
CM_ BO_ 1787 " ";
CM_ SG_ 1787 Diagnose_message_6FB "诊断信号（用于生成dbc）";
CM_ BO_ 1790 " ";
CM_ SG_ 1790 ErpsBootMode "VIU_FR刷写状态";
CM_ BO_ 1793 " ";
CM_ SG_ 1793 Diagnose_message_701 "诊断信号（用于生成dbc）";
CM_ BO_ 1795 " ";
CM_ SG_ 1795 Diagnose_message_703 "诊断信号（用于生成dbc）";
CM_ BO_ 1796 " ";
CM_ SG_ 1796 Diagnose_message_704 "诊断信号（用于生成dbc）";
CM_ BO_ 1801 " ";
CM_ SG_ 1801 Diagnose_message_709 "诊断信号（用于生成dbc）";
CM_ BO_ 1803 " ";
CM_ SG_ 1803 Diagnose_message_70B "诊断信号（用于生成dbc）";
CM_ BO_ 1804 " ";
CM_ SG_ 1804 Diagnose_message_70C "诊断信号（用于生成dbc）";
CM_ BO_ 1808 " ";
CM_ SG_ 1808 Diagnose_message_710 "诊断信号（用于生成dbc）";
CM_ BO_ 1811 " ";
CM_ SG_ 1811 Diagnose_message_713 "诊断信号（用于生成dbc）";
CM_ BO_ 1816 " ";
CM_ SG_ 1816 Diagnose_message_718 "诊断信号（用于生成dbc）";
CM_ BO_ 1819 " ";
CM_ SG_ 1819 Diagnose_message_71B "诊断信号（用于生成dbc）";
CM_ BO_ 1824 " ";
CM_ SG_ 1824 Diagnose_message_720 "诊断信号（用于生成dbc）";
CM_ BO_ 1832 " ";
CM_ SG_ 1832 Diagnose_message_728 "诊断信号（用于生成dbc）";
CM_ BO_ 1843 " ";
CM_ SG_ 1843 Diagnose_message_733 "诊断信号（用于生成dbc）";
CM_ BO_ 1845 " ";
CM_ SG_ 1845 Diagnose_message_735 "诊断信号（用于生成dbc）";
CM_ BO_ 1851 " ";
CM_ SG_ 1851 Diagnose_message_73B "诊断信号（用于生成dbc）";
CM_ BO_ 1853 " ";
CM_ SG_ 1853 Diagnose_message_73D "诊断信号（用于生成dbc）";
CM_ BO_ 1875 " ";
CM_ SG_ 1875 Diagnose_message_753 "诊断信号";
CM_ BO_ 1883 " ";
CM_ SG_ 1883 Diagnose_message_75B "诊断信号";
CM_ BO_ 1892 " ";
CM_ SG_ 1892 Diagnose_message_764 "诊断信号（用于生成dbc）";
CM_ BO_ 1900 " ";
CM_ SG_ 1900 Diagnose_message_76C "诊断信号（用于生成dbc）";
CM_ BO_ 1910 " ";
CM_ SG_ 1910 Diagnose_message_776 "诊断信号（用于生成dbc）";
CM_ BO_ 1911 " ";
CM_ SG_ 1911 Diagnose_message_777 "诊断信号（用于生成dbc）";
CM_ BO_ 1918 " ";
CM_ SG_ 1918 Diagnose_message_77E "诊断信号（用于生成dbc）";
CM_ BO_ 1919 " ";
CM_ SG_ 1919 Diagnose_message_77F "诊断信号（用于生成dbc）";
CM_ BO_ 1955 " ";
CM_ SG_ 1955 Diagnose_message7A3 "诊断信号（用于生成DBC）";
CM_ BO_ 1957 " ";
CM_ SG_ 1957 Diagnose_message_7A5 "诊断信号（用于生成dbc）";
CM_ BO_ 1963 " ";
CM_ SG_ 1963 Diagnose_message7AB "诊断信号（用于生成DBC）";
CM_ BO_ 1965 " ";
CM_ SG_ 1965 Diagnose_message_7AD "诊断信号（用于生成dbc）";
CM_ BO_ 1984 " ";
CM_ SG_ 1984 Diagnose_message_7C0 "诊断信号（用于生成dbc）";
CM_ BO_ 1992 " ";
CM_ SG_ 1992 Diagnose_message_7C8 "诊断信号（用于生成dbc）";
CM_ BO_ 2000 " ";
CM_ SG_ 2000 Diagnose_message_7D0 "诊断信号（用于生成dbc）";
CM_ BO_ 2004 " ";
CM_ SG_ 2004 Diagnose_message_7D4 "诊断信号（用于生成dbc）";
CM_ BO_ 2005 " ";
CM_ SG_ 2005 Diagnose_message_7D5 "诊断信号（用于生成dbc）";
CM_ BO_ 2006 " ";
CM_ SG_ 2006 Diagnose_message_7D6 "诊断信号（用于生成dbc）";
CM_ BO_ 2007 " ";
CM_ SG_ 2007 Diagnose_message_7D7 "诊断信号（用于生成dbc）";
CM_ BO_ 2008 " ";
CM_ SG_ 2008 Diagnose_message_7D8 "诊断信号（用于生成dbc）";
CM_ BO_ 2015 " ";
CM_ SG_ 2015 Diagnose_message_7DF "诊断信号（用于生成dbc）";
CM_ BO_ 2016 " ";
CM_ SG_ 2016 Diagnose_message_7E0 "诊断信号（用于生成dbc）";
CM_ BO_ 2017 " ";
CM_ SG_ 2017 Diagnose_message7E1 "诊断信号（用于生成DBC）";
CM_ BO_ 2024 " ";
CM_ SG_ 2024 Diagnose_message_7E8 "诊断信号（用于生成dbc）";
CM_ BO_ 2025 " ";
CM_ SG_ 2025 Diagnose_message7E9 "诊断信号（用于生成DBC）";
CM_ BO_ 2033 " ";
CM_ SG_ 2033 Diagnose_message_7F1 "诊断信号（用于生成dbc）";
CM_ BO_ 2041 " ";
CM_ SG_ 2041 Diagnose_message_7F9 "诊断信号（用于生成dbc）";
BA_DEF_ SG_ "GenSigStartValue" INT 0 0;
BA_DEF_ SG_ "GenSigInvalidValue" CHAR;
BA_DEF_ SG_ "GenSigCycleTime" INT 0 0;
BA_DEF_ SG_ "GenSigSendType" ENUM,"Cyclic\"","\"OnWrite\"","\"OnWriteWithRepetition\"","\"OnChange\"","\"OnChangeWithRepetition\"","\"IfActive\"","\"IfActiveWithRepetition\"","\"NoSigSendType\"","\"NotUsed\"","\"NotUsed\"","\"NotUsed\"","\"NotUsed\"","\"NotUsed";
BA_DEF_ BO_ "GenMsgSendType" ENUM,"Cyclic\"","\"Event\"","\"Direct\"","\"NotUsed\"","\"NotUsed\"","\"Cyclic\"","\"NotUsed\"","\"IfActive\"","\"NoMsgSendType\"","\"NotUsed";
BA_DEF_ BO_ "GenMsgCycleTime" INT 0 65535;
BA_DEF_ BO_ "VFrameFormat" ENUM,"StandardCAN\"","\"ExtendedCAN\"","\"reserved\"","\"reserved\"","\"reserved\"","\"reserved\"","\"reserved\"","\"reserved\"","\"reserved\"","\"reserved\"","\"reserved\"","\"reserved\"","\"reserved\"","\"reserved\"","\"StandardCAN_FD\"","\"ExtendedCAN_FD";
BA_DEF_ SG_ "SystemSignalLongSymbol" CHAR;
BA_ "GenMsgCycleTime" BO_ 1407 1000;
BA_ "GenMsgSendType" BO_ 1407 0;
BA_ "VFrameFormat" BO_ 1407 14;
BA_ "GenMsgCycleTime" BO_ 1411 1000;
BA_ "GenMsgSendType" BO_ 1411 0;
BA_ "VFrameFormat" BO_ 1411 14;
BA_ "GenMsgCycleTime" BO_ 1417 1000;
BA_ "GenMsgSendType" BO_ 1417 0;
BA_ "VFrameFormat" BO_ 1417 14;
BA_ "GenMsgCycleTime" BO_ 1418 1000;
BA_ "GenMsgSendType" BO_ 1418 0;
BA_ "VFrameFormat" BO_ 1418 14;
BA_ "GenMsgCycleTime" BO_ 1430 1000;
BA_ "GenMsgSendType" BO_ 1430 0;
BA_ "VFrameFormat" BO_ 1430 14;
BA_ "GenMsgCycleTime" BO_ 1431 1000;
BA_ "GenMsgSendType" BO_ 1431 0;
BA_ "VFrameFormat" BO_ 1431 14;
BA_ "GenMsgCycleTime" BO_ 1432 1000;
BA_ "GenMsgSendType" BO_ 1432 0;
BA_ "VFrameFormat" BO_ 1432 14;
BA_ "GenMsgCycleTime" BO_ 1438 1000;
BA_ "GenMsgSendType" BO_ 1438 0;
BA_ "VFrameFormat" BO_ 1438 14;
BA_ "GenMsgCycleTime" BO_ 1442 1000;
BA_ "GenMsgSendType" BO_ 1442 0;
BA_ "VFrameFormat" BO_ 1442 14;
BA_ "GenMsgCycleTime" BO_ 1466 1000;
BA_ "GenMsgSendType" BO_ 1466 0;
BA_ "VFrameFormat" BO_ 1466 14;
BA_ "GenMsgCycleTime" BO_ 1471 1000;
BA_ "GenMsgSendType" BO_ 1471 0;
BA_ "VFrameFormat" BO_ 1471 14;
BA_ "GenMsgCycleTime" BO_ 1494 500;
BA_ "GenMsgSendType" BO_ 1494 0;
BA_ "VFrameFormat" BO_ 1494 14;
BA_ "GenMsgCycleTime" BO_ 1502 1000;
BA_ "GenMsgSendType" BO_ 1502 0;
BA_ "VFrameFormat" BO_ 1502 14;
BA_ "GenMsgCycleTime" BO_ 1510 1000;
BA_ "GenMsgSendType" BO_ 1510 0;
BA_ "VFrameFormat" BO_ 1510 14;
BA_ "GenMsgCycleTime" BO_ 1540 0;
BA_ "GenMsgSendType" BO_ 1540 1;
BA_ "VFrameFormat" BO_ 1540 14;
BA_ "GenMsgCycleTime" BO_ 1541 0;
BA_ "GenMsgSendType" BO_ 1541 1;
BA_ "VFrameFormat" BO_ 1541 14;
BA_ "GenMsgCycleTime" BO_ 1543 0;
BA_ "GenMsgSendType" BO_ 1543 1;
BA_ "VFrameFormat" BO_ 1543 14;
BA_ "GenMsgCycleTime" BO_ 1546 0;
BA_ "GenMsgSendType" BO_ 1546 1;
BA_ "VFrameFormat" BO_ 1546 14;
BA_ "GenMsgCycleTime" BO_ 1547 0;
BA_ "GenMsgSendType" BO_ 1547 1;
BA_ "VFrameFormat" BO_ 1547 14;
BA_ "GenMsgCycleTime" BO_ 1548 0;
BA_ "GenMsgSendType" BO_ 1548 1;
BA_ "VFrameFormat" BO_ 1548 14;
BA_ "GenMsgCycleTime" BO_ 1551 0;
BA_ "GenMsgSendType" BO_ 1551 1;
BA_ "VFrameFormat" BO_ 1551 14;
BA_ "GenMsgCycleTime" BO_ 1579 0;
BA_ "GenMsgSendType" BO_ 1579 1;
BA_ "VFrameFormat" BO_ 1579 14;
BA_ "GenMsgCycleTime" BO_ 1589 500;
BA_ "GenMsgSendType" BO_ 1589 0;
BA_ "VFrameFormat" BO_ 1589 14;
BA_ "GenMsgCycleTime" BO_ 1705 0;
BA_ "GenMsgSendType" BO_ 1705 1;
BA_ "VFrameFormat" BO_ 1705 14;
BA_ "GenMsgCycleTime" BO_ 1707 0;
BA_ "GenMsgSendType" BO_ 1707 1;
BA_ "VFrameFormat" BO_ 1707 14;
BA_ "GenMsgCycleTime" BO_ 1750 0;
BA_ "GenMsgSendType" BO_ 1750 1;
BA_ "VFrameFormat" BO_ 1750 14;
BA_ "GenMsgCycleTime" BO_ 1751 0;
BA_ "GenMsgSendType" BO_ 1751 1;
BA_ "VFrameFormat" BO_ 1751 14;
BA_ "GenMsgCycleTime" BO_ 1761 500;
BA_ "GenMsgSendType" BO_ 1761 0;
BA_ "VFrameFormat" BO_ 1761 14;
BA_ "GenMsgCycleTime" BO_ 1762 500;
BA_ "GenMsgSendType" BO_ 1762 0;
BA_ "VFrameFormat" BO_ 1762 14;
BA_ "GenMsgCycleTime" BO_ 1763 0;
BA_ "GenMsgSendType" BO_ 1763 1;
BA_ "VFrameFormat" BO_ 1763 14;
BA_ "GenMsgCycleTime" BO_ 1764 500;
BA_ "GenMsgSendType" BO_ 1764 0;
BA_ "VFrameFormat" BO_ 1764 14;
BA_ "GenMsgCycleTime" BO_ 1767 0;
BA_ "GenMsgSendType" BO_ 1767 1;
BA_ "VFrameFormat" BO_ 1767 14;
BA_ "GenMsgCycleTime" BO_ 1782 500;
BA_ "GenMsgSendType" BO_ 1782 0;
BA_ "VFrameFormat" BO_ 1782 14;
BA_ "GenMsgCycleTime" BO_ 1786 0;
BA_ "GenMsgSendType" BO_ 1786 1;
BA_ "VFrameFormat" BO_ 1786 14;
BA_ "GenMsgCycleTime" BO_ 1787 0;
BA_ "GenMsgSendType" BO_ 1787 1;
BA_ "VFrameFormat" BO_ 1787 14;
BA_ "GenMsgCycleTime" BO_ 1790 100;
BA_ "GenMsgSendType" BO_ 1790 0;
BA_ "VFrameFormat" BO_ 1790 14;
BA_ "GenMsgCycleTime" BO_ 1793 0;
BA_ "GenMsgSendType" BO_ 1793 1;
BA_ "VFrameFormat" BO_ 1793 14;
BA_ "GenMsgCycleTime" BO_ 1795 0;
BA_ "GenMsgSendType" BO_ 1795 1;
BA_ "VFrameFormat" BO_ 1795 14;
BA_ "GenMsgCycleTime" BO_ 1796 0;
BA_ "GenMsgSendType" BO_ 1796 1;
BA_ "VFrameFormat" BO_ 1796 14;
BA_ "GenMsgCycleTime" BO_ 1801 0;
BA_ "GenMsgSendType" BO_ 1801 1;
BA_ "VFrameFormat" BO_ 1801 14;
BA_ "GenMsgCycleTime" BO_ 1803 0;
BA_ "GenMsgSendType" BO_ 1803 1;
BA_ "VFrameFormat" BO_ 1803 14;
BA_ "GenMsgCycleTime" BO_ 1804 0;
BA_ "GenMsgSendType" BO_ 1804 1;
BA_ "VFrameFormat" BO_ 1804 14;
BA_ "GenMsgCycleTime" BO_ 1808 0;
BA_ "GenMsgSendType" BO_ 1808 1;
BA_ "VFrameFormat" BO_ 1808 14;
BA_ "GenMsgCycleTime" BO_ 1811 0;
BA_ "GenMsgSendType" BO_ 1811 1;
BA_ "VFrameFormat" BO_ 1811 14;
BA_ "GenMsgCycleTime" BO_ 1816 0;
BA_ "GenMsgSendType" BO_ 1816 1;
BA_ "VFrameFormat" BO_ 1816 14;
BA_ "GenMsgCycleTime" BO_ 1819 0;
BA_ "GenMsgSendType" BO_ 1819 1;
BA_ "VFrameFormat" BO_ 1819 14;
BA_ "GenMsgCycleTime" BO_ 1824 0;
BA_ "GenMsgSendType" BO_ 1824 1;
BA_ "VFrameFormat" BO_ 1824 14;
BA_ "GenMsgCycleTime" BO_ 1832 0;
BA_ "GenMsgSendType" BO_ 1832 1;
BA_ "VFrameFormat" BO_ 1832 14;
BA_ "GenMsgCycleTime" BO_ 1843 0;
BA_ "GenMsgSendType" BO_ 1843 1;
BA_ "VFrameFormat" BO_ 1843 14;
BA_ "GenMsgCycleTime" BO_ 1845 0;
BA_ "GenMsgSendType" BO_ 1845 1;
BA_ "VFrameFormat" BO_ 1845 14;
BA_ "GenMsgCycleTime" BO_ 1851 0;
BA_ "GenMsgSendType" BO_ 1851 1;
BA_ "VFrameFormat" BO_ 1851 14;
BA_ "GenMsgCycleTime" BO_ 1853 0;
BA_ "GenMsgSendType" BO_ 1853 1;
BA_ "VFrameFormat" BO_ 1853 14;
BA_ "GenMsgCycleTime" BO_ 1875 0;
BA_ "GenMsgSendType" BO_ 1875 1;
BA_ "VFrameFormat" BO_ 1875 14;
BA_ "GenMsgCycleTime" BO_ 1883 0;
BA_ "GenMsgSendType" BO_ 1883 1;
BA_ "VFrameFormat" BO_ 1883 14;
BA_ "GenMsgCycleTime" BO_ 1892 0;
BA_ "GenMsgSendType" BO_ 1892 1;
BA_ "VFrameFormat" BO_ 1892 14;
BA_ "GenMsgCycleTime" BO_ 1900 0;
BA_ "GenMsgSendType" BO_ 1900 1;
BA_ "VFrameFormat" BO_ 1900 14;
BA_ "GenMsgCycleTime" BO_ 1910 0;
BA_ "GenMsgSendType" BO_ 1910 1;
BA_ "VFrameFormat" BO_ 1910 14;
BA_ "GenMsgCycleTime" BO_ 1911 0;
BA_ "GenMsgSendType" BO_ 1911 1;
BA_ "VFrameFormat" BO_ 1911 14;
BA_ "GenMsgCycleTime" BO_ 1918 0;
BA_ "GenMsgSendType" BO_ 1918 1;
BA_ "VFrameFormat" BO_ 1918 14;
BA_ "GenMsgCycleTime" BO_ 1919 0;
BA_ "GenMsgSendType" BO_ 1919 1;
BA_ "VFrameFormat" BO_ 1919 14;
BA_ "GenMsgCycleTime" BO_ 1955 0;
BA_ "GenMsgSendType" BO_ 1955 1;
BA_ "VFrameFormat" BO_ 1955 14;
BA_ "GenMsgCycleTime" BO_ 1957 0;
BA_ "GenMsgSendType" BO_ 1957 1;
BA_ "VFrameFormat" BO_ 1957 14;
BA_ "GenMsgCycleTime" BO_ 1963 0;
BA_ "GenMsgSendType" BO_ 1963 1;
BA_ "VFrameFormat" BO_ 1963 14;
BA_ "GenMsgCycleTime" BO_ 1965 0;
BA_ "GenMsgSendType" BO_ 1965 1;
BA_ "VFrameFormat" BO_ 1965 14;
BA_ "GenMsgCycleTime" BO_ 1984 0;
BA_ "GenMsgSendType" BO_ 1984 1;
BA_ "VFrameFormat" BO_ 1984 14;
BA_ "GenMsgCycleTime" BO_ 1992 0;
BA_ "GenMsgSendType" BO_ 1992 1;
BA_ "VFrameFormat" BO_ 1992 14;
BA_ "GenMsgCycleTime" BO_ 2000 0;
BA_ "GenMsgSendType" BO_ 2000 1;
BA_ "VFrameFormat" BO_ 2000 14;
BA_ "GenMsgCycleTime" BO_ 2004 0;
BA_ "GenMsgSendType" BO_ 2004 1;
BA_ "VFrameFormat" BO_ 2004 14;
BA_ "GenMsgCycleTime" BO_ 2005 0;
BA_ "GenMsgSendType" BO_ 2005 1;
BA_ "VFrameFormat" BO_ 2005 14;
BA_ "GenMsgCycleTime" BO_ 2006 0;
BA_ "GenMsgSendType" BO_ 2006 1;
BA_ "VFrameFormat" BO_ 2006 14;
BA_ "GenMsgCycleTime" BO_ 2007 0;
BA_ "GenMsgSendType" BO_ 2007 1;
BA_ "VFrameFormat" BO_ 2007 14;
BA_ "GenMsgCycleTime" BO_ 2008 0;
BA_ "GenMsgSendType" BO_ 2008 1;
BA_ "VFrameFormat" BO_ 2008 14;
BA_ "GenMsgCycleTime" BO_ 2015 0;
BA_ "GenMsgSendType" BO_ 2015 1;
BA_ "VFrameFormat" BO_ 2015 14;
BA_ "GenMsgCycleTime" BO_ 2016 0;
BA_ "GenMsgSendType" BO_ 2016 1;
BA_ "VFrameFormat" BO_ 2016 14;
BA_ "GenMsgCycleTime" BO_ 2017 0;
BA_ "GenMsgSendType" BO_ 2017 1;
BA_ "VFrameFormat" BO_ 2017 14;
BA_ "GenMsgCycleTime" BO_ 2024 0;
BA_ "GenMsgSendType" BO_ 2024 1;
BA_ "VFrameFormat" BO_ 2024 14;
BA_ "GenMsgCycleTime" BO_ 2025 0;
BA_ "GenMsgSendType" BO_ 2025 1;
BA_ "VFrameFormat" BO_ 2025 14;
BA_ "GenMsgCycleTime" BO_ 2033 0;
BA_ "GenMsgSendType" BO_ 2033 1;
BA_ "VFrameFormat" BO_ 2033 14;
BA_ "GenMsgCycleTime" BO_ 2041 0;
BA_ "GenMsgSendType" BO_ 2041 1;
BA_ "VFrameFormat" BO_ 2041 14;
BA_ "GenSigCycleTime" SG_ 1407 VIU_FL_NotSleep_Index 1000;
BA_ "GenSigSendType" SG_ 1407 VIU_FL_NotSleep_Index 0;
BA_ "GenSigStartValue" SG_ 1407 VIU_FL_NotSleep_Index 0;
BA_ "GenSigInvalidValue" SG_ 1407 VIU_FL_NotSleep_Index "NA";
BA_ "GenSigCycleTime" SG_ 1407 VIU_FL_NotSleep_IndexTotal 1000;
BA_ "GenSigSendType" SG_ 1407 VIU_FL_NotSleep_IndexTotal 0;
BA_ "GenSigStartValue" SG_ 1407 VIU_FL_NotSleep_IndexTotal 0;
BA_ "GenSigInvalidValue" SG_ 1407 VIU_FL_NotSleep_IndexTotal "NA";
BA_ "GenSigCycleTime" SG_ 1407 VIU_FL_NotSleep_Nmnumber 1000;
BA_ "GenSigSendType" SG_ 1407 VIU_FL_NotSleep_Nmnumber 0;
BA_ "GenSigStartValue" SG_ 1407 VIU_FL_NotSleep_Nmnumber 0;
BA_ "GenSigInvalidValue" SG_ 1407 VIU_FL_NotSleep_Nmnumber "NA";
BA_ "GenSigCycleTime" SG_ 1407 VIU_FL_NotSleep_serviceNumber 1000;
BA_ "GenSigSendType" SG_ 1407 VIU_FL_NotSleep_serviceNumber 0;
BA_ "GenSigStartValue" SG_ 1407 VIU_FL_NotSleep_serviceNumber 0;
BA_ "GenSigInvalidValue" SG_ 1407 VIU_FL_NotSleep_serviceNumber "NA";
BA_ "GenSigCycleTime" SG_ 1407 VIU_FL_WakeUp_BYTE0BIT0 1000;
BA_ "GenSigSendType" SG_ 1407 VIU_FL_WakeUp_BYTE0BIT0 0;
BA_ "GenSigStartValue" SG_ 1407 VIU_FL_WakeUp_BYTE0BIT0 0;
BA_ "GenSigInvalidValue" SG_ 1407 VIU_FL_WakeUp_BYTE0BIT0 0;
BA_ "GenSigCycleTime" SG_ 1407 VIU_FL_WakeUp_BYTE0BIT1 1000;
BA_ "GenSigSendType" SG_ 1407 VIU_FL_WakeUp_BYTE0BIT1 0;
BA_ "GenSigStartValue" SG_ 1407 VIU_FL_WakeUp_BYTE0BIT1 0;
BA_ "GenSigInvalidValue" SG_ 1407 VIU_FL_WakeUp_BYTE0BIT1 0;
BA_ "GenSigCycleTime" SG_ 1407 VIU_FL_WakeUp_BYTE0BIT2 1000;
BA_ "GenSigSendType" SG_ 1407 VIU_FL_WakeUp_BYTE0BIT2 0;
BA_ "GenSigStartValue" SG_ 1407 VIU_FL_WakeUp_BYTE0BIT2 0;
BA_ "GenSigInvalidValue" SG_ 1407 VIU_FL_WakeUp_BYTE0BIT2 0;
BA_ "GenSigCycleTime" SG_ 1407 VIU_FL_WakeUp_BYTE0BIT3 1000;
BA_ "GenSigSendType" SG_ 1407 VIU_FL_WakeUp_BYTE0BIT3 0;
BA_ "GenSigStartValue" SG_ 1407 VIU_FL_WakeUp_BYTE0BIT3 0;
BA_ "GenSigInvalidValue" SG_ 1407 VIU_FL_WakeUp_BYTE0BIT3 0;
BA_ "GenSigCycleTime" SG_ 1407 VIU_FL_WakeUp_BYTE0BIT4 1000;
BA_ "GenSigSendType" SG_ 1407 VIU_FL_WakeUp_BYTE0BIT4 0;
BA_ "GenSigStartValue" SG_ 1407 VIU_FL_WakeUp_BYTE0BIT4 0;
BA_ "GenSigInvalidValue" SG_ 1407 VIU_FL_WakeUp_BYTE0BIT4 0;
BA_ "GenSigCycleTime" SG_ 1407 VIU_FL_WakeUp_BYTE0BIT5 1000;
BA_ "GenSigSendType" SG_ 1407 VIU_FL_WakeUp_BYTE0BIT5 0;
BA_ "GenSigStartValue" SG_ 1407 VIU_FL_WakeUp_BYTE0BIT5 0;
BA_ "GenSigInvalidValue" SG_ 1407 VIU_FL_WakeUp_BYTE0BIT5 0;
BA_ "GenSigCycleTime" SG_ 1407 VIU_FL_WakeUp_BYTE0BIT6 1000;
BA_ "GenSigSendType" SG_ 1407 VIU_FL_WakeUp_BYTE0BIT6 0;
BA_ "GenSigStartValue" SG_ 1407 VIU_FL_WakeUp_BYTE0BIT6 0;
BA_ "GenSigInvalidValue" SG_ 1407 VIU_FL_WakeUp_BYTE0BIT6 0;
BA_ "GenSigCycleTime" SG_ 1407 VIU_FL_WakeUp_BYTE0BIT7 1000;
BA_ "GenSigSendType" SG_ 1407 VIU_FL_WakeUp_BYTE0BIT7 0;
BA_ "GenSigStartValue" SG_ 1407 VIU_FL_WakeUp_BYTE0BIT7 0;
BA_ "GenSigInvalidValue" SG_ 1407 VIU_FL_WakeUp_BYTE0BIT7 0;
BA_ "GenSigCycleTime" SG_ 1407 VIU_FL_WakeUp_BYTE1BIT0 1000;
BA_ "GenSigSendType" SG_ 1407 VIU_FL_WakeUp_BYTE1BIT0 0;
BA_ "GenSigStartValue" SG_ 1407 VIU_FL_WakeUp_BYTE1BIT0 0;
BA_ "GenSigInvalidValue" SG_ 1407 VIU_FL_WakeUp_BYTE1BIT0 0;
BA_ "GenSigCycleTime" SG_ 1407 VIU_FL_WakeUp_BYTE1BIT1 1000;
BA_ "GenSigSendType" SG_ 1407 VIU_FL_WakeUp_BYTE1BIT1 0;
BA_ "GenSigStartValue" SG_ 1407 VIU_FL_WakeUp_BYTE1BIT1 0;
BA_ "GenSigInvalidValue" SG_ 1407 VIU_FL_WakeUp_BYTE1BIT1 0;
BA_ "GenSigCycleTime" SG_ 1407 VIU_FL_WakeUp_BYTE1BIT2 1000;
BA_ "GenSigSendType" SG_ 1407 VIU_FL_WakeUp_BYTE1BIT2 0;
BA_ "GenSigStartValue" SG_ 1407 VIU_FL_WakeUp_BYTE1BIT2 0;
BA_ "GenSigInvalidValue" SG_ 1407 VIU_FL_WakeUp_BYTE1BIT2 0;
BA_ "GenSigCycleTime" SG_ 1407 VIU_FL_WakeUp_BYTE1BIT3 1000;
BA_ "GenSigSendType" SG_ 1407 VIU_FL_WakeUp_BYTE1BIT3 0;
BA_ "GenSigStartValue" SG_ 1407 VIU_FL_WakeUp_BYTE1BIT3 0;
BA_ "GenSigInvalidValue" SG_ 1407 VIU_FL_WakeUp_BYTE1BIT3 0;
BA_ "GenSigCycleTime" SG_ 1407 VIU_FL_WakeUp_BYTE1BIT4 1000;
BA_ "GenSigSendType" SG_ 1407 VIU_FL_WakeUp_BYTE1BIT4 0;
BA_ "GenSigStartValue" SG_ 1407 VIU_FL_WakeUp_BYTE1BIT4 0;
BA_ "GenSigInvalidValue" SG_ 1407 VIU_FL_WakeUp_BYTE1BIT4 0;
BA_ "GenSigCycleTime" SG_ 1407 VIU_FL_WakeUp_BYTE1BIT5 1000;
BA_ "GenSigSendType" SG_ 1407 VIU_FL_WakeUp_BYTE1BIT5 0;
BA_ "GenSigStartValue" SG_ 1407 VIU_FL_WakeUp_BYTE1BIT5 0;
BA_ "GenSigInvalidValue" SG_ 1407 VIU_FL_WakeUp_BYTE1BIT5 0;
BA_ "GenSigCycleTime" SG_ 1407 VIU_FL_WakeUp_BYTE1BIT6 1000;
BA_ "GenSigSendType" SG_ 1407 VIU_FL_WakeUp_BYTE1BIT6 0;
BA_ "GenSigStartValue" SG_ 1407 VIU_FL_WakeUp_BYTE1BIT6 0;
BA_ "GenSigInvalidValue" SG_ 1407 VIU_FL_WakeUp_BYTE1BIT6 0;
BA_ "GenSigCycleTime" SG_ 1407 VIU_FL_WakeUp_BYTE1BIT7 1000;
BA_ "GenSigSendType" SG_ 1407 VIU_FL_WakeUp_BYTE1BIT7 0;
BA_ "GenSigStartValue" SG_ 1407 VIU_FL_WakeUp_BYTE1BIT7 0;
BA_ "GenSigInvalidValue" SG_ 1407 VIU_FL_WakeUp_BYTE1BIT7 0;
BA_ "GenSigCycleTime" SG_ 1407 VIU_FL_WakeUp_BYTE2BIT0 1000;
BA_ "GenSigSendType" SG_ 1407 VIU_FL_WakeUp_BYTE2BIT0 0;
BA_ "GenSigStartValue" SG_ 1407 VIU_FL_WakeUp_BYTE2BIT0 0;
BA_ "GenSigInvalidValue" SG_ 1407 VIU_FL_WakeUp_BYTE2BIT0 0;
BA_ "GenSigCycleTime" SG_ 1407 VIU_FL_WakeUp_BYTE2BIT1 1000;
BA_ "GenSigSendType" SG_ 1407 VIU_FL_WakeUp_BYTE2BIT1 0;
BA_ "GenSigStartValue" SG_ 1407 VIU_FL_WakeUp_BYTE2BIT1 0;
BA_ "GenSigInvalidValue" SG_ 1407 VIU_FL_WakeUp_BYTE2BIT1 0;
BA_ "GenSigCycleTime" SG_ 1407 VIU_FL_WakeUp_BYTE2BIT2 1000;
BA_ "GenSigSendType" SG_ 1407 VIU_FL_WakeUp_BYTE2BIT2 0;
BA_ "GenSigStartValue" SG_ 1407 VIU_FL_WakeUp_BYTE2BIT2 0;
BA_ "GenSigInvalidValue" SG_ 1407 VIU_FL_WakeUp_BYTE2BIT2 0;
BA_ "GenSigCycleTime" SG_ 1407 VIU_FL_WakeUp_BYTE2BIT3 1000;
BA_ "GenSigSendType" SG_ 1407 VIU_FL_WakeUp_BYTE2BIT3 0;
BA_ "GenSigStartValue" SG_ 1407 VIU_FL_WakeUp_BYTE2BIT3 0;
BA_ "GenSigInvalidValue" SG_ 1407 VIU_FL_WakeUp_BYTE2BIT3 0;
BA_ "GenSigCycleTime" SG_ 1407 VIU_FL_WakeUp_BYTE2BIT4 1000;
BA_ "GenSigSendType" SG_ 1407 VIU_FL_WakeUp_BYTE2BIT4 0;
BA_ "GenSigStartValue" SG_ 1407 VIU_FL_WakeUp_BYTE2BIT4 0;
BA_ "GenSigInvalidValue" SG_ 1407 VIU_FL_WakeUp_BYTE2BIT4 0;
BA_ "GenSigCycleTime" SG_ 1407 VIU_FL_WakeUp_BYTE2BIT5 1000;
BA_ "GenSigSendType" SG_ 1407 VIU_FL_WakeUp_BYTE2BIT5 0;
BA_ "GenSigStartValue" SG_ 1407 VIU_FL_WakeUp_BYTE2BIT5 0;
BA_ "GenSigInvalidValue" SG_ 1407 VIU_FL_WakeUp_BYTE2BIT5 0;
BA_ "GenSigCycleTime" SG_ 1407 VIU_FL_WakeUp_BYTE2BIT6 1000;
BA_ "GenSigSendType" SG_ 1407 VIU_FL_WakeUp_BYTE2BIT6 0;
BA_ "GenSigStartValue" SG_ 1407 VIU_FL_WakeUp_BYTE2BIT6 0;
BA_ "GenSigInvalidValue" SG_ 1407 VIU_FL_WakeUp_BYTE2BIT6 0;
BA_ "GenSigCycleTime" SG_ 1407 VIU_FL_WakeUp_BYTE2BIT7 1000;
BA_ "GenSigSendType" SG_ 1407 VIU_FL_WakeUp_BYTE2BIT7 0;
BA_ "GenSigStartValue" SG_ 1407 VIU_FL_WakeUp_BYTE2BIT7 0;
BA_ "GenSigInvalidValue" SG_ 1407 VIU_FL_WakeUp_BYTE2BIT7 0;
BA_ "GenSigCycleTime" SG_ 1407 VIU_FL_WakeUp_BYTE3BIT0 1000;
BA_ "GenSigSendType" SG_ 1407 VIU_FL_WakeUp_BYTE3BIT0 0;
BA_ "GenSigStartValue" SG_ 1407 VIU_FL_WakeUp_BYTE3BIT0 0;
BA_ "GenSigInvalidValue" SG_ 1407 VIU_FL_WakeUp_BYTE3BIT0 0;
BA_ "GenSigCycleTime" SG_ 1407 VIU_FL_WakeUp_BYTE3BIT1 1000;
BA_ "GenSigSendType" SG_ 1407 VIU_FL_WakeUp_BYTE3BIT1 0;
BA_ "GenSigStartValue" SG_ 1407 VIU_FL_WakeUp_BYTE3BIT1 0;
BA_ "GenSigInvalidValue" SG_ 1407 VIU_FL_WakeUp_BYTE3BIT1 0;
BA_ "GenSigCycleTime" SG_ 1407 VIU_FL_WakeUp_BYTE3BIT2 1000;
BA_ "GenSigSendType" SG_ 1407 VIU_FL_WakeUp_BYTE3BIT2 0;
BA_ "GenSigStartValue" SG_ 1407 VIU_FL_WakeUp_BYTE3BIT2 0;
BA_ "GenSigInvalidValue" SG_ 1407 VIU_FL_WakeUp_BYTE3BIT2 0;
BA_ "GenSigCycleTime" SG_ 1407 VIU_FL_WakeUp_BYTE3BIT3 1000;
BA_ "GenSigSendType" SG_ 1407 VIU_FL_WakeUp_BYTE3BIT3 0;
BA_ "GenSigStartValue" SG_ 1407 VIU_FL_WakeUp_BYTE3BIT3 0;
BA_ "GenSigInvalidValue" SG_ 1407 VIU_FL_WakeUp_BYTE3BIT3 0;
BA_ "GenSigCycleTime" SG_ 1407 VIU_FL_WakeUp_BYTE3BIT4 1000;
BA_ "GenSigSendType" SG_ 1407 VIU_FL_WakeUp_BYTE3BIT4 0;
BA_ "GenSigStartValue" SG_ 1407 VIU_FL_WakeUp_BYTE3BIT4 0;
BA_ "GenSigInvalidValue" SG_ 1407 VIU_FL_WakeUp_BYTE3BIT4 0;
BA_ "GenSigCycleTime" SG_ 1407 VIU_FL_WakeUp_BYTE3BIT5 1000;
BA_ "GenSigSendType" SG_ 1407 VIU_FL_WakeUp_BYTE3BIT5 0;
BA_ "GenSigStartValue" SG_ 1407 VIU_FL_WakeUp_BYTE3BIT5 0;
BA_ "GenSigInvalidValue" SG_ 1407 VIU_FL_WakeUp_BYTE3BIT5 0;
BA_ "GenSigCycleTime" SG_ 1407 VIU_FL_WakeUp_BYTE3BIT6 1000;
BA_ "GenSigSendType" SG_ 1407 VIU_FL_WakeUp_BYTE3BIT6 0;
BA_ "GenSigStartValue" SG_ 1407 VIU_FL_WakeUp_BYTE3BIT6 0;
BA_ "GenSigInvalidValue" SG_ 1407 VIU_FL_WakeUp_BYTE3BIT6 0;
BA_ "GenSigCycleTime" SG_ 1407 VIU_FL_WakeUp_BYTE3BIT7 1000;
BA_ "GenSigSendType" SG_ 1407 VIU_FL_WakeUp_BYTE3BIT7 0;
BA_ "GenSigStartValue" SG_ 1407 VIU_FL_WakeUp_BYTE3BIT7 0;
BA_ "GenSigInvalidValue" SG_ 1407 VIU_FL_WakeUp_BYTE3BIT7 0;
BA_ "GenSigCycleTime" SG_ 1407 VIU_FL_WakeUp_BYTE4BIT0 1000;
BA_ "GenSigSendType" SG_ 1407 VIU_FL_WakeUp_BYTE4BIT0 0;
BA_ "GenSigStartValue" SG_ 1407 VIU_FL_WakeUp_BYTE4BIT0 0;
BA_ "GenSigInvalidValue" SG_ 1407 VIU_FL_WakeUp_BYTE4BIT0 0;
BA_ "GenSigCycleTime" SG_ 1407 VIU_FL_WakeUp_BYTE4BIT1 1000;
BA_ "GenSigSendType" SG_ 1407 VIU_FL_WakeUp_BYTE4BIT1 0;
BA_ "GenSigStartValue" SG_ 1407 VIU_FL_WakeUp_BYTE4BIT1 0;
BA_ "GenSigInvalidValue" SG_ 1407 VIU_FL_WakeUp_BYTE4BIT1 0;
BA_ "GenSigCycleTime" SG_ 1407 VIU_FL_WakeUp_BYTE4BIT2 1000;
BA_ "GenSigSendType" SG_ 1407 VIU_FL_WakeUp_BYTE4BIT2 0;
BA_ "GenSigStartValue" SG_ 1407 VIU_FL_WakeUp_BYTE4BIT2 0;
BA_ "GenSigInvalidValue" SG_ 1407 VIU_FL_WakeUp_BYTE4BIT2 0;
BA_ "GenSigCycleTime" SG_ 1407 VIU_FL_WakeUp_BYTE4BIT3 1000;
BA_ "GenSigSendType" SG_ 1407 VIU_FL_WakeUp_BYTE4BIT3 0;
BA_ "GenSigStartValue" SG_ 1407 VIU_FL_WakeUp_BYTE4BIT3 0;
BA_ "GenSigInvalidValue" SG_ 1407 VIU_FL_WakeUp_BYTE4BIT3 0;
BA_ "GenSigCycleTime" SG_ 1407 VIU_FL_WakeUp_BYTE4BIT4 1000;
BA_ "GenSigSendType" SG_ 1407 VIU_FL_WakeUp_BYTE4BIT4 0;
BA_ "GenSigStartValue" SG_ 1407 VIU_FL_WakeUp_BYTE4BIT4 0;
BA_ "GenSigInvalidValue" SG_ 1407 VIU_FL_WakeUp_BYTE4BIT4 0;
BA_ "GenSigCycleTime" SG_ 1407 VIU_FL_WakeUp_BYTE4BIT5 1000;
BA_ "GenSigSendType" SG_ 1407 VIU_FL_WakeUp_BYTE4BIT5 0;
BA_ "GenSigStartValue" SG_ 1407 VIU_FL_WakeUp_BYTE4BIT5 0;
BA_ "GenSigInvalidValue" SG_ 1407 VIU_FL_WakeUp_BYTE4BIT5 0;
BA_ "GenSigCycleTime" SG_ 1407 VIU_FL_WakeUp_BYTE4BIT6 1000;
BA_ "GenSigSendType" SG_ 1407 VIU_FL_WakeUp_BYTE4BIT6 0;
BA_ "GenSigStartValue" SG_ 1407 VIU_FL_WakeUp_BYTE4BIT6 0;
BA_ "GenSigInvalidValue" SG_ 1407 VIU_FL_WakeUp_BYTE4BIT6 0;
BA_ "GenSigCycleTime" SG_ 1407 VIU_FL_WakeUp_BYTE4BIT7 1000;
BA_ "GenSigSendType" SG_ 1407 VIU_FL_WakeUp_BYTE4BIT7 0;
BA_ "GenSigStartValue" SG_ 1407 VIU_FL_WakeUp_BYTE4BIT7 0;
BA_ "GenSigInvalidValue" SG_ 1407 VIU_FL_WakeUp_BYTE4BIT7 0;
BA_ "GenSigCycleTime" SG_ 1407 VIU_FL_WakeUp_BYTE5BIT0 1000;
BA_ "GenSigSendType" SG_ 1407 VIU_FL_WakeUp_BYTE5BIT0 0;
BA_ "GenSigStartValue" SG_ 1407 VIU_FL_WakeUp_BYTE5BIT0 0;
BA_ "GenSigInvalidValue" SG_ 1407 VIU_FL_WakeUp_BYTE5BIT0 0;
BA_ "GenSigCycleTime" SG_ 1407 VIU_FL_WakeUp_BYTE5BIT1 1000;
BA_ "GenSigSendType" SG_ 1407 VIU_FL_WakeUp_BYTE5BIT1 0;
BA_ "GenSigStartValue" SG_ 1407 VIU_FL_WakeUp_BYTE5BIT1 0;
BA_ "GenSigInvalidValue" SG_ 1407 VIU_FL_WakeUp_BYTE5BIT1 0;
BA_ "GenSigCycleTime" SG_ 1407 VIU_FL_WakeUp_BYTE5BIT2 1000;
BA_ "GenSigSendType" SG_ 1407 VIU_FL_WakeUp_BYTE5BIT2 0;
BA_ "GenSigStartValue" SG_ 1407 VIU_FL_WakeUp_BYTE5BIT2 0;
BA_ "GenSigInvalidValue" SG_ 1407 VIU_FL_WakeUp_BYTE5BIT2 0;
BA_ "GenSigCycleTime" SG_ 1407 VIU_FL_WakeUp_BYTE5BIT3 1000;
BA_ "GenSigSendType" SG_ 1407 VIU_FL_WakeUp_BYTE5BIT3 0;
BA_ "GenSigStartValue" SG_ 1407 VIU_FL_WakeUp_BYTE5BIT3 0;
BA_ "GenSigInvalidValue" SG_ 1407 VIU_FL_WakeUp_BYTE5BIT3 0;
BA_ "GenSigCycleTime" SG_ 1407 VIU_FL_WakeUp_BYTE5BIT4 1000;
BA_ "GenSigSendType" SG_ 1407 VIU_FL_WakeUp_BYTE5BIT4 0;
BA_ "GenSigStartValue" SG_ 1407 VIU_FL_WakeUp_BYTE5BIT4 0;
BA_ "GenSigInvalidValue" SG_ 1407 VIU_FL_WakeUp_BYTE5BIT4 0;
BA_ "GenSigCycleTime" SG_ 1407 VIU_FL_WakeUp_BYTE5BIT5 1000;
BA_ "GenSigSendType" SG_ 1407 VIU_FL_WakeUp_BYTE5BIT5 0;
BA_ "GenSigStartValue" SG_ 1407 VIU_FL_WakeUp_BYTE5BIT5 0;
BA_ "GenSigInvalidValue" SG_ 1407 VIU_FL_WakeUp_BYTE5BIT5 0;
BA_ "GenSigCycleTime" SG_ 1407 VIU_FL_WakeUp_BYTE5BIT6 1000;
BA_ "GenSigSendType" SG_ 1407 VIU_FL_WakeUp_BYTE5BIT6 0;
BA_ "GenSigStartValue" SG_ 1407 VIU_FL_WakeUp_BYTE5BIT6 0;
BA_ "GenSigInvalidValue" SG_ 1407 VIU_FL_WakeUp_BYTE5BIT6 0;
BA_ "GenSigCycleTime" SG_ 1407 VIU_FL_WakeUp_BYTE5BIT7 1000;
BA_ "GenSigSendType" SG_ 1407 VIU_FL_WakeUp_BYTE5BIT7 0;
BA_ "GenSigStartValue" SG_ 1407 VIU_FL_WakeUp_BYTE5BIT7 0;
BA_ "GenSigInvalidValue" SG_ 1407 VIU_FL_WakeUp_BYTE5BIT7 0;
BA_ "GenSigCycleTime" SG_ 1407 VIU_FL_WakeUp_BYTE6BIT0 1000;
BA_ "GenSigSendType" SG_ 1407 VIU_FL_WakeUp_BYTE6BIT0 0;
BA_ "GenSigStartValue" SG_ 1407 VIU_FL_WakeUp_BYTE6BIT0 0;
BA_ "GenSigInvalidValue" SG_ 1407 VIU_FL_WakeUp_BYTE6BIT0 0;
BA_ "GenSigCycleTime" SG_ 1407 VIU_FL_WakeUp_BYTE6BIT1 1000;
BA_ "GenSigSendType" SG_ 1407 VIU_FL_WakeUp_BYTE6BIT1 0;
BA_ "GenSigStartValue" SG_ 1407 VIU_FL_WakeUp_BYTE6BIT1 0;
BA_ "GenSigInvalidValue" SG_ 1407 VIU_FL_WakeUp_BYTE6BIT1 0;
BA_ "GenSigCycleTime" SG_ 1407 VIU_FL_WakeUp_BYTE6BIT2 1000;
BA_ "GenSigSendType" SG_ 1407 VIU_FL_WakeUp_BYTE6BIT2 0;
BA_ "GenSigStartValue" SG_ 1407 VIU_FL_WakeUp_BYTE6BIT2 0;
BA_ "GenSigInvalidValue" SG_ 1407 VIU_FL_WakeUp_BYTE6BIT2 0;
BA_ "GenSigCycleTime" SG_ 1407 VIU_FL_WakeUp_BYTE6BIT3 1000;
BA_ "GenSigSendType" SG_ 1407 VIU_FL_WakeUp_BYTE6BIT3 0;
BA_ "GenSigStartValue" SG_ 1407 VIU_FL_WakeUp_BYTE6BIT3 0;
BA_ "GenSigInvalidValue" SG_ 1407 VIU_FL_WakeUp_BYTE6BIT3 0;
BA_ "GenSigCycleTime" SG_ 1407 VIU_FL_WakeUp_BYTE6BIT4 1000;
BA_ "GenSigSendType" SG_ 1407 VIU_FL_WakeUp_BYTE6BIT4 0;
BA_ "GenSigStartValue" SG_ 1407 VIU_FL_WakeUp_BYTE6BIT4 0;
BA_ "GenSigInvalidValue" SG_ 1407 VIU_FL_WakeUp_BYTE6BIT4 0;
BA_ "GenSigCycleTime" SG_ 1407 VIU_FL_WakeUp_BYTE6BIT5 1000;
BA_ "GenSigSendType" SG_ 1407 VIU_FL_WakeUp_BYTE6BIT5 0;
BA_ "GenSigStartValue" SG_ 1407 VIU_FL_WakeUp_BYTE6BIT5 0;
BA_ "GenSigInvalidValue" SG_ 1407 VIU_FL_WakeUp_BYTE6BIT5 0;
BA_ "GenSigCycleTime" SG_ 1407 VIU_FL_WakeUp_BYTE6BIT6 1000;
BA_ "GenSigSendType" SG_ 1407 VIU_FL_WakeUp_BYTE6BIT6 0;
BA_ "GenSigStartValue" SG_ 1407 VIU_FL_WakeUp_BYTE6BIT6 0;
BA_ "GenSigInvalidValue" SG_ 1407 VIU_FL_WakeUp_BYTE6BIT6 0;
BA_ "GenSigCycleTime" SG_ 1407 VIU_FL_WakeUp_BYTE6BIT7 1000;
BA_ "GenSigSendType" SG_ 1407 VIU_FL_WakeUp_BYTE6BIT7 0;
BA_ "GenSigStartValue" SG_ 1407 VIU_FL_WakeUp_BYTE6BIT7 0;
BA_ "GenSigInvalidValue" SG_ 1407 VIU_FL_WakeUp_BYTE6BIT7 0;
BA_ "GenSigCycleTime" SG_ 1407 VIU_FL_WakeUp_BYTE7BIT0 1000;
BA_ "GenSigSendType" SG_ 1407 VIU_FL_WakeUp_BYTE7BIT0 0;
BA_ "GenSigStartValue" SG_ 1407 VIU_FL_WakeUp_BYTE7BIT0 0;
BA_ "GenSigInvalidValue" SG_ 1407 VIU_FL_WakeUp_BYTE7BIT0 0;
BA_ "GenSigCycleTime" SG_ 1407 VIU_FL_WakeUp_BYTE7BIT1 1000;
BA_ "GenSigSendType" SG_ 1407 VIU_FL_WakeUp_BYTE7BIT1 0;
BA_ "GenSigStartValue" SG_ 1407 VIU_FL_WakeUp_BYTE7BIT1 0;
BA_ "GenSigInvalidValue" SG_ 1407 VIU_FL_WakeUp_BYTE7BIT1 0;
BA_ "GenSigCycleTime" SG_ 1407 VIU_FL_WakeUp_BYTE7BIT2 1000;
BA_ "GenSigSendType" SG_ 1407 VIU_FL_WakeUp_BYTE7BIT2 0;
BA_ "GenSigStartValue" SG_ 1407 VIU_FL_WakeUp_BYTE7BIT2 0;
BA_ "GenSigInvalidValue" SG_ 1407 VIU_FL_WakeUp_BYTE7BIT2 0;
BA_ "GenSigCycleTime" SG_ 1407 VIU_FL_WakeUp_BYTE7BIT3 1000;
BA_ "GenSigSendType" SG_ 1407 VIU_FL_WakeUp_BYTE7BIT3 0;
BA_ "GenSigStartValue" SG_ 1407 VIU_FL_WakeUp_BYTE7BIT3 0;
BA_ "GenSigInvalidValue" SG_ 1407 VIU_FL_WakeUp_BYTE7BIT3 0;
BA_ "GenSigCycleTime" SG_ 1407 VIU_FL_WakeUp_BYTE7BIT4 1000;
BA_ "GenSigSendType" SG_ 1407 VIU_FL_WakeUp_BYTE7BIT4 0;
BA_ "GenSigStartValue" SG_ 1407 VIU_FL_WakeUp_BYTE7BIT4 0;
BA_ "GenSigInvalidValue" SG_ 1407 VIU_FL_WakeUp_BYTE7BIT4 0;
BA_ "GenSigCycleTime" SG_ 1407 VIU_FL_WakeUp_BYTE7BIT5 1000;
BA_ "GenSigSendType" SG_ 1407 VIU_FL_WakeUp_BYTE7BIT5 0;
BA_ "GenSigStartValue" SG_ 1407 VIU_FL_WakeUp_BYTE7BIT5 0;
BA_ "GenSigInvalidValue" SG_ 1407 VIU_FL_WakeUp_BYTE7BIT5 0;
BA_ "GenSigCycleTime" SG_ 1407 VIU_FL_WakeUp_BYTE7BIT6 1000;
BA_ "GenSigSendType" SG_ 1407 VIU_FL_WakeUp_BYTE7BIT6 0;
BA_ "GenSigStartValue" SG_ 1407 VIU_FL_WakeUp_BYTE7BIT6 0;
BA_ "GenSigInvalidValue" SG_ 1407 VIU_FL_WakeUp_BYTE7BIT6 0;
BA_ "GenSigCycleTime" SG_ 1407 VIU_FL_WakeUp_BYTE7BIT7 1000;
BA_ "GenSigSendType" SG_ 1407 VIU_FL_WakeUp_BYTE7BIT7 0;
BA_ "GenSigStartValue" SG_ 1407 VIU_FL_WakeUp_BYTE7BIT7 0;
BA_ "GenSigInvalidValue" SG_ 1407 VIU_FL_WakeUp_BYTE7BIT7 0;
BA_ "GenSigCycleTime" SG_ 1407 VIU_FL_WakeUp_BYTE15BIT0 1000;
BA_ "GenSigSendType" SG_ 1407 VIU_FL_WakeUp_BYTE15BIT0 0;
BA_ "GenSigStartValue" SG_ 1407 VIU_FL_WakeUp_BYTE15BIT0 0;
BA_ "GenSigInvalidValue" SG_ 1407 VIU_FL_WakeUp_BYTE15BIT0 0;
BA_ "GenSigCycleTime" SG_ 1407 VIU_FL_WakeUp_BYTE15BIT1 1000;
BA_ "GenSigSendType" SG_ 1407 VIU_FL_WakeUp_BYTE15BIT1 0;
BA_ "GenSigStartValue" SG_ 1407 VIU_FL_WakeUp_BYTE15BIT1 0;
BA_ "GenSigInvalidValue" SG_ 1407 VIU_FL_WakeUp_BYTE15BIT1 0;
BA_ "GenSigCycleTime" SG_ 1411 IP_WakeUp_BYTE3BIT0 1000;
BA_ "GenSigSendType" SG_ 1411 IP_WakeUp_BYTE3BIT0 0;
BA_ "GenSigStartValue" SG_ 1411 IP_WakeUp_BYTE3BIT0 0;
BA_ "GenSigInvalidValue" SG_ 1411 IP_WakeUp_BYTE3BIT0 0;
BA_ "GenSigCycleTime" SG_ 1411 IP_NotSleep_BYTE7BIT0 1000;
BA_ "GenSigSendType" SG_ 1411 IP_NotSleep_BYTE7BIT0 0;
BA_ "GenSigStartValue" SG_ 1411 IP_NotSleep_BYTE7BIT0 0;
BA_ "GenSigInvalidValue" SG_ 1411 IP_NotSleep_BYTE7BIT0 0;
BA_ "GenSigCycleTime" SG_ 1411 IP_NotSleep_BYTE7BIT1 1000;
BA_ "GenSigSendType" SG_ 1411 IP_NotSleep_BYTE7BIT1 0;
BA_ "GenSigStartValue" SG_ 1411 IP_NotSleep_BYTE7BIT1 0;
BA_ "GenSigInvalidValue" SG_ 1411 IP_NotSleep_BYTE7BIT1 0;
BA_ "GenSigCycleTime" SG_ 1417 VIU_FR_WakeUp_BYTE0BIT0 1000;
BA_ "GenSigSendType" SG_ 1417 VIU_FR_WakeUp_BYTE0BIT0 0;
BA_ "GenSigStartValue" SG_ 1417 VIU_FR_WakeUp_BYTE0BIT0 0;
BA_ "GenSigInvalidValue" SG_ 1417 VIU_FR_WakeUp_BYTE0BIT0 0;
BA_ "GenSigCycleTime" SG_ 1417 VIU_FR_WakeUp_BYTE0BIT1 1000;
BA_ "GenSigSendType" SG_ 1417 VIU_FR_WakeUp_BYTE0BIT1 0;
BA_ "GenSigStartValue" SG_ 1417 VIU_FR_WakeUp_BYTE0BIT1 0;
BA_ "GenSigInvalidValue" SG_ 1417 VIU_FR_WakeUp_BYTE0BIT1 0;
BA_ "GenSigCycleTime" SG_ 1417 VIU_FR_WakeUp_BYTE0BIT2 1000;
BA_ "GenSigSendType" SG_ 1417 VIU_FR_WakeUp_BYTE0BIT2 0;
BA_ "GenSigStartValue" SG_ 1417 VIU_FR_WakeUp_BYTE0BIT2 0;
BA_ "GenSigInvalidValue" SG_ 1417 VIU_FR_WakeUp_BYTE0BIT2 0;
BA_ "GenSigCycleTime" SG_ 1417 VIU_FR_WakeUp_BYTE0BIT3 1000;
BA_ "GenSigSendType" SG_ 1417 VIU_FR_WakeUp_BYTE0BIT3 0;
BA_ "GenSigStartValue" SG_ 1417 VIU_FR_WakeUp_BYTE0BIT3 0;
BA_ "GenSigInvalidValue" SG_ 1417 VIU_FR_WakeUp_BYTE0BIT3 0;
BA_ "GenSigCycleTime" SG_ 1417 VIU_FR_WakeUp_BYTE0BIT4 1000;
BA_ "GenSigSendType" SG_ 1417 VIU_FR_WakeUp_BYTE0BIT4 0;
BA_ "GenSigStartValue" SG_ 1417 VIU_FR_WakeUp_BYTE0BIT4 0;
BA_ "GenSigInvalidValue" SG_ 1417 VIU_FR_WakeUp_BYTE0BIT4 0;
BA_ "GenSigCycleTime" SG_ 1417 VIU_FR_WakeUp_BYTE0BIT5 1000;
BA_ "GenSigSendType" SG_ 1417 VIU_FR_WakeUp_BYTE0BIT5 0;
BA_ "GenSigStartValue" SG_ 1417 VIU_FR_WakeUp_BYTE0BIT5 0;
BA_ "GenSigInvalidValue" SG_ 1417 VIU_FR_WakeUp_BYTE0BIT5 0;
BA_ "GenSigCycleTime" SG_ 1417 VIU_FR_WakeUp_BYTE0BIT6 1000;
BA_ "GenSigSendType" SG_ 1417 VIU_FR_WakeUp_BYTE0BIT6 0;
BA_ "GenSigStartValue" SG_ 1417 VIU_FR_WakeUp_BYTE0BIT6 0;
BA_ "GenSigInvalidValue" SG_ 1417 VIU_FR_WakeUp_BYTE0BIT6 0;
BA_ "GenSigCycleTime" SG_ 1417 VIU_FR_WakeUp_BYTE0BIT7 1000;
BA_ "GenSigSendType" SG_ 1417 VIU_FR_WakeUp_BYTE0BIT7 0;
BA_ "GenSigStartValue" SG_ 1417 VIU_FR_WakeUp_BYTE0BIT7 0;
BA_ "GenSigInvalidValue" SG_ 1417 VIU_FR_WakeUp_BYTE0BIT7 0;
BA_ "GenSigCycleTime" SG_ 1417 VIU_FR_WakeUp_BYTE1BIT0 1000;
BA_ "GenSigSendType" SG_ 1417 VIU_FR_WakeUp_BYTE1BIT0 0;
BA_ "GenSigStartValue" SG_ 1417 VIU_FR_WakeUp_BYTE1BIT0 0;
BA_ "GenSigInvalidValue" SG_ 1417 VIU_FR_WakeUp_BYTE1BIT0 0;
BA_ "GenSigCycleTime" SG_ 1417 VIU_FR_WakeUp_BYTE1BIT1 1000;
BA_ "GenSigSendType" SG_ 1417 VIU_FR_WakeUp_BYTE1BIT1 0;
BA_ "GenSigStartValue" SG_ 1417 VIU_FR_WakeUp_BYTE1BIT1 0;
BA_ "GenSigInvalidValue" SG_ 1417 VIU_FR_WakeUp_BYTE1BIT1 0;
BA_ "GenSigCycleTime" SG_ 1417 VIU_FR_WakeUp_BYTE1BIT2 1000;
BA_ "GenSigSendType" SG_ 1417 VIU_FR_WakeUp_BYTE1BIT2 0;
BA_ "GenSigStartValue" SG_ 1417 VIU_FR_WakeUp_BYTE1BIT2 0;
BA_ "GenSigInvalidValue" SG_ 1417 VIU_FR_WakeUp_BYTE1BIT2 0;
BA_ "GenSigCycleTime" SG_ 1417 VIU_FR_WakeUp_BYTE1BIT3 1000;
BA_ "GenSigSendType" SG_ 1417 VIU_FR_WakeUp_BYTE1BIT3 0;
BA_ "GenSigStartValue" SG_ 1417 VIU_FR_WakeUp_BYTE1BIT3 0;
BA_ "GenSigInvalidValue" SG_ 1417 VIU_FR_WakeUp_BYTE1BIT3 0;
BA_ "GenSigCycleTime" SG_ 1417 VIU_FR_WakeUp_BYTE1BIT4 1000;
BA_ "GenSigSendType" SG_ 1417 VIU_FR_WakeUp_BYTE1BIT4 0;
BA_ "GenSigStartValue" SG_ 1417 VIU_FR_WakeUp_BYTE1BIT4 0;
BA_ "GenSigInvalidValue" SG_ 1417 VIU_FR_WakeUp_BYTE1BIT4 0;
BA_ "GenSigCycleTime" SG_ 1417 VIU_FR_WakeUp_BYTE1BIT5 1000;
BA_ "GenSigSendType" SG_ 1417 VIU_FR_WakeUp_BYTE1BIT5 0;
BA_ "GenSigStartValue" SG_ 1417 VIU_FR_WakeUp_BYTE1BIT5 0;
BA_ "GenSigInvalidValue" SG_ 1417 VIU_FR_WakeUp_BYTE1BIT5 0;
BA_ "GenSigCycleTime" SG_ 1417 VIU_FR_WakeUp_BYTE1BIT6 1000;
BA_ "GenSigSendType" SG_ 1417 VIU_FR_WakeUp_BYTE1BIT6 0;
BA_ "GenSigStartValue" SG_ 1417 VIU_FR_WakeUp_BYTE1BIT6 0;
BA_ "GenSigInvalidValue" SG_ 1417 VIU_FR_WakeUp_BYTE1BIT6 0;
BA_ "GenSigCycleTime" SG_ 1417 VIU_FR_WakeUp_BYTE1BIT7 1000;
BA_ "GenSigSendType" SG_ 1417 VIU_FR_WakeUp_BYTE1BIT7 0;
BA_ "GenSigStartValue" SG_ 1417 VIU_FR_WakeUp_BYTE1BIT7 0;
BA_ "GenSigInvalidValue" SG_ 1417 VIU_FR_WakeUp_BYTE1BIT7 0;
BA_ "GenSigCycleTime" SG_ 1417 VIU_FR_WakeUp_BYTE2BIT0 1000;
BA_ "GenSigSendType" SG_ 1417 VIU_FR_WakeUp_BYTE2BIT0 0;
BA_ "GenSigStartValue" SG_ 1417 VIU_FR_WakeUp_BYTE2BIT0 0;
BA_ "GenSigInvalidValue" SG_ 1417 VIU_FR_WakeUp_BYTE2BIT0 0;
BA_ "GenSigCycleTime" SG_ 1417 VIU_FR_WakeUp_BYTE2BIT1 1000;
BA_ "GenSigSendType" SG_ 1417 VIU_FR_WakeUp_BYTE2BIT1 0;
BA_ "GenSigStartValue" SG_ 1417 VIU_FR_WakeUp_BYTE2BIT1 0;
BA_ "GenSigInvalidValue" SG_ 1417 VIU_FR_WakeUp_BYTE2BIT1 0;
BA_ "GenSigCycleTime" SG_ 1417 VIU_FR_WakeUp_BYTE2BIT2 1000;
BA_ "GenSigSendType" SG_ 1417 VIU_FR_WakeUp_BYTE2BIT2 0;
BA_ "GenSigStartValue" SG_ 1417 VIU_FR_WakeUp_BYTE2BIT2 0;
BA_ "GenSigInvalidValue" SG_ 1417 VIU_FR_WakeUp_BYTE2BIT2 0;
BA_ "GenSigCycleTime" SG_ 1417 VIU_FR_WakeUp_BYTE2BIT3 1000;
BA_ "GenSigSendType" SG_ 1417 VIU_FR_WakeUp_BYTE2BIT3 0;
BA_ "GenSigStartValue" SG_ 1417 VIU_FR_WakeUp_BYTE2BIT3 0;
BA_ "GenSigInvalidValue" SG_ 1417 VIU_FR_WakeUp_BYTE2BIT3 0;
BA_ "GenSigCycleTime" SG_ 1417 VIU_FR_WakeUp_BYTE2BIT4 1000;
BA_ "GenSigSendType" SG_ 1417 VIU_FR_WakeUp_BYTE2BIT4 0;
BA_ "GenSigStartValue" SG_ 1417 VIU_FR_WakeUp_BYTE2BIT4 0;
BA_ "GenSigInvalidValue" SG_ 1417 VIU_FR_WakeUp_BYTE2BIT4 0;
BA_ "GenSigCycleTime" SG_ 1417 VIU_FR_WakeUp_BYTE2BIT5 1000;
BA_ "GenSigSendType" SG_ 1417 VIU_FR_WakeUp_BYTE2BIT5 0;
BA_ "GenSigStartValue" SG_ 1417 VIU_FR_WakeUp_BYTE2BIT5 0;
BA_ "GenSigInvalidValue" SG_ 1417 VIU_FR_WakeUp_BYTE2BIT5 0;
BA_ "GenSigCycleTime" SG_ 1417 VIU_FR_WakeUp_BYTE2BIT6 1000;
BA_ "GenSigSendType" SG_ 1417 VIU_FR_WakeUp_BYTE2BIT6 0;
BA_ "GenSigStartValue" SG_ 1417 VIU_FR_WakeUp_BYTE2BIT6 0;
BA_ "GenSigInvalidValue" SG_ 1417 VIU_FR_WakeUp_BYTE2BIT6 0;
BA_ "GenSigCycleTime" SG_ 1417 VIU_FR_WakeUp_BYTE2BIT7 1000;
BA_ "GenSigSendType" SG_ 1417 VIU_FR_WakeUp_BYTE2BIT7 0;
BA_ "GenSigStartValue" SG_ 1417 VIU_FR_WakeUp_BYTE2BIT7 0;
BA_ "GenSigInvalidValue" SG_ 1417 VIU_FR_WakeUp_BYTE2BIT7 0;
BA_ "GenSigCycleTime" SG_ 1417 VIU_FR_WakeUp_BYTE3BIT0 1000;
BA_ "GenSigSendType" SG_ 1417 VIU_FR_WakeUp_BYTE3BIT0 0;
BA_ "GenSigStartValue" SG_ 1417 VIU_FR_WakeUp_BYTE3BIT0 0;
BA_ "GenSigInvalidValue" SG_ 1417 VIU_FR_WakeUp_BYTE3BIT0 0;
BA_ "GenSigCycleTime" SG_ 1417 VIU_FR_WakeUp_BYTE3BIT1 1000;
BA_ "GenSigSendType" SG_ 1417 VIU_FR_WakeUp_BYTE3BIT1 0;
BA_ "GenSigStartValue" SG_ 1417 VIU_FR_WakeUp_BYTE3BIT1 0;
BA_ "GenSigInvalidValue" SG_ 1417 VIU_FR_WakeUp_BYTE3BIT1 0;
BA_ "GenSigCycleTime" SG_ 1417 VIU_FR_WakeUp_BYTE3BIT2 1000;
BA_ "GenSigSendType" SG_ 1417 VIU_FR_WakeUp_BYTE3BIT2 0;
BA_ "GenSigStartValue" SG_ 1417 VIU_FR_WakeUp_BYTE3BIT2 0;
BA_ "GenSigInvalidValue" SG_ 1417 VIU_FR_WakeUp_BYTE3BIT2 0;
BA_ "GenSigCycleTime" SG_ 1417 VIU_FR_WakeUp_BYTE3BIT3 1000;
BA_ "GenSigSendType" SG_ 1417 VIU_FR_WakeUp_BYTE3BIT3 0;
BA_ "GenSigStartValue" SG_ 1417 VIU_FR_WakeUp_BYTE3BIT3 0;
BA_ "GenSigInvalidValue" SG_ 1417 VIU_FR_WakeUp_BYTE3BIT3 0;
BA_ "GenSigCycleTime" SG_ 1417 VIU_FR_WakeUp_BYTE3BIT4 1000;
BA_ "GenSigSendType" SG_ 1417 VIU_FR_WakeUp_BYTE3BIT4 0;
BA_ "GenSigStartValue" SG_ 1417 VIU_FR_WakeUp_BYTE3BIT4 0;
BA_ "GenSigInvalidValue" SG_ 1417 VIU_FR_WakeUp_BYTE3BIT4 0;
BA_ "GenSigCycleTime" SG_ 1417 VIU_FR_WakeUp_BYTE3BIT5 1000;
BA_ "GenSigSendType" SG_ 1417 VIU_FR_WakeUp_BYTE3BIT5 0;
BA_ "GenSigStartValue" SG_ 1417 VIU_FR_WakeUp_BYTE3BIT5 0;
BA_ "GenSigInvalidValue" SG_ 1417 VIU_FR_WakeUp_BYTE3BIT5 0;
BA_ "GenSigCycleTime" SG_ 1417 VIU_FR_WakeUp_BYTE3BIT6 1000;
BA_ "GenSigSendType" SG_ 1417 VIU_FR_WakeUp_BYTE3BIT6 0;
BA_ "GenSigStartValue" SG_ 1417 VIU_FR_WakeUp_BYTE3BIT6 0;
BA_ "GenSigInvalidValue" SG_ 1417 VIU_FR_WakeUp_BYTE3BIT6 0;
BA_ "GenSigCycleTime" SG_ 1417 VIU_FR_WakeUp_BYTE3BIT7 1000;
BA_ "GenSigSendType" SG_ 1417 VIU_FR_WakeUp_BYTE3BIT7 0;
BA_ "GenSigStartValue" SG_ 1417 VIU_FR_WakeUp_BYTE3BIT7 0;
BA_ "GenSigInvalidValue" SG_ 1417 VIU_FR_WakeUp_BYTE3BIT7 0;
BA_ "GenSigCycleTime" SG_ 1417 VIU_FR_WakeUp_BYTE4BIT0 1000;
BA_ "GenSigSendType" SG_ 1417 VIU_FR_WakeUp_BYTE4BIT0 0;
BA_ "GenSigStartValue" SG_ 1417 VIU_FR_WakeUp_BYTE4BIT0 0;
BA_ "GenSigInvalidValue" SG_ 1417 VIU_FR_WakeUp_BYTE4BIT0 0;
BA_ "GenSigCycleTime" SG_ 1417 VIU_FR_WakeUp_BYTE4BIT1 1000;
BA_ "GenSigSendType" SG_ 1417 VIU_FR_WakeUp_BYTE4BIT1 0;
BA_ "GenSigStartValue" SG_ 1417 VIU_FR_WakeUp_BYTE4BIT1 0;
BA_ "GenSigInvalidValue" SG_ 1417 VIU_FR_WakeUp_BYTE4BIT1 0;
BA_ "GenSigCycleTime" SG_ 1417 VIU_FR_WakeUp_BYTE4BIT2 1000;
BA_ "GenSigSendType" SG_ 1417 VIU_FR_WakeUp_BYTE4BIT2 0;
BA_ "GenSigStartValue" SG_ 1417 VIU_FR_WakeUp_BYTE4BIT2 0;
BA_ "GenSigInvalidValue" SG_ 1417 VIU_FR_WakeUp_BYTE4BIT2 0;
BA_ "GenSigCycleTime" SG_ 1417 VIU_FR_WakeUp_BYTE4BIT3 1000;
BA_ "GenSigSendType" SG_ 1417 VIU_FR_WakeUp_BYTE4BIT3 0;
BA_ "GenSigStartValue" SG_ 1417 VIU_FR_WakeUp_BYTE4BIT3 0;
BA_ "GenSigInvalidValue" SG_ 1417 VIU_FR_WakeUp_BYTE4BIT3 0;
BA_ "GenSigCycleTime" SG_ 1417 VIU_FR_WakeUp_BYTE4BIT4 1000;
BA_ "GenSigSendType" SG_ 1417 VIU_FR_WakeUp_BYTE4BIT4 0;
BA_ "GenSigStartValue" SG_ 1417 VIU_FR_WakeUp_BYTE4BIT4 0;
BA_ "GenSigInvalidValue" SG_ 1417 VIU_FR_WakeUp_BYTE4BIT4 0;
BA_ "GenSigCycleTime" SG_ 1417 VIU_FR_WakeUp_BYTE4BIT5 1000;
BA_ "GenSigSendType" SG_ 1417 VIU_FR_WakeUp_BYTE4BIT5 0;
BA_ "GenSigStartValue" SG_ 1417 VIU_FR_WakeUp_BYTE4BIT5 0;
BA_ "GenSigInvalidValue" SG_ 1417 VIU_FR_WakeUp_BYTE4BIT5 0;
BA_ "GenSigCycleTime" SG_ 1417 VIU_FR_WakeUp_BYTE4BIT6 1000;
BA_ "GenSigSendType" SG_ 1417 VIU_FR_WakeUp_BYTE4BIT6 0;
BA_ "GenSigStartValue" SG_ 1417 VIU_FR_WakeUp_BYTE4BIT6 0;
BA_ "GenSigInvalidValue" SG_ 1417 VIU_FR_WakeUp_BYTE4BIT6 0;
BA_ "GenSigCycleTime" SG_ 1417 VIU_FR_WakeUp_BYTE4BIT7 1000;
BA_ "GenSigSendType" SG_ 1417 VIU_FR_WakeUp_BYTE4BIT7 0;
BA_ "GenSigStartValue" SG_ 1417 VIU_FR_WakeUp_BYTE4BIT7 0;
BA_ "GenSigInvalidValue" SG_ 1417 VIU_FR_WakeUp_BYTE4BIT7 0;
BA_ "GenSigCycleTime" SG_ 1417 VIU_FR_WakeUp_BYTE5BIT0 1000;
BA_ "GenSigSendType" SG_ 1417 VIU_FR_WakeUp_BYTE5BIT0 0;
BA_ "GenSigStartValue" SG_ 1417 VIU_FR_WakeUp_BYTE5BIT0 0;
BA_ "GenSigInvalidValue" SG_ 1417 VIU_FR_WakeUp_BYTE5BIT0 0;
BA_ "GenSigCycleTime" SG_ 1417 VIU_FR_WakeUp_BYTE5BIT1 1000;
BA_ "GenSigSendType" SG_ 1417 VIU_FR_WakeUp_BYTE5BIT1 0;
BA_ "GenSigStartValue" SG_ 1417 VIU_FR_WakeUp_BYTE5BIT1 0;
BA_ "GenSigInvalidValue" SG_ 1417 VIU_FR_WakeUp_BYTE5BIT1 0;
BA_ "GenSigCycleTime" SG_ 1417 VIU_FR_WakeUp_BYTE5BIT2 1000;
BA_ "GenSigSendType" SG_ 1417 VIU_FR_WakeUp_BYTE5BIT2 0;
BA_ "GenSigStartValue" SG_ 1417 VIU_FR_WakeUp_BYTE5BIT2 0;
BA_ "GenSigInvalidValue" SG_ 1417 VIU_FR_WakeUp_BYTE5BIT2 0;
BA_ "GenSigCycleTime" SG_ 1417 VIU_FR_WakeUp_BYTE5BIT3 1000;
BA_ "GenSigSendType" SG_ 1417 VIU_FR_WakeUp_BYTE5BIT3 0;
BA_ "GenSigStartValue" SG_ 1417 VIU_FR_WakeUp_BYTE5BIT3 0;
BA_ "GenSigInvalidValue" SG_ 1417 VIU_FR_WakeUp_BYTE5BIT3 0;
BA_ "GenSigCycleTime" SG_ 1417 VIU_FR_WakeUp_BYTE5BIT4 1000;
BA_ "GenSigSendType" SG_ 1417 VIU_FR_WakeUp_BYTE5BIT4 0;
BA_ "GenSigStartValue" SG_ 1417 VIU_FR_WakeUp_BYTE5BIT4 0;
BA_ "GenSigInvalidValue" SG_ 1417 VIU_FR_WakeUp_BYTE5BIT4 0;
BA_ "GenSigCycleTime" SG_ 1417 VIU_FR_WakeUp_BYTE5BIT5 1000;
BA_ "GenSigSendType" SG_ 1417 VIU_FR_WakeUp_BYTE5BIT5 0;
BA_ "GenSigStartValue" SG_ 1417 VIU_FR_WakeUp_BYTE5BIT5 0;
BA_ "GenSigInvalidValue" SG_ 1417 VIU_FR_WakeUp_BYTE5BIT5 0;
BA_ "GenSigCycleTime" SG_ 1417 VIU_FR_WakeUp_BYTE5BIT6 1000;
BA_ "GenSigSendType" SG_ 1417 VIU_FR_WakeUp_BYTE5BIT6 0;
BA_ "GenSigStartValue" SG_ 1417 VIU_FR_WakeUp_BYTE5BIT6 0;
BA_ "GenSigInvalidValue" SG_ 1417 VIU_FR_WakeUp_BYTE5BIT6 0;
BA_ "GenSigCycleTime" SG_ 1417 VIU_FR_WakeUp_BYTE5BIT7 1000;
BA_ "GenSigSendType" SG_ 1417 VIU_FR_WakeUp_BYTE5BIT7 0;
BA_ "GenSigStartValue" SG_ 1417 VIU_FR_WakeUp_BYTE5BIT7 0;
BA_ "GenSigInvalidValue" SG_ 1417 VIU_FR_WakeUp_BYTE5BIT7 0;
BA_ "GenSigCycleTime" SG_ 1417 VIU_FR_WakeUp_BYTE6BIT0 1000;
BA_ "GenSigSendType" SG_ 1417 VIU_FR_WakeUp_BYTE6BIT0 0;
BA_ "GenSigStartValue" SG_ 1417 VIU_FR_WakeUp_BYTE6BIT0 0;
BA_ "GenSigInvalidValue" SG_ 1417 VIU_FR_WakeUp_BYTE6BIT0 0;
BA_ "GenSigCycleTime" SG_ 1417 VIU_FR_WakeUp_BYTE6BIT1 1000;
BA_ "GenSigSendType" SG_ 1417 VIU_FR_WakeUp_BYTE6BIT1 0;
BA_ "GenSigStartValue" SG_ 1417 VIU_FR_WakeUp_BYTE6BIT1 0;
BA_ "GenSigInvalidValue" SG_ 1417 VIU_FR_WakeUp_BYTE6BIT1 0;
BA_ "GenSigCycleTime" SG_ 1417 VIU_FR_WakeUp_BYTE6BIT2 1000;
BA_ "GenSigSendType" SG_ 1417 VIU_FR_WakeUp_BYTE6BIT2 0;
BA_ "GenSigStartValue" SG_ 1417 VIU_FR_WakeUp_BYTE6BIT2 0;
BA_ "GenSigInvalidValue" SG_ 1417 VIU_FR_WakeUp_BYTE6BIT2 0;
BA_ "GenSigCycleTime" SG_ 1417 VIU_FR_WakeUp_BYTE6BIT3 1000;
BA_ "GenSigSendType" SG_ 1417 VIU_FR_WakeUp_BYTE6BIT3 0;
BA_ "GenSigStartValue" SG_ 1417 VIU_FR_WakeUp_BYTE6BIT3 0;
BA_ "GenSigInvalidValue" SG_ 1417 VIU_FR_WakeUp_BYTE6BIT3 0;
BA_ "GenSigCycleTime" SG_ 1417 VIU_FR_WakeUp_BYTE6BIT4 1000;
BA_ "GenSigSendType" SG_ 1417 VIU_FR_WakeUp_BYTE6BIT4 0;
BA_ "GenSigStartValue" SG_ 1417 VIU_FR_WakeUp_BYTE6BIT4 0;
BA_ "GenSigInvalidValue" SG_ 1417 VIU_FR_WakeUp_BYTE6BIT4 0;
BA_ "GenSigCycleTime" SG_ 1417 VIU_FR_WakeUp_BYTE6BIT5 1000;
BA_ "GenSigSendType" SG_ 1417 VIU_FR_WakeUp_BYTE6BIT5 0;
BA_ "GenSigStartValue" SG_ 1417 VIU_FR_WakeUp_BYTE6BIT5 0;
BA_ "GenSigInvalidValue" SG_ 1417 VIU_FR_WakeUp_BYTE6BIT5 0;
BA_ "GenSigCycleTime" SG_ 1417 VIU_FR_WakeUp_BYTE6BIT6 1000;
BA_ "GenSigSendType" SG_ 1417 VIU_FR_WakeUp_BYTE6BIT6 0;
BA_ "GenSigStartValue" SG_ 1417 VIU_FR_WakeUp_BYTE6BIT6 0;
BA_ "GenSigInvalidValue" SG_ 1417 VIU_FR_WakeUp_BYTE6BIT6 0;
BA_ "GenSigCycleTime" SG_ 1417 VIU_FR_WakeUp_BYTE6BIT7 1000;
BA_ "GenSigSendType" SG_ 1417 VIU_FR_WakeUp_BYTE6BIT7 0;
BA_ "GenSigStartValue" SG_ 1417 VIU_FR_WakeUp_BYTE6BIT7 0;
BA_ "GenSigInvalidValue" SG_ 1417 VIU_FR_WakeUp_BYTE6BIT7 0;
BA_ "GenSigCycleTime" SG_ 1417 VIU_FR_WakeUp_BYTE7BIT0 1000;
BA_ "GenSigSendType" SG_ 1417 VIU_FR_WakeUp_BYTE7BIT0 0;
BA_ "GenSigStartValue" SG_ 1417 VIU_FR_WakeUp_BYTE7BIT0 0;
BA_ "GenSigInvalidValue" SG_ 1417 VIU_FR_WakeUp_BYTE7BIT0 0;
BA_ "GenSigCycleTime" SG_ 1417 VIU_FR_WakeUp_BYTE7BIT1 1000;
BA_ "GenSigSendType" SG_ 1417 VIU_FR_WakeUp_BYTE7BIT1 0;
BA_ "GenSigStartValue" SG_ 1417 VIU_FR_WakeUp_BYTE7BIT1 0;
BA_ "GenSigInvalidValue" SG_ 1417 VIU_FR_WakeUp_BYTE7BIT1 0;
BA_ "GenSigCycleTime" SG_ 1417 VIU_FR_WakeUp_BYTE7BIT2 1000;
BA_ "GenSigSendType" SG_ 1417 VIU_FR_WakeUp_BYTE7BIT2 0;
BA_ "GenSigStartValue" SG_ 1417 VIU_FR_WakeUp_BYTE7BIT2 0;
BA_ "GenSigInvalidValue" SG_ 1417 VIU_FR_WakeUp_BYTE7BIT2 0;
BA_ "GenSigCycleTime" SG_ 1417 VIU_FR_WakeUp_BYTE7BIT3 1000;
BA_ "GenSigSendType" SG_ 1417 VIU_FR_WakeUp_BYTE7BIT3 0;
BA_ "GenSigStartValue" SG_ 1417 VIU_FR_WakeUp_BYTE7BIT3 0;
BA_ "GenSigInvalidValue" SG_ 1417 VIU_FR_WakeUp_BYTE7BIT3 0;
BA_ "GenSigCycleTime" SG_ 1417 VIU_FR_WakeUp_BYTE7BIT4 1000;
BA_ "GenSigSendType" SG_ 1417 VIU_FR_WakeUp_BYTE7BIT4 0;
BA_ "GenSigStartValue" SG_ 1417 VIU_FR_WakeUp_BYTE7BIT4 0;
BA_ "GenSigInvalidValue" SG_ 1417 VIU_FR_WakeUp_BYTE7BIT4 0;
BA_ "GenSigCycleTime" SG_ 1417 VIU_FR_WakeUp_BYTE7BIT5 1000;
BA_ "GenSigSendType" SG_ 1417 VIU_FR_WakeUp_BYTE7BIT5 0;
BA_ "GenSigStartValue" SG_ 1417 VIU_FR_WakeUp_BYTE7BIT5 0;
BA_ "GenSigInvalidValue" SG_ 1417 VIU_FR_WakeUp_BYTE7BIT5 0;
BA_ "GenSigCycleTime" SG_ 1417 VIU_FR_WakeUp_BYTE7BIT6 1000;
BA_ "GenSigSendType" SG_ 1417 VIU_FR_WakeUp_BYTE7BIT6 0;
BA_ "GenSigStartValue" SG_ 1417 VIU_FR_WakeUp_BYTE7BIT6 0;
BA_ "GenSigInvalidValue" SG_ 1417 VIU_FR_WakeUp_BYTE7BIT6 0;
BA_ "GenSigCycleTime" SG_ 1417 VIU_FR_WakeUp_BYTE7BIT7 1000;
BA_ "GenSigSendType" SG_ 1417 VIU_FR_WakeUp_BYTE7BIT7 0;
BA_ "GenSigStartValue" SG_ 1417 VIU_FR_WakeUp_BYTE7BIT7 0;
BA_ "GenSigInvalidValue" SG_ 1417 VIU_FR_WakeUp_BYTE7BIT7 0;
BA_ "GenSigCycleTime" SG_ 1418 VIU_FR_NotSleep_Index 1000;
BA_ "GenSigSendType" SG_ 1418 VIU_FR_NotSleep_Index 0;
BA_ "GenSigStartValue" SG_ 1418 VIU_FR_NotSleep_Index 0;
BA_ "GenSigInvalidValue" SG_ 1418 VIU_FR_NotSleep_Index "NA";
BA_ "GenSigCycleTime" SG_ 1418 VIU_FR_NotSleep_IndexTotal 1000;
BA_ "GenSigSendType" SG_ 1418 VIU_FR_NotSleep_IndexTotal 0;
BA_ "GenSigStartValue" SG_ 1418 VIU_FR_NotSleep_IndexTotal 0;
BA_ "GenSigInvalidValue" SG_ 1418 VIU_FR_NotSleep_IndexTotal "NA";
BA_ "GenSigCycleTime" SG_ 1418 VIU_FR_NotSleep_Nmnumber 1000;
BA_ "GenSigSendType" SG_ 1418 VIU_FR_NotSleep_Nmnumber 0;
BA_ "GenSigStartValue" SG_ 1418 VIU_FR_NotSleep_Nmnumber 0;
BA_ "GenSigInvalidValue" SG_ 1418 VIU_FR_NotSleep_Nmnumber "NA";
BA_ "GenSigCycleTime" SG_ 1418 VIU_FR_NotSleep_serviceNumber 1000;
BA_ "GenSigSendType" SG_ 1418 VIU_FR_NotSleep_serviceNumber 0;
BA_ "GenSigStartValue" SG_ 1418 VIU_FR_NotSleep_serviceNumber 0;
BA_ "GenSigInvalidValue" SG_ 1418 VIU_FR_NotSleep_serviceNumber "NA";
BA_ "GenSigCycleTime" SG_ 1418 VIU_FR_WakeUp_BYTE15BIT0 1000;
BA_ "GenSigSendType" SG_ 1418 VIU_FR_WakeUp_BYTE15BIT0 0;
BA_ "GenSigStartValue" SG_ 1418 VIU_FR_WakeUp_BYTE15BIT0 0;
BA_ "GenSigInvalidValue" SG_ 1418 VIU_FR_WakeUp_BYTE15BIT0 0;
BA_ "GenSigCycleTime" SG_ 1418 VIU_FR_WakeUp_BYTE15BIT1 1000;
BA_ "GenSigSendType" SG_ 1418 VIU_FR_WakeUp_BYTE15BIT1 0;
BA_ "GenSigStartValue" SG_ 1418 VIU_FR_WakeUp_BYTE15BIT1 0;
BA_ "GenSigInvalidValue" SG_ 1418 VIU_FR_WakeUp_BYTE15BIT1 0;
BA_ "GenSigCycleTime" SG_ 1430 RLR_NotSleep_BYTE7BIT0 1000;
BA_ "GenSigSendType" SG_ 1430 RLR_NotSleep_BYTE7BIT0 0;
BA_ "GenSigStartValue" SG_ 1430 RLR_NotSleep_BYTE7BIT0 0;
BA_ "GenSigInvalidValue" SG_ 1430 RLR_NotSleep_BYTE7BIT0 0;
BA_ "GenSigCycleTime" SG_ 1430 RLR_NotSleep_BYTE7BIT1 1000;
BA_ "GenSigSendType" SG_ 1430 RLR_NotSleep_BYTE7BIT1 0;
BA_ "GenSigStartValue" SG_ 1430 RLR_NotSleep_BYTE7BIT1 0;
BA_ "GenSigInvalidValue" SG_ 1430 RLR_NotSleep_BYTE7BIT1 0;
BA_ "GenSigCycleTime" SG_ 1430 RLR_NotSleep_BYTE7BIT2 1000;
BA_ "GenSigSendType" SG_ 1430 RLR_NotSleep_BYTE7BIT2 0;
BA_ "GenSigStartValue" SG_ 1430 RLR_NotSleep_BYTE7BIT2 0;
BA_ "GenSigInvalidValue" SG_ 1430 RLR_NotSleep_BYTE7BIT2 0;
BA_ "GenSigCycleTime" SG_ 1430 RLR_NotSleep_BYTE7BIT3 1000;
BA_ "GenSigSendType" SG_ 1430 RLR_NotSleep_BYTE7BIT3 0;
BA_ "GenSigStartValue" SG_ 1430 RLR_NotSleep_BYTE7BIT3 0;
BA_ "GenSigInvalidValue" SG_ 1430 RLR_NotSleep_BYTE7BIT3 0;
BA_ "GenSigCycleTime" SG_ 1430 RLR_WakeUp_BYTE3BIT0 1000;
BA_ "GenSigSendType" SG_ 1430 RLR_WakeUp_BYTE3BIT0 0;
BA_ "GenSigStartValue" SG_ 1430 RLR_WakeUp_BYTE3BIT0 0;
BA_ "GenSigInvalidValue" SG_ 1430 RLR_WakeUp_BYTE3BIT0 0;
BA_ "GenSigCycleTime" SG_ 1430 RLR_WakeUp_BYTE3BIT1 1000;
BA_ "GenSigSendType" SG_ 1430 RLR_WakeUp_BYTE3BIT1 0;
BA_ "GenSigStartValue" SG_ 1430 RLR_WakeUp_BYTE3BIT1 0;
BA_ "GenSigInvalidValue" SG_ 1430 RLR_WakeUp_BYTE3BIT1 0;
BA_ "GenSigCycleTime" SG_ 1431 RRR_NotSleep_BYTE7BIT0 1000;
BA_ "GenSigSendType" SG_ 1431 RRR_NotSleep_BYTE7BIT0 0;
BA_ "GenSigStartValue" SG_ 1431 RRR_NotSleep_BYTE7BIT0 0;
BA_ "GenSigInvalidValue" SG_ 1431 RRR_NotSleep_BYTE7BIT0 0;
BA_ "GenSigCycleTime" SG_ 1431 RRR_NotSleep_BYTE7BIT1 1000;
BA_ "GenSigSendType" SG_ 1431 RRR_NotSleep_BYTE7BIT1 0;
BA_ "GenSigStartValue" SG_ 1431 RRR_NotSleep_BYTE7BIT1 0;
BA_ "GenSigInvalidValue" SG_ 1431 RRR_NotSleep_BYTE7BIT1 0;
BA_ "GenSigCycleTime" SG_ 1431 RRR_NotSleep_BYTE7BIT2 1000;
BA_ "GenSigSendType" SG_ 1431 RRR_NotSleep_BYTE7BIT2 0;
BA_ "GenSigStartValue" SG_ 1431 RRR_NotSleep_BYTE7BIT2 0;
BA_ "GenSigInvalidValue" SG_ 1431 RRR_NotSleep_BYTE7BIT2 0;
BA_ "GenSigCycleTime" SG_ 1431 RRR_NotSleep_BYTE7BIT3 1000;
BA_ "GenSigSendType" SG_ 1431 RRR_NotSleep_BYTE7BIT3 0;
BA_ "GenSigStartValue" SG_ 1431 RRR_NotSleep_BYTE7BIT3 0;
BA_ "GenSigInvalidValue" SG_ 1431 RRR_NotSleep_BYTE7BIT3 0;
BA_ "GenSigCycleTime" SG_ 1431 RRR_WakeUp_BYTE3BIT0 1000;
BA_ "GenSigSendType" SG_ 1431 RRR_WakeUp_BYTE3BIT0 0;
BA_ "GenSigStartValue" SG_ 1431 RRR_WakeUp_BYTE3BIT0 0;
BA_ "GenSigInvalidValue" SG_ 1431 RRR_WakeUp_BYTE3BIT0 0;
BA_ "GenSigCycleTime" SG_ 1431 RRR_WakeUp_BYTE3BIT1 1000;
BA_ "GenSigSendType" SG_ 1431 RRR_WakeUp_BYTE3BIT1 0;
BA_ "GenSigStartValue" SG_ 1431 RRR_WakeUp_BYTE3BIT1 0;
BA_ "GenSigInvalidValue" SG_ 1431 RRR_WakeUp_BYTE3BIT1 0;
BA_ "GenSigCycleTime" SG_ 1432 FRR_NotSleep_BYTE7BIT0 1000;
BA_ "GenSigSendType" SG_ 1432 FRR_NotSleep_BYTE7BIT0 0;
BA_ "GenSigStartValue" SG_ 1432 FRR_NotSleep_BYTE7BIT0 0;
BA_ "GenSigInvalidValue" SG_ 1432 FRR_NotSleep_BYTE7BIT0 0;
BA_ "GenSigCycleTime" SG_ 1432 FRR_NotSleep_BYTE7BIT1 1000;
BA_ "GenSigSendType" SG_ 1432 FRR_NotSleep_BYTE7BIT1 0;
BA_ "GenSigStartValue" SG_ 1432 FRR_NotSleep_BYTE7BIT1 0;
BA_ "GenSigInvalidValue" SG_ 1432 FRR_NotSleep_BYTE7BIT1 0;
BA_ "GenSigCycleTime" SG_ 1432 FRR_NotSleep_BYTE7BIT2 1000;
BA_ "GenSigSendType" SG_ 1432 FRR_NotSleep_BYTE7BIT2 0;
BA_ "GenSigStartValue" SG_ 1432 FRR_NotSleep_BYTE7BIT2 0;
BA_ "GenSigInvalidValue" SG_ 1432 FRR_NotSleep_BYTE7BIT2 0;
BA_ "GenSigCycleTime" SG_ 1432 FRR_NotSleep_BYTE7BIT3 1000;
BA_ "GenSigSendType" SG_ 1432 FRR_NotSleep_BYTE7BIT3 0;
BA_ "GenSigStartValue" SG_ 1432 FRR_NotSleep_BYTE7BIT3 0;
BA_ "GenSigInvalidValue" SG_ 1432 FRR_NotSleep_BYTE7BIT3 0;
BA_ "GenSigCycleTime" SG_ 1432 FRR_WakeUp_BYTE3BIT0 1000;
BA_ "GenSigSendType" SG_ 1432 FRR_WakeUp_BYTE3BIT0 0;
BA_ "GenSigStartValue" SG_ 1432 FRR_WakeUp_BYTE3BIT0 0;
BA_ "GenSigInvalidValue" SG_ 1432 FRR_WakeUp_BYTE3BIT0 0;
BA_ "GenSigCycleTime" SG_ 1432 FRR_WakeUp_BYTE3BIT1 1000;
BA_ "GenSigSendType" SG_ 1432 FRR_WakeUp_BYTE3BIT1 0;
BA_ "GenSigStartValue" SG_ 1432 FRR_WakeUp_BYTE3BIT1 0;
BA_ "GenSigInvalidValue" SG_ 1432 FRR_WakeUp_BYTE3BIT1 0;
BA_ "GenSigCycleTime" SG_ 1438 EVCC_WakeUp_BYTE4BIT3 1000;
BA_ "GenSigSendType" SG_ 1438 EVCC_WakeUp_BYTE4BIT3 0;
BA_ "GenSigStartValue" SG_ 1438 EVCC_WakeUp_BYTE4BIT3 0;
BA_ "GenSigInvalidValue" SG_ 1438 EVCC_WakeUp_BYTE4BIT3 0;
BA_ "GenSigCycleTime" SG_ 1438 EVCC_WakeUp_BYTE4BIT2 1000;
BA_ "GenSigSendType" SG_ 1438 EVCC_WakeUp_BYTE4BIT2 0;
BA_ "GenSigStartValue" SG_ 1438 EVCC_WakeUp_BYTE4BIT2 0;
BA_ "GenSigInvalidValue" SG_ 1438 EVCC_WakeUp_BYTE4BIT2 0;
BA_ "GenSigCycleTime" SG_ 1438 EVCC_WakeUp_BYTE4BIT1 1000;
BA_ "GenSigSendType" SG_ 1438 EVCC_WakeUp_BYTE4BIT1 0;
BA_ "GenSigStartValue" SG_ 1438 EVCC_WakeUp_BYTE4BIT1 0;
BA_ "GenSigInvalidValue" SG_ 1438 EVCC_WakeUp_BYTE4BIT1 0;
BA_ "GenSigCycleTime" SG_ 1438 EVCC_WakeUp_BYTE4BIT0 1000;
BA_ "GenSigSendType" SG_ 1438 EVCC_WakeUp_BYTE4BIT0 0;
BA_ "GenSigStartValue" SG_ 1438 EVCC_WakeUp_BYTE4BIT0 0;
BA_ "GenSigInvalidValue" SG_ 1438 EVCC_WakeUp_BYTE4BIT0 0;
BA_ "GenSigCycleTime" SG_ 1438 EVCC_NotSleep_BYTE7BIT4 1000;
BA_ "GenSigSendType" SG_ 1438 EVCC_NotSleep_BYTE7BIT4 0;
BA_ "GenSigStartValue" SG_ 1438 EVCC_NotSleep_BYTE7BIT4 0;
BA_ "GenSigInvalidValue" SG_ 1438 EVCC_NotSleep_BYTE7BIT4 0;
BA_ "GenSigCycleTime" SG_ 1438 EVCC_NotSleep_BYTE7BIT3 1000;
BA_ "GenSigSendType" SG_ 1438 EVCC_NotSleep_BYTE7BIT3 0;
BA_ "GenSigStartValue" SG_ 1438 EVCC_NotSleep_BYTE7BIT3 0;
BA_ "GenSigInvalidValue" SG_ 1438 EVCC_NotSleep_BYTE7BIT3 0;
BA_ "GenSigCycleTime" SG_ 1438 EVCC_NotSleep_BYTE7BIT2 1000;
BA_ "GenSigSendType" SG_ 1438 EVCC_NotSleep_BYTE7BIT2 0;
BA_ "GenSigStartValue" SG_ 1438 EVCC_NotSleep_BYTE7BIT2 0;
BA_ "GenSigInvalidValue" SG_ 1438 EVCC_NotSleep_BYTE7BIT2 0;
BA_ "GenSigCycleTime" SG_ 1438 EVCC_NotSleep_BYTE7BIT1 1000;
BA_ "GenSigSendType" SG_ 1438 EVCC_NotSleep_BYTE7BIT1 0;
BA_ "GenSigStartValue" SG_ 1438 EVCC_NotSleep_BYTE7BIT1 0;
BA_ "GenSigInvalidValue" SG_ 1438 EVCC_NotSleep_BYTE7BIT1 0;
BA_ "GenSigCycleTime" SG_ 1438 EVCC_NotSleep_BYTE7BIT0 1000;
BA_ "GenSigSendType" SG_ 1438 EVCC_NotSleep_BYTE7BIT0 0;
BA_ "GenSigStartValue" SG_ 1438 EVCC_NotSleep_BYTE7BIT0 0;
BA_ "GenSigInvalidValue" SG_ 1438 EVCC_NotSleep_BYTE7BIT0 0;
BA_ "GenSigCycleTime" SG_ 1442 FLR_NotSleep_BYTE7BIT0 1000;
BA_ "GenSigSendType" SG_ 1442 FLR_NotSleep_BYTE7BIT0 0;
BA_ "GenSigStartValue" SG_ 1442 FLR_NotSleep_BYTE7BIT0 0;
BA_ "GenSigInvalidValue" SG_ 1442 FLR_NotSleep_BYTE7BIT0 0;
BA_ "GenSigCycleTime" SG_ 1442 FLR_NotSleep_BYTE7BIT1 1000;
BA_ "GenSigSendType" SG_ 1442 FLR_NotSleep_BYTE7BIT1 0;
BA_ "GenSigStartValue" SG_ 1442 FLR_NotSleep_BYTE7BIT1 0;
BA_ "GenSigInvalidValue" SG_ 1442 FLR_NotSleep_BYTE7BIT1 0;
BA_ "GenSigCycleTime" SG_ 1442 FLR_NotSleep_BYTE7BIT2 1000;
BA_ "GenSigSendType" SG_ 1442 FLR_NotSleep_BYTE7BIT2 0;
BA_ "GenSigStartValue" SG_ 1442 FLR_NotSleep_BYTE7BIT2 0;
BA_ "GenSigInvalidValue" SG_ 1442 FLR_NotSleep_BYTE7BIT2 0;
BA_ "GenSigCycleTime" SG_ 1442 FLR_NotSleep_BYTE7BIT3 1000;
BA_ "GenSigSendType" SG_ 1442 FLR_NotSleep_BYTE7BIT3 0;
BA_ "GenSigStartValue" SG_ 1442 FLR_NotSleep_BYTE7BIT3 0;
BA_ "GenSigInvalidValue" SG_ 1442 FLR_NotSleep_BYTE7BIT3 0;
BA_ "GenSigCycleTime" SG_ 1442 FLR_WakeUp_BYTE3BIT0 1000;
BA_ "GenSigSendType" SG_ 1442 FLR_WakeUp_BYTE3BIT0 0;
BA_ "GenSigStartValue" SG_ 1442 FLR_WakeUp_BYTE3BIT0 0;
BA_ "GenSigInvalidValue" SG_ 1442 FLR_WakeUp_BYTE3BIT0 0;
BA_ "GenSigCycleTime" SG_ 1442 FLR_WakeUp_BYTE3BIT1 1000;
BA_ "GenSigSendType" SG_ 1442 FLR_WakeUp_BYTE3BIT1 0;
BA_ "GenSigStartValue" SG_ 1442 FLR_WakeUp_BYTE3BIT1 0;
BA_ "GenSigInvalidValue" SG_ 1442 FLR_WakeUp_BYTE3BIT1 0;
BA_ "GenSigCycleTime" SG_ 1466 AMP_NotSleep_BYTE7BIT0 1000;
BA_ "GenSigSendType" SG_ 1466 AMP_NotSleep_BYTE7BIT0 0;
BA_ "GenSigStartValue" SG_ 1466 AMP_NotSleep_BYTE7BIT0 0;
BA_ "GenSigInvalidValue" SG_ 1466 AMP_NotSleep_BYTE7BIT0 0;
BA_ "GenSigCycleTime" SG_ 1466 AMP_NotSleep_BYTE7BIT1 1000;
BA_ "GenSigSendType" SG_ 1466 AMP_NotSleep_BYTE7BIT1 0;
BA_ "GenSigStartValue" SG_ 1466 AMP_NotSleep_BYTE7BIT1 0;
BA_ "GenSigInvalidValue" SG_ 1466 AMP_NotSleep_BYTE7BIT1 0;
BA_ "GenSigCycleTime" SG_ 1466 AMP_NotSleep_BYTE7BIT2 1000;
BA_ "GenSigSendType" SG_ 1466 AMP_NotSleep_BYTE7BIT2 0;
BA_ "GenSigStartValue" SG_ 1466 AMP_NotSleep_BYTE7BIT2 0;
BA_ "GenSigInvalidValue" SG_ 1466 AMP_NotSleep_BYTE7BIT2 0;
BA_ "GenSigCycleTime" SG_ 1466 AMP_WakeUp_BYTE3BIT0 1000;
BA_ "GenSigSendType" SG_ 1466 AMP_WakeUp_BYTE3BIT0 0;
BA_ "GenSigStartValue" SG_ 1466 AMP_WakeUp_BYTE3BIT0 0;
BA_ "GenSigInvalidValue" SG_ 1466 AMP_WakeUp_BYTE3BIT0 0;
BA_ "GenSigCycleTime" SG_ 1466 AMP_WakeUp_BYTE3BIT1 1000;
BA_ "GenSigSendType" SG_ 1466 AMP_WakeUp_BYTE3BIT1 0;
BA_ "GenSigStartValue" SG_ 1466 AMP_WakeUp_BYTE3BIT1 0;
BA_ "GenSigInvalidValue" SG_ 1466 AMP_WakeUp_BYTE3BIT1 0;
BA_ "GenSigCycleTime" SG_ 1471 mcuLogDataBytesSegment0 1000;
BA_ "GenSigSendType" SG_ 1471 mcuLogDataBytesSegment0 0;
BA_ "GenSigStartValue" SG_ 1471 mcuLogDataBytesSegment0 0;
BA_ "GenSigInvalidValue" SG_ 1471 mcuLogDataBytesSegment0 0;
BA_ "GenSigCycleTime" SG_ 1471 mcuLogDataBytesSegment1 1000;
BA_ "GenSigSendType" SG_ 1471 mcuLogDataBytesSegment1 0;
BA_ "GenSigStartValue" SG_ 1471 mcuLogDataBytesSegment1 0;
BA_ "GenSigInvalidValue" SG_ 1471 mcuLogDataBytesSegment1 0;
BA_ "GenSigCycleTime" SG_ 1471 mcuLogDataBytesSegment2 1000;
BA_ "GenSigSendType" SG_ 1471 mcuLogDataBytesSegment2 0;
BA_ "GenSigStartValue" SG_ 1471 mcuLogDataBytesSegment2 0;
BA_ "GenSigInvalidValue" SG_ 1471 mcuLogDataBytesSegment2 0;
BA_ "GenSigCycleTime" SG_ 1471 mcuLogDataBytesSegment3 1000;
BA_ "GenSigSendType" SG_ 1471 mcuLogDataBytesSegment3 0;
BA_ "GenSigStartValue" SG_ 1471 mcuLogDataBytesSegment3 0;
BA_ "GenSigInvalidValue" SG_ 1471 mcuLogDataBytesSegment3 0;
BA_ "GenSigCycleTime" SG_ 1471 mcuLogDataBytesSegment4 1000;
BA_ "GenSigSendType" SG_ 1471 mcuLogDataBytesSegment4 0;
BA_ "GenSigStartValue" SG_ 1471 mcuLogDataBytesSegment4 0;
BA_ "GenSigInvalidValue" SG_ 1471 mcuLogDataBytesSegment4 0;
BA_ "GenSigCycleTime" SG_ 1471 mcuLogDataBytesSegment5 1000;
BA_ "GenSigSendType" SG_ 1471 mcuLogDataBytesSegment5 0;
BA_ "GenSigStartValue" SG_ 1471 mcuLogDataBytesSegment5 0;
BA_ "GenSigInvalidValue" SG_ 1471 mcuLogDataBytesSegment5 0;
BA_ "GenSigCycleTime" SG_ 1471 mcuLogDataBytesSegment6 1000;
BA_ "GenSigSendType" SG_ 1471 mcuLogDataBytesSegment6 0;
BA_ "GenSigStartValue" SG_ 1471 mcuLogDataBytesSegment6 0;
BA_ "GenSigInvalidValue" SG_ 1471 mcuLogDataBytesSegment6 0;
BA_ "GenSigCycleTime" SG_ 1471 mcuLogDataBytesSegment7 1000;
BA_ "GenSigSendType" SG_ 1471 mcuLogDataBytesSegment7 0;
BA_ "GenSigStartValue" SG_ 1471 mcuLogDataBytesSegment7 0;
BA_ "GenSigInvalidValue" SG_ 1471 mcuLogDataBytesSegment7 0;
BA_ "GenSigCycleTime" SG_ 1494 IP_DTC1_HighByte 500;
BA_ "GenSigSendType" SG_ 1494 IP_DTC1_HighByte 0;
BA_ "GenSigStartValue" SG_ 1494 IP_DTC1_HighByte 0;
BA_ "GenSigInvalidValue" SG_ 1494 IP_DTC1_HighByte "/";
BA_ "GenSigCycleTime" SG_ 1494 IP_DTC1_LowByte 500;
BA_ "GenSigSendType" SG_ 1494 IP_DTC1_LowByte 0;
BA_ "GenSigStartValue" SG_ 1494 IP_DTC1_LowByte 0;
BA_ "GenSigInvalidValue" SG_ 1494 IP_DTC1_LowByte "/";
BA_ "GenSigCycleTime" SG_ 1494 IP_DTC1_MiddByte 500;
BA_ "GenSigSendType" SG_ 1494 IP_DTC1_MiddByte 0;
BA_ "GenSigStartValue" SG_ 1494 IP_DTC1_MiddByte 0;
BA_ "GenSigInvalidValue" SG_ 1494 IP_DTC1_MiddByte "/";
BA_ "GenSigCycleTime" SG_ 1494 IP_DTC1_Status 500;
BA_ "GenSigSendType" SG_ 1494 IP_DTC1_Status 0;
BA_ "GenSigStartValue" SG_ 1494 IP_DTC1_Status 0;
BA_ "GenSigInvalidValue" SG_ 1494 IP_DTC1_Status "/";
BA_ "GenSigCycleTime" SG_ 1494 IP_DTC2_HighByte 500;
BA_ "GenSigSendType" SG_ 1494 IP_DTC2_HighByte 0;
BA_ "GenSigStartValue" SG_ 1494 IP_DTC2_HighByte 0;
BA_ "GenSigInvalidValue" SG_ 1494 IP_DTC2_HighByte "/";
BA_ "GenSigCycleTime" SG_ 1494 IP_DTC2_LowByte 500;
BA_ "GenSigSendType" SG_ 1494 IP_DTC2_LowByte 0;
BA_ "GenSigStartValue" SG_ 1494 IP_DTC2_LowByte 0;
BA_ "GenSigInvalidValue" SG_ 1494 IP_DTC2_LowByte "/";
BA_ "GenSigCycleTime" SG_ 1494 IP_DTC2_MiddByte 500;
BA_ "GenSigSendType" SG_ 1494 IP_DTC2_MiddByte 0;
BA_ "GenSigStartValue" SG_ 1494 IP_DTC2_MiddByte 0;
BA_ "GenSigInvalidValue" SG_ 1494 IP_DTC2_MiddByte "/";
BA_ "GenSigCycleTime" SG_ 1494 IP_DTC2_Status 500;
BA_ "GenSigSendType" SG_ 1494 IP_DTC2_Status 0;
BA_ "GenSigStartValue" SG_ 1494 IP_DTC2_Status 0;
BA_ "GenSigInvalidValue" SG_ 1494 IP_DTC2_Status "/";
BA_ "GenSigCycleTime" SG_ 1502 ReMotAmnt_GB 1000;
BA_ "GenSigSendType" SG_ 1502 ReMotAmnt_GB 0;
BA_ "GenSigStartValue" SG_ 1502 ReMotAmnt_GB 1;
BA_ "GenSigInvalidValue" SG_ 1502 ReMotAmnt_GB 1;
BA_ "GenSigCycleTime" SG_ 1502 ReMotNr_GB 1000;
BA_ "GenSigSendType" SG_ 1502 ReMotNr_GB 0;
BA_ "GenSigStartValue" SG_ 1502 ReMotNr_GB 1;
BA_ "GenSigInvalidValue" SG_ 1502 ReMotNr_GB 1;
BA_ "GenSigCycleTime" SG_ 1502 ReMotSts_GB 1000;
BA_ "GenSigSendType" SG_ 1502 ReMotSts_GB 0;
BA_ "GenSigStartValue" SG_ 1502 ReMotSts_GB 3;
BA_ "GenSigInvalidValue" SG_ 1502 ReMotSts_GB 3;
BA_ "GenSigCycleTime" SG_ 1502 ReIpuT_GB 1000;
BA_ "GenSigSendType" SG_ 1502 ReIpuT_GB 0;
BA_ "GenSigStartValue" SG_ 1502 ReIpuT_GB 0;
BA_ "GenSigInvalidValue" SG_ 1502 ReIpuT_GB 0;
BA_ "GenSigCycleTime" SG_ 1502 ReMotTq_GB 1000;
BA_ "GenSigSendType" SG_ 1502 ReMotTq_GB 0;
BA_ "GenSigStartValue" SG_ 1502 ReMotTq_GB 200000;
BA_ "GenSigInvalidValue" SG_ 1502 ReMotTq_GB 200000;
BA_ "GenSigCycleTime" SG_ 1502 ReMotSpd_GB 1000;
BA_ "GenSigSendType" SG_ 1502 ReMotSpd_GB 0;
BA_ "GenSigStartValue" SG_ 1502 ReMotSpd_GB 32000;
BA_ "GenSigInvalidValue" SG_ 1502 ReMotSpd_GB 32000;
BA_ "GenSigCycleTime" SG_ 1502 ReMotTStatr_GB 1000;
BA_ "GenSigSendType" SG_ 1502 ReMotTStatr_GB 0;
BA_ "GenSigStartValue" SG_ 1502 ReMotTStatr_GB 0;
BA_ "GenSigInvalidValue" SG_ 1502 ReMotTStatr_GB 0;
BA_ "GenSigCycleTime" SG_ 1502 ReIpuErrAmnt_GB 1000;
BA_ "GenSigSendType" SG_ 1502 ReIpuErrAmnt_GB 0;
BA_ "GenSigStartValue" SG_ 1502 ReIpuErrAmnt_GB 0;
BA_ "GenSigInvalidValue" SG_ 1502 ReIpuErrAmnt_GB 0;
BA_ "GenSigCycleTime" SG_ 1502 ReIpuErrNr_GB 1000;
BA_ "GenSigSendType" SG_ 1502 ReIpuErrNr_GB 0;
BA_ "GenSigStartValue" SG_ 1502 ReIpuErrNr_GB 0;
BA_ "GenSigInvalidValue" SG_ 1502 ReIpuErrNr_GB 0;
BA_ "GenSigCycleTime" SG_ 1502 ReMotOverSpd_GB 1000;
BA_ "GenSigSendType" SG_ 1502 ReMotOverSpd_GB 0;
BA_ "GenSigStartValue" SG_ 1502 ReMotOverSpd_GB 0;
BA_ "GenSigInvalidValue" SG_ 1502 ReMotOverSpd_GB 0;
BA_ "GenSigCycleTime" SG_ 1502 ReMotOverI_GB 1000;
BA_ "GenSigSendType" SG_ 1502 ReMotOverI_GB 0;
BA_ "GenSigStartValue" SG_ 1502 ReMotOverI_GB 0;
BA_ "GenSigInvalidValue" SG_ 1502 ReMotOverI_GB 0;
BA_ "GenSigCycleTime" SG_ 1502 ReIpuTOver_GB 1000;
BA_ "GenSigSendType" SG_ 1502 ReIpuTOver_GB 0;
BA_ "GenSigStartValue" SG_ 1502 ReIpuTOver_GB 0;
BA_ "GenSigInvalidValue" SG_ 1502 ReIpuTOver_GB 0;
BA_ "GenSigCycleTime" SG_ 1502 ReMotTOver_GB 1000;
BA_ "GenSigSendType" SG_ 1502 ReMotTOver_GB 0;
BA_ "GenSigStartValue" SG_ 1502 ReMotTOver_GB 0;
BA_ "GenSigInvalidValue" SG_ 1502 ReMotTOver_GB 0;
BA_ "GenSigCycleTime" SG_ 1510 FrntMotAmntGb 1000;
BA_ "GenSigSendType" SG_ 1510 FrntMotAmntGb 0;
BA_ "GenSigStartValue" SG_ 1510 FrntMotAmntGb 1;
BA_ "GenSigInvalidValue" SG_ 1510 FrntMotAmntGb 1;
BA_ "GenSigCycleTime" SG_ 1510 FrntMotNrGb 1000;
BA_ "GenSigSendType" SG_ 1510 FrntMotNrGb 0;
BA_ "GenSigStartValue" SG_ 1510 FrntMotNrGb 1;
BA_ "GenSigInvalidValue" SG_ 1510 FrntMotNrGb 1;
BA_ "GenSigCycleTime" SG_ 1510 FrntMotStsGb 1000;
BA_ "GenSigSendType" SG_ 1510 FrntMotStsGb 0;
BA_ "GenSigStartValue" SG_ 1510 FrntMotStsGb 3;
BA_ "GenSigInvalidValue" SG_ 1510 FrntMotStsGb 3;
BA_ "GenSigCycleTime" SG_ 1510 FrntMotIvtINTCTGb 1000;
BA_ "GenSigSendType" SG_ 1510 FrntMotIvtINTCTGb 0;
BA_ "GenSigStartValue" SG_ 1510 FrntMotIvtINTCTGb 0;
BA_ "GenSigInvalidValue" SG_ 1510 FrntMotIvtINTCTGb 0;
BA_ "GenSigCycleTime" SG_ 1510 FrntMotTqGb 1000;
BA_ "GenSigSendType" SG_ 1510 FrntMotTqGb 0;
BA_ "GenSigStartValue" SG_ 1510 FrntMotTqGb 200000;
BA_ "GenSigInvalidValue" SG_ 1510 FrntMotTqGb 200000;
BA_ "GenSigCycleTime" SG_ 1510 FrntMotSpdGb 1000;
BA_ "GenSigSendType" SG_ 1510 FrntMotSpdGb 0;
BA_ "GenSigStartValue" SG_ 1510 FrntMotSpdGb 32000;
BA_ "GenSigInvalidValue" SG_ 1510 FrntMotSpdGb 32000;
BA_ "GenSigCycleTime" SG_ 1510 FrntMotTStatrGb 1000;
BA_ "GenSigSendType" SG_ 1510 FrntMotTStatrGb 0;
BA_ "GenSigStartValue" SG_ 1510 FrntMotTStatrGb 0;
BA_ "GenSigInvalidValue" SG_ 1510 FrntMotTStatrGb 0;
BA_ "GenSigCycleTime" SG_ 1510 FrntIpuErrAmntGb 1000;
BA_ "GenSigSendType" SG_ 1510 FrntIpuErrAmntGb 0;
BA_ "GenSigStartValue" SG_ 1510 FrntIpuErrAmntGb 0;
BA_ "GenSigInvalidValue" SG_ 1510 FrntIpuErrAmntGb 0;
BA_ "GenSigCycleTime" SG_ 1510 FrntIpuErrNrGb 1000;
BA_ "GenSigSendType" SG_ 1510 FrntIpuErrNrGb 0;
BA_ "GenSigStartValue" SG_ 1510 FrntIpuErrNrGb 0;
BA_ "GenSigInvalidValue" SG_ 1510 FrntIpuErrNrGb 0;
BA_ "GenSigCycleTime" SG_ 1510 FrntMotOverSpdGb 1000;
BA_ "GenSigSendType" SG_ 1510 FrntMotOverSpdGb 0;
BA_ "GenSigStartValue" SG_ 1510 FrntMotOverSpdGb 0;
BA_ "GenSigInvalidValue" SG_ 1510 FrntMotOverSpdGb 0;
BA_ "GenSigCycleTime" SG_ 1510 FrntMotOverIGb 1000;
BA_ "GenSigSendType" SG_ 1510 FrntMotOverIGb 0;
BA_ "GenSigStartValue" SG_ 1510 FrntMotOverIGb 0;
BA_ "GenSigInvalidValue" SG_ 1510 FrntMotOverIGb 0;
BA_ "GenSigCycleTime" SG_ 1510 FrntIpuTOverGb 1000;
BA_ "GenSigSendType" SG_ 1510 FrntIpuTOverGb 0;
BA_ "GenSigStartValue" SG_ 1510 FrntIpuTOverGb 0;
BA_ "GenSigInvalidValue" SG_ 1510 FrntIpuTOverGb 0;
BA_ "GenSigCycleTime" SG_ 1510 FrntMotTOverGb 1000;
BA_ "GenSigSendType" SG_ 1510 FrntMotTOverGb 0;
BA_ "GenSigStartValue" SG_ 1510 FrntMotTOverGb 0;
BA_ "GenSigInvalidValue" SG_ 1510 FrntMotTOverGb 0;
BA_ "GenSigCycleTime" SG_ 1540 EDC_EthMng_Vers 0;
BA_ "GenSigSendType" SG_ 1540 EDC_EthMng_Vers 3;
BA_ "GenSigStartValue" SG_ 1540 EDC_EthMng_Vers 0;
BA_ "GenSigInvalidValue" SG_ 1540 EDC_EthMng_Vers 0;
BA_ "GenSigCycleTime" SG_ 1540 EDC_EthMng_MngTyp 0;
BA_ "GenSigSendType" SG_ 1540 EDC_EthMng_MngTyp 3;
BA_ "GenSigStartValue" SG_ 1540 EDC_EthMng_MngTyp 0;
BA_ "GenSigInvalidValue" SG_ 1540 EDC_EthMng_MngTyp 0;
BA_ "GenSigCycleTime" SG_ 1540 EDC_EthMng_Msg 0;
BA_ "GenSigSendType" SG_ 1540 EDC_EthMng_Msg 3;
BA_ "GenSigStartValue" SG_ 1540 EDC_EthMng_Msg 0;
BA_ "GenSigInvalidValue" SG_ 1540 EDC_EthMng_Msg 0;
BA_ "GenSigCycleTime" SG_ 1540 EDC_EthMng_OptnCod 0;
BA_ "GenSigSendType" SG_ 1540 EDC_EthMng_OptnCod 3;
BA_ "GenSigStartValue" SG_ 1540 EDC_EthMng_OptnCod 0;
BA_ "GenSigInvalidValue" SG_ 1540 EDC_EthMng_OptnCod 0;
BA_ "GenSigCycleTime" SG_ 1540 EDC_EthMng_Optn 0;
BA_ "GenSigSendType" SG_ 1540 EDC_EthMng_Optn 3;
BA_ "GenSigStartValue" SG_ 1540 EDC_EthMng_Optn 0;
BA_ "GenSigInvalidValue" SG_ 1540 EDC_EthMng_Optn 0;
BA_ "GenSigCycleTime" SG_ 1540 EDC_EthMng_DataTyp 0;
BA_ "GenSigSendType" SG_ 1540 EDC_EthMng_DataTyp 3;
BA_ "GenSigStartValue" SG_ 1540 EDC_EthMng_DataTyp 0;
BA_ "GenSigInvalidValue" SG_ 1540 EDC_EthMng_DataTyp 0;
BA_ "GenSigCycleTime" SG_ 1540 EDC_EthMng_DataLen 0;
BA_ "GenSigSendType" SG_ 1540 EDC_EthMng_DataLen 3;
BA_ "GenSigStartValue" SG_ 1540 EDC_EthMng_DataLen 0;
BA_ "GenSigInvalidValue" SG_ 1540 EDC_EthMng_DataLen 0;
BA_ "GenSigCycleTime" SG_ 1540 EDC_EthMng_Payload 0;
BA_ "GenSigSendType" SG_ 1540 EDC_EthMng_Payload 3;
BA_ "GenSigStartValue" SG_ 1540 EDC_EthMng_Payload 0;
BA_ "GenSigInvalidValue" SG_ 1540 EDC_EthMng_Payload 0;
BA_ "GenSigCycleTime" SG_ 1541 VIUFL_EthMng_Vers 0;
BA_ "GenSigSendType" SG_ 1541 VIUFL_EthMng_Vers 3;
BA_ "GenSigStartValue" SG_ 1541 VIUFL_EthMng_Vers 0;
BA_ "GenSigInvalidValue" SG_ 1541 VIUFL_EthMng_Vers 0;
BA_ "GenSigCycleTime" SG_ 1541 VIUFL_EthMng_MngTyp 0;
BA_ "GenSigSendType" SG_ 1541 VIUFL_EthMng_MngTyp 3;
BA_ "GenSigStartValue" SG_ 1541 VIUFL_EthMng_MngTyp 0;
BA_ "GenSigInvalidValue" SG_ 1541 VIUFL_EthMng_MngTyp 0;
BA_ "GenSigCycleTime" SG_ 1541 VIUFL_EthMng_Msg 0;
BA_ "GenSigSendType" SG_ 1541 VIUFL_EthMng_Msg 3;
BA_ "GenSigStartValue" SG_ 1541 VIUFL_EthMng_Msg 0;
BA_ "GenSigInvalidValue" SG_ 1541 VIUFL_EthMng_Msg 0;
BA_ "GenSigCycleTime" SG_ 1541 VIUFL_EthMng_OptnCod 0;
BA_ "GenSigSendType" SG_ 1541 VIUFL_EthMng_OptnCod 3;
BA_ "GenSigStartValue" SG_ 1541 VIUFL_EthMng_OptnCod 0;
BA_ "GenSigInvalidValue" SG_ 1541 VIUFL_EthMng_OptnCod 0;
BA_ "GenSigCycleTime" SG_ 1541 VIUFL_EthMng_Optn 0;
BA_ "GenSigSendType" SG_ 1541 VIUFL_EthMng_Optn 3;
BA_ "GenSigStartValue" SG_ 1541 VIUFL_EthMng_Optn 0;
BA_ "GenSigInvalidValue" SG_ 1541 VIUFL_EthMng_Optn 0;
BA_ "GenSigCycleTime" SG_ 1541 VIUFL_EthMng_DataTyp 0;
BA_ "GenSigSendType" SG_ 1541 VIUFL_EthMng_DataTyp 3;
BA_ "GenSigStartValue" SG_ 1541 VIUFL_EthMng_DataTyp 0;
BA_ "GenSigInvalidValue" SG_ 1541 VIUFL_EthMng_DataTyp 0;
BA_ "GenSigCycleTime" SG_ 1541 VIUFL_EthMng_DataLen 0;
BA_ "GenSigSendType" SG_ 1541 VIUFL_EthMng_DataLen 3;
BA_ "GenSigStartValue" SG_ 1541 VIUFL_EthMng_DataLen 0;
BA_ "GenSigInvalidValue" SG_ 1541 VIUFL_EthMng_DataLen 0;
BA_ "GenSigCycleTime" SG_ 1543 VIU_FrTakOveSts 0;
BA_ "GenSigSendType" SG_ 1543 VIU_FrTakOveSts 3;
BA_ "GenSigStartValue" SG_ 1543 VIU_FrTakOveSts 0;
BA_ "GenSigInvalidValue" SG_ 1543 VIU_FrTakOveSts 0;
BA_ "GenSigCycleTime" SG_ 1546 VIUFR_EthMng_Vers 0;
BA_ "GenSigSendType" SG_ 1546 VIUFR_EthMng_Vers 3;
BA_ "GenSigStartValue" SG_ 1546 VIUFR_EthMng_Vers 0;
BA_ "GenSigInvalidValue" SG_ 1546 VIUFR_EthMng_Vers 0;
BA_ "GenSigCycleTime" SG_ 1546 VIUFR_EthMng_MngTyp 0;
BA_ "GenSigSendType" SG_ 1546 VIUFR_EthMng_MngTyp 3;
BA_ "GenSigStartValue" SG_ 1546 VIUFR_EthMng_MngTyp 0;
BA_ "GenSigInvalidValue" SG_ 1546 VIUFR_EthMng_MngTyp 0;
BA_ "GenSigCycleTime" SG_ 1546 VIUFR_EthMng_Msg 0;
BA_ "GenSigSendType" SG_ 1546 VIUFR_EthMng_Msg 3;
BA_ "GenSigStartValue" SG_ 1546 VIUFR_EthMng_Msg 0;
BA_ "GenSigInvalidValue" SG_ 1546 VIUFR_EthMng_Msg 0;
BA_ "GenSigCycleTime" SG_ 1546 VIUFR_EthMng_OptnCod 0;
BA_ "GenSigSendType" SG_ 1546 VIUFR_EthMng_OptnCod 3;
BA_ "GenSigStartValue" SG_ 1546 VIUFR_EthMng_OptnCod 0;
BA_ "GenSigInvalidValue" SG_ 1546 VIUFR_EthMng_OptnCod 0;
BA_ "GenSigCycleTime" SG_ 1546 VIUFR_EthMng_Optn 0;
BA_ "GenSigSendType" SG_ 1546 VIUFR_EthMng_Optn 3;
BA_ "GenSigStartValue" SG_ 1546 VIUFR_EthMng_Optn 0;
BA_ "GenSigInvalidValue" SG_ 1546 VIUFR_EthMng_Optn 0;
BA_ "GenSigCycleTime" SG_ 1546 VIUFR_EthMng_DataTyp 0;
BA_ "GenSigSendType" SG_ 1546 VIUFR_EthMng_DataTyp 3;
BA_ "GenSigStartValue" SG_ 1546 VIUFR_EthMng_DataTyp 0;
BA_ "GenSigInvalidValue" SG_ 1546 VIUFR_EthMng_DataTyp 0;
BA_ "GenSigCycleTime" SG_ 1546 VIUFR_EthMng_DataLen 0;
BA_ "GenSigSendType" SG_ 1546 VIUFR_EthMng_DataLen 3;
BA_ "GenSigStartValue" SG_ 1546 VIUFR_EthMng_DataLen 0;
BA_ "GenSigInvalidValue" SG_ 1546 VIUFR_EthMng_DataLen 0;
BA_ "GenSigCycleTime" SG_ 1547 C2_EthMng_Vers 0;
BA_ "GenSigSendType" SG_ 1547 C2_EthMng_Vers 3;
BA_ "GenSigStartValue" SG_ 1547 C2_EthMng_Vers 0;
BA_ "GenSigInvalidValue" SG_ 1547 C2_EthMng_Vers 0;
BA_ "GenSigCycleTime" SG_ 1547 C2_EthMng_MngTyp 0;
BA_ "GenSigSendType" SG_ 1547 C2_EthMng_MngTyp 3;
BA_ "GenSigStartValue" SG_ 1547 C2_EthMng_MngTyp 0;
BA_ "GenSigInvalidValue" SG_ 1547 C2_EthMng_MngTyp 0;
BA_ "GenSigCycleTime" SG_ 1547 C2_EthMng_Msg 0;
BA_ "GenSigSendType" SG_ 1547 C2_EthMng_Msg 3;
BA_ "GenSigStartValue" SG_ 1547 C2_EthMng_Msg 0;
BA_ "GenSigInvalidValue" SG_ 1547 C2_EthMng_Msg 0;
BA_ "GenSigCycleTime" SG_ 1547 C2_EthMng_OptnCod 0;
BA_ "GenSigSendType" SG_ 1547 C2_EthMng_OptnCod 3;
BA_ "GenSigStartValue" SG_ 1547 C2_EthMng_OptnCod 0;
BA_ "GenSigInvalidValue" SG_ 1547 C2_EthMng_OptnCod 0;
BA_ "GenSigCycleTime" SG_ 1547 C2_EthMng_Optn 0;
BA_ "GenSigSendType" SG_ 1547 C2_EthMng_Optn 3;
BA_ "GenSigStartValue" SG_ 1547 C2_EthMng_Optn 0;
BA_ "GenSigInvalidValue" SG_ 1547 C2_EthMng_Optn 0;
BA_ "GenSigCycleTime" SG_ 1547 C2_EthMng_DataTyp 0;
BA_ "GenSigSendType" SG_ 1547 C2_EthMng_DataTyp 3;
BA_ "GenSigStartValue" SG_ 1547 C2_EthMng_DataTyp 0;
BA_ "GenSigInvalidValue" SG_ 1547 C2_EthMng_DataTyp 0;
BA_ "GenSigCycleTime" SG_ 1547 C2_EthMng_DataLen 0;
BA_ "GenSigSendType" SG_ 1547 C2_EthMng_DataLen 3;
BA_ "GenSigStartValue" SG_ 1547 C2_EthMng_DataLen 0;
BA_ "GenSigInvalidValue" SG_ 1547 C2_EthMng_DataLen 0;
BA_ "GenSigCycleTime" SG_ 1548 EDC_ErpsRev_Pst 0;
BA_ "GenSigSendType" SG_ 1548 EDC_ErpsRev_Pst 3;
BA_ "GenSigStartValue" SG_ 1548 EDC_ErpsRev_Pst 0;
BA_ "GenSigInvalidValue" SG_ 1548 EDC_ErpsRev_Pst "/";
BA_ "GenSigCycleTime" SG_ 1551 VIUFR_ErpsRev_Pst 0;
BA_ "GenSigSendType" SG_ 1551 VIUFR_ErpsRev_Pst 3;
BA_ "GenSigStartValue" SG_ 1551 VIUFR_ErpsRev_Pst 0;
BA_ "GenSigInvalidValue" SG_ 1551 VIUFR_ErpsRev_Pst "/";
BA_ "GenSigCycleTime" SG_ 1579 C2_EthMng_Vers 0;
BA_ "GenSigSendType" SG_ 1579 C2_EthMng_Vers 3;
BA_ "GenSigStartValue" SG_ 1579 C2_EthMng_Vers 0;
BA_ "GenSigInvalidValue" SG_ 1579 C2_EthMng_Vers "/";
BA_ "GenSigCycleTime" SG_ 1579 C2_EthMng_MngTyp 0;
BA_ "GenSigSendType" SG_ 1579 C2_EthMng_MngTyp 3;
BA_ "GenSigStartValue" SG_ 1579 C2_EthMng_MngTyp 0;
BA_ "GenSigInvalidValue" SG_ 1579 C2_EthMng_MngTyp "/";
BA_ "GenSigCycleTime" SG_ 1579 C2_EthMng_Msg 0;
BA_ "GenSigSendType" SG_ 1579 C2_EthMng_Msg 3;
BA_ "GenSigStartValue" SG_ 1579 C2_EthMng_Msg 0;
BA_ "GenSigInvalidValue" SG_ 1579 C2_EthMng_Msg "/";
BA_ "GenSigCycleTime" SG_ 1579 C2_EthMng_OptnCod 0;
BA_ "GenSigSendType" SG_ 1579 C2_EthMng_OptnCod 3;
BA_ "GenSigStartValue" SG_ 1579 C2_EthMng_OptnCod 0;
BA_ "GenSigInvalidValue" SG_ 1579 C2_EthMng_OptnCod "/";
BA_ "GenSigCycleTime" SG_ 1579 C2_EthMng_Optn 0;
BA_ "GenSigSendType" SG_ 1579 C2_EthMng_Optn 3;
BA_ "GenSigStartValue" SG_ 1579 C2_EthMng_Optn 0;
BA_ "GenSigInvalidValue" SG_ 1579 C2_EthMng_Optn "/";
BA_ "GenSigCycleTime" SG_ 1579 C2_EthMng_DataTyp 0;
BA_ "GenSigSendType" SG_ 1579 C2_EthMng_DataTyp 3;
BA_ "GenSigStartValue" SG_ 1579 C2_EthMng_DataTyp 0;
BA_ "GenSigInvalidValue" SG_ 1579 C2_EthMng_DataTyp "/";
BA_ "GenSigCycleTime" SG_ 1579 C2_EthMng_DataLen 0;
BA_ "GenSigSendType" SG_ 1579 C2_EthMng_DataLen 3;
BA_ "GenSigStartValue" SG_ 1579 C2_EthMng_DataLen 0;
BA_ "GenSigInvalidValue" SG_ 1579 C2_EthMng_DataLen "/";
BA_ "GenSigCycleTime" SG_ 1589 EvccDtc2Sts 500;
BA_ "GenSigSendType" SG_ 1589 EvccDtc2Sts 0;
BA_ "GenSigStartValue" SG_ 1589 EvccDtc2Sts 0;
BA_ "GenSigInvalidValue" SG_ 1589 EvccDtc2Sts 0;
BA_ "GenSigCycleTime" SG_ 1589 EvccDtc2MidByte 500;
BA_ "GenSigSendType" SG_ 1589 EvccDtc2MidByte 0;
BA_ "GenSigStartValue" SG_ 1589 EvccDtc2MidByte 0;
BA_ "GenSigInvalidValue" SG_ 1589 EvccDtc2MidByte 0;
BA_ "GenSigCycleTime" SG_ 1589 EvccDtc2HiByte 500;
BA_ "GenSigSendType" SG_ 1589 EvccDtc2HiByte 0;
BA_ "GenSigStartValue" SG_ 1589 EvccDtc2HiByte 0;
BA_ "GenSigInvalidValue" SG_ 1589 EvccDtc2HiByte 0;
BA_ "GenSigCycleTime" SG_ 1589 EvccDtc2LoByte 500;
BA_ "GenSigSendType" SG_ 1589 EvccDtc2LoByte 0;
BA_ "GenSigStartValue" SG_ 1589 EvccDtc2LoByte 0;
BA_ "GenSigInvalidValue" SG_ 1589 EvccDtc2LoByte 0;
BA_ "GenSigCycleTime" SG_ 1589 EvccDtc1Sts 500;
BA_ "GenSigSendType" SG_ 1589 EvccDtc1Sts 0;
BA_ "GenSigStartValue" SG_ 1589 EvccDtc1Sts 0;
BA_ "GenSigInvalidValue" SG_ 1589 EvccDtc1Sts 0;
BA_ "GenSigCycleTime" SG_ 1589 EvccDtc1MidByte 500;
BA_ "GenSigSendType" SG_ 1589 EvccDtc1MidByte 0;
BA_ "GenSigStartValue" SG_ 1589 EvccDtc1MidByte 0;
BA_ "GenSigInvalidValue" SG_ 1589 EvccDtc1MidByte 0;
BA_ "GenSigCycleTime" SG_ 1589 EvccDtc1HiByte 500;
BA_ "GenSigSendType" SG_ 1589 EvccDtc1HiByte 0;
BA_ "GenSigStartValue" SG_ 1589 EvccDtc1HiByte 0;
BA_ "GenSigInvalidValue" SG_ 1589 EvccDtc1HiByte 0;
BA_ "GenSigCycleTime" SG_ 1589 EvccDtc1LoByte 500;
BA_ "GenSigSendType" SG_ 1589 EvccDtc1LoByte 0;
BA_ "GenSigStartValue" SG_ 1589 EvccDtc1LoByte 0;
BA_ "GenSigInvalidValue" SG_ 1589 EvccDtc1LoByte 0;
BA_ "GenSigCycleTime" SG_ 1705 calibration_message6A9 0;
BA_ "GenSigSendType" SG_ 1705 calibration_message6A9 3;
BA_ "GenSigStartValue" SG_ 1705 calibration_message6A9 0;
BA_ "GenSigInvalidValue" SG_ 1705 calibration_message6A9 0;
BA_ "GenSigCycleTime" SG_ 1707 Diagnose_message_6AB 0;
BA_ "GenSigSendType" SG_ 1707 Diagnose_message_6AB 3;
BA_ "GenSigStartValue" SG_ 1707 Diagnose_message_6AB 0;
BA_ "GenSigInvalidValue" SG_ 1707 Diagnose_message_6AB 0;
BA_ "GenSigCycleTime" SG_ 1750 calibration_message6D6 0;
BA_ "GenSigSendType" SG_ 1750 calibration_message6D6 3;
BA_ "GenSigStartValue" SG_ 1750 calibration_message6D6 0;
BA_ "GenSigInvalidValue" SG_ 1750 calibration_message6D6 0;
BA_ "GenSigCycleTime" SG_ 1751 calibration_message6D7 0;
BA_ "GenSigSendType" SG_ 1751 calibration_message6D7 3;
BA_ "GenSigStartValue" SG_ 1751 calibration_message6D7 0;
BA_ "GenSigInvalidValue" SG_ 1751 calibration_message6D7 0;
BA_ "GenSigCycleTime" SG_ 1761 EDC_DTC1_HighByte 500;
BA_ "GenSigSendType" SG_ 1761 EDC_DTC1_HighByte 0;
BA_ "GenSigStartValue" SG_ 1761 EDC_DTC1_HighByte 0;
BA_ "GenSigInvalidValue" SG_ 1761 EDC_DTC1_HighByte "/";
BA_ "GenSigCycleTime" SG_ 1761 EDC_DTC1_LowByte 500;
BA_ "GenSigSendType" SG_ 1761 EDC_DTC1_LowByte 0;
BA_ "GenSigStartValue" SG_ 1761 EDC_DTC1_LowByte 0;
BA_ "GenSigInvalidValue" SG_ 1761 EDC_DTC1_LowByte "/";
BA_ "GenSigCycleTime" SG_ 1761 EDC_DTC1_MiddByte 500;
BA_ "GenSigSendType" SG_ 1761 EDC_DTC1_MiddByte 0;
BA_ "GenSigStartValue" SG_ 1761 EDC_DTC1_MiddByte 0;
BA_ "GenSigInvalidValue" SG_ 1761 EDC_DTC1_MiddByte "/";
BA_ "GenSigCycleTime" SG_ 1761 EDC_DTC1_Status 500;
BA_ "GenSigSendType" SG_ 1761 EDC_DTC1_Status 0;
BA_ "GenSigStartValue" SG_ 1761 EDC_DTC1_Status 0;
BA_ "GenSigInvalidValue" SG_ 1761 EDC_DTC1_Status "/";
BA_ "GenSigCycleTime" SG_ 1761 EDC_DTC2_HighByte 500;
BA_ "GenSigSendType" SG_ 1761 EDC_DTC2_HighByte 0;
BA_ "GenSigStartValue" SG_ 1761 EDC_DTC2_HighByte 0;
BA_ "GenSigInvalidValue" SG_ 1761 EDC_DTC2_HighByte "/";
BA_ "GenSigCycleTime" SG_ 1761 EDC_DTC2_LowByte 500;
BA_ "GenSigSendType" SG_ 1761 EDC_DTC2_LowByte 0;
BA_ "GenSigStartValue" SG_ 1761 EDC_DTC2_LowByte 0;
BA_ "GenSigInvalidValue" SG_ 1761 EDC_DTC2_LowByte "/";
BA_ "GenSigCycleTime" SG_ 1761 EDC_DTC2_MiddByte 500;
BA_ "GenSigSendType" SG_ 1761 EDC_DTC2_MiddByte 0;
BA_ "GenSigStartValue" SG_ 1761 EDC_DTC2_MiddByte 0;
BA_ "GenSigInvalidValue" SG_ 1761 EDC_DTC2_MiddByte "/";
BA_ "GenSigCycleTime" SG_ 1761 EDC_DTC2_Status 500;
BA_ "GenSigSendType" SG_ 1761 EDC_DTC2_Status 0;
BA_ "GenSigStartValue" SG_ 1761 EDC_DTC2_Status 0;
BA_ "GenSigInvalidValue" SG_ 1761 EDC_DTC2_Status "/";
BA_ "GenSigCycleTime" SG_ 1762 TBOX_DTC1_HighByte 500;
BA_ "GenSigSendType" SG_ 1762 TBOX_DTC1_HighByte 0;
BA_ "GenSigStartValue" SG_ 1762 TBOX_DTC1_HighByte 0;
BA_ "GenSigInvalidValue" SG_ 1762 TBOX_DTC1_HighByte "/";
BA_ "GenSigCycleTime" SG_ 1762 TBOX_DTC1_LowByte 500;
BA_ "GenSigSendType" SG_ 1762 TBOX_DTC1_LowByte 0;
BA_ "GenSigStartValue" SG_ 1762 TBOX_DTC1_LowByte 0;
BA_ "GenSigInvalidValue" SG_ 1762 TBOX_DTC1_LowByte "/";
BA_ "GenSigCycleTime" SG_ 1762 TBOX_DTC1_MiddByte 500;
BA_ "GenSigSendType" SG_ 1762 TBOX_DTC1_MiddByte 0;
BA_ "GenSigStartValue" SG_ 1762 TBOX_DTC1_MiddByte 0;
BA_ "GenSigInvalidValue" SG_ 1762 TBOX_DTC1_MiddByte "/";
BA_ "GenSigCycleTime" SG_ 1762 TBOX_DTC1_Status 500;
BA_ "GenSigSendType" SG_ 1762 TBOX_DTC1_Status 0;
BA_ "GenSigStartValue" SG_ 1762 TBOX_DTC1_Status 0;
BA_ "GenSigInvalidValue" SG_ 1762 TBOX_DTC1_Status "/";
BA_ "GenSigCycleTime" SG_ 1762 TBOX_DTC2_HighByte 500;
BA_ "GenSigSendType" SG_ 1762 TBOX_DTC2_HighByte 0;
BA_ "GenSigStartValue" SG_ 1762 TBOX_DTC2_HighByte 0;
BA_ "GenSigInvalidValue" SG_ 1762 TBOX_DTC2_HighByte "/";
BA_ "GenSigCycleTime" SG_ 1762 TBOX_DTC2_LowByte 500;
BA_ "GenSigSendType" SG_ 1762 TBOX_DTC2_LowByte 0;
BA_ "GenSigStartValue" SG_ 1762 TBOX_DTC2_LowByte 0;
BA_ "GenSigInvalidValue" SG_ 1762 TBOX_DTC2_LowByte "/";
BA_ "GenSigCycleTime" SG_ 1762 TBOX_DTC2_MiddByte 500;
BA_ "GenSigSendType" SG_ 1762 TBOX_DTC2_MiddByte 0;
BA_ "GenSigStartValue" SG_ 1762 TBOX_DTC2_MiddByte 0;
BA_ "GenSigInvalidValue" SG_ 1762 TBOX_DTC2_MiddByte "/";
BA_ "GenSigCycleTime" SG_ 1762 TBOX_DTC2_Status 500;
BA_ "GenSigSendType" SG_ 1762 TBOX_DTC2_Status 0;
BA_ "GenSigStartValue" SG_ 1762 TBOX_DTC2_Status 0;
BA_ "GenSigInvalidValue" SG_ 1762 TBOX_DTC2_Status "/";
BA_ "GenSigCycleTime" SG_ 1763 EDCEqCertifReqFrmType 0;
BA_ "GenSigSendType" SG_ 1763 EDCEqCertifReqFrmType 3;
BA_ "GenSigStartValue" SG_ 1763 EDCEqCertifReqFrmType 0;
BA_ "GenSigInvalidValue" SG_ 1763 EDCEqCertifReqFrmType "NA";
BA_ "GenSigCycleTime" SG_ 1763 EDCEqCertifReqCmac 0;
BA_ "GenSigSendType" SG_ 1763 EDCEqCertifReqCmac 3;
BA_ "GenSigStartValue" SG_ 1763 EDCEqCertifReqCmac 0;
BA_ "GenSigInvalidValue" SG_ 1763 EDCEqCertifReqCmac "NA";
BA_ "GenSigCycleTime" SG_ 1764 VIU_FL_DTC1_HighByte 500;
BA_ "GenSigSendType" SG_ 1764 VIU_FL_DTC1_HighByte 0;
BA_ "GenSigStartValue" SG_ 1764 VIU_FL_DTC1_HighByte 0;
BA_ "GenSigInvalidValue" SG_ 1764 VIU_FL_DTC1_HighByte "/";
BA_ "GenSigCycleTime" SG_ 1764 VIU_FL_DTC1_LowByte 500;
BA_ "GenSigSendType" SG_ 1764 VIU_FL_DTC1_LowByte 0;
BA_ "GenSigStartValue" SG_ 1764 VIU_FL_DTC1_LowByte 0;
BA_ "GenSigInvalidValue" SG_ 1764 VIU_FL_DTC1_LowByte "/";
BA_ "GenSigCycleTime" SG_ 1764 VIU_FL_DTC1_MiddByte 500;
BA_ "GenSigSendType" SG_ 1764 VIU_FL_DTC1_MiddByte 0;
BA_ "GenSigStartValue" SG_ 1764 VIU_FL_DTC1_MiddByte 0;
BA_ "GenSigInvalidValue" SG_ 1764 VIU_FL_DTC1_MiddByte "/";
BA_ "GenSigCycleTime" SG_ 1764 VIU_FL_DTC1_Status 500;
BA_ "GenSigSendType" SG_ 1764 VIU_FL_DTC1_Status 0;
BA_ "GenSigStartValue" SG_ 1764 VIU_FL_DTC1_Status 0;
BA_ "GenSigInvalidValue" SG_ 1764 VIU_FL_DTC1_Status "/";
BA_ "GenSigCycleTime" SG_ 1764 VIU_FL_DTC2_HighByte 500;
BA_ "GenSigSendType" SG_ 1764 VIU_FL_DTC2_HighByte 0;
BA_ "GenSigStartValue" SG_ 1764 VIU_FL_DTC2_HighByte 0;
BA_ "GenSigInvalidValue" SG_ 1764 VIU_FL_DTC2_HighByte "/";
BA_ "GenSigCycleTime" SG_ 1764 VIU_FL_DTC2_LowByte 500;
BA_ "GenSigSendType" SG_ 1764 VIU_FL_DTC2_LowByte 0;
BA_ "GenSigStartValue" SG_ 1764 VIU_FL_DTC2_LowByte 0;
BA_ "GenSigInvalidValue" SG_ 1764 VIU_FL_DTC2_LowByte "/";
BA_ "GenSigCycleTime" SG_ 1764 VIU_FL_DTC2_MiddByte 500;
BA_ "GenSigSendType" SG_ 1764 VIU_FL_DTC2_MiddByte 0;
BA_ "GenSigStartValue" SG_ 1764 VIU_FL_DTC2_MiddByte 0;
BA_ "GenSigInvalidValue" SG_ 1764 VIU_FL_DTC2_MiddByte "/";
BA_ "GenSigCycleTime" SG_ 1764 VIU_FL_DTC2_Status 500;
BA_ "GenSigSendType" SG_ 1764 VIU_FL_DTC2_Status 0;
BA_ "GenSigStartValue" SG_ 1764 VIU_FL_DTC2_Status 0;
BA_ "GenSigInvalidValue" SG_ 1764 VIU_FL_DTC2_Status "/";
BA_ "GenSigCycleTime" SG_ 1767 VIUEqCertifRespFrmType 0;
BA_ "GenSigSendType" SG_ 1767 VIUEqCertifRespFrmType 3;
BA_ "GenSigStartValue" SG_ 1767 VIUEqCertifRespFrmType 0;
BA_ "GenSigInvalidValue" SG_ 1767 VIUEqCertifRespFrmType "NA";
BA_ "GenSigCycleTime" SG_ 1767 VIUEqCertifRespRand 0;
BA_ "GenSigSendType" SG_ 1767 VIUEqCertifRespRand 3;
BA_ "GenSigStartValue" SG_ 1767 VIUEqCertifRespRand 0;
BA_ "GenSigInvalidValue" SG_ 1767 VIUEqCertifRespRand "NA";
BA_ "GenSigCycleTime" SG_ 1767 VIUEqCertifRespRes 0;
BA_ "GenSigSendType" SG_ 1767 VIUEqCertifRespRes 3;
BA_ "GenSigStartValue" SG_ 1767 VIUEqCertifRespRes 0;
BA_ "GenSigInvalidValue" SG_ 1767 VIUEqCertifRespRes "NA";
BA_ "GenSigCycleTime" SG_ 1782 AMP_DTC1_HighByte 500;
BA_ "GenSigSendType" SG_ 1782 AMP_DTC1_HighByte 0;
BA_ "GenSigStartValue" SG_ 1782 AMP_DTC1_HighByte 0;
BA_ "GenSigInvalidValue" SG_ 1782 AMP_DTC1_HighByte "/";
BA_ "GenSigCycleTime" SG_ 1782 AMP_DTC1_LowByte 500;
BA_ "GenSigSendType" SG_ 1782 AMP_DTC1_LowByte 0;
BA_ "GenSigStartValue" SG_ 1782 AMP_DTC1_LowByte 0;
BA_ "GenSigInvalidValue" SG_ 1782 AMP_DTC1_LowByte "/";
BA_ "GenSigCycleTime" SG_ 1782 AMP_DTC1_MiddByte 500;
BA_ "GenSigSendType" SG_ 1782 AMP_DTC1_MiddByte 0;
BA_ "GenSigStartValue" SG_ 1782 AMP_DTC1_MiddByte 0;
BA_ "GenSigInvalidValue" SG_ 1782 AMP_DTC1_MiddByte "/";
BA_ "GenSigCycleTime" SG_ 1782 AMP_DTC1_Status 500;
BA_ "GenSigSendType" SG_ 1782 AMP_DTC1_Status 0;
BA_ "GenSigStartValue" SG_ 1782 AMP_DTC1_Status 0;
BA_ "GenSigInvalidValue" SG_ 1782 AMP_DTC1_Status "/";
BA_ "GenSigCycleTime" SG_ 1782 AMP_DTC2_HighByte 500;
BA_ "GenSigSendType" SG_ 1782 AMP_DTC2_HighByte 0;
BA_ "GenSigStartValue" SG_ 1782 AMP_DTC2_HighByte 0;
BA_ "GenSigInvalidValue" SG_ 1782 AMP_DTC2_HighByte "/";
BA_ "GenSigCycleTime" SG_ 1782 AMP_DTC2_LowByte 500;
BA_ "GenSigSendType" SG_ 1782 AMP_DTC2_LowByte 0;
BA_ "GenSigStartValue" SG_ 1782 AMP_DTC2_LowByte 0;
BA_ "GenSigInvalidValue" SG_ 1782 AMP_DTC2_LowByte "/";
BA_ "GenSigCycleTime" SG_ 1782 AMP_DTC2_MiddByte 500;
BA_ "GenSigSendType" SG_ 1782 AMP_DTC2_MiddByte 0;
BA_ "GenSigStartValue" SG_ 1782 AMP_DTC2_MiddByte 0;
BA_ "GenSigInvalidValue" SG_ 1782 AMP_DTC2_MiddByte "/";
BA_ "GenSigCycleTime" SG_ 1782 AMP_DTC2_Status 500;
BA_ "GenSigSendType" SG_ 1782 AMP_DTC2_Status 0;
BA_ "GenSigStartValue" SG_ 1782 AMP_DTC2_Status 0;
BA_ "GenSigInvalidValue" SG_ 1782 AMP_DTC2_Status "/";
BA_ "GenSigCycleTime" SG_ 1786 calibration_message6FA 0;
BA_ "GenSigSendType" SG_ 1786 calibration_message6FA 3;
BA_ "GenSigStartValue" SG_ 1786 calibration_message6FA 0;
BA_ "GenSigInvalidValue" SG_ 1786 calibration_message6FA 0;
BA_ "GenSigCycleTime" SG_ 1787 Diagnose_message_6FB 0;
BA_ "GenSigSendType" SG_ 1787 Diagnose_message_6FB 3;
BA_ "GenSigStartValue" SG_ 1787 Diagnose_message_6FB 0;
BA_ "GenSigInvalidValue" SG_ 1787 Diagnose_message_6FB 0;
BA_ "GenSigCycleTime" SG_ 1790 ErpsBootMode 100;
BA_ "GenSigSendType" SG_ 1790 ErpsBootMode 0;
BA_ "GenSigStartValue" SG_ 1790 ErpsBootMode 0;
BA_ "GenSigInvalidValue" SG_ 1790 ErpsBootMode 0;
BA_ "GenSigCycleTime" SG_ 1793 Diagnose_message_701 0;
BA_ "GenSigSendType" SG_ 1793 Diagnose_message_701 3;
BA_ "GenSigStartValue" SG_ 1793 Diagnose_message_701 0;
BA_ "GenSigInvalidValue" SG_ 1793 Diagnose_message_701 0;
BA_ "GenSigCycleTime" SG_ 1795 Diagnose_message_703 0;
BA_ "GenSigSendType" SG_ 1795 Diagnose_message_703 3;
BA_ "GenSigStartValue" SG_ 1795 Diagnose_message_703 0;
BA_ "GenSigInvalidValue" SG_ 1795 Diagnose_message_703 0;
BA_ "GenSigCycleTime" SG_ 1796 Diagnose_message_704 0;
BA_ "GenSigSendType" SG_ 1796 Diagnose_message_704 3;
BA_ "GenSigStartValue" SG_ 1796 Diagnose_message_704 0;
BA_ "GenSigInvalidValue" SG_ 1796 Diagnose_message_704 0;
BA_ "GenSigCycleTime" SG_ 1801 Diagnose_message_709 0;
BA_ "GenSigSendType" SG_ 1801 Diagnose_message_709 3;
BA_ "GenSigStartValue" SG_ 1801 Diagnose_message_709 0;
BA_ "GenSigInvalidValue" SG_ 1801 Diagnose_message_709 0;
BA_ "GenSigCycleTime" SG_ 1803 Diagnose_message_70B 0;
BA_ "GenSigSendType" SG_ 1803 Diagnose_message_70B 3;
BA_ "GenSigStartValue" SG_ 1803 Diagnose_message_70B 0;
BA_ "GenSigInvalidValue" SG_ 1803 Diagnose_message_70B 0;
BA_ "GenSigCycleTime" SG_ 1804 Diagnose_message_70C 0;
BA_ "GenSigSendType" SG_ 1804 Diagnose_message_70C 3;
BA_ "GenSigStartValue" SG_ 1804 Diagnose_message_70C 0;
BA_ "GenSigInvalidValue" SG_ 1804 Diagnose_message_70C 0;
BA_ "GenSigCycleTime" SG_ 1808 Diagnose_message_710 0;
BA_ "GenSigSendType" SG_ 1808 Diagnose_message_710 3;
BA_ "GenSigStartValue" SG_ 1808 Diagnose_message_710 0;
BA_ "GenSigInvalidValue" SG_ 1808 Diagnose_message_710 0;
BA_ "GenSigCycleTime" SG_ 1811 Diagnose_message_713 0;
BA_ "GenSigSendType" SG_ 1811 Diagnose_message_713 3;
BA_ "GenSigStartValue" SG_ 1811 Diagnose_message_713 0;
BA_ "GenSigInvalidValue" SG_ 1811 Diagnose_message_713 0;
BA_ "GenSigCycleTime" SG_ 1816 Diagnose_message_718 0;
BA_ "GenSigSendType" SG_ 1816 Diagnose_message_718 3;
BA_ "GenSigStartValue" SG_ 1816 Diagnose_message_718 0;
BA_ "GenSigInvalidValue" SG_ 1816 Diagnose_message_718 0;
BA_ "GenSigCycleTime" SG_ 1819 Diagnose_message_71B 0;
BA_ "GenSigSendType" SG_ 1819 Diagnose_message_71B 3;
BA_ "GenSigStartValue" SG_ 1819 Diagnose_message_71B 0;
BA_ "GenSigInvalidValue" SG_ 1819 Diagnose_message_71B 0;
BA_ "GenSigCycleTime" SG_ 1824 Diagnose_message_720 0;
BA_ "GenSigSendType" SG_ 1824 Diagnose_message_720 3;
BA_ "GenSigStartValue" SG_ 1824 Diagnose_message_720 0;
BA_ "GenSigInvalidValue" SG_ 1824 Diagnose_message_720 0;
BA_ "GenSigCycleTime" SG_ 1832 Diagnose_message_728 0;
BA_ "GenSigSendType" SG_ 1832 Diagnose_message_728 3;
BA_ "GenSigStartValue" SG_ 1832 Diagnose_message_728 0;
BA_ "GenSigInvalidValue" SG_ 1832 Diagnose_message_728 0;
BA_ "GenSigCycleTime" SG_ 1843 Diagnose_message_733 0;
BA_ "GenSigSendType" SG_ 1843 Diagnose_message_733 3;
BA_ "GenSigStartValue" SG_ 1843 Diagnose_message_733 0;
BA_ "GenSigInvalidValue" SG_ 1843 Diagnose_message_733 0;
BA_ "GenSigCycleTime" SG_ 1845 Diagnose_message_735 0;
BA_ "GenSigSendType" SG_ 1845 Diagnose_message_735 3;
BA_ "GenSigStartValue" SG_ 1845 Diagnose_message_735 0;
BA_ "GenSigInvalidValue" SG_ 1845 Diagnose_message_735 0;
BA_ "GenSigCycleTime" SG_ 1851 Diagnose_message_73B 0;
BA_ "GenSigSendType" SG_ 1851 Diagnose_message_73B 3;
BA_ "GenSigStartValue" SG_ 1851 Diagnose_message_73B 0;
BA_ "GenSigInvalidValue" SG_ 1851 Diagnose_message_73B 0;
BA_ "GenSigCycleTime" SG_ 1853 Diagnose_message_73D 0;
BA_ "GenSigSendType" SG_ 1853 Diagnose_message_73D 3;
BA_ "GenSigStartValue" SG_ 1853 Diagnose_message_73D 0;
BA_ "GenSigInvalidValue" SG_ 1853 Diagnose_message_73D 0;
BA_ "GenSigCycleTime" SG_ 1875 Diagnose_message_753 0;
BA_ "GenSigSendType" SG_ 1875 Diagnose_message_753 3;
BA_ "GenSigStartValue" SG_ 1875 Diagnose_message_753 0;
BA_ "GenSigInvalidValue" SG_ 1875 Diagnose_message_753 0;
BA_ "GenSigCycleTime" SG_ 1883 Diagnose_message_75B 0;
BA_ "GenSigSendType" SG_ 1883 Diagnose_message_75B 3;
BA_ "GenSigStartValue" SG_ 1883 Diagnose_message_75B 0;
BA_ "GenSigInvalidValue" SG_ 1883 Diagnose_message_75B 0;
BA_ "GenSigCycleTime" SG_ 1892 Diagnose_message_764 0;
BA_ "GenSigSendType" SG_ 1892 Diagnose_message_764 3;
BA_ "GenSigStartValue" SG_ 1892 Diagnose_message_764 0;
BA_ "GenSigInvalidValue" SG_ 1892 Diagnose_message_764 0;
BA_ "GenSigCycleTime" SG_ 1900 Diagnose_message_76C 0;
BA_ "GenSigSendType" SG_ 1900 Diagnose_message_76C 3;
BA_ "GenSigStartValue" SG_ 1900 Diagnose_message_76C 0;
BA_ "GenSigInvalidValue" SG_ 1900 Diagnose_message_76C 0;
BA_ "GenSigCycleTime" SG_ 1910 Diagnose_message_776 0;
BA_ "GenSigSendType" SG_ 1910 Diagnose_message_776 3;
BA_ "GenSigStartValue" SG_ 1910 Diagnose_message_776 0;
BA_ "GenSigInvalidValue" SG_ 1910 Diagnose_message_776 0;
BA_ "GenSigCycleTime" SG_ 1911 Diagnose_message_777 0;
BA_ "GenSigSendType" SG_ 1911 Diagnose_message_777 3;
BA_ "GenSigStartValue" SG_ 1911 Diagnose_message_777 0;
BA_ "GenSigInvalidValue" SG_ 1911 Diagnose_message_777 0;
BA_ "GenSigCycleTime" SG_ 1918 Diagnose_message_77E 0;
BA_ "GenSigSendType" SG_ 1918 Diagnose_message_77E 3;
BA_ "GenSigStartValue" SG_ 1918 Diagnose_message_77E 0;
BA_ "GenSigInvalidValue" SG_ 1918 Diagnose_message_77E 0;
BA_ "GenSigCycleTime" SG_ 1919 Diagnose_message_77F 0;
BA_ "GenSigSendType" SG_ 1919 Diagnose_message_77F 3;
BA_ "GenSigStartValue" SG_ 1919 Diagnose_message_77F 0;
BA_ "GenSigInvalidValue" SG_ 1919 Diagnose_message_77F 0;
BA_ "GenSigCycleTime" SG_ 1955 Diagnose_message7A3 0;
BA_ "GenSigSendType" SG_ 1955 Diagnose_message7A3 3;
BA_ "GenSigStartValue" SG_ 1955 Diagnose_message7A3 0;
BA_ "GenSigInvalidValue" SG_ 1955 Diagnose_message7A3 0;
BA_ "GenSigCycleTime" SG_ 1957 Diagnose_message_7A5 0;
BA_ "GenSigSendType" SG_ 1957 Diagnose_message_7A5 3;
BA_ "GenSigStartValue" SG_ 1957 Diagnose_message_7A5 0;
BA_ "GenSigInvalidValue" SG_ 1957 Diagnose_message_7A5 0;
BA_ "GenSigCycleTime" SG_ 1963 Diagnose_message7AB 0;
BA_ "GenSigSendType" SG_ 1963 Diagnose_message7AB 3;
BA_ "GenSigStartValue" SG_ 1963 Diagnose_message7AB 0;
BA_ "GenSigInvalidValue" SG_ 1963 Diagnose_message7AB 0;
BA_ "GenSigCycleTime" SG_ 1965 Diagnose_message_7AD 0;
BA_ "GenSigSendType" SG_ 1965 Diagnose_message_7AD 3;
BA_ "GenSigStartValue" SG_ 1965 Diagnose_message_7AD 0;
BA_ "GenSigInvalidValue" SG_ 1965 Diagnose_message_7AD 0;
BA_ "GenSigCycleTime" SG_ 1984 Diagnose_message_7C0 0;
BA_ "GenSigSendType" SG_ 1984 Diagnose_message_7C0 3;
BA_ "GenSigStartValue" SG_ 1984 Diagnose_message_7C0 0;
BA_ "GenSigInvalidValue" SG_ 1984 Diagnose_message_7C0 0;
BA_ "GenSigCycleTime" SG_ 1992 Diagnose_message_7C8 0;
BA_ "GenSigSendType" SG_ 1992 Diagnose_message_7C8 3;
BA_ "GenSigStartValue" SG_ 1992 Diagnose_message_7C8 0;
BA_ "GenSigInvalidValue" SG_ 1992 Diagnose_message_7C8 0;
BA_ "GenSigCycleTime" SG_ 2000 Diagnose_message_7D0 0;
BA_ "GenSigSendType" SG_ 2000 Diagnose_message_7D0 3;
BA_ "GenSigStartValue" SG_ 2000 Diagnose_message_7D0 0;
BA_ "GenSigInvalidValue" SG_ 2000 Diagnose_message_7D0 0;
BA_ "GenSigCycleTime" SG_ 2004 Diagnose_message_7D4 0;
BA_ "GenSigSendType" SG_ 2004 Diagnose_message_7D4 3;
BA_ "GenSigStartValue" SG_ 2004 Diagnose_message_7D4 0;
BA_ "GenSigInvalidValue" SG_ 2004 Diagnose_message_7D4 0;
BA_ "GenSigCycleTime" SG_ 2005 Diagnose_message_7D5 0;
BA_ "GenSigSendType" SG_ 2005 Diagnose_message_7D5 3;
BA_ "GenSigStartValue" SG_ 2005 Diagnose_message_7D5 0;
BA_ "GenSigInvalidValue" SG_ 2005 Diagnose_message_7D5 0;
BA_ "GenSigCycleTime" SG_ 2006 Diagnose_message_7D6 0;
BA_ "GenSigSendType" SG_ 2006 Diagnose_message_7D6 3;
BA_ "GenSigStartValue" SG_ 2006 Diagnose_message_7D6 0;
BA_ "GenSigInvalidValue" SG_ 2006 Diagnose_message_7D6 0;
BA_ "GenSigCycleTime" SG_ 2007 Diagnose_message_7D7 0;
BA_ "GenSigSendType" SG_ 2007 Diagnose_message_7D7 3;
BA_ "GenSigStartValue" SG_ 2007 Diagnose_message_7D7 0;
BA_ "GenSigInvalidValue" SG_ 2007 Diagnose_message_7D7 0;
BA_ "GenSigCycleTime" SG_ 2008 Diagnose_message_7D8 0;
BA_ "GenSigSendType" SG_ 2008 Diagnose_message_7D8 3;
BA_ "GenSigStartValue" SG_ 2008 Diagnose_message_7D8 0;
BA_ "GenSigInvalidValue" SG_ 2008 Diagnose_message_7D8 0;
BA_ "GenSigCycleTime" SG_ 2015 Diagnose_message_7DF 0;
BA_ "GenSigSendType" SG_ 2015 Diagnose_message_7DF 3;
BA_ "GenSigStartValue" SG_ 2015 Diagnose_message_7DF 0;
BA_ "GenSigInvalidValue" SG_ 2015 Diagnose_message_7DF 0;
BA_ "GenSigCycleTime" SG_ 2016 Diagnose_message_7E0 0;
BA_ "GenSigSendType" SG_ 2016 Diagnose_message_7E0 3;
BA_ "GenSigStartValue" SG_ 2016 Diagnose_message_7E0 0;
BA_ "GenSigInvalidValue" SG_ 2016 Diagnose_message_7E0 0;
BA_ "GenSigCycleTime" SG_ 2017 Diagnose_message7E1 0;
BA_ "GenSigSendType" SG_ 2017 Diagnose_message7E1 3;
BA_ "GenSigStartValue" SG_ 2017 Diagnose_message7E1 0;
BA_ "GenSigInvalidValue" SG_ 2017 Diagnose_message7E1 0;
BA_ "GenSigCycleTime" SG_ 2024 Diagnose_message_7E8 0;
BA_ "GenSigSendType" SG_ 2024 Diagnose_message_7E8 3;
BA_ "GenSigStartValue" SG_ 2024 Diagnose_message_7E8 0;
BA_ "GenSigInvalidValue" SG_ 2024 Diagnose_message_7E8 0;
BA_ "GenSigCycleTime" SG_ 2025 Diagnose_message7E9 0;
BA_ "GenSigSendType" SG_ 2025 Diagnose_message7E9 3;
BA_ "GenSigStartValue" SG_ 2025 Diagnose_message7E9 0;
BA_ "GenSigInvalidValue" SG_ 2025 Diagnose_message7E9 0;
BA_ "GenSigCycleTime" SG_ 2033 Diagnose_message_7F1 0;
BA_ "GenSigSendType" SG_ 2033 Diagnose_message_7F1 3;
BA_ "GenSigStartValue" SG_ 2033 Diagnose_message_7F1 0;
BA_ "GenSigInvalidValue" SG_ 2033 Diagnose_message_7F1 0;
BA_ "GenSigCycleTime" SG_ 2041 Diagnose_message_7F9 0;
BA_ "GenSigSendType" SG_ 2041 Diagnose_message_7F9 3;
BA_ "GenSigStartValue" SG_ 2041 Diagnose_message_7F9 0;
BA_ "GenSigInvalidValue" SG_ 2041 Diagnose_message_7F9 0;
VAL_ 1407 VIU_FL_WakeUp_BYTE0BIT0 0 "Inactive" 1 "NM唤醒" ;
VAL_ 1407 VIU_FL_WakeUp_BYTE0BIT1 0 "Inactive" 1 "RTC定时唤醒" ;
VAL_ 1407 VIU_FL_WakeUp_BYTE0BIT2 0 "Inactive" 1 "VIUFL_LIN5 收到RLS\\IBS的从节点唤醒信号" ;
VAL_ 1407 VIU_FL_WakeUp_BYTE0BIT3 0 "Inactive" 1 "TPMS胎压唤醒" ;
VAL_ 1407 VIU_FL_WakeUp_BYTE0BIT4 0 "Inactive" 1 "紧急报警开关Hazard_SW状态发生跳变" ;
VAL_ 1407 VIU_FL_WakeUp_BYTE0BIT5 0 "Inactive" 1 "检测到VIU电源电压低于12.3以下（(智能补电功能触发)" ;
VAL_ 1407 VIU_FL_WakeUp_BYTE0BIT6 0 "Inactive" 1 "检测到EFUSE端口唤醒电流超出或故障" ;
VAL_ 1407 VIU_FL_WakeUp_BYTE0BIT7 0 "Inactive" 1 "右前座椅靠背前后、坐垫起翘上下调节开关" ;
VAL_ 1407 VIU_FL_WakeUp_BYTE1BIT0 0 "Inactive" 1 "蓝牙连接" ;
VAL_ 1407 VIU_FL_WakeUp_BYTE1BIT1 0 "Inactive" 1 "检测到前舱盖信号出现跳变（前备箱盖状态检测1、前备箱盖状态检测2）/预留开关" ;
VAL_ 1407 VIU_FL_WakeUp_BYTE1BIT2 0 "Inactive" 1 "检测到左前车门状态信号出现跳变（左前车门微开状态检测）" ;
VAL_ 1407 VIU_FL_WakeUp_BYTE1BIT3 0 "Inactive" 1 "检测到右前车门状态信号出现跳变（右前车门微开状态检测）" ;
VAL_ 1407 VIU_FL_WakeUp_BYTE1BIT4 0 "Inactive" 1 "检测到左后、右后车门状态信号出现跳变（左后/右后车门微开状态检测）" ;
VAL_ 1407 VIU_FL_WakeUp_BYTE1BIT5 0 "Inactive" 1 "检测到门锁状态信号出现跳变（左前门锁状态检测）" ;
VAL_ 1407 VIU_FL_WakeUp_BYTE1BIT6 0 "Inactive" 1 "检测到门锁状态信号出现跳变（右前门锁状态检测）" ;
VAL_ 1407 VIU_FL_WakeUp_BYTE1BIT7 0 "Inactive" 1 "检测到门锁状态信号出现跳变（左后、右后门锁状态检测）" ;
VAL_ 1407 VIU_FL_WakeUp_BYTE2BIT0 0 "Inactive" 1 "检测到“中控锁解锁开关/中控解闭锁" ;
VAL_ 1407 VIU_FL_WakeUp_BYTE2BIT1 0 "Inactive" 1 "检测到“左前车内车门开关”出现跳变" ;
VAL_ 1407 VIU_FL_WakeUp_BYTE2BIT2 0 "Inactive" 1 "检测到“右前车内车门开关”出现跳变" ;
VAL_ 1407 VIU_FL_WakeUp_BYTE2BIT3 0 "Inactive" 1 "检测到“左后/右后车内车门开关”出现跳变" ;
VAL_ 1407 VIU_FL_WakeUp_BYTE2BIT4 0 "Inactive" 1 "检测到“左前门把手按键检测”有效/离合器开关" ;
VAL_ 1407 VIU_FL_WakeUp_BYTE2BIT5 0 "Inactive" 1 "检测到“右前门把手按键检测”有效" ;
VAL_ 1407 VIU_FL_WakeUp_BYTE2BIT6 0 "Inactive" 1 "检测到“左后/右后门把手按键检测”有效" ;
VAL_ 1407 VIU_FL_WakeUp_BYTE2BIT7 0 "Inactive" 1 "检测到行李箱门锁状态信号出现跳变（背门吸合锁1半锁位置开关检测）" ;
VAL_ 1407 VIU_FL_WakeUp_BYTE3BIT0 0 "Inactive" 1 "检测到行李箱门锁状态信号出现跳变（背门吸合锁1全锁位置开关检测）" ;
VAL_ 1407 VIU_FL_WakeUp_BYTE3BIT1 0 "Inactive" 1 "检测到“后背门车内开关”出现跳变" ;
VAL_ 1407 VIU_FL_WakeUp_BYTE3BIT2 0 "Inactive" 1 "检测到“后背门车外开关”出现跳变" ;
VAL_ 1407 VIU_FL_WakeUp_BYTE3BIT3 0 "Inactive" 1 "检测到“后背门全关&闭锁开关”出现跳变" ;
VAL_ 1407 VIU_FL_WakeUp_BYTE3BIT4 0 "Inactive" 1 "检测到“主驾座椅人员检测”出现跳变" ;
VAL_ 1407 VIU_FL_WakeUp_BYTE3BIT5 0 "Inactive" 1 "预留" ;
VAL_ 1407 VIU_FL_WakeUp_BYTE3BIT6 0 "Inactive" 1 "预留" ;
VAL_ 1407 VIU_FL_WakeUp_BYTE3BIT7 0 "Inactive" 1 "喇叭开关跳变" ;
VAL_ 1407 VIU_FL_WakeUp_BYTE4BIT0 0 "Inactive" 1 "VCU_A+信号检测（充电唤醒信号）高电平" ;
VAL_ 1407 VIU_FL_WakeUp_BYTE4BIT1 0 "Inactive" 1 "VCU_SWP1（输出P1挡）输入有效" ;
VAL_ 1407 VIU_FL_WakeUp_BYTE4BIT2 0 "Inactive" 1 "VCU_SWP2（输出P2挡）输入有效/左前座椅前后、上下调节开关" ;
VAL_ 1407 VIU_FL_WakeUp_BYTE4BIT3 0 "Inactive" 1 "VCU_车内220V电源放电开关" ;
VAL_ 1407 VIU_FL_WakeUp_BYTE4BIT4 0 "Inactive" 1 "制动开关常开输入信号" ;
VAL_ 1407 VIU_FL_WakeUp_BYTE4BIT5 0 "Inactive" 1 "背门左侧吸合锁半锁位置开关" ;
VAL_ 1407 VIU_FL_WakeUp_BYTE4BIT6 0 "Inactive" 1 "紧急搭电电源唤醒" ;
VAL_ 1407 VIU_FL_WakeUp_BYTE4BIT7 0 "Inactive" 1 "背门右侧吸合锁半锁位置开关/前备箱吸合锁半锁位置开关/前罩锁状态检测" ;
VAL_ 1407 VIU_FL_WakeUp_BYTE5BIT0 0 "Inactive" 1 "硬线唤醒信号输入（HVM）" ;
VAL_ 1407 VIU_FL_WakeUp_BYTE5BIT1 0 "Inactive" 1 "烟雾传感器硬线唤醒输入" ;
VAL_ 1407 VIU_FL_WakeUp_BYTE5BIT2 0 "Inactive" 1 "(预留开关)左前门PE开关/左前门把手电容开关" ;
VAL_ 1407 VIU_FL_WakeUp_BYTE5BIT3 0 "Inactive" 1 "(预留开关)Front_Trunk_SW" ;
VAL_ 1407 VIU_FL_WakeUp_BYTE5BIT4 0 "Inactive" 1 "(预留)高有效信号输入2" ;
VAL_ 1407 VIU_FL_WakeUp_BYTE5BIT5 0 "Inactive" 1 "慢充唤醒" ;
VAL_ 1407 VIU_FL_WakeUp_BYTE5BIT6 0 "Inactive" 1 "预留" ;
VAL_ 1407 VIU_FL_WakeUp_BYTE5BIT7 0 "Inactive" 1 "充电连接确认1" ;
VAL_ 1407 VIU_FL_WakeUp_BYTE6BIT0 0 "Inactive" 1 "预留" ;
VAL_ 1407 VIU_FL_WakeUp_BYTE6BIT1 0 "Inactive" 1 "右前座椅前后、上下调节开关" ;
VAL_ 1407 VIU_FL_WakeUp_BYTE6BIT2 0 "Inactive" 1 "插枪保温" ;
VAL_ 1407 VIU_FL_WakeUp_BYTE6BIT3 0 "Inactive" 1 "右前座椅腿托上旋转、伸缩调节开关" ;
VAL_ 1407 VIU_FL_WakeUp_BYTE6BIT4 0 "Inactive" 1 "副驾零重力座椅开关" ;
VAL_ 1407 VIU_FL_WakeUp_BYTE6BIT5 0 "Inactive" 1 "右前座椅老板键开关" ;
VAL_ 1407 VIU_FL_WakeUp_BYTE6BIT6 0 "Inactive" 1 "左前座椅靠背前后、坐垫起翘上下调节开关" ;
VAL_ 1407 VIU_FL_WakeUp_BYTE6BIT7 0 "Inactive" 1 "主驾座椅腿托上旋转、伸缩调节开关/第二排左侧座椅前后调节开关" ;
VAL_ 1407 VIU_FL_WakeUp_BYTE7BIT0 0 "Inactive" 1 "左前零重力座椅开关-预留/启停开关1" ;
VAL_ 1407 VIU_FL_WakeUp_BYTE7BIT1 0 "Inactive" 1 "左后门把手电容开关" ;
VAL_ 1407 VIU_FL_WakeUp_BYTE7BIT2 0 "Inactive" 1 "制动踏板唤醒源" ;
VAL_ 1407 VIU_FL_WakeUp_BYTE7BIT3 0 "Inactive" 1 "预留低有效信号输入" ;
VAL_ 1407 VIU_FL_WakeUp_BYTE7BIT4 0 "Inactive" 1 "以太网唤醒线" ;
VAL_ 1407 VIU_FL_WakeUp_BYTE7BIT5 0 "Inactive" 1 "预留模拟输入3" ;
VAL_ 1407 VIU_FL_WakeUp_BYTE7BIT6 0 "Inactive" 1 "预留模拟输入4" ;
VAL_ 1407 VIU_FL_WakeUp_BYTE7BIT7 0 "Inactive" 1 "预留开关" ;
VAL_ 1407 VIU_FL_WakeUp_BYTE15BIT0 0 "Inactive" 1 "PT传感器受温度输入（电池冷却器后端）" ;
VAL_ 1407 VIU_FL_WakeUp_BYTE15BIT1 0 "Inactive" 1 "车内温度传感器（前排）" ;
VAL_ 1411 IP_WakeUp_BYTE3BIT0 0 "Inactive" 1 " 硬线唤醒" ;
VAL_ 1411 IP_NotSleep_BYTE7BIT0 0 "Inactive" 1 " IP硬线唤醒信号为高电平" ;
VAL_ 1411 IP_NotSleep_BYTE7BIT1 0 "Inactive" 1 " 其他条件（包含外部/远程/本地功能请求及诊断模式）" ;
VAL_ 1417 VIU_FR_WakeUp_BYTE0BIT0 0 "Inactive" 1 "NM唤醒" ;
VAL_ 1417 VIU_FR_WakeUp_BYTE0BIT1 0 "Inactive" 1 "RTC定时唤醒" ;
VAL_ 1417 VIU_FR_WakeUp_BYTE0BIT2 0 "Inactive" 1 "VIUFL_LIN5 收到RLS\\IBS的从节点唤醒信号" ;
VAL_ 1417 VIU_FR_WakeUp_BYTE0BIT3 0 "Inactive" 1 "TPMS胎压唤醒" ;
VAL_ 1417 VIU_FR_WakeUp_BYTE0BIT4 0 "Inactive" 1 "紧急报警开关Hazard_SW状态发生跳变" ;
VAL_ 1417 VIU_FR_WakeUp_BYTE0BIT5 0 "Inactive" 1 "检测到VIU电源电压低于12.3以下（(智能补电功能触发)" ;
VAL_ 1417 VIU_FR_WakeUp_BYTE0BIT6 0 "Inactive" 1 "检测到EFUSE端口唤醒电流超出或故障" ;
VAL_ 1417 VIU_FR_WakeUp_BYTE0BIT7 0 "Inactive" 1 "右前座椅靠背前后、坐垫起翘上下调节开关" ;
VAL_ 1417 VIU_FR_WakeUp_BYTE1BIT0 0 "Inactive" 1 "蓝牙连接" ;
VAL_ 1417 VIU_FR_WakeUp_BYTE1BIT1 0 "Inactive" 1 "检测到前舱盖信号出现跳变（前备箱盖状态检测1、前备箱盖状态检测2）/预留开关" ;
VAL_ 1417 VIU_FR_WakeUp_BYTE1BIT2 0 "Inactive" 1 "检测到左前车门状态信号出现跳变（左前车门微开状态检测）" ;
VAL_ 1417 VIU_FR_WakeUp_BYTE1BIT3 0 "Inactive" 1 "检测到右前车门状态信号出现跳变（右前车门微开状态检测）" ;
VAL_ 1417 VIU_FR_WakeUp_BYTE1BIT4 0 "Inactive" 1 "检测到左后、右后车门状态信号出现跳变（左后/右后车门微开状态检测）" ;
VAL_ 1417 VIU_FR_WakeUp_BYTE1BIT5 0 "Inactive" 1 "检测到门锁状态信号出现跳变（左前门锁状态检测）" ;
VAL_ 1417 VIU_FR_WakeUp_BYTE1BIT6 0 "Inactive" 1 "检测到门锁状态信号出现跳变（右前门锁状态检测）" ;
VAL_ 1417 VIU_FR_WakeUp_BYTE1BIT7 0 "Inactive" 1 "检测到门锁状态信号出现跳变（左后、右后门锁状态检测）" ;
VAL_ 1417 VIU_FR_WakeUp_BYTE2BIT0 0 "Inactive" 1 "检测到“中控锁解锁开关/中控解闭锁" ;
VAL_ 1417 VIU_FR_WakeUp_BYTE2BIT1 0 "Inactive" 1 "检测到“左前车内车门开关”出现跳变" ;
VAL_ 1417 VIU_FR_WakeUp_BYTE2BIT2 0 "Inactive" 1 "检测到“右前车内车门开关”出现跳变" ;
VAL_ 1417 VIU_FR_WakeUp_BYTE2BIT3 0 "Inactive" 1 "检测到“左后/右后车内车门开关”出现跳变" ;
VAL_ 1417 VIU_FR_WakeUp_BYTE2BIT4 0 "Inactive" 1 "检测到“左前门把手按键检测”有效/离合器开关" ;
VAL_ 1417 VIU_FR_WakeUp_BYTE2BIT5 0 "Inactive" 1 "检测到“右前门把手按键检测”有效" ;
VAL_ 1417 VIU_FR_WakeUp_BYTE2BIT6 0 "Inactive" 1 "检测到“左后/右后门把手按键检测”有效" ;
VAL_ 1417 VIU_FR_WakeUp_BYTE2BIT7 0 "Inactive" 1 "检测到行李箱门锁状态信号出现跳变（背门吸合锁1半锁位置开关检测）" ;
VAL_ 1417 VIU_FR_WakeUp_BYTE3BIT0 0 "Inactive" 1 "检测到行李箱门锁状态信号出现跳变（背门吸合锁1全锁位置开关检测）" ;
VAL_ 1417 VIU_FR_WakeUp_BYTE3BIT1 0 "Inactive" 1 "检测到“后背门车内开关”出现跳变" ;
VAL_ 1417 VIU_FR_WakeUp_BYTE3BIT2 0 "Inactive" 1 "检测到“后背门车外开关”出现跳变" ;
VAL_ 1417 VIU_FR_WakeUp_BYTE3BIT3 0 "Inactive" 1 "检测到“后背门全关&闭锁开关”出现跳变" ;
VAL_ 1417 VIU_FR_WakeUp_BYTE3BIT4 0 "Inactive" 1 "检测到“主驾座椅人员检测”出现跳变" ;
VAL_ 1417 VIU_FR_WakeUp_BYTE3BIT5 0 "Inactive" 1 "预留" ;
VAL_ 1417 VIU_FR_WakeUp_BYTE3BIT6 0 "Inactive" 1 "预留" ;
VAL_ 1417 VIU_FR_WakeUp_BYTE3BIT7 0 "Inactive" 1 "喇叭开关跳变" ;
VAL_ 1417 VIU_FR_WakeUp_BYTE4BIT0 0 "Inactive" 1 "VCU_A+信号检测（充电唤醒信号）高电平" ;
VAL_ 1417 VIU_FR_WakeUp_BYTE4BIT1 0 "Inactive" 1 "VCU_SWP1（输出P1挡）输入有效" ;
VAL_ 1417 VIU_FR_WakeUp_BYTE4BIT2 0 "Inactive" 1 "VCU_SWP2（输出P2挡）输入有效/左前座椅前后、上下调节开关" ;
VAL_ 1417 VIU_FR_WakeUp_BYTE4BIT3 0 "Inactive" 1 "VCU_车内220V电源放电开关" ;
VAL_ 1417 VIU_FR_WakeUp_BYTE4BIT4 0 "Inactive" 1 "制动开关常开输入信号" ;
VAL_ 1417 VIU_FR_WakeUp_BYTE4BIT5 0 "Inactive" 1 "背门左侧吸合锁半锁位置开关" ;
VAL_ 1417 VIU_FR_WakeUp_BYTE4BIT6 0 "Inactive" 1 "紧急搭电电源唤醒" ;
VAL_ 1417 VIU_FR_WakeUp_BYTE4BIT7 0 "Inactive" 1 "背门右侧吸合锁半锁位置开关/前备箱吸合锁半锁位置开关/前罩锁状态检测" ;
VAL_ 1417 VIU_FR_WakeUp_BYTE5BIT0 0 "Inactive" 1 "硬线唤醒信号输入（HVM）" ;
VAL_ 1417 VIU_FR_WakeUp_BYTE5BIT1 0 "Inactive" 1 "烟雾传感器硬线唤醒输入" ;
VAL_ 1417 VIU_FR_WakeUp_BYTE5BIT2 0 "Inactive" 1 "(预留开关)左前门PE开关/左前门把手电容开关" ;
VAL_ 1417 VIU_FR_WakeUp_BYTE5BIT3 0 "Inactive" 1 "(预留开关)Front_Trunk_SW" ;
VAL_ 1417 VIU_FR_WakeUp_BYTE5BIT4 0 "Inactive" 1 "(预留)高有效信号输入2" ;
VAL_ 1417 VIU_FR_WakeUp_BYTE5BIT5 0 "Inactive" 1 "慢充唤醒" ;
VAL_ 1417 VIU_FR_WakeUp_BYTE5BIT6 0 "Inactive" 1 "预留" ;
VAL_ 1417 VIU_FR_WakeUp_BYTE5BIT7 0 "Inactive" 1 "充电连接确认1" ;
VAL_ 1417 VIU_FR_WakeUp_BYTE6BIT0 0 "Inactive" 1 "预留" ;
VAL_ 1417 VIU_FR_WakeUp_BYTE6BIT1 0 "Inactive" 1 "右前座椅前后、上下调节开关" ;
VAL_ 1417 VIU_FR_WakeUp_BYTE6BIT2 0 "Inactive" 1 "插枪保温" ;
VAL_ 1417 VIU_FR_WakeUp_BYTE6BIT3 0 "Inactive" 1 "右前座椅腿托上旋转、伸缩调节开关" ;
VAL_ 1417 VIU_FR_WakeUp_BYTE6BIT4 0 "Inactive" 1 "副驾零重力座椅开关" ;
VAL_ 1417 VIU_FR_WakeUp_BYTE6BIT5 0 "Inactive" 1 "右前座椅老板键开关" ;
VAL_ 1417 VIU_FR_WakeUp_BYTE6BIT6 0 "Inactive" 1 "左前座椅靠背前后、坐垫起翘上下调节开关" ;
VAL_ 1417 VIU_FR_WakeUp_BYTE6BIT7 0 "Inactive" 1 "主驾座椅腿托上旋转、伸缩调节开关/第二排左侧座椅前后调节开关" ;
VAL_ 1417 VIU_FR_WakeUp_BYTE7BIT0 0 "Inactive" 1 "左前零重力座椅开关-预留/启停开关1" ;
VAL_ 1417 VIU_FR_WakeUp_BYTE7BIT1 0 "Inactive" 1 "左后门把手电容开关" ;
VAL_ 1417 VIU_FR_WakeUp_BYTE7BIT2 0 "Inactive" 1 "制动踏板唤醒源" ;
VAL_ 1417 VIU_FR_WakeUp_BYTE7BIT3 0 "Inactive" 1 "预留低有效信号输入" ;
VAL_ 1417 VIU_FR_WakeUp_BYTE7BIT4 0 "Inactive" 1 "以太网唤醒线" ;
VAL_ 1417 VIU_FR_WakeUp_BYTE7BIT5 0 "Inactive" 1 "预留模拟输入3" ;
VAL_ 1417 VIU_FR_WakeUp_BYTE7BIT6 0 "Inactive" 1 "预留模拟输入4" ;
VAL_ 1417 VIU_FR_WakeUp_BYTE7BIT7 0 "Inactive" 1 "预留开关" ;
VAL_ 1418 VIU_FR_WakeUp_BYTE15BIT0 0 "Inactive" 1 "PT传感器受温度输入（电池冷却器后端）" ;
VAL_ 1418 VIU_FR_WakeUp_BYTE15BIT1 0 "Inactive" 1 "车内温度传感器（前排）" ;
VAL_ 1430 RLR_NotSleep_BYTE7BIT0 0 "Inactive" 1 "网络上其他节点NM报文不允许休眠" ;
VAL_ 1430 RLR_NotSleep_BYTE7BIT1 0 "Inactive" 1 "电源档位为ON档" ;
VAL_ 1430 RLR_NotSleep_BYTE7BIT2 0 "Inactive" 1 "电源模式切换为OFF后的5分钟内" ;
VAL_ 1430 RLR_NotSleep_BYTE7BIT3 0 "Inactive" 1 "其他条件（包含外部/远程/本地功能请求及诊断模式）" ;
VAL_ 1430 RLR_WakeUp_BYTE3BIT0 0 "Inactive" 1 "NM报文唤醒" ;
VAL_ 1430 RLR_WakeUp_BYTE3BIT1 0 "Inactive" 1 "电源档位为ON档" ;
VAL_ 1431 RRR_NotSleep_BYTE7BIT0 0 "Inactive" 1 "网络上其他节点NM报文不允许休眠" ;
VAL_ 1431 RRR_NotSleep_BYTE7BIT1 0 "Inactive" 1 "电源档位为ON档" ;
VAL_ 1431 RRR_NotSleep_BYTE7BIT2 0 "Inactive" 1 "电源模式切换为OFF后的5分钟内" ;
VAL_ 1431 RRR_NotSleep_BYTE7BIT3 0 "Inactive" 1 "其他条件（包含外部/远程/本地功能请求及诊断模式）" ;
VAL_ 1431 RRR_WakeUp_BYTE3BIT0 0 "Inactive" 1 "NM报文唤醒" ;
VAL_ 1431 RRR_WakeUp_BYTE3BIT1 0 "Inactive" 1 "电源档位为ON档" ;
VAL_ 1432 FRR_NotSleep_BYTE7BIT0 0 "Inactive" 1 "网络上其他节点NM报文不允许休眠" ;
VAL_ 1432 FRR_NotSleep_BYTE7BIT1 0 "Inactive" 1 "电源档位为ON档" ;
VAL_ 1432 FRR_NotSleep_BYTE7BIT2 0 "Inactive" 1 "电源模式切换为OFF后的5分钟内" ;
VAL_ 1432 FRR_NotSleep_BYTE7BIT3 0 "Inactive" 1 "其他条件（包含外部/远程/本地功能请求及诊断模式）" ;
VAL_ 1432 FRR_WakeUp_BYTE3BIT0 0 "Inactive" 1 "NM报文唤醒" ;
VAL_ 1432 FRR_WakeUp_BYTE3BIT1 0 "Inactive" 1 "电源档位为ON档" ;
VAL_ 1438 EVCC_WakeUp_BYTE4BIT3 0 "Inactive" 1 " CP信号从6-12V电平或悬空状态变为PWM状态唤醒" ;
VAL_ 1438 EVCC_WakeUp_BYTE4BIT2 0 "Inactive" 1 " CP信号从悬空状态变为6-12V电平唤醒" ;
VAL_ 1438 EVCC_WakeUp_BYTE4BIT1 0 "Inactive" 1 " KL15唤醒（若不接IG硬线则无此位）" ;
VAL_ 1438 EVCC_WakeUp_BYTE4BIT0 0 "Inactive" 1 " NM唤醒" ;
VAL_ 1438 EVCC_NotSleep_BYTE7BIT4 0 "Inactive" 1 "处于诊断模式" ;
VAL_ 1438 EVCC_NotSleep_BYTE7BIT3 0 "Inactive" 1 "处于充电状态或充电结束一定时间（初始=1min)" ;
VAL_ 1438 EVCC_NotSleep_BYTE7BIT2 0 "Inactive" 1 "唤醒后，一定时间内（初始值=1min）检测到的CP信号不为PWM（3%~7%）状态" ;
VAL_ 1438 EVCC_NotSleep_BYTE7BIT1 0 "Inactive" 1 " IGN硬线信号为ON档/总线电源挡位信号ON" ;
VAL_ 1438 EVCC_NotSleep_BYTE7BIT0 0 "Inactive" 1 "NM不允许休眠" ;
VAL_ 1442 FLR_NotSleep_BYTE7BIT0 0 "Inactive" 1 "网络上其他节点NM报文不允许休眠" ;
VAL_ 1442 FLR_NotSleep_BYTE7BIT1 0 "Inactive" 1 "电源档位为ON档" ;
VAL_ 1442 FLR_NotSleep_BYTE7BIT2 0 "Inactive" 1 "电源模式切换为OFF后的5分钟内" ;
VAL_ 1442 FLR_NotSleep_BYTE7BIT3 0 "Inactive" 1 "其他条件（包含外部/远程/本地功能请求及诊断模式）" ;
VAL_ 1442 FLR_WakeUp_BYTE3BIT0 0 "Inactive" 1 "NM报文唤醒" ;
VAL_ 1442 FLR_WakeUp_BYTE3BIT1 0 "Inactive" 1 "电源档位为ON档" ;
VAL_ 1466 AMP_NotSleep_BYTE7BIT0 0 "Inactive" 1 "网络上其他节点NM报文不允许休眠" ;
VAL_ 1466 AMP_NotSleep_BYTE7BIT1 0 "Inactive" 1 "电源档位为ON档" ;
VAL_ 1466 AMP_NotSleep_BYTE7BIT2 0 "Inactive" 1 "其他条件（包含外部/远程/本地功能请求及诊断模式）" ;
VAL_ 1466 AMP_WakeUp_BYTE3BIT0 0 "Inactive" 1 "NM报文唤醒" ;
VAL_ 1466 AMP_WakeUp_BYTE3BIT1 0 "Inactive" 1 "电源档位为ON档" ;
VAL_ 1502 ReMotSts_GB 1 "耗电" 2 "发电" 3 "关闭状态" 4 "准备状态" ;
VAL_ 1502 ReMotOverSpd_GB 0 "Noerror" 1 "error" ;
VAL_ 1502 ReMotOverI_GB 0 "Noerror" 1 "error" ;
VAL_ 1502 ReIpuTOver_GB 0 "Noerror" 1 "error" ;
VAL_ 1502 ReMotTOver_GB 0 "Noerror" 1 "error" ;
VAL_ 1510 FrntMotStsGb 1 "耗电" 2 "发电" 3 "关闭状态" 4 "准备状态" ;
VAL_ 1510 FrntMotOverSpdGb 0 "Noerror" 1 "error" ;
VAL_ 1510 FrntMotOverIGb 0 "Noerror" 1 "error" ;
VAL_ 1510 FrntIpuTOverGb 0 "Noerror" 1 "error" ;
VAL_ 1510 FrntMotTOverGb 0 "Noerror" 1 "error" ;
VAL_ 1540 EDC_EthMng_MngTyp 0 "预留" 1 "PC/工程模式" 2 "云端" ;
VAL_ 1540 EDC_EthMng_Msg 0 "预留" 1 "request（请求）" 2 "response（请求响应）" 3 "notification（通告）——用于通告ERPS Owner节点ERPS错误" 4 "error(错误)" ;
VAL_ 1540 EDC_EthMng_OptnCod 0 "预留" 1 "add-添加" 2 "del-删除" 3 "mod-修改" 4 "get-获取" ;
VAL_ 1540 EDC_EthMng_Optn 0 "预留" 1 "VIU_FL" 2 "VIU_FR" 3 "C2_MCU" 4 "C2_SOC" 5 "EDC_QNX" 6 "EDC_Android" 7 "EDC_MCU" 8 "EDC_TBOX" 9 "Madc" 10 "LIDAR1" 11 "LIDAR2" 12 "INS" 13 "C3_J6A核" 14 "C3_MCU" 15 "C3_SE1000AP" 16 "C3_SE1000CP" 17 "C3_M22" ;
VAL_ 1540 EDC_EthMng_DataTyp 0 "预留" 1 "link状态" 2 "SQI" 3 "DataFlow流量统计" 4 "DropFrame丢包统计" 5 "FDB表" 6 "VLAN" 7 "PHY主从" 8 "MAC地址" 9 "IP配置" 10 "全域连通性检测" 11 "PING" ;
VAL_ 1541 VIUFL_EthMng_MngTyp 0 "预留" 1 "PC/工程模式" 2 "云端" ;
VAL_ 1541 VIUFL_EthMng_Msg 0 "预留" 1 "request（请求）" 2 "response（请求响应）" 3 "notification（通告）——用于通告ERPS Owner节点ERPS错误" 4 "error(错误)" ;
VAL_ 1541 VIUFL_EthMng_OptnCod 0 "预留" 1 "add-添加" 2 "del-删除" 3 "mod-修改" 4 "get-获取" ;
VAL_ 1541 VIUFL_EthMng_Optn 0 "预留" 1 "VIU_FL" 2 "VIU_FR" 3 "C2_MCU" 4 "C2_SOC" 5 "EDC_QNX" 6 "EDC_Android" 7 "EDC_MCU" 8 "EDC_TBOX" 9 "Madc" 10 "LIDAR1" 11 "LIDAR2" 12 "INS" 13 "C3_J6A核" 14 "C3_MCU" 15 "C3_SE1000AP" 16 "C3_SE1000CP" 17 "C3_M22" ;
VAL_ 1541 VIUFL_EthMng_DataTyp 0 "预留" 1 "link状态" 2 "SQI" 3 "DataFlow流量统计" 4 "DropFrame丢包统计" 5 "FDB表" 6 "VLAN" 7 "PHY主从" 8 "MAC地址" 9 "IP配置" 10 "全域连通性检测" 11 "PING" ;
VAL_ 1543 VIU_FrTakOveSts 0 "None" 1 "NormalTakeOve" 2 "ForceTakeOve" ;
VAL_ 1546 VIUFR_EthMng_MngTyp 0 "预留" 1 "PC/工程模式" 2 "云端" ;
VAL_ 1546 VIUFR_EthMng_Msg 0 "预留" 1 "request（请求）" 2 "response（请求响应）" 3 "notification（通告）——用于通告ERPS Owner节点ERPS错误" 4 "error(错误)" ;
VAL_ 1546 VIUFR_EthMng_OptnCod 0 "预留" 1 "add-添加" 2 "del-删除" 3 "mod-修改" 4 "get-获取" ;
VAL_ 1546 VIUFR_EthMng_Optn 0 "预留" 1 "VIU_FL" 2 "VIU_FR" 3 "C2_MCU" 4 "C2_SOC" 5 "EDC_QNX" 6 "EDC_Android" 7 "EDC_MCU" 8 "EDC_TBOX" 9 "Madc" 10 "LIDAR1" 11 "LIDAR2" 12 "INS" 13 "C3_J6A核" 14 "C3_MCU" 15 "C3_SE1000AP" 16 "C3_SE1000CP" 17 "C3_M22" ;
VAL_ 1546 VIUFR_EthMng_DataTyp 0 "预留" 1 "link状态" 2 "SQI" 3 "DataFlow流量统计" 4 "DropFrame丢包统计" 5 "FDB表" 6 "VLAN" 7 "PHY主从" 8 "MAC地址" 9 "IP配置" 10 "全域连通性检测" 11 "PING" ;
VAL_ 1547 C2_EthMng_MngTyp 0 "预留" 1 "PC/工程模式" 2 "云端" ;
VAL_ 1547 C2_EthMng_Msg 0 "预留" 1 "request（请求）" 2 "response（请求响应）" 3 "notification（通告）——用于通告ERPS Owner节点ERPS错误" 4 "error(错误)" ;
VAL_ 1547 C2_EthMng_OptnCod 0 "预留" 1 "add-添加" 2 "del-删除" 3 "mod-修改" 4 "get-获取" ;
VAL_ 1547 C2_EthMng_Optn 0 "预留" 1 "VIU_FL" 2 "VIU_FR" 3 "C2_MCU" 4 "C2_SOC" 5 "EDC_QNX" 6 "EDC_Android" 7 "EDC_MCU" 8 "EDC_TBOX" 9 "Madc" 10 "LIDAR1" 11 "LIDAR2" 12 "INS" 13 "C3_J6A核" 14 "C3_MCU" 15 "C3_SE1000AP" 16 "C3_SE1000CP" 17 "C3_M22" ;
VAL_ 1547 C2_EthMng_DataTyp 0 "预留" 1 "link状态" 2 "SQI" 3 "DataFlow流量统计" 4 "DropFrame丢包统计" 5 "FDB表" 6 "VLAN" 7 "PHY主从" 8 "MAC地址" 9 "IP配置" 10 "全域连通性检测" 11 "PING" ;
VAL_ 1548 EDC_ErpsRev_Pst 0 "norplportblock" 1 "owner port block" 2 " neighbour port block " 3 "owner and neighbour port block" ;
VAL_ 1551 VIUFR_ErpsRev_Pst 0 "norplportblock" 1 "owner port block" 2 " neighbour port block " 3 "owner and neighbour port block" ;
VAL_ 1579 C2_EthMng_MngTyp 0 "预留" 1 "PC/工程模式" 2 "云端" ;
VAL_ 1579 C2_EthMng_Msg 0 "预留" 1 "request（请求）" 2 "response（请求响应）" 3 "notification（通告）——用于通告ERPS Owner节点ERPS错误" 4 "error(错误)" ;
VAL_ 1579 C2_EthMng_OptnCod 0 "预留" 1 "add-添加" 2 "del-删除" 3 "mod-修改" 4 "get-获取" ;
VAL_ 1579 C2_EthMng_Optn 0 "预留" 1 "VIU_FL" 2 "VIU_FR" 3 "C2_MCU" 4 "C2_SOC" 5 "EDC_QNX" 6 "EDC_Android" 7 "EDC_MCU" 8 "EDC_TBOX" 9 "Madc" 10 "LIDAR1" 11 "LIDAR2" 12 "INS" 13 "C3_J6A核" 14 "C3_MCU" 15 "C3_SE1000AP" 16 "C3_SE1000CP" 17 "C3_M22" 18 " 冗余J6" ;
VAL_ 1579 C2_EthMng_DataTyp 0 "预留" 1 "link状态" 2 "SQI" 3 "DataFlow流量统计" 4 "DropFrame丢包统计" 5 "FDB表" 6 "VLAN" 7 "PHY主从" 8 "MAC地址" 9 "IP配置" 10 "全域连通性检测" 11 "PING" ;
VAL_ 1763 EDCEqCertifReqFrmType 161 "认证请求" 163 "挑战应答" ;
VAL_ 1767 VIUEqCertifRespFrmType 162 "挑战请求" 164 "认证应答" ;
VAL_ 1767 VIUEqCertifRespRes 0 "成功" 1 "失败" ;
VAL_ 1790 ErpsBootMode 0 "不处于OTA或Boot" 1 "处于OTA或Boot" ;
